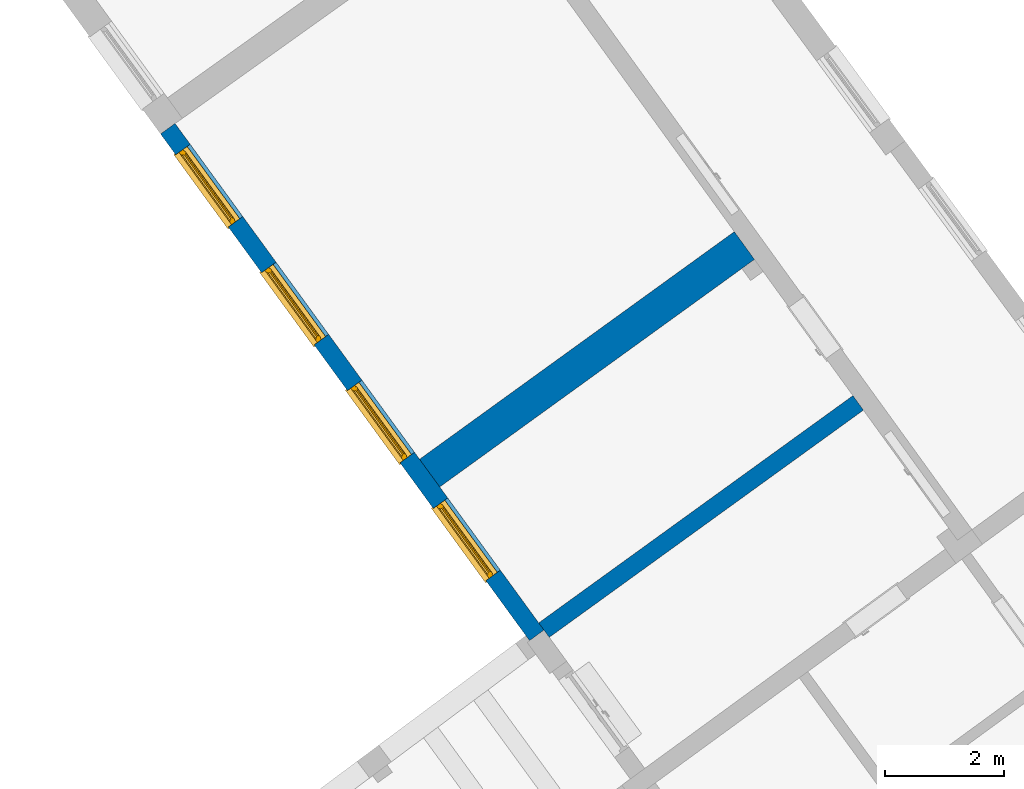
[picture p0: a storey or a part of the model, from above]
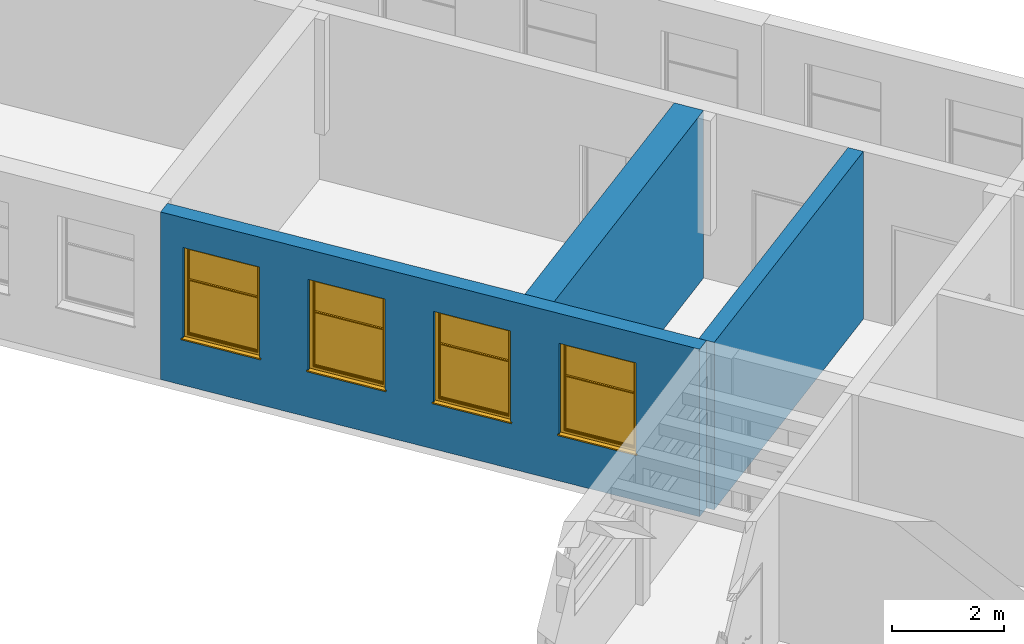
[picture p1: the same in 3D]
Properties of the parts of a building model (IFC2X3), part 1 of 13

# File
Description: ViewDefinition [CoordinationView_V2.0], RevitIdentifiers [VersionGUID: 7a34f898-4692-4373-837c-c47529479d31, NumberOfSaves: 8], CoordinateReference [CoordinateBase: Shared Coordinates]
File name: Project Number
Time: 2026-03-11T15:52:37+02:00
Written by: ODA SDAI 22.12
Made in: 23.1.10.4 - Exporter 23.2.2.0 - Alternate UI 23.2.2.0

# IfcProject, Project Number
LongName: Project Name; Phase: Project Status

# IfcSite, Default
RefLatitude: 42, 54, 1, 679999; RefLongitude: 25, 17, 46, 199999; RefElevation: 0 mm
Pset_ProductRequirements - Category: Project Information

# IfcBuilding
Pset_BuildingCommon - NumberOfStoreys: 11
Pset_ProductRequirements - Category: Project Information

# IfcBuildingStorey: Level:1/4" Head (3)
Elevation: 0 mm
Pset_ProductRequirements - Category: Levels
Name | LongName = Pset_AirSideSystemInformation, Name = Pset_ProductRequirements, Name
PLAN | PLAN
3D | 3D
-1. Story | -1. Story

# IfcBuildingStorey: Level:Circle Head - Project Datum (11)
Pset_ProductRequirements - Category: Levels
Name | LongName = Pset_AirSideSystemInformation, Name = Pset_ProductRequirements, Name | Elevation (mm)
0.UG -3.60 | 0.UG -3.60 | -3600
6.EG KH -1.15 | 6.EG KH -1.15 | -1150
1.EG +0.00 | 1.EG +0.00 | -4.33147e-12
7.1OG KH +2.65 | 7.1OG KH +2.65 | 2650
2.1OG +5.30 | 2.1OG +5.30 | 5300
8.2OG KH +6.45 | 8.2OG KH +6.45 | 6450
9.3OG KH +10.25 | 9.3OG KH +10.25 | 10250
3.2OG +10.60 | 3.2OG +10.60 | 10600
10.DG KH +14.25 | 10.DG KH +14.25 | 14250
4.3OG +15.90 | 4.3OG +15.90 | 15900
5.DG +21.50 | 5.DG +21.50 | 21500

# IfcBeam: Beam-124 291688:Beam-124 291688 (64)
In: PLAN
Type - Pset_BeamCommon - IsExternal: no; LoadBearing: yes
Type - Pset_ProductRequirements - Category: Structural Framing
Material: Paint-02.3; Group: Model Group:River:478153
Pset_BeamCommon - Reference: Beam-124 291688
Pset_QuantityTakeOff - Reference: Beam-124 291688; sets with these values: 2

# IfcBeam: Beam-124 342651:Beam-124 342651 (144)
In: PLAN
Type - Pset_BeamCommon - IsExternal: no; LoadBearing: yes
Type - Pset_ProductRequirements - Category: Structural Framing
Material: Wd Siding Dark color 01; Group: Model Group:River:478153
Pset_BeamCommon - Reference: Beam-124 342651
Pset_QuantityTakeOff - Reference: Beam-124 342651; sets with these values: 2

# IfcBeam: Beam-124 342768:Beam-124 342768 (10)
In: PLAN
Type - Pset_BeamCommon - IsExternal: no; LoadBearing: yes
Type - Pset_ProductRequirements - Category: Structural Framing
Material: Paint-02.1; Group: Model Group:River:478153
Pset_BeamCommon - Reference: Beam-124 342768
Pset_QuantityTakeOff - Reference: Beam-124 342768; sets with these values: 2

# IfcBeam: Beam-124 342968:Beam-124 342968 (4)
In: PLAN
Type - Pset_BeamCommon - IsExternal: no; LoadBearing: yes
Type - Pset_ProductRequirements - Category: Structural Framing
Material: Paint-02.3; Group: Model Group:River:478153
Pset_BeamCommon - Reference: Beam-124 342968
Pset_QuantityTakeOff - Reference: Beam-124 342968; sets with these values: 2

# IfcBeam: Beam-125 342678:Beam-125 342678 (6)
In: PLAN
Type - Pset_BeamCommon - IsExternal: no; LoadBearing: yes
Type - Pset_ProductRequirements - Category: Structural Framing
Material: Paint-02.2; Group: Model Group:River:478153
Pset_BeamCommon - Reference: Beam-125 342678
Pset_QuantityTakeOff - Reference: Beam-125 342678; sets with these values: 2

# IfcBeam: Beam-125 342737:Beam-125 342737 (6)
In: PLAN
Type - Pset_BeamCommon - IsExternal: no; LoadBearing: yes
Type - Pset_ProductRequirements - Category: Structural Framing
Material: Paint-02.2; Group: Model Group:River:478153
Pset_BeamCommon - Reference: Beam-125 342737
Pset_QuantityTakeOff - Reference: Beam-125 342737; sets with these values: 2

# IfcBeam: Beam-125 342828:Beam-125 342828 (2)
In: PLAN
Type - Pset_BeamCommon - IsExternal: no; LoadBearing: yes
Type - Pset_ProductRequirements - Category: Structural Framing
Material: Paint-02.2; Group: Model Group:River:478153
Pset_BeamCommon - Reference: Beam-125 342828
Pset_QuantityTakeOff - Reference: Beam-125 342828; sets with these values: 2

# IfcBeam: Beam-125 373068:Beam-125 373068 (2)
In: PLAN
Type - Pset_BeamCommon - IsExternal: no; LoadBearing: yes
Type - Pset_ProductRequirements - Category: Structural Framing
Material: Paint-02.2; Group: Model Group:River:478153
Pset_BeamCommon - Reference: Beam-125 373068
Pset_QuantityTakeOff - Reference: Beam-125 373068; sets with these values: 2

# IfcBeam: Beam-136 (4)
In: 6.EG KH -1.15
Type - Pset_BeamCommon - IsExternal: no; LoadBearing: yes
Type - Pset_ProductRequirements - Category: Structural Framing
Material: Paveta_bordur; Group: Model Group:River:478153
Pset_QuantityTakeOff - sets with these values: 2
Name | Pset_BeamCommon, Reference = Pset_QuantityTakeOff, Reference
Beam-136:Beam-136:298538 | Beam-136
Beam-136 237953:Beam-136 237953:298580 | Beam-136 237953
Beam-136 237969:Beam-136 237969:298587 | Beam-136 237969
Beam-136 266104:Beam-136 266104:299016 | Beam-136 266104

# IfcBeam: Beam-136 236833:Beam-136 236833, Beam-136
In: 1.EG +0.00
Type - Pset_BeamCommon - IsExternal: no; LoadBearing: yes
Type - Pset_ProductRequirements - Category: Structural Framing
Material: Paveta_bordur; Group: Model Group:River:478153
Pset_BeamCommon - Reference: Beam-136 236833
Pset_QuantityTakeOff - Reference: Beam-136 236833; sets with these values: 2

# IfcBeam: Beam-136 236875:Beam-136 236875, Beam-136
In: 1.EG +0.00
Type - Pset_BeamCommon - IsExternal: no; LoadBearing: yes
Type - Pset_ProductRequirements - Category: Structural Framing
Material: Paveta_bordur; Group: Model Group:River:478153
Pset_BeamCommon - Reference: Beam-136 236875
Pset_QuantityTakeOff - Reference: Beam-136 236875; sets with these values: 2

# IfcBeam: Beam-136 237941:Beam-136 237941, Beam-136
In: 6.EG KH -1.15
Type - Pset_BeamCommon - IsExternal: no; LoadBearing: yes
Type - Pset_ProductRequirements - Category: Structural Framing
Material: Paveta_bordur; Group: Model Group:River:478153
Pset_BeamCommon - Reference: Beam-136 237941
Pset_QuantityTakeOff - Reference: Beam-136 237941; sets with these values: 2

# IfcBeam: Beam-136 237952:Beam-136 237952, Beam-136
In: 6.EG KH -1.15
Type - Pset_BeamCommon - IsExternal: no; LoadBearing: yes
Type - Pset_ProductRequirements - Category: Structural Framing
Material: Paveta_bordur; Group: Model Group:River:478153
Pset_BeamCommon - Reference: Beam-136 237952
Pset_QuantityTakeOff - Reference: Beam-136 237952; sets with these values: 2

# IfcBeam: Beam-136 237970:Beam-136 237970, Beam-136
In: 6.EG KH -1.15
Type - Pset_BeamCommon - IsExternal: no; LoadBearing: yes
Type - Pset_ProductRequirements - Category: Structural Framing
Material: Paveta_bordur; Group: Model Group:River:478153
Pset_BeamCommon - Reference: Beam-136 237970
Pset_QuantityTakeOff - Reference: Beam-136 237970; sets with these values: 2

# IfcBeam: Beam-137 (3)
Type - Pset_BeamCommon - IsExternal: no; LoadBearing: yes
Type - Pset_ProductRequirements - Category: Structural Framing
Material: Paveta_bordur; Group: Model Group:River:478153
Pset_QuantityTakeOff - sets with these values: 2
Name | In | Pset_BeamCommon, Reference = Pset_QuantityTakeOff, Reference
Beam-137:Beam-137:298349 | 1.EG +0.00 | Beam-137
Beam-137 237484:Beam-137 237484:298510 | 6.EG KH -1.15 | Beam-137 237484
Beam-137 237932:Beam-137 237932:298573 | 6.EG KH -1.15 | Beam-137 237932

# IfcBeam: Beam-137 236767:Beam-137 236767, Beam-137
In: 1.EG +0.00
Type - Pset_BeamCommon - IsExternal: no; LoadBearing: yes
Type - Pset_ProductRequirements - Category: Structural Framing
Material: Paveta_bordur; Group: Model Group:River:478153
Pset_BeamCommon - Reference: Beam-137 236767
Pset_QuantityTakeOff - Reference: Beam-137 236767; sets with these values: 2

# IfcBeam: Beam-137 236820:Beam-137 236820 (6)
In: 3D
Type - Pset_BeamCommon - IsExternal: no; LoadBearing: yes
Type - Pset_ProductRequirements - Category: Structural Framing
Material: Paveta_bordur; Group: Model Group:River:478153
Pset_BeamCommon - Reference: Beam-137 236820
Pset_QuantityTakeOff - Reference: Beam-137 236820; sets with these values: 2
Name
Beam-148
2 x Beam-161
Beam-181
Beam-140
Beam-137

# IfcBeam: Beam-137 236851:Beam-137 236851, Beam-137
In: 1.EG +0.00
Type - Pset_BeamCommon - IsExternal: no; LoadBearing: yes
Type - Pset_ProductRequirements - Category: Structural Framing
Material: Paveta_bordur; Group: Model Group:River:478153
Pset_BeamCommon - Reference: Beam-137 236851
Pset_QuantityTakeOff - Reference: Beam-137 236851; sets with these values: 2

# IfcBeam: Beam-137 237951:Beam-137 237951, Beam-137
In: 6.EG KH -1.15
Type - Pset_BeamCommon - IsExternal: no; LoadBearing: yes
Type - Pset_ProductRequirements - Category: Structural Framing
Material: Paveta_bordur; Group: Model Group:River:478153
Pset_BeamCommon - Reference: Beam-137 237951
Pset_QuantityTakeOff - Reference: Beam-137 237951; sets with these values: 2

# IfcBeam: Beam-137 238188:Beam-137 238188, Beam-137
In: 6.EG KH -1.15
Type - Pset_BeamCommon - IsExternal: no; LoadBearing: yes
Type - Pset_ProductRequirements - Category: Structural Framing
Material: Paveta_bordur; Group: Model Group:River:478153
Pset_BeamCommon - Reference: Beam-137 238188
Pset_QuantityTakeOff - Reference: Beam-137 238188; sets with these values: 2

# IfcBeam: Beam-137 291495:Beam-137 291495, Beam-137
In: 1.EG +0.00
Type - Pset_BeamCommon - IsExternal: no; LoadBearing: yes
Type - Pset_ProductRequirements - Category: Structural Framing
Material: Paveta_bordur; Group: Model Group:River:478153
Pset_BeamCommon - Reference: Beam-137 291495
Pset_QuantityTakeOff - Reference: Beam-137 291495; sets with these values: 2

# IfcBeam: Beam-138, Beam-138:Beam-138:298650
In: 6.EG KH -1.15
Type - Pset_BeamCommon - IsExternal: no; LoadBearing: yes
Type - Pset_ProductRequirements - Category: Structural Framing
Material: Paveta_bordur; Group: Model Group:River:478153
Pset_BeamCommon - Reference: Beam-138
Pset_QuantityTakeOff - Reference: Beam-138; sets with these values: 2

# IfcBeam: Beam-138 236757:Beam-138 236757, Beam-138
In: 1.EG +0.00
Type - Pset_BeamCommon - IsExternal: no; LoadBearing: yes
Type - Pset_ProductRequirements - Category: Structural Framing
Material: Paveta_bordur; Group: Model Group:River:478153
Pset_BeamCommon - Reference: Beam-138 236757
Pset_QuantityTakeOff - Reference: Beam-138 236757; sets with these values: 2

# IfcBeam: Beam-138 236822:Beam-138 236822, Beam-138
In: 1.EG +0.00
Type - Pset_BeamCommon - IsExternal: no; LoadBearing: yes
Type - Pset_ProductRequirements - Category: Structural Framing
Material: Paveta_bordur; Group: Model Group:River:478153
Pset_BeamCommon - Reference: Beam-138 236822
Pset_QuantityTakeOff - Reference: Beam-138 236822; sets with these values: 2

# IfcBeam: Beam-138 237779:Beam-138 237779, Beam-138
In: 6.EG KH -1.15
Type - Pset_BeamCommon - IsExternal: no; LoadBearing: yes
Type - Pset_ProductRequirements - Category: Structural Framing
Material: Paveta_bordur; Group: Model Group:River:478153
Pset_BeamCommon - Reference: Beam-138 237779
Pset_QuantityTakeOff - Reference: Beam-138 237779; sets with these values: 2

# IfcBeam: Beam-139 (3)
Type - Pset_BeamCommon - IsExternal: no; LoadBearing: yes
Type - Pset_ProductRequirements - Category: Structural Framing
Material: Paveta_bordur; Group: Model Group:River:478153
Pset_QuantityTakeOff - sets with these values: 2
Name | In | Pset_BeamCommon, Reference = Pset_QuantityTakeOff, Reference
Beam-139:Beam-139:298356 | 1.EG +0.00 | Beam-139
Beam-139 237451:Beam-139 237451:298503 | 0.UG -3.60 | Beam-139 237451
Beam-139 237500:Beam-139 237500:298524 | 6.EG KH -1.15 | Beam-139 237500

# IfcBeam: Beam-139 228031:Beam-139 228031, Beam-139
In: 0.UG -3.60
Type - Pset_BeamCommon - IsExternal: no; LoadBearing: yes
Type - Pset_ProductRequirements - Category: Structural Framing
Material: Paveta_bordur; Group: Model Group:River:478153
Pset_BeamCommon - Reference: Beam-139 228031
Pset_QuantityTakeOff - Reference: Beam-139 228031; sets with these values: 2

# IfcBeam: Beam-139 236846:Beam-139 236846, Beam-139
In: 1.EG +0.00
Type - Pset_BeamCommon - IsExternal: no; LoadBearing: yes
Type - Pset_ProductRequirements - Category: Structural Framing
Material: Paveta_bordur; Group: Model Group:River:478153
Pset_BeamCommon - Reference: Beam-139 236846
Pset_QuantityTakeOff - Reference: Beam-139 236846; sets with these values: 2

# IfcBeam: Beam-139 236876:Beam-139 236876, Beam-139
In: 0.UG -3.60
Type - Pset_BeamCommon - IsExternal: no; LoadBearing: yes
Type - Pset_ProductRequirements - Category: Structural Framing
Material: Paint-01; Group: Model Group:River:478153
Pset_BeamCommon - Reference: Beam-139 236876
Pset_QuantityTakeOff - Reference: Beam-139 236876; sets with these values: 2

# IfcBeam: Beam-139 236877:Beam-139 236877, Beam-139
In: 0.UG -3.60
Type - Pset_BeamCommon - IsExternal: no; LoadBearing: yes
Type - Pset_ProductRequirements - Category: Structural Framing
Material: Paint-01; Group: Model Group:River:478153
Pset_BeamCommon - Reference: Beam-139 236877
Pset_QuantityTakeOff - Reference: Beam-139 236877; sets with these values: 2

# IfcBeam: Beam-139 237440:Beam-139 237440, Beam-139
In: 0.UG -3.60
Type - Pset_BeamCommon - IsExternal: no; LoadBearing: yes
Type - Pset_ProductRequirements - Category: Structural Framing
Material: Paint-01; Group: Model Group:River:478153
Pset_BeamCommon - Reference: Beam-139 237440
Pset_QuantityTakeOff - Reference: Beam-139 237440; sets with these values: 2

# IfcBeam: Beam-139 237447:Beam-139 237447, Beam-139
In: 0.UG -3.60
Type - Pset_BeamCommon - IsExternal: no; LoadBearing: yes
Type - Pset_ProductRequirements - Category: Structural Framing
Material: Paint-01; Group: Model Group:River:478153
Pset_BeamCommon - Reference: Beam-139 237447
Pset_QuantityTakeOff - Reference: Beam-139 237447; sets with these values: 2

# IfcBeam: Beam-139 237458:Beam-139 237458, Beam-139
In: 0.UG -3.60
Type - Pset_BeamCommon - IsExternal: no; LoadBearing: yes
Type - Pset_ProductRequirements - Category: Structural Framing
Material: Paint-01; Group: Model Group:River:478153
Pset_BeamCommon - Reference: Beam-139 237458
Pset_QuantityTakeOff - Reference: Beam-139 237458; sets with these values: 2

# IfcBeam: Beam-139 237459:Beam-139 237459, Beam-139
In: 6.EG KH -1.15
Type - Pset_BeamCommon - IsExternal: no; LoadBearing: yes
Type - Pset_ProductRequirements - Category: Structural Framing
Material: Paveta_bordur; Group: Model Group:River:478153
Pset_BeamCommon - Reference: Beam-139 237459
Pset_QuantityTakeOff - Reference: Beam-139 237459; sets with these values: 2

# IfcBeam: Beam-139 237462:Beam-139 237462, Beam-139
In: 0.UG -3.60
Type - Pset_BeamCommon - IsExternal: no; LoadBearing: yes
Type - Pset_ProductRequirements - Category: Structural Framing
Material: Paveta_bordur; Group: Model Group:River:478153
Pset_BeamCommon - Reference: Beam-139 237462
Pset_QuantityTakeOff - Reference: Beam-139 237462; sets with these values: 2

# IfcBeam: Beam-139 237467:Beam-139 237467, Beam-139
In: 0.UG -3.60
Type - Pset_BeamCommon - IsExternal: no; LoadBearing: yes
Type - Pset_ProductRequirements - Category: Structural Framing
Material: Paveta_bordur; Group: Model Group:River:478153
Pset_BeamCommon - Reference: Beam-139 237467
Pset_QuantityTakeOff - Reference: Beam-139 237467; sets with these values: 2

# IfcBeam: Beam-139 237471:Beam-139 237471, Beam-139
In: 0.UG -3.60
Type - Pset_BeamCommon - IsExternal: no; LoadBearing: yes
Type - Pset_ProductRequirements - Category: Structural Framing
Material: Paint-01; Group: Model Group:River:478153
Pset_BeamCommon - Reference: Beam-139 237471
Pset_QuantityTakeOff - Reference: Beam-139 237471; sets with these values: 2

# IfcBeam: Beam-139 237474:Beam-139 237474, Beam-139
In: 0.UG -3.60
Type - Pset_BeamCommon - IsExternal: no; LoadBearing: yes
Type - Pset_ProductRequirements - Category: Structural Framing
Material: Paint-01; Group: Model Group:River:478153
Pset_BeamCommon - Reference: Beam-139 237474
Pset_QuantityTakeOff - Reference: Beam-139 237474; sets with these values: 2

# IfcBeam: Beam-139 237483:Beam-139 237483, Beam-139
In: 6.EG KH -1.15
Type - Pset_BeamCommon - IsExternal: no; LoadBearing: yes
Type - Pset_ProductRequirements - Category: Structural Framing
Material: Paveta_bordur; Group: Model Group:River:478153
Pset_BeamCommon - Reference: Beam-139 237483
Pset_QuantityTakeOff - Reference: Beam-139 237483; sets with these values: 2

# IfcBeam: Beam-139 237501:Beam-139 237501, Beam-139
In: 0.UG -3.60
Type - Pset_BeamCommon - IsExternal: no; LoadBearing: yes
Type - Pset_ProductRequirements - Category: Structural Framing
Material: Paint-01; Group: Model Group:River:478153
Pset_BeamCommon - Reference: Beam-139 237501
Pset_QuantityTakeOff - Reference: Beam-139 237501; sets with these values: 2

# IfcBeam: Beam-139 237552:Beam-139 237552, Beam-139
In: 6.EG KH -1.15
Type - Pset_BeamCommon - IsExternal: no; LoadBearing: yes
Type - Pset_ProductRequirements - Category: Structural Framing
Material: Paveta_bordur; Group: Model Group:River:478153
Pset_BeamCommon - Reference: Beam-139 237552
Pset_QuantityTakeOff - Reference: Beam-139 237552; sets with these values: 2

# IfcBeam: Beam-139 237771:Beam-139 237771, Beam-139
In: 6.EG KH -1.15
Type - Pset_BeamCommon - IsExternal: no; LoadBearing: yes
Type - Pset_ProductRequirements - Category: Structural Framing
Material: Paveta_bordur; Group: Model Group:River:478153
Pset_BeamCommon - Reference: Beam-139 237771
Pset_QuantityTakeOff - Reference: Beam-139 237771; sets with these values: 2

# IfcBeam: Beam-139 237922:Beam-139 237922, Beam-139
In: 6.EG KH -1.15
Type - Pset_BeamCommon - IsExternal: no; LoadBearing: yes
Type - Pset_ProductRequirements - Category: Structural Framing
Material: Paveta_bordur; Group: Model Group:River:478153
Pset_BeamCommon - Reference: Beam-139 237922
Pset_QuantityTakeOff - Reference: Beam-139 237922; sets with these values: 2

# IfcBeam: Beam-139 238160:Beam-139 238160, Beam-139
In: 6.EG KH -1.15
Type - Pset_BeamCommon - IsExternal: no; LoadBearing: yes
Type - Pset_ProductRequirements - Category: Structural Framing
Material: Paveta_bordur; Group: Model Group:River:478153
Pset_BeamCommon - Reference: Beam-139 238160
Pset_QuantityTakeOff - Reference: Beam-139 238160; sets with these values: 2

# IfcBeam: Beam-139 238194:Beam-139 238194, Beam-139
In: 6.EG KH -1.15
Type - Pset_BeamCommon - IsExternal: no; LoadBearing: yes
Type - Pset_ProductRequirements - Category: Structural Framing
Material: Paveta_bordur; Group: Model Group:River:478153
Pset_BeamCommon - Reference: Beam-139 238194
Pset_QuantityTakeOff - Reference: Beam-139 238194; sets with these values: 2

# IfcBeam: Beam-139 238196:Beam-139 238196, Beam-139
In: 6.EG KH -1.15
Type - Pset_BeamCommon - IsExternal: no; LoadBearing: yes
Type - Pset_ProductRequirements - Category: Structural Framing
Material: Paveta_bordur; Group: Model Group:River:478153
Pset_BeamCommon - Reference: Beam-139 238196
Pset_QuantityTakeOff - Reference: Beam-139 238196; sets with these values: 2

# IfcBeam: Beam-139 262464:Beam-139 262464, Beam-139
In: 0.UG -3.60
Type - Pset_BeamCommon - IsExternal: no; LoadBearing: yes
Type - Pset_ProductRequirements - Category: Structural Framing
Material: Paint-01; Group: Model Group:River:478153
Pset_BeamCommon - Reference: Beam-139 262464
Pset_QuantityTakeOff - Reference: Beam-139 262464; sets with these values: 2

# IfcBeam: Beam-139 262485:Beam-139 262485, Beam-139
In: 0.UG -3.60
Type - Pset_BeamCommon - IsExternal: no; LoadBearing: yes
Type - Pset_ProductRequirements - Category: Structural Framing
Material: Paint-01; Group: Model Group:River:478153
Pset_BeamCommon - Reference: Beam-139 262485
Pset_QuantityTakeOff - Reference: Beam-139 262485; sets with these values: 2

# IfcBeam: Beam-139 83593:Beam-139 83593, Beam-139
In: 0.UG -3.60
Type - Pset_BeamCommon - IsExternal: no; LoadBearing: yes
Type - Pset_ProductRequirements - Category: Structural Framing
Material: Paveta_bordur; Group: Model Group:River:478153
Pset_BeamCommon - Reference: Beam-139 83593
Pset_QuantityTakeOff - Reference: Beam-139 83593; sets with these values: 2

# IfcBeam: Beam-140 (6)
Type - Pset_BeamCommon - IsExternal: no; LoadBearing: yes
Type - Pset_ProductRequirements - Category: Structural Framing
Material: Paveta_bordur; Group: Model Group:River:478153
Pset_QuantityTakeOff - sets with these values: 2
Name | In | Pset_BeamCommon, Reference = Pset_QuantityTakeOff, Reference
Beam-140:Beam-140:298377 | 1.EG +0.00 | Beam-140
Beam-140 237048:Beam-140 237048:298447 | 0.UG -3.60 | Beam-140 237048
Beam-140 237450:Beam-140 237450:298496 | 0.UG -3.60 | Beam-140 237450
Beam-140 237496:Beam-140 237496:298517 | 6.EG KH -1.15 | Beam-140 237496
Beam-140 237508:Beam-140 237508:298531 | 6.EG KH -1.15 | Beam-140 237508
Beam-140 238172:Beam-140 238172:298643 | 6.EG KH -1.15 | Beam-140 238172

# IfcBeam: Beam-140 182489:Beam-140 182489, Beam-140
In: 0.UG -3.60
Type - Pset_BeamCommon - IsExternal: no; LoadBearing: yes
Type - Pset_ProductRequirements - Category: Structural Framing
Material: Paint-01; Group: Model Group:River:478153
Pset_BeamCommon - Reference: Beam-140 182489
Pset_QuantityTakeOff - Reference: Beam-140 182489; sets with these values: 2

# IfcBeam: Beam-140 236747:Beam-140 236747 (6)
In: 3D
Type - Pset_BeamCommon - IsExternal: no; LoadBearing: yes
Type - Pset_ProductRequirements - Category: Structural Framing
Material: Paveta_bordur; Group: Model Group:River:478153
Pset_BeamCommon - Reference: Beam-140 236747
Pset_QuantityTakeOff - Reference: Beam-140 236747; sets with these values: 2
Name
Beam-146
Beam-176
Beam-164
Beam-163
Beam-143
Beam-140

# IfcBeam: Beam-140 237435:Beam-140 237435, Beam-140
In: 0.UG -3.60
Type - Pset_BeamCommon - IsExternal: no; LoadBearing: yes
Type - Pset_ProductRequirements - Category: Structural Framing
Material: Paveta_bordur; Group: Model Group:River:478153
Pset_BeamCommon - Reference: Beam-140 237435
Pset_QuantityTakeOff - Reference: Beam-140 237435; sets with these values: 2

# IfcBeam: Beam-140 237494:Beam-140 237494, Beam-140
In: 6.EG KH -1.15
Type - Pset_BeamCommon - IsExternal: no; LoadBearing: yes
Type - Pset_ProductRequirements - Category: Structural Framing
Material: Paveta_bordur; Group: Model Group:River:478153
Pset_BeamCommon - Reference: Beam-140 237494
Pset_QuantityTakeOff - Reference: Beam-140 237494; sets with these values: 2

# IfcBeam: Beam-140 237927:Beam-140 237927, Beam-140
In: 6.EG KH -1.15
Type - Pset_BeamCommon - IsExternal: no; LoadBearing: yes
Type - Pset_ProductRequirements - Category: Structural Framing
Material: Paveta_bordur; Group: Model Group:River:478153
Pset_BeamCommon - Reference: Beam-140 237927
Pset_QuantityTakeOff - Reference: Beam-140 237927; sets with these values: 2

# IfcBeam: Beam-141 (6)
Type - Pset_BeamCommon - IsExternal: no; LoadBearing: yes
Type - Pset_ProductRequirements - Category: Structural Framing
Material: Paveta_bordur; Group: Model Group:River:478153
Pset_QuantityTakeOff - sets with these values: 2
Name | In | Pset_BeamCommon, Reference = Pset_QuantityTakeOff, Reference
Beam-141:Beam-141:298363 | 1.EG +0.00 | Beam-141
Beam-141 236813:Beam-141 236813:298384 | 1.EG +0.00 | Beam-141 236813
Beam-141 237873:Beam-141 237873:298566 | 6.EG KH -1.15 | Beam-141 237873
Beam-141 238103:Beam-141 238103:298616 | 6.EG KH -1.15 | Beam-141 238103
Beam-141 238166:Beam-141 238166:298636 | 6.EG KH -1.15 | Beam-141 238166
Beam-141 256654:Beam-141 256654:298841 | 6.EG KH -1.15 | Beam-141 256654

# IfcBeam: Beam-141 211486:Beam-141 211486, Beam-141
In: 0.UG -3.60
Type - Pset_BeamCommon - IsExternal: no; LoadBearing: yes
Type - Pset_ProductRequirements - Category: Structural Framing
Material: Paint-01; Group: Model Group:River:478153
Pset_BeamCommon - Reference: Beam-141 211486
Pset_QuantityTakeOff - Reference: Beam-141 211486; sets with these values: 2

# IfcBeam: Beam-141 237854:Beam-141 237854, Beam-141
In: 6.EG KH -1.15
Type - Pset_BeamCommon - IsExternal: no; LoadBearing: yes
Type - Pset_ProductRequirements - Category: Structural Framing
Material: Paveta_bordur; Group: Model Group:River:478153
Pset_BeamCommon - Reference: Beam-141 237854
Pset_QuantityTakeOff - Reference: Beam-141 237854; sets with these values: 2

# IfcBeam: Beam-141 237901:Beam-141 237901, Beam-141
In: 6.EG KH -1.15
Type - Pset_BeamCommon - IsExternal: no; LoadBearing: yes
Type - Pset_ProductRequirements - Category: Structural Framing
Material: Paveta_bordur; Group: Model Group:River:478153
Pset_BeamCommon - Reference: Beam-141 237901
Pset_QuantityTakeOff - Reference: Beam-141 237901; sets with these values: 2

# IfcBeam: Beam-141 237912:Beam-141 237912, Beam-141
In: 6.EG KH -1.15
Type - Pset_BeamCommon - IsExternal: no; LoadBearing: yes
Type - Pset_ProductRequirements - Category: Structural Framing
Material: Paveta_bordur; Group: Model Group:River:478153
Pset_BeamCommon - Reference: Beam-141 237912
Pset_QuantityTakeOff - Reference: Beam-141 237912; sets with these values: 2

# IfcBeam: Beam-141 237933:Beam-141 237933, Beam-141
In: 6.EG KH -1.15
Type - Pset_BeamCommon - IsExternal: no; LoadBearing: yes
Type - Pset_ProductRequirements - Category: Structural Framing
Material: Paveta_bordur; Group: Model Group:River:478153
Pset_BeamCommon - Reference: Beam-141 237933
Pset_QuantityTakeOff - Reference: Beam-141 237933; sets with these values: 2

# IfcBeam: Beam-141 238098:Beam-141 238098, Beam-141
In: 6.EG KH -1.15
Type - Pset_BeamCommon - IsExternal: no; LoadBearing: yes
Type - Pset_ProductRequirements - Category: Structural Framing
Material: Paint-01; Group: Model Group:River:478153
Pset_BeamCommon - Reference: Beam-141 238098
Pset_QuantityTakeOff - Reference: Beam-141 238098; sets with these values: 2

# IfcBeam: Beam-141 238106:Beam-141 238106, Beam-141
In: 6.EG KH -1.15
Type - Pset_BeamCommon - IsExternal: no; LoadBearing: yes
Type - Pset_ProductRequirements - Category: Structural Framing
Material: Paint-01; Group: Model Group:River:478153
Pset_BeamCommon - Reference: Beam-141 238106
Pset_QuantityTakeOff - Reference: Beam-141 238106; sets with these values: 2

# IfcBeam: Beam-141 266031:Beam-141 266031, Beam-141
In: 6.EG KH -1.15
Type - Pset_BeamCommon - IsExternal: no; LoadBearing: yes
Type - Pset_ProductRequirements - Category: Structural Framing
Material: Paint-01; Group: Model Group:River:478153
Pset_BeamCommon - Reference: Beam-141 266031
Pset_QuantityTakeOff - Reference: Beam-141 266031; sets with these values: 2

# IfcBeam: Beam-141 266038:Beam-141 266038, Beam-141
In: 6.EG KH -1.15
Type - Pset_BeamCommon - IsExternal: no; LoadBearing: yes
Type - Pset_ProductRequirements - Category: Structural Framing
Material: Paint-01; Group: Model Group:River:478153
Pset_BeamCommon - Reference: Beam-141 266038
Pset_QuantityTakeOff - Reference: Beam-141 266038; sets with these values: 2

# IfcBeam: Beam-141 266069:Beam-141 266069, Beam-141
In: 0.UG -3.60
Type - Pset_BeamCommon - IsExternal: no; LoadBearing: yes
Type - Pset_ProductRequirements - Category: Structural Framing
Material: Paint-01; Group: Model Group:River:478153
Pset_BeamCommon - Reference: Beam-141 266069
Pset_QuantityTakeOff - Reference: Beam-141 266069; sets with these values: 2

# IfcBeam: Beam-141 266079:Beam-141 266079, Beam-141
In: 6.EG KH -1.15
Type - Pset_BeamCommon - IsExternal: no; LoadBearing: yes
Type - Pset_ProductRequirements - Category: Structural Framing
Material: Paveta_bordur; Group: Model Group:River:478153
Pset_BeamCommon - Reference: Beam-141 266079
Pset_QuantityTakeOff - Reference: Beam-141 266079; sets with these values: 2

# IfcBeam: Beam-141 266112:Beam-141 266112, Beam-141
In: 6.EG KH -1.15
Type - Pset_BeamCommon - IsExternal: no; LoadBearing: yes
Type - Pset_ProductRequirements - Category: Structural Framing
Material: Paint-01; Group: Model Group:River:478153
Pset_BeamCommon - Reference: Beam-141 266112
Pset_QuantityTakeOff - Reference: Beam-141 266112; sets with these values: 2

# IfcBeam: Beam-142 (3)
Type - Pset_BeamCommon - IsExternal: no; LoadBearing: yes
Type - Pset_ProductRequirements - Category: Structural Framing
Material: Paveta_bordur; Group: Model Group:River:478153
Pset_QuantityTakeOff - sets with these values: 2
Name | In | Pset_BeamCommon, Reference = Pset_QuantityTakeOff, Reference
Beam-142:Beam-142:297484 | 0.UG -3.60 | Beam-142
Beam-142 237364:Beam-142 237364:298482 | 0.UG -3.60 | Beam-142 237364
Beam-142 237788:Beam-142 237788:298545 | 6.EG KH -1.15 | Beam-142 237788

# IfcBeam: Beam-142 236743:Beam-142 236743, Beam-142
In: 1.EG +0.00
Type - Pset_BeamCommon - IsExternal: no; LoadBearing: yes
Type - Pset_ProductRequirements - Category: Structural Framing
Material: Paveta_bordur; Group: Model Group:River:478153
Pset_BeamCommon - Reference: Beam-142 236743
Pset_QuantityTakeOff - Reference: Beam-142 236743; sets with these values: 2

# IfcBeam: Beam-142 237426:Beam-142 237426, Beam-142
In: 0.UG -3.60
Type - Pset_BeamCommon - IsExternal: no; LoadBearing: yes
Type - Pset_ProductRequirements - Category: Structural Framing
Material: Paveta_bordur; Group: Model Group:River:478153
Pset_BeamCommon - Reference: Beam-142 237426
Pset_QuantityTakeOff - Reference: Beam-142 237426; sets with these values: 2

# IfcBeam: Beam-142 237446:Beam-142 237446, Beam-142
In: 0.UG -3.60
Type - Pset_BeamCommon - IsExternal: no; LoadBearing: yes
Type - Pset_ProductRequirements - Category: Structural Framing
Material: Paint-01; Group: Model Group:River:478153
Pset_BeamCommon - Reference: Beam-142 237446
Pset_QuantityTakeOff - Reference: Beam-142 237446; sets with these values: 2

# IfcBeam: Beam-142 237812:Beam-142 237812, Beam-142
In: 6.EG KH -1.15
Type - Pset_BeamCommon - IsExternal: no; LoadBearing: yes
Type - Pset_ProductRequirements - Category: Structural Framing
Material: Paveta_bordur; Group: Model Group:River:478153
Pset_BeamCommon - Reference: Beam-142 237812
Pset_QuantityTakeOff - Reference: Beam-142 237812; sets with these values: 2

# IfcBeam: Beam-142 237851:Beam-142 237851, Beam-142
In: 6.EG KH -1.15
Type - Pset_BeamCommon - IsExternal: no; LoadBearing: yes
Type - Pset_ProductRequirements - Category: Structural Framing
Material: Paveta_bordur; Group: Model Group:River:478153
Pset_BeamCommon - Reference: Beam-142 237851
Pset_QuantityTakeOff - Reference: Beam-142 237851; sets with these values: 2

# IfcBeam: Beam-142 237892:Beam-142 237892, Beam-142
In: 6.EG KH -1.15
Type - Pset_BeamCommon - IsExternal: no; LoadBearing: yes
Type - Pset_ProductRequirements - Category: Structural Framing
Material: Paveta_bordur; Group: Model Group:River:478153
Pset_BeamCommon - Reference: Beam-142 237892
Pset_QuantityTakeOff - Reference: Beam-142 237892; sets with these values: 2

# IfcBeam: Beam-142 238038:Beam-142 238038, Beam-142
In: 6.EG KH -1.15
Type - Pset_BeamCommon - IsExternal: no; LoadBearing: yes
Type - Pset_ProductRequirements - Category: Structural Framing
Material: Paint-01; Group: Model Group:River:478153
Pset_BeamCommon - Reference: Beam-142 238038
Pset_QuantityTakeOff - Reference: Beam-142 238038; sets with these values: 2

# IfcBeam: Beam-143 (5)
Type - Pset_BeamCommon - IsExternal: no; LoadBearing: yes
Type - Pset_ProductRequirements - Category: Structural Framing
Material: Paveta_bordur; Group: Model Group:River:478153
Pset_QuantityTakeOff - sets with these values: 2
Name | In | Pset_BeamCommon, Reference = Pset_QuantityTakeOff, Reference
Beam-143:Beam-143:298091 | 1.EG +0.00 | Beam-143
Beam-143 236867:Beam-143 236867:298391 | 1.EG +0.00 | Beam-143 236867
Beam-143 237867:Beam-143 237867:298552 | 6.EG KH -1.15 | Beam-143 237867
Beam-143 237871:Beam-143 237871:298559 | 6.EG KH -1.15 | Beam-143 237871
Beam-143 256643:Beam-143 256643:298812 | 6.EG KH -1.15 | Beam-143 256643

# IfcBeam: Beam-143 236732:Beam-143 236732, Beam-143
In: 1.EG +0.00
Type - Pset_BeamCommon - IsExternal: no; LoadBearing: yes
Type - Pset_ProductRequirements - Category: Structural Framing
Material: Paveta_bordur; Group: Model Group:River:478153
Pset_BeamCommon - Reference: Beam-143 236732
Pset_QuantityTakeOff - Reference: Beam-143 236732; sets with these values: 2

# IfcBeam: Beam-143 236752:Beam-143 236752, Beam-143
In: 1.EG +0.00
Type - Pset_BeamCommon - IsExternal: no; LoadBearing: yes
Type - Pset_ProductRequirements - Category: Structural Framing
Material: Paveta_bordur; Group: Model Group:River:478153
Pset_BeamCommon - Reference: Beam-143 236752
Pset_QuantityTakeOff - Reference: Beam-143 236752; sets with these values: 2

# IfcBeam: Beam-143 237778:Beam-143 237778, Beam-143
In: 6.EG KH -1.15
Type - Pset_BeamCommon - IsExternal: no; LoadBearing: yes
Type - Pset_ProductRequirements - Category: Structural Framing
Material: Paveta_bordur; Group: Model Group:River:478153
Pset_BeamCommon - Reference: Beam-143 237778
Pset_QuantityTakeOff - Reference: Beam-143 237778; sets with these values: 2

# IfcBeam: Beam-143 237790:Beam-143 237790, Beam-143
In: 6.EG KH -1.15
Type - Pset_BeamCommon - IsExternal: no; LoadBearing: yes
Type - Pset_ProductRequirements - Category: Structural Framing
Material: Paveta_bordur; Group: Model Group:River:478153
Pset_BeamCommon - Reference: Beam-143 237790
Pset_QuantityTakeOff - Reference: Beam-143 237790; sets with these values: 2

# IfcBeam: Beam-143 237866:Beam-143 237866, Beam-143
In: 6.EG KH -1.15
Type - Pset_BeamCommon - IsExternal: no; LoadBearing: yes
Type - Pset_ProductRequirements - Category: Structural Framing
Material: Paveta_bordur; Group: Model Group:River:478153
Pset_BeamCommon - Reference: Beam-143 237866
Pset_QuantityTakeOff - Reference: Beam-143 237866; sets with these values: 2

# IfcBeam: Beam-143 237887:Beam-143 237887, Beam-143
In: 6.EG KH -1.15
Type - Pset_BeamCommon - IsExternal: no; LoadBearing: yes
Type - Pset_ProductRequirements - Category: Structural Framing
Material: Paveta_bordur; Group: Model Group:River:478153
Pset_BeamCommon - Reference: Beam-143 237887
Pset_QuantityTakeOff - Reference: Beam-143 237887; sets with these values: 2

# IfcBeam: Beam-143 237907:Beam-143 237907, Beam-143
In: 6.EG KH -1.15
Type - Pset_BeamCommon - IsExternal: no; LoadBearing: yes
Type - Pset_ProductRequirements - Category: Structural Framing
Material: Paveta_bordur; Group: Model Group:River:478153
Pset_BeamCommon - Reference: Beam-143 237907
Pset_QuantityTakeOff - Reference: Beam-143 237907; sets with these values: 2

# IfcBeam: Beam-143 238161:Beam-143 238161, Beam-143
In: 6.EG KH -1.15
Type - Pset_BeamCommon - IsExternal: no; LoadBearing: yes
Type - Pset_ProductRequirements - Category: Structural Framing
Material: Paveta_bordur; Group: Model Group:River:478153
Pset_BeamCommon - Reference: Beam-143 238161
Pset_QuantityTakeOff - Reference: Beam-143 238161; sets with these values: 2

# IfcBeam: Beam-144, Beam-144:Beam-144:298342
In: 1.EG +0.00
Type - Pset_BeamCommon - IsExternal: no; LoadBearing: yes
Type - Pset_ProductRequirements - Category: Structural Framing
Material: Paveta_bordur; Group: Model Group:River:478153
Pset_BeamCommon - Reference: Beam-144
Pset_QuantityTakeOff - Reference: Beam-144; sets with these values: 2

# IfcBeam: Beam-144 237408:Beam-144 237408, Beam-144
In: 0.UG -3.60
Type - Pset_BeamCommon - IsExternal: no; LoadBearing: yes
Type - Pset_ProductRequirements - Category: Structural Framing
Material: Paveta_bordur; Group: Model Group:River:478153
Pset_BeamCommon - Reference: Beam-144 237408
Pset_QuantityTakeOff - Reference: Beam-144 237408; sets with these values: 2

# IfcBeam: Beam-144 237761:Beam-144 237761, Beam-144
In: 6.EG KH -1.15
Type - Pset_BeamCommon - IsExternal: no; LoadBearing: yes
Type - Pset_ProductRequirements - Category: Structural Framing
Material: Paveta_bordur; Group: Model Group:River:478153
Pset_BeamCommon - Reference: Beam-144 237761
Pset_QuantityTakeOff - Reference: Beam-144 237761; sets with these values: 2

# IfcBeam: Beam-144 237846:Beam-144 237846, Beam-144
In: 6.EG KH -1.15
Type - Pset_BeamCommon - IsExternal: no; LoadBearing: yes
Type - Pset_ProductRequirements - Category: Structural Framing
Material: Paveta_bordur; Group: Model Group:River:478153
Pset_BeamCommon - Reference: Beam-144 237846
Pset_QuantityTakeOff - Reference: Beam-144 237846; sets with these values: 2

# IfcBeam: Beam-144 237850:Beam-144 237850, Beam-144
In: 6.EG KH -1.15
Type - Pset_BeamCommon - IsExternal: no; LoadBearing: yes
Type - Pset_ProductRequirements - Category: Structural Framing
Material: Paveta_bordur; Group: Model Group:River:478153
Pset_BeamCommon - Reference: Beam-144 237850
Pset_QuantityTakeOff - Reference: Beam-144 237850; sets with these values: 2

# IfcBeam: Beam-144 237878:Beam-144 237878, Beam-144
In: 6.EG KH -1.15
Type - Pset_BeamCommon - IsExternal: no; LoadBearing: yes
Type - Pset_ProductRequirements - Category: Structural Framing
Material: Paveta_bordur; Group: Model Group:River:478153
Pset_BeamCommon - Reference: Beam-144 237878
Pset_QuantityTakeOff - Reference: Beam-144 237878; sets with these values: 2

# IfcBeam: Beam-145 236657:Beam-145 236657, Beam-145
In: 1.EG +0.00
Type - Pset_BeamCommon - IsExternal: no; LoadBearing: yes
Type - Pset_ProductRequirements - Category: Structural Framing
Material: Paint-01; Group: Model Group:River:478153
Pset_BeamCommon - Reference: Beam-145 236657
Pset_QuantityTakeOff - Reference: Beam-145 236657; sets with these values: 2

# IfcBeam: Beam-145 236670:Beam-145 236670, Beam-145
In: 6.EG KH -1.15
Type - Pset_BeamCommon - IsExternal: no; LoadBearing: yes
Type - Pset_ProductRequirements - Category: Structural Framing
Material: Paint-01; Group: Model Group:River:478153
Pset_BeamCommon - Reference: Beam-145 236670
Pset_QuantityTakeOff - Reference: Beam-145 236670; sets with these values: 2

# IfcBeam: Beam-145 236680:Beam-145 236680, Beam-145
In: 6.EG KH -1.15
Type - Pset_BeamCommon - IsExternal: no; LoadBearing: yes
Type - Pset_ProductRequirements - Category: Structural Framing
Material: Paveta_bordur; Group: Model Group:River:478153
Pset_BeamCommon - Reference: Beam-145 236680
Pset_QuantityTakeOff - Reference: Beam-145 236680; sets with these values: 2

# IfcBeam: Beam-145 236702:Beam-145 236702, Beam-145
In: 1.EG +0.00
Type - Pset_BeamCommon - IsExternal: no; LoadBearing: yes
Type - Pset_ProductRequirements - Category: Structural Framing
Material: Paveta_bordur; Group: Model Group:River:478153
Pset_BeamCommon - Reference: Beam-145 236702
Pset_QuantityTakeOff - Reference: Beam-145 236702; sets with these values: 2

# IfcBeam: Beam-145 236730:Beam-145 236730, Beam-145
In: 1.EG +0.00
Type - Pset_BeamCommon - IsExternal: no; LoadBearing: yes
Type - Pset_ProductRequirements - Category: Structural Framing
Material: Paveta_bordur; Group: Model Group:River:478153
Pset_BeamCommon - Reference: Beam-145 236730
Pset_QuantityTakeOff - Reference: Beam-145 236730; sets with these values: 2

# IfcBeam: Beam-145 236786:Beam-145 236786, Beam-145
In: 1.EG +0.00
Type - Pset_BeamCommon - IsExternal: no; LoadBearing: yes
Type - Pset_ProductRequirements - Category: Structural Framing
Material: Paint-01; Group: Model Group:River:478153
Pset_BeamCommon - Reference: Beam-145 236786
Pset_QuantityTakeOff - Reference: Beam-145 236786; sets with these values: 2

# IfcBeam: Beam-145 236797:Beam-145 236797, Beam-145
In: 6.EG KH -1.15
Type - Pset_BeamCommon - IsExternal: no; LoadBearing: yes
Type - Pset_ProductRequirements - Category: Structural Framing
Material: Paint-01; Group: Model Group:River:478153
Pset_BeamCommon - Reference: Beam-145 236797
Pset_QuantityTakeOff - Reference: Beam-145 236797; sets with these values: 2

# IfcBeam: Beam-145 236815:Beam-145 236815, Beam-145
In: 1.EG +0.00
Type - Pset_BeamCommon - IsExternal: no; LoadBearing: yes
Type - Pset_ProductRequirements - Category: Structural Framing
Material: Paint-01; Group: Model Group:River:478153
Pset_BeamCommon - Reference: Beam-145 236815
Pset_QuantityTakeOff - Reference: Beam-145 236815; sets with these values: 2

# IfcBeam: Beam-145 237387:Beam-145 237387, Beam-145
In: 0.UG -3.60
Type - Pset_BeamCommon - IsExternal: no; LoadBearing: yes
Type - Pset_ProductRequirements - Category: Structural Framing
Material: Paveta_bordur; Group: Model Group:River:478153
Pset_BeamCommon - Reference: Beam-145 237387
Pset_QuantityTakeOff - Reference: Beam-145 237387; sets with these values: 2

# IfcBeam: Beam-145 237754:Beam-145 237754, Beam-145
In: 6.EG KH -1.15
Type - Pset_BeamCommon - IsExternal: no; LoadBearing: yes
Type - Pset_ProductRequirements - Category: Structural Framing
Material: Paveta_bordur; Group: Model Group:River:478153
Pset_BeamCommon - Reference: Beam-145 237754
Pset_QuantityTakeOff - Reference: Beam-145 237754; sets with these values: 2

# IfcBeam: Beam-145 237897:Beam-145 237897, Beam-145
In: 6.EG KH -1.15
Type - Pset_BeamCommon - IsExternal: no; LoadBearing: yes
Type - Pset_ProductRequirements - Category: Structural Framing
Material: Paveta_bordur; Group: Model Group:River:478153
Pset_BeamCommon - Reference: Beam-145 237897
Pset_QuantityTakeOff - Reference: Beam-145 237897; sets with these values: 2

# IfcBeam: Beam-146 (2)
In: 0.UG -3.60
Type - Pset_BeamCommon - IsExternal: no; LoadBearing: yes
Type - Pset_ProductRequirements - Category: Structural Framing
Material: Paveta_bordur; Group: Model Group:River:478153
Pset_QuantityTakeOff - sets with these values: 2
Name | Pset_BeamCommon, Reference = Pset_QuantityTakeOff, Reference
Beam-146:Beam-146:297477 | Beam-146
Beam-146 208203:Beam-146 208203:297491 | Beam-146 208203

# IfcBeam: Beam-146 236684:Beam-146 236684, Beam-146
In: 6.EG KH -1.15
Type - Pset_BeamCommon - IsExternal: no; LoadBearing: yes
Type - Pset_ProductRequirements - Category: Structural Framing
Material: Paveta_bordur; Group: Model Group:River:478153
Pset_BeamCommon - Reference: Beam-146 236684
Pset_QuantityTakeOff - Reference: Beam-146 236684; sets with these values: 2

# IfcBeam: Beam-146 236712:Beam-146 236712, Beam-146
In: 1.EG +0.00
Type - Pset_BeamCommon - IsExternal: no; LoadBearing: yes
Type - Pset_ProductRequirements - Category: Structural Framing
Material: Paveta_bordur; Group: Model Group:River:478153
Pset_BeamCommon - Reference: Beam-146 236712
Pset_QuantityTakeOff - Reference: Beam-146 236712; sets with these values: 2

# IfcBeam: Beam-146 236717:Beam-146 236717, Beam-146
In: 1.EG +0.00
Type - Pset_BeamCommon - IsExternal: no; LoadBearing: yes
Type - Pset_ProductRequirements - Category: Structural Framing
Material: Paveta_bordur; Group: Model Group:River:478153
Pset_BeamCommon - Reference: Beam-146 236717
Pset_QuantityTakeOff - Reference: Beam-146 236717; sets with these values: 2

# IfcBeam: Beam-146 236784:Beam-146 236784, Beam-146
In: 1.EG +0.00
Type - Pset_BeamCommon - IsExternal: no; LoadBearing: yes
Type - Pset_ProductRequirements - Category: Structural Framing
Material: Paveta_bordur; Group: Model Group:River:478153
Pset_BeamCommon - Reference: Beam-146 236784
Pset_QuantityTakeOff - Reference: Beam-146 236784; sets with these values: 2

# IfcBeam: Beam-146 237397:Beam-146 237397, Beam-146
In: 0.UG -3.60
Type - Pset_BeamCommon - IsExternal: no; LoadBearing: yes
Type - Pset_ProductRequirements - Category: Structural Framing
Material: Paveta_bordur; Group: Model Group:River:478153
Pset_BeamCommon - Reference: Beam-146 237397
Pset_QuantityTakeOff - Reference: Beam-146 237397; sets with these values: 2

# IfcBeam: Beam-146 237398:Beam-146 237398, Beam-146
In: 0.UG -3.60
Type - Pset_BeamCommon - IsExternal: no; LoadBearing: yes
Type - Pset_ProductRequirements - Category: Structural Framing
Material: Paveta_bordur; Group: Model Group:River:478153
Pset_BeamCommon - Reference: Beam-146 237398
Pset_QuantityTakeOff - Reference: Beam-146 237398; sets with these values: 2

# IfcBeam: Beam-146 237399:Beam-146 237399, Beam-146
In: 0.UG -3.60
Type - Pset_BeamCommon - IsExternal: no; LoadBearing: yes
Type - Pset_ProductRequirements - Category: Structural Framing
Material: Paint-01; Group: Model Group:River:478153
Pset_BeamCommon - Reference: Beam-146 237399
Pset_QuantityTakeOff - Reference: Beam-146 237399; sets with these values: 2

# IfcBeam: Beam-146 237835:Beam-146 237835, Beam-146
In: 6.EG KH -1.15
Type - Pset_BeamCommon - IsExternal: no; LoadBearing: yes
Type - Pset_ProductRequirements - Category: Structural Framing
Material: Paveta_bordur; Group: Model Group:River:478153
Pset_BeamCommon - Reference: Beam-146 237835
Pset_QuantityTakeOff - Reference: Beam-146 237835; sets with these values: 2

# IfcBeam: Beam-147, Beam-147:Beam-147:298370
In: 1.EG +0.00
Type - Pset_BeamCommon - IsExternal: no; LoadBearing: yes
Type - Pset_ProductRequirements - Category: Structural Framing
Material: Paveta_bordur; Group: Model Group:River:478153
Pset_BeamCommon - Reference: Beam-147
Pset_QuantityTakeOff - Reference: Beam-147; sets with these values: 2

# IfcBeam: Beam-147 236671:Beam-147 236671, Beam-147
In: 6.EG KH -1.15
Type - Pset_BeamCommon - IsExternal: no; LoadBearing: yes
Type - Pset_ProductRequirements - Category: Structural Framing
Material: Paveta_bordur; Group: Model Group:River:478153
Pset_BeamCommon - Reference: Beam-147 236671
Pset_QuantityTakeOff - Reference: Beam-147 236671; sets with these values: 2

# IfcBeam: Beam-147 237382:Beam-147 237382, Beam-147
In: 0.UG -3.60
Type - Pset_BeamCommon - IsExternal: no; LoadBearing: yes
Type - Pset_ProductRequirements - Category: Structural Framing
Material: Paveta_bordur; Group: Model Group:River:478153
Pset_BeamCommon - Reference: Beam-147 237382
Pset_QuantityTakeOff - Reference: Beam-147 237382; sets with these values: 2

# IfcBeam: Beam-147 237577:Beam-147 237577, Beam-147
In: 6.EG KH -1.15
Type - Pset_BeamCommon - IsExternal: no; LoadBearing: yes
Type - Pset_ProductRequirements - Category: Structural Framing
Material: Paveta_bordur; Group: Model Group:River:478153
Pset_BeamCommon - Reference: Beam-147 237577
Pset_QuantityTakeOff - Reference: Beam-147 237577; sets with these values: 2

# IfcBeam: Beam-147 237719:Beam-147 237719, Beam-147
In: 6.EG KH -1.15
Type - Pset_BeamCommon - IsExternal: no; LoadBearing: yes
Type - Pset_ProductRequirements - Category: Structural Framing
Material: Paveta_bordur; Group: Model Group:River:478153
Pset_BeamCommon - Reference: Beam-147 237719
Pset_QuantityTakeOff - Reference: Beam-147 237719; sets with these values: 2

# IfcBeam: Beam-147 237817:Beam-147 237817, Beam-147
In: 6.EG KH -1.15
Type - Pset_BeamCommon - IsExternal: no; LoadBearing: yes
Type - Pset_ProductRequirements - Category: Structural Framing
Material: Paveta_bordur; Group: Model Group:River:478153
Pset_BeamCommon - Reference: Beam-147 237817
Pset_QuantityTakeOff - Reference: Beam-147 237817; sets with these values: 2

# IfcBeam: Beam-148 237353:Beam-148 237353, Beam-148
In: 0.UG -3.60
Type - Pset_BeamCommon - IsExternal: no; LoadBearing: yes
Type - Pset_ProductRequirements - Category: Structural Framing
Material: Paveta_bordur; Group: Model Group:River:478153
Pset_BeamCommon - Reference: Beam-148 237353
Pset_QuantityTakeOff - Reference: Beam-148 237353; sets with these values: 2

# IfcBeam: Beam-148 237381:Beam-148 237381, Beam-148
In: 0.UG -3.60
Type - Pset_BeamCommon - IsExternal: no; LoadBearing: yes
Type - Pset_ProductRequirements - Category: Structural Framing
Material: Paint-01; Group: Model Group:River:478153
Pset_BeamCommon - Reference: Beam-148 237381
Pset_QuantityTakeOff - Reference: Beam-148 237381; sets with these values: 2

# IfcBeam: Beam-148 237620:Beam-148 237620, Beam-148
In: 6.EG KH -1.15
Type - Pset_BeamCommon - IsExternal: no; LoadBearing: yes
Type - Pset_ProductRequirements - Category: Structural Framing
Material: Paveta_bordur; Group: Model Group:River:478153
Pset_BeamCommon - Reference: Beam-148 237620
Pset_QuantityTakeOff - Reference: Beam-148 237620; sets with these values: 2

# IfcBeam: Beam-148 238221:Beam-148 238221, Beam-148
In: 0.UG -3.60
Type - Pset_BeamCommon - IsExternal: no; LoadBearing: yes
Type - Pset_ProductRequirements - Category: Structural Framing
Material: Paveta_bordur; Group: Model Group:River:478153
Pset_BeamCommon - Reference: Beam-148 238221
Pset_QuantityTakeOff - Reference: Beam-148 238221; sets with these values: 2

# IfcBeam: Beam-149, Beam-149 237377:Beam-149 237377:298489
In: 0.UG -3.60
Type - Pset_BeamCommon - IsExternal: no; LoadBearing: yes
Type - Pset_ProductRequirements - Category: Structural Framing
Material: Paveta_bordur; Group: Model Group:River:478153
Pset_BeamCommon - Reference: Beam-149 237377
Pset_QuantityTakeOff - Reference: Beam-149 237377; sets with these values: 2

# IfcBeam: Beam-149 181490:Beam-149 181490, Beam-149
In: 0.UG -3.60
Type - Pset_BeamCommon - IsExternal: no; LoadBearing: yes
Type - Pset_ProductRequirements - Category: Structural Framing
Material: Paint-01; Group: Model Group:River:478153
Pset_BeamCommon - Reference: Beam-149 181490
Pset_QuantityTakeOff - Reference: Beam-149 181490; sets with these values: 2

# IfcBeam: Beam-149 205235:Beam-149 205235, Beam-149
In: 0.UG -3.60
Type - Pset_BeamCommon - IsExternal: no; LoadBearing: yes
Type - Pset_ProductRequirements - Category: Structural Framing
Material: Paint-01; Group: Model Group:River:478153
Pset_BeamCommon - Reference: Beam-149 205235
Pset_QuantityTakeOff - Reference: Beam-149 205235; sets with these values: 2

# IfcBeam: Beam-149 237316:Beam-149 237316, Beam-149
In: 0.UG -3.60
Type - Pset_BeamCommon - IsExternal: no; LoadBearing: yes
Type - Pset_ProductRequirements - Category: Structural Framing
Material: Paint-01; Group: Model Group:River:478153
Pset_BeamCommon - Reference: Beam-149 237316
Pset_QuantityTakeOff - Reference: Beam-149 237316; sets with these values: 2

# IfcBeam: Beam-149 237709:Beam-149 237709, Beam-149
In: 6.EG KH -1.15
Type - Pset_BeamCommon - IsExternal: no; LoadBearing: yes
Type - Pset_ProductRequirements - Category: Structural Framing
Material: Paveta_bordur; Group: Model Group:River:478153
Pset_BeamCommon - Reference: Beam-149 237709
Pset_QuantityTakeOff - Reference: Beam-149 237709; sets with these values: 2

# IfcBeam: Beam-149 289760:Beam-149 289760 (2)
In: 3D
Type - Pset_BeamCommon - IsExternal: no; LoadBearing: yes
Type - Pset_ProductRequirements - Category: Structural Framing
Material: Paint-01; Group: Model Group:River:478153
Pset_BeamCommon - Reference: Beam-149 289760
Pset_QuantityTakeOff - Reference: Beam-149 289760; sets with these values: 2

# IfcBeam: Beam-150 (2)
In: 0.UG -3.60
Type - Pset_BeamCommon - IsExternal: no; LoadBearing: yes
Type - Pset_ProductRequirements - Category: Structural Framing
Material: Paveta_bordur; Group: Model Group:River:478153
Pset_QuantityTakeOff - sets with these values: 2
Name | Pset_BeamCommon, Reference = Pset_QuantityTakeOff, Reference
Beam-150:Beam-150:297498 | Beam-150
Beam-150 237352:Beam-150 237352:298475 | Beam-150 237352

# IfcBeam: Beam-150 237374:Beam-150 237374, Beam-150
In: 0.UG -3.60
Type - Pset_BeamCommon - IsExternal: no; LoadBearing: yes
Type - Pset_ProductRequirements - Category: Structural Framing
Material: Paveta_bordur; Group: Model Group:River:478153
Pset_BeamCommon - Reference: Beam-150 237374
Pset_QuantityTakeOff - Reference: Beam-150 237374; sets with these values: 2

# IfcBeam: Beam-150 237704:Beam-150 237704, Beam-150
In: 6.EG KH -1.15
Type - Pset_BeamCommon - IsExternal: no; LoadBearing: yes
Type - Pset_ProductRequirements - Category: Structural Framing
Material: Paveta_bordur; Group: Model Group:River:478153
Pset_BeamCommon - Reference: Beam-150 237704
Pset_QuantityTakeOff - Reference: Beam-150 237704; sets with these values: 2

# IfcBeam: Beam-151 237307:Beam-151 237307, Beam-151
In: 0.UG -3.60
Type - Pset_BeamCommon - IsExternal: no; LoadBearing: yes
Type - Pset_ProductRequirements - Category: Structural Framing
Material: Paveta_bordur; Group: Model Group:River:478153
Pset_BeamCommon - Reference: Beam-151 237307
Pset_QuantityTakeOff - Reference: Beam-151 237307; sets with these values: 2

# IfcBeam: Beam-151 237315:Beam-151 237315, Beam-151
In: 0.UG -3.60
Type - Pset_BeamCommon - IsExternal: no; LoadBearing: yes
Type - Pset_ProductRequirements - Category: Structural Framing
Material: Paveta_bordur; Group: Model Group:River:478153
Pset_BeamCommon - Reference: Beam-151 237315
Pset_QuantityTakeOff - Reference: Beam-151 237315; sets with these values: 2

# IfcBeam: Beam-151 237698:Beam-151 237698, Beam-151
In: 6.EG KH -1.15
Type - Pset_BeamCommon - IsExternal: no; LoadBearing: yes
Type - Pset_ProductRequirements - Category: Structural Framing
Material: Paveta_bordur; Group: Model Group:River:478153
Pset_BeamCommon - Reference: Beam-151 237698
Pset_QuantityTakeOff - Reference: Beam-151 237698; sets with these values: 2

# IfcBeam: Beam-152, Beam-152:Beam-152:298468
In: 0.UG -3.60
Type - Pset_BeamCommon - IsExternal: no; LoadBearing: yes
Type - Pset_ProductRequirements - Category: Structural Framing
Material: Paveta_bordur; Group: Model Group:River:478153
Pset_BeamCommon - Reference: Beam-152
Pset_QuantityTakeOff - Reference: Beam-152; sets with these values: 2

# IfcBeam: Beam-152 237356:Beam-152 237356, Beam-152
In: 0.UG -3.60
Type - Pset_BeamCommon - IsExternal: no; LoadBearing: yes
Type - Pset_ProductRequirements - Category: Structural Framing
Material: Paveta_bordur; Group: Model Group:River:478153
Pset_BeamCommon - Reference: Beam-152 237356
Pset_QuantityTakeOff - Reference: Beam-152 237356; sets with these values: 2

# IfcBeam: Beam-152 237412:Beam-152 237412, Beam-152
In: 0.UG -3.60
Type - Pset_BeamCommon - IsExternal: no; LoadBearing: yes
Type - Pset_ProductRequirements - Category: Structural Framing
Material: Paveta_bordur; Group: Model Group:River:478153
Pset_BeamCommon - Reference: Beam-152 237412
Pset_QuantityTakeOff - Reference: Beam-152 237412; sets with these values: 2

# IfcBeam: Beam-152 237727:Beam-152 237727, Beam-152
In: 6.EG KH -1.15
Type - Pset_BeamCommon - IsExternal: no; LoadBearing: yes
Type - Pset_ProductRequirements - Category: Structural Framing
Material: Paveta_bordur; Group: Model Group:River:478153
Pset_BeamCommon - Reference: Beam-152 237727
Pset_QuantityTakeOff - Reference: Beam-152 237727; sets with these values: 2

# IfcBeam: Beam-153 237160:Beam-153 237160 (2)
In: 3D
Type - Pset_BeamCommon - IsExternal: no; LoadBearing: yes
Type - Pset_ProductRequirements - Category: Structural Framing
Material: Paveta_bordur; Group: Model Group:River:478153
Pset_BeamCommon - Reference: Beam-153 237160
Pset_QuantityTakeOff - Reference: Beam-153 237160; sets with these values: 2
Name
Beam-152
Beam-153

# IfcBeam: Beam-153 237306:Beam-153 237306, Beam-153
In: 0.UG -3.60
Type - Pset_BeamCommon - IsExternal: no; LoadBearing: yes
Type - Pset_ProductRequirements - Category: Structural Framing
Material: Paveta_bordur; Group: Model Group:River:478153
Pset_BeamCommon - Reference: Beam-153 237306
Pset_QuantityTakeOff - Reference: Beam-153 237306; sets with these values: 2

# IfcBeam: Beam-153 237699:Beam-153 237699, Beam-153
In: 6.EG KH -1.15
Type - Pset_BeamCommon - IsExternal: no; LoadBearing: yes
Type - Pset_ProductRequirements - Category: Structural Framing
Material: Paveta_bordur; Group: Model Group:River:478153
Pset_BeamCommon - Reference: Beam-153 237699
Pset_QuantityTakeOff - Reference: Beam-153 237699; sets with these values: 2

# IfcBeam: Beam-153 238112:Beam-153 238112, Beam-153
In: 0.UG -3.60
Type - Pset_BeamCommon - IsExternal: no; LoadBearing: yes
Type - Pset_ProductRequirements - Category: Structural Framing
Material: Paveta_bordur; Group: Model Group:River:478153
Pset_BeamCommon - Reference: Beam-153 238112
Pset_QuantityTakeOff - Reference: Beam-153 238112; sets with these values: 2

# IfcBeam: Beam-153 238199:Beam-153 238199, Beam-153
In: 0.UG -3.60
Type - Pset_BeamCommon - IsExternal: no; LoadBearing: yes
Type - Pset_ProductRequirements - Category: Structural Framing
Material: Paint-01; Group: Model Group:River:478153
Pset_BeamCommon - Reference: Beam-153 238199
Pset_QuantityTakeOff - Reference: Beam-153 238199; sets with these values: 2

# IfcBeam: Beam-155 237293:Beam-155 237293, Beam-155
In: 0.UG -3.60
Type - Pset_BeamCommon - IsExternal: no; LoadBearing: yes
Type - Pset_ProductRequirements - Category: Structural Framing
Material: Paveta_bordur; Group: Model Group:River:478153
Pset_BeamCommon - Reference: Beam-155 237293
Pset_QuantityTakeOff - Reference: Beam-155 237293; sets with these values: 2

# IfcBeam: Beam-155 237688:Beam-155 237688, Beam-155
In: 6.EG KH -1.15
Type - Pset_BeamCommon - IsExternal: no; LoadBearing: yes
Type - Pset_ProductRequirements - Category: Structural Framing
Material: Paveta_bordur; Group: Model Group:River:478153
Pset_BeamCommon - Reference: Beam-155 237688
Pset_QuantityTakeOff - Reference: Beam-155 237688; sets with these values: 2

# IfcBeam: Beam-156 237292:Beam-156 237292, Beam-156
In: 0.UG -3.60
Type - Pset_BeamCommon - IsExternal: no; LoadBearing: yes
Type - Pset_ProductRequirements - Category: Structural Framing
Material: Paveta_bordur; Group: Model Group:River:478153
Pset_BeamCommon - Reference: Beam-156 237292
Pset_QuantityTakeOff - Reference: Beam-156 237292; sets with these values: 2

# IfcBeam: Beam-156 237664:Beam-156 237664, Beam-156
In: 6.EG KH -1.15
Type - Pset_BeamCommon - IsExternal: no; LoadBearing: yes
Type - Pset_ProductRequirements - Category: Structural Framing
Material: Paveta_bordur; Group: Model Group:River:478153
Pset_BeamCommon - Reference: Beam-156 237664
Pset_QuantityTakeOff - Reference: Beam-156 237664; sets with these values: 2

# IfcBeam: Beam-157, Beam-157:Beam-157:288744
In: 0.UG -3.60
Type - Pset_BeamCommon - IsExternal: no; LoadBearing: yes
Type - Pset_ProductRequirements - Category: Structural Framing
Material: Paveta_bordur; Group: Model Group:River:478153
Pset_BeamCommon - Reference: Beam-157
Pset_QuantityTakeOff - Reference: Beam-157; sets with these values: 2

# IfcBeam: Beam-157 237033:Beam-157 237033, Beam-157
In: 0.UG -3.60
Type - Pset_BeamCommon - IsExternal: no; LoadBearing: yes
Type - Pset_ProductRequirements - Category: Structural Framing
Material: Paveta_bordur; Group: Model Group:River:478153
Pset_BeamCommon - Reference: Beam-157 237033
Pset_QuantityTakeOff - Reference: Beam-157 237033; sets with these values: 2

# IfcBeam: Beam-157 237118:Beam-157 237118, Beam-157
In: 0.UG -3.60
Type - Pset_BeamCommon - IsExternal: no; LoadBearing: yes
Type - Pset_ProductRequirements - Category: Structural Framing
Material: Paveta_bordur; Group: Model Group:River:478153
Pset_BeamCommon - Reference: Beam-157 237118
Pset_QuantityTakeOff - Reference: Beam-157 237118; sets with these values: 2

# IfcBeam: Beam-157 237278:Beam-157 237278, Beam-157
In: 0.UG -3.60
Type - Pset_BeamCommon - IsExternal: no; LoadBearing: yes
Type - Pset_ProductRequirements - Category: Structural Framing
Material: Paveta_bordur; Group: Model Group:River:478153
Pset_BeamCommon - Reference: Beam-157 237278
Pset_QuantityTakeOff - Reference: Beam-157 237278; sets with these values: 2

# IfcBeam: Beam-157 237669:Beam-157 237669, Beam-157
In: 6.EG KH -1.15
Type - Pset_BeamCommon - IsExternal: no; LoadBearing: yes
Type - Pset_ProductRequirements - Category: Structural Framing
Material: Paveta_bordur; Group: Model Group:River:478153
Pset_BeamCommon - Reference: Beam-157 237669
Pset_QuantityTakeOff - Reference: Beam-157 237669; sets with these values: 2

# IfcBeam: Beam-158, Beam-158:Beam-158:288751
In: 0.UG -3.60
Type - Pset_BeamCommon - IsExternal: no; LoadBearing: yes
Type - Pset_ProductRequirements - Category: Structural Framing
Material: Paveta_bordur; Group: Model Group:River:478153
Pset_BeamCommon - Reference: Beam-158
Pset_QuantityTakeOff - Reference: Beam-158; sets with these values: 2

# IfcBeam: Beam-158 237023:Beam-158 237023, Beam-158
In: 0.UG -3.60
Type - Pset_BeamCommon - IsExternal: no; LoadBearing: yes
Type - Pset_ProductRequirements - Category: Structural Framing
Material: Paveta_bordur; Group: Model Group:River:478153
Pset_BeamCommon - Reference: Beam-158 237023
Pset_QuantityTakeOff - Reference: Beam-158 237023; sets with these values: 2

# IfcBeam: Beam-158 237053:Beam-158 237053, Beam-158
In: 0.UG -3.60
Type - Pset_BeamCommon - IsExternal: no; LoadBearing: yes
Type - Pset_ProductRequirements - Category: Structural Framing
Material: Paveta_bordur; Group: Model Group:River:478153
Pset_BeamCommon - Reference: Beam-158 237053
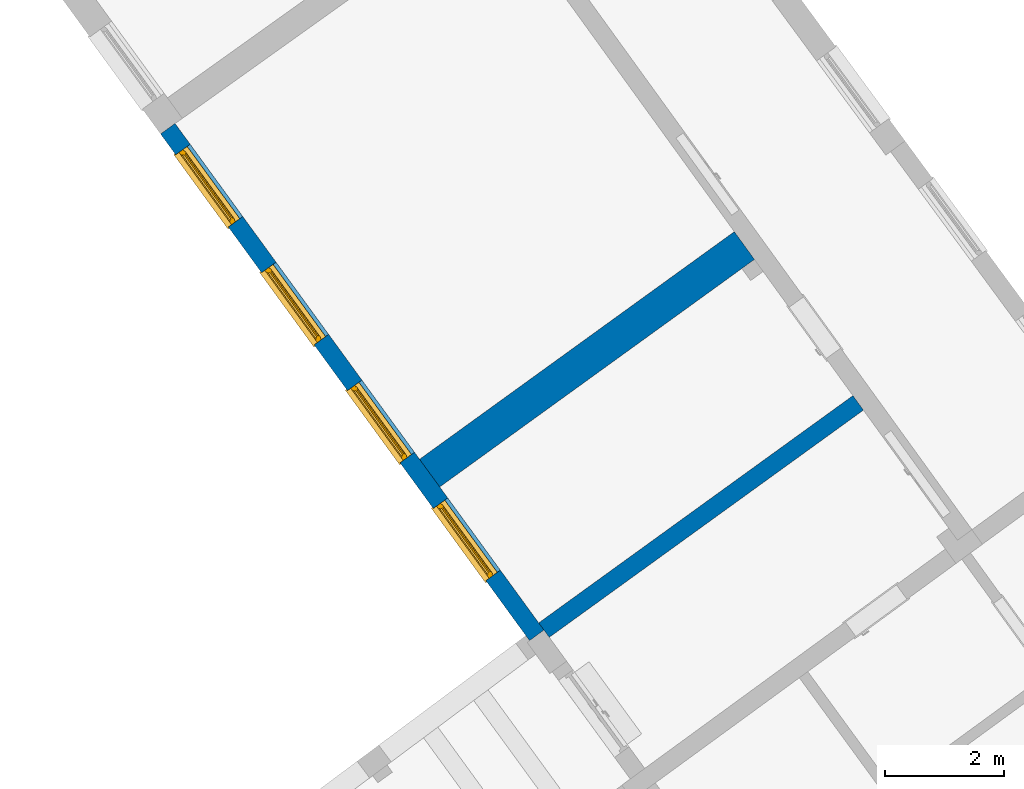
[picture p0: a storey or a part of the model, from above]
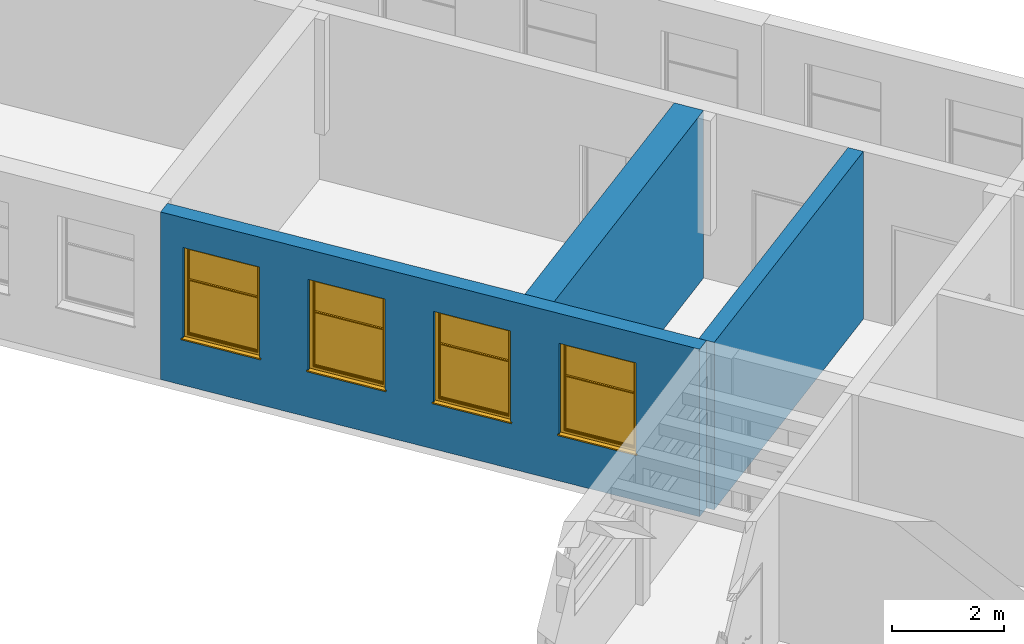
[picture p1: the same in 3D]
Properties of the parts of a building model (IFC2X3), part 2 of 13

# IfcBeam: Beam-158 237053:Beam-158 237053, Beam-158
Pset_QuantityTakeOff - Reference: Beam-158 237053; sets with these values: 2

# IfcBeam: Beam-158 237110:Beam-158 237110, Beam-158
In: 0.UG -3.60
Type - Pset_BeamCommon - IsExternal: no; LoadBearing: yes
Type - Pset_ProductRequirements - Category: Structural Framing
Material: Paveta_bordur; Group: Model Group:River:478153
Pset_BeamCommon - Reference: Beam-158 237110
Pset_QuantityTakeOff - Reference: Beam-158 237110; sets with these values: 2

# IfcBeam: Beam-158 237290:Beam-158 237290, Beam-158
In: 0.UG -3.60
Type - Pset_BeamCommon - IsExternal: no; LoadBearing: yes
Type - Pset_ProductRequirements - Category: Structural Framing
Material: Paveta_bordur; Group: Model Group:River:478153
Pset_BeamCommon - Reference: Beam-158 237290
Pset_QuantityTakeOff - Reference: Beam-158 237290; sets with these values: 2

# IfcBeam: Beam-158 237658:Beam-158 237658, Beam-158
In: 6.EG KH -1.15
Type - Pset_BeamCommon - IsExternal: no; LoadBearing: yes
Type - Pset_ProductRequirements - Category: Structural Framing
Material: Paveta_bordur; Group: Model Group:River:478153
Pset_BeamCommon - Reference: Beam-158 237658
Pset_QuantityTakeOff - Reference: Beam-158 237658; sets with these values: 2

# IfcBeam: Beam-159, Beam-159:Beam-159:298440
In: 0.UG -3.60
Type - Pset_BeamCommon - IsExternal: no; LoadBearing: yes
Type - Pset_ProductRequirements - Category: Structural Framing
Material: Paveta_bordur; Group: Model Group:River:478153
Pset_BeamCommon - Reference: Beam-159
Pset_QuantityTakeOff - Reference: Beam-159; sets with these values: 2

# IfcBeam: Beam-159 237022:Beam-159 237022, Beam-159
In: 0.UG -3.60
Type - Pset_BeamCommon - IsExternal: no; LoadBearing: yes
Type - Pset_ProductRequirements - Category: Structural Framing
Material: Paveta_bordur; Group: Model Group:River:478153
Pset_BeamCommon - Reference: Beam-159 237022
Pset_QuantityTakeOff - Reference: Beam-159 237022; sets with these values: 2

# IfcBeam: Beam-159 237105:Beam-159 237105, Beam-159
In: 0.UG -3.60
Type - Pset_BeamCommon - IsExternal: no; LoadBearing: yes
Type - Pset_ProductRequirements - Category: Structural Framing
Material: Paveta_bordur; Group: Model Group:River:478153
Pset_BeamCommon - Reference: Beam-159 237105
Pset_QuantityTakeOff - Reference: Beam-159 237105; sets with these values: 2

# IfcBeam: Beam-159 237277:Beam-159 237277, Beam-159
In: 0.UG -3.60
Type - Pset_BeamCommon - IsExternal: no; LoadBearing: yes
Type - Pset_ProductRequirements - Category: Structural Framing
Material: Paveta_bordur; Group: Model Group:River:478153
Pset_BeamCommon - Reference: Beam-159 237277
Pset_QuantityTakeOff - Reference: Beam-159 237277; sets with these values: 2

# IfcBeam: Beam-159 237659:Beam-159 237659, Beam-159
In: 6.EG KH -1.15
Type - Pset_BeamCommon - IsExternal: no; LoadBearing: yes
Type - Pset_ProductRequirements - Category: Structural Framing
Material: Paveta_bordur; Group: Model Group:River:478153
Pset_BeamCommon - Reference: Beam-159 237659
Pset_QuantityTakeOff - Reference: Beam-159 237659; sets with these values: 2

# IfcBeam: Beam-160, Beam-160:Beam-160:298454
In: 0.UG -3.60
Type - Pset_BeamCommon - IsExternal: no; LoadBearing: yes
Type - Pset_ProductRequirements - Category: Structural Framing
Material: Paveta_bordur; Group: Model Group:River:478153
Pset_BeamCommon - Reference: Beam-160
Pset_QuantityTakeOff - Reference: Beam-160; sets with these values: 2

# IfcBeam: Beam-160 237010:Beam-160 237010, Beam-160
In: 0.UG -3.60
Type - Pset_BeamCommon - IsExternal: no; LoadBearing: yes
Type - Pset_ProductRequirements - Category: Structural Framing
Material: Paveta_bordur; Group: Model Group:River:478153
Pset_BeamCommon - Reference: Beam-160 237010
Pset_QuantityTakeOff - Reference: Beam-160 237010; sets with these values: 2

# IfcBeam: Beam-160 237085:Beam-160 237085, Beam-160
In: 0.UG -3.60
Type - Pset_BeamCommon - IsExternal: no; LoadBearing: yes
Type - Pset_ProductRequirements - Category: Structural Framing
Material: Paveta_bordur; Group: Model Group:River:478153
Pset_BeamCommon - Reference: Beam-160 237085
Pset_QuantityTakeOff - Reference: Beam-160 237085; sets with these values: 2

# IfcBeam: Beam-160 237100:Beam-160 237100, Beam-160
In: 0.UG -3.60
Type - Pset_BeamCommon - IsExternal: no; LoadBearing: yes
Type - Pset_ProductRequirements - Category: Structural Framing
Material: Paveta_bordur; Group: Model Group:River:478153
Pset_BeamCommon - Reference: Beam-160 237100
Pset_QuantityTakeOff - Reference: Beam-160 237100; sets with these values: 2

# IfcBeam: Beam-160 237145:Beam-160 237145, Beam-160
In: 0.UG -3.60
Type - Pset_BeamCommon - IsExternal: no; LoadBearing: yes
Type - Pset_ProductRequirements - Category: Structural Framing
Material: Paveta_bordur; Group: Model Group:River:478153
Pset_BeamCommon - Reference: Beam-160 237145
Pset_QuantityTakeOff - Reference: Beam-160 237145; sets with these values: 2

# IfcBeam: Beam-160 237341:Beam-160 237341, Beam-160
In: 0.UG -3.60
Type - Pset_BeamCommon - IsExternal: no; LoadBearing: yes
Type - Pset_ProductRequirements - Category: Structural Framing
Material: Paveta_bordur; Group: Model Group:River:478153
Pset_BeamCommon - Reference: Beam-160 237341
Pset_QuantityTakeOff - Reference: Beam-160 237341; sets with these values: 2

# IfcBeam: Beam-160 237411:Beam-160 237411, Beam-160
In: 0.UG -3.60
Type - Pset_BeamCommon - IsExternal: no; LoadBearing: yes
Type - Pset_ProductRequirements - Category: Structural Framing
Material: Paveta_bordur; Group: Model Group:River:478153
Pset_BeamCommon - Reference: Beam-160 237411
Pset_QuantityTakeOff - Reference: Beam-160 237411; sets with these values: 2

# IfcBeam: Beam-160 237647:Beam-160 237647, Beam-160
In: 6.EG KH -1.15
Type - Pset_BeamCommon - IsExternal: no; LoadBearing: yes
Type - Pset_ProductRequirements - Category: Structural Framing
Material: Paveta_bordur; Group: Model Group:River:478153
Pset_BeamCommon - Reference: Beam-160 237647
Pset_QuantityTakeOff - Reference: Beam-160 237647; sets with these values: 2

# IfcBeam: Beam-160 240377:Beam-160 240377, Beam-160
In: 0.UG -3.60
Type - Pset_BeamCommon - IsExternal: no; LoadBearing: yes
Type - Pset_ProductRequirements - Category: Structural Framing
Material: Paveta_bordur; Group: Model Group:River:478153
Pset_BeamCommon - Reference: Beam-160 240377
Pset_QuantityTakeOff - Reference: Beam-160 240377; sets with these values: 2

# IfcBeam: Beam-161 (5)
In: 0.UG -3.60
Type - Pset_BeamCommon - IsExternal: no; LoadBearing: yes
Type - Pset_ProductRequirements - Category: Structural Framing
Material: Paveta_bordur; Group: Model Group:River:478153
Pset_QuantityTakeOff - sets with these values: 2
Name | Pset_BeamCommon, Reference = Pset_QuantityTakeOff, Reference
Beam-161:Beam-161:297505 | Beam-161
Beam-161 236930:Beam-161 236930:298405 | Beam-161 236930
Beam-161 236948:Beam-161 236948:298412 | Beam-161 236948
Beam-161 240349:Beam-161 240349:298665 | Beam-161 240349
Beam-161 240386:Beam-161 240386:298672 | Beam-161 240386

# IfcBeam: Beam-161 227987:Beam-161 227987, Beam-161
In: 0.UG -3.60
Type - Pset_BeamCommon - IsExternal: no; LoadBearing: yes
Type - Pset_ProductRequirements - Category: Structural Framing
Material: Paveta_bordur; Group: Model Group:River:478153
Pset_BeamCommon - Reference: Beam-161 227987
Pset_QuantityTakeOff - Reference: Beam-161 227987; sets with these values: 2

# IfcBeam: Beam-161 236893:Beam-161 236893, Beam-161
In: 0.UG -3.60
Type - Pset_BeamCommon - IsExternal: no; LoadBearing: yes
Type - Pset_ProductRequirements - Category: Structural Framing
Material: Paveta_bordur; Group: Model Group:River:478153
Pset_BeamCommon - Reference: Beam-161 236893
Pset_QuantityTakeOff - Reference: Beam-161 236893; sets with these values: 2

# IfcBeam: Beam-161 236897:Beam-161 236897, Beam-161
In: 0.UG -3.60
Type - Pset_BeamCommon - IsExternal: no; LoadBearing: yes
Type - Pset_ProductRequirements - Category: Structural Framing
Material: Paveta_bordur; Group: Model Group:River:478153
Pset_BeamCommon - Reference: Beam-161 236897
Pset_QuantityTakeOff - Reference: Beam-161 236897; sets with these values: 2

# IfcBeam: Beam-161 236898:Beam-161 236898, Beam-161
In: 0.UG -3.60
Type - Pset_BeamCommon - IsExternal: no; LoadBearing: yes
Type - Pset_ProductRequirements - Category: Structural Framing
Material: Paveta_bordur; Group: Model Group:River:478153
Pset_BeamCommon - Reference: Beam-161 236898
Pset_QuantityTakeOff - Reference: Beam-161 236898; sets with these values: 2

# IfcBeam: Beam-161 236908:Beam-161 236908, Beam-161
In: 0.UG -3.60
Type - Pset_BeamCommon - IsExternal: no; LoadBearing: yes
Type - Pset_ProductRequirements - Category: Structural Framing
Material: Paveta_bordur; Group: Model Group:River:478153
Pset_BeamCommon - Reference: Beam-161 236908
Pset_QuantityTakeOff - Reference: Beam-161 236908; sets with these values: 2

# IfcBeam: Beam-161 236914:Beam-161 236914, Beam-161
In: 0.UG -3.60
Type - Pset_BeamCommon - IsExternal: no; LoadBearing: yes
Type - Pset_ProductRequirements - Category: Structural Framing
Material: Paveta_bordur; Group: Model Group:River:478153
Pset_BeamCommon - Reference: Beam-161 236914
Pset_QuantityTakeOff - Reference: Beam-161 236914; sets with these values: 2

# IfcBeam: Beam-161 236943:Beam-161 236943, Beam-161
In: 0.UG -3.60
Type - Pset_BeamCommon - IsExternal: no; LoadBearing: yes
Type - Pset_ProductRequirements - Category: Structural Framing
Material: Paveta_bordur; Group: Model Group:River:478153
Pset_BeamCommon - Reference: Beam-161 236943
Pset_QuantityTakeOff - Reference: Beam-161 236943; sets with these values: 2

# IfcBeam: Beam-161 236953:Beam-161 236953, Beam-161
In: 0.UG -3.60
Type - Pset_BeamCommon - IsExternal: no; LoadBearing: yes
Type - Pset_ProductRequirements - Category: Structural Framing
Material: Paveta_bordur; Group: Model Group:River:478153
Pset_BeamCommon - Reference: Beam-161 236953
Pset_QuantityTakeOff - Reference: Beam-161 236953; sets with these values: 2

# IfcBeam: Beam-161 237080:Beam-161 237080, Beam-161
In: 0.UG -3.60
Type - Pset_BeamCommon - IsExternal: no; LoadBearing: yes
Type - Pset_ProductRequirements - Category: Structural Framing
Material: Paveta_bordur; Group: Model Group:River:478153
Pset_BeamCommon - Reference: Beam-161 237080
Pset_QuantityTakeOff - Reference: Beam-161 237080; sets with these values: 2

# IfcBeam: Beam-161 237090:Beam-161 237090, Beam-161
In: 0.UG -3.60
Type - Pset_BeamCommon - IsExternal: no; LoadBearing: yes
Type - Pset_ProductRequirements - Category: Structural Framing
Material: Paveta_bordur; Group: Model Group:River:478153
Pset_BeamCommon - Reference: Beam-161 237090
Pset_QuantityTakeOff - Reference: Beam-161 237090; sets with these values: 2

# IfcBeam: Beam-161 237126:Beam-161 237126, Beam-161
In: 0.UG -3.60
Type - Pset_BeamCommon - IsExternal: no; LoadBearing: yes
Type - Pset_ProductRequirements - Category: Structural Framing
Material: Paint-01; Group: Model Group:River:478153
Pset_BeamCommon - Reference: Beam-161 237126
Pset_QuantityTakeOff - Reference: Beam-161 237126; sets with these values: 2

# IfcBeam: Beam-161 237133:Beam-161 237133, Beam-161
In: 0.UG -3.60
Type - Pset_BeamCommon - IsExternal: no; LoadBearing: yes
Type - Pset_ProductRequirements - Category: Structural Framing
Material: Paint-01; Group: Model Group:River:478153
Pset_BeamCommon - Reference: Beam-161 237133
Pset_QuantityTakeOff - Reference: Beam-161 237133; sets with these values: 2

# IfcBeam: Beam-161 237425:Beam-161 237425, Beam-161
In: 0.UG -3.60
Type - Pset_BeamCommon - IsExternal: no; LoadBearing: yes
Type - Pset_ProductRequirements - Category: Structural Framing
Material: Paint-01; Group: Model Group:River:478153
Pset_BeamCommon - Reference: Beam-161 237425
Pset_QuantityTakeOff - Reference: Beam-161 237425; sets with these values: 2

# IfcBeam: Beam-161 240354:Beam-161 240354, Beam-161
In: 0.UG -3.60
Type - Pset_BeamCommon - IsExternal: no; LoadBearing: yes
Type - Pset_ProductRequirements - Category: Structural Framing
Material: Paveta_bordur; Group: Model Group:River:478153
Pset_BeamCommon - Reference: Beam-161 240354
Pset_QuantityTakeOff - Reference: Beam-161 240354; sets with these values: 2

# IfcBeam: Beam-161 240382:Beam-161 240382, Beam-161
In: 0.UG -3.60
Type - Pset_BeamCommon - IsExternal: no; LoadBearing: yes
Type - Pset_ProductRequirements - Category: Structural Framing
Material: Paveta_bordur; Group: Model Group:River:478153
Pset_BeamCommon - Reference: Beam-161 240382
Pset_QuantityTakeOff - Reference: Beam-161 240382; sets with these values: 2

# IfcBeam: Beam-162 195816:Beam-162 195816, Beam-162
In: 0.UG -3.60
Type - Pset_BeamCommon - IsExternal: no; LoadBearing: yes
Type - Pset_ProductRequirements - Category: Structural Framing
Material: Paveta_bordur; Group: Model Group:River:478153
Pset_BeamCommon - Reference: Beam-162 195816
Pset_QuantityTakeOff - Reference: Beam-162 195816; sets with these values: 2

# IfcBeam: Beam-162 210071:Beam-162 210071, Beam-162
In: 0.UG -3.60
Type - Pset_BeamCommon - IsExternal: no; LoadBearing: yes
Type - Pset_ProductRequirements - Category: Structural Framing
Material: Paveta_bordur; Group: Model Group:River:478153
Pset_BeamCommon - Reference: Beam-162 210071
Pset_QuantityTakeOff - Reference: Beam-162 210071; sets with these values: 2

# IfcBeam: Beam-162 236962:Beam-162 236962, Beam-162
In: 0.UG -3.60
Type - Pset_BeamCommon - IsExternal: no; LoadBearing: yes
Type - Pset_ProductRequirements - Category: Structural Framing
Material: Paveta_bordur; Group: Model Group:River:478153
Pset_BeamCommon - Reference: Beam-162 236962
Pset_QuantityTakeOff - Reference: Beam-162 236962; sets with these values: 2

# IfcBeam: Beam-162 237073:Beam-162 237073, Beam-162
In: 0.UG -3.60
Type - Pset_BeamCommon - IsExternal: no; LoadBearing: yes
Type - Pset_ProductRequirements - Category: Structural Framing
Material: Paveta_bordur; Group: Model Group:River:478153
Pset_BeamCommon - Reference: Beam-162 237073
Pset_QuantityTakeOff - Reference: Beam-162 237073; sets with these values: 2

# IfcBeam: Beam-162 237129:Beam-162 237129, Beam-162
In: 0.UG -3.60
Type - Pset_BeamCommon - IsExternal: no; LoadBearing: yes
Type - Pset_ProductRequirements - Category: Structural Framing
Material: Paint-01; Group: Model Group:River:478153
Pset_BeamCommon - Reference: Beam-162 237129
Pset_QuantityTakeOff - Reference: Beam-162 237129; sets with these values: 2

# IfcBeam: Beam-162 237132:Beam-162 237132, Beam-162
In: 0.UG -3.60
Type - Pset_BeamCommon - IsExternal: no; LoadBearing: yes
Type - Pset_ProductRequirements - Category: Structural Framing
Material: Paint-01; Group: Model Group:River:478153
Pset_BeamCommon - Reference: Beam-162 237132
Pset_QuantityTakeOff - Reference: Beam-162 237132; sets with these values: 2

# IfcBeam: Beam-162 237253:Beam-162 237253, Beam-162
In: 0.UG -3.60
Type - Pset_BeamCommon - IsExternal: no; LoadBearing: yes
Type - Pset_ProductRequirements - Category: Structural Framing
Material: Paveta_bordur; Group: Model Group:River:478153
Pset_BeamCommon - Reference: Beam-162 237253
Pset_QuantityTakeOff - Reference: Beam-162 237253; sets with these values: 2

# IfcBeam: Beam-162 237270:Beam-162 237270, Beam-162
In: 0.UG -3.60
Type - Pset_BeamCommon - IsExternal: no; LoadBearing: yes
Type - Pset_ProductRequirements - Category: Structural Framing
Material: Paveta_bordur; Group: Model Group:River:478153
Pset_BeamCommon - Reference: Beam-162 237270
Pset_QuantityTakeOff - Reference: Beam-162 237270; sets with these values: 2

# IfcBeam: Beam-163 (2)
In: 0.UG -3.60
Type - Pset_BeamCommon - IsExternal: no; LoadBearing: yes
Type - Pset_ProductRequirements - Category: Structural Framing
Material: Paveta_bordur; Group: Model Group:River:478153
Pset_QuantityTakeOff - sets with these values: 2
Name | Pset_BeamCommon, Reference = Pset_QuantityTakeOff, Reference
Beam-163:Beam-163:298040 | Beam-163
Beam-163 237331:Beam-163 237331:298461 | Beam-163 237331

# IfcBeam: Beam-163 237074:Beam-163 237074, Beam-163
In: 0.UG -3.60
Type - Pset_BeamCommon - IsExternal: no; LoadBearing: yes
Type - Pset_ProductRequirements - Category: Structural Framing
Material: Paveta_bordur; Group: Model Group:River:478153
Pset_BeamCommon - Reference: Beam-163 237074
Pset_QuantityTakeOff - Reference: Beam-163 237074; sets with these values: 2

# IfcBeam: Beam-163 237164:Beam-163 237164, Beam-163
In: 0.UG -3.60
Type - Pset_BeamCommon - IsExternal: no; LoadBearing: yes
Type - Pset_ProductRequirements - Category: Structural Framing
Material: Paint-01; Group: Model Group:River:478153
Pset_BeamCommon - Reference: Beam-163 237164
Pset_QuantityTakeOff - Reference: Beam-163 237164; sets with these values: 2

# IfcBeam: Beam-163 237266:Beam-163 237266, Beam-163
In: 0.UG -3.60
Type - Pset_BeamCommon - IsExternal: no; LoadBearing: yes
Type - Pset_ProductRequirements - Category: Structural Framing
Material: Paveta_bordur; Group: Model Group:River:478153
Pset_BeamCommon - Reference: Beam-163 237266
Pset_QuantityTakeOff - Reference: Beam-163 237266; sets with these values: 2

# IfcBeam: Beam-163 237327:Beam-163 237327, Beam-163
In: 0.UG -3.60
Type - Pset_BeamCommon - IsExternal: no; LoadBearing: yes
Type - Pset_ProductRequirements - Category: Structural Framing
Material: Paint-01; Group: Model Group:River:478153
Pset_BeamCommon - Reference: Beam-163 237327
Pset_QuantityTakeOff - Reference: Beam-163 237327; sets with these values: 2

# IfcBeam: Beam-163 238237:Beam-163 238237, Beam-163
In: 0.UG -3.60
Type - Pset_BeamCommon - IsExternal: no; LoadBearing: yes
Type - Pset_ProductRequirements - Category: Structural Framing
Material: Paveta_bordur; Group: Model Group:River:478153
Pset_BeamCommon - Reference: Beam-163 238237
Pset_QuantityTakeOff - Reference: Beam-163 238237; sets with these values: 2

# IfcBeam: Beam-164 (2)
In: 0.UG -3.60
Type - Pset_BeamCommon - IsExternal: no; LoadBearing: yes
Type - Pset_ProductRequirements - Category: Structural Framing
Material: Paveta_bordur; Group: Model Group:River:478153
Pset_QuantityTakeOff - sets with these values: 2
Name | Pset_BeamCommon, Reference = Pset_QuantityTakeOff, Reference
Beam-164:Beam-164:298398 | Beam-164
Beam-164 236958:Beam-164 236958:298419 | Beam-164 236958

# IfcBeam: Beam-164 236919:Beam-164 236919, Beam-164
In: 0.UG -3.60
Type - Pset_BeamCommon - IsExternal: no; LoadBearing: yes
Type - Pset_ProductRequirements - Category: Structural Framing
Material: Paveta_bordur; Group: Model Group:River:478153
Pset_BeamCommon - Reference: Beam-164 236919
Pset_QuantityTakeOff - Reference: Beam-164 236919; sets with these values: 2

# IfcBeam: Beam-164 237161:Beam-164 237161, Beam-164
In: 0.UG -3.60
Type - Pset_BeamCommon - IsExternal: no; LoadBearing: yes
Type - Pset_ProductRequirements - Category: Structural Framing
Material: Paint-01; Group: Model Group:River:478153
Pset_BeamCommon - Reference: Beam-164 237161
Pset_QuantityTakeOff - Reference: Beam-164 237161; sets with these values: 2

# IfcBeam: Beam-164 237636:Beam-164 237636, Beam-164
In: 6.EG KH -1.15
Type - Pset_BeamCommon - IsExternal: no; LoadBearing: yes
Type - Pset_ProductRequirements - Category: Structural Framing
Material: Paveta_bordur; Group: Model Group:River:478153
Pset_BeamCommon - Reference: Beam-164 237636
Pset_QuantityTakeOff - Reference: Beam-164 237636; sets with these values: 2

# IfcBeam: Beam-165 237065:Beam-165 237065, Beam-165
In: 0.UG -3.60
Type - Pset_BeamCommon - IsExternal: no; LoadBearing: yes
Type - Pset_ProductRequirements - Category: Structural Framing
Material: Paveta_bordur; Group: Model Group:River:478153
Pset_BeamCommon - Reference: Beam-165 237065
Pset_QuantityTakeOff - Reference: Beam-165 237065; sets with these values: 2

# IfcBeam: Beam-165 237264:Beam-165 237264, Beam-165
In: 0.UG -3.60
Type - Pset_BeamCommon - IsExternal: no; LoadBearing: yes
Type - Pset_ProductRequirements - Category: Structural Framing
Material: Paveta_bordur; Group: Model Group:River:478153
Pset_BeamCommon - Reference: Beam-165 237264
Pset_QuantityTakeOff - Reference: Beam-165 237264; sets with these values: 2

# IfcBeam: Beam-165 237349:Beam-165 237349, Beam-165
In: 0.UG -3.60
Type - Pset_BeamCommon - IsExternal: no; LoadBearing: yes
Type - Pset_ProductRequirements - Category: Structural Framing
Material: Paveta_bordur; Group: Model Group:River:478153
Pset_BeamCommon - Reference: Beam-165 237349
Pset_QuantityTakeOff - Reference: Beam-165 237349; sets with these values: 2

# IfcBeam: Beam-165 237631:Beam-165 237631, Beam-165
In: 6.EG KH -1.15
Type - Pset_BeamCommon - IsExternal: no; LoadBearing: yes
Type - Pset_ProductRequirements - Category: Structural Framing
Material: Paveta_bordur; Group: Model Group:River:478153
Pset_BeamCommon - Reference: Beam-165 237631
Pset_QuantityTakeOff - Reference: Beam-165 237631; sets with these values: 2

# IfcBeam: Beam-165 237974:Beam-165 237974, Beam-165
In: 0.UG -3.60
Type - Pset_BeamCommon - IsExternal: no; LoadBearing: yes
Type - Pset_ProductRequirements - Category: Structural Framing
Material: Paveta_bordur; Group: Model Group:River:478153
Pset_BeamCommon - Reference: Beam-165 237974
Pset_QuantityTakeOff - Reference: Beam-165 237974; sets with these values: 2

# IfcBeam: Beam-166 (3)
In: 6.EG KH -1.15
Type - Pset_BeamCommon - IsExternal: no; LoadBearing: yes
Type - Pset_ProductRequirements - Category: Structural Framing
Material: Paveta_bordur; Group: Model Group:River:478153
Pset_QuantityTakeOff - sets with these values: 2
Name | Pset_BeamCommon, Reference = Pset_QuantityTakeOff, Reference
Beam-166:Beam-166:299002 | Beam-166
Beam-166 262470:Beam-166 262470:299009 | Beam-166 262470
Beam-166 266109:Beam-166 266109:299023 | Beam-166 266109

# IfcBeam: Beam-166 235956:Beam-166 235956, Beam-166
In: 6.EG KH -1.15
Type - Pset_BeamCommon - IsExternal: no; LoadBearing: yes
Type - Pset_ProductRequirements - Category: Structural Framing
Material: Paint-01; Group: Model Group:River:478153
Pset_BeamCommon - Reference: Beam-166 235956
Pset_QuantityTakeOff - Reference: Beam-166 235956; sets with these values: 2

# IfcBeam: Beam-166 236872:Beam-166 236872, Beam-166
In: 6.EG KH -1.15
Type - Pset_BeamCommon - IsExternal: no; LoadBearing: yes
Type - Pset_ProductRequirements - Category: Structural Framing
Material: Paveta_bordur; Group: Model Group:River:478153
Pset_BeamCommon - Reference: Beam-166 236872
Pset_QuantityTakeOff - Reference: Beam-166 236872; sets with these values: 2

# IfcBeam: Beam-166 237260:Beam-166 237260, Beam-166
In: 0.UG -3.60
Type - Pset_BeamCommon - IsExternal: no; LoadBearing: yes
Type - Pset_ProductRequirements - Category: Structural Framing
Material: Paveta_bordur; Group: Model Group:River:478153
Pset_BeamCommon - Reference: Beam-166 237260
Pset_QuantityTakeOff - Reference: Beam-166 237260; sets with these values: 2

# IfcBeam: Beam-166 237564:Beam-166 237564, Beam-166
In: 6.EG KH -1.15
Type - Pset_BeamCommon - IsExternal: no; LoadBearing: yes
Type - Pset_ProductRequirements - Category: Structural Framing
Material: Paint-01; Group: Model Group:River:478153
Pset_BeamCommon - Reference: Beam-166 237564
Pset_QuantityTakeOff - Reference: Beam-166 237564; sets with these values: 2

# IfcBeam: Beam-166 237585:Beam-166 237585, Beam-166
In: 6.EG KH -1.15
Type - Pset_BeamCommon - IsExternal: no; LoadBearing: yes
Type - Pset_ProductRequirements - Category: Structural Framing
Material: Paint-01; Group: Model Group:River:478153
Pset_BeamCommon - Reference: Beam-166 237585
Pset_QuantityTakeOff - Reference: Beam-166 237585; sets with these values: 2

# IfcBeam: Beam-166 237587:Beam-166 237587, Beam-166
In: 6.EG KH -1.15
Type - Pset_BeamCommon - IsExternal: no; LoadBearing: yes
Type - Pset_ProductRequirements - Category: Structural Framing
Material: Paveta_bordur; Group: Model Group:River:478153
Pset_BeamCommon - Reference: Beam-166 237587
Pset_QuantityTakeOff - Reference: Beam-166 237587; sets with these values: 2

# IfcBeam: Beam-166 237602:Beam-166 237602, Beam-166
In: 6.EG KH -1.15
Type - Pset_BeamCommon - IsExternal: no; LoadBearing: yes
Type - Pset_ProductRequirements - Category: Structural Framing
Material: Paint-01; Group: Model Group:River:478153
Pset_BeamCommon - Reference: Beam-166 237602
Pset_QuantityTakeOff - Reference: Beam-166 237602; sets with these values: 2

# IfcBeam: Beam-166 237613:Beam-166 237613, Beam-166
In: 6.EG KH -1.15
Type - Pset_BeamCommon - IsExternal: no; LoadBearing: yes
Type - Pset_ProductRequirements - Category: Structural Framing
Material: Paveta_bordur; Group: Model Group:River:478153
Pset_BeamCommon - Reference: Beam-166 237613
Pset_QuantityTakeOff - Reference: Beam-166 237613; sets with these values: 2

# IfcBeam: Beam-166 237614:Beam-166 237614, Beam-166
In: 6.EG KH -1.15
Type - Pset_BeamCommon - IsExternal: no; LoadBearing: yes
Type - Pset_ProductRequirements - Category: Structural Framing
Material: Paveta_bordur; Group: Model Group:River:478153
Pset_BeamCommon - Reference: Beam-166 237614
Pset_QuantityTakeOff - Reference: Beam-166 237614; sets with these values: 2

# IfcBeam: Beam-166 237637:Beam-166 237637, Beam-166
In: 6.EG KH -1.15
Type - Pset_BeamCommon - IsExternal: no; LoadBearing: yes
Type - Pset_ProductRequirements - Category: Structural Framing
Material: Paveta_bordur; Group: Model Group:River:478153
Pset_BeamCommon - Reference: Beam-166 237637
Pset_QuantityTakeOff - Reference: Beam-166 237637; sets with these values: 2

# IfcBeam: Beam-166 237960:Beam-166 237960, Beam-166
In: 6.EG KH -1.15
Type - Pset_BeamCommon - IsExternal: no; LoadBearing: yes
Type - Pset_ProductRequirements - Category: Structural Framing
Material: Paint-01; Group: Model Group:River:478153
Pset_BeamCommon - Reference: Beam-166 237960
Pset_QuantityTakeOff - Reference: Beam-166 237960; sets with these values: 2

# IfcBeam: Beam-166 262416:Beam-166 262416, Beam-166
In: 6.EG KH -1.15
Type - Pset_BeamCommon - IsExternal: no; LoadBearing: yes
Type - Pset_ProductRequirements - Category: Structural Framing
Material: Paint-01; Group: Model Group:River:478153
Pset_BeamCommon - Reference: Beam-166 262416
Pset_QuantityTakeOff - Reference: Beam-166 262416; sets with these values: 2

# IfcBeam: Beam-166 262426:Beam-166 262426, Beam-166
In: 6.EG KH -1.15
Type - Pset_BeamCommon - IsExternal: no; LoadBearing: yes
Type - Pset_ProductRequirements - Category: Structural Framing
Material: Paint-01; Group: Model Group:River:478153
Pset_BeamCommon - Reference: Beam-166 262426
Pset_QuantityTakeOff - Reference: Beam-166 262426; sets with these values: 2

# IfcBeam: Beam-166 262444:Beam-166 262444, Beam-166
In: 6.EG KH -1.15
Type - Pset_BeamCommon - IsExternal: no; LoadBearing: yes
Type - Pset_ProductRequirements - Category: Structural Framing
Material: Paint-01; Group: Model Group:River:478153
Pset_BeamCommon - Reference: Beam-166 262444
Pset_QuantityTakeOff - Reference: Beam-166 262444; sets with these values: 2

# IfcBeam: Beam-166 262471:Beam-166 262471, Beam-166
In: 6.EG KH -1.15
Type - Pset_BeamCommon - IsExternal: no; LoadBearing: yes
Type - Pset_ProductRequirements - Category: Structural Framing
Material: Paint-01; Group: Model Group:River:478153
Pset_BeamCommon - Reference: Beam-166 262471
Pset_QuantityTakeOff - Reference: Beam-166 262471; sets with these values: 2

# IfcBeam: Beam-167 237265:Beam-167 237265, Beam-167
In: 0.UG -3.60
Type - Pset_BeamCommon - IsExternal: no; LoadBearing: yes
Type - Pset_ProductRequirements - Category: Structural Framing
Material: Paveta_bordur; Group: Model Group:River:478153
Pset_BeamCommon - Reference: Beam-167 237265
Pset_QuantityTakeOff - Reference: Beam-167 237265; sets with these values: 2

# IfcBeam: Beam-167 237598:Beam-167 237598, Beam-167
In: 6.EG KH -1.15
Type - Pset_BeamCommon - IsExternal: no; LoadBearing: yes
Type - Pset_ProductRequirements - Category: Structural Framing
Material: Paveta_bordur; Group: Model Group:River:478153
Pset_BeamCommon - Reference: Beam-167 237598
Pset_QuantityTakeOff - Reference: Beam-167 237598; sets with these values: 2

# IfcBeam: Beam-167 237657:Beam-167 237657, Beam-167
In: 6.EG KH -1.15
Type - Pset_BeamCommon - IsExternal: no; LoadBearing: yes
Type - Pset_ProductRequirements - Category: Structural Framing
Material: Paveta_bordur; Group: Model Group:River:478153
Pset_BeamCommon - Reference: Beam-167 237657
Pset_QuantityTakeOff - Reference: Beam-167 237657; sets with these values: 2

# IfcBeam: Beam-168 237608:Beam-168 237608, Beam-168
In: 6.EG KH -1.15
Type - Pset_BeamCommon - IsExternal: no; LoadBearing: yes
Type - Pset_ProductRequirements - Category: Structural Framing
Material: Paveta_bordur; Group: Model Group:River:478153
Pset_BeamCommon - Reference: Beam-168 237608
Pset_QuantityTakeOff - Reference: Beam-168 237608; sets with these values: 2

# IfcBeam: Beam-169 237536:Beam-169 237536, Beam-169
In: 6.EG KH -1.15
Type - Pset_BeamCommon - IsExternal: no; LoadBearing: yes
Type - Pset_ProductRequirements - Category: Structural Framing
Material: Paveta_bordur; Group: Model Group:River:478153
Pset_BeamCommon - Reference: Beam-169 237536
Pset_QuantityTakeOff - Reference: Beam-169 237536; sets with these values: 2

# IfcBeam: Beam-169 237546:Beam-169 237546, Beam-169
In: 6.EG KH -1.15
Type - Pset_BeamCommon - IsExternal: no; LoadBearing: yes
Type - Pset_ProductRequirements - Category: Structural Framing
Material: Paveta_bordur; Group: Model Group:River:478153
Pset_BeamCommon - Reference: Beam-169 237546
Pset_QuantityTakeOff - Reference: Beam-169 237546; sets with these values: 2

# IfcBeam: Beam-170, Beam-170:Beam-170:298426
In: 0.UG -3.60
Type - Pset_BeamCommon - IsExternal: no; LoadBearing: yes
Type - Pset_ProductRequirements - Category: Structural Framing
Material: Paveta_bordur; Group: Model Group:River:478153
Pset_BeamCommon - Reference: Beam-170
Pset_QuantityTakeOff - Reference: Beam-170; sets with these values: 2

# IfcBeam: Beam-170 236984:Beam-170 236984, Beam-170
In: 0.UG -3.60
Type - Pset_BeamCommon - IsExternal: no; LoadBearing: yes
Type - Pset_ProductRequirements - Category: Structural Framing
Material: Paveta_bordur; Group: Model Group:River:478153
Pset_BeamCommon - Reference: Beam-170 236984
Pset_QuantityTakeOff - Reference: Beam-170 236984; sets with these values: 2

# IfcBeam: Beam-170 237028:Beam-170 237028, Beam-170
In: 0.UG -3.60
Type - Pset_BeamCommon - IsExternal: no; LoadBearing: yes
Type - Pset_ProductRequirements - Category: Structural Framing
Material: Paveta_bordur; Group: Model Group:River:478153
Pset_BeamCommon - Reference: Beam-170 237028
Pset_QuantityTakeOff - Reference: Beam-170 237028; sets with these values: 2

# IfcBeam: Beam-170 237551:Beam-170 237551, Beam-170
In: 0.UG -3.60
Type - Pset_BeamCommon - IsExternal: no; LoadBearing: yes
Type - Pset_ProductRequirements - Category: Structural Framing
Material: Paveta_bordur; Group: Model Group:River:478153
Pset_BeamCommon - Reference: Beam-170 237551
Pset_QuantityTakeOff - Reference: Beam-170 237551; sets with these values: 2

# IfcBeam: Beam-171 237540:Beam-171 237540, Beam-171
In: 6.EG KH -1.15
Type - Pset_BeamCommon - IsExternal: no; LoadBearing: yes
Type - Pset_ProductRequirements - Category: Structural Framing
Material: Paveta_bordur; Group: Model Group:River:478153
Pset_BeamCommon - Reference: Beam-171 237540
Pset_QuantityTakeOff - Reference: Beam-171 237540; sets with these values: 2

# IfcBeam: Beam-171 237565:Beam-171 237565, Beam-171
In: 6.EG KH -1.15
Type - Pset_BeamCommon - IsExternal: no; LoadBearing: yes
Type - Pset_ProductRequirements - Category: Structural Framing
Material: Paveta_bordur; Group: Model Group:River:478153
Pset_BeamCommon - Reference: Beam-171 237565
Pset_QuantityTakeOff - Reference: Beam-171 237565; sets with these values: 2

# IfcBeam: Beam-171 237566:Beam-171 237566, Beam-171
In: 6.EG KH -1.15
Type - Pset_BeamCommon - IsExternal: no; LoadBearing: yes
Type - Pset_ProductRequirements - Category: Structural Framing
Material: Paveta_bordur; Group: Model Group:River:478153
Pset_BeamCommon - Reference: Beam-171 237566
Pset_QuantityTakeOff - Reference: Beam-171 237566; sets with these values: 2

# IfcBeam: Beam-172 237515:Beam-172 237515, Beam-172
In: 6.EG KH -1.15
Type - Pset_BeamCommon - IsExternal: no; LoadBearing: yes
Type - Pset_ProductRequirements - Category: Structural Framing
Material: Paint-01; Group: Model Group:River:478153
Pset_BeamCommon - Reference: Beam-172 237515
Pset_QuantityTakeOff - Reference: Beam-172 237515; sets with these values: 2

# IfcBeam: Beam-172 237525:Beam-172 237525, Beam-172
In: 6.EG KH -1.15
Type - Pset_BeamCommon - IsExternal: no; LoadBearing: yes
Type - Pset_ProductRequirements - Category: Structural Framing
Material: Paveta_bordur; Group: Model Group:River:478153
Pset_BeamCommon - Reference: Beam-172 237525
Pset_QuantityTakeOff - Reference: Beam-172 237525; sets with these values: 2

# IfcBeam: Beam-172 237541:Beam-172 237541, Beam-172
In: 6.EG KH -1.15
Type - Pset_BeamCommon - IsExternal: no; LoadBearing: yes
Type - Pset_ProductRequirements - Category: Structural Framing
Material: Paint-01; Group: Model Group:River:478153
Pset_BeamCommon - Reference: Beam-172 237541
Pset_QuantityTakeOff - Reference: Beam-172 237541; sets with these values: 2

# IfcBeam: Beam-173 236799:Beam-173 236799, Beam-173
In: 6.EG KH -1.15
Type - Pset_BeamCommon - IsExternal: no; LoadBearing: yes
Type - Pset_ProductRequirements - Category: Structural Framing
Material: Paveta_bordur; Group: Model Group:River:478153
Pset_BeamCommon - Reference: Beam-173 236799
Pset_QuantityTakeOff - Reference: Beam-173 236799; sets with these values: 2

# IfcBeam: Beam-173 237229:Beam-173 237229, Beam-173
In: 0.UG -3.60
Type - Pset_BeamCommon - IsExternal: no; LoadBearing: yes
Type - Pset_ProductRequirements - Category: Structural Framing
Material: Paveta_bordur; Group: Model Group:River:478153
Pset_BeamCommon - Reference: Beam-173 237229
Pset_QuantityTakeOff - Reference: Beam-173 237229; sets with these values: 2

# IfcBeam: Beam-173 237520:Beam-173 237520, Beam-173
In: 6.EG KH -1.15
Type - Pset_BeamCommon - IsExternal: no; LoadBearing: yes
Type - Pset_ProductRequirements - Category: Structural Framing
Material: Paveta_bordur; Group: Model Group:River:478153
Pset_BeamCommon - Reference: Beam-173 237520
Pset_QuantityTakeOff - Reference: Beam-173 237520; sets with these values: 2

# IfcBeam: Beam-175 236903:Beam-175 236903, Beam-175
In: 0.UG -3.60
Type - Pset_BeamCommon - IsExternal: no; LoadBearing: yes
Type - Pset_ProductRequirements - Category: Structural Framing
Material: Paveta_bordur; Group: Model Group:River:478153
Pset_BeamCommon - Reference: Beam-175 236903
Pset_QuantityTakeOff - Reference: Beam-175 236903; sets with these values: 2

# IfcBeam: Beam-175 237123:Beam-175 237123, Beam-175
In: 0.UG -3.60
Type - Pset_BeamCommon - IsExternal: no; LoadBearing: yes
Type - Pset_ProductRequirements - Category: Structural Framing
Material: Paveta_bordur; Group: Model Group:River:478153
Pset_BeamCommon - Reference: Beam-175 237123
Pset_QuantityTakeOff - Reference: Beam-175 237123; sets with these values: 2

# IfcBeam: Beam-176 (3)
In: 0.UG -3.60
Type - Pset_BeamCommon - IsExternal: no; LoadBearing: yes
Type - Pset_ProductRequirements - Category: Structural Framing
Material: Paveta_bordur; Group: Model Group:River:478153
Pset_QuantityTakeOff - sets with these values: 2
Name | Pset_BeamCommon, Reference = Pset_QuantityTakeOff, Reference
Beam-176:Beam-176:298126 | Beam-176
Beam-176 236697:Beam-176 236697:298335 | Beam-176 236697
Beam-176 236995:Beam-176 236995:298433 | Beam-176 236995

# IfcBeam: Beam-176 228032:Beam-176 228032, Beam-176
In: 0.UG -3.60
Type - Pset_BeamCommon - IsExternal: no; LoadBearing: yes
Type - Pset_ProductRequirements - Category: Structural Framing
Material: Paveta_bordur; Group: Model Group:River:478153
Pset_BeamCommon - Reference: Beam-176 228032
Pset_QuantityTakeOff - Reference: Beam-176 228032; sets with these values: 2

# IfcBeam: Beam-176 237005:Beam-176 237005, Beam-176
In: 0.UG -3.60
Type - Pset_BeamCommon - IsExternal: no; LoadBearing: yes
Type - Pset_ProductRequirements - Category: Structural Framing
Material: Paveta_bordur; Group: Model Group:River:478153
Pset_BeamCommon - Reference: Beam-176 237005
Pset_QuantityTakeOff - Reference: Beam-176 237005; sets with these values: 2

# IfcBeam: Beam-176 237222:Beam-176 237222, Beam-176
In: 0.UG -3.60
Type - Pset_BeamCommon - IsExternal: no; LoadBearing: yes
Type - Pset_ProductRequirements - Category: Structural Framing
Material: Paveta_bordur; Group: Model Group:River:478153
Pset_BeamCommon - Reference: Beam-176 237222
Pset_QuantityTakeOff - Reference: Beam-176 237222; sets with these values: 2

# IfcBeam: Beam-176 237245:Beam-176 237245, Beam-176
In: 0.UG -3.60
Type - Pset_BeamCommon - IsExternal: no; LoadBearing: yes
Type - Pset_ProductRequirements - Category: Structural Framing
Material: Paveta_bordur; Group: Model Group:River:478153
Pset_BeamCommon - Reference: Beam-176 237245
Pset_QuantityTakeOff - Reference: Beam-176 237245; sets with these values: 2

# IfcBeam: Beam-176 237248:Beam-176 237248, Beam-176
In: 0.UG -3.60
Type - Pset_BeamCommon - IsExternal: no; LoadBearing: yes
Type - Pset_ProductRequirements - Category: Structural Framing
Material: Paveta_bordur; Group: Model Group:River:478153
Pset_BeamCommon - Reference: Beam-176 237248
Pset_QuantityTakeOff - Reference: Beam-176 237248; sets with these values: 2

# IfcBeam: Beam-177 (2)
In: 0.UG -3.60
Type - Pset_BeamCommon - IsExternal: no; LoadBearing: yes
Type - Pset_ProductRequirements - Category: Structural Framing
Material: Paveta_bordur; Group: Model Group:River:478153
Pset_QuantityTakeOff - sets with these values: 2
Name | Pset_BeamCommon, Reference = Pset_QuantityTakeOff, Reference
Beam-177:Beam-177:297990 | Beam-177
Beam-177 220085:Beam-177 220085:297997 | Beam-177 220085

# IfcBeam: Beam-177 219159:Beam-177 219159, Beam-177
In: 0.UG -3.60
Type - Pset_BeamCommon - IsExternal: no; LoadBearing: yes
Type - Pset_ProductRequirements - Category: Structural Framing
Material: Paint-01; Group: Model Group:River:478153
Pset_BeamCommon - Reference: Beam-177 219159
Pset_QuantityTakeOff - Reference: Beam-177 219159; sets with these values: 2

# IfcBeam: Beam-177 220075:Beam-177 220075, Beam-177
In: 0.UG -3.60
Type - Pset_BeamCommon - IsExternal: no; LoadBearing: yes
Type - Pset_ProductRequirements - Category: Structural Framing
Material: Paveta_bordur; Group: Model Group:River:478153
Pset_BeamCommon - Reference: Beam-177 220075
Pset_QuantityTakeOff - Reference: Beam-177 220075; sets with these values: 2

# IfcBeam: Beam-177 228364:Beam-177 228364, Beam-177
In: 0.UG -3.60
Type - Pset_BeamCommon - IsExternal: no; LoadBearing: yes
Type - Pset_ProductRequirements - Category: Structural Framing
Material: Paveta_bordur; Group: Model Group:River:478153
Pset_BeamCommon - Reference: Beam-177 228364
Pset_QuantityTakeOff - Reference: Beam-177 228364; sets with these values: 2

# IfcBeam: Beam-177 237234:Beam-177 237234, Beam-177
In: 0.UG -3.60
Type - Pset_BeamCommon - IsExternal: no; LoadBearing: yes
Type - Pset_ProductRequirements - Category: Structural Framing
Material: Paveta_bordur; Group: Model Group:River:478153
Pset_BeamCommon - Reference: Beam-177 237234
Pset_QuantityTakeOff - Reference: Beam-177 237234; sets with these values: 2

# IfcBeam: Beam-178 (2)
In: 0.UG -3.60
Type - Pset_BeamCommon - IsExternal: no; LoadBearing: yes
Type - Pset_ProductRequirements - Category: Structural Framing
Material: Paveta_bordur; Group: Model Group:River:478153
Pset_QuantityTakeOff - sets with these values: 2
Name | Pset_BeamCommon, Reference = Pset_QuantityTakeOff, Reference
Beam-178:Beam-178:288737 | Beam-178
Beam-178 227982:Beam-178 227982:298062 | Beam-178 227982

# IfcBeam: Beam-178 219178:Beam-178 219178, Beam-178
In: 0.UG -3.60
Type - Pset_BeamCommon - IsExternal: no; LoadBearing: yes
Type - Pset_ProductRequirements - Category: Structural Framing
Material: Paveta_bordur; Group: Model Group:River:478153
Pset_BeamCommon - Reference: Beam-178 219178
Pset_QuantityTakeOff - Reference: Beam-178 219178; sets with these values: 2

# IfcBeam: Beam-178 237212:Beam-178 237212, Beam-178
In: 0.UG -3.60
Type - Pset_BeamCommon - IsExternal: no; LoadBearing: yes
Type - Pset_ProductRequirements - Category: Structural Framing
Material: Paveta_bordur; Group: Model Group:River:478153
Pset_BeamCommon - Reference: Beam-178 237212
Pset_QuantityTakeOff - Reference: Beam-178 237212; sets with these values: 2

# IfcBeam: Beam-179, Beam-179:Beam-179:288546
In: 0.UG -3.60
Type - Pset_BeamCommon - IsExternal: no; LoadBearing: yes
Type - Pset_ProductRequirements - Category: Structural Framing
Material: Paveta_bordur; Group: Model Group:River:478153
Pset_BeamCommon - Reference: Beam-179
Pset_QuantityTakeOff - Reference: Beam-179; sets with these values: 2

# IfcBeam: Beam-179 207791:Beam-179 207791, Beam-179
In: 0.UG -3.60
Type - Pset_BeamCommon - IsExternal: no; LoadBearing: yes
Type - Pset_ProductRequirements - Category: Structural Framing
Material: Paveta_bordur; Group: Model Group:River:478153
Pset_BeamCommon - Reference: Beam-179 207791
Pset_QuantityTakeOff - Reference: Beam-179 207791; sets with these values: 2

# IfcBeam: Beam-179 220069:Beam-179 220069, Beam-179
In: 0.UG -3.60
Type - Pset_BeamCommon - IsExternal: no; LoadBearing: yes
Type - Pset_ProductRequirements - Category: Structural Framing
Material: Paveta_bordur; Group: Model Group:River:478153
Pset_BeamCommon - Reference: Beam-179 220069
Pset_QuantityTakeOff - Reference: Beam-179 220069; sets with these values: 2

# IfcBeam: Beam-179 237208:Beam-179 237208, Beam-179
In: 0.UG -3.60
Type - Pset_BeamCommon - IsExternal: no; LoadBearing: yes
Type - Pset_ProductRequirements - Category: Structural Framing
Material: Paveta_bordur; Group: Model Group:River:478153
Pset_BeamCommon - Reference: Beam-179 237208
Pset_QuantityTakeOff - Reference: Beam-179 237208; sets with these values: 2

# IfcBeam: Beam-179 246836:Beam-179 246836, Beam-179
In: 0.UG -3.60
Type - Pset_BeamCommon - IsExternal: no; LoadBearing: yes
Type - Pset_ProductRequirements - Category: Structural Framing
Material: Paveta_bordur; Group: Model Group:River:478153
Pset_BeamCommon - Reference: Beam-179 246836
Pset_QuantityTakeOff - Reference: Beam-179 246836; sets with these values: 2

# IfcBeam: Beam-180 (2)
In: 0.UG -3.60
Type - Pset_BeamCommon - IsExternal: no; LoadBearing: yes
Type - Pset_ProductRequirements - Category: Structural Framing
Material: Paveta_bordur; Group: Model Group:River:478153
Pset_QuantityTakeOff - sets with these values: 2
Name | Pset_BeamCommon, Reference = Pset_QuantityTakeOff, Reference
Beam-180:Beam-180:297947 | Beam-180
Beam-180 228304:Beam-180 228304:298140 | Beam-180 228304

# IfcBeam: Beam-180 208270:Beam-180 208270, Beam-180
In: 0.UG -3.60
Type - Pset_BeamCommon - IsExternal: no; LoadBearing: yes
Type - Pset_ProductRequirements - Category: Structural Framing
Material: Paint-01; Group: Model Group:River:478153
Pset_BeamCommon - Reference: Beam-180 208270
Pset_QuantityTakeOff - Reference: Beam-180 208270; sets with these values: 2

# IfcBeam: Beam-180 246833:Beam-180 246833, Beam-180
In: 0.UG -3.60
Type - Pset_BeamCommon - IsExternal: no; LoadBearing: yes
Type - Pset_ProductRequirements - Category: Structural Framing
Material: Paint-01; Group: Model Group:River:478153
Pset_BeamCommon - Reference: Beam-180 246833
Pset_QuantityTakeOff - Reference: Beam-180 246833; sets with these values: 2

# IfcBeam: Beam-180 57452:Beam-180 57452, Beam-180
In: 6.EG KH -1.15
Type - Pset_BeamCommon - IsExternal: no; LoadBearing: yes
Type - Pset_ProductRequirements - Category: Structural Framing
Material: Paveta_bordur; Group: Model Group:River:478153
Pset_BeamCommon - Reference: Beam-180 57452
Pset_QuantityTakeOff - Reference: Beam-180 57452; sets with these values: 2

# IfcBeam: Beam-181 228290:Beam-181 228290 (3)
In: 3D
Type - Pset_BeamCommon - IsExternal: no; LoadBearing: yes
Type - Pset_ProductRequirements - Category: Structural Framing
Material: Paveta_bordur; Group: Model Group:River:478153
Pset_BeamCommon - Reference: Beam-181 228290
Pset_QuantityTakeOff - Reference: Beam-181 228290; sets with these values: 2
Name
Beam-141
Beam-148
Beam-181

# IfcBeam: Beam-181 236854:Beam-181 236854, Beam-181
In: 0.UG -3.60
Type - Pset_BeamCommon - IsExternal: no; LoadBearing: yes
Type - Pset_ProductRequirements - Category: Structural Framing
Material: Paveta_bordur; Group: Model Group:River:478153
Pset_BeamCommon - Reference: Beam-181 236854
Pset_QuantityTakeOff - Reference: Beam-181 236854; sets with these values: 2

# IfcBeam: Beam-181 237020:Beam-181 237020, Beam-181
In: 0.UG -3.60
Type - Pset_BeamCommon - IsExternal: no; LoadBearing: yes
Type - Pset_ProductRequirements - Category: Structural Framing
Material: Paveta_bordur; Group: Model Group:River:478153
Pset_BeamCommon - Reference: Beam-181 237020
Pset_QuantityTakeOff - Reference: Beam-181 237020; sets with these values: 2

# IfcBeam: Beam-182 237195:Beam-182 237195, Beam-182
In: 0.UG -3.60
Type - Pset_BeamCommon - IsExternal: no; LoadBearing: yes
Type - Pset_ProductRequirements - Category: Structural Framing
Material: Paveta_bordur; Group: Model Group:River:478153
Pset_BeamCommon - Reference: Beam-182 237195
Pset_QuantityTakeOff - Reference: Beam-182 237195; sets with these values: 2

# IfcBeam: Beam-183 237196:Beam-183 237196, Beam-183
In: 0.UG -3.60
Type - Pset_BeamCommon - IsExternal: no; LoadBearing: yes
Type - Pset_ProductRequirements - Category: Structural Framing
Material: Paint-01; Group: Model Group:River:478153
Pset_BeamCommon - Reference: Beam-183 237196
Pset_QuantityTakeOff - Reference: Beam-183 237196; sets with these values: 2

# IfcBeam: Beam-183 237202:Beam-183 237202, Beam-183
In: 0.UG -3.60
Type - Pset_BeamCommon - IsExternal: no; LoadBearing: yes
Type - Pset_ProductRequirements - Category: Structural Framing
Material: Paveta_bordur; Group: Model Group:River:478153
Pset_BeamCommon - Reference: Beam-183 237202
Pset_QuantityTakeOff - Reference: Beam-183 237202; sets with these values: 2

# IfcBeam: Beam-184 237184:Beam-184 237184, Beam-184
In: 0.UG -3.60
Type - Pset_BeamCommon - IsExternal: no; LoadBearing: yes
Type - Pset_ProductRequirements - Category: Structural Framing
Material: Paveta_bordur; Group: Model Group:River:478153
Pset_BeamCommon - Reference: Beam-184 237184
Pset_QuantityTakeOff - Reference: Beam-184 237184; sets with these values: 2

# IfcBeam: Beam-185 208224:Beam-185 208224, Beam-185
In: 0.UG -3.60
Type - Pset_BeamCommon - IsExternal: no; LoadBearing: yes
Type - Pset_ProductRequirements - Category: Structural Framing
Material: Paveta_bordur; Group: Model Group:River:478153
Pset_BeamCommon - Reference: Beam-185 208224
Pset_QuantityTakeOff - Reference: Beam-185 208224; sets with these values: 2

# IfcBeam: Beam-186 237177:Beam-186 237177, Beam-186
In: 0.UG -3.60
Type - Pset_BeamCommon - IsExternal: no; LoadBearing: yes
Type - Pset_ProductRequirements - Category: Structural Framing
Material: Paint-01; Group: Model Group:River:478153
Pset_BeamCommon - Reference: Beam-186 237177
Pset_QuantityTakeOff - Reference: Beam-186 237177; sets with these values: 2

# IfcBeam: Beam-187 237176:Beam-187 237176, Beam-187
In: 0.UG -3.60
Type - Pset_BeamCommon - IsExternal: no; LoadBearing: yes
Type - Pset_ProductRequirements - Category: Structural Framing
Material: Paveta_bordur; Group: Model Group:River:478153
Pset_BeamCommon - Reference: Beam-187 237176
Pset_QuantityTakeOff - Reference: Beam-187 237176; sets with these values: 2

# IfcBuildingElementProxy: Cotterman_Roof_ladder_with_walk-thru_17671:Cotterman_Roof_ladder_with_walk-thru_17671 (2)
Type - Material: <Unnamed>
Type - Pset_ProductRequirements - Category: Generic Models
Pset_BuildingElementProxyCommon - Reference: Cotterman_Roof_ladder_with_walk-thru_17671; sets with these values: 2
Group: Model Group:Building:629362
Name (Cotterman_Roof_ladder_with_walk-thru_17671:Cotterman_Roof_ladder_with_walk-thru_17671:...) | In
624168 | 4.3OG +15.90
624169 | 2.1OG +5.30

# IfcBuildingElementProxy: Eingang_West_1:Eingang_West_1 (2)
In: 1.EG +0.00
Type - Material: <Unnamed>
Type - Pset_ProductRequirements - Category: Generic Models
Pset_BuildingElementProxyCommon - Reference: Eingang_West_1; sets with these values: 2
Group: Model Group:Building:629362
Name (Eingang_West_1:Eingang_West_1:...)
624397
624398

# IfcBuildingElementProxy: Eingang_West_2:Eingang_West_2, Eingang_West_2:Eingang_West_2:624399
In: 1.EG +0.00
Type - Material: Default
Type - Pset_ProductRequirements - Category: Generic Models
Pset_BuildingElementProxyCommon - Reference: Eingang_West_2; sets with these values: 2
Group: Model Group:Building:629362

# IfcBuildingElementProxy: X_BRACE:X_BRACE (18)
Type - Material: Default
Type - Pset_ProductRequirements - Category: Generic Models
Pset_BuildingElementProxyCommon - Reference: X_BRACE; sets with these values: 2
Group: Model Group:Building:629362
Name (X_BRACE:X_BRACE:...) | In
623594 | 1.EG +0.00
623595 | 7.1OG KH +2.65
623596 | 2.1OG +5.30
623597 | 8.2OG KH +6.45
623598 | 9.3OG KH +10.25
623599 | 3.2OG +10.60
623600 | 10.DG KH +14.25
623601 | 4.3OG +15.90
623602 | 4.3OG +15.90
623603 | 1.EG +0.00
623604 | 7.1OG KH +2.65
623605 | 2.1OG +5.30
623606 | 8.2OG KH +6.45
623607 | 9.3OG KH +10.25
623608 | 3.2OG +10.60
623609 | 10.DG KH +14.25
623610 | 4.3OG +15.90
623611 | 4.3OG +15.90

# IfcColumn: Col-036 342654:Col-036 342654 (20)
In: PLAN
Type - PredefinedType: COLUMN; Material: Paint-02.1
Type - Pset_ColumnCommon - IsExternal: no
Type - Pset_ProductRequirements - Category: Columns
Pset_ColumnCommon - Reference: Col-036 342654
Pset_QuantityTakeOff - Reference: Col-036 342654; sets with these values: 2
Group: Model Group:River:478153

# IfcColumn: Col-042 216947:Col-042 216947 (9)
In: 3D
Type - PredefinedType: COLUMN; Material: _parapet_dark
Type - Pset_ColumnCommon - IsExternal: no
Type - Pset_ProductRequirements - Category: Columns
Pset_ColumnCommon - Reference: Col-042 216947
Pset_QuantityTakeOff - Reference: Col-042 216947; sets with these values: 2
Group: Model Group:River:478153

# IfcColumn: Col-045 246663:Col-045 246663, Col-045
In: 1.EG +0.00
Type - PredefinedType: COLUMN; Material: _parapet_dark
Type - Pset_ColumnCommon - IsExternal: no
Type - Pset_ProductRequirements - Category: Columns
Pset_ColumnCommon - Reference: Col-045 246663
Pset_QuantityTakeOff - Reference: Col-045 246663; sets with these values: 2
Group: Model Group:River:478153

# IfcColumn: Columns_Rectangular:130x80 (2)
Type - PredefinedType: COLUMN; Material: <Unnamed>, Analytical Wall Surface_CJC
Type - Pset_ColumnCommon - IsExternal: no
Type - Pset_ProductRequirements - Category: Columns
Material: Analytical Wall Surface_CJC; Group: Model Group:Building:629362
Pset_ColumnCommon - Reference: 130x80
Pset_QuantityTakeOff - Reference: 130x80; sets with these values: 2
Name (Columns_Rectangular:130x80:...) | In
619180 | 2.1OG +5.30
619877 | 3.2OG +10.60

# IfcColumn: Columns_Rectangular:130x80 (3)
Type - PredefinedType: COLUMN; Material: Analytical Wall Surface_CJC
Type - Pset_ColumnCommon - IsExternal: no
Type - Pset_ProductRequirements - Category: Columns
Pset_ColumnCommon - Reference: 130x80
Pset_QuantityTakeOff - Reference: 130x80; sets with these values: 2
Group: Model Group:Building:629362
Name (Columns_Rectangular:130x80:...) | In
618235 | 1.EG +0.00
618252 | 1.EG +0.00
620801 | 4.3OG +15.90

# IfcColumn: Columns_Rectangular:37.75x50, Columns_Rectangular:37.75x50:621834
In: 1.EG +0.00
Type - PredefinedType: COLUMN; Material: Analytical Wall Surface_CJC
Type - Pset_ColumnCommon - IsExternal: no
Type - Pset_ProductRequirements - Category: Columns
Pset_ColumnCommon - Reference: 37.75x50
Pset_QuantityTakeOff - Reference: 37.75x50; sets with these values: 2
Group: Model Group:Building:629362

# IfcColumn: Columns_Rectangular:37x40, Columns_Rectangular:37x40:621880
In: 6.EG KH -1.15
Type - PredefinedType: COLUMN; Material: Analytical Wall Surface_CJC
Type - Pset_ColumnCommon - IsExternal: no
Type - Pset_ProductRequirements - Category: Columns
Pset_ColumnCommon - Reference: 37x40
Pset_QuantityTakeOff - Reference: 37x40; sets with these values: 2
Group: Model Group:Building:629362

# IfcColumn: Columns_Rectangular:45x35 (13)
In: 4.3OG +15.90
Type - PredefinedType: COLUMN; Material: <Unnamed>, Analytical Wall Surface_CJC
Type - Pset_ColumnCommon - IsExternal: no
Type - Pset_ProductRequirements - Category: Columns
Material: Analytical Wall Surface_CJC; Group: Model Group:Building:629362
Pset_ColumnCommon - Reference: 45x35
Pset_QuantityTakeOff - Reference: 45x35; sets with these values: 2
Name (Columns_Rectangular:45x35:...)
620681
620698
620699
620700
620703
620718
620720
620721
620722
620723
620724
620729
621140

# IfcColumn: Columns_Rectangular:45x35 (11)
In: 4.3OG +15.90
Type - PredefinedType: COLUMN; Material: Analytical Wall Surface_CJC
Type - Pset_ColumnCommon - IsExternal: no
Type - Pset_ProductRequirements - Category: Columns
Pset_ColumnCommon - Reference: 45x35
Pset_QuantityTakeOff - Reference: 45x35; sets with these values: 2
Group: Model Group:Building:629362
Name (Columns_Rectangular:45x35:...)
620677
620678
620679
620680
620683
620684
620701
620702
620725
620726
620727

# IfcColumn: Columns_Rectangular:50x55 (4)
Type - PredefinedType: COLUMN; Material: <Unnamed>, Analytical Wall Surface_CJC
Type - Pset_ColumnCommon - IsExternal: no
Type - Pset_ProductRequirements - Category: Columns
Material: Analytical Wall Surface_CJC; Group: Model Group:Building:629362
Pset_ColumnCommon - Reference: 50x55
Pset_QuantityTakeOff - Reference: 50x55; sets with these values: 2
Name (Columns_Rectangular:50x55:...) | In
621704 | 1.EG +0.00
621870 | 7.1OG KH +2.65
622219 | 8.2OG KH +6.45
622314 | 9.3OG KH +10.25

# IfcColumn: Columns_Rectangular:55x55 (8)
Type - PredefinedType: COLUMN; Material: <Unnamed>, Analytical Wall Surface_CJC
Type - Pset_ColumnCommon - IsExternal: no
Type - Pset_ProductRequirements - Category: Columns
Material: Analytical Wall Surface_CJC; Group: Model Group:Building:629362
Pset_ColumnCommon - Reference: 55x55
Pset_QuantityTakeOff - Reference: 55x55; sets with these values: 2
Name (Columns_Rectangular:55x55:...) | In
621702 | 1.EG +0.00
621703 | 1.EG +0.00
621868 | 7.1OG KH +2.65
621869 | 7.1OG KH +2.65
622217 | 8.2OG KH +6.45
622218 | 8.2OG KH +6.45
622312 | 9.3OG KH +10.25
622313 | 9.3OG KH +10.25

# IfcColumn: Columns_Rectangular:65x35 (13)
In: 3.2OG +10.60
Type - PredefinedType: COLUMN; Material: <Unnamed>, Analytical Wall Surface_CJC
Type - Pset_ColumnCommon - IsExternal: no
Type - Pset_ProductRequirements - Category: Columns
Material: Analytical Wall Surface_CJC; Group: Model Group:Building:629362
Pset_ColumnCommon - Reference: 65x35
Pset_QuantityTakeOff - Reference: 65x35; sets with these values: 2
Name (Columns_Rectangular:65x35:...)
619741
619742
619745
619760
619761
619762
619763
619764
619765
619782
619783
619784
619785

# IfcColumn: Columns_Rectangular:65x35 (10)
In: 3.2OG +10.60
Type - PredefinedType: COLUMN; Material: Analytical Wall Surface_CJC
Type - Pset_ColumnCommon - IsExternal: no
Type - Pset_ProductRequirements - Category: Columns
Pset_ColumnCommon - Reference: 65x35
Pset_QuantityTakeOff - Reference: 65x35; sets with these values: 2
Group: Model Group:Building:629362
Name (Columns_Rectangular:65x35:...)
619739
619740
619743
619746
619780
619786
619787
619788
619789
619804

# IfcColumn: Columns_Rectangular:65x45, Columns_Rectangular:65x45:620728
In: 4.3OG +15.90
Type - PredefinedType: COLUMN; Material: <Unnamed>, Analytical Wall Surface_CJC
Type - Pset_ColumnCommon - IsExternal: no
Type - Pset_ProductRequirements - Category: Columns
Material: Analytical Wall Surface_CJC; Group: Model Group:Building:629362
Pset_ColumnCommon - Reference: 65x45
Pset_QuantityTakeOff - Reference: 65x45; sets with these values: 2

# IfcColumn: Columns_Rectangular:65x45, Columns_Rectangular:65x45:622528
In: 0.UG -3.60
Type - PredefinedType: COLUMN; Material: Analytical Wall Surface_CJC
Type - Pset_ColumnCommon - IsExternal: no
Type - Pset_ProductRequirements - Category: Columns
Pset_ColumnCommon - Reference: 65x45
Pset_QuantityTakeOff - Reference: 65x45; sets with these values: 2
Group: Model Group:Building:629362

# IfcColumn: Columns_Rectangular:65x65 (2)
Type - PredefinedType: COLUMN; Material: <Unnamed>, Analytical Wall Surface_CJC
Type - Pset_ColumnCommon - IsExternal: no
Type - Pset_ProductRequirements - Category: Columns
Material: Analytical Wall Surface_CJC; Group: Model Group:Building:629362
Pset_ColumnCommon - Reference: 65x65
Pset_QuantityTakeOff - Reference: 65x65; sets with these values: 2
Name (Columns_Rectangular:65x65:...) | In
619790 | 3.2OG +10.60
620719 | 4.3OG +15.90

# IfcColumn: Columns_Rectangular:65x65, Columns_Rectangular:65x65:619781
In: 3.2OG +10.60
Type - PredefinedType: COLUMN; Material: Analytical Wall Surface_CJC
Type - Pset_ColumnCommon - IsExternal: no
Type - Pset_ProductRequirements - Category: Columns
Pset_ColumnCommon - Reference: 65x65
Pset_QuantityTakeOff - Reference: 65x65; sets with these values: 2
Group: Model Group:Building:629362

# IfcColumn: Columns_Rectangular:67.5x30 (6)
Type - PredefinedType: COLUMN; Material: <Unnamed>
Type - Pset_ColumnCommon - IsExternal: no
Type - Pset_ProductRequirements - Category: Columns
Pset_ColumnCommon - Reference: 67.5x30
Pset_QuantityTakeOff - Reference: 67.5x30; sets with these values: 2
Group: Model Group:Building:629362
Name (Columns_Rectangular:67.5x30:...) | In
618168 | 1.EG +0.00
618169 | 1.EG +0.00
619129 | 2.1OG +5.30
619130 | 2.1OG +5.30
619826 | 3.2OG +10.60
619827 | 3.2OG +10.60

# IfcColumn: Columns_Rectangular:67.5x30 (4)
Type - PredefinedType: COLUMN; Material: <Unnamed>, Analytical Wall Surface_CJC
Type - Pset_ColumnCommon - IsExternal: no
Type - Pset_ProductRequirements - Category: Columns
Material: Analytical Wall Surface_CJC; Group: Model Group:Building:629362
Pset_ColumnCommon - Reference: 67.5x30
Pset_QuantityTakeOff - Reference: 67.5x30; sets with these values: 2
Name (Columns_Rectangular:67.5x30:...) | In
620750 | 4.3OG +15.90
620751 | 4.3OG +15.90
623075 | 0.UG -3.60
623076 | 0.UG -3.60

# IfcColumn: Columns_Rectangular:67.5x35 (4)
Type - PredefinedType: COLUMN; Material: <Unnamed>, Analytical Wall Surface_CJC
Type - Pset_ColumnCommon - IsExternal: no
Type - Pset_ProductRequirements - Category: Columns
Material: Analytical Wall Surface_CJC; Group: Model Group:Building:629362
Pset_ColumnCommon - Reference: 67.5x35
Pset_QuantityTakeOff - Reference: 67.5x35; sets with these values: 2
Name (Columns_Rectangular:67.5x35:...) | In
618170 | 1.EG +0.00
619131 | 2.1OG +5.30
619828 | 3.2OG +10.60
623077 | 0.UG -3.60

# IfcColumn: Columns_Rectangular:67.5x35 (6)
Type - PredefinedType: COLUMN; Material: Analytical Wall Surface_CJC
Type - Pset_ColumnCommon - IsExternal: no
Type - Pset_ProductRequirements - Category: Columns
Pset_ColumnCommon - Reference: 67.5x35
Pset_QuantityTakeOff - Reference: 67.5x35; sets with these values: 2
Group: Model Group:Building:629362
Name (Columns_Rectangular:67.5x35:...) | In
618167 | 1.EG +0.00
619128 | 2.1OG +5.30
619825 | 3.2OG +10.60
620749 | 4.3OG +15.90
620752 | 4.3OG +15.90
623074 | 0.UG -3.60

# IfcColumn: Columns_Rectangular:70x70, Columns_Rectangular:70x70:618245
In: 1.EG +0.00
Type - PredefinedType: COLUMN; Material: Analytical Wall Surface_CJC
Type - Pset_ColumnCommon - IsExternal: no
Type - Pset_ProductRequirements - Category: Columns
Pset_ColumnCommon - Reference: 70x70
Pset_QuantityTakeOff - Reference: 70x70; sets with these values: 2
Group: Model Group:Building:629362

# IfcColumn: Columns_Rectangular:75x35, Columns_Rectangular:75x35:620232
In: 3.2OG +10.60
Type - PredefinedType: COLUMN; Material: Analytical Wall Surface_CJC
Type - Pset_ColumnCommon - IsExternal: no
Type - Pset_ProductRequirements - Category: Columns
Pset_ColumnCommon - Reference: 75x35
Pset_QuantityTakeOff - Reference: 75x35; sets with these values: 2
Group: Model Group:Building:629362

# IfcColumn: Columns_Rectangular:80x40 (7)
In: 2.1OG +5.30
Type - PredefinedType: COLUMN; Material: <Unnamed>, Analytical Wall Surface_CJC
Type - Pset_ColumnCommon - IsExternal: no
Type - Pset_ProductRequirements - Category: Columns
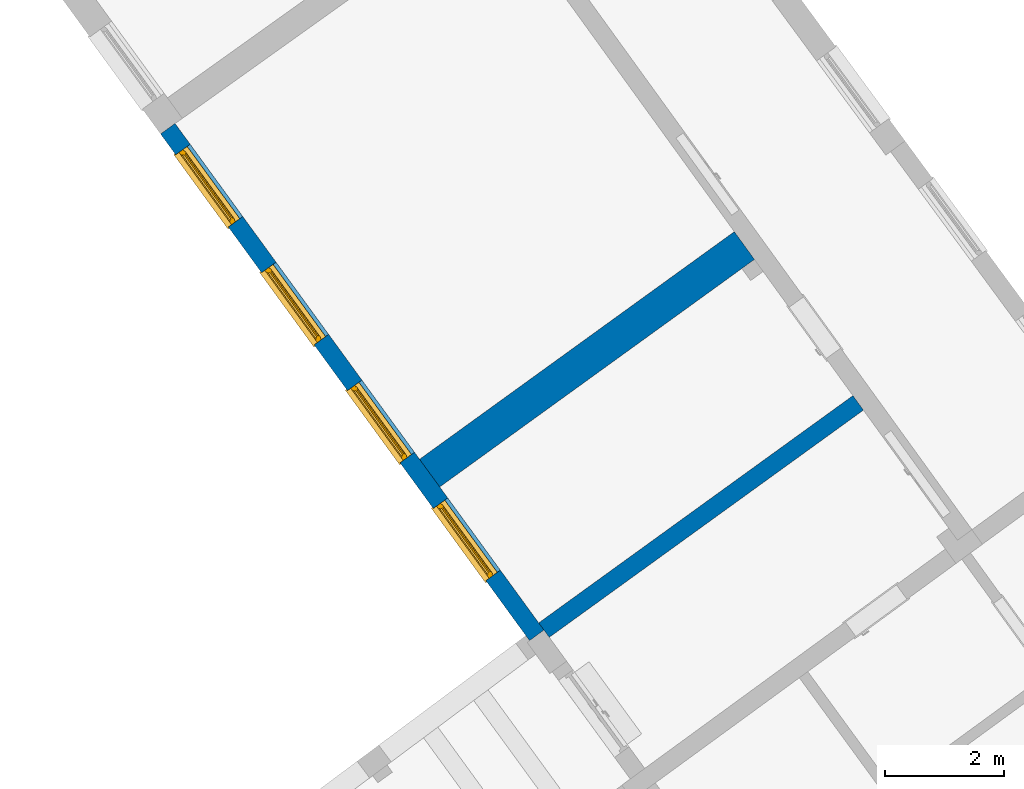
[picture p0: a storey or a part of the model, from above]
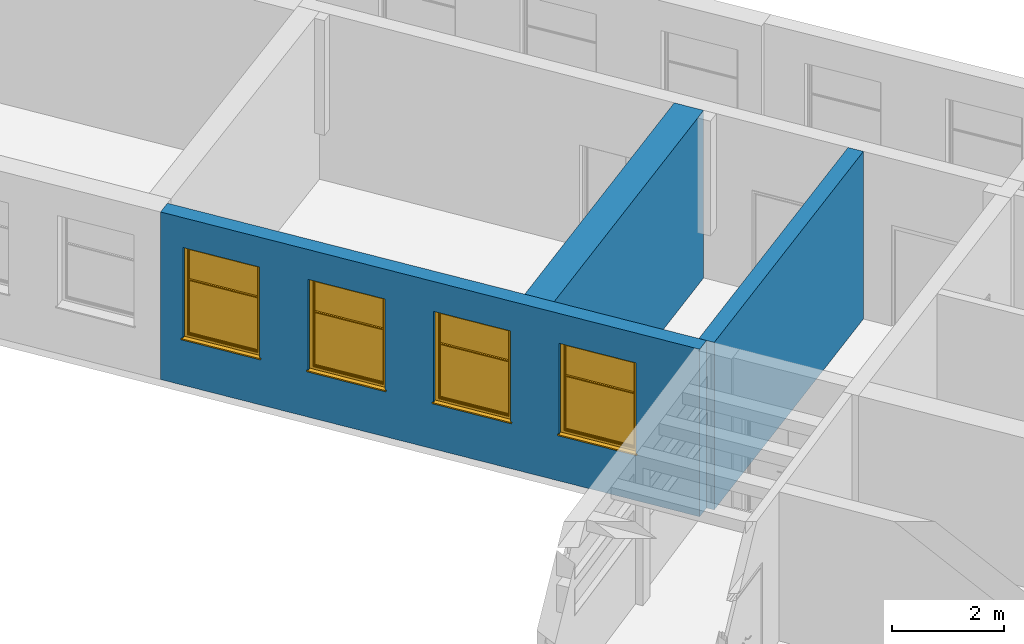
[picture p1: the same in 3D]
Properties of the parts of a building model (IFC2X3), part 3 of 13

# IfcColumn: Columns_Rectangular:80x40 (7)
Material: Analytical Wall Surface_CJC; Group: Model Group:Building:629362
Pset_ColumnCommon - Reference: 80x40
Pset_QuantityTakeOff - Reference: 80x40; sets with these values: 2
Name (Columns_Rectangular:80x40:...)
618859
618861
618862
618863
618864
618953
619087

# IfcColumn: Columns_Rectangular:80x40 (17)
In: 2.1OG +5.30
Type - PredefinedType: COLUMN; Material: Analytical Wall Surface_CJC
Type - Pset_ColumnCommon - IsExternal: no
Type - Pset_ProductRequirements - Category: Columns
Pset_ColumnCommon - Reference: 80x40
Pset_QuantityTakeOff - Reference: 80x40; sets with these values: 2
Group: Model Group:Building:629362
Name (Columns_Rectangular:80x40:...)
618799
618800
618801
618802
618803
618843
618844
618860
618951
618954
618955
618956
618957
618958
618959
618960
619595

# IfcColumn: Columns_Rectangular:80x70 (5)
Type - PredefinedType: COLUMN; Material: Analytical Wall Surface_CJC
Type - Pset_ColumnCommon - IsExternal: no
Type - Pset_ProductRequirements - Category: Columns
Pset_ColumnCommon - Reference: 80x70
Pset_QuantityTakeOff - Reference: 80x70; sets with these values: 2
Group: Model Group:Building:629362
Name (Columns_Rectangular:80x70:...) | In
618952 | 2.1OG +5.30
618961 | 2.1OG +5.30
619173 | 2.1OG +5.30
619870 | 3.2OG +10.60
620794 | 4.3OG +15.90

# IfcColumn: Columns_Rectangular:90x45, Columns_Rectangular:90x45:619604
In: 2.1OG +5.30
Type - PredefinedType: COLUMN; Material: Analytical Wall Surface_CJC
Type - Pset_ColumnCommon - IsExternal: no
Type - Pset_ProductRequirements - Category: Columns
Pset_ColumnCommon - Reference: 90x45
Pset_QuantityTakeOff - Reference: 90x45; sets with these values: 2
Group: Model Group:Building:629362

# IfcColumn: Columns_Rectangular:90x50 (4)
In: 1.EG +0.00
Type - PredefinedType: COLUMN; Material: <Unnamed>, Analytical Wall Surface_CJC
Type - Pset_ColumnCommon - IsExternal: no
Type - Pset_ProductRequirements - Category: Columns
Material: Analytical Wall Surface_CJC; Group: Model Group:Building:629362
Pset_ColumnCommon - Reference: 90x50
Pset_QuantityTakeOff - Reference: 90x50; sets with these values: 2
Name (Columns_Rectangular:90x50:...)
617838
617840
617841
617951

# IfcColumn: Columns_Rectangular:90x50 (19)
In: 1.EG +0.00
Type - PredefinedType: COLUMN; Material: Analytical Wall Surface_CJC
Type - Pset_ColumnCommon - IsExternal: no
Type - Pset_ProductRequirements - Category: Columns
Pset_ColumnCommon - Reference: 90x50
Pset_QuantityTakeOff - Reference: 90x50; sets with these values: 2
Group: Model Group:Building:629362
Name (Columns_Rectangular:90x50:...)
617742
617743
617744
617745
617746
617816
617817
617836
617837
617839
617947
617949
617950
617952
617953
617954
617955
617956
618090

# IfcColumn: Columns_Rectangular:90x65 (4)
In: 0.UG -3.60
Type - PredefinedType: COLUMN; Material: <Unnamed>, Analytical Wall Surface_CJC
Type - Pset_ColumnCommon - IsExternal: no
Type - Pset_ProductRequirements - Category: Columns
Material: Analytical Wall Surface_CJC; Group: Model Group:Building:629362
Pset_ColumnCommon - Reference: 90x65
Pset_QuantityTakeOff - Reference: 90x65; sets with these values: 2
Name (Columns_Rectangular:90x65:...)
622541
622542
622543
622561

# IfcColumn: Columns_Rectangular:90x65 (7)
In: 0.UG -3.60
Type - PredefinedType: COLUMN; Material: Analytical Wall Surface_CJC
Type - Pset_ColumnCommon - IsExternal: no
Type - Pset_ProductRequirements - Category: Columns
Pset_ColumnCommon - Reference: 90x65
Pset_QuantityTakeOff - Reference: 90x65; sets with these values: 2
Group: Model Group:Building:629362
Name (Columns_Rectangular:90x65:...)
622533
622534
622535
622536
622537
622538
622539

# IfcColumn: Columns_Rectangular:90x80 (3)
In: 1.EG +0.00
Type - PredefinedType: COLUMN; Material: Analytical Wall Surface_CJC
Type - Pset_ColumnCommon - IsExternal: no
Type - Pset_ProductRequirements - Category: Columns
Pset_ColumnCommon - Reference: 90x80
Pset_QuantityTakeOff - Reference: 90x80; sets with these values: 2
Group: Model Group:Building:629362
Name (Columns_Rectangular:90x80:...)
617948
617957
618236

# IfcColumn: Columns_Rectangular:95x65 (10)
In: 0.UG -3.60
Type - PredefinedType: COLUMN; Material: Analytical Wall Surface_CJC
Type - Pset_ColumnCommon - IsExternal: no
Type - Pset_ProductRequirements - Category: Columns
Pset_ColumnCommon - Reference: 95x65
Pset_QuantityTakeOff - Reference: 95x65; sets with these values: 2
Group: Model Group:Building:629362
Name (Columns_Rectangular:95x65:...)
622522
622523
622524
622525
622526
622527
622529
622530
622531
622532

# IfcCovering: Compound Ceiling:600x600mm_Grid (4)
In: 4.3OG +15.90
Type - PredefinedType: CEILING
Type - Pset_CoveringCommon - TotalThickness: 52 mm
Type - Pset_ElementShading - Roughness: 914.4 mm
Type - Pset_ProductRequirements - Category: Ceilings
Material: Default 36 mm, Ceiling Tile 600 x 600 16 mm; Group: Model Group:Building:629362
Pset_CoveringCommon - Reference: 600x600mm_Grid; Finish: Ceiling Tile 600 x 600;
Pset_QuantityTakeOff - Reference: 600x600mm_Grid
Name (Compound Ceiling:600x600mm_Grid:...)
625589
625616
625777
626034

# IfcCovering: Compound Ceiling:Plain, Compound Ceiling:Plain:627473
In: 2.1OG +5.30
Type - PredefinedType: CEILING
Type - Pset_CoveringCommon - TotalThickness: 57 mm
Type - Pset_ElementShading - Roughness: 914.4 mm
Type - Pset_ProductRequirements - Category: Ceilings
Material: Metal Stud Layer 45 mm, Gypsum Wall Board 12 mm; Group: Model Group:Building:629362
Pset_CoveringCommon - Reference: Plain; sets with these values: 2

# IfcCurtainWall: Curtain Wall:Curtain_Wall_CJC (2)
In: 1.EG +0.00
Type - Pset_CurtainWallCommon - IsExternal: yes
Type - Pset_ProductRequirements - Category: Walls
Pset_CurtainWallCommon - Reference: Curtain_Wall_CJC
Pset_QuantityTakeOff - Reference: Curtain_Wall_CJC
Group: Model Group:Building:629362
Name (Curtain Wall:Curtain_Wall_CJC:...)
618355
618425

# IfcCurtainWall: Curtain Wall:Curtain_Wall_CJC 2, Curtain Wall:Curtain_Wall_CJC 2:618390
In: 1.EG +0.00
Type - Pset_CurtainWallCommon - IsExternal: yes
Type - Pset_ProductRequirements - Category: Walls
Pset_CurtainWallCommon - Reference: Curtain_Wall_CJC 2
Pset_QuantityTakeOff - Reference: Curtain_Wall_CJC 2
Group: Model Group:Building:629362

# IfcCurtainWall: Curtain Wall:Curtain_Wall_CJC_ENTR1 (2)
In: 1.EG +0.00
Type - Pset_CurtainWallCommon - IsExternal: yes
Type - Pset_ProductRequirements - Category: Walls
Pset_CurtainWallCommon - Reference: Curtain_Wall_CJC_ENTR1
Pset_QuantityTakeOff - Reference: Curtain_Wall_CJC_ENTR1
Group: Model Group:Building:629362
Name (Curtain Wall:Curtain_Wall_CJC_ENTR1:...)
618663
618771

# IfcCurtainWall: Curtain Wall:Curtain_Wall_CJC_ENTR_KH, Curtain Wall:Curtain_Wall_CJC_ENTR_KH:622079
In: 6.EG KH -1.15
Type - Pset_CurtainWallCommon - IsExternal: yes
Type - Pset_ProductRequirements - Category: Walls
Pset_CurtainWallCommon - Reference: Curtain_Wall_CJC_ENTR_KH
Pset_QuantityTakeOff - Reference: Curtain_Wall_CJC_ENTR_KH
Group: Model Group:Building:629362

# IfcCurtainWall: Curtain Wall:Curtain_Wall_CJC_Int (12)
Type - Pset_CurtainWallCommon - IsExternal: no
Type - Pset_ProductRequirements - Category: Walls
Pset_CurtainWallCommon - Reference: Curtain_Wall_CJC_Int
Pset_QuantityTakeOff - Reference: Curtain_Wall_CJC_Int
Group: Model Group:Building:629362
Name (Curtain Wall:Curtain_Wall_CJC_Int:...) | In
624460 | 4.3OG +15.90
624486 | 4.3OG +15.90
624511 | 4.3OG +15.90
624537 | 4.3OG +15.90
624563 | 4.3OG +15.90
626517 | 2.1OG +5.30
626668 | 2.1OG +5.30
626689 | 2.1OG +5.30
626720 | 2.1OG +5.30
626751 | 2.1OG +5.30
627528 | 2.1OG +5.30
627658 | 2.1OG +5.30

# IfcCurtainWall: Curtain Wall:Curtain_Wall_CJC_Int2 (4)
In: 4.3OG +15.90
Type - Pset_CurtainWallCommon - IsExternal: no
Type - Pset_ProductRequirements - Category: Walls
Pset_CurtainWallCommon - Reference: Curtain_Wall_CJC_Int2
Pset_QuantityTakeOff - Reference: Curtain_Wall_CJC_Int2
Group: Model Group:Building:629362
Name (Curtain Wall:Curtain_Wall_CJC_Int2:...)
621555
621556
621557
625129

# IfcCurtainWall: Curtain Wall:Curtain_Wall_CJC_Int3 (2)
In: 4.3OG +15.90
Type - Pset_CurtainWallCommon - IsExternal: no
Type - Pset_ProductRequirements - Category: Walls
Pset_CurtainWallCommon - Reference: Curtain_Wall_CJC_Int3
Pset_QuantityTakeOff - Reference: Curtain_Wall_CJC_Int3
Group: Model Group:Building:629362
Name (Curtain Wall:Curtain_Wall_CJC_Int3:...)
625660
625707

# IfcCurtainWall: Curtain Wall:Curtain_Wall_CJC_Int4 (5)
In: 4.3OG +15.90
Type - Pset_CurtainWallCommon - IsExternal: no
Type - Pset_ProductRequirements - Category: Walls
Pset_CurtainWallCommon - Reference: Curtain_Wall_CJC_Int4
Pset_QuantityTakeOff - Reference: Curtain_Wall_CJC_Int4
Group: Model Group:Building:629362
Name (Curtain Wall:Curtain_Wall_CJC_Int4:...)
625881
625912
625943
625971
626002

# IfcCurtainWall: Curtain Wall:Curtain_Wall_CJC_Int5 (28)
Type - Pset_CurtainWallCommon - IsExternal: no
Type - Pset_ProductRequirements - Category: Walls
Pset_CurtainWallCommon - Reference: Curtain_Wall_CJC_Int5
Pset_QuantityTakeOff - Reference: Curtain_Wall_CJC_Int5
Group: Model Group:Building:629362
Name (Curtain Wall:Curtain_Wall_CJC_Int5:...) | In
617902 | 1.EG +0.00
617903 | 1.EG +0.00
617922 | 1.EG +0.00
618140 | 1.EG +0.00
618238 | 1.EG +0.00
626063 | 3.2OG +10.60
626084 | 3.2OG +10.60
626105 | 3.2OG +10.60
626208 | 3.2OG +10.60
626229 | 3.2OG +10.60
626250 | 3.2OG +10.60
626313 | 3.2OG +10.60
626338 | 3.2OG +10.60
626388 | 3.2OG +10.60
626414 | 3.2OG +10.60
626439 | 3.2OG +10.60
627861 | 2.1OG +5.30
627910 | 2.1OG +5.30
627957 | 2.1OG +5.30
628006 | 2.1OG +5.30
628041 | 2.1OG +5.30
628076 | 2.1OG +5.30
628365 | 1.EG +0.00
628568 | 1.EG +0.00
628569 | 1.EG +0.00
628713 | 1.EG +0.00
628740 | 1.EG +0.00
628755 | 1.EG +0.00

# IfcDoor: Doors_IntSgl:100x190, Doors_IntSgl:100x190:623334
In: 6.EG KH -1.15
Type - OperationType: SINGLE_SWING_RIGHT; ParameterTakesPrecedence: no; Sizeable: no; Material: Door - Handle, Door - Panel, Door - Architrave, Door - Frame/Mullion (1)
Type - Doors_IntSgl:100x190:623334:1 - PanelOperation: SWINGING
Type - Pset_DoorCommon - IsExternal: no
Type - Pset_ManufacturerTypeInformation - Manufacturer: Revit
Type - Pset_ProductRequirements - Category: Doors
OverallHeight: 1900 mm; OverallWidth: 1080 mm; Group: Model Group:Building:629362
Pset_DoorCommon - Reference: 100x190
Pset_QuantityTakeOff - Reference: 100x190

# IfcDoor: Doors_IntSgl:100x200 (3)
Type - OperationType: SINGLE_SWING_LEFT; ParameterTakesPrecedence: no; Sizeable: no; Material: Door - Handle, Door - Panel, Door - Architrave, Door - Frame/Mullion (1)
Type - Doors_IntSgl:100x200:619669:1 - PanelOperation: SWINGING
Type - Pset_DoorCommon - IsExternal: no
Type - Pset_ManufacturerTypeInformation - Manufacturer: Revit
Type - Pset_ProductRequirements - Category: Doors
OverallHeight: 2050 mm; OverallWidth: 1080 mm; Group: Model Group:Building:629362
Pset_DoorCommon - Reference: 100x200
Pset_QuantityTakeOff - Reference: 100x200
Name (Doors_IntSgl:100x200:...) | In
619669 | 2.1OG +5.30
620288 | 3.2OG +10.60
621194 | 4.3OG +15.90

# IfcDoor: Doors_IntSgl:100x200 (12)
Type - OperationType: SINGLE_SWING_RIGHT; ParameterTakesPrecedence: no; Sizeable: no; Material: Door - Handle, Door - Panel, Door - Architrave, Door - Frame/Mullion (1)
Type - Doors_IntSgl:100x200:619659:1 - PanelOperation: SWINGING
Type - Pset_DoorCommon - IsExternal: no
Type - Pset_ManufacturerTypeInformation - Manufacturer: Revit
Type - Pset_ProductRequirements - Category: Doors
OverallHeight: 2050 mm; OverallWidth: 1080 mm; Group: Model Group:Building:629362
Pset_DoorCommon - Reference: 100x200
Pset_QuantityTakeOff - Reference: 100x200
Name (Doors_IntSgl:100x200:...) | In
619659 | 2.1OG +5.30
619667 | 2.1OG +5.30
619668 | 2.1OG +5.30
620278 | 3.2OG +10.60
620286 | 3.2OG +10.60
620287 | 3.2OG +10.60
620660 | 2.1OG +5.30
620661 | 3.2OG +10.60
621184 | 4.3OG +15.90
621192 | 4.3OG +15.90
621193 | 4.3OG +15.90
621496 | 4.3OG +15.90

# IfcDoor: Doors_IntSgl:100x210 (44)
Type - OperationType: SINGLE_SWING_LEFT; ParameterTakesPrecedence: no; Sizeable: no; Material: Door - Handle, Door - Panel, Door - Architrave, Door - Frame/Mullion (1)
Type - Doors_IntSgl:100x210:618460:1 - PanelOperation: SWINGING
Type - Pset_DoorCommon - IsExternal: no
Type - Pset_ManufacturerTypeInformation - Manufacturer: Revit
Type - Pset_ProductRequirements - Category: Doors
OverallHeight: 2150 mm; OverallWidth: 1080 mm; Group: Model Group:Building:629362
Pset_DoorCommon - Reference: 100x210
Pset_QuantityTakeOff - Reference: 100x210
Name (Doors_IntSgl:100x210:...) | In
618460 | 1.EG +0.00
618518 | 1.EG +0.00
618519 | 1.EG +0.00
618548 | 1.EG +0.00
618556 | 1.EG +0.00
619584 | 2.1OG +5.30
619640 | 2.1OG +5.30
619662 | 2.1OG +5.30
619666 | 2.1OG +5.30
620217 | 3.2OG +10.60
620260 | 3.2OG +10.60
620281 | 3.2OG +10.60
620285 | 3.2OG +10.60
620873 | 4.3OG +15.90
621125 | 4.3OG +15.90
621127 | 4.3OG +15.90
621166 | 4.3OG +15.90
621187 | 4.3OG +15.90
621191 | 4.3OG +15.90
621599 | 4.3OG +15.90
621905 | 7.1OG KH +2.65
621908 | 7.1OG KH +2.65
622180 | 6.EG KH -1.15
622199 | 7.1OG KH +2.65
622239 | 8.2OG KH +6.45
622243 | 8.2OG KH +6.45
622246 | 8.2OG KH +6.45
622362 | 9.3OG KH +10.25
622364 | 9.3OG KH +10.25
622366 | 9.3OG KH +10.25
623095 | 0.UG -3.60
623096 | 0.UG -3.60
623098 | 0.UG -3.60
623100 | 0.UG -3.60
623104 | 0.UG -3.60
623111 | 0.UG -3.60
623114 | 0.UG -3.60
623115 | 0.UG -3.60
623118 | 0.UG -3.60
623120 | 0.UG -3.60
623123 | 0.UG -3.60
623124 | 0.UG -3.60
623179 | 0.UG -3.60
623180 | 0.UG -3.60

# IfcDoor: Doors_IntSgl:100x210, Doors_IntSgl:100x210:618558
In: 1.EG +0.00
Type - OperationType: SINGLE_SWING_LEFT; ParameterTakesPrecedence: no; Sizeable: no; Material: Door - Handle, Door - Panel, Door - Architrave, Door - Frame/Mullion (1)
Type - Doors_IntSgl:100x210:618558:1 - PanelOperation: SWINGING
Type - Pset_DoorCommon - IsExternal: no
Type - Pset_ManufacturerTypeInformation - Manufacturer: Revit
Type - Pset_ProductRequirements - Category: Doors
OverallHeight: 2150 mm; OverallWidth: 1080 mm; Group: Model Group:Building:629362
Pset_DoorCommon - Reference: 100x210
Pset_QuantityTakeOff - Reference: 100x210

# IfcDoor: Doors_IntSgl:100x210, Doors_IntSgl:100x210:621562
In: 4.3OG +15.90
Type - OperationType: SINGLE_SWING_LEFT; ParameterTakesPrecedence: no; Sizeable: no; Material: Door - Handle, Door - Panel, Door - Architrave, Door - Frame/Mullion (1)
Type - Doors_IntSgl:100x210:621562:1 - PanelOperation: SWINGING
Type - Pset_DoorCommon - IsExternal: no
Type - Pset_ManufacturerTypeInformation - Manufacturer: Revit
Type - Pset_ProductRequirements - Category: Doors
OverallHeight: 2150 mm; OverallWidth: 1080 mm; Group: Model Group:Building:629362
Pset_DoorCommon - Reference: 100x210
Pset_QuantityTakeOff - Reference: 100x210

# IfcDoor: Doors_IntSgl:100x210, Doors_IntSgl:100x210:621903
In: 7.1OG KH +2.65
Type - OperationType: SINGLE_SWING_LEFT; ParameterTakesPrecedence: no; Sizeable: no; Material: Door - Handle, Door - Panel, Door - Architrave, Door - Frame/Mullion (1)
Type - Doors_IntSgl:100x210:621903:1 - PanelOperation: SWINGING
Type - Pset_DoorCommon - IsExternal: no
Type - Pset_ManufacturerTypeInformation - Manufacturer: Revit
Type - Pset_ProductRequirements - Category: Doors
OverallHeight: 2150 mm; OverallWidth: 1080 mm; Group: Model Group:Building:629362
Pset_DoorCommon - Reference: 100x210
Pset_QuantityTakeOff - Reference: 100x210

# IfcDoor: Doors_IntSgl:100x210, Doors_IntSgl:100x210:621907
In: 7.1OG KH +2.65
Type - OperationType: SINGLE_SWING_LEFT; ParameterTakesPrecedence: no; Sizeable: no; Material: Door - Handle, Door - Panel, Door - Architrave, Door - Frame/Mullion (1)
Type - Doors_IntSgl:100x210:621907:1 - PanelOperation: SWINGING
Type - Pset_DoorCommon - IsExternal: no
Type - Pset_ManufacturerTypeInformation - Manufacturer: Revit
Type - Pset_ProductRequirements - Category: Doors
OverallHeight: 2150 mm; OverallWidth: 1080 mm; Group: Model Group:Building:629362
Pset_DoorCommon - Reference: 100x210
Pset_QuantityTakeOff - Reference: 100x210

# IfcDoor: Doors_IntSgl:100x210, Doors_IntSgl:100x210:621909
In: 7.1OG KH +2.65
Type - OperationType: SINGLE_SWING_LEFT; ParameterTakesPrecedence: no; Sizeable: no; Material: Door - Handle, Door - Panel, Door - Architrave, Door - Frame/Mullion (1)
Type - Doors_IntSgl:100x210:621909:1 - PanelOperation: SWINGING
Type - Pset_DoorCommon - IsExternal: no
Type - Pset_ManufacturerTypeInformation - Manufacturer: Revit
Type - Pset_ProductRequirements - Category: Doors
OverallHeight: 2150 mm; OverallWidth: 1080 mm; Group: Model Group:Building:629362
Pset_DoorCommon - Reference: 100x210
Pset_QuantityTakeOff - Reference: 100x210

# IfcDoor: Doors_IntSgl:100x210, Doors_IntSgl:100x210:622181
In: 6.EG KH -1.15
Type - OperationType: SINGLE_SWING_LEFT; ParameterTakesPrecedence: no; Sizeable: no; Material: Door - Handle, Door - Panel, Door - Architrave, Door - Frame/Mullion (1)
Type - Doors_IntSgl:100x210:622181:1 - PanelOperation: SWINGING
Type - Pset_DoorCommon - IsExternal: no
Type - Pset_ManufacturerTypeInformation - Manufacturer: Revit
Type - Pset_ProductRequirements - Category: Doors
OverallHeight: 2150 mm; OverallWidth: 1080 mm; Group: Model Group:Building:629362
Pset_DoorCommon - Reference: 100x210
Pset_QuantityTakeOff - Reference: 100x210

# IfcDoor: Doors_IntSgl:100x210, Doors_IntSgl:100x210:622240
In: 8.2OG KH +6.45
Type - OperationType: SINGLE_SWING_LEFT; ParameterTakesPrecedence: no; Sizeable: no; Material: Door - Handle, Door - Panel, Door - Architrave, Door - Frame/Mullion (1)
Type - Doors_IntSgl:100x210:622240:1 - PanelOperation: SWINGING
Type - Pset_DoorCommon - IsExternal: no
Type - Pset_ManufacturerTypeInformation - Manufacturer: Revit
Type - Pset_ProductRequirements - Category: Doors
OverallHeight: 2150 mm; OverallWidth: 1080 mm; Group: Model Group:Building:629362
Pset_DoorCommon - Reference: 100x210
Pset_QuantityTakeOff - Reference: 100x210

# IfcDoor: Doors_IntSgl:100x210 (2)
In: 0.UG -3.60
Type - OperationType: SINGLE_SWING_LEFT; ParameterTakesPrecedence: no; Sizeable: no; Material: Door - Handle, Door - Panel, Door - Architrave, Door - Frame/Mullion (1)
Type - Doors_IntSgl:100x210:623105:1 - PanelOperation: SWINGING
Type - Pset_DoorCommon - IsExternal: no
Type - Pset_ManufacturerTypeInformation - Manufacturer: Revit
Type - Pset_ProductRequirements - Category: Doors
OverallHeight: 2150 mm; OverallWidth: 1080 mm; Group: Model Group:Building:629362
Pset_DoorCommon - Reference: 100x210
Pset_QuantityTakeOff - Reference: 100x210
Name (Doors_IntSgl:100x210:...)
623105
623106

# IfcDoor: Doors_IntSgl:100x210, Doors_IntSgl:100x210:623204
In: 0.UG -3.60
Type - OperationType: SINGLE_SWING_LEFT; ParameterTakesPrecedence: no; Sizeable: no; Material: Door - Handle, Door - Panel, Door - Architrave, Door - Frame/Mullion (1)
Type - Doors_IntSgl:100x210:623204:1 - PanelOperation: SWINGING
Type - Pset_DoorCommon - IsExternal: no
Type - Pset_ManufacturerTypeInformation - Manufacturer: Revit
Type - Pset_ProductRequirements - Category: Doors
OverallHeight: 2150 mm; OverallWidth: 1080 mm; Group: Model Group:Building:629362
Pset_DoorCommon - Reference: 100x210
Pset_QuantityTakeOff - Reference: 100x210

# IfcDoor: Doors_IntSgl:100x210 (77)
Type - OperationType: SINGLE_SWING_RIGHT; ParameterTakesPrecedence: no; Sizeable: no; Material: Door - Handle, Door - Panel, Door - Architrave, Door - Frame/Mullion (1)
Type - Doors_IntSgl:100x210:618462:1 - PanelOperation: SWINGING
Type - Pset_DoorCommon - IsExternal: no
Type - Pset_ManufacturerTypeInformation - Manufacturer: Revit
Type - Pset_ProductRequirements - Category: Doors
OverallHeight: 2150 mm; OverallWidth: 1080 mm; Group: Model Group:Building:629362
Pset_DoorCommon - Reference: 100x210
Pset_QuantityTakeOff - Reference: 100x210
Name (Doors_IntSgl:100x210:...) | In
618462 | 1.EG +0.00
618520 | 1.EG +0.00
618521 | 1.EG +0.00
618522 | 1.EG +0.00
618523 | 1.EG +0.00
618524 | 1.EG +0.00
618549 | 1.EG +0.00
618555 | 1.EG +0.00
618557 | 1.EG +0.00
619253 | 2.1OG +5.30
619296 | 2.1OG +5.30
619297 | 2.1OG +5.30
619298 | 2.1OG +5.30
619299 | 2.1OG +5.30
619300 | 2.1OG +5.30
619301 | 2.1OG +5.30
619302 | 2.1OG +5.30
619586 | 2.1OG +5.30
619630 | 2.1OG +5.30
619631 | 2.1OG +5.30
619632 | 2.1OG +5.30
619636 | 2.1OG +5.30
619639 | 2.1OG +5.30
619641 | 2.1OG +5.30
619664 | 2.1OG +5.30
619665 | 2.1OG +5.30
619950 | 3.2OG +10.60
619993 | 3.2OG +10.60
619994 | 3.2OG +10.60
619995 | 3.2OG +10.60
619996 | 3.2OG +10.60
619997 | 3.2OG +10.60
619998 | 3.2OG +10.60
619999 | 3.2OG +10.60
620219 | 3.2OG +10.60
620257 | 3.2OG +10.60
620259 | 3.2OG +10.60
620261 | 3.2OG +10.60
620283 | 3.2OG +10.60
620284 | 3.2OG +10.60
620906 | 4.3OG +15.90
620907 | 4.3OG +15.90
620908 | 4.3OG +15.90
620909 | 4.3OG +15.90
620910 | 4.3OG +15.90
620911 | 4.3OG +15.90
620912 | 4.3OG +15.90
621163 | 4.3OG +15.90
621165 | 4.3OG +15.90
621167 | 4.3OG +15.90
621189 | 4.3OG +15.90
621190 | 4.3OG +15.90
621569 | 4.3OG +15.90
621904 | 7.1OG KH +2.65
621906 | 7.1OG KH +2.65
622182 | 6.EG KH -1.15
622241 | 8.2OG KH +6.45
622242 | 8.2OG KH +6.45
622244 | 8.2OG KH +6.45
622365 | 9.3OG KH +10.25
623093 | 0.UG -3.60
623094 | 0.UG -3.60
623097 | 0.UG -3.60
623099 | 0.UG -3.60
623102 | 0.UG -3.60
623103 | 0.UG -3.60
623112 | 0.UG -3.60
623113 | 0.UG -3.60
623116 | 0.UG -3.60
623117 | 0.UG -3.60
623119 | 0.UG -3.60
623125 | 0.UG -3.60
623126 | 0.UG -3.60
623166 | 0.UG -3.60
623177 | 0.UG -3.60
623178 | 0.UG -3.60
623207 | 0.UG -3.60

# IfcDoor: Doors_IntSgl:100x210 (5)
Type - OperationType: SINGLE_SWING_RIGHT; ParameterTakesPrecedence: no; Sizeable: no; Material: Door - Handle, Door - Panel, Door - Architrave, Door - Frame/Mullion (1)
Type - Doors_IntSgl:100x210:618525:1 - PanelOperation: SWINGING
Type - Pset_DoorCommon - IsExternal: no
Type - Pset_ManufacturerTypeInformation - Manufacturer: Revit
Type - Pset_ProductRequirements - Category: Doors
OverallHeight: 2150 mm; OverallWidth: 1080 mm; Group: Model Group:Building:629362
Pset_DoorCommon - Reference: 100x210
Pset_QuantityTakeOff - Reference: 100x210
Name (Doors_IntSgl:100x210:...) | In
618525 | 1.EG +0.00
619303 | 2.1OG +5.30
620000 | 3.2OG +10.60
620913 | 4.3OG +15.90
621563 | 4.3OG +15.90

# IfcDoor: Doors_IntSgl:100x210 (2)
Type - OperationType: SINGLE_SWING_RIGHT; ParameterTakesPrecedence: no; Sizeable: no; Material: Door - Handle, Door - Panel, Door - Architrave, Door - Frame/Mullion (1)
Type - Doors_IntSgl:100x210:622245:1 - PanelOperation: SWINGING
Type - Pset_DoorCommon - IsExternal: no
Type - Pset_ManufacturerTypeInformation - Manufacturer: Revit
Type - Pset_ProductRequirements - Category: Doors
OverallHeight: 2150 mm; OverallWidth: 1080 mm; Group: Model Group:Building:629362
Pset_DoorCommon - Reference: 100x210
Pset_QuantityTakeOff - Reference: 100x210
Name (Doors_IntSgl:100x210:...) | In
622245 | 8.2OG KH +6.45
622363 | 9.3OG KH +10.25

# IfcDoor: Doors_IntSgl:100x210, Doors_IntSgl:100x210:623091
In: 0.UG -3.60
Type - OperationType: SINGLE_SWING_RIGHT; ParameterTakesPrecedence: no; Sizeable: no; Material: Door - Handle, Door - Panel, Door - Architrave, Door - Frame/Mullion (1)
Type - Doors_IntSgl:100x210:623091:1 - PanelOperation: SWINGING
Type - Pset_DoorCommon - IsExternal: no
Type - Pset_ManufacturerTypeInformation - Manufacturer: Revit
Type - Pset_ProductRequirements - Category: Doors
OverallHeight: 2150 mm; OverallWidth: 1080 mm; Group: Model Group:Building:629362
Pset_DoorCommon - Reference: 100x210
Pset_QuantityTakeOff - Reference: 100x210

# IfcDoor: Doors_IntSgl:100x210 (2)
In: 0.UG -3.60
Type - OperationType: SINGLE_SWING_RIGHT; ParameterTakesPrecedence: no; Sizeable: no; Material: Door - Handle, Door - Panel, Door - Architrave, Door - Frame/Mullion (1)
Type - Doors_IntSgl:100x210:623107:1 - PanelOperation: SWINGING
Type - Pset_DoorCommon - IsExternal: no
Type - Pset_ManufacturerTypeInformation - Manufacturer: Revit
Type - Pset_ProductRequirements - Category: Doors
OverallHeight: 2150 mm; OverallWidth: 1080 mm; Group: Model Group:Building:629362
Pset_DoorCommon - Reference: 100x210
Pset_QuantityTakeOff - Reference: 100x210
Name (Doors_IntSgl:100x210:...)
623107
623109

# IfcDoor: Doors_IntSgl:100x210, Doors_IntSgl:100x210:623165
In: 0.UG -3.60
Type - OperationType: SINGLE_SWING_RIGHT; ParameterTakesPrecedence: no; Sizeable: no; Material: Door - Handle, Door - Panel, Door - Architrave, Door - Frame/Mullion (1)
Type - Doors_IntSgl:100x210:623165:1 - PanelOperation: SWINGING
Type - Pset_DoorCommon - IsExternal: no
Type - Pset_ManufacturerTypeInformation - Manufacturer: Revit
Type - Pset_ProductRequirements - Category: Doors
OverallHeight: 2150 mm; OverallWidth: 1080 mm; Group: Model Group:Building:629362
Pset_DoorCommon - Reference: 100x210
Pset_QuantityTakeOff - Reference: 100x210

# IfcDoor: Doors_IntSgl:100x210, Doors_IntSgl:100x210:623170
In: 0.UG -3.60
Type - OperationType: SINGLE_SWING_RIGHT; ParameterTakesPrecedence: no; Sizeable: no; Material: Door - Handle, Door - Panel, Door - Architrave, Door - Frame/Mullion (1)
Type - Doors_IntSgl:100x210:623170:1 - PanelOperation: SWINGING
Type - Pset_DoorCommon - IsExternal: no
Type - Pset_ManufacturerTypeInformation - Manufacturer: Revit
Type - Pset_ProductRequirements - Category: Doors
OverallHeight: 2150 mm; OverallWidth: 1080 mm; Group: Model Group:Building:629362
Pset_DoorCommon - Reference: 100x210
Pset_QuantityTakeOff - Reference: 100x210

# IfcDoor: Doors_IntSgl:100x210, Doors_IntSgl:100x210:623181
In: 0.UG -3.60
Type - OperationType: SINGLE_SWING_RIGHT; ParameterTakesPrecedence: no; Sizeable: no; Material: Door - Handle, Door - Panel, Door - Architrave, Door - Frame/Mullion (1)
Type - Doors_IntSgl:100x210:623181:1 - PanelOperation: SWINGING
Type - Pset_DoorCommon - IsExternal: no
Type - Pset_ManufacturerTypeInformation - Manufacturer: Revit
Type - Pset_ProductRequirements - Category: Doors
OverallHeight: 2150 mm; OverallWidth: 1080 mm; Group: Model Group:Building:629362
Pset_DoorCommon - Reference: 100x210
Pset_QuantityTakeOff - Reference: 100x210

# IfcDoor: Doors_IntSgl:70x210, Doors_IntSgl:70x210:623101
In: 0.UG -3.60
Type - OperationType: SINGLE_SWING_LEFT; ParameterTakesPrecedence: no; Sizeable: no; Material: Door - Handle, Door - Panel, Door - Architrave, Door - Frame/Mullion (1)
Type - Doors_IntSgl:70x210:623101:1 - PanelOperation: SWINGING
Type - Pset_DoorCommon - IsExternal: no
Type - Pset_ManufacturerTypeInformation - Manufacturer: Revit
Type - Pset_ProductRequirements - Category: Doors
OverallHeight: 2150 mm; OverallWidth: 780 mm; Group: Model Group:Building:629362
Pset_DoorCommon - Reference: 70x210
Pset_QuantityTakeOff - Reference: 70x210

# IfcDoor: Doors_IntSgl:70x210 (2)
Type - OperationType: SINGLE_SWING_LEFT; ParameterTakesPrecedence: no; Sizeable: no; Material: Door - Handle, Door - Panel, Door - Architrave, Door - Frame/Mullion (1)
Type - Doors_IntSgl:70x210:625642:1 - PanelOperation: SWINGING
Type - Pset_DoorCommon - IsExternal: no
Type - Pset_ManufacturerTypeInformation - Manufacturer: Revit
Type - Pset_ProductRequirements - Category: Doors
OverallHeight: 2150 mm; OverallWidth: 780 mm; Group: Model Group:Building:629362
Pset_DoorCommon - Reference: 70x210
Pset_QuantityTakeOff - Reference: 70x210
Name (Doors_IntSgl:70x210:...) | In
625642 | 4.3OG +15.90
627822 | 3.2OG +10.60

# IfcDoor: Doors_IntSgl:70x210, Doors_IntSgl:70x210:622179
In: 6.EG KH -1.15
Type - OperationType: SINGLE_SWING_RIGHT; ParameterTakesPrecedence: no; Sizeable: no; Material: Door - Handle, Door - Panel, Door - Architrave, Door - Frame/Mullion (1)
Type - Doors_IntSgl:70x210:622179:1 - PanelOperation: SWINGING
Type - Pset_DoorCommon - IsExternal: no
Type - Pset_ManufacturerTypeInformation - Manufacturer: Revit
Type - Pset_ProductRequirements - Category: Doors
OverallHeight: 2150 mm; OverallWidth: 780 mm; Group: Model Group:Building:629362
Pset_DoorCommon - Reference: 70x210
Pset_QuantityTakeOff - Reference: 70x210

# IfcDoor: Doors_IntSgl:70x210 (4)
Type - OperationType: SINGLE_SWING_RIGHT; ParameterTakesPrecedence: no; Sizeable: no; Material: Door - Handle, Door - Panel, Door - Architrave, Door - Frame/Mullion (1)
Type - Doors_IntSgl:70x210:625641:1 - PanelOperation: SWINGING
Type - Pset_DoorCommon - IsExternal: no
Type - Pset_ManufacturerTypeInformation - Manufacturer: Revit
Type - Pset_ProductRequirements - Category: Doors
OverallHeight: 2150 mm; OverallWidth: 780 mm; Group: Model Group:Building:629362
Pset_DoorCommon - Reference: 70x210
Pset_QuantityTakeOff - Reference: 70x210
Name (Doors_IntSgl:70x210:...) | In
625641 | 4.3OG +15.90
627821 | 3.2OG +10.60
627842 | 2.1OG +5.30
627843 | 2.1OG +5.30

# IfcDoor: Doors_IntSgl:75x210 (2)
In: 0.UG -3.60
Type - OperationType: SINGLE_SWING_LEFT; ParameterTakesPrecedence: no; Sizeable: no; Material: Door - Handle, Door - Panel, Door - Architrave, Door - Frame/Mullion (1)
Type - Doors_IntSgl:75x210:623089:1 - PanelOperation: SWINGING
Type - Pset_DoorCommon - IsExternal: no
Type - Pset_ManufacturerTypeInformation - Manufacturer: Revit
Type - Pset_ProductRequirements - Category: Doors
OverallHeight: 2150 mm; OverallWidth: 830 mm; Group: Model Group:Building:629362
Pset_DoorCommon - Reference: 75x210
Pset_QuantityTakeOff - Reference: 75x210
Name (Doors_IntSgl:75x210:...)
623089
623092

# IfcDoor: Doors_IntSgl:75x210, Doors_IntSgl:75x210:623090
In: 0.UG -3.60
Type - OperationType: SINGLE_SWING_RIGHT; ParameterTakesPrecedence: no; Sizeable: no; Material: Door - Handle, Door - Panel, Door - Architrave, Door - Frame/Mullion (1)
Type - Doors_IntSgl:75x210:623090:1 - PanelOperation: SWINGING
Type - Pset_DoorCommon - IsExternal: no
Type - Pset_ManufacturerTypeInformation - Manufacturer: Revit
Type - Pset_ProductRequirements - Category: Doors
OverallHeight: 2150 mm; OverallWidth: 830 mm; Group: Model Group:Building:629362
Pset_DoorCommon - Reference: 75x210
Pset_QuantityTakeOff - Reference: 75x210

# IfcDoor: Doors_IntSgl:75x210, Doors_IntSgl:75x210:628113
In: 1.EG +0.00
Type - OperationType: SINGLE_SWING_RIGHT; ParameterTakesPrecedence: no; Sizeable: no; Material: Door - Handle, Door - Panel, Door - Architrave, Door - Frame/Mullion (1)
Type - Doors_IntSgl:75x210:628113:1 - PanelOperation: SWINGING
Type - Pset_DoorCommon - IsExternal: no
Type - Pset_ManufacturerTypeInformation - Manufacturer: Revit
Type - Pset_ProductRequirements - Category: Doors
OverallHeight: 2150 mm; OverallWidth: 830 mm; Group: Model Group:Building:629362
Pset_DoorCommon - Reference: 75x210
Pset_QuantityTakeOff - Reference: 75x210

# IfcDoor: Doors_IntSgl:80x210 (3)
Type - OperationType: SINGLE_SWING_LEFT; ParameterTakesPrecedence: no; Sizeable: no; Material: Door - Handle, Door - Panel, Door - Architrave, Door - Frame/Mullion (1)
Type - Doors_IntSgl:80x210:619320:1 - PanelOperation: SWINGING
Type - Pset_DoorCommon - IsExternal: no
Type - Pset_ManufacturerTypeInformation - Manufacturer: Revit
Type - Pset_ProductRequirements - Category: Doors
OverallHeight: 2150 mm; OverallWidth: 880 mm; Group: Model Group:Building:629362
Pset_DoorCommon - Reference: 80x210
Pset_QuantityTakeOff - Reference: 80x210
Name (Doors_IntSgl:80x210:...) | In
619320 | 2.1OG +5.30
623163 | 0.UG -3.60
623172 | 0.UG -3.60

# IfcDoor: Doors_IntSgl:80x210, Doors_IntSgl:80x210:623205
In: 0.UG -3.60
Type - OperationType: SINGLE_SWING_LEFT; ParameterTakesPrecedence: no; Sizeable: no; Material: Door - Handle, Door - Panel, Door - Architrave, Door - Frame/Mullion (1)
Type - Doors_IntSgl:80x210:623205:1 - PanelOperation: SWINGING
Type - Pset_DoorCommon - IsExternal: no
Type - Pset_ManufacturerTypeInformation - Manufacturer: Revit
Type - Pset_ProductRequirements - Category: Doors
OverallHeight: 2150 mm; OverallWidth: 880 mm; Group: Model Group:Building:629362
Pset_DoorCommon - Reference: 80x210
Pset_QuantityTakeOff - Reference: 80x210

# IfcDoor: Doors_IntSgl:80x210 (2)
In: 0.UG -3.60
Type - OperationType: SINGLE_SWING_RIGHT; ParameterTakesPrecedence: no; Sizeable: no; Material: Door - Handle, Door - Panel, Door - Architrave, Door - Frame/Mullion (1)
Type - Doors_IntSgl:80x210:623167:1 - PanelOperation: SWINGING
Type - Pset_DoorCommon - IsExternal: no
Type - Pset_ManufacturerTypeInformation - Manufacturer: Revit
Type - Pset_ProductRequirements - Category: Doors
OverallHeight: 2150 mm; OverallWidth: 880 mm; Group: Model Group:Building:629362
Pset_DoorCommon - Reference: 80x210
Pset_QuantityTakeOff - Reference: 80x210
Name (Doors_IntSgl:80x210:...)
623167
623171

# IfcDoor: Doors_IntSgl:90x180, Doors_IntSgl:90x180:622292
In: 8.2OG KH +6.45
Type - OperationType: SINGLE_SWING_RIGHT; ParameterTakesPrecedence: no; Sizeable: no; Material: Door - Handle, Door - Panel, Door - Architrave, Door - Frame/Mullion (1)
Type - Doors_IntSgl:90x180:622292:1 - PanelOperation: SWINGING
Type - Pset_DoorCommon - IsExternal: no
Type - Pset_ManufacturerTypeInformation - Manufacturer: Revit
Type - Pset_ProductRequirements - Category: Doors
OverallHeight: 1850 mm; OverallWidth: 980 mm; Group: Model Group:Building:629362
Pset_DoorCommon - Reference: 90x180
Pset_QuantityTakeOff - Reference: 90x180

# IfcDoor: Doors_IntSgl:90x210 (4)
Type - OperationType: SINGLE_SWING_LEFT; ParameterTakesPrecedence: no; Sizeable: no; Material: Door - Handle, Door - Panel, Door - Architrave, Door - Frame/Mullion (1)
Type - Doors_IntSgl:90x210:618546:1 - PanelOperation: SWINGING
Type - Pset_DoorCommon - IsExternal: no
Type - Pset_ManufacturerTypeInformation - Manufacturer: Revit
Type - Pset_ProductRequirements - Category: Doors
OverallHeight: 2150 mm; OverallWidth: 980 mm; Group: Model Group:Building:629362
Pset_DoorCommon - Reference: 90x210
Pset_QuantityTakeOff - Reference: 90x210
Name (Doors_IntSgl:90x210:...) | In
618546 | 1.EG +0.00
618552 | 1.EG +0.00
622367 | 9.3OG KH +10.25
627526 | 2.1OG +5.30

# IfcDoor: Doors_IntSgl:90x210, Doors_IntSgl:90x210:619626
In: 2.1OG +5.30
Type - OperationType: SINGLE_SWING_LEFT; ParameterTakesPrecedence: no; Sizeable: no; Material: Door - Handle, Door - Panel, Door - Architrave, Door - Frame/Mullion (1)
Type - Doors_IntSgl:90x210:619626:1 - PanelOperation: SWINGING
Type - Pset_DoorCommon - IsExternal: no
Type - Pset_ManufacturerTypeInformation - Manufacturer: Revit
Type - Pset_ProductRequirements - Category: Doors
OverallHeight: 2150 mm; OverallWidth: 980 mm; Group: Model Group:Building:629362
Pset_DoorCommon - Reference: 90x210
Pset_QuantityTakeOff - Reference: 90x210

# IfcDoor: Doors_IntSgl:90x210, Doors_IntSgl:90x210:622198
In: 7.1OG KH +2.65
Type - OperationType: SINGLE_SWING_LEFT; ParameterTakesPrecedence: no; Sizeable: no; Material: Door - Handle, Door - Panel, Door - Architrave, Door - Frame/Mullion (1)
Type - Doors_IntSgl:90x210:622198:1 - PanelOperation: SWINGING
Type - Pset_DoorCommon - IsExternal: no
Type - Pset_ManufacturerTypeInformation - Manufacturer: Revit
Type - Pset_ProductRequirements - Category: Doors
OverallHeight: 2150 mm; OverallWidth: 980 mm; Group: Model Group:Building:629362
Pset_DoorCommon - Reference: 90x210
Pset_QuantityTakeOff - Reference: 90x210

# IfcDoor: Doors_IntSgl:90x210 (2)
In: 0.UG -3.60
Type - OperationType: SINGLE_SWING_LEFT; ParameterTakesPrecedence: no; Sizeable: no; Material: Door - Handle, Door - Panel, Door - Architrave, Door - Frame/Mullion (1)
Type - Doors_IntSgl:90x210:623182:1 - PanelOperation: SWINGING
Type - Pset_DoorCommon - IsExternal: no
Type - Pset_ManufacturerTypeInformation - Manufacturer: Revit
Type - Pset_ProductRequirements - Category: Doors
OverallHeight: 2150 mm; OverallWidth: 980 mm; Group: Model Group:Building:629362
Pset_DoorCommon - Reference: 90x210
Pset_QuantityTakeOff - Reference: 90x210
Name (Doors_IntSgl:90x210:...)
623182
623183

# IfcDoor: Doors_IntSgl:90x210 (10)
Type - OperationType: SINGLE_SWING_RIGHT; ParameterTakesPrecedence: no; Sizeable: no; Material: Door - Handle, Door - Panel, Door - Architrave, Door - Frame/Mullion (1)
Type - Doors_IntSgl:90x210:618547:1 - PanelOperation: SWINGING
Type - Pset_DoorCommon - IsExternal: no
Type - Pset_ManufacturerTypeInformation - Manufacturer: Revit
Type - Pset_ProductRequirements - Category: Doors
OverallHeight: 2150 mm; OverallWidth: 980 mm; Group: Model Group:Building:629362
Pset_DoorCommon - Reference: 90x210
Pset_QuantityTakeOff - Reference: 90x210
Name (Doors_IntSgl:90x210:...) | In
618547 | 1.EG +0.00
618550 | 1.EG +0.00
618551 | 1.EG +0.00
618553 | 1.EG +0.00
618554 | 1.EG +0.00
618790 | 1.EG +0.00
619622 | 2.1OG +5.30
619637 | 2.1OG +5.30
623122 | 0.UG -3.60
623206 | 0.UG -3.60

# IfcDoor: Doors_IntSgl:90x210, Doors_IntSgl:90x210:622247
In: 8.2OG KH +6.45
Type - OperationType: SINGLE_SWING_RIGHT; ParameterTakesPrecedence: no; Sizeable: no; Material: Door - Handle, Door - Panel, Door - Architrave, Door - Frame/Mullion (1)
Type - Doors_IntSgl:90x210:622247:1 - PanelOperation: SWINGING
Type - Pset_DoorCommon - IsExternal: no
Type - Pset_ManufacturerTypeInformation - Manufacturer: Revit
Type - Pset_ProductRequirements - Category: Doors
OverallHeight: 2150 mm; OverallWidth: 980 mm; Group: Model Group:Building:629362
Pset_DoorCommon - Reference: 90x210
Pset_QuantityTakeOff - Reference: 90x210

# IfcDoor: Doors_IntSgl:90x210, Doors_IntSgl:90x210:627527
In: 2.1OG +5.30
Type - OperationType: SINGLE_SWING_RIGHT; ParameterTakesPrecedence: no; Sizeable: no; Material: Door - Handle, Door - Panel, Door - Architrave, Door - Frame/Mullion (1)
Type - Doors_IntSgl:90x210:627527:1 - PanelOperation: SWINGING
Type - Pset_DoorCommon - IsExternal: no
Type - Pset_ManufacturerTypeInformation - Manufacturer: Revit
Type - Pset_ProductRequirements - Category: Doors
OverallHeight: 2150 mm; OverallWidth: 980 mm; Group: Model Group:Building:629362
Pset_DoorCommon - Reference: 90x210
Pset_QuantityTakeOff - Reference: 90x210

# IfcDoor: M_Door-Curtain-Wall-Double-Storefront:M_Door-Curtain-Wall-Double-Storefront (7)
Type - ParameterTakesPrecedence: no; Sizeable: no; Material: Aluminum, Glass
Type - Pset_DoorCommon - IsExternal: yes; ThermalTransmittance: 4.11674 kg/K/s3
Type - Pset_ProductRequirements - Category: Doors
Pset_DoorCommon - Reference: M_Door-Curtain-Wall-Double-Storefront
Pset_QuantityTakeOff - Reference: M_Door-Curtain-Wall-Double-Storefront
Group: Model Group:Building:629362
Name (M_Door-Curtain-Wall-Double-Storefront:M_Door-Curtain-Wall-Double-Storefront:...) | In | OverallHeight (mm) | OverallWidth (mm)
618703 | 1.EG +0.00 | 2875 | 1550
618694 | 1.EG +0.00 | 2875 | 1550
618774 | 1.EG +0.00 | 1900 | 1546.12
622082 | 6.EG KH -1.15 | 2075 | 1550
622086 | 6.EG KH -1.15 | 2075 | 1550
626064 | 3.2OG +10.60 | 2000 | 1425
627917 | 2.1OG +5.30 | 2000 | 1425

# IfcDoor: M_Door-Curtain-Wall-Single-Glass:M_Door-Curtain-Wall-Single-Glass (10)
Type - ParameterTakesPrecedence: no; Sizeable: no; Material: Glass, Aluminum
Type - Pset_DoorCommon - IsExternal: yes
Type - Pset_ProductRequirements - Category: Doors
Pset_DoorCommon - Reference: M_Door-Curtain-Wall-Single-Glass
Pset_QuantityTakeOff - Reference: M_Door-Curtain-Wall-Single-Glass
Group: Model Group:Building:629362
Name (M_Door-Curtain-Wall-Single-Glass:M_Door-Curtain-Wall-Single-Glass:...) | In | OverallHeight (mm) | OverallWidth (mm)
628192 | 1.EG +0.00 | 2025 | 825
628426 | 1.EG +0.00 | 2025 | 825
625313 | 4.3OG +15.90 | 3125 | 1000
625130 | 4.3OG +15.90 | 3125 | 975
625142 | 4.3OG +15.90 | 3125 | 1000
625661 | 4.3OG +15.90 | 2925 | 950
626316 | 3.2OG +10.60 | 2175 | 1075
626442 | 3.2OG +10.60 | 2100 | 1233.33
628571 | 1.EG +0.00 | 2025 | 825
628741 | 1.EG +0.00 | 2325 | 900

# IfcDoor: M_Door-Exterior-Double:265x350, M_Door-Exterior-Double:265x350:618561
In: 1.EG +0.00
Type - ParameterTakesPrecedence: no; Sizeable: no; Material: Metal - Stainless Steel, Cherry, Metal - Painted - Grey
Type - M_Door-Exterior-Double:265x350:618561 - LiningOffset: 15 mm
Type - Pset_DoorCommon - IsExternal: yes
Type - Pset_ProductRequirements - Category: Doors
OverallHeight: 3600 mm; OverallWidth: 2750 mm; Classification: B2030200 Uniformat (Uniformat); Group: Model Group:Building:629362
Pset_DoorCommon - Reference: 265x350
Pset_QuantityTakeOff - Reference: 265x350

# IfcDoor: M_Door-Exterior-Double:280x250, M_Door-Exterior-Double:280x250:623320
In: 1.EG +0.00
Type - ParameterTakesPrecedence: no; Sizeable: no; Material: Metal - Stainless Steel, Cherry, Metal - Painted - Grey
Type - M_Door-Exterior-Double:280x250:623320 - LiningOffset: 15 mm
Type - Pset_DoorCommon - IsExternal: yes
Type - Pset_ProductRequirements - Category: Doors
OverallHeight: 2600 mm; OverallWidth: 2900 mm; Classification: B2030200 Uniformat (Uniformat); Group: Model Group:Building:629362
Pset_DoorCommon - Reference: 280x250
Pset_QuantityTakeOff - Reference: 280x250

# IfcDoor: M_Door-Exterior-Double:300x290, M_Door-Exterior-Double:300x290:623321
In: 1.EG +0.00
Type - ParameterTakesPrecedence: no; Sizeable: no; Material: Metal - Stainless Steel, Cherry, Metal - Painted - Grey
Type - M_Door-Exterior-Double:300x290:623321 - LiningOffset: 15 mm
Type - Pset_DoorCommon - IsExternal: yes
Type - Pset_ProductRequirements - Category: Doors
OverallHeight: 3000 mm; OverallWidth: 3100 mm; Classification: B2030200 Uniformat (Uniformat); Group: Model Group:Building:629362
Pset_DoorCommon - Reference: 300x290
Pset_QuantityTakeOff - Reference: 300x290

# IfcDoor: M_Door-Passage-Double-Flush:130x210 (3)
Type - ParameterTakesPrecedence: no; Sizeable: no; Material: Aluminum, Metal - Painted - Grey, Metal Door - Brindle
Type - Pset_DoorCommon - IsExternal: yes
Type - Pset_ProductRequirements - Category: Doors
OverallHeight: 2200 mm; OverallWidth: 1400 mm; Classification: B2030200 Uniformat (Uniformat); Group: Model Group:Building:629362
Pset_DoorCommon - Reference: 130x210
Pset_QuantityTakeOff - Reference: 130x210
Name (M_Door-Passage-Double-Flush:130x210:...) | In
618625 | 1.EG +0.00
623108 | 0.UG -3.60
623110 | 0.UG -3.60

# IfcDoor: M_Door-Passage-Double-Flush:150x210 (16)
Type - ParameterTakesPrecedence: no; Sizeable: no; Material: Aluminum, Metal - Painted - Grey, Metal Door - Brindle
Type - Pset_DoorCommon - IsExternal: yes
Type - Pset_ProductRequirements - Category: Doors
OverallHeight: 2200 mm; OverallWidth: 1600 mm; Classification: B2030200 Uniformat (Uniformat); Group: Model Group:Building:629362
Pset_DoorCommon - Reference: 150x210
Pset_QuantityTakeOff - Reference: 150x210
Name (M_Door-Passage-Double-Flush:150x210:...) | In
618461 | 1.EG +0.00
618607 | 1.EG +0.00
618622 | 1.EG +0.00
619342 | 2.1OG +5.30
619629 | 2.1OG +5.30
619663 | 2.1OG +5.30
620038 | 3.2OG +10.60
620282 | 3.2OG +10.60
620666 | 3.2OG +10.60
620668 | 3.2OG +10.60
621188 | 4.3OG +15.90
622132 | 6.EG KH -1.15
622133 | 6.EG KH -1.15
622135 | 6.EG KH -1.15
622136 | 6.EG KH -1.15
622197 | 6.EG KH -1.15

# IfcDoor: M_Door-Passage-Double-Flush:160x210 (50)
Type - ParameterTakesPrecedence: no; Sizeable: no; Material: Aluminum, Metal - Painted - Grey, Metal Door - Brindle
Type - Pset_DoorCommon - IsExternal: yes
Type - Pset_ProductRequirements - Category: Doors
OverallHeight: 2200 mm; OverallWidth: 1700 mm; Classification: B2030200 Uniformat (Uniformat); Group: Model Group:Building:629362
Pset_DoorCommon - Reference: 160x210
Pset_QuantityTakeOff - Reference: 160x210
Name (M_Door-Passage-Double-Flush:160x210:...) | In
618600 | 1.EG +0.00
618601 | 1.EG +0.00
618602 | 1.EG +0.00
618603 | 1.EG +0.00
618604 | 1.EG +0.00
618605 | 1.EG +0.00
618606 | 1.EG +0.00
618608 | 1.EG +0.00
618609 | 1.EG +0.00
618610 | 1.EG +0.00
618611 | 1.EG +0.00
618612 | 1.EG +0.00
618613 | 1.EG +0.00
618614 | 1.EG +0.00
618615 | 1.EG +0.00
618616 | 1.EG +0.00
618617 | 1.EG +0.00
618618 | 1.EG +0.00
618619 | 1.EG +0.00
618620 | 1.EG +0.00
618621 | 1.EG +0.00
618624 | 1.EG +0.00
619340 | 2.1OG +5.30
619341 | 2.1OG +5.30
619344 | 2.1OG +5.30
619638 | 2.1OG +5.30
620036 | 3.2OG +10.60
620037 | 3.2OG +10.60
620040 | 3.2OG +10.60
620258 | 3.2OG +10.60
620949 | 4.3OG +15.90
620950 | 4.3OG +15.90
620952 | 4.3OG +15.90
621164 | 4.3OG +15.90
621995 | 7.1OG KH +2.65
622129 | 6.EG KH -1.15
622130 | 6.EG KH -1.15
622131 | 6.EG KH -1.15
622134 | 6.EG KH -1.15
622200 | 7.1OG KH +2.65
622248 | 8.2OG KH +6.45
622368 | 9.3OG KH +10.25
623164 | 0.UG -3.60
623168 | 0.UG -3.60
623169 | 0.UG -3.60
623173 | 0.UG -3.60
623174 | 0.UG -3.60
623175 | 0.UG -3.60
623176 | 0.UG -3.60
623769 | 0.UG -3.60

# IfcDoor: M_Door-Passage-Double-Flush:180x210, M_Door-Passage-Double-Flush:180x210:623162
In: 0.UG -3.60
Type - ParameterTakesPrecedence: no; Sizeable: no; Material: Aluminum, Metal - Painted - Grey, Metal Door - Brindle
Type - Pset_DoorCommon - IsExternal: yes
Type - Pset_ProductRequirements - Category: Doors
OverallHeight: 2200 mm; OverallWidth: 1900 mm; Classification: B2030200 Uniformat (Uniformat); Group: Model Group:Building:629362
Pset_DoorCommon - Reference: 180x210
Pset_QuantityTakeOff - Reference: 180x210

# IfcDoor: M_Door-Passage-Double-Flush:210x210, M_Door-Passage-Double-Flush:210x210:625586
In: 4.3OG +15.90
Type - ParameterTakesPrecedence: no; Sizeable: no; Material: Aluminum, Metal - Painted - Grey, Metal Door - Brindle
Type - Pset_DoorCommon - IsExternal: yes
Type - Pset_ProductRequirements - Category: Doors
OverallHeight: 2200 mm; OverallWidth: 2100 mm; Classification: B2030200 Uniformat (Uniformat); Group: Model Group:Building:629362
Pset_DoorCommon - Reference: 210x210
Pset_QuantityTakeOff - Reference: 210x210

# IfcDoor: M_Door-Passage-Double-Flush:220x210 (2)
In: 4.3OG +15.90
Type - ParameterTakesPrecedence: no; Sizeable: no; Material: Aluminum, Metal - Painted - Grey, Metal Door - Brindle
Type - Pset_DoorCommon - IsExternal: yes
Type - Pset_ProductRequirements - Category: Doors
OverallHeight: 2200 mm; OverallWidth: 2300 mm; Classification: B2030200 Uniformat (Uniformat); Group: Model Group:Building:629362
Pset_DoorCommon - Reference: 220x210
Pset_QuantityTakeOff - Reference: 220x210
Name (M_Door-Passage-Double-Flush:220x210:...)
621567
621568

# IfcMember: Rectangular Mullion:5x5 (2701)
Type - PredefinedType: MULLION; Material: Aluminium
Type - Pset_MemberCommon - IsExternal: no
Type - Pset_ProductRequirements - Category: Curtain Wall Mullions
Pset_MemberCommon - Reference: 5x5
Pset_QuantityTakeOff - Reference: 5x5
Group: Model Group:Building:629362
Name (Rectangular Mullion:5x5:...) | In | Span (mm)
628307 | 1.EG +0.00 | 2000
628308 | 1.EG +0.00 | 850
628329 | 1.EG +0.00 | 646.096
628330 | 1.EG +0.00 | 646.096
628331 | 1.EG +0.00 | 646.096
628332 | 1.EG +0.00 | 646.096
628333 | 1.EG +0.00 | 646.096
628334 | 1.EG +0.00 | 646.096
628335 | 1.EG +0.00 | 850
628336 | 1.EG +0.00 | 850
628337 | 1.EG +0.00 | 2000
628338 | 1.EG +0.00 | 850
628339 | 1.EG +0.00 | 646.096
628340 | 1.EG +0.00 | 646.096
628341 | 1.EG +0.00 | 646.096
628342 | 1.EG +0.00 | 646.096
628343 | 1.EG +0.00 | 646.096
628344 | 1.EG +0.00 | 646.096
628345 | 1.EG +0.00 | 646.096
628346 | 1.EG +0.00 | 646.096
628347 | 1.EG +0.00 | 646.096
628348 | 1.EG +0.00 | 646.096
628349 | 1.EG +0.00 | 646.096
628350 | 1.EG +0.00 | 646.096
628351 | 1.EG +0.00 | 646.096
628352 | 1.EG +0.00 | 646.096
628353 | 1.EG +0.00 | 2000
628354 | 1.EG +0.00 | 2000
628355 | 1.EG +0.00 | 2000
628356 | 1.EG +0.00 | 2000
628357 | 1.EG +0.00 | 850
628358 | 1.EG +0.00 | 850
628359 | 1.EG +0.00 | 850
628360 | 1.EG +0.00 | 850
628361 | 1.EG +0.00 | 850
628362 | 1.EG +0.00 | 850
628363 | 1.EG +0.00 | 850
628364 | 1.EG +0.00 | 850
628411 | 1.EG +0.00 | 646.096
628412 | 1.EG +0.00 | 646.096
628413 | 1.EG +0.00 | 646.096
628414 | 1.EG +0.00 | 646.096
628415 | 1.EG +0.00 | 646.096
628416 | 1.EG +0.00 | 646.096
628417 | 1.EG +0.00 | 646.096
628418 | 1.EG +0.00 | 646.096
628419 | 1.EG +0.00 | 2000
628420 | 1.EG +0.00 | 2000
628421 | 1.EG +0.00 | 850
628422 | 1.EG +0.00 | 850
628423 | 1.EG +0.00 | 850
628424 | 1.EG +0.00 | 850
628150 | 1.EG +0.00 | 696.43
628151 | 1.EG +0.00 | 746.43
628152 | 1.EG +0.00 | 1000
628153 | 1.EG +0.00 | 700
628218 | 1.EG +0.00 | 746.43
628219 | 1.EG +0.00 | 746.43
628220 | 1.EG +0.00 | 746.43
628221 | 1.EG +0.00 | 746.43
628222 | 1.EG +0.00 | 746.43
628223 | 1.EG +0.00 | 746.43
628224 | 1.EG +0.00 | 746.43
628225 | 1.EG +0.00 | 696.43
628226 | 1.EG +0.00 | 1100
628227 | 1.EG +0.00 | 1000
628228 | 1.EG +0.00 | 550
628229 | 1.EG +0.00 | 700
628230 | 1.EG +0.00 | 1000
628231 | 1.EG +0.00 | 1100
628232 | 1.EG +0.00 | 1000
628233 | 1.EG +0.00 | 550
628234 | 1.EG +0.00 | 746.43
628235 | 1.EG +0.00 | 746.43
628236 | 1.EG +0.00 | 746.43
628237 | 1.EG +0.00 | 746.43
628238 | 1.EG +0.00 | 696.43
628239 | 1.EG +0.00 | 746.43
628240 | 1.EG +0.00 | 746.43
628241 | 1.EG +0.00 | 746.43
628242 | 1.EG +0.00 | 746.43
628243 | 1.EG +0.00 | 696.43
628244 | 1.EG +0.00 | 1000
628245 | 1.EG +0.00 | 1000
628246 | 1.EG +0.00 | 1000
628247 | 1.EG +0.00 | 1000
628248 | 1.EG +0.00 | 1100
628249 | 1.EG +0.00 | 1100
628250 | 1.EG +0.00 | 1100
628251 | 1.EG +0.00 | 1100
628252 | 1.EG +0.00 | 1000
628253 | 1.EG +0.00 | 1000
628254 | 1.EG +0.00 | 1000
628255 | 1.EG +0.00 | 1000
628256 | 1.EG +0.00 | 550
628257 | 1.EG +0.00 | 550
628258 | 1.EG +0.00 | 550
628259 | 1.EG +0.00 | 550
628260 | 1.EG +0.00 | 700
628261 | 1.EG +0.00 | 700
628262 | 1.EG +0.00 | 700
628263 | 1.EG +0.00 | 700
628288 | 1.EG +0.00 | 746.43
628289 | 1.EG +0.00 | 746.43
628290 | 1.EG +0.00 | 746.43
628291 | 1.EG +0.00 | 746.43
628292 | 1.EG +0.00 | 746.43
628293 | 1.EG +0.00 | 746.43
628294 | 1.EG +0.00 | 746.43
628295 | 1.EG +0.00 | 746.43
628296 | 1.EG +0.00 | 1000
628297 | 1.EG +0.00 | 1000
628298 | 1.EG +0.00 | 1100
628299 | 1.EG +0.00 | 1100
628300 | 1.EG +0.00 | 1000
628301 | 1.EG +0.00 | 1000
628302 | 1.EG +0.00 | 550
628303 | 1.EG +0.00 | 550
628304 | 1.EG +0.00 | 700
628305 | 1.EG +0.00 | 700
628186 | 1.EG +0.00 | 701.034
628187 | 1.EG +0.00 | 1000
628188 | 1.EG +0.00 | 600
628201 | 1.EG +0.00 | 701.034
628202 | 1.EG +0.00 | 677.068
628203 | 1.EG +0.00 | 677.068
628204 | 1.EG +0.00 | 825
628205 | 1.EG +0.00 | 1100
628206 | 1.EG +0.00 | 1000
628207 | 1.EG +0.00 | 1000
628208 | 1.EG +0.00 | 1100
628209 | 1.EG +0.00 | 701.034
628210 | 1.EG +0.00 | 677.068
628211 | 1.EG +0.00 | 825
628212 | 1.EG +0.00 | 1000
628213 | 1.EG +0.00 | 1000
628214 | 1.EG +0.00 | 1100
628215 | 1.EG +0.00 | 1100
628216 | 1.EG +0.00 | 1000
628217 | 1.EG +0.00 | 1000
628264 | 1.EG +0.00 | 825
628269 | 1.EG +0.00 | 1000
628270 | 1.EG +0.00 | 600
628271 | 1.EG +0.00 | 600
628272 | 1.EG +0.00 | 600
628273 | 1.EG +0.00 | 701.034
628274 | 1.EG +0.00 | 677.068
628275 | 1.EG +0.00 | 825
628427 | 1.EG +0.00 | 728.634
628428 | 1.EG +0.00 | 753.634
628429 | 1.EG +0.00 | 1000
628430 | 1.EG +0.00 | 1125
628477 | 1.EG +0.00 | 728.634
628478 | 1.EG +0.00 | 728.634
628479 | 1.EG +0.00 | 728.634
628480 | 1.EG +0.00 | 728.634
628481 | 1.EG +0.00 | 753.634
628482 | 1.EG +0.00 | 753.634
628483 | 1.EG +0.00 | 753.634
628484 | 1.EG +0.00 | 753.634
628485 | 1.EG +0.00 | 1100
628486 | 1.EG +0.00 | 1125
628487 | 1.EG +0.00 | 1125
628488 | 1.EG +0.00 | 1000
628489 | 1.EG +0.00 | 1100
628490 | 1.EG +0.00 | 1125
628491 | 1.EG +0.00 | 753.634
628492 | 1.EG +0.00 | 753.634
628493 | 1.EG +0.00 | 753.634
628494 | 1.EG +0.00 | 753.634
628495 | 1.EG +0.00 | 753.634
628496 | 1.EG +0.00 | 728.634
628497 | 1.EG +0.00 | 728.634
628498 | 1.EG +0.00 | 728.634
628499 | 1.EG +0.00 | 728.634
628500 | 1.EG +0.00 | 728.634
628501 | 1.EG +0.00 | 728.634
628502 | 1.EG +0.00 | 728.634
628503 | 1.EG +0.00 | 728.634
628504 | 1.EG +0.00 | 728.634
628505 | 1.EG +0.00 | 728.634
628506 | 1.EG +0.00 | 1000
628507 | 1.EG +0.00 | 1000
628508 | 1.EG +0.00 | 1100
628509 | 1.EG +0.00 | 1100
628510 | 1.EG +0.00 | 1150
628511 | 1.EG +0.00 | 1125
628512 | 1.EG +0.00 | 1150
628513 | 1.EG +0.00 | 1125
628514 | 1.EG +0.00 | 1125
628515 | 1.EG +0.00 | 1125
628516 | 1.EG +0.00 | 1125
628517 | 1.EG +0.00 | 1125
628552 | 1.EG +0.00 | 728.634
628553 | 1.EG +0.00 | 728.634
628554 | 1.EG +0.00 | 753.634
628555 | 1.EG +0.00 | 728.634
628556 | 1.EG +0.00 | 753.634
628557 | 1.EG +0.00 | 728.634
628558 | 1.EG +0.00 | 728.634
628559 | 1.EG +0.00 | 728.634
628560 | 1.EG +0.00 | 728.634
628561 | 1.EG +0.00 | 728.634
628562 | 1.EG +0.00 | 1000
628563 | 1.EG +0.00 | 1100
628564 | 1.EG +0.00 | 1150
628565 | 1.EG +0.00 | 1125
628566 | 1.EG +0.00 | 1125
628567 | 1.EG +0.00 | 1125
628457 | 1.EG +0.00 | 701.034
628458 | 1.EG +0.00 | 825
628459 | 1.EG +0.00 | 1000
628460 | 1.EG +0.00 | 800
628518 | 1.EG +0.00 | 825
628519 | 1.EG +0.00 | 677.068
628520 | 1.EG +0.00 | 702.072
628521 | 1.EG +0.00 | 726.036
628522 | 1.EG +0.00 | 1100
628523 | 1.EG +0.00 | 800
628524 | 1.EG +0.00 | 800
628525 | 1.EG +0.00 | 1000
628526 | 1.EG +0.00 | 1100
628527 | 1.EG +0.00 | 800
628528 | 1.EG +0.00 | 702.072
628529 | 1.EG +0.00 | 726.036
628530 | 1.EG +0.00 | 825
628531 | 1.EG +0.00 | 677.068
628532 | 1.EG +0.00 | 701.034
628533 | 1.EG +0.00 | 825
628534 | 1.EG +0.00 | 677.068
628535 | 1.EG +0.00 | 701.034
628536 | 1.EG +0.00 | 1000
628537 | 1.EG +0.00 | 1100
628538 | 1.EG +0.00 | 800
628539 | 1.EG +0.00 | 825
628540 | 1.EG +0.00 | 800
628541 | 1.EG +0.00 | 800
618361 | 1.EG +0.00 | 712
618362 | 1.EG +0.00 | 712
618363 | 1.EG +0.00 | 712
618364 | 1.EG +0.00 | 1700
618365 | 1.EG +0.00 | 1700
618366 | 1.EG +0.00 | 1450
618367 | 1.EG +0.00 | 1700
618368 | 1.EG +0.00 | 1700
618369 | 1.EG +0.00 | 1700
618370 | 1.EG +0.00 | 712
618375 | 1.EG +0.00 | 712
618376 | 1.EG +0.00 | 712
618377 | 1.EG +0.00 | 712
618378 | 1.EG +0.00 | 712
618379 | 1.EG +0.00 | 1700
618380 | 1.EG +0.00 | 1700
618381 | 1.EG +0.00 | 1700
618385 | 1.EG +0.00 | 1700
618386 | 1.EG +0.00 | 1700
618387 | 1.EG +0.00 | 1700
618388 | 1.EG +0.00 | 712
618389 | 1.EG +0.00 | 712
624251 | 1.EG +0.00 | 1700
624252 | 1.EG +0.00 | 1700
624253 | 1.EG +0.00 | 1700
624254 | 1.EG +0.00 | 1700
624255 | 1.EG +0.00 | 1700
624256 | 1.EG +0.00 | 1700
624257 | 1.EG +0.00 | 1700
624258 | 1.EG +0.00 | 1700
624259 | 1.EG +0.00 | 1700
624260 | 1.EG +0.00 | 1700
624261 | 1.EG +0.00 | 1700
624262 | 1.EG +0.00 | 1700
624263 | 1.EG +0.00 | 1700
624264 | 1.EG +0.00 | 1700
624265 | 1.EG +0.00 | 1700
624266 | 1.EG +0.00 | 1700
624267 | 1.EG +0.00 | 1700
624268 | 1.EG +0.00 | 1450
624269 | 1.EG +0.00 | 1700
624270 | 1.EG +0.00 | 1700
624271 | 1.EG +0.00 | 1700
624272 | 1.EG +0.00 | 1700
624273 | 1.EG +0.00 | 1700
624274 | 1.EG +0.00 | 1700
624275 | 1.EG +0.00 | 1700
624276 | 1.EG +0.00 | 1700
624277 | 1.EG +0.00 | 1450
624278 | 1.EG +0.00 | 712
624279 | 1.EG +0.00 | 712
624280 | 1.EG +0.00 | 712
624281 | 1.EG +0.00 | 712
624282 | 1.EG +0.00 | 712
624283 | 1.EG +0.00 | 712
624284 | 1.EG +0.00 | 712
624285 | 1.EG +0.00 | 712
624286 | 1.EG +0.00 | 712
624287 | 1.EG +0.00 | 712
624288 | 1.EG +0.00 | 712
624289 | 1.EG +0.00 | 712
624290 | 1.EG +0.00 | 712
624291 | 1.EG +0.00 | 712
624292 | 1.EG +0.00 | 712
624293 | 1.EG +0.00 | 712
624294 | 1.EG +0.00 | 712
624295 | 1.EG +0.00 | 712
618396 | 1.EG +0.00 | 875.077
618397 | 1.EG +0.00 | 875.077
618398 | 1.EG +0.00 | 875.077
618399 | 1.EG +0.00 | 1700
618400 | 1.EG +0.00 | 1700
618401 | 1.EG +0.00 | 1450
618402 | 1.EG +0.00 | 1700
618403 | 1.EG +0.00 | 1700
618404 | 1.EG +0.00 | 1700
618405 | 1.EG +0.00 | 875.077
618410 | 1.EG +0.00 | 875.077
618411 | 1.EG +0.00 | 875.077
618412 | 1.EG +0.00 | 875.077
618413 | 1.EG +0.00 | 875.077
618414 | 1.EG +0.00 | 1700
618415 | 1.EG +0.00 | 1700
618416 | 1.EG +0.00 | 1700
618420 | 1.EG +0.00 | 1700
618421 | 1.EG +0.00 | 1700
618422 | 1.EG +0.00 | 1700
618423 | 1.EG +0.00 | 875.077
618424 | 1.EG +0.00 | 875.077
624296 | 1.EG +0.00 | 1700
624297 | 1.EG +0.00 | 1700
624298 | 1.EG +0.00 | 1700
624299 | 1.EG +0.00 | 1700
624300 | 1.EG +0.00 | 1700
624301 | 1.EG +0.00 | 1700
624302 | 1.EG +0.00 | 1700
624303 | 1.EG +0.00 | 1700
624304 | 1.EG +0.00 | 1700
624305 | 1.EG +0.00 | 1700
624306 | 1.EG +0.00 | 1700
624307 | 1.EG +0.00 | 1700
624308 | 1.EG +0.00 | 1700
624309 | 1.EG +0.00 | 1700
624310 | 1.EG +0.00 | 1700
624311 | 1.EG +0.00 | 1700
624312 | 1.EG +0.00 | 1700
624313 | 1.EG +0.00 | 1450
624314 | 1.EG +0.00 | 1700
624315 | 1.EG +0.00 | 1700
624316 | 1.EG +0.00 | 1700
624317 | 1.EG +0.00 | 1700
624318 | 1.EG +0.00 | 1700
624319 | 1.EG +0.00 | 1700
624320 | 1.EG +0.00 | 1700
624321 | 1.EG +0.00 | 1700
624322 | 1.EG +0.00 | 1450
624323 | 1.EG +0.00 | 875.077
624324 | 1.EG +0.00 | 875.077
624325 | 1.EG +0.00 | 875.077
624326 | 1.EG +0.00 | 875.077
624327 | 1.EG +0.00 | 875.077
624328 | 1.EG +0.00 | 875.077
624329 | 1.EG +0.00 | 875.077
624330 | 1.EG +0.00 | 875.077
624331 | 1.EG +0.00 | 875.077
624332 | 1.EG +0.00 | 875.077
624333 | 1.EG +0.00 | 875.077
624334 | 1.EG +0.00 | 875.077
624335 | 1.EG +0.00 | 875.077
624336 | 1.EG +0.00 | 875.077
624337 | 1.EG +0.00 | 875.077
624338 | 1.EG +0.00 | 875.077
624339 | 1.EG +0.00 | 875.077
624340 | 1.EG +0.00 | 875.077
618431 | 1.EG +0.00 | 713.127
618432 | 1.EG +0.00 | 713.127
618433 | 1.EG +0.00 | 713.127
618434 | 1.EG +0.00 | 1700
618435 | 1.EG +0.00 | 1700
618436 | 1.EG +0.00 | 1450
618437 | 1.EG +0.00 | 1700
618438 | 1.EG +0.00 | 1700
618439 | 1.EG +0.00 | 1700
618440 | 1.EG +0.00 | 713.127
618445 | 1.EG +0.00 | 713.127
618446 | 1.EG +0.00 | 713.127
618447 | 1.EG +0.00 | 713.127
618448 | 1.EG +0.00 | 713.127
618449 | 1.EG +0.00 | 1700
618450 | 1.EG +0.00 | 1700
618451 | 1.EG +0.00 | 1700
618455 | 1.EG +0.00 | 1700
618456 | 1.EG +0.00 | 1700
618457 | 1.EG +0.00 | 1700
618458 | 1.EG +0.00 | 713.127
618459 | 1.EG +0.00 | 713.127
624341 | 1.EG +0.00 | 1700
624342 | 1.EG +0.00 | 1700
624343 | 1.EG +0.00 | 1700
624344 | 1.EG +0.00 | 1700
624345 | 1.EG +0.00 | 1700
624346 | 1.EG +0.00 | 1700
624347 | 1.EG +0.00 | 1700
624348 | 1.EG +0.00 | 1700
624349 | 1.EG +0.00 | 1700
624350 | 1.EG +0.00 | 1700
624351 | 1.EG +0.00 | 1700
624352 | 1.EG +0.00 | 1700
624353 | 1.EG +0.00 | 1700
624354 | 1.EG +0.00 | 1700
624355 | 1.EG +0.00 | 1700
624356 | 1.EG +0.00 | 1700
624357 | 1.EG +0.00 | 1700
624358 | 1.EG +0.00 | 1450
624359 | 1.EG +0.00 | 1700
624360 | 1.EG +0.00 | 1700
624361 | 1.EG +0.00 | 1700
624362 | 1.EG +0.00 | 1700
624363 | 1.EG +0.00 | 1700
624364 | 1.EG +0.00 | 1700
624365 | 1.EG +0.00 | 1700
624366 | 1.EG +0.00 | 1700
624367 | 1.EG +0.00 | 1450
624368 | 1.EG +0.00 | 713.127
624369 | 1.EG +0.00 | 713.127
624370 | 1.EG +0.00 | 713.127
624371 | 1.EG +0.00 | 713.127
624372 | 1.EG +0.00 | 713.127
624373 | 1.EG +0.00 | 713.127
624374 | 1.EG +0.00 | 713.127
624375 | 1.EG +0.00 | 713.127
624376 | 1.EG +0.00 | 713.127
624377 | 1.EG +0.00 | 713.127
624378 | 1.EG +0.00 | 713.127
624379 | 1.EG +0.00 | 713.127
624380 | 1.EG +0.00 | 713.127
624381 | 1.EG +0.00 | 713.127
624382 | 1.EG +0.00 | 713.127
624383 | 1.EG +0.00 | 713.127
624384 | 1.EG +0.00 | 713.127
624385 | 1.EG +0.00 | 713.127
618676 | 1.EG +0.00 | 750
618677 | 1.EG +0.00 | 750
618678 | 1.EG +0.00 | 760
618679 | 1.EG +0.00 | 785
618680 | 1.EG +0.00 | 775
618681 | 1.EG +0.00 | 760
618682 | 1.EG +0.00 | 2950
618683 | 1.EG +0.00 | 1350
618684 | 1.EG +0.00 | 1350
618685 | 1.EG +0.00 | 2950
618686 | 1.EG +0.00 | 750
618687 | 1.EG +0.00 | 760
618688 | 1.EG +0.00 | 2950
618689 | 1.EG +0.00 | 1375
618690 | 1.EG +0.00 | 1350
618691 | 1.EG +0.00 | 1350
618692 | 1.EG +0.00 | 785
618705 | 1.EG +0.00 | 785
618706 | 1.EG +0.00 | 750
618707 | 1.EG +0.00 | 750
618708 | 1.EG +0.00 | 655
618709 | 1.EG +0.00 | 775
618710 | 1.EG +0.00 | 775
618711 | 1.EG +0.00 | 655
618712 | 1.EG +0.00 | 775
618713 | 1.EG +0.00 | 750
618714 | 1.EG +0.00 | 750
618715 | 1.EG +0.00 | 655
618716 | 1.EG +0.00 | 750
618717 | 1.EG +0.00 | 2950
618718 | 1.EG +0.00 | 2950
618719 | 1.EG +0.00 | 2950
618720 | 1.EG +0.00 | 1350
618721 | 1.EG +0.00 | 1350
618722 | 1.EG +0.00 | 1375
618723 | 1.EG +0.00 | 1350
618724 | 1.EG +0.00 | 2950
618779 | 1.EG +0.00 | 671.124
618780 | 1.EG +0.00 | 675
618781 | 1.EG +0.00 | 1546.12
618782 | 1.EG +0.00 | 675
618783 | 1.EG +0.00 | 1546.12
618784 | 1.EG +0.00 | 671.124
618785 | 1.EG +0.00 | 2000
618786 | 1.EG +0.00 | 2000
618787 | 1.EG +0.00 | 2000
618788 | 1.EG +0.00 | 2000
618789 | 1.EG +0.00 | 2000
625049 | 4.3OG +15.90 | 800
625050 | 4.3OG +15.90 | 1000
625051 | 4.3OG +15.90 | 1450
625080 | 4.3OG +15.90 | 800
625081 | 4.3OG +15.90 | 800
625082 | 4.3OG +15.90 | 800
625083 | 4.3OG +15.90 | 800
625084 | 4.3OG +15.90 | 800
625085 | 4.3OG +15.90 | 800
625086 | 4.3OG +15.90 | 800
625087 | 4.3OG +15.90 | 800
625088 | 4.3OG +15.90 | 800
625089 | 4.3OG +15.90 | 800
625090 | 4.3OG +15.90 | 800
625091 | 4.3OG +15.90 | 400.46
625092 | 4.3OG +15.90 | 1500
625093 | 4.3OG +15.90 | 1450
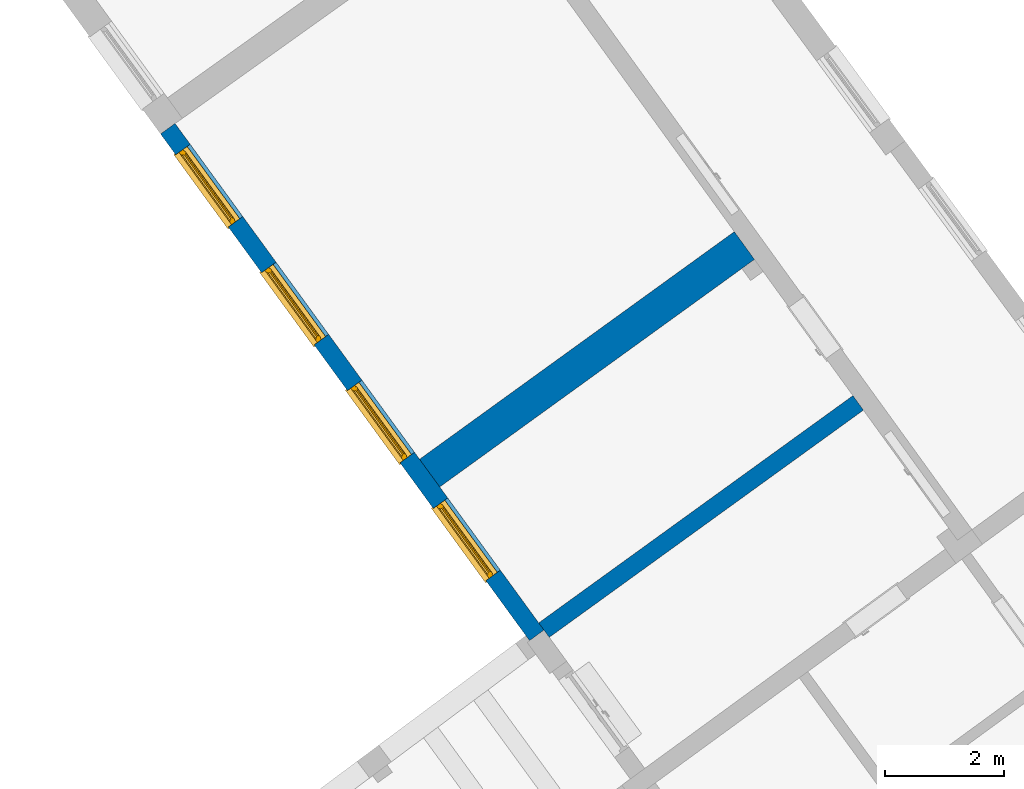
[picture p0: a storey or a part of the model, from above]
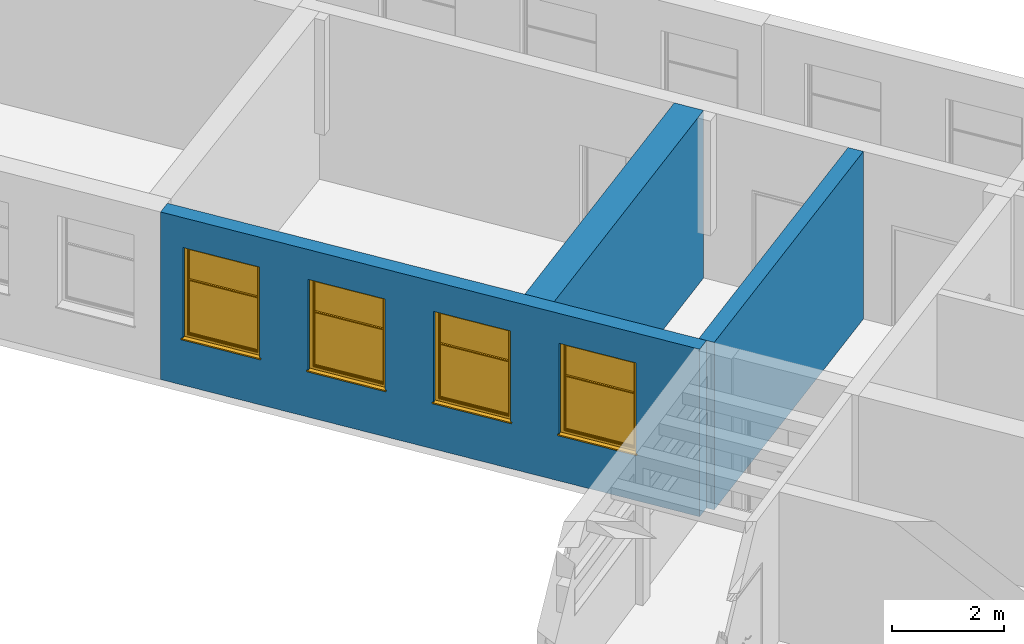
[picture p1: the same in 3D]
Properties of the parts of a building model (IFC2X3), part 4 of 13

# IfcMember: Rectangular Mullion:5x5 (2701)
Name (Rectangular Mullion:5x5:...) | In | Span (mm)
625094 | 4.3OG +15.90 | 700
625095 | 4.3OG +15.90 | 1500
625096 | 4.3OG +15.90 | 800
625097 | 4.3OG +15.90 | 800
625098 | 4.3OG +15.90 | 800
625099 | 4.3OG +15.90 | 800
625100 | 4.3OG +15.90 | 800
625101 | 4.3OG +15.90 | 800
625102 | 4.3OG +15.90 | 400.46
625103 | 4.3OG +15.90 | 800
625104 | 4.3OG +15.90 | 800
625105 | 4.3OG +15.90 | 800
625106 | 4.3OG +15.90 | 800
625107 | 4.3OG +15.90 | 800
625108 | 4.3OG +15.90 | 800
625109 | 4.3OG +15.90 | 400.46
625110 | 4.3OG +15.90 | 1000
625111 | 4.3OG +15.90 | 1000
625112 | 4.3OG +15.90 | 1000
625113 | 4.3OG +15.90 | 1000
625114 | 4.3OG +15.90 | 1000
625115 | 4.3OG +15.90 | 1000
625116 | 4.3OG +15.90 | 1500
625117 | 4.3OG +15.90 | 1500
625118 | 4.3OG +15.90 | 1500
625119 | 4.3OG +15.90 | 1500
625120 | 4.3OG +15.90 | 1500
625121 | 4.3OG +15.90 | 1500
625122 | 4.3OG +15.90 | 1450
625123 | 4.3OG +15.90 | 1450
625124 | 4.3OG +15.90 | 1450
625125 | 4.3OG +15.90 | 1450
625126 | 4.3OG +15.90 | 1450
625127 | 4.3OG +15.90 | 1450
625128 | 4.3OG +15.90 | 400.46
625289 | 4.3OG +15.90 | 700
625290 | 4.3OG +15.90 | 1000
625291 | 4.3OG +15.90 | 700
625292 | 4.3OG +15.90 | 700
625293 | 4.3OG +15.90 | 700
625294 | 4.3OG +15.90 | 700
625295 | 4.3OG +15.90 | 700
625296 | 4.3OG +15.90 | 700
625297 | 4.3OG +15.90 | 800
625298 | 4.3OG +15.90 | 800
625299 | 4.3OG +15.90 | 800
625300 | 4.3OG +15.90 | 800
625301 | 4.3OG +15.90 | 800
625302 | 4.3OG +15.90 | 800
625303 | 4.3OG +15.90 | 400.46
625306 | 4.3OG +15.90 | 175
625307 | 4.3OG +15.90 | 350.028
625308 | 4.3OG +15.90 | 1000
625309 | 4.3OG +15.90 | 850
625310 | 4.3OG +15.90 | 1300
625311 | 4.3OG +15.90 | 850
625396 | 4.3OG +15.90 | 1000
625397 | 4.3OG +15.90 | 800
625398 | 4.3OG +15.90 | 800
625399 | 4.3OG +15.90 | 800
625400 | 4.3OG +15.90 | 800
625401 | 4.3OG +15.90 | 800
625402 | 4.3OG +15.90 | 800
625403 | 4.3OG +15.90 | 800
625404 | 4.3OG +15.90 | 800
625405 | 4.3OG +15.90 | 675.717
625406 | 4.3OG +15.90 | 1500
625407 | 4.3OG +15.90 | 1300
625408 | 4.3OG +15.90 | 700
625409 | 4.3OG +15.90 | 1500
625410 | 4.3OG +15.90 | 175
625411 | 4.3OG +15.90 | 800
625412 | 4.3OG +15.90 | 800
625413 | 4.3OG +15.90 | 800
625414 | 4.3OG +15.90 | 800
625415 | 4.3OG +15.90 | 800
625416 | 4.3OG +15.90 | 800
625417 | 4.3OG +15.90 | 800
625418 | 4.3OG +15.90 | 800
625419 | 4.3OG +15.90 | 675.717
625420 | 4.3OG +15.90 | 175
625421 | 4.3OG +15.90 | 1000
625422 | 4.3OG +15.90 | 800
625423 | 4.3OG +15.90 | 800
625424 | 4.3OG +15.90 | 800
625425 | 4.3OG +15.90 | 800
625426 | 4.3OG +15.90 | 800
625427 | 4.3OG +15.90 | 800
625428 | 4.3OG +15.90 | 800
625429 | 4.3OG +15.90 | 800
625430 | 4.3OG +15.90 | 675.717
625431 | 4.3OG +15.90 | 1000
625432 | 4.3OG +15.90 | 1000
625433 | 4.3OG +15.90 | 1000
625434 | 4.3OG +15.90 | 1000
625435 | 4.3OG +15.90 | 1000
625436 | 4.3OG +15.90 | 1000
625437 | 4.3OG +15.90 | 1000
625438 | 4.3OG +15.90 | 1000
625439 | 4.3OG +15.90 | 1000
625440 | 4.3OG +15.90 | 1000
625441 | 4.3OG +15.90 | 1500
625442 | 4.3OG +15.90 | 1500
625443 | 4.3OG +15.90 | 1500
625444 | 4.3OG +15.90 | 1500
625445 | 4.3OG +15.90 | 1500
625446 | 4.3OG +15.90 | 1500
625447 | 4.3OG +15.90 | 1500
625448 | 4.3OG +15.90 | 1500
625449 | 4.3OG +15.90 | 1500
625450 | 4.3OG +15.90 | 1500
625451 | 4.3OG +15.90 | 1300
625452 | 4.3OG +15.90 | 1300
625453 | 4.3OG +15.90 | 1300
625454 | 4.3OG +15.90 | 1300
625455 | 4.3OG +15.90 | 1300
625456 | 4.3OG +15.90 | 1300
625457 | 4.3OG +15.90 | 1300
625458 | 4.3OG +15.90 | 1300
625459 | 4.3OG +15.90 | 1300
625534 | 4.3OG +15.90 | 700
625535 | 4.3OG +15.90 | 1000
625536 | 4.3OG +15.90 | 700
625537 | 4.3OG +15.90 | 700
625538 | 4.3OG +15.90 | 700
625539 | 4.3OG +15.90 | 700
625540 | 4.3OG +15.90 | 700
625541 | 4.3OG +15.90 | 700
625542 | 4.3OG +15.90 | 700
625543 | 4.3OG +15.90 | 700
625544 | 4.3OG +15.90 | 700
625545 | 4.3OG +15.90 | 700
625546 | 4.3OG +15.90 | 175
625547 | 4.3OG +15.90 | 800
625548 | 4.3OG +15.90 | 800
625549 | 4.3OG +15.90 | 800
625550 | 4.3OG +15.90 | 800
625551 | 4.3OG +15.90 | 800
625552 | 4.3OG +15.90 | 800
625553 | 4.3OG +15.90 | 800
625554 | 4.3OG +15.90 | 800
625555 | 4.3OG +15.90 | 675.717
625585 | 4.3OG +15.90 | 1300
629028 | 4.3OG +15.90 | 675.717
629029 | 4.3OG +15.90 | 50.4599
629030 | 4.3OG +15.90 | 175
629031 | 4.3OG +15.90 | 1000
629032 | 4.3OG +15.90 | 800
629033 | 4.3OG +15.90 | 800
629034 | 4.3OG +15.90 | 800
629035 | 4.3OG +15.90 | 800
629036 | 4.3OG +15.90 | 800
629037 | 4.3OG +15.90 | 299.512
629038 | 4.3OG +15.90 | 800
629039 | 4.3OG +15.90 | 800
625356 | 4.3OG +15.90 | 526.258
625357 | 4.3OG +15.90 | 800
625358 | 4.3OG +15.90 | 1000
625359 | 4.3OG +15.90 | 1300
625460 | 4.3OG +15.90 | 800
625461 | 4.3OG +15.90 | 800
625462 | 4.3OG +15.90 | 800
625463 | 4.3OG +15.90 | 800
625464 | 4.3OG +15.90 | 800
625465 | 4.3OG +15.90 | 800
625466 | 4.3OG +15.90 | 800
625467 | 4.3OG +15.90 | 800
625468 | 4.3OG +15.90 | 800
625469 | 4.3OG +15.90 | 800
625470 | 4.3OG +15.90 | 800
625471 | 4.3OG +15.90 | 800
625472 | 4.3OG +15.90 | 800
625473 | 4.3OG +15.90 | 800
625474 | 4.3OG +15.90 | 800
625475 | 4.3OG +15.90 | 526.258
625476 | 4.3OG +15.90 | 1500
625477 | 4.3OG +15.90 | 1300
625478 | 4.3OG +15.90 | 700
625479 | 4.3OG +15.90 | 1500
625480 | 4.3OG +15.90 | 800
625481 | 4.3OG +15.90 | 800
625482 | 4.3OG +15.90 | 800
625483 | 4.3OG +15.90 | 800
625484 | 4.3OG +15.90 | 800
625485 | 4.3OG +15.90 | 800
625486 | 4.3OG +15.90 | 800
625487 | 4.3OG +15.90 | 800
625488 | 4.3OG +15.90 | 526.258
625489 | 4.3OG +15.90 | 800
625490 | 4.3OG +15.90 | 800
625491 | 4.3OG +15.90 | 800
625492 | 4.3OG +15.90 | 800
625493 | 4.3OG +15.90 | 800
625494 | 4.3OG +15.90 | 800
625495 | 4.3OG +15.90 | 800
625496 | 4.3OG +15.90 | 800
625497 | 4.3OG +15.90 | 526.258
625498 | 4.3OG +15.90 | 1000
625499 | 4.3OG +15.90 | 1000
625500 | 4.3OG +15.90 | 1000
625501 | 4.3OG +15.90 | 1000
625502 | 4.3OG +15.90 | 1000
625503 | 4.3OG +15.90 | 1000
625504 | 4.3OG +15.90 | 1000
625505 | 4.3OG +15.90 | 1000
625506 | 4.3OG +15.90 | 1500
625507 | 4.3OG +15.90 | 1500
625508 | 4.3OG +15.90 | 1500
625509 | 4.3OG +15.90 | 1500
625510 | 4.3OG +15.90 | 1500
625511 | 4.3OG +15.90 | 1500
625512 | 4.3OG +15.90 | 1500
625513 | 4.3OG +15.90 | 1500
625514 | 4.3OG +15.90 | 1300
625515 | 4.3OG +15.90 | 1300
625516 | 4.3OG +15.90 | 1300
625517 | 4.3OG +15.90 | 1300
625518 | 4.3OG +15.90 | 1300
625519 | 4.3OG +15.90 | 1300
625520 | 4.3OG +15.90 | 1300
625521 | 4.3OG +15.90 | 1300
625566 | 4.3OG +15.90 | 700
625567 | 4.3OG +15.90 | 1000
625568 | 4.3OG +15.90 | 700
625569 | 4.3OG +15.90 | 700
625570 | 4.3OG +15.90 | 700
625571 | 4.3OG +15.90 | 700
625572 | 4.3OG +15.90 | 700
625573 | 4.3OG +15.90 | 700
625574 | 4.3OG +15.90 | 700
625575 | 4.3OG +15.90 | 700
625576 | 4.3OG +15.90 | 800
625577 | 4.3OG +15.90 | 800
625578 | 4.3OG +15.90 | 800
625579 | 4.3OG +15.90 | 800
625580 | 4.3OG +15.90 | 800
625581 | 4.3OG +15.90 | 800
625582 | 4.3OG +15.90 | 800
625583 | 4.3OG +15.90 | 800
625584 | 4.3OG +15.90 | 526.258
622089 | 6.EG KH -1.15 | 384.588
622090 | 6.EG KH -1.15 | 375
622091 | 6.EG KH -1.15 | 1550
622092 | 6.EG KH -1.15 | 350.028
622093 | 6.EG KH -1.15 | 750
622094 | 6.EG KH -1.15 | 375
622095 | 6.EG KH -1.15 | 1550
622096 | 6.EG KH -1.15 | 350
622097 | 6.EG KH -1.15 | 750
622098 | 6.EG KH -1.15 | 800
622099 | 6.EG KH -1.15 | 2150
622100 | 6.EG KH -1.15 | 950
622101 | 6.EG KH -1.15 | 2150
622102 | 6.EG KH -1.15 | 2150
622103 | 6.EG KH -1.15 | 2150
622110 | 6.EG KH -1.15 | 950
622111 | 6.EG KH -1.15 | 2150
622112 | 6.EG KH -1.15 | 950
622113 | 6.EG KH -1.15 | 950
622114 | 6.EG KH -1.15 | 950
622115 | 6.EG KH -1.15 | 375
622116 | 6.EG KH -1.15 | 1550
622117 | 6.EG KH -1.15 | 350
622118 | 6.EG KH -1.15 | 750
622119 | 6.EG KH -1.15 | 800
622124 | 6.EG KH -1.15 | 800
622125 | 6.EG KH -1.15 | 384.588
622126 | 6.EG KH -1.15 | 384.588
622127 | 6.EG KH -1.15 | 2150
622128 | 6.EG KH -1.15 | 950
624470 | 4.3OG +15.90 | 53.7897
624471 | 4.3OG +15.90 | 150
624472 | 4.3OG +15.90 | 200
624473 | 4.3OG +15.90 | 200
624474 | 4.3OG +15.90 | 200
624475 | 4.3OG +15.90 | 150
624476 | 4.3OG +15.90 | 200
624477 | 4.3OG +15.90 | 200
624478 | 4.3OG +15.90 | 200
624479 | 4.3OG +15.90 | 200
624480 | 4.3OG +15.90 | 1350
624481 | 4.3OG +15.90 | 1350
624482 | 4.3OG +15.90 | 1350
624483 | 4.3OG +15.90 | 1350
624484 | 4.3OG +15.90 | 1350
624485 | 4.3OG +15.90 | 1350
624765 | 4.3OG +15.90 | 200
624766 | 4.3OG +15.90 | 200
624767 | 4.3OG +15.90 | 200
624768 | 4.3OG +15.90 | 200
624769 | 4.3OG +15.90 | 200
624770 | 4.3OG +15.90 | 200
624771 | 4.3OG +15.90 | 200
624772 | 4.3OG +15.90 | 200
624773 | 4.3OG +15.90 | 200
624774 | 4.3OG +15.90 | 200
624775 | 4.3OG +15.90 | 200
624776 | 4.3OG +15.90 | 200
624777 | 4.3OG +15.90 | 200
624778 | 4.3OG +15.90 | 200
624779 | 4.3OG +15.90 | 200
624780 | 4.3OG +15.90 | 200
624781 | 4.3OG +15.90 | 200
624782 | 4.3OG +15.90 | 200
624783 | 4.3OG +15.90 | 200
624784 | 4.3OG +15.90 | 200
624785 | 4.3OG +15.90 | 200
624786 | 4.3OG +15.90 | 200
624787 | 4.3OG +15.90 | 200
624788 | 4.3OG +15.90 | 200
624789 | 4.3OG +15.90 | 200
624790 | 4.3OG +15.90 | 200
624791 | 4.3OG +15.90 | 200
624792 | 4.3OG +15.90 | 200
624793 | 4.3OG +15.90 | 200
624794 | 4.3OG +15.90 | 200
624795 | 4.3OG +15.90 | 200
624796 | 4.3OG +15.90 | 200
624797 | 4.3OG +15.90 | 200
624798 | 4.3OG +15.90 | 200
624799 | 4.3OG +15.90 | 200
624800 | 4.3OG +15.90 | 53.7897
624801 | 4.3OG +15.90 | 1350
624802 | 4.3OG +15.90 | 1350
624803 | 4.3OG +15.90 | 1350
624804 | 4.3OG +15.90 | 1350
624805 | 4.3OG +15.90 | 1350
624806 | 4.3OG +15.90 | 1350
624807 | 4.3OG +15.90 | 1350
624808 | 4.3OG +15.90 | 1350
624809 | 4.3OG +15.90 | 1350
624810 | 4.3OG +15.90 | 1350
624811 | 4.3OG +15.90 | 1350
624812 | 4.3OG +15.90 | 1350
624813 | 4.3OG +15.90 | 1350
624814 | 4.3OG +15.90 | 1350
624815 | 4.3OG +15.90 | 1350
624816 | 4.3OG +15.90 | 1350
624817 | 4.3OG +15.90 | 1350
624818 | 4.3OG +15.90 | 1350
624496 | 4.3OG +15.90 | 200
624497 | 4.3OG +15.90 | 200
624498 | 4.3OG +15.90 | 200
624499 | 4.3OG +15.90 | 200
624500 | 4.3OG +15.90 | 200
624501 | 4.3OG +15.90 | 200
624502 | 4.3OG +15.90 | 200
624503 | 4.3OG +15.90 | 200
624504 | 4.3OG +15.90 | 200
624505 | 4.3OG +15.90 | 1350
624506 | 4.3OG +15.90 | 1350
624507 | 4.3OG +15.90 | 1350
624508 | 4.3OG +15.90 | 1350
624509 | 4.3OG +15.90 | 1350
624510 | 4.3OG +15.90 | 1350
624819 | 4.3OG +15.90 | 200
624820 | 4.3OG +15.90 | 200
624821 | 4.3OG +15.90 | 200
624822 | 4.3OG +15.90 | 200
624823 | 4.3OG +15.90 | 200
624824 | 4.3OG +15.90 | 200
624825 | 4.3OG +15.90 | 200
624826 | 4.3OG +15.90 | 200
624827 | 4.3OG +15.90 | 200
624828 | 4.3OG +15.90 | 200
624829 | 4.3OG +15.90 | 200
624830 | 4.3OG +15.90 | 200
624831 | 4.3OG +15.90 | 200
624832 | 4.3OG +15.90 | 200
624833 | 4.3OG +15.90 | 200
624834 | 4.3OG +15.90 | 200
624835 | 4.3OG +15.90 | 200
624836 | 4.3OG +15.90 | 200
624837 | 4.3OG +15.90 | 200
624838 | 4.3OG +15.90 | 200
624839 | 4.3OG +15.90 | 200
624840 | 4.3OG +15.90 | 200
624841 | 4.3OG +15.90 | 200
624842 | 4.3OG +15.90 | 200
624843 | 4.3OG +15.90 | 200
624844 | 4.3OG +15.90 | 200
624845 | 4.3OG +15.90 | 200
624846 | 4.3OG +15.90 | 200
624847 | 4.3OG +15.90 | 200
624848 | 4.3OG +15.90 | 200
624849 | 4.3OG +15.90 | 200
624850 | 4.3OG +15.90 | 200
624851 | 4.3OG +15.90 | 200
624852 | 4.3OG +15.90 | 200
624853 | 4.3OG +15.90 | 200
624854 | 4.3OG +15.90 | 1350
624855 | 4.3OG +15.90 | 1350
624856 | 4.3OG +15.90 | 1350
624857 | 4.3OG +15.90 | 1350
624858 | 4.3OG +15.90 | 1350
624859 | 4.3OG +15.90 | 1350
624860 | 4.3OG +15.90 | 1350
624861 | 4.3OG +15.90 | 1350
624862 | 4.3OG +15.90 | 1350
624863 | 4.3OG +15.90 | 1350
624864 | 4.3OG +15.90 | 1350
624865 | 4.3OG +15.90 | 1350
624866 | 4.3OG +15.90 | 1350
624867 | 4.3OG +15.90 | 1350
624868 | 4.3OG +15.90 | 1350
624869 | 4.3OG +15.90 | 1350
624870 | 4.3OG +15.90 | 1350
624871 | 4.3OG +15.90 | 1350
624522 | 4.3OG +15.90 | 200
624523 | 4.3OG +15.90 | 200
624524 | 4.3OG +15.90 | 200
624525 | 4.3OG +15.90 | 200
624526 | 4.3OG +15.90 | 200
624527 | 4.3OG +15.90 | 200
624528 | 4.3OG +15.90 | 200
624529 | 4.3OG +15.90 | 200
624530 | 4.3OG +15.90 | 200
624531 | 4.3OG +15.90 | 1350
624532 | 4.3OG +15.90 | 1350
624533 | 4.3OG +15.90 | 1350
624534 | 4.3OG +15.90 | 1350
624535 | 4.3OG +15.90 | 1350
624536 | 4.3OG +15.90 | 1350
624872 | 4.3OG +15.90 | 200
624873 | 4.3OG +15.90 | 200
624874 | 4.3OG +15.90 | 200
624875 | 4.3OG +15.90 | 200
624876 | 4.3OG +15.90 | 200
624877 | 4.3OG +15.90 | 200
624878 | 4.3OG +15.90 | 200
624879 | 4.3OG +15.90 | 200
624880 | 4.3OG +15.90 | 200
624881 | 4.3OG +15.90 | 200
624882 | 4.3OG +15.90 | 200
624883 | 4.3OG +15.90 | 200
624884 | 4.3OG +15.90 | 200
624885 | 4.3OG +15.90 | 200
624886 | 4.3OG +15.90 | 200
624887 | 4.3OG +15.90 | 200
624888 | 4.3OG +15.90 | 200
624889 | 4.3OG +15.90 | 200
624890 | 4.3OG +15.90 | 200
624891 | 4.3OG +15.90 | 200
624892 | 4.3OG +15.90 | 200
624893 | 4.3OG +15.90 | 200
624894 | 4.3OG +15.90 | 200
624895 | 4.3OG +15.90 | 200
624896 | 4.3OG +15.90 | 200
624897 | 4.3OG +15.90 | 200
624898 | 4.3OG +15.90 | 200
624899 | 4.3OG +15.90 | 200
624900 | 4.3OG +15.90 | 200
624901 | 4.3OG +15.90 | 200
624902 | 4.3OG +15.90 | 200
624903 | 4.3OG +15.90 | 200
624904 | 4.3OG +15.90 | 200
624905 | 4.3OG +15.90 | 200
624906 | 4.3OG +15.90 | 200
624908 | 4.3OG +15.90 | 1350
624909 | 4.3OG +15.90 | 1350
624910 | 4.3OG +15.90 | 1350
624911 | 4.3OG +15.90 | 1350
624912 | 4.3OG +15.90 | 1350
624913 | 4.3OG +15.90 | 1350
624914 | 4.3OG +15.90 | 1350
624915 | 4.3OG +15.90 | 1350
624916 | 4.3OG +15.90 | 1350
624917 | 4.3OG +15.90 | 1350
624918 | 4.3OG +15.90 | 1350
624919 | 4.3OG +15.90 | 1350
624920 | 4.3OG +15.90 | 1350
624921 | 4.3OG +15.90 | 1350
624922 | 4.3OG +15.90 | 1350
624923 | 4.3OG +15.90 | 1350
624924 | 4.3OG +15.90 | 1350
624925 | 4.3OG +15.90 | 1350
624548 | 4.3OG +15.90 | 150
624549 | 4.3OG +15.90 | 200
624550 | 4.3OG +15.90 | 200
624551 | 4.3OG +15.90 | 200
624552 | 4.3OG +15.90 | 150
624553 | 4.3OG +15.90 | 200
624554 | 4.3OG +15.90 | 200
624555 | 4.3OG +15.90 | 200
624556 | 4.3OG +15.90 | 200
624557 | 4.3OG +15.90 | 1900
624558 | 4.3OG +15.90 | 1900
624559 | 4.3OG +15.90 | 1900
624560 | 4.3OG +15.90 | 1900
624561 | 4.3OG +15.90 | 1900
624562 | 4.3OG +15.90 | 1900
624926 | 4.3OG +15.90 | 200
624927 | 4.3OG +15.90 | 200
624928 | 4.3OG +15.90 | 200
624929 | 4.3OG +15.90 | 200
624930 | 4.3OG +15.90 | 200
624931 | 4.3OG +15.90 | 200
624932 | 4.3OG +15.90 | 200
624933 | 4.3OG +15.90 | 200
624934 | 4.3OG +15.90 | 200
624935 | 4.3OG +15.90 | 200
624936 | 4.3OG +15.90 | 200
624937 | 4.3OG +15.90 | 200
624938 | 4.3OG +15.90 | 200
624939 | 4.3OG +15.90 | 200
624940 | 4.3OG +15.90 | 200
624941 | 4.3OG +15.90 | 200
624942 | 4.3OG +15.90 | 200
624943 | 4.3OG +15.90 | 200
624944 | 4.3OG +15.90 | 200
624945 | 4.3OG +15.90 | 200
624946 | 4.3OG +15.90 | 200
624947 | 4.3OG +15.90 | 200
624948 | 4.3OG +15.90 | 200
624949 | 4.3OG +15.90 | 200
624950 | 4.3OG +15.90 | 200
624951 | 4.3OG +15.90 | 200
624952 | 4.3OG +15.90 | 200
624953 | 4.3OG +15.90 | 200
624954 | 4.3OG +15.90 | 200
624955 | 4.3OG +15.90 | 200
624956 | 4.3OG +15.90 | 200
624957 | 4.3OG +15.90 | 200
624958 | 4.3OG +15.90 | 200
624959 | 4.3OG +15.90 | 200
624960 | 4.3OG +15.90 | 200
624962 | 4.3OG +15.90 | 1900
624963 | 4.3OG +15.90 | 1900
624964 | 4.3OG +15.90 | 1900
624965 | 4.3OG +15.90 | 1900
624966 | 4.3OG +15.90 | 1900
624967 | 4.3OG +15.90 | 1900
624968 | 4.3OG +15.90 | 1900
624969 | 4.3OG +15.90 | 1900
624970 | 4.3OG +15.90 | 1900
624971 | 4.3OG +15.90 | 1900
624972 | 4.3OG +15.90 | 1900
624973 | 4.3OG +15.90 | 1900
624974 | 4.3OG +15.90 | 1900
624975 | 4.3OG +15.90 | 1900
624976 | 4.3OG +15.90 | 1900
624977 | 4.3OG +15.90 | 1900
624978 | 4.3OG +15.90 | 1900
624979 | 4.3OG +15.90 | 1900
624573 | 4.3OG +15.90 | 14.5158
624574 | 4.3OG +15.90 | 150
624575 | 4.3OG +15.90 | 200
624576 | 4.3OG +15.90 | 200
624577 | 4.3OG +15.90 | 200
624578 | 4.3OG +15.90 | 150
624579 | 4.3OG +15.90 | 200
624580 | 4.3OG +15.90 | 200
624581 | 4.3OG +15.90 | 200
624582 | 4.3OG +15.90 | 200
624583 | 4.3OG +15.90 | 1900
624584 | 4.3OG +15.90 | 1900
624585 | 4.3OG +15.90 | 1900
624586 | 4.3OG +15.90 | 1900
624587 | 4.3OG +15.90 | 1900
624588 | 4.3OG +15.90 | 1900
624980 | 4.3OG +15.90 | 200
624981 | 4.3OG +15.90 | 200
624982 | 4.3OG +15.90 | 200
624983 | 4.3OG +15.90 | 200
624984 | 4.3OG +15.90 | 200
624985 | 4.3OG +15.90 | 200
624986 | 4.3OG +15.90 | 200
624987 | 4.3OG +15.90 | 200
624988 | 4.3OG +15.90 | 200
624989 | 4.3OG +15.90 | 200
624990 | 4.3OG +15.90 | 200
624991 | 4.3OG +15.90 | 200
624992 | 4.3OG +15.90 | 200
624993 | 4.3OG +15.90 | 200
624994 | 4.3OG +15.90 | 200
624995 | 4.3OG +15.90 | 200
624996 | 4.3OG +15.90 | 200
624997 | 4.3OG +15.90 | 200
624998 | 4.3OG +15.90 | 200
624999 | 4.3OG +15.90 | 200
625000 | 4.3OG +15.90 | 200
625001 | 4.3OG +15.90 | 200
625002 | 4.3OG +15.90 | 200
625003 | 4.3OG +15.90 | 200
625004 | 4.3OG +15.90 | 200
625005 | 4.3OG +15.90 | 200
625006 | 4.3OG +15.90 | 200
625007 | 4.3OG +15.90 | 200
625008 | 4.3OG +15.90 | 200
625009 | 4.3OG +15.90 | 200
625010 | 4.3OG +15.90 | 200
625011 | 4.3OG +15.90 | 14.5158
625012 | 4.3OG +15.90 | 1900
625013 | 4.3OG +15.90 | 1900
625014 | 4.3OG +15.90 | 1900
625015 | 4.3OG +15.90 | 1900
625016 | 4.3OG +15.90 | 1900
625017 | 4.3OG +15.90 | 1900
625018 | 4.3OG +15.90 | 1900
625019 | 4.3OG +15.90 | 1900
625020 | 4.3OG +15.90 | 1900
625021 | 4.3OG +15.90 | 1900
625022 | 4.3OG +15.90 | 1900
625023 | 4.3OG +15.90 | 1900
625024 | 4.3OG +15.90 | 1900
625025 | 4.3OG +15.90 | 1900
625026 | 4.3OG +15.90 | 1900
625027 | 4.3OG +15.90 | 1900
625163 | 4.3OG +15.90 | 975
625164 | 4.3OG +15.90 | 800
625165 | 4.3OG +15.90 | 800
625166 | 4.3OG +15.90 | 575
625167 | 4.3OG +15.90 | 800
625168 | 4.3OG +15.90 | 800
625169 | 4.3OG +15.90 | 1000
625170 | 4.3OG +15.90 | 800
625171 | 4.3OG +15.90 | 800
625172 | 4.3OG +15.90 | 800
625173 | 4.3OG +15.90 | 975
625174 | 4.3OG +15.90 | 800
625175 | 4.3OG +15.90 | 800
625176 | 4.3OG +15.90 | 575
625177 | 4.3OG +15.90 | 800
625178 | 4.3OG +15.90 | 800
625179 | 4.3OG +15.90 | 1000
625180 | 4.3OG +15.90 | 800
625181 | 4.3OG +15.90 | 800
625182 | 4.3OG +15.90 | 800
625183 | 4.3OG +15.90 | 1000
625184 | 4.3OG +15.90 | 1500
625185 | 4.3OG +15.90 | 1450
625186 | 4.3OG +15.90 | 700
625187 | 4.3OG +15.90 | 800
625188 | 4.3OG +15.90 | 800
625189 | 4.3OG +15.90 | 575
625190 | 4.3OG +15.90 | 800
625191 | 4.3OG +15.90 | 800
625192 | 4.3OG +15.90 | 800
625193 | 4.3OG +15.90 | 800
625194 | 4.3OG +15.90 | 800
625195 | 4.3OG +15.90 | 1000
625196 | 4.3OG +15.90 | 1000
625197 | 4.3OG +15.90 | 1000
625198 | 4.3OG +15.90 | 1000
625199 | 4.3OG +15.90 | 1000
625200 | 4.3OG +15.90 | 1000
625201 | 4.3OG +15.90 | 1000
625202 | 4.3OG +15.90 | 1000
625203 | 4.3OG +15.90 | 1000
625204 | 4.3OG +15.90 | 1000
625205 | 4.3OG +15.90 | 1500
625206 | 4.3OG +15.90 | 1500
625207 | 4.3OG +15.90 | 1500
625208 | 4.3OG +15.90 | 1500
625209 | 4.3OG +15.90 | 1500
625210 | 4.3OG +15.90 | 1500
625211 | 4.3OG +15.90 | 1500
625212 | 4.3OG +15.90 | 1500
625213 | 4.3OG +15.90 | 1500
625214 | 4.3OG +15.90 | 1500
625227 | 4.3OG +15.90 | 1450
625228 | 4.3OG +15.90 | 1500
625229 | 4.3OG +15.90 | 1450
625230 | 4.3OG +15.90 | 1450
625231 | 4.3OG +15.90 | 1450
625232 | 4.3OG +15.90 | 1450
625233 | 4.3OG +15.90 | 1450
625234 | 4.3OG +15.90 | 1450
625235 | 4.3OG +15.90 | 1450
625236 | 4.3OG +15.90 | 1450
625237 | 4.3OG +15.90 | 1450
625238 | 4.3OG +15.90 | 1450
625239 | 4.3OG +15.90 | 975
625240 | 4.3OG +15.90 | 800
625241 | 4.3OG +15.90 | 800
625242 | 4.3OG +15.90 | 575
625243 | 4.3OG +15.90 | 800
625244 | 4.3OG +15.90 | 800
625245 | 4.3OG +15.90 | 1000
625246 | 4.3OG +15.90 | 800
625247 | 4.3OG +15.90 | 800
625248 | 4.3OG +15.90 | 800
625261 | 4.3OG +15.90 | 700
625262 | 4.3OG +15.90 | 1000
625263 | 4.3OG +15.90 | 700
625264 | 4.3OG +15.90 | 700
625265 | 4.3OG +15.90 | 700
625266 | 4.3OG +15.90 | 700
625267 | 4.3OG +15.90 | 700
625268 | 4.3OG +15.90 | 700
625269 | 4.3OG +15.90 | 700
625270 | 4.3OG +15.90 | 700
625271 | 4.3OG +15.90 | 700
625272 | 4.3OG +15.90 | 700
625273 | 4.3OG +15.90 | 800
625274 | 4.3OG +15.90 | 800
625275 | 4.3OG +15.90 | 575
625276 | 4.3OG +15.90 | 800
625277 | 4.3OG +15.90 | 800
625278 | 4.3OG +15.90 | 800
625279 | 4.3OG +15.90 | 800
625280 | 4.3OG +15.90 | 800
625679 | 4.3OG +15.90 | 450.275
625680 | 4.3OG +15.90 | 950
625681 | 4.3OG +15.90 | 950
625682 | 4.3OG +15.90 | 950
625683 | 4.3OG +15.90 | 950
625684 | 4.3OG +15.90 | 950
625685 | 4.3OG +15.90 | 950
625686 | 4.3OG +15.90 | 950
625687 | 4.3OG +15.90 | 950
625688 | 4.3OG +15.90 | 950
625689 | 4.3OG +15.90 | 950
625690 | 4.3OG +15.90 | 450.275
625691 | 4.3OG +15.90 | 1000
625692 | 4.3OG +15.90 | 1000
625693 | 4.3OG +15.90 | 150
625694 | 4.3OG +15.90 | 1000
625695 | 4.3OG +15.90 | 950
625696 | 4.3OG +15.90 | 450.275
625697 | 4.3OG +15.90 | 1000
625698 | 4.3OG +15.90 | 1000
625699 | 4.3OG +15.90 | 1000
625700 | 4.3OG +15.90 | 1000
625701 | 4.3OG +15.90 | 1000
625702 | 4.3OG +15.90 | 1000
625703 | 4.3OG +15.90 | 1000
625704 | 4.3OG +15.90 | 1000
625705 | 4.3OG +15.90 | 1000
625706 | 4.3OG +15.90 | 1000
625765 | 4.3OG +15.90 | 1000
625766 | 4.3OG +15.90 | 1000
625767 | 4.3OG +15.90 | 1000
625768 | 4.3OG +15.90 | 1000
625769 | 4.3OG +15.90 | 1000
625770 | 4.3OG +15.90 | 1000
625771 | 4.3OG +15.90 | 1000
625772 | 4.3OG +15.90 | 950
625773 | 4.3OG +15.90 | 450.275
625822 | 4.3OG +15.90 | 1000
625823 | 4.3OG +15.90 | 1000
625824 | 4.3OG +15.90 | 1000
625825 | 4.3OG +15.90 | 1000
625826 | 4.3OG +15.90 | 1000
625827 | 4.3OG +15.90 | 150
625828 | 4.3OG +15.90 | 1000
625829 | 4.3OG +15.90 | 1000
625830 | 4.3OG +15.90 | 150
625831 | 4.3OG +15.90 | 1000
625832 | 4.3OG +15.90 | 1000
625833 | 4.3OG +15.90 | 150
625834 | 4.3OG +15.90 | 1000
625835 | 4.3OG +15.90 | 1000
625836 | 4.3OG +15.90 | 150
625837 | 4.3OG +15.90 | 1000
625838 | 4.3OG +15.90 | 1000
625839 | 4.3OG +15.90 | 150
625840 | 4.3OG +15.90 | 1000
625841 | 4.3OG +15.90 | 1000
625842 | 4.3OG +15.90 | 150
625843 | 4.3OG +15.90 | 950
625844 | 4.3OG +15.90 | 950
625845 | 4.3OG +15.90 | 950
625846 | 4.3OG +15.90 | 950
625847 | 4.3OG +15.90 | 950
625848 | 4.3OG +15.90 | 450.275
625726 | 4.3OG +15.90 | 396.862
625727 | 4.3OG +15.90 | 950
625728 | 4.3OG +15.90 | 950
625729 | 4.3OG +15.90 | 950
625730 | 4.3OG +15.90 | 950
625731 | 4.3OG +15.90 | 950
625732 | 4.3OG +15.90 | 950
625733 | 4.3OG +15.90 | 950
625734 | 4.3OG +15.90 | 950
625735 | 4.3OG +15.90 | 950
625736 | 4.3OG +15.90 | 950
625737 | 4.3OG +15.90 | 396.862
625738 | 4.3OG +15.90 | 1000
625739 | 4.3OG +15.90 | 1000
625740 | 4.3OG +15.90 | 700
625741 | 4.3OG +15.90 | 1000
625742 | 4.3OG +15.90 | 950
625743 | 4.3OG +15.90 | 950
625744 | 4.3OG +15.90 | 950
625745 | 4.3OG +15.90 | 950
625746 | 4.3OG +15.90 | 950
625747 | 4.3OG +15.90 | 396.862
625748 | 4.3OG +15.90 | 1000
625749 | 4.3OG +15.90 | 1000
625750 | 4.3OG +15.90 | 1000
625751 | 4.3OG +15.90 | 1000
625752 | 4.3OG +15.90 | 1000
625753 | 4.3OG +15.90 | 1000
625754 | 4.3OG +15.90 | 1000
625755 | 4.3OG +15.90 | 1000
625756 | 4.3OG +15.90 | 1000
625757 | 4.3OG +15.90 | 1000
625849 | 4.3OG +15.90 | 1000
625850 | 4.3OG +15.90 | 700
625851 | 4.3OG +15.90 | 1000
625852 | 4.3OG +15.90 | 1000
625853 | 4.3OG +15.90 | 1000
625854 | 4.3OG +15.90 | 700
625855 | 4.3OG +15.90 | 1000
625856 | 4.3OG +15.90 | 700
625857 | 4.3OG +15.90 | 1000
625858 | 4.3OG +15.90 | 700
625859 | 4.3OG +15.90 | 1000
625860 | 4.3OG +15.90 | 700
625861 | 4.3OG +15.90 | 1000
625862 | 4.3OG +15.90 | 700
625863 | 4.3OG +15.90 | 950
625864 | 4.3OG +15.90 | 950
625865 | 4.3OG +15.90 | 950
625866 | 4.3OG +15.90 | 950
625867 | 4.3OG +15.90 | 950
625868 | 4.3OG +15.90 | 396.862
625869 | 4.3OG +15.90 | 950
625870 | 4.3OG +15.90 | 950
625871 | 4.3OG +15.90 | 950
625872 | 4.3OG +15.90 | 950
625873 | 4.3OG +15.90 | 950
625874 | 4.3OG +15.90 | 396.862
625901 | 4.3OG +15.90 | 800
625902 | 4.3OG +15.90 | 800
625903 | 4.3OG +15.90 | 800
625904 | 4.3OG +15.90 | 800
625905 | 4.3OG +15.90 | 800
625906 | 4.3OG +15.90 | 800
625907 | 4.3OG +15.90 | 800
625908 | 4.3OG +15.90 | 800
625909 | 4.3OG +15.90 | 800
625910 | 4.3OG +15.90 | 800
625911 | 4.3OG +15.90 | 800
625932 | 4.3OG +15.90 | 800
625933 | 4.3OG +15.90 | 800
625934 | 4.3OG +15.90 | 800
625935 | 4.3OG +15.90 | 800
625936 | 4.3OG +15.90 | 800
625937 | 4.3OG +15.90 | 800
625938 | 4.3OG +15.90 | 800
625939 | 4.3OG +15.90 | 800
625940 | 4.3OG +15.90 | 800
625941 | 4.3OG +15.90 | 800
625942 | 4.3OG +15.90 | 800
625961 | 4.3OG +15.90 | 800
625962 | 4.3OG +15.90 | 800
625963 | 4.3OG +15.90 | 800
625964 | 4.3OG +15.90 | 800
625965 | 4.3OG +15.90 | 800
625966 | 4.3OG +15.90 | 800
625967 | 4.3OG +15.90 | 800
625968 | 4.3OG +15.90 | 800
625969 | 4.3OG +15.90 | 800
625970 | 4.3OG +15.90 | 800
625991 | 4.3OG +15.90 | 800
625992 | 4.3OG +15.90 | 800
625993 | 4.3OG +15.90 | 800
625994 | 4.3OG +15.90 | 800
625995 | 4.3OG +15.90 | 800
625996 | 4.3OG +15.90 | 800
625997 | 4.3OG +15.90 | 800
625998 | 4.3OG +15.90 | 800
625999 | 4.3OG +15.90 | 800
626000 | 4.3OG +15.90 | 800
626001 | 4.3OG +15.90 | 800
626020 | 4.3OG +15.90 | 800
626021 | 4.3OG +15.90 | 800
626022 | 4.3OG +15.90 | 800
626023 | 4.3OG +15.90 | 800
626024 | 4.3OG +15.90 | 800
626025 | 4.3OG +15.90 | 800
626026 | 4.3OG +15.90 | 800
626027 | 4.3OG +15.90 | 800
626028 | 4.3OG +15.90 | 800
626029 | 4.3OG +15.90 | 800
626071 | 3.2OG +10.60 | 1249.22
626072 | 3.2OG +10.60 | 1425
626073 | 3.2OG +10.60 | 1073.43
626074 | 3.2OG +10.60 | 1249.22
626075 | 3.2OG +10.60 | 1425
626076 | 3.2OG +10.60 | 1073.43
626077 | 3.2OG +10.60 | 1249.22
626078 | 3.2OG +10.60 | 1249.22
626079 | 3.2OG +10.60 | 700
626080 | 3.2OG +10.60 | 700
626081 | 3.2OG +10.60 | 700
626082 | 3.2OG +10.60 | 700
626083 | 3.2OG +10.60 | 700
626156 | 3.2OG +10.60 | 700
626157 | 3.2OG +10.60 | 700
626158 | 3.2OG +10.60 | 700
626159 | 3.2OG +10.60 | 700
626160 | 3.2OG +10.60 | 700
626161 | 3.2OG +10.60 | 700
626162 | 3.2OG +10.60 | 700
626163 | 3.2OG +10.60 | 700
626164 | 3.2OG +10.60 | 700
626165 | 3.2OG +10.60 | 700
626166 | 3.2OG +10.60 | 1073.43
626167 | 3.2OG +10.60 | 1249.22
626168 | 3.2OG +10.60 | 1249.22
626169 | 3.2OG +10.60 | 1073.43
626170 | 3.2OG +10.60 | 1249.22
626171 | 3.2OG +10.60 | 1249.22
626092 | 3.2OG +10.60 | 1275.37
626093 | 3.2OG +10.60 | 1275.37
626094 | 3.2OG +10.60 | 1275.37
626095 | 3.2OG +10.60 | 1275.37
626096 | 3.2OG +10.60 | 1275.37
626097 | 3.2OG +10.60 | 1275.37
626098 | 3.2OG +10.60 | 1275.37
626099 | 3.2OG +10.60 | 1275.37
626100 | 3.2OG +10.60 | 700
626101 | 3.2OG +10.60 | 700
626102 | 3.2OG +10.60 | 700
626103 | 3.2OG +10.60 | 700
626104 | 3.2OG +10.60 | 700
626172 | 3.2OG +10.60 | 700
626173 | 3.2OG +10.60 | 700
626174 | 3.2OG +10.60 | 700
626175 | 3.2OG +10.60 | 700
626176 | 3.2OG +10.60 | 700
626177 | 3.2OG +10.60 | 700
626178 | 3.2OG +10.60 | 700
626179 | 3.2OG +10.60 | 700
626180 | 3.2OG +10.60 | 700
626181 | 3.2OG +10.60 | 700
626182 | 3.2OG +10.60 | 1275.37
626183 | 3.2OG +10.60 | 1275.37
626184 | 3.2OG +10.60 | 1275.37
626185 | 3.2OG +10.60 | 1275.37
626186 | 3.2OG +10.60 | 1275.37
626187 | 3.2OG +10.60 | 1275.37
626188 | 3.2OG +10.60 | 1275.37
626189 | 3.2OG +10.60 | 1275.37
626113 | 3.2OG +10.60 | 1250.79
626114 | 3.2OG +10.60 | 1250.79
626115 | 3.2OG +10.60 | 1250.79
626116 | 3.2OG +10.60 | 1250.79
626117 | 3.2OG +10.60 | 1250.79
626118 | 3.2OG +10.60 | 1250.79
626119 | 3.2OG +10.60 | 1250.79
626120 | 3.2OG +10.60 | 1250.79
626121 | 3.2OG +10.60 | 700
626122 | 3.2OG +10.60 | 700
626123 | 3.2OG +10.60 | 700
626124 | 3.2OG +10.60 | 700
626125 | 3.2OG +10.60 | 700
626190 | 3.2OG +10.60 | 700
626191 | 3.2OG +10.60 | 700
626192 | 3.2OG +10.60 | 700
626193 | 3.2OG +10.60 | 700
626194 | 3.2OG +10.60 | 700
626195 | 3.2OG +10.60 | 700
626196 | 3.2OG +10.60 | 700
626197 | 3.2OG +10.60 | 700
626198 | 3.2OG +10.60 | 700
626199 | 3.2OG +10.60 | 700
626200 | 3.2OG +10.60 | 1250.79
626201 | 3.2OG +10.60 | 1250.79
626202 | 3.2OG +10.60 | 1250.79
626203 | 3.2OG +10.60 | 1250.79
626204 | 3.2OG +10.60 | 1250.79
626205 | 3.2OG +10.60 | 1250.79
626206 | 3.2OG +10.60 | 1250.79
626207 | 3.2OG +10.60 | 1250.79
626216 | 3.2OG +10.60 | 1249.22
626217 | 3.2OG +10.60 | 1249.22
626218 | 3.2OG +10.60 | 1249.22
626219 | 3.2OG +10.60 | 1249.22
626220 | 3.2OG +10.60 | 1249.22
626221 | 3.2OG +10.60 | 1249.22
626222 | 3.2OG +10.60 | 1249.22
626223 | 3.2OG +10.60 | 1249.22
626224 | 3.2OG +10.60 | 800
626225 | 3.2OG +10.60 | 800
626226 | 3.2OG +10.60 | 800
626227 | 3.2OG +10.60 | 800
626228 | 3.2OG +10.60 | 800
626286 | 3.2OG +10.60 | 800
626287 | 3.2OG +10.60 | 800
626288 | 3.2OG +10.60 | 800
626289 | 3.2OG +10.60 | 800
626290 | 3.2OG +10.60 | 800
626291 | 3.2OG +10.60 | 1249.22
626292 | 3.2OG +10.60 | 1249.22
626293 | 3.2OG +10.60 | 1249.22
626294 | 3.2OG +10.60 | 1249.22
626237 | 3.2OG +10.60 | 1275.37
626238 | 3.2OG +10.60 | 1275.37
626239 | 3.2OG +10.60 | 1275.37
626240 | 3.2OG +10.60 | 1275.37
626241 | 3.2OG +10.60 | 1275.37
626242 | 3.2OG +10.60 | 1275.37
626243 | 3.2OG +10.60 | 1275.37
626244 | 3.2OG +10.60 | 1275.37
626245 | 3.2OG +10.60 | 800
626246 | 3.2OG +10.60 | 800
626247 | 3.2OG +10.60 | 800
626248 | 3.2OG +10.60 | 800
626249 | 3.2OG +10.60 | 800
626295 | 3.2OG +10.60 | 800
626296 | 3.2OG +10.60 | 800
626297 | 3.2OG +10.60 | 800
626298 | 3.2OG +10.60 | 800
626299 | 3.2OG +10.60 | 800
626300 | 3.2OG +10.60 | 1275.37
626301 | 3.2OG +10.60 | 1275.37
626302 | 3.2OG +10.60 | 1275.37
626303 | 3.2OG +10.60 | 1275.37
626258 | 3.2OG +10.60 | 1250.79
626259 | 3.2OG +10.60 | 1250.79
626260 | 3.2OG +10.60 | 1250.79
626261 | 3.2OG +10.60 | 1250.79
626262 | 3.2OG +10.60 | 1250.79
626263 | 3.2OG +10.60 | 1250.79
626264 | 3.2OG +10.60 | 1250.79
626265 | 3.2OG +10.60 | 1250.79
626266 | 3.2OG +10.60 | 800
626267 | 3.2OG +10.60 | 800
626268 | 3.2OG +10.60 | 800
626269 | 3.2OG +10.60 | 800
626270 | 3.2OG +10.60 | 800
626304 | 3.2OG +10.60 | 800
626305 | 3.2OG +10.60 | 800
626306 | 3.2OG +10.60 | 800
626307 | 3.2OG +10.60 | 800
626308 | 3.2OG +10.60 | 800
626309 | 3.2OG +10.60 | 1250.79
626310 | 3.2OG +10.60 | 1250.79
626311 | 3.2OG +10.60 | 1250.79
626312 | 3.2OG +10.60 | 1250.79
626323 | 3.2OG +10.60 | 1075
626324 | 3.2OG +10.60 | 1075
626325 | 3.2OG +10.60 | 1075
626326 | 3.2OG +10.60 | 1075
626327 | 3.2OG +10.60 | 1450
626328 | 3.2OG +10.60 | 800
626329 | 3.2OG +10.60 | 650
626330 | 3.2OG +10.60 | 500
626331 | 3.2OG +10.60 | 1450
626332 | 3.2OG +10.60 | 800
626333 | 3.2OG +10.60 | 1075
626334 | 3.2OG +10.60 | 1075
626335 | 3.2OG +10.60 | 1450
626336 | 3.2OG +10.60 | 800
626337 | 3.2OG +10.60 | 650
626368 | 3.2OG +10.60 | 950
626369 | 3.2OG +10.60 | 650
626370 | 3.2OG +10.60 | 950
626371 | 3.2OG +10.60 | 1075
626375 | 3.2OG +10.60 | 950
626376 | 3.2OG +10.60 | 500
626377 | 3.2OG +10.60 | 500
626378 | 3.2OG +10.60 | 1075
626379 | 3.2OG +10.60 | 1075
626348 | 3.2OG +10.60 | 887.5
626349 | 3.2OG +10.60 | 937.5
626350 | 3.2OG +10.60 | 937.5
626351 | 3.2OG +10.60 | 887.5
626352 | 3.2OG +10.60 | 1450
626353 | 3.2OG +10.60 | 1450
626354 | 3.2OG +10.60 | 950
626355 | 3.2OG +10.60 | 500
626356 | 3.2OG +10.60 | 1450
626357 | 3.2OG +10.60 | 1450
626358 | 3.2OG +10.60 | 937.5
626359 | 3.2OG +10.60 | 887.5
626360 | 3.2OG +10.60 | 937.5
626361 | 3.2OG +10.60 | 887.5
626362 | 3.2OG +10.60 | 1450
626363 | 3.2OG +10.60 | 1450
626364 | 3.2OG +10.60 | 950
626383 | 3.2OG +10.60 | 500
626384 | 3.2OG +10.60 | 950
626385 | 3.2OG +10.60 | 500
626386 | 3.2OG +10.60 | 937.5
626387 | 3.2OG +10.60 | 887.5
626398 | 3.2OG +10.60 | 1300
626399 | 3.2OG +10.60 | 1300
626400 | 3.2OG +10.60 | 1300
626401 | 3.2OG +10.60 | 1300
626402 | 3.2OG +10.60 | 1300
626403 | 3.2OG +10.60 | 1300
626404 | 3.2OG +10.60 | 1175
626405 | 3.2OG +10.60 | 2175
626406 | 3.2OG +10.60 | 2175
626407 | 3.2OG +10.60 | 500
626408 | 3.2OG +10.60 | 1300
626409 | 3.2OG +10.60 | 1300
626410 | 3.2OG +10.60 | 1175
626411 | 3.2OG +10.60 | 1175
626412 | 3.2OG +10.60 | 2175
626413 | 3.2OG +10.60 | 2175
626479 | 3.2OG +10.60 | 500
626480 | 3.2OG +10.60 | 1175
626481 | 3.2OG +10.60 | 500
626482 | 3.2OG +10.60 | 500
626483 | 3.2OG +10.60 | 1300
626484 | 3.2OG +10.60 | 1300
626489 | 3.2OG +10.60 | 500
626490 | 3.2OG +10.60 | 500
626491 | 3.2OG +10.60 | 500
626492 | 3.2OG +10.60 | 500
626493 | 3.2OG +10.60 | 1300
626424 | 3.2OG +10.60 | 1233.33
626425 | 3.2OG +10.60 | 1233.33
626426 | 3.2OG +10.60 | 1233.33
626427 | 3.2OG +10.60 | 1233.33
626428 | 3.2OG +10.60 | 1233.33
626429 | 3.2OG +10.60 | 1233.33
626430 | 3.2OG +10.60 | 1182.6
626431 | 3.2OG +10.60 | 2175
626432 | 3.2OG +10.60 | 2175
626433 | 3.2OG +10.60 | 500
626434 | 3.2OG +10.60 | 1233.33
626435 | 3.2OG +10.60 | 1182.6
626436 | 3.2OG +10.60 | 1182.6
626437 | 3.2OG +10.60 | 2175
626438 | 3.2OG +10.60 | 2175
626498 | 3.2OG +10.60 | 500
626499 | 3.2OG +10.60 | 492.404
626500 | 3.2OG +10.60 | 500
626501 | 3.2OG +10.60 | 500
626502 | 3.2OG +10.60 | 1233.33
626503 | 3.2OG +10.60 | 1233.33
626508 | 3.2OG +10.60 | 492.404
626509 | 3.2OG +10.60 | 492.404
626510 | 3.2OG +10.60 | 492.404
626511 | 3.2OG +10.60 | 1182.6
626512 | 3.2OG +10.60 | 1233.33
626449 | 3.2OG +10.60 | 1233.33
626450 | 3.2OG +10.60 | 1233.33
626451 | 3.2OG +10.60 | 1233.33
626452 | 3.2OG +10.60 | 1233.33
626453 | 3.2OG +10.60 | 1233.33
626454 | 3.2OG +10.60 | 1233.33
626455 | 3.2OG +10.60 | 1175
626456 | 3.2OG +10.60 | 2175
626457 | 3.2OG +10.60 | 2175
626458 | 3.2OG +10.60 | 1000
626459 | 3.2OG +10.60 | 1233.33
626460 | 3.2OG +10.60 | 1233.33
626461 | 3.2OG +10.60 | 1175
626462 | 3.2OG +10.60 | 1175
626463 | 3.2OG +10.60 | 2175
626464 | 3.2OG +10.60 | 2175
626469 | 3.2OG +10.60 | 1000
626470 | 3.2OG +10.60 | 1175
626471 | 3.2OG +10.60 | 1000
626472 | 3.2OG +10.60 | 1000
626473 | 3.2OG +10.60 | 1233.33
626474 | 3.2OG +10.60 | 1233.33
626577 | 2.1OG +5.30 | 150
626578 | 2.1OG +5.30 | 200
626579 | 2.1OG +5.30 | 200
626580 | 2.1OG +5.30 | 200
626581 | 2.1OG +5.30 | 200
626582 | 2.1OG +5.30 | 200
626583 | 2.1OG +5.30 | 200
626584 | 2.1OG +5.30 | 200
626585 | 2.1OG +5.30 | 200
626586 | 2.1OG +5.30 | 200
626587 | 2.1OG +5.30 | 200
626588 | 2.1OG +5.30 | 200
626589 | 2.1OG +5.30 | 200
626590 | 2.1OG +5.30 | 200
626591 | 2.1OG +5.30 | 200
626592 | 2.1OG +5.30 | 200
626593 | 2.1OG +5.30 | 200
626594 | 2.1OG +5.30 | 200
626595 | 2.1OG +5.30 | 200
626596 | 2.1OG +5.30 | 200
626597 | 2.1OG +5.30 | 200
626598 | 2.1OG +5.30 | 200
626599 | 2.1OG +5.30 | 200
626600 | 2.1OG +5.30 | 200
626601 | 2.1OG +5.30 | 200
626602 | 2.1OG +5.30 | 200
626603 | 2.1OG +5.30 | 200
626604 | 2.1OG +5.30 | 200
626605 | 2.1OG +5.30 | 200
626606 | 2.1OG +5.30 | 150
626607 | 2.1OG +5.30 | 200
626608 | 2.1OG +5.30 | 200
626609 | 2.1OG +5.30 | 200
626610 | 2.1OG +5.30 | 200
626611 | 2.1OG +5.30 | 200
626612 | 2.1OG +5.30 | 200
626613 | 2.1OG +5.30 | 200
626614 | 2.1OG +5.30 | 200
626615 | 2.1OG +5.30 | 200
626616 | 2.1OG +5.30 | 200
626617 | 2.1OG +5.30 | 200
626618 | 2.1OG +5.30 | 200
626619 | 2.1OG +5.30 | 200
626620 | 2.1OG +5.30 | 200
626621 | 2.1OG +5.30 | 200
626622 | 2.1OG +5.30 | 200
626623 | 2.1OG +5.30 | 200
626624 | 2.1OG +5.30 | 200
626625 | 2.1OG +5.30 | 200
626626 | 2.1OG +5.30 | 200
626627 | 2.1OG +5.30 | 200
626628 | 2.1OG +5.30 | 200
626629 | 2.1OG +5.30 | 200
626630 | 2.1OG +5.30 | 200
626631 | 2.1OG +5.30 | 200
626632 | 2.1OG +5.30 | 200
626633 | 2.1OG +5.30 | 200
626634 | 2.1OG +5.30 | 200
626635 | 2.1OG +5.30 | 200
626636 | 2.1OG +5.30 | 1900
626637 | 2.1OG +5.30 | 1900
626638 | 2.1OG +5.30 | 1900
626639 | 2.1OG +5.30 | 1900
626640 | 2.1OG +5.30 | 1900
626641 | 2.1OG +5.30 | 1900
626642 | 2.1OG +5.30 | 1900
626643 | 2.1OG +5.30 | 1900
626644 | 2.1OG +5.30 | 1900
626645 | 2.1OG +5.30 | 1900
626646 | 2.1OG +5.30 | 1900
626647 | 2.1OG +5.30 | 1900
626648 | 2.1OG +5.30 | 1900
626649 | 2.1OG +5.30 | 1900
626650 | 2.1OG +5.30 | 1900
626651 | 2.1OG +5.30 | 1900
626652 | 2.1OG +5.30 | 1900
626653 | 2.1OG +5.30 | 1900
626654 | 2.1OG +5.30 | 1900
626655 | 2.1OG +5.30 | 1900
626656 | 2.1OG +5.30 | 1900
626657 | 2.1OG +5.30 | 1900
626658 | 2.1OG +5.30 | 1900
626659 | 2.1OG +5.30 | 1900
626660 | 2.1OG +5.30 | 1900
626661 | 2.1OG +5.30 | 1900
626662 | 2.1OG +5.30 | 1900
626663 | 2.1OG +5.30 | 1900
626664 | 2.1OG +5.30 | 1900
626665 | 2.1OG +5.30 | 1900
626666 | 2.1OG +5.30 | 1900
626786 | 2.1OG +5.30 | 200
626787 | 2.1OG +5.30 | 200
626788 | 2.1OG +5.30 | 200
626789 | 2.1OG +5.30 | 200
626790 | 2.1OG +5.30 | 200
626791 | 2.1OG +5.30 | 200
626792 | 2.1OG +5.30 | 200
626793 | 2.1OG +5.30 | 200
626794 | 2.1OG +5.30 | 200
626795 | 2.1OG +5.30 | 200
626796 | 2.1OG +5.30 | 200
626797 | 2.1OG +5.30 | 200
626798 | 2.1OG +5.30 | 1900
626799 | 2.1OG +5.30 | 1900
626800 | 2.1OG +5.30 | 1900
626801 | 2.1OG +5.30 | 1900
626802 | 2.1OG +5.30 | 1900
626803 | 2.1OG +5.30 | 1900
627070 | 2.1OG +5.30 | 200
627071 | 2.1OG +5.30 | 200
627072 | 2.1OG +5.30 | 200
627073 | 2.1OG +5.30 | 200
627074 | 2.1OG +5.30 | 200
627075 | 2.1OG +5.30 | 200
627076 | 2.1OG +5.30 | 200
627077 | 2.1OG +5.30 | 200
627078 | 2.1OG +5.30 | 200
627079 | 2.1OG +5.30 | 200
627080 | 2.1OG +5.30 | 200
627081 | 2.1OG +5.30 | 200
627082 | 2.1OG +5.30 | 200
627083 | 2.1OG +5.30 | 200
627084 | 2.1OG +5.30 | 200
627085 | 2.1OG +5.30 | 200
627086 | 2.1OG +5.30 | 200
627087 | 2.1OG +5.30 | 200
627088 | 2.1OG +5.30 | 200
627089 | 2.1OG +5.30 | 200
627090 | 2.1OG +5.30 | 200
627091 | 2.1OG +5.30 | 200
627092 | 2.1OG +5.30 | 200
627093 | 2.1OG +5.30 | 200
627094 | 2.1OG +5.30 | 200
627095 | 2.1OG +5.30 | 200
627096 | 2.1OG +5.30 | 200
627097 | 2.1OG +5.30 | 200
627098 | 2.1OG +5.30 | 200
627099 | 2.1OG +5.30 | 200
627100 | 2.1OG +5.30 | 200
627101 | 2.1OG +5.30 | 200
627102 | 2.1OG +5.30 | 200
627103 | 2.1OG +5.30 | 200
627104 | 2.1OG +5.30 | 200
627105 | 2.1OG +5.30 | 200
627106 | 2.1OG +5.30 | 200
627107 | 2.1OG +5.30 | 200
627108 | 2.1OG +5.30 | 200
627109 | 2.1OG +5.30 | 200
627110 | 2.1OG +5.30 | 200
627111 | 2.1OG +5.30 | 200
627112 | 2.1OG +5.30 | 200
627113 | 2.1OG +5.30 | 200
627114 | 2.1OG +5.30 | 200
627115 | 2.1OG +5.30 | 200
627116 | 2.1OG +5.30 | 200
627117 | 2.1OG +5.30 | 200
627118 | 2.1OG +5.30 | 200
627119 | 2.1OG +5.30 | 200
627120 | 2.1OG +5.30 | 200
627121 | 2.1OG +5.30 | 200
627122 | 2.1OG +5.30 | 200
627123 | 2.1OG +5.30 | 200
627124 | 2.1OG +5.30 | 200
627125 | 2.1OG +5.30 | 200
627126 | 2.1OG +5.30 | 200
627127 | 2.1OG +5.30 | 200
627128 | 2.1OG +5.30 | 200
627129 | 2.1OG +5.30 | 200
627130 | 2.1OG +5.30 | 200
627131 | 2.1OG +5.30 | 200
627132 | 2.1OG +5.30 | 200
627133 | 2.1OG +5.30 | 200
627134 | 2.1OG +5.30 | 200
627135 | 2.1OG +5.30 | 200
627136 | 2.1OG +5.30 | 200
627137 | 2.1OG +5.30 | 200
627138 | 2.1OG +5.30 | 200
627139 | 2.1OG +5.30 | 200
627140 | 2.1OG +5.30 | 200
627141 | 2.1OG +5.30 | 200
627142 | 2.1OG +5.30 | 200
627143 | 2.1OG +5.30 | 200
627144 | 2.1OG +5.30 | 200
627145 | 2.1OG +5.30 | 200
627146 | 2.1OG +5.30 | 200
627147 | 2.1OG +5.30 | 200
627148 | 2.1OG +5.30 | 200
627149 | 2.1OG +5.30 | 200
627150 | 2.1OG +5.30 | 200
627151 | 2.1OG +5.30 | 200
627152 | 2.1OG +5.30 | 200
627153 | 2.1OG +5.30 | 200
627154 | 2.1OG +5.30 | 200
627155 | 2.1OG +5.30 | 200
627156 | 2.1OG +5.30 | 200
627157 | 2.1OG +5.30 | 200
627158 | 2.1OG +5.30 | 200
627159 | 2.1OG +5.30 | 200
627160 | 2.1OG +5.30 | 200
627161 | 2.1OG +5.30 | 200
627162 | 2.1OG +5.30 | 200
627163 | 2.1OG +5.30 | 200
627164 | 2.1OG +5.30 | 200
627165 | 2.1OG +5.30 | 200
627166 | 2.1OG +5.30 | 200
627167 | 2.1OG +5.30 | 200
627168 | 2.1OG +5.30 | 200
627169 | 2.1OG +5.30 | 200
627170 | 2.1OG +5.30 | 200
627171 | 2.1OG +5.30 | 200
627172 | 2.1OG +5.30 | 200
627173 | 2.1OG +5.30 | 200
627174 | 2.1OG +5.30 | 200
627175 | 2.1OG +5.30 | 200
627176 | 2.1OG +5.30 | 200
627177 | 2.1OG +5.30 | 200
627178 | 2.1OG +5.30 | 200
627179 | 2.1OG +5.30 | 200
627180 | 2.1OG +5.30 | 200
627181 | 2.1OG +5.30 | 200
627182 | 2.1OG +5.30 | 200
627183 | 2.1OG +5.30 | 200
627184 | 2.1OG +5.30 | 200
627185 | 2.1OG +5.30 | 200
627186 | 2.1OG +5.30 | 200
627187 | 2.1OG +5.30 | 200
627188 | 2.1OG +5.30 | 200
627189 | 2.1OG +5.30 | 200
627190 | 2.1OG +5.30 | 200
627191 | 2.1OG +5.30 | 200
627192 | 2.1OG +5.30 | 200
627193 | 2.1OG +5.30 | 200
627194 | 2.1OG +5.30 | 200
627195 | 2.1OG +5.30 | 200
627196 | 2.1OG +5.30 | 200
627197 | 2.1OG +5.30 | 200
627198 | 2.1OG +5.30 | 200
627199 | 2.1OG +5.30 | 200
627200 | 2.1OG +5.30 | 200
627201 | 2.1OG +5.30 | 200
627202 | 2.1OG +5.30 | 200
627203 | 2.1OG +5.30 | 200
627204 | 2.1OG +5.30 | 200
627205 | 2.1OG +5.30 | 200
627206 | 2.1OG +5.30 | 200
627207 | 2.1OG +5.30 | 200
627208 | 2.1OG +5.30 | 200
627209 | 2.1OG +5.30 | 200
627210 | 2.1OG +5.30 | 200
627211 | 2.1OG +5.30 | 200
627212 | 2.1OG +5.30 | 200
627213 | 2.1OG +5.30 | 200
627214 | 2.1OG +5.30 | 200
627215 | 2.1OG +5.30 | 200
627216 | 2.1OG +5.30 | 200
627217 | 2.1OG +5.30 | 200
627218 | 2.1OG +5.30 | 200
627219 | 2.1OG +5.30 | 200
627220 | 2.1OG +5.30 | 200
627221 | 2.1OG +5.30 | 200
627222 | 2.1OG +5.30 | 200
627223 | 2.1OG +5.30 | 200
627224 | 2.1OG +5.30 | 200
627225 | 2.1OG +5.30 | 200
627226 | 2.1OG +5.30 | 200
627227 | 2.1OG +5.30 | 200
627228 | 2.1OG +5.30 | 200
627229 | 2.1OG +5.30 | 200
627230 | 2.1OG +5.30 | 200
627231 | 2.1OG +5.30 | 200
627232 | 2.1OG +5.30 | 200
627233 | 2.1OG +5.30 | 200
627234 | 2.1OG +5.30 | 200
627235 | 2.1OG +5.30 | 200
627236 | 2.1OG +5.30 | 200
627237 | 2.1OG +5.30 | 200
627238 | 2.1OG +5.30 | 1900
627239 | 2.1OG +5.30 | 1900
627240 | 2.1OG +5.30 | 1900
627241 | 2.1OG +5.30 | 1900
627242 | 2.1OG +5.30 | 1900
627243 | 2.1OG +5.30 | 1900
627244 | 2.1OG +5.30 | 1900
627245 | 2.1OG +5.30 | 1900
627246 | 2.1OG +5.30 | 1900
627247 | 2.1OG +5.30 | 1900
627248 | 2.1OG +5.30 | 1900
627249 | 2.1OG +5.30 | 1900
627250 | 2.1OG +5.30 | 1900
627251 | 2.1OG +5.30 | 1900
627252 | 2.1OG +5.30 | 1900
627253 | 2.1OG +5.30 | 1900
627254 | 2.1OG +5.30 | 1900
627255 | 2.1OG +5.30 | 1900
627256 | 2.1OG +5.30 | 1900
627257 | 2.1OG +5.30 | 1900
627258 | 2.1OG +5.30 | 1900
627259 | 2.1OG +5.30 | 1900
627260 | 2.1OG +5.30 | 1900
627261 | 2.1OG +5.30 | 1900
627262 | 2.1OG +5.30 | 1900
627263 | 2.1OG +5.30 | 1900
627264 | 2.1OG +5.30 | 1900
627265 | 2.1OG +5.30 | 1900
627266 | 2.1OG +5.30 | 1900
627267 | 2.1OG +5.30 | 1900
627268 | 2.1OG +5.30 | 1900
627269 | 2.1OG +5.30 | 1900
627270 | 2.1OG +5.30 | 1900
627271 | 2.1OG +5.30 | 1900
627272 | 2.1OG +5.30 | 1900
627273 | 2.1OG +5.30 | 1900
627274 | 2.1OG +5.30 | 1900
627275 | 2.1OG +5.30 | 1900
627276 | 2.1OG +5.30 | 1900
627277 | 2.1OG +5.30 | 1900
627278 | 2.1OG +5.30 | 1900
627279 | 2.1OG +5.30 | 1900
627280 | 2.1OG +5.30 | 1900
627281 | 2.1OG +5.30 | 1900
627282 | 2.1OG +5.30 | 1900
627283 | 2.1OG +5.30 | 1900
627284 | 2.1OG +5.30 | 1900
627285 | 2.1OG +5.30 | 1900
627286 | 2.1OG +5.30 | 1900
627287 | 2.1OG +5.30 | 1900
627288 | 2.1OG +5.30 | 1900
627289 | 2.1OG +5.30 | 1900
627290 | 2.1OG +5.30 | 1900
627291 | 2.1OG +5.30 | 1900
627292 | 2.1OG +5.30 | 1900
627293 | 2.1OG +5.30 | 1900
627294 | 2.1OG +5.30 | 1900
627295 | 2.1OG +5.30 | 1900
627296 | 2.1OG +5.30 | 1900
627297 | 2.1OG +5.30 | 1900
627298 | 2.1OG +5.30 | 1900
627299 | 2.1OG +5.30 | 1900
627300 | 2.1OG +5.30 | 1900
627301 | 2.1OG +5.30 | 1900
627302 | 2.1OG +5.30 | 1900
627303 | 2.1OG +5.30 | 1900
627304 | 2.1OG +5.30 | 1900
627305 | 2.1OG +5.30 | 1900
627306 | 2.1OG +5.30 | 1900
627307 | 2.1OG +5.30 | 1900
627308 | 2.1OG +5.30 | 1900
627309 | 2.1OG +5.30 | 1900
627310 | 2.1OG +5.30 | 1900
627311 | 2.1OG +5.30 | 1900
627312 | 2.1OG +5.30 | 1900
627313 | 2.1OG +5.30 | 1900
627314 | 2.1OG +5.30 | 1900
627315 | 2.1OG +5.30 | 1900
627316 | 2.1OG +5.30 | 1900
627317 | 2.1OG +5.30 | 1900
627318 | 2.1OG +5.30 | 1900
627319 | 2.1OG +5.30 | 1900
627320 | 2.1OG +5.30 | 1900
627321 | 2.1OG +5.30 | 1900
628825 | 2.1OG +5.30 | 200
628827 | 2.1OG +5.30 | 1900
626670 | 2.1OG +5.30 | 52.9531
626671 | 2.1OG +5.30 | 200
626672 | 2.1OG +5.30 | 1900
626673 | 2.1OG +5.30 | 1900
626680 | 2.1OG +5.30 | 200
626681 | 2.1OG +5.30 | 200
626682 | 2.1OG +5.30 | 200
626683 | 2.1OG +5.30 | 200
626684 | 2.1OG +5.30 | 200
626685 | 2.1OG +5.30 | 200
626686 | 2.1OG +5.30 | 1900
626687 | 2.1OG +5.30 | 1900
626688 | 2.1OG +5.30 | 1900
627322 | 2.1OG +5.30 | 200
627323 | 2.1OG +5.30 | 200
627324 | 2.1OG +5.30 | 200
627325 | 2.1OG +5.30 | 200
627326 | 2.1OG +5.30 | 200
627327 | 2.1OG +5.30 | 200
627328 | 2.1OG +5.30 | 200
627329 | 2.1OG +5.30 | 200
627330 | 2.1OG +5.30 | 200
627331 | 2.1OG +5.30 | 200
627332 | 2.1OG +5.30 | 200
627333 | 2.1OG +5.30 | 200
627334 | 2.1OG +5.30 | 200
627335 | 2.1OG +5.30 | 200
627336 | 2.1OG +5.30 | 200
627337 | 2.1OG +5.30 | 200
627338 | 2.1OG +5.30 | 200
627339 | 2.1OG +5.30 | 200
627340 | 2.1OG +5.30 | 200
627341 | 2.1OG +5.30 | 52.9531
627342 | 2.1OG +5.30 | 1900
627343 | 2.1OG +5.30 | 1900
627344 | 2.1OG +5.30 | 1900
627345 | 2.1OG +5.30 | 1900
627346 | 2.1OG +5.30 | 1900
627347 | 2.1OG +5.30 | 1900
627348 | 2.1OG +5.30 | 1900
627349 | 2.1OG +5.30 | 1900
627350 | 2.1OG +5.30 | 1900
627351 | 2.1OG +5.30 | 1900
626702 | 2.1OG +5.30 | 200
626703 | 2.1OG +5.30 | 200
626704 | 2.1OG +5.30 | 200
626705 | 2.1OG +5.30 | 200
626706 | 2.1OG +5.30 | 200
626707 | 2.1OG +5.30 | 200
626708 | 2.1OG +5.30 | 200
626709 | 2.1OG +5.30 | 200
626710 | 2.1OG +5.30 | 200
626711 | 2.1OG +5.30 | 200
626712 | 2.1OG +5.30 | 200
626713 | 2.1OG +5.30 | 1900
626714 | 2.1OG +5.30 | 1900
626715 | 2.1OG +5.30 | 1900
626716 | 2.1OG +5.30 | 1900
626717 | 2.1OG +5.30 | 1900
626718 | 2.1OG +5.30 | 1900
626719 | 2.1OG +5.30 | 1900
627352 | 2.1OG +5.30 | 200
627353 | 2.1OG +5.30 | 200
627354 | 2.1OG +5.30 | 200
627355 | 2.1OG +5.30 | 200
627356 | 2.1OG +5.30 | 200
627357 | 2.1OG +5.30 | 200
627358 | 2.1OG +5.30 | 200
627359 | 2.1OG +5.30 | 200
627360 | 2.1OG +5.30 | 200
627361 | 2.1OG +5.30 | 200
627362 | 2.1OG +5.30 | 200
627363 | 2.1OG +5.30 | 200
627364 | 2.1OG +5.30 | 200
627365 | 2.1OG +5.30 | 200
627366 | 2.1OG +5.30 | 200
627367 | 2.1OG +5.30 | 200
627368 | 2.1OG +5.30 | 200
627369 | 2.1OG +5.30 | 200
627370 | 2.1OG +5.30 | 200
627371 | 2.1OG +5.30 | 200
627372 | 2.1OG +5.30 | 200
627373 | 2.1OG +5.30 | 200
627374 | 2.1OG +5.30 | 200
627375 | 2.1OG +5.30 | 200
627376 | 2.1OG +5.30 | 200
627377 | 2.1OG +5.30 | 200
627378 | 2.1OG +5.30 | 200
627379 | 2.1OG +5.30 | 200
627380 | 2.1OG +5.30 | 200
627382 | 2.1OG +5.30 | 1900
627383 | 2.1OG +5.30 | 1900
627384 | 2.1OG +5.30 | 1900
627385 | 2.1OG +5.30 | 1900
627386 | 2.1OG +5.30 | 1900
627387 | 2.1OG +5.30 | 1900
627388 | 2.1OG +5.30 | 1900
627389 | 2.1OG +5.30 | 1900
627390 | 2.1OG +5.30 | 1900
627391 | 2.1OG +5.30 | 1900
627392 | 2.1OG +5.30 | 1900
627393 | 2.1OG +5.30 | 1900
627394 | 2.1OG +5.30 | 1900
627395 | 2.1OG +5.30 | 1900
627396 | 2.1OG +5.30 | 1900
626733 | 2.1OG +5.30 | 200
626734 | 2.1OG +5.30 | 200
626735 | 2.1OG +5.30 | 200
626736 | 2.1OG +5.30 | 200
626737 | 2.1OG +5.30 | 200
626738 | 2.1OG +5.30 | 200
626739 | 2.1OG +5.30 | 200
626740 | 2.1OG +5.30 | 200
626741 | 2.1OG +5.30 | 200
626742 | 2.1OG +5.30 | 200
626743 | 2.1OG +5.30 | 200
626744 | 2.1OG +5.30 | 1900
626745 | 2.1OG +5.30 | 1900
626746 | 2.1OG +5.30 | 1900
626747 | 2.1OG +5.30 | 1900
626748 | 2.1OG +5.30 | 1900
626749 | 2.1OG +5.30 | 1900
626750 | 2.1OG +5.30 | 1900
627397 | 2.1OG +5.30 | 200
627398 | 2.1OG +5.30 | 200
627399 | 2.1OG +5.30 | 200
627400 | 2.1OG +5.30 | 200
627401 | 2.1OG +5.30 | 200
627402 | 2.1OG +5.30 | 200
627403 | 2.1OG +5.30 | 200
627404 | 2.1OG +5.30 | 200
627405 | 2.1OG +5.30 | 200
627406 | 2.1OG +5.30 | 200
627407 | 2.1OG +5.30 | 200
627408 | 2.1OG +5.30 | 200
627409 | 2.1OG +5.30 | 200
627410 | 2.1OG +5.30 | 200
627411 | 2.1OG +5.30 | 200
627412 | 2.1OG +5.30 | 200
627413 | 2.1OG +5.30 | 200
627414 | 2.1OG +5.30 | 200
627415 | 2.1OG +5.30 | 200
627416 | 2.1OG +5.30 | 200
627417 | 2.1OG +5.30 | 200
627418 | 2.1OG +5.30 | 200
627419 | 2.1OG +5.30 | 200
627420 | 2.1OG +5.30 | 200
627421 | 2.1OG +5.30 | 200
627422 | 2.1OG +5.30 | 200
627423 | 2.1OG +5.30 | 200
627424 | 2.1OG +5.30 | 200
627425 | 2.1OG +5.30 | 200
627427 | 2.1OG +5.30 | 1900
627428 | 2.1OG +5.30 | 1900
627429 | 2.1OG +5.30 | 1900
627430 | 2.1OG +5.30 | 1900
627431 | 2.1OG +5.30 | 1900
627432 | 2.1OG +5.30 | 1900
627433 | 2.1OG +5.30 | 1900
627434 | 2.1OG +5.30 | 1900
627435 | 2.1OG +5.30 | 1900
627436 | 2.1OG +5.30 | 1900
627437 | 2.1OG +5.30 | 1900
627438 | 2.1OG +5.30 | 1900
627439 | 2.1OG +5.30 | 1900
627440 | 2.1OG +5.30 | 1900
627441 | 2.1OG +5.30 | 1900
626759 | 2.1OG +5.30 | 152.882
626760 | 2.1OG +5.30 | 200
626761 | 2.1OG +5.30 | 200
626762 | 2.1OG +5.30 | 200
626763 | 2.1OG +5.30 | 200
626764 | 2.1OG +5.30 | 200
626765 | 2.1OG +5.30 | 200
626766 | 2.1OG +5.30 | 200
626767 | 2.1OG +5.30 | 1900
626768 | 2.1OG +5.30 | 1900
626769 | 2.1OG +5.30 | 1900
626770 | 2.1OG +5.30 | 1900
626771 | 2.1OG +5.30 | 1900
627442 | 2.1OG +5.30 | 200
627443 | 2.1OG +5.30 | 200
627444 | 2.1OG +5.30 | 200
627445 | 2.1OG +5.30 | 200
627446 | 2.1OG +5.30 | 200
627447 | 2.1OG +5.30 | 200
627448 | 2.1OG +5.30 | 200
627449 | 2.1OG +5.30 | 200
627450 | 2.1OG +5.30 | 200
627451 | 2.1OG +5.30 | 200
627452 | 2.1OG +5.30 | 200
627453 | 2.1OG +5.30 | 200
627454 | 2.1OG +5.30 | 200
627455 | 2.1OG +5.30 | 200
627456 | 2.1OG +5.30 | 200
627457 | 2.1OG +5.30 | 200
627458 | 2.1OG +5.30 | 200
627459 | 2.1OG +5.30 | 152.882
627460 | 2.1OG +5.30 | 1900
627461 | 2.1OG +5.30 | 1900
627462 | 2.1OG +5.30 | 1900
627463 | 2.1OG +5.30 | 1900
627464 | 2.1OG +5.30 | 1900
627465 | 2.1OG +5.30 | 1900
627466 | 2.1OG +5.30 | 1900
627467 | 2.1OG +5.30 | 1900
627468 | 2.1OG +5.30 | 1900
627571 | 2.1OG +5.30 | 200
627572 | 2.1OG +5.30 | 200
627573 | 2.1OG +5.30 | 200
627574 | 2.1OG +5.30 | 200
627575 | 2.1OG +5.30 | 200
627576 | 2.1OG +5.30 | 200
627577 | 2.1OG +5.30 | 200
627578 | 2.1OG +5.30 | 200
627579 | 2.1OG +5.30 | 200
627580 | 2.1OG +5.30 | 200
627581 | 2.1OG +5.30 | 200
627582 | 2.1OG +5.30 | 200
627583 | 2.1OG +5.30 | 200
627584 | 2.1OG +5.30 | 200
627585 | 2.1OG +5.30 | 200
627586 | 2.1OG +5.30 | 200
627587 | 2.1OG +5.30 | 200
627588 | 2.1OG +5.30 | 200
627589 | 2.1OG +5.30 | 200
627590 | 2.1OG +5.30 | 200
627591 | 2.1OG +5.30 | 200
627592 | 2.1OG +5.30 | 200
627593 | 2.1OG +5.30 | 76.8066
627594 | 2.1OG +5.30 | 1900
627595 | 2.1OG +5.30 | 1900
627596 | 2.1OG +5.30 | 1900
627597 | 2.1OG +5.30 | 1900
627598 | 2.1OG +5.30 | 1408
627599 | 2.1OG +5.30 | 1408
627600 | 2.1OG +5.30 | 1408
627601 | 2.1OG +5.30 | 1408
627602 | 2.1OG +5.30 | 1900
627603 | 2.1OG +5.30 | 1900
627604 | 2.1OG +5.30 | 1900
627605 | 2.1OG +5.30 | 1900
627606 | 2.1OG +5.30 | 1900
627607 | 2.1OG +5.30 | 1900
627608 | 2.1OG +5.30 | 1900
627609 | 2.1OG +5.30 | 1900
627610 | 2.1OG +5.30 | 1900
627611 | 2.1OG +5.30 | 1900
627612 | 2.1OG +5.30 | 1900
627613 | 2.1OG +5.30 | 1900
627614 | 2.1OG +5.30 | 1900
627615 | 2.1OG +5.30 | 1900
627634 | 2.1OG +5.30 | 73.1934
627635 | 2.1OG +5.30 | 59.1934
627636 | 2.1OG +5.30 | 200
627637 | 2.1OG +5.30 | 200
627638 | 2.1OG +5.30 | 200
627639 | 2.1OG +5.30 | 90.8066
627640 | 2.1OG +5.30 | 200
627641 | 2.1OG +5.30 | 200
627642 | 2.1OG +5.30 | 200
627643 | 2.1OG +5.30 | 200
627644 | 2.1OG +5.30 | 200
627645 | 2.1OG +5.30 | 200
627646 | 2.1OG +5.30 | 200
627647 | 2.1OG +5.30 | 200
627648 | 2.1OG +5.30 | 200
627649 | 2.1OG +5.30 | 200
627650 | 2.1OG +5.30 | 200
627651 | 2.1OG +5.30 | 200
627652 | 2.1OG +5.30 | 200
627654 | 2.1OG +5.30 | 542
627655 | 2.1OG +5.30 | 542
627704 | 2.1OG +5.30 | 80
627705 | 2.1OG +5.30 | 200
627706 | 2.1OG +5.30 | 200
627707 | 2.1OG +5.30 | 200
627708 | 2.1OG +5.30 | 200
627709 | 2.1OG +5.30 | 200
627710 | 2.1OG +5.30 | 200
627711 | 2.1OG +5.30 | 200
627712 | 2.1OG +5.30 | 200
627713 | 2.1OG +5.30 | 200
627714 | 2.1OG +5.30 | 200
627715 | 2.1OG +5.30 | 200
627716 | 2.1OG +5.30 | 200
627717 | 2.1OG +5.30 | 200
627718 | 2.1OG +5.30 | 200
627719 | 2.1OG +5.30 | 200
627720 | 2.1OG +5.30 | 200
627721 | 2.1OG +5.30 | 200
627722 | 2.1OG +5.30 | 200
627723 | 2.1OG +5.30 | 200
627724 | 2.1OG +5.30 | 200
627725 | 2.1OG +5.30 | 200
627726 | 2.1OG +5.30 | 200
627727 | 2.1OG +5.30 | 200
627728 | 2.1OG +5.30 | 200
627729 | 2.1OG +5.30 | 200
627730 | 2.1OG +5.30 | 200
627731 | 2.1OG +5.30 | 200
627732 | 2.1OG +5.30 | 200
627733 | 2.1OG +5.30 | 200
627734 | 2.1OG +5.30 | 200
627735 | 2.1OG +5.30 | 200
627736 | 2.1OG +5.30 | 200
627737 | 2.1OG +5.30 | 200
627738 | 2.1OG +5.30 | 200
627739 | 2.1OG +5.30 | 200
627740 | 2.1OG +5.30 | 200
627741 | 2.1OG +5.30 | 200
627742 | 2.1OG +5.30 | 200
627743 | 2.1OG +5.30 | 200
627744 | 2.1OG +5.30 | 200
627745 | 2.1OG +5.30 | 200
627746 | 2.1OG +5.30 | 200
627747 | 2.1OG +5.30 | 200
627748 | 2.1OG +5.30 | 200
627749 | 2.1OG +5.30 | 80
627750 | 2.1OG +5.30 | 1800
627751 | 2.1OG +5.30 | 1800
627752 | 2.1OG +5.30 | 1800
627753 | 2.1OG +5.30 | 1800
627754 | 2.1OG +5.30 | 1800
627755 | 2.1OG +5.30 | 1800
627756 | 2.1OG +5.30 | 1800
627757 | 2.1OG +5.30 | 1800
627758 | 2.1OG +5.30 | 1800
627759 | 2.1OG +5.30 | 1800
627760 | 2.1OG +5.30 | 1800
627761 | 2.1OG +5.30 | 1800
627762 | 2.1OG +5.30 | 1800
627763 | 2.1OG +5.30 | 1800
627764 | 2.1OG +5.30 | 1800
627765 | 2.1OG +5.30 | 1800
627766 | 2.1OG +5.30 | 1800
627767 | 2.1OG +5.30 | 1800
627768 | 2.1OG +5.30 | 1800
627769 | 2.1OG +5.30 | 1800
627770 | 2.1OG +5.30 | 1800
627771 | 2.1OG +5.30 | 1800
627772 | 2.1OG +5.30 | 1800
627773 | 2.1OG +5.30 | 1800
627879 | 2.1OG +5.30 | 1208.12
627880 | 2.1OG +5.30 | 1208.12
627881 | 2.1OG +5.30 | 1208.12
627882 | 2.1OG +5.30 | 1208.12
627883 | 2.1OG +5.30 | 1208.12
627884 | 2.1OG +5.30 | 1208.12
627885 | 2.1OG +5.30 | 1208.12
627886 | 2.1OG +5.30 | 1208.12
627887 | 2.1OG +5.30 | 700
627888 | 2.1OG +5.30 | 700
627889 | 2.1OG +5.30 | 700
627890 | 2.1OG +5.30 | 700
627891 | 2.1OG +5.30 | 700
627892 | 2.1OG +5.30 | 700
627893 | 2.1OG +5.30 | 1208.12
627894 | 2.1OG +5.30 | 1208.12
627895 | 2.1OG +5.30 | 1208.12
627896 | 2.1OG +5.30 | 1208.12
627897 | 2.1OG +5.30 | 1208.12
627898 | 2.1OG +5.30 | 1208.12
627899 | 2.1OG +5.30 | 1208.12
627900 | 2.1OG +5.30 | 1208.12
627901 | 2.1OG +5.30 | 700
627902 | 2.1OG +5.30 | 700
627903 | 2.1OG +5.30 | 700
627904 | 2.1OG +5.30 | 700
627905 | 2.1OG +5.30 | 700
627906 | 2.1OG +5.30 | 700
627907 | 2.1OG +5.30 | 700
627908 | 2.1OG +5.30 | 700
627909 | 2.1OG +5.30 | 700
627928 | 2.1OG +5.30 | 1425
627929 | 2.1OG +5.30 | 1237.87
627930 | 2.1OG +5.30 | 1237.87
627931 | 2.1OG +5.30 | 1050.74
627932 | 2.1OG +5.30 | 1237.87
627933 | 2.1OG +5.30 | 1237.87
627934 | 2.1OG +5.30 | 1050.74
627935 | 2.1OG +5.30 | 1425
627936 | 2.1OG +5.30 | 700
627937 | 2.1OG +5.30 | 700
627938 | 2.1OG +5.30 | 700
627939 | 2.1OG +5.30 | 700
627940 | 2.1OG +5.30 | 700
627941 | 2.1OG +5.30 | 700
627942 | 2.1OG +5.30 | 1237.87
627943 | 2.1OG +5.30 | 1237.87
627944 | 2.1OG +5.30 | 1050.74
627945 | 2.1OG +5.30 | 1237.87
627946 | 2.1OG +5.30 | 1237.87
627947 | 2.1OG +5.30 | 1050.74
627948 | 2.1OG +5.30 | 700
627949 | 2.1OG +5.30 | 700
627950 | 2.1OG +5.30 | 700
627951 | 2.1OG +5.30 | 700
627952 | 2.1OG +5.30 | 700
627953 | 2.1OG +5.30 | 700
627954 | 2.1OG +5.30 | 700
627955 | 2.1OG +5.30 | 700
627956 | 2.1OG +5.30 | 700
627975 | 2.1OG +5.30 | 1207.05
627976 | 2.1OG +5.30 | 1207.05
627977 | 2.1OG +5.30 | 1207.05
627978 | 2.1OG +5.30 | 1207.05
627979 | 2.1OG +5.30 | 1207.05
627980 | 2.1OG +5.30 | 1207.05
627981 | 2.1OG +5.30 | 1207.05
627982 | 2.1OG +5.30 | 1207.05
627983 | 2.1OG +5.30 | 700
627984 | 2.1OG +5.30 | 700
627985 | 2.1OG +5.30 | 700
627986 | 2.1OG +5.30 | 700
627987 | 2.1OG +5.30 | 700
627988 | 2.1OG +5.30 | 700
627989 | 2.1OG +5.30 | 1207.05
627990 | 2.1OG +5.30 | 1207.05
627991 | 2.1OG +5.30 | 1207.05
627992 | 2.1OG +5.30 | 1207.05
627993 | 2.1OG +5.30 | 1207.05
627994 | 2.1OG +5.30 | 1207.05
627995 | 2.1OG +5.30 | 1207.05
627996 | 2.1OG +5.30 | 1207.05
627997 | 2.1OG +5.30 | 700
627998 | 2.1OG +5.30 | 700
627999 | 2.1OG +5.30 | 700
628000 | 2.1OG +5.30 | 700
628001 | 2.1OG +5.30 | 700
628002 | 2.1OG +5.30 | 700
628003 | 2.1OG +5.30 | 700
628004 | 2.1OG +5.30 | 700
628005 | 2.1OG +5.30 | 700
628019 | 2.1OG +5.30 | 1208.12
628020 | 2.1OG +5.30 | 1208.12
628021 | 2.1OG +5.30 | 1208.12
628022 | 2.1OG +5.30 | 1208.12
628023 | 2.1OG +5.30 | 1208.12
628024 | 2.1OG +5.30 | 1208.12
628025 | 2.1OG +5.30 | 1208.12
628026 | 2.1OG +5.30 | 1208.12
628027 | 2.1OG +5.30 | 800
628028 | 2.1OG +5.30 | 800
628029 | 2.1OG +5.30 | 800
628030 | 2.1OG +5.30 | 800
628031 | 2.1OG +5.30 | 1208.12
628032 | 2.1OG +5.30 | 1208.12
628033 | 2.1OG +5.30 | 1208.12
628034 | 2.1OG +5.30 | 1208.12
628035 | 2.1OG +5.30 | 800
628036 | 2.1OG +5.30 | 800
628037 | 2.1OG +5.30 | 800
628038 | 2.1OG +5.30 | 800
628039 | 2.1OG +5.30 | 800
628040 | 2.1OG +5.30 | 800
628054 | 2.1OG +5.30 | 1237.87
628055 | 2.1OG +5.30 | 1237.87
628056 | 2.1OG +5.30 | 1237.87
628057 | 2.1OG +5.30 | 1237.87
628058 | 2.1OG +5.30 | 1237.87
628059 | 2.1OG +5.30 | 1237.87
628060 | 2.1OG +5.30 | 1237.87
628061 | 2.1OG +5.30 | 1237.87
628062 | 2.1OG +5.30 | 800
628063 | 2.1OG +5.30 | 800
628064 | 2.1OG +5.30 | 800
628065 | 2.1OG +5.30 | 800
628066 | 2.1OG +5.30 | 1237.87
628067 | 2.1OG +5.30 | 1237.87
628068 | 2.1OG +5.30 | 1237.87
628069 | 2.1OG +5.30 | 1237.87
628070 | 2.1OG +5.30 | 800
628071 | 2.1OG +5.30 | 800
628072 | 2.1OG +5.30 | 800
628073 | 2.1OG +5.30 | 800
628074 | 2.1OG +5.30 | 800
628075 | 2.1OG +5.30 | 800
628089 | 2.1OG +5.30 | 1207.05
628090 | 2.1OG +5.30 | 1207.05
628091 | 2.1OG +5.30 | 1207.05
628092 | 2.1OG +5.30 | 1207.05
628093 | 2.1OG +5.30 | 1207.05
628094 | 2.1OG +5.30 | 1207.05
628095 | 2.1OG +5.30 | 1207.05
628096 | 2.1OG +5.30 | 1207.05
628097 | 2.1OG +5.30 | 800
628098 | 2.1OG +5.30 | 800
628099 | 2.1OG +5.30 | 800
628100 | 2.1OG +5.30 | 800
628101 | 2.1OG +5.30 | 1207.05
628102 | 2.1OG +5.30 | 1207.05
628103 | 2.1OG +5.30 | 1207.05
628104 | 2.1OG +5.30 | 1207.05
628105 | 2.1OG +5.30 | 800
628106 | 2.1OG +5.30 | 800
628107 | 2.1OG +5.30 | 800
628108 | 2.1OG +5.30 | 800
628109 | 2.1OG +5.30 | 800
628110 | 2.1OG +5.30 | 800
628379 | 1.EG +0.00 | 700.714
628380 | 1.EG +0.00 | 750.714
628381 | 1.EG +0.00 | 750.714
628382 | 1.EG +0.00 | 750.714
628383 | 1.EG +0.00 | 750.714
628384 | 1.EG +0.00 | 700.714
628385 | 1.EG +0.00 | 2000
628386 | 1.EG +0.00 | 850
628387 | 1.EG +0.00 | 850
628388 | 1.EG +0.00 | 850
628389 | 1.EG +0.00 | 2000
628390 | 1.EG +0.00 | 850
628391 | 1.EG +0.00 | 750.714
628392 | 1.EG +0.00 | 750.714
628393 | 1.EG +0.00 | 700.714
628394 | 1.EG +0.00 | 750.714
628395 | 1.EG +0.00 | 750.714
628396 | 1.EG +0.00 | 700.714
628397 | 1.EG +0.00 | 2000
628398 | 1.EG +0.00 | 2000
628399 | 1.EG +0.00 | 850
628400 | 1.EG +0.00 | 850
628401 | 1.EG +0.00 | 850
628402 | 1.EG +0.00 | 850
628572 | 1.EG +0.00 | 728.634
628573 | 1.EG +0.00 | 753.634
628574 | 1.EG +0.00 | 1000
628575 | 1.EG +0.00 | 1125
628622 | 1.EG +0.00 | 728.634
628623 | 1.EG +0.00 | 728.634
628624 | 1.EG +0.00 | 728.634
628625 | 1.EG +0.00 | 728.634
628626 | 1.EG +0.00 | 753.634
628627 | 1.EG +0.00 | 753.634
628628 | 1.EG +0.00 | 753.634
628629 | 1.EG +0.00 | 753.634
628630 | 1.EG +0.00 | 1100
628631 | 1.EG +0.00 | 1125
628632 | 1.EG +0.00 | 1125
628633 | 1.EG +0.00 | 1000
628634 | 1.EG +0.00 | 1100
628635 | 1.EG +0.00 | 1125
628636 | 1.EG +0.00 | 753.634
628637 | 1.EG +0.00 | 753.634
628638 | 1.EG +0.00 | 753.634
628639 | 1.EG +0.00 | 753.634
628640 | 1.EG +0.00 | 753.634
628641 | 1.EG +0.00 | 728.634
628642 | 1.EG +0.00 | 728.634
628643 | 1.EG +0.00 | 728.634
628644 | 1.EG +0.00 | 728.634
628645 | 1.EG +0.00 | 728.634
628646 | 1.EG +0.00 | 728.634
628647 | 1.EG +0.00 | 728.634
628648 | 1.EG +0.00 | 728.634
628649 | 1.EG +0.00 | 728.634
628650 | 1.EG +0.00 | 728.634
628651 | 1.EG +0.00 | 1000
628652 | 1.EG +0.00 | 1000
628653 | 1.EG +0.00 | 1100
628654 | 1.EG +0.00 | 1100
628655 | 1.EG +0.00 | 1150
628656 | 1.EG +0.00 | 1125
628657 | 1.EG +0.00 | 1150
628658 | 1.EG +0.00 | 1125
628659 | 1.EG +0.00 | 1125
628660 | 1.EG +0.00 | 1125
628661 | 1.EG +0.00 | 1125
628662 | 1.EG +0.00 | 1125
628697 | 1.EG +0.00 | 728.634
628698 | 1.EG +0.00 | 728.634
628699 | 1.EG +0.00 | 753.634
628700 | 1.EG +0.00 | 728.634
628701 | 1.EG +0.00 | 753.634
628702 | 1.EG +0.00 | 728.634
628703 | 1.EG +0.00 | 728.634
628704 | 1.EG +0.00 | 728.634
628705 | 1.EG +0.00 | 728.634
628706 | 1.EG +0.00 | 728.634
628707 | 1.EG +0.00 | 1000
628708 | 1.EG +0.00 | 1100
628709 | 1.EG +0.00 | 1150
628710 | 1.EG +0.00 | 1125
628711 | 1.EG +0.00 | 1125
628712 | 1.EG +0.00 | 1125
628602 | 1.EG +0.00 | 701.034
628603 | 1.EG +0.00 | 825
628604 | 1.EG +0.00 | 1000
628605 | 1.EG +0.00 | 800
628663 | 1.EG +0.00 | 825
628664 | 1.EG +0.00 | 677.068
628665 | 1.EG +0.00 | 702.072
628666 | 1.EG +0.00 | 726.036
628667 | 1.EG +0.00 | 1100
628668 | 1.EG +0.00 | 800
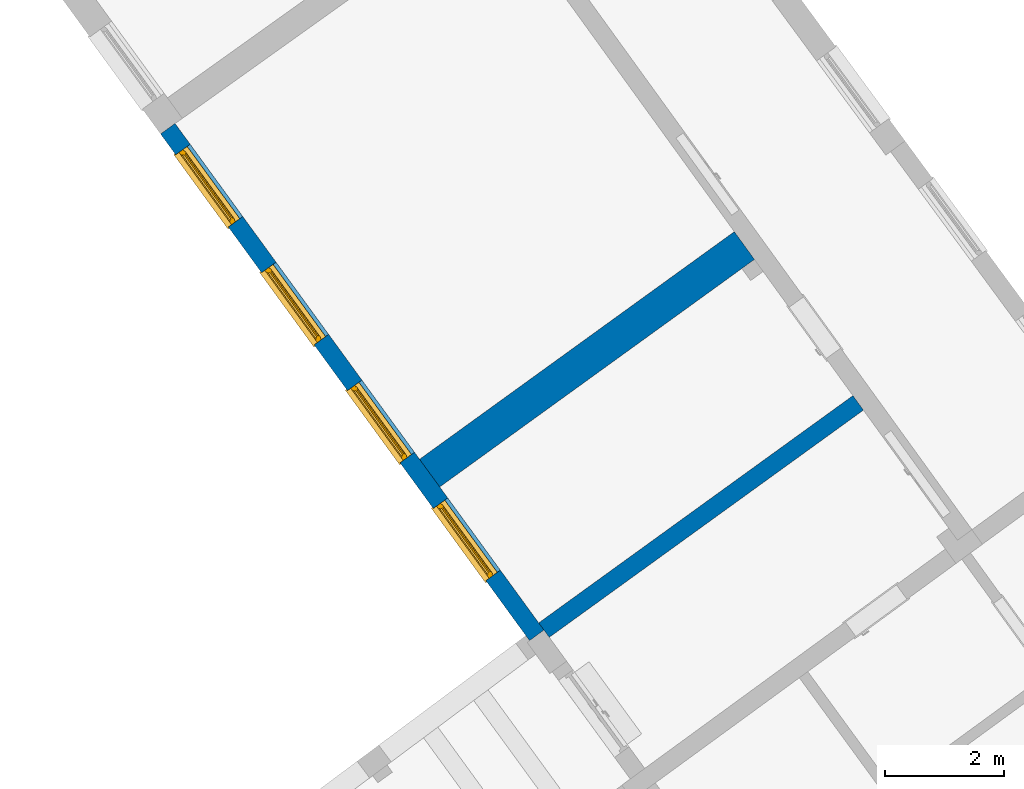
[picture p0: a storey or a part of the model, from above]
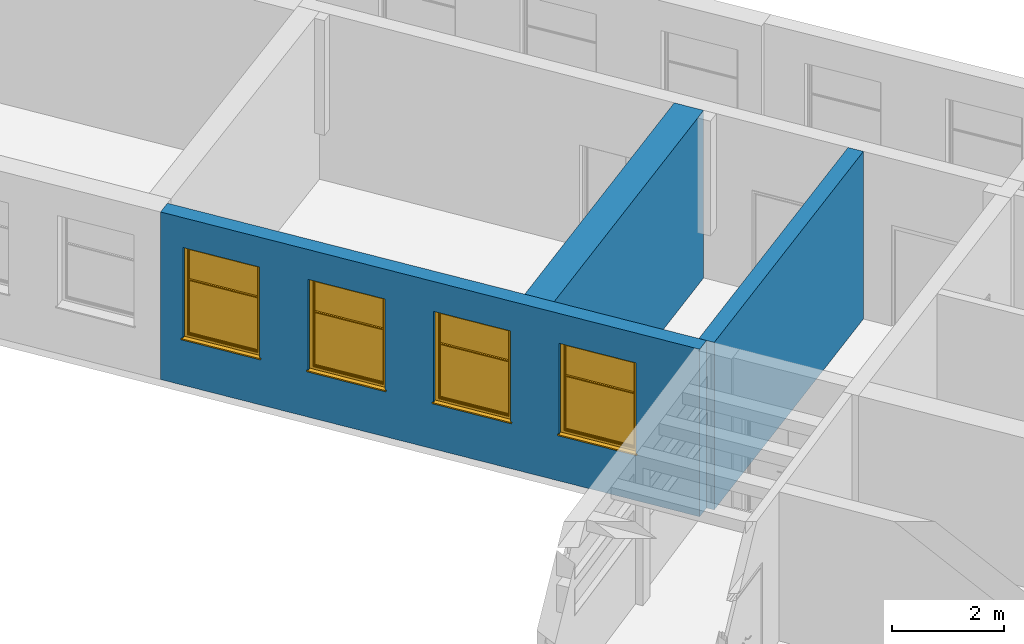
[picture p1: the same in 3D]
Properties of the parts of a building model (IFC2X3), part 5 of 13

# IfcMember: Rectangular Mullion:5x5 (2701)
Name (Rectangular Mullion:5x5:...) | In | Span (mm)
628669 | 1.EG +0.00 | 800
628670 | 1.EG +0.00 | 1000
628671 | 1.EG +0.00 | 1100
628672 | 1.EG +0.00 | 800
628673 | 1.EG +0.00 | 702.072
628674 | 1.EG +0.00 | 726.036
628675 | 1.EG +0.00 | 825
628676 | 1.EG +0.00 | 677.068
628677 | 1.EG +0.00 | 701.034
628678 | 1.EG +0.00 | 825
628679 | 1.EG +0.00 | 677.068
628680 | 1.EG +0.00 | 701.034
628681 | 1.EG +0.00 | 1000
628682 | 1.EG +0.00 | 1100
628683 | 1.EG +0.00 | 800
628684 | 1.EG +0.00 | 825
628685 | 1.EG +0.00 | 800
628686 | 1.EG +0.00 | 800
628723 | 1.EG +0.00 | 766.667
628724 | 1.EG +0.00 | 766.667
628725 | 1.EG +0.00 | 766.667
628726 | 1.EG +0.00 | 766.667
628727 | 1.EG +0.00 | 766.667
628728 | 1.EG +0.00 | 766.667
628729 | 1.EG +0.00 | 1500
628730 | 1.EG +0.00 | 900
628731 | 1.EG +0.00 | 1150
628732 | 1.EG +0.00 | 1500
628733 | 1.EG +0.00 | 766.667
628734 | 1.EG +0.00 | 766.667
628735 | 1.EG +0.00 | 766.667
628736 | 1.EG +0.00 | 1500
628737 | 1.EG +0.00 | 1500
628738 | 1.EG +0.00 | 900
628739 | 1.EG +0.00 | 900
628802 | 1.EG +0.00 | 1150
628803 | 1.EG +0.00 | 900
628804 | 1.EG +0.00 | 1150
628805 | 1.EG +0.00 | 1150
628806 | 1.EG +0.00 | 766.667
628807 | 1.EG +0.00 | 766.667
628808 | 1.EG +0.00 | 766.667
628747 | 1.EG +0.00 | 425
628748 | 1.EG +0.00 | 425
628749 | 1.EG +0.00 | 450
628750 | 1.EG +0.00 | 450
628751 | 1.EG +0.00 | 1500
628752 | 1.EG +0.00 | 900
628753 | 1.EG +0.00 | 1150
628754 | 1.EG +0.00 | 1500
628809 | 1.EG +0.00 | 1150
628810 | 1.EG +0.00 | 900
628811 | 1.EG +0.00 | 1175
628812 | 1.EG +0.00 | 425
628813 | 1.EG +0.00 | 425
628768 | 1.EG +0.00 | 688.246
628769 | 1.EG +0.00 | 738.246
628770 | 1.EG +0.00 | 738.246
628771 | 1.EG +0.00 | 738.246
628772 | 1.EG +0.00 | 738.246
628773 | 1.EG +0.00 | 738.246
628774 | 1.EG +0.00 | 738.246
628775 | 1.EG +0.00 | 688.246
628776 | 1.EG +0.00 | 1500
628777 | 1.EG +0.00 | 900
628778 | 1.EG +0.00 | 1150
628779 | 1.EG +0.00 | 1500
628780 | 1.EG +0.00 | 738.246
628781 | 1.EG +0.00 | 738.246
628782 | 1.EG +0.00 | 738.246
628783 | 1.EG +0.00 | 688.246
628784 | 1.EG +0.00 | 1500
628785 | 1.EG +0.00 | 1500
628786 | 1.EG +0.00 | 1500
628787 | 1.EG +0.00 | 900
628788 | 1.EG +0.00 | 900
628789 | 1.EG +0.00 | 900
628814 | 1.EG +0.00 | 1150
628815 | 1.EG +0.00 | 900
628816 | 1.EG +0.00 | 1150
628817 | 1.EG +0.00 | 1150
628818 | 1.EG +0.00 | 1150
628819 | 1.EG +0.00 | 738.246
628820 | 1.EG +0.00 | 738.246
628821 | 1.EG +0.00 | 738.246
628822 | 1.EG +0.00 | 688.246

# IfcMember: Stringer:Stringer-Paint-15mm_Width (4)
In: 1.EG +0.00
Type - PredefinedType: STRINGER
Material: Steel, Paint Finish, Dark Gray, Matte; Group: Model Group:Building:629362
Pset_MemberCommon - IsExternal: no; Reference: Stringer-Paint-15mm_Width; Slope: 90 deg
Pset_ProductRequirements - Category: Stairs: Supports
Pset_QuantityTakeOff - Reference: Stringer-Paint-15mm_Width
Name (Assembled Stair:Stair:...)
629207 Stringer 1
629207 Stringer 2
629355 Stringer 1
629355 Stringer 2

# IfcOpeningElement: Opening (908)
Name | In
Basic Wall:Wand_Aussen_35:630546 | 1.EG +0.00 | Pset_OpeningElementCommon - Reference: Wand_Aussen_35; sets with these values: 2; Pset_ProductRequirements - Category: Lines: <Sketch>; Group: Model Group:Building:629362
9 x Basic Wall:Wand_Innen_35:630553 | 1.EG +0.00 | Pset_OpeningElementCommon - Reference: Wand_Innen_35; sets with these values: 2; Pset_ProductRequirements - Category: Lines: <Sketch>; Group: Model Group:Building:629362
Columns_Rectangular:90x50:617836:1 | 1.EG +0.00 | Pset_OpeningElementCommon - Reference: 90x50; sets with these values: 2; Pset_ProductRequirements - Category: Columns; Group: Model Group:Building:629362
Columns_Rectangular:90x80:617948:1 | 1.EG +0.00 | Pset_OpeningElementCommon - Reference: 90x80; sets with these values: 2; Pset_ProductRequirements - Category: Columns; Group: Model Group:Building:629362
Floor:Boden_CJC:618466:2 | 1.EG +0.00 | Pset_OpeningElementCommon - Reference: Boden_CJC; sets with these values: 2; Pset_ProductRequirements - Category: Floors; Group: Model Group:Building:629362
Floor:Boden_CJC:618466:3 | 1.EG +0.00 | Pset_OpeningElementCommon - Reference: Boden_CJC; sets with these values: 2; Pset_ProductRequirements - Category: Floors; Group: Model Group:Building:629362
Floor:Boden_CJC:618466:4 | 1.EG +0.00 | Pset_OpeningElementCommon - Reference: Boden_CJC; sets with these values: 2; Pset_ProductRequirements - Category: Floors; Group: Model Group:Building:629362
Basic Wall:Wand_Innen_30:618725:1 | 1.EG +0.00 | Pset_OpeningElementCommon - Reference: Wand_Innen_30; sets with these values: 2; Pset_ProductRequirements - Category: Walls; Group: Model Group:Building:629362
Basic Wall:Wand_Innen_30:618726:1 | 1.EG +0.00 | Pset_OpeningElementCommon - Reference: Wand_Innen_30; sets with these values: 2; Pset_ProductRequirements - Category: Walls; Group: Model Group:Building:629362
8 x Basic Wall:Wand_Innen_35:630553 | 2.1OG +5.30 | Pset_OpeningElementCommon - Reference: Wand_Innen_35; sets with these values: 2; Pset_ProductRequirements - Category: Lines: <Sketch>; Group: Model Group:Building:629362
Floor:Boden_CJC:619257:2 | 2.1OG +5.30 | Pset_OpeningElementCommon - Reference: Boden_CJC; sets with these values: 2; Pset_ProductRequirements - Category: Floors; Group: Model Group:Building:629362
Basic Wall:Wand_Innen_30:619343 | 2.1OG +5.30 | Pset_OpeningElementCommon - Reference: Fenster_Aussen_NORD1_CJC; sets with these values: 2; Pset_ProductRequirements - Category: Windows; Group: Model Group:Building:629362
Basic Wall:Wand_Innen_30:619511:1 | 2.1OG +5.30 | Pset_OpeningElementCommon - Reference: Wand_Innen_30; sets with these values: 2; Pset_ProductRequirements - Category: Walls; Group: Model Group:Building:629362
Basic Wall:Wand_Aussen_35:619520 | 2.1OG +5.30 | Pset_OpeningElementCommon - Reference: 90x250; sets with these values: 2; Pset_ProductRequirements - Category: Windows; Group: Model Group:Building:629362
Basic Wall:Wand_Innen_30:619528 | 2.1OG +5.30 | Pset_OpeningElementCommon - Reference: 0610 x 1220mm; sets with these values: 2; Pset_ProductRequirements - Category: Windows; Group: Model Group:Building:629362
Basic Wall:Wand_Innen_32.5:619530 | 2.1OG +5.30 | Pset_OpeningElementCommon - Reference: 150x210; sets with these values: 2; Pset_ProductRequirements - Category: Doors; Group: Model Group:Building:629362
Basic Wall:Wand_Innen_30:619593:1 | 2.1OG +5.30 | Pset_OpeningElementCommon - Reference: Wand_Innen_30; sets with these values: 2; Pset_ProductRequirements - Category: Walls; Group: Model Group:Building:629362
Basic Wall:Wand_Innen_30:619601:1 | 2.1OG +5.30 | Pset_OpeningElementCommon - Reference: Wand_Innen_30; sets with these values: 2; Pset_ProductRequirements - Category: Walls; Group: Model Group:Building:629362
Basic Wall:Wand_Innen_30:619602:1 | 2.1OG +5.30 | Pset_OpeningElementCommon - Reference: Wand_Innen_30; sets with these values: 2; Pset_ProductRequirements - Category: Walls; Group: Model Group:Building:629362
Basic Wall:Wand_Innen_30:619603:1 | 2.1OG +5.30 | Pset_OpeningElementCommon - Reference: Wand_Innen_30; sets with these values: 2; Pset_ProductRequirements - Category: Walls; Group: Model Group:Building:629362
Basic Wall:Wand_Innen_55:619624 | 2.1OG +5.30 | Pset_OpeningElementCommon - Reference: 80x210; sets with these values: 2; Pset_ProductRequirements - Category: Doors; Group: Model Group:Building:629362
8 x Basic Wall:Wand_Innen_35:630553 | 3.2OG +10.60 | Pset_OpeningElementCommon - Reference: Wand_Innen_35; sets with these values: 2; Pset_ProductRequirements - Category: Lines: <Sketch>; Group: Model Group:Building:629362
Floor:Boden_CJC:619954:2 | 3.2OG +10.60 | Pset_OpeningElementCommon - Reference: Boden_CJC; sets with these values: 2; Pset_ProductRequirements - Category: Floors; Group: Model Group:Building:629362
Basic Wall:Wand_Aussen_35:620168 | 3.2OG +10.60 | Pset_OpeningElementCommon - Reference: 90x250; sets with these values: 2; Pset_ProductRequirements - Category: Windows; Group: Model Group:Building:629362
Basic Wall:Wand_Innen_30:620176 | 3.2OG +10.60 | Pset_OpeningElementCommon - Reference: 0610 x 1220mm; sets with these values: 2; Pset_ProductRequirements - Category: Windows; Group: Model Group:Building:629362
Basic Wall:Wand_Innen_32.5:620178 | 3.2OG +10.60 | Pset_OpeningElementCommon - Reference: 150x210; sets with these values: 2; Pset_ProductRequirements - Category: Doors; Group: Model Group:Building:629362
Basic Wall:Wand_Innen_30:620224:1 | 3.2OG +10.60 | Pset_OpeningElementCommon - Reference: Wand_Innen_30; sets with these values: 2; Pset_ProductRequirements - Category: Walls; Group: Model Group:Building:629362
Basic Wall:Wand_Innen_30:620229:1 | 3.2OG +10.60 | Pset_OpeningElementCommon - Reference: Wand_Innen_30; sets with these values: 2; Pset_ProductRequirements - Category: Walls; Group: Model Group:Building:629362
Basic Wall:Wand_Innen_30:620230:1 | 3.2OG +10.60 | Pset_OpeningElementCommon - Reference: Wand_Innen_30; sets with these values: 2; Pset_ProductRequirements - Category: Walls; Group: Model Group:Building:629362
Basic Wall:Wand_Innen_30:620231:1 | 3.2OG +10.60 | Pset_OpeningElementCommon - Reference: Wand_Innen_30; sets with these values: 2; Pset_ProductRequirements - Category: Walls; Group: Model Group:Building:629362
Basic Wall:Wand_Aussen_35:630546 | 4.3OG +15.90 | Pset_OpeningElementCommon - Reference: Wand_Aussen_35; sets with these values: 2; Pset_ProductRequirements - Category: Lines: <Sketch>; Group: Model Group:Building:629362
10 x Basic Wall:Wand_Innen_35:630553 | 4.3OG +15.90 | Pset_OpeningElementCommon - Reference: Wand_Innen_35; sets with these values: 2; Pset_ProductRequirements - Category: Lines: <Sketch>; Group: Model Group:Building:629362
Floor:Boden_CJC:620877:2 | 4.3OG +15.90 | Pset_OpeningElementCommon - Reference: Boden_CJC; sets with these values: 2; Pset_ProductRequirements - Category: Floors; Group: Model Group:Building:629362
Basic Wall:Wand_Aussen_35:621078 | 4.3OG +15.90 | Pset_OpeningElementCommon - Reference: 90x250; sets with these values: 2; Pset_ProductRequirements - Category: Windows; Group: Model Group:Building:629362
Basic Wall:Wand_Innen_30:621086 | 4.3OG +15.90 | Pset_OpeningElementCommon - Reference: 0610 x 1220mm; sets with these values: 2; Pset_ProductRequirements - Category: Windows; Group: Model Group:Building:629362
Basic Wall:Wand_Innen_35:621088 | 4.3OG +15.90 | Pset_OpeningElementCommon - Reference: 150x210; sets with these values: 2; Pset_ProductRequirements - Category: Doors; Group: Model Group:Building:629362
Basic Wall:Wand_Innen_30:621132:1 | 4.3OG +15.90 | Pset_OpeningElementCommon - Reference: Wand_Innen_30; sets with these values: 2; Pset_ProductRequirements - Category: Walls; Group: Model Group:Building:629362
Basic Wall:Wand_Innen_30:621137:1 | 4.3OG +15.90 | Pset_OpeningElementCommon - Reference: Wand_Innen_30; sets with these values: 2; Pset_ProductRequirements - Category: Walls; Group: Model Group:Building:629362
Basic Wall:Wand_Innen_30:621138:1 | 4.3OG +15.90 | Pset_OpeningElementCommon - Reference: Wand_Innen_30; sets with these values: 2; Pset_ProductRequirements - Category: Walls; Group: Model Group:Building:629362
Basic Wall:Wand_Innen_30:621139:1 | 4.3OG +15.90 | Pset_OpeningElementCommon - Reference: Wand_Innen_30; sets with these values: 2; Pset_ProductRequirements - Category: Walls; Group: Model Group:Building:629362
Basic Wall:Wand_Innen_15:621564 | 4.3OG +15.90 | Pset_OpeningElementCommon - Reference: 210x210; sets with these values: 2; Pset_ProductRequirements - Category: Doors; Group: Model Group:Building:629362
Basic Roof:Dach_CJC_CAP:621651:1 | 5.DG +21.50 | Pset_OpeningElementCommon - Reference: Dach_CJC_CAP; sets with these values: 2; Pset_ProductRequirements - Category: Roofs; Group: Model Group:Building:629362
Basic Roof:Dach_CJC_CAP:621651:2 | 5.DG +21.50 | Pset_OpeningElementCommon - Reference: Dach_CJC_CAP; sets with these values: 2; Pset_ProductRequirements - Category: Roofs; Group: Model Group:Building:629362
Basic Roof:Dach_CJC_CAP:621651:3 | 5.DG +21.50 | Pset_OpeningElementCommon - Reference: Dach_CJC_CAP; sets with these values: 2; Pset_ProductRequirements - Category: Roofs; Group: Model Group:Building:629362
Basic Wall:Wand_Innen_42.5:621681 | 1.EG +0.00 | Pset_OpeningElementCommon - Reference: 200x150; sets with these values: 2; Pset_ProductRequirements - Category: Windows; Group: Model Group:Building:629362
Basic Wall:Wand_Innen_30:621688:1 | 1.EG +0.00 | Pset_OpeningElementCommon - Reference: Wand_Innen_30; sets with these values: 2; Pset_ProductRequirements - Category: Walls; Group: Model Group:Building:629362
Basic Wall:Wand_Innen_30:621894:1 | 7.1OG KH +2.65 | Pset_OpeningElementCommon - Reference: Wand_Innen_30; sets with these values: 2; Pset_ProductRequirements - Category: Walls; Group: Model Group:Building:629362
Basic Wall:Wand_Innen_30:621895:1 | 7.1OG KH +2.65 | Pset_OpeningElementCommon - Reference: Wand_Innen_30; sets with these values: 2; Pset_ProductRequirements - Category: Walls; Group: Model Group:Building:629362
Basic Wall:Wand_Innen_35:621898:1 | 7.1OG KH +2.65 | Pset_OpeningElementCommon - Reference: Wand_Innen_35; sets with these values: 2; Pset_ProductRequirements - Category: Walls; Group: Model Group:Building:629362
Basic Wall:Wand_Innen_35:621899:1 | 7.1OG KH +2.65 | Pset_OpeningElementCommon - Reference: Wand_Innen_35; sets with these values: 2; Pset_ProductRequirements - Category: Walls; Group: Model Group:Building:629362
Basic Wall:Wand_Innen_42.5:622224 | 8.2OG KH +6.45 | Pset_OpeningElementCommon - Reference: 160x210; sets with these values: 2; Pset_ProductRequirements - Category: Doors; Group: Model Group:Building:629362
Basic Roof:Dach_CJC_CAP:622416:1 | 10.DG KH +14.25 | Pset_OpeningElementCommon - Reference: Dach_CJC_CAP; sets with these values: 2; Pset_ProductRequirements - Category: Roofs; Group: Model Group:Building:629362
Basic Wall:Wand_Aussen_35:622475 | 0.UG -3.60 | Pset_OpeningElementCommon - Reference: 508x270; sets with these values: 2; Pset_ProductRequirements - Category: Windows; Group: Model Group:Building:629362
Basic Wall:Wand_Innen_35:622991:1 | 0.UG -3.60 | Pset_OpeningElementCommon - Reference: Wand_Innen_35; sets with these values: 2; Pset_ProductRequirements - Category: Walls; Group: Model Group:Building:629362
Basic Wall:Wand_Innen_35:623013:1 | 0.UG -3.60 | Pset_OpeningElementCommon - Reference: Wand_Innen_35; sets with these values: 2; Pset_ProductRequirements - Category: Walls; Group: Model Group:Building:629362
Basic Wall:Wand_Innen_30:623039:1 | 0.UG -3.60 | Pset_OpeningElementCommon - Reference: Wand_Innen_30; sets with these values: 2; Pset_ProductRequirements - Category: Walls; Group: Model Group:Building:629362
Basic Wall:Wand_Innen_30:623039:2 | 0.UG -3.60 | Pset_OpeningElementCommon - Reference: Wand_Innen_30; sets with these values: 2; Pset_ProductRequirements - Category: Walls; Group: Model Group:Building:629362
Basic Wall:Wand_Innen_30:623039:3 | 0.UG -3.60 | Pset_OpeningElementCommon - Reference: Wand_Innen_30; sets with these values: 2; Pset_ProductRequirements - Category: Walls; Group: Model Group:Building:629362
Basic Wall:Wand_Innen_30:623039:4 | 0.UG -3.60 | Pset_OpeningElementCommon - Reference: Wand_Innen_30; sets with these values: 2; Pset_ProductRequirements - Category: Walls; Group: Model Group:Building:629362
Basic Wall:Wand_Innen_30:623039:5 | 0.UG -3.60 | Pset_OpeningElementCommon - Reference: Wand_Innen_30; sets with these values: 2; Pset_ProductRequirements - Category: Walls; Group: Model Group:Building:629362
Basic Wall:Wand_Innen_30:623039:6 | 0.UG -3.60 | Pset_OpeningElementCommon - Reference: Wand_Innen_30; sets with these values: 2; Pset_ProductRequirements - Category: Walls; Group: Model Group:Building:629362
Basic Wall:Wand_Innen_35:623042:1 | 0.UG -3.60 | Pset_OpeningElementCommon - Reference: Wand_Innen_35; sets with these values: 2; Pset_ProductRequirements - Category: Walls; Group: Model Group:Building:629362
Basic Wall:Wand_Innen_30:623044:1 | 0.UG -3.60 | Pset_OpeningElementCommon - Reference: Wand_Innen_30; sets with these values: 2; Pset_ProductRequirements - Category: Walls; Group: Model Group:Building:629362
Basic Wall:Wand_Innen_45:623243 | 0.UG -3.60 | Pset_OpeningElementCommon - Reference: 508x270; sets with these values: 2; Pset_ProductRequirements - Category: Windows; Group: Model Group:Building:629362
Basic Roof:Dach_CJC_CAP:624114:1 | 5.DG +21.50 | Pset_OpeningElementCommon - Reference: Dach_CJC_CAP; sets with these values: 2; Pset_ProductRequirements - Category: Roofs; Group: Model Group:Building:629362
Basic Roof:Dach_CJC_CAP:624136:1 | 5.DG +21.50 | Pset_OpeningElementCommon - Reference: Dach_CJC_CAP; sets with these values: 2; Pset_ProductRequirements - Category: Roofs; Group: Model Group:Building:629362
Basic Roof:Dach_CJC_CAP:624136:2 | 5.DG +21.50 | Pset_OpeningElementCommon - Reference: Dach_CJC_CAP; sets with these values: 2; Pset_ProductRequirements - Category: Roofs; Group: Model Group:Building:629362
Tuer_Aussen_NORD_EG_CJC:Tuer_Aussen_NORD_EG_CJC:623742:1 | 1.EG +0.00
Fenster_Aussen_CJC:Fenster_Aussen_CJC_265x350:618463:1 | 1.EG +0.00
Doors_IntSgl:100x210:618558:1 | 1.EG +0.00
M_Door-Exterior-Double:265x350:618561:1 | 1.EG +0.00
Fenster_Aussen_CJC:Fenster_Aussen_CJC_265x350:618304:1 | 1.EG +0.00
Fenster_Aussen_CJC:Fenster_Aussen_CJC_265x350:618303:1 | 1.EG +0.00
Fenster_Aussen_CJC_TOPONLY:Fenster_Aussen_CJC_TOPONLY:618562:1 | 1.EG +0.00
Fenster_Aussen_CJC:Fenster_Aussen_CJC_265x350:618290:1 | 1.EG +0.00
Fenster_Aussen_CJC:Fenster_Aussen_CJC_265x350:618291:1 | 1.EG +0.00
Fenster_Aussen_CJC:Fenster_Aussen_CJC_265x350:618292:1 | 1.EG +0.00
Fenster_Aussen_CJC:Fenster_Aussen_CJC_265x350:618293:1 | 1.EG +0.00
Fenster_Aussen_CJC:Fenster_Aussen_CJC_265x350:618294:1 | 1.EG +0.00
Fenster_Aussen_CJC:Fenster_Aussen_CJC_265x350:618295:1 | 1.EG +0.00
Fenster_Aussen_CJC:Fenster_Aussen_CJC_265x350:618296:1 | 1.EG +0.00
Fenster_Aussen_CJC:Fenster_Aussen_CJC_265x350:618297:1 | 1.EG +0.00
Fenster_Aussen_CJC:Fenster_Aussen_CJC_265x350:618298:1 | 1.EG +0.00
Fenster_Aussen_CJC:Fenster_Aussen_CJC_265x350:618299:1 | 1.EG +0.00
Fenster_Aussen_CJC:Fenster_Aussen_CJC_265x350:618300:1 | 1.EG +0.00
Fenster_Aussen_CJC:Fenster_Aussen_CJC_265x350:618301:1 | 1.EG +0.00
Fenster_Aussen_CJC:Fenster_Aussen_CJC_265x350:618302:1 | 1.EG +0.00
Fenster_Aussen_CJC:Fenster_Aussen_CJC_265x350:618305:1 | 1.EG +0.00
Fenster_Aussen_CJC:Fenster_Aussen_CJC_265x350:618335:1 | 1.EG +0.00
Fenster_Aussen_CJC:Fenster_Aussen_CJC_265x350:618336:1 | 1.EG +0.00
Fenster_Aussen_CJC:Fenster_Aussen_CJC_265x350:618337:1 | 1.EG +0.00
Fenster_Aussen_CJC:Fenster_Aussen_CJC_265x350:618338:1 | 1.EG +0.00
Fenster_Aussen_CJC:Fenster_Aussen_CJC_265x350:618339:1 | 1.EG +0.00
Fenster_Aussen_CJC:Fenster_Aussen_CJC_265x350:618340:1 | 1.EG +0.00
Fenster_Aussen_CJC:Fenster_Aussen_CJC_265x350:618341:1 | 1.EG +0.00
Fenster_Aussen_CJC:Fenster_Aussen_CJC_265x350:618342:1 | 1.EG +0.00
Fenster_Aussen_CJC:Fenster_Aussen_CJC_265x350:618343:1 | 1.EG +0.00
Fenster_Aussen_CJC:Fenster_Aussen_CJC_265x350:618344:1 | 1.EG +0.00
Fenster_Aussen_CJC:Fenster_Aussen_CJC_265x350:618345:1 | 1.EG +0.00
Fenster_Aussen_CJC:Fenster_Aussen_CJC_265x350:618346:1 | 1.EG +0.00
Fenster_Aussen_CJC:Fenster_Aussen_CJC_265x350:618347:1 | 1.EG +0.00
Fenster_Aussen_CJC:Fenster_Aussen_CJC_265x350:618348:1 | 1.EG +0.00
Fenster_Aussen_CJC:Fenster_Aussen_CJC_265x350:618349:1 | 1.EG +0.00
Fenster_Aussen_CJC:Fenster_Aussen_CJC_265x350:618350:1 | 1.EG +0.00
Doors_IntSgl:100x210:618549:1 | 1.EG +0.00
Doors_IntSgl:90x210:618552:1 | 1.EG +0.00
Doors_IntSgl:90x210:618551:1 | 1.EG +0.00
M_Door-Passage-Double-Flush:160x210:618611:1 | 1.EG +0.00
Doors_IntSgl:100x210:618525:1 | 1.EG +0.00
M_Door-Passage-Double-Flush:160x210:618621:1 | 1.EG +0.00
M_Door-Passage-Double-Flush:150x210:618607:1 | 1.EG +0.00
M_Door-Passage-Double-Flush:160x210:618601:1 | 1.EG +0.00
M_Door-Passage-Double-Flush:160x210:618608:1 | 1.EG +0.00
Doors_IntSgl:100x210:618518:1 | 1.EG +0.00
Doors_IntSgl:100x210:618519:1 | 1.EG +0.00
Doors_IntSgl:100x210:618520:1 | 1.EG +0.00
M_Door-Passage-Double-Flush:160x210:618609:1 | 1.EG +0.00
M_Door-Passage-Double-Flush:160x210:618610:1 | 1.EG +0.00
Doors_IntSgl:100x210:618555:1 | 1.EG +0.00
Fenster_Aussen_CJC:Fenster_Aussen_CJC_265x350:618306:1 | 1.EG +0.00
Fenster_Aussen_CJC:Fenster_Aussen_CJC_265x350:618307:1 | 1.EG +0.00
Fenster_Aussen_CJC:Fenster_Aussen_CJC_265x350:618308:1 | 1.EG +0.00
Fenster_Aussen_CJC:Fenster_Aussen_CJC_265x350:618309:1 | 1.EG +0.00
Fenster_Aussen_CJC:Fenster_Aussen_CJC_265x350:618310:1 | 1.EG +0.00
Fenster_Aussen_CJC:Fenster_Aussen_CJC_265x350:618311:1 | 1.EG +0.00
Fenster_Aussen_CJC:Fenster_Aussen_CJC_265x350:618312:1 | 1.EG +0.00
Fenster_Aussen_CJC:Fenster_Aussen_CJC_265x350:618313:1 | 1.EG +0.00
Fenster_Aussen_CJC:Fenster_Aussen_CJC_265x350:618314:1 | 1.EG +0.00
Fenster_Aussen_CJC:Fenster_Aussen_CJC_265x350:618315:1 | 1.EG +0.00
Fenster_Aussen_CJC:Fenster_Aussen_CJC_265x350:618316:1 | 1.EG +0.00
Fenster_Aussen_CJC:Fenster_Aussen_CJC_265x350:618317:1 | 1.EG +0.00
Fenster_Aussen_CJC:Fenster_Aussen_CJC_265x350:618318:1 | 1.EG +0.00
Fenster_Aussen_CJC:Fenster_Aussen_CJC_265x350:618319:1 | 1.EG +0.00
Fenster_Aussen_CJC:Fenster_Aussen_CJC_265x350:618320:1 | 1.EG +0.00
Fenster_Aussen_CJC:Fenster_Aussen_CJC_265x350:618321:1 | 1.EG +0.00
Fenster_Aussen_CJC:Fenster_Aussen_CJC_265x350:618322:1 | 1.EG +0.00
Fenster_Aussen_CJC:Fenster_Aussen_CJC_265x350:618323:1 | 1.EG +0.00
Fenster_Aussen_CJC:Fenster_Aussen_CJC_265x350:618324:1 | 1.EG +0.00
Fenster_Aussen_CJC:Fenster_Aussen_CJC_265x350:618325:1 | 1.EG +0.00
Fenster_Aussen_CJC:Fenster_Aussen_CJC_265x350:618326:1 | 1.EG +0.00
Fenster_Aussen_CJC:Fenster_Aussen_CJC_265x350:618327:1 | 1.EG +0.00
Fenster_Aussen_CJC:Fenster_Aussen_CJC_265x350:618328:1 | 1.EG +0.00
Fenster_Aussen_CJC:Fenster_Aussen_CJC_265x350:618329:1 | 1.EG +0.00
Fenster_Aussen_CJC:Fenster_Aussen_CJC_265x350:618330:1 | 1.EG +0.00
Fenster_Aussen_CJC:Fenster_Aussen_CJC_265x350:618331:1 | 1.EG +0.00
Fenster_Aussen_CJC:Fenster_Aussen_CJC_265x350:618332:1 | 1.EG +0.00
Fenster_Aussen_CJC:Fenster_Aussen_CJC_265x350:618333:1 | 1.EG +0.00
Fenster_Aussen_CJC:Fenster_Aussen_CJC_265x350:618334:1 | 1.EG +0.00
Doors_IntSgl:100x210:618460:1 | 1.EG +0.00
M_Door-Passage-Double-Flush:150x210:618461:1 | 1.EG +0.00
Doors_IntSgl:100x210:618462:1 | 1.EG +0.00
Doors_IntSgl:100x210:618521:1 | 1.EG +0.00
Doors_IntSgl:100x210:618522:1 | 1.EG +0.00
Doors_IntSgl:100x210:618523:1 | 1.EG +0.00
Doors_IntSgl:100x210:618524:1 | 1.EG +0.00
Doors_IntSgl:90x210:618546:1 | 1.EG +0.00
Doors_IntSgl:90x210:618547:1 | 1.EG +0.00
Doors_IntSgl:100x210:618548:1 | 1.EG +0.00
Doors_IntSgl:90x210:618550:1 | 1.EG +0.00
Doors_IntSgl:90x210:618553:1 | 1.EG +0.00
Doors_IntSgl:90x210:618554:1 | 1.EG +0.00
Doors_IntSgl:100x210:618556:1 | 1.EG +0.00
Doors_IntSgl:100x210:618557:1 | 1.EG +0.00
M_Door-Passage-Double-Flush:160x210:618600:1 | 1.EG +0.00
M_Door-Passage-Double-Flush:160x210:618602:1 | 1.EG +0.00
M_Door-Passage-Double-Flush:160x210:618603:1 | 1.EG +0.00
M_Door-Passage-Double-Flush:160x210:618604:1 | 1.EG +0.00
M_Door-Passage-Double-Flush:160x210:618605:1 | 1.EG +0.00
M_Door-Passage-Double-Flush:160x210:618606:1 | 1.EG +0.00
M_Door-Passage-Double-Flush:160x210:618612:1 | 1.EG +0.00
M_Door-Passage-Double-Flush:160x210:618613:1 | 1.EG +0.00
M_Door-Passage-Double-Flush:160x210:618614:1 | 1.EG +0.00
M_Door-Passage-Double-Flush:160x210:618615:1 | 1.EG +0.00
M_Door-Passage-Double-Flush:160x210:618616:1 | 1.EG +0.00
M_Door-Passage-Double-Flush:160x210:618617:1 | 1.EG +0.00
M_Door-Passage-Double-Flush:160x210:618618:1 | 1.EG +0.00
M_Door-Passage-Double-Flush:160x210:618619:1 | 1.EG +0.00
M_Door-Passage-Double-Flush:160x210:618620:1 | 1.EG +0.00
M_Door-Passage-Double-Flush:150x210:618622:1 | 1.EG +0.00
M_Door-Passage-Double-Flush:160x210:618624:1 | 1.EG +0.00
M_Door-Passage-Double-Flush:130x210:618625:1 | 1.EG +0.00
Fenster_Aussen_NORD1_CJC:Fenster_Aussen_NORD1_CJC:618650:1 | 1.EG +0.00
Doors_IntSgl:90x210:618790:1 | 1.EG +0.00
Fenster_Aussen_CJC:Fenster_Aussen_CJC_265x350:619254:1 | 2.1OG +5.30
Fenster_Aussen_CJC:Fenster_Aussen_CJC_265x350:619519:1 | 2.1OG +5.30
Fenster_Tuer_Fass_CJC:Fenster_Tuer_Fass_CJC:623733:1 | 2.1OG +5.30
Fenster_Aussen_CJC:Fenster_Aussen_CJC_265x350:619203:1 | 2.1OG +5.30
Fenster_Aussen_CJC:Fenster_Aussen_CJC_265x350:619202:1 | 2.1OG +5.30
Fenster_Aussen_CJC:Fenster_Aussen_CJC_265x350:619189:1 | 2.1OG +5.30
Fenster_Aussen_CJC:Fenster_Aussen_CJC_265x350:619190:1 | 2.1OG +5.30
Fenster_Aussen_CJC:Fenster_Aussen_CJC_265x350:619191:1 | 2.1OG +5.30
Fenster_Aussen_CJC:Fenster_Aussen_CJC_265x350:619192:1 | 2.1OG +5.30
Fenster_Aussen_CJC:Fenster_Aussen_CJC_265x350:619193:1 | 2.1OG +5.30
Fenster_Aussen_CJC:Fenster_Aussen_CJC_265x350:619194:1 | 2.1OG +5.30
Fenster_Aussen_CJC:Fenster_Aussen_CJC_265x350:619195:1 | 2.1OG +5.30
Fenster_Aussen_CJC:Fenster_Aussen_CJC_265x350:619196:1 | 2.1OG +5.30
Fenster_Aussen_CJC:Fenster_Aussen_CJC_265x350:619197:1 | 2.1OG +5.30
Fenster_Aussen_CJC:Fenster_Aussen_CJC_265x350:619198:1 | 2.1OG +5.30
Fenster_Aussen_CJC:Fenster_Aussen_CJC_265x350:619199:1 | 2.1OG +5.30
Fenster_Aussen_CJC:Fenster_Aussen_CJC_265x350:619200:1 | 2.1OG +5.30
Fenster_Aussen_CJC:Fenster_Aussen_CJC_265x350:619201:1 | 2.1OG +5.30
Fenster_Aussen_CJC:Fenster_Aussen_CJC_265x350:619204:1 | 2.1OG +5.30
Fenster_Aussen_CJC:Fenster_Aussen_CJC_265x350:619532:1 | 2.1OG +5.30
Fenster_Aussen_CJC:Fenster_Aussen_CJC_265x350:619234:1 | 2.1OG +5.30
Fenster_Aussen_CJC:Fenster_Aussen_CJC_265x350:619235:1 | 2.1OG +5.30
Fenster_Aussen_CJC:Fenster_Aussen_CJC_265x350:619236:1 | 2.1OG +5.30
Fenster_Aussen_CJC:Fenster_Aussen_CJC_265x350:619237:1 | 2.1OG +5.30
Fenster_Aussen_CJC:Fenster_Aussen_CJC_265x350:619238:1 | 2.1OG +5.30
Fenster_Aussen_CJC:Fenster_Aussen_CJC_265x350:619239:1 | 2.1OG +5.30
Fenster_Aussen_CJC:Fenster_Aussen_CJC_265x350:619240:1 | 2.1OG +5.30
Fenster_Aussen_CJC:Fenster_Aussen_CJC_265x350:619241:1 | 2.1OG +5.30
Fenster_Aussen_CJC:Fenster_Aussen_CJC_265x350:619242:1 | 2.1OG +5.30
Fenster_Aussen_CJC:Fenster_Aussen_CJC_265x350:619243:1 | 2.1OG +5.30
Fenster_Aussen_CJC:Fenster_Aussen_CJC_265x350:619244:1 | 2.1OG +5.30
Fenster_Aussen_CJC:Fenster_Aussen_CJC_265x350:619245:1 | 2.1OG +5.30
Fenster_Aussen_CJC:Fenster_Aussen_CJC_265x350:619246:1 | 2.1OG +5.30
Fenster_Aussen_CJC:Fenster_Aussen_CJC_265x350:619247:1 | 2.1OG +5.30
Fenster_Aussen_CJC:Fenster_Aussen_CJC_265x350:619248:1 | 2.1OG +5.30
Fenster_Aussen_CJC:Fenster_Aussen_CJC_265x350:619249:1 | 2.1OG +5.30
M_Window-Louvers:140x310:619616:1 | 2.1OG +5.30
Fenster_Aussen_CJC:Fenster_Aussen_CJC_265x350:619613:1 | 2.1OG +5.30
Fenster_Aussen_CJC:Fenster_Aussen_CJC_265x350:619615:1 | 2.1OG +5.30
Doors_IntSgl:100x210:619665:1 | 2.1OG +5.30
M_Door-Passage-Double-Flush:150x210:619663:1 | 2.1OG +5.30
M_Door-Passage-Double-Flush:160x210:619341:1 | 2.1OG +5.30
Doors_IntSgl:100x210:619303:1 | 2.1OG +5.30
Doors_IntSgl:100x210:619639:1 | 2.1OG +5.30
Doors_IntSgl:100x210:619640:1 | 2.1OG +5.30
Fenster_Aussen_CJC:Fenster_Aussen_CJC_265x350:619205:1 | 2.1OG +5.30
Fenster_Aussen_CJC:Fenster_Aussen_CJC_265x350:619206:1 | 2.1OG +5.30
Fenster_Aussen_CJC:Fenster_Aussen_CJC_265x350:619207:1 | 2.1OG +5.30
Fenster_Aussen_CJC:Fenster_Aussen_CJC_265x350:619208:1 | 2.1OG +5.30
Fenster_Aussen_CJC:Fenster_Aussen_CJC_265x350:619209:1 | 2.1OG +5.30
Fenster_Aussen_CJC:Fenster_Aussen_CJC_265x350:619210:1 | 2.1OG +5.30
Fenster_Aussen_CJC:Fenster_Aussen_CJC_265x350:619211:1 | 2.1OG +5.30
Fenster_Aussen_CJC:Fenster_Aussen_CJC_265x350:619212:1 | 2.1OG +5.30
Fenster_Aussen_CJC:Fenster_Aussen_CJC_265x350:619213:1 | 2.1OG +5.30
Fenster_Aussen_CJC:Fenster_Aussen_CJC_265x350:619214:1 | 2.1OG +5.30
Fenster_Aussen_CJC:Fenster_Aussen_CJC_265x350:619215:1 | 2.1OG +5.30
Fenster_Aussen_CJC:Fenster_Aussen_CJC_265x350:619216:1 | 2.1OG +5.30
Fenster_Aussen_CJC:Fenster_Aussen_CJC_265x350:619217:1 | 2.1OG +5.30
Fenster_Aussen_CJC:Fenster_Aussen_CJC_265x350:619218:1 | 2.1OG +5.30
Fenster_Aussen_CJC:Fenster_Aussen_CJC_265x350:619699:1 | 2.1OG +5.30
Fenster_Aussen_CJC:Fenster_Aussen_CJC_265x350:619700:1 | 2.1OG +5.30
Fenster_Aussen_CJC:Fenster_Aussen_CJC_265x350:623875:1 | 2.1OG +5.30
Fenster_Aussen_CJC:Fenster_Aussen_CJC_265x350:623876:1 | 2.1OG +5.30
M_Door-Passage-Double-Flush:160x210:619340:1 | 2.1OG +5.30
Doors_IntSgl:100x210:619296:1 | 2.1OG +5.30
Doors_IntSgl:100x210:619297:1 | 2.1OG +5.30
Doors_IntSgl:100x210:619298:1 | 2.1OG +5.30
Doors_IntSgl:100x210:619584:1 | 2.1OG +5.30
Fenster_Corridor200x100x350_CJC:Fenster_Corridor200x100x350_CJC:627815:1 | 2.1OG +5.30
Fenster_Corridor200x100x350_CJC:Fenster_Corridor200x100x350_CJC:627816:1 | 2.1OG +5.30
Fenster_Corridor200x100x350_CJC:Fenster_Corridor200x100x350_CJC:627817:1 | 2.1OG +5.30
Fenster_Corridor200x100x350_CJC:Fenster_Corridor200x100x350_CJC:627818:1 | 2.1OG +5.30
Fenster_Aussen_CJC:Fenster_Aussen_CJC_265x350:619219:1 | 2.1OG +5.30
Fenster_Aussen_CJC:Fenster_Aussen_CJC_265x350:619220:1 | 2.1OG +5.30
Fenster_Aussen_CJC:Fenster_Aussen_CJC_265x350:619221:1 | 2.1OG +5.30
Fenster_Aussen_CJC:Fenster_Aussen_CJC_265x350:619222:1 | 2.1OG +5.30
Fenster_Aussen_CJC:Fenster_Aussen_CJC_265x350:619223:1 | 2.1OG +5.30
Fenster_Aussen_CJC:Fenster_Aussen_CJC_265x350:619224:1 | 2.1OG +5.30
Fenster_Aussen_CJC:Fenster_Aussen_CJC_265x350:619225:1 | 2.1OG +5.30
Fenster_Aussen_CJC:Fenster_Aussen_CJC_265x350:619226:1 | 2.1OG +5.30
Fenster_Aussen_CJC:Fenster_Aussen_CJC_265x350:619227:1 | 2.1OG +5.30
Fenster_Aussen_CJC:Fenster_Aussen_CJC_265x350:619228:1 | 2.1OG +5.30
Fenster_Aussen_CJC:Fenster_Aussen_CJC_265x350:619229:1 | 2.1OG +5.30
Fenster_Aussen_CJC:Fenster_Aussen_CJC_265x350:619230:1 | 2.1OG +5.30
Fenster_Aussen_CJC:Fenster_Aussen_CJC_265x350:619231:1 | 2.1OG +5.30
Fenster_Aussen_CJC:Fenster_Aussen_CJC_265x350:619232:1 | 2.1OG +5.30
Fenster_Aussen_CJC:Fenster_Aussen_CJC_265x350:619233:1 | 2.1OG +5.30
M_Window-Louvers:140x250:619621:1 | 2.1OG +5.30
Doors_IntSgl:100x210:619253:1 | 2.1OG +5.30
Doors_IntSgl:100x210:619299:1 | 2.1OG +5.30
Doors_IntSgl:100x210:619300:1 | 2.1OG +5.30
Doors_IntSgl:100x210:619301:1 | 2.1OG +5.30
Doors_IntSgl:100x210:619302:1 | 2.1OG +5.30
Doors_IntSgl:80x210:619320:1 | 2.1OG +5.30
M_Door-Passage-Double-Flush:150x210:619342:1 | 2.1OG +5.30
Doors_IntSgl:100x210:619636:1 | 2.1OG +5.30
Doors_IntSgl:90x210:619637:1 | 2.1OG +5.30
M_Door-Passage-Double-Flush:160x210:619344:1 | 2.1OG +5.30
Fenster_Aussen_NORD1_CJC:Fenster_Aussen_NORD1_CJC:619360:1 | 2.1OG +5.30
Fenster_Aussen_NORD2_CJC:Fenster_Aussen_NORD2_CJC:619368:1 | 2.1OG +5.30
Doors_IntSgl:90x210:619622:1 | 2.1OG +5.30
Fenster_Aussen_CJC:Fenster_Aussen_CJC_265x350:619701:1 | 2.1OG +5.30
M_Window-Louvers:90x250:619675:1 | 2.1OG +5.30
Doors_IntSgl:100x210:619666:1 | 2.1OG +5.30
M_Instance-Window-Fixed:0610 x 1220mm:619670:1 | 2.1OG +5.30
Doors_IntSgl:100x200:619669:1 | 2.1OG +5.30
M_Instance-Window-Fixed:0610 x 1220mm:619671:1 | 2.1OG +5.30
Doors_IntSgl:100x200:619668:1 | 2.1OG +5.30
M_Instance-Window-Fixed:0610 x 1220mm:619672:1 | 2.1OG +5.30
Doors_IntSgl:100x210:619662:1 | 2.1OG +5.30
Doors_IntSgl:100x210:619664:1 | 2.1OG +5.30
Doors_IntSgl:100x210:619586:1 | 2.1OG +5.30
Doors_IntSgl:100x210:619641:1 | 2.1OG +5.30
Doors_IntSgl:100x200:619659:1 | 2.1OG +5.30
M_Instance-Window-Fixed:0610 x 1220mm:619660:1 | 2.1OG +5.30
Doors_IntSgl:90x210:619626:1 | 2.1OG +5.30
M_Door-Passage-Double-Flush:150x210:619629:1 | 2.1OG +5.30
Doors_IntSgl:100x210:619630:1 | 2.1OG +5.30
Doors_IntSgl:100x210:619631:1 | 2.1OG +5.30
Doors_IntSgl:100x210:619632:1 | 2.1OG +5.30
M_Door-Passage-Double-Flush:160x210:619638:1 | 2.1OG +5.30
Doors_IntSgl:100x200:619667:1 | 2.1OG +5.30
Fenster_Aussen_CJC:Fenster_Aussen_CJC_265x350:619951:1 | 3.2OG +10.60
Fenster_Aussen_CJC:Fenster_Aussen_CJC_265x350:620167:1 | 3.2OG +10.60
Fenster_Tuer_Fass_CJC:Fenster_Tuer_Fass_CJC:623734:1 | 3.2OG +10.60
Fenster_Aussen_CJC:Fenster_Aussen_CJC_265x350:619900:1 | 3.2OG +10.60
Fenster_Aussen_CJC:Fenster_Aussen_CJC_265x350:619899:1 | 3.2OG +10.60
Fenster_Aussen_CJC:Fenster_Aussen_CJC_265x350:619886:1 | 3.2OG +10.60
Fenster_Aussen_CJC:Fenster_Aussen_CJC_265x350:619887:1 | 3.2OG +10.60
Fenster_Aussen_CJC:Fenster_Aussen_CJC_265x350:619888:1 | 3.2OG +10.60
Fenster_Aussen_CJC:Fenster_Aussen_CJC_265x350:619889:1 | 3.2OG +10.60
Fenster_Aussen_CJC:Fenster_Aussen_CJC_265x350:619890:1 | 3.2OG +10.60
Fenster_Aussen_CJC:Fenster_Aussen_CJC_265x350:619891:1 | 3.2OG +10.60
Fenster_Aussen_CJC:Fenster_Aussen_CJC_265x350:619892:1 | 3.2OG +10.60
Fenster_Aussen_CJC:Fenster_Aussen_CJC_265x350:619893:1 | 3.2OG +10.60
Fenster_Aussen_CJC:Fenster_Aussen_CJC_265x350:619894:1 | 3.2OG +10.60
Fenster_Aussen_CJC:Fenster_Aussen_CJC_265x350:619895:1 | 3.2OG +10.60
Fenster_Aussen_CJC:Fenster_Aussen_CJC_265x350:619896:1 | 3.2OG +10.60
Fenster_Aussen_CJC:Fenster_Aussen_CJC_265x350:619897:1 | 3.2OG +10.60
Fenster_Aussen_CJC:Fenster_Aussen_CJC_265x350:619898:1 | 3.2OG +10.60
Fenster_Aussen_CJC:Fenster_Aussen_CJC_265x350:619901:1 | 3.2OG +10.60
Fenster_Aussen_CJC:Fenster_Aussen_CJC_265x350:620180:1 | 3.2OG +10.60
Fenster_Aussen_CJC:Fenster_Aussen_CJC_265x350:619931:1 | 3.2OG +10.60
Fenster_Aussen_CJC:Fenster_Aussen_CJC_265x350:619932:1 | 3.2OG +10.60
Fenster_Aussen_CJC:Fenster_Aussen_CJC_265x350:619933:1 | 3.2OG +10.60
Fenster_Aussen_CJC:Fenster_Aussen_CJC_265x350:619934:1 | 3.2OG +10.60
Fenster_Aussen_CJC:Fenster_Aussen_CJC_265x350:619935:1 | 3.2OG +10.60
Fenster_Aussen_CJC:Fenster_Aussen_CJC_265x350:619936:1 | 3.2OG +10.60
Fenster_Aussen_CJC:Fenster_Aussen_CJC_265x350:619937:1 | 3.2OG +10.60
Fenster_Aussen_CJC:Fenster_Aussen_CJC_265x350:619938:1 | 3.2OG +10.60
Fenster_Aussen_CJC:Fenster_Aussen_CJC_265x350:619939:1 | 3.2OG +10.60
Fenster_Aussen_CJC:Fenster_Aussen_CJC_265x350:619940:1 | 3.2OG +10.60
Fenster_Aussen_CJC:Fenster_Aussen_CJC_265x350:619941:1 | 3.2OG +10.60
Fenster_Aussen_CJC:Fenster_Aussen_CJC_265x350:619942:1 | 3.2OG +10.60
Fenster_Aussen_CJC:Fenster_Aussen_CJC_265x350:619943:1 | 3.2OG +10.60
Fenster_Aussen_CJC:Fenster_Aussen_CJC_265x350:619944:1 | 3.2OG +10.60
Fenster_Aussen_CJC:Fenster_Aussen_CJC_265x350:619945:1 | 3.2OG +10.60
Fenster_Aussen_CJC:Fenster_Aussen_CJC_265x350:619946:1 | 3.2OG +10.60
M_Window-Louvers:140x310:620244:1 | 3.2OG +10.60
Fenster_Aussen_CJC:Fenster_Aussen_CJC_265x350:620241:1 | 3.2OG +10.60
Fenster_Aussen_CJC:Fenster_Aussen_CJC_265x350:620243:1 | 3.2OG +10.60
Doors_IntSgl:100x210:620284:1 | 3.2OG +10.60
M_Door-Passage-Double-Flush:150x210:620282:1 | 3.2OG +10.60
M_Door-Passage-Double-Flush:160x210:620037:1 | 3.2OG +10.60
Doors_IntSgl:100x210:620000:1 | 3.2OG +10.60
Doors_IntSgl:100x210:620259:1 | 3.2OG +10.60
Doors_IntSgl:100x210:620260:1 | 3.2OG +10.60
Fenster_Aussen_CJC:Fenster_Aussen_CJC_265x350:619902:1 | 3.2OG +10.60
Fenster_Aussen_CJC:Fenster_Aussen_CJC_265x350:619903:1 | 3.2OG +10.60
Fenster_Aussen_CJC:Fenster_Aussen_CJC_265x350:619904:1 | 3.2OG +10.60
Fenster_Aussen_CJC:Fenster_Aussen_CJC_265x350:619905:1 | 3.2OG +10.60
Fenster_Aussen_CJC:Fenster_Aussen_CJC_265x350:619906:1 | 3.2OG +10.60
Fenster_Aussen_CJC:Fenster_Aussen_CJC_265x350:619907:1 | 3.2OG +10.60
Fenster_Aussen_CJC:Fenster_Aussen_CJC_265x350:619908:1 | 3.2OG +10.60
Fenster_Aussen_CJC:Fenster_Aussen_CJC_265x350:619909:1 | 3.2OG +10.60
Fenster_Aussen_CJC:Fenster_Aussen_CJC_265x350:619910:1 | 3.2OG +10.60
Fenster_Aussen_CJC:Fenster_Aussen_CJC_265x350:619911:1 | 3.2OG +10.60
Fenster_Aussen_CJC:Fenster_Aussen_CJC_265x350:619912:1 | 3.2OG +10.60
Fenster_Aussen_CJC:Fenster_Aussen_CJC_265x350:619913:1 | 3.2OG +10.60
Fenster_Aussen_CJC:Fenster_Aussen_CJC_265x350:619914:1 | 3.2OG +10.60
Fenster_Aussen_CJC:Fenster_Aussen_CJC_265x350:619915:1 | 3.2OG +10.60
Fenster_Aussen_CJC:Fenster_Aussen_CJC_265x350:620299:1 | 3.2OG +10.60
Fenster_Aussen_CJC:Fenster_Aussen_CJC_265x350:620300:1 | 3.2OG +10.60
Fenster_Aussen_CJC:Fenster_Aussen_CJC_265x350:623873:1 | 3.2OG +10.60
Fenster_Aussen_CJC:Fenster_Aussen_CJC_265x350:623874:1 | 3.2OG +10.60
M_Door-Passage-Double-Flush:160x210:620036:1 | 3.2OG +10.60
Doors_IntSgl:100x210:619993:1 | 3.2OG +10.60
Doors_IntSgl:100x210:619994:1 | 3.2OG +10.60
Doors_IntSgl:100x210:619995:1 | 3.2OG +10.60
Doors_IntSgl:100x210:620217:1 | 3.2OG +10.60
Fenster_Corridor200x100x350_CJC:Fenster_Corridor200x100x350_CJC:626055:1 | 3.2OG +10.60
Fenster_Corridor200x100x350_CJC:Fenster_Corridor200x100x350_CJC:626056:1 | 3.2OG +10.60
Fenster_Corridor200x100x350_CJC:Fenster_Corridor200x100x350_CJC:626057:1 | 3.2OG +10.60
Fenster_Corridor200x100x350_CJC:Fenster_Corridor200x100x350_CJC:626058:1 | 3.2OG +10.60
Fenster_Aussen_CJC:Fenster_Aussen_CJC_265x350:619916:1 | 3.2OG +10.60
Fenster_Aussen_CJC:Fenster_Aussen_CJC_265x350:619917:1 | 3.2OG +10.60
Fenster_Aussen_CJC:Fenster_Aussen_CJC_265x350:619918:1 | 3.2OG +10.60
Fenster_Aussen_CJC:Fenster_Aussen_CJC_265x350:619919:1 | 3.2OG +10.60
Fenster_Aussen_CJC:Fenster_Aussen_CJC_265x350:619920:1 | 3.2OG +10.60
Fenster_Aussen_CJC:Fenster_Aussen_CJC_265x350:619921:1 | 3.2OG +10.60
Fenster_Aussen_CJC:Fenster_Aussen_CJC_265x350:619922:1 | 3.2OG +10.60
Fenster_Aussen_CJC:Fenster_Aussen_CJC_265x350:619923:1 | 3.2OG +10.60
Fenster_Aussen_CJC:Fenster_Aussen_CJC_265x350:619924:1 | 3.2OG +10.60
Fenster_Aussen_CJC:Fenster_Aussen_CJC_265x350:619925:1 | 3.2OG +10.60
Fenster_Aussen_CJC:Fenster_Aussen_CJC_265x350:619926:1 | 3.2OG +10.60
Fenster_Aussen_CJC:Fenster_Aussen_CJC_265x350:619927:1 | 3.2OG +10.60
Fenster_Aussen_CJC:Fenster_Aussen_CJC_265x350:619928:1 | 3.2OG +10.60
Fenster_Aussen_CJC:Fenster_Aussen_CJC_265x350:619929:1 | 3.2OG +10.60
Fenster_Aussen_CJC:Fenster_Aussen_CJC_265x350:619930:1 | 3.2OG +10.60
M_Window-Louvers:140x250:620249:1 | 3.2OG +10.60
Doors_IntSgl:100x210:619950:1 | 3.2OG +10.60
Doors_IntSgl:100x210:619996:1 | 3.2OG +10.60
Doors_IntSgl:100x210:619997:1 | 3.2OG +10.60
Doors_IntSgl:100x210:619998:1 | 3.2OG +10.60
Doors_IntSgl:100x210:619999:1 | 3.2OG +10.60
M_Door-Passage-Double-Flush:150x210:620038:1 | 3.2OG +10.60
M_Door-Passage-Double-Flush:160x210:620040:1 | 3.2OG +10.60
Fenster_Aussen_NORD1_CJC:Fenster_Aussen_NORD1_CJC:620056:1 | 3.2OG +10.60
Fenster_Aussen_NORD2_CJC:Fenster_Aussen_NORD2_CJC:620057:1 | 3.2OG +10.60
Fenster_Aussen_CJC:Fenster_Aussen_CJC_265x350:620301:1 | 3.2OG +10.60
M_Window-Louvers:90x250:620294:1 | 3.2OG +10.60
Doors_IntSgl:100x210:620285:1 | 3.2OG +10.60
M_Instance-Window-Fixed:0610 x 1220mm:620289:1 | 3.2OG +10.60
Doors_IntSgl:100x200:620288:1 | 3.2OG +10.60
M_Instance-Window-Fixed:0610 x 1220mm:620290:1 | 3.2OG +10.60
Doors_IntSgl:100x200:620287:1 | 3.2OG +10.60
M_Instance-Window-Fixed:0610 x 1220mm:620291:1 | 3.2OG +10.60
Doors_IntSgl:100x210:620281:1 | 3.2OG +10.60
Doors_IntSgl:100x210:620283:1 | 3.2OG +10.60
Doors_IntSgl:100x210:620219:1 | 3.2OG +10.60
Doors_IntSgl:100x210:620261:1 | 3.2OG +10.60
Doors_IntSgl:100x200:620278:1 | 3.2OG +10.60
M_Instance-Window-Fixed:0610 x 1220mm:620279:1 | 3.2OG +10.60
M_Door-Passage-Double-Flush:160x210:620258:1 | 3.2OG +10.60
Doors_IntSgl:100x210:620257:1 | 3.2OG +10.60
Doors_IntSgl:100x200:620286:1 | 3.2OG +10.60
M_Door-Passage-Double-Flush:150x210:620666:1 | 3.2OG +10.60
Doors_IntSgl:100x200:620660:1 | 2.1OG +5.30
Doors_IntSgl:100x200:620661:1 | 3.2OG +10.60
M_Instance-Window-Fixed:0610 x 1220mm:620665:1 | 3.2OG +10.60
M_Door-Passage-Double-Flush:150x210:620668:1 | 3.2OG +10.60
Fenster_Aussen_CJC:Fenster_Aussen_CJC_265x350:620874:1 | 4.3OG +15.90
Fenster_Aussen_CJC:Fenster_Aussen_CJC_265x350:621077:1 | 4.3OG +15.90
Fenster_Tuer_Fass_CJC:Fenster_Tuer_Fass_CJC:623735:1 | 4.3OG +15.90
Fenster_Aussen_CJC:Fenster_Aussen_CJC_265x350:620823:1 | 4.3OG +15.90
Fenster_Aussen_CJC:Fenster_Aussen_CJC_265x350:620822:1 | 4.3OG +15.90
Fenster_Aussen_CJC:Fenster_Aussen_CJC_265x350:620809:1 | 4.3OG +15.90
Fenster_Aussen_CJC:Fenster_Aussen_CJC_265x350:620810:1 | 4.3OG +15.90
Fenster_Aussen_CJC:Fenster_Aussen_CJC_265x350:620811:1 | 4.3OG +15.90
Fenster_Aussen_CJC:Fenster_Aussen_CJC_265x350:620812:1 | 4.3OG +15.90
Fenster_Aussen_CJC:Fenster_Aussen_CJC_265x350:620813:1 | 4.3OG +15.90
Fenster_Aussen_CJC:Fenster_Aussen_CJC_265x350:620814:1 | 4.3OG +15.90
Fenster_Aussen_CJC:Fenster_Aussen_CJC_265x350:620815:1 | 4.3OG +15.90
Fenster_Aussen_CJC:Fenster_Aussen_CJC_265x350:620816:1 | 4.3OG +15.90
Fenster_Aussen_CJC:Fenster_Aussen_CJC_265x350:620817:1 | 4.3OG +15.90
Fenster_Aussen_CJC:Fenster_Aussen_CJC_265x350:620818:1 | 4.3OG +15.90
Fenster_Aussen_CJC:Fenster_Aussen_CJC_265x350:620819:1 | 4.3OG +15.90
Fenster_Aussen_CJC:Fenster_Aussen_CJC_265x350:620820:1 | 4.3OG +15.90
Fenster_Aussen_CJC:Fenster_Aussen_CJC_265x350:620821:1 | 4.3OG +15.90
Fenster_Aussen_CJC:Fenster_Aussen_CJC_265x350:620824:1 | 4.3OG +15.90
Fenster_Aussen_CJC:Fenster_Aussen_CJC_265x350:621089:1 | 4.3OG +15.90
Fenster_Aussen_CJC:Fenster_Aussen_CJC_265x350:620854:1 | 4.3OG +15.90
Fenster_Aussen_CJC:Fenster_Aussen_CJC_265x350:620855:1 | 4.3OG +15.90
Fenster_Aussen_CJC:Fenster_Aussen_CJC_265x350:620856:1 | 4.3OG +15.90
Fenster_Aussen_CJC:Fenster_Aussen_CJC_265x350:620857:1 | 4.3OG +15.90
Fenster_Aussen_CJC:Fenster_Aussen_CJC_265x350:620858:1 | 4.3OG +15.90
Fenster_Aussen_CJC:Fenster_Aussen_CJC_265x350:620859:1 | 4.3OG +15.90
Fenster_Aussen_CJC:Fenster_Aussen_CJC_265x350:620860:1 | 4.3OG +15.90
Fenster_Aussen_CJC:Fenster_Aussen_CJC_265x350:620861:1 | 4.3OG +15.90
Fenster_Aussen_CJC:Fenster_Aussen_CJC_265x350:620862:1 | 4.3OG +15.90
Fenster_Aussen_CJC:Fenster_Aussen_CJC_265x350:620863:1 | 4.3OG +15.90
Fenster_Aussen_CJC:Fenster_Aussen_CJC_265x350:620864:1 | 4.3OG +15.90
Fenster_Aussen_CJC:Fenster_Aussen_CJC_265x350:620865:1 | 4.3OG +15.90
Fenster_Aussen_CJC:Fenster_Aussen_CJC_265x350:620866:1 | 4.3OG +15.90
Fenster_Aussen_CJC:Fenster_Aussen_CJC_265x350:620867:1 | 4.3OG +15.90
Fenster_Aussen_CJC:Fenster_Aussen_CJC_265x350:620868:1 | 4.3OG +15.90
Fenster_Aussen_CJC:Fenster_Aussen_CJC_265x350:620869:1 | 4.3OG +15.90
M_Window-Louvers:140x310:621152:1 | 4.3OG +15.90
Fenster_Aussen_CJC:Fenster_Aussen_CJC_265x350:621149:1 | 4.3OG +15.90
Fenster_Aussen_CJC:Fenster_Aussen_CJC_265x350:621151:1 | 4.3OG +15.90
Doors_IntSgl:100x210:621190:1 | 4.3OG +15.90
M_Door-Passage-Double-Flush:160x210:620950:1 | 4.3OG +15.90
Doors_IntSgl:100x210:621569:1 | 4.3OG +15.90
Doors_IntSgl:100x210:620913:1 | 4.3OG +15.90
Doors_IntSgl:100x210:621165:1 | 4.3OG +15.90
Doors_IntSgl:100x210:621166:1 | 4.3OG +15.90
Fenster_Aussen_NORD2_CJC:Fenster_Aussen_NORD2_CJC:620969:1 | 4.3OG +15.90
Fenster_Aussen_NORD1_CJC:Fenster_Aussen_NORD1_CJC:620968:1 | 4.3OG +15.90
Fenster_Aussen_CJC:Fenster_Aussen_CJC_265x350:620825:1 | 4.3OG +15.90
Fenster_Aussen_CJC:Fenster_Aussen_CJC_265x350:620826:1 | 4.3OG +15.90
Fenster_Aussen_CJC:Fenster_Aussen_CJC_265x350:620827:1 | 4.3OG +15.90
Fenster_Aussen_CJC:Fenster_Aussen_CJC_265x350:620828:1 | 4.3OG +15.90
Fenster_Aussen_CJC:Fenster_Aussen_CJC_265x350:620829:1 | 4.3OG +15.90
Fenster_Aussen_CJC:Fenster_Aussen_CJC_265x350:620830:1 | 4.3OG +15.90
Fenster_Aussen_CJC:Fenster_Aussen_CJC_265x350:620831:1 | 4.3OG +15.90
Fenster_Aussen_CJC:Fenster_Aussen_CJC_265x350:620832:1 | 4.3OG +15.90
Fenster_Aussen_CJC:Fenster_Aussen_CJC_265x350:620833:1 | 4.3OG +15.90
Fenster_Aussen_CJC:Fenster_Aussen_CJC_265x350:620834:1 | 4.3OG +15.90
Fenster_Aussen_CJC:Fenster_Aussen_CJC_265x350:620835:1 | 4.3OG +15.90
Fenster_Aussen_CJC:Fenster_Aussen_CJC_265x350:620836:1 | 4.3OG +15.90
Fenster_Aussen_CJC:Fenster_Aussen_CJC_265x350:620837:1 | 4.3OG +15.90
Fenster_Aussen_CJC:Fenster_Aussen_CJC_265x350:620838:1 | 4.3OG +15.90
Fenster_Aussen_CJC:Fenster_Aussen_CJC_265x350:621205:1 | 4.3OG +15.90
Fenster_Aussen_CJC:Fenster_Aussen_CJC_265x350:621206:1 | 4.3OG +15.90
Fenster_Aussen_CJC:Fenster_Aussen_CJC_265x350:623871:1 | 4.3OG +15.90
Fenster_Aussen_CJC:Fenster_Aussen_CJC_265x350:623872:1 | 4.3OG +15.90
Doors_IntSgl:100x210:620906:1 | 4.3OG +15.90
Doors_IntSgl:100x210:620907:1 | 4.3OG +15.90
Doors_IntSgl:100x210:620908:1 | 4.3OG +15.90
Doors_IntSgl:100x210:621125:1 | 4.3OG +15.90
Fenster_Corridor200x100x350_CJC:Fenster_Corridor200x100x350_CJC:625610:1 | 4.3OG +15.90
Fenster_Corridor200x100x350_CJC:Fenster_Corridor200x100x350_CJC:625611:1 | 4.3OG +15.90
Fenster_Corridor200x100x350_CJC:Fenster_Corridor200x100x350_CJC:625612:1 | 4.3OG +15.90
Fenster_Corridor200x100x350_CJC:Fenster_Corridor200x100x350_CJC:625613:1 | 4.3OG +15.90
Fenster_Aussen_CJC:Fenster_Aussen_CJC_265x350:620839:1 | 4.3OG +15.90
Fenster_Aussen_CJC:Fenster_Aussen_CJC_265x350:620840:1 | 4.3OG +15.90
Fenster_Aussen_CJC:Fenster_Aussen_CJC_265x350:620841:1 | 4.3OG +15.90
Fenster_Aussen_CJC:Fenster_Aussen_CJC_265x350:620842:1 | 4.3OG +15.90
Fenster_Aussen_CJC:Fenster_Aussen_CJC_265x350:620843:1 | 4.3OG +15.90
Fenster_Aussen_CJC:Fenster_Aussen_CJC_265x350:620844:1 | 4.3OG +15.90
Fenster_Aussen_CJC:Fenster_Aussen_CJC_265x350:620845:1 | 4.3OG +15.90
Fenster_Aussen_CJC:Fenster_Aussen_CJC_265x350:620846:1 | 4.3OG +15.90
Fenster_Aussen_CJC:Fenster_Aussen_CJC_265x350:620847:1 | 4.3OG +15.90
Fenster_Aussen_CJC:Fenster_Aussen_CJC_265x350:620848:1 | 4.3OG +15.90
Fenster_Aussen_CJC:Fenster_Aussen_CJC_265x350:620849:1 | 4.3OG +15.90
Fenster_Aussen_CJC:Fenster_Aussen_CJC_265x350:620850:1 | 4.3OG +15.90
Fenster_Aussen_CJC:Fenster_Aussen_CJC_265x350:620851:1 | 4.3OG +15.90
Fenster_Aussen_CJC:Fenster_Aussen_CJC_265x350:620852:1 | 4.3OG +15.90
Fenster_Aussen_CJC:Fenster_Aussen_CJC_265x350:620853:1 | 4.3OG +15.90
M_Window-Louvers:140x250:621157:1 | 4.3OG +15.90
Doors_IntSgl:100x210:620873:1 | 4.3OG +15.90
Doors_IntSgl:100x210:620909:1 | 4.3OG +15.90
Doors_IntSgl:100x210:620910:1 | 4.3OG +15.90
Doors_IntSgl:100x210:620911:1 | 4.3OG +15.90
Doors_IntSgl:100x210:620912:1 | 4.3OG +15.90
M_Door-Passage-Double-Flush:160x210:620949:1 | 4.3OG +15.90
M_Door-Passage-Double-Flush:160x210:620952:1 | 4.3OG +15.90
Fenster_Aussen_CJC:Fenster_Aussen_CJC_265x350:621207:1 | 4.3OG +15.90
M_Window-Louvers:90x250:621200:1 | 4.3OG +15.90
Doors_IntSgl:100x210:621191:1 | 4.3OG +15.90
M_Instance-Window-Fixed:0610 x 1220mm:621195:1 | 4.3OG +15.90
Doors_IntSgl:100x200:621194:1 | 4.3OG +15.90
M_Instance-Window-Fixed:0610 x 1220mm:621196:1 | 4.3OG +15.90
Doors_IntSgl:100x200:621193:1 | 4.3OG +15.90
M_Instance-Window-Fixed:0610 x 1220mm:621197:1 | 4.3OG +15.90
Doors_IntSgl:100x210:621187:1 | 4.3OG +15.90
Doors_IntSgl:100x210:621189:1 | 4.3OG +15.90
Doors_IntSgl:100x210:621127:1 | 4.3OG +15.90
Doors_IntSgl:100x210:621167:1 | 4.3OG +15.90
Doors_IntSgl:100x200:621184:1 | 4.3OG +15.90
M_Instance-Window-Fixed:0610 x 1220mm:621185:1 | 4.3OG +15.90
M_Door-Passage-Double-Flush:160x210:621164:1 | 4.3OG +15.90
Doors_IntSgl:100x210:621163:1 | 4.3OG +15.90
M_Door-Passage-Double-Flush:150x210:621188:1 | 4.3OG +15.90
Doors_IntSgl:100x200:621192:1 | 4.3OG +15.90
Doors_IntSgl:100x200:621496:1 | 4.3OG +15.90
M_Instance-Window-Fixed:0610 x 1220mm:621500:1 | 4.3OG +15.90
M_Door-Passage-Double-Flush:220x210:621567:1 | 4.3OG +15.90
M_Door-Passage-Double-Flush:220x210:621568:1 | 4.3OG +15.90
Doors_IntSgl:100x210:621562:1 | 4.3OG +15.90
Doors_IntSgl:100x210:621563:1 | 4.3OG +15.90
Doors_IntSgl:100x210:621599:1 | 4.3OG +15.90
Windows_Sgl_Horz_Bars:200x150:622075:1 | 1.EG +0.00
Windows_Sgl_Horz_Bars:200x150:622076:1 | 1.EG +0.00
Windows_Sgl_Horz_Bars:200x150:622070:1 | 1.EG +0.00
Windows_Sgl_Horz_Bars:200x150:622071:1 | 1.EG +0.00
Windows_Sgl_Horz_Bars:200x150:622072:1 | 1.EG +0.00
Windows_Sgl_Horz_Bars:200x150:622073:1 | 1.EG +0.00
Windows_Sgl_Horz_Bars:200x150:622074:1 | 1.EG +0.00
Fenster_Aussen_KH_CJC:Fenster_Aussen_KH_CJC:623631:1 | 1.EG +0.00
Fenster_Aussen_KH_CJC:Fenster_Aussen_KH_CJC:623629:1 | 1.EG +0.00
Fenster_Aussen_KH_CJC:Fenster_Aussen_KH_CJC:623630:1 | 1.EG +0.00
Windows_Sgl_Horz_Bars:200x150:622066:1 | 1.EG +0.00
Windows_Sgl_Horz_Bars:200x150:622067:1 | 1.EG +0.00
Windows_Sgl_Horz_Bars:200x150:622068:1 | 1.EG +0.00
Windows_Sgl_Horz_Bars:200x150:622069:1 | 1.EG +0.00
Windows_Sgl_Horz_Bars:200x150:622062:1 | 1.EG +0.00
Windows_Sgl_Horz_Bars:200x150:622063:1 | 1.EG +0.00
Windows_Sgl_Horz_Bars:200x150:622064:1 | 1.EG +0.00
Windows_Sgl_Horz_Bars:200x150:622065:1 | 1.EG +0.00
M_Door-Passage-Double-Flush:160x210:622129:1 | 1.EG +0.00
M_Door-Passage-Double-Flush:160x210:622130:1 | 1.EG +0.00
M_Door-Passage-Double-Flush:150x210:622132:1 | 1.EG +0.00
M_Door-Passage-Double-Flush:150x210:622133:1 | 1.EG +0.00
M_Door-Passage-Double-Flush:160x210:622134:1 | 1.EG +0.00
Doors_IntSgl:100x210:622182:1 | 1.EG +0.00
Doors_IntSgl:100x210:622181:1 | 1.EG +0.00
Doors_IntSgl:70x210:622179:1 | 1.EG +0.00
M_Door-Passage-Double-Flush:150x210:622136:1 | 1.EG +0.00
Windows_Sgl_Plain:100x100:622177:1 | 1.EG +0.00
Windows_Sgl_Plain:120x140:622178:1 | 1.EG +0.00
Doors_IntSgl:100x210:621903:1 | 7.1OG KH +2.65
Windows_Sgl_Horz_Bars:200x150:622002:1 | 7.1OG KH +2.65
Windows_Sgl_Horz_Bars:200x150:622003:1 | 7.1OG KH +2.65
Windows_Sgl_Horz_Bars:200x150:621996:1 | 7.1OG KH +2.65
Windows_Sgl_Horz_Bars:200x150:621997:1 | 7.1OG KH +2.65
Windows_Sgl_Horz_Bars:200x150:621998:1 | 7.1OG KH +2.65
Windows_Sgl_Horz_Bars:200x150:621999:1 | 7.1OG KH +2.65
Windows_Sgl_Horz_Bars:200x150:622000:1 | 7.1OG KH +2.65
Windows_Sgl_Horz_Bars:200x150:622001:1 | 7.1OG KH +2.65
Windows_Sgl_Horz_Bars:200x150:622008:1 | 7.1OG KH +2.65
Windows_Sgl_Horz_Bars:200x150:622009:1 | 7.1OG KH +2.65
Windows_Sgl_Horz_Bars:200x150:622010:1 | 7.1OG KH +2.65
Windows_Sgl_Horz_Bars:200x150:622011:1 | 7.1OG KH +2.65
Windows_Sgl_Horz_Bars:200x150:622012:1 | 7.1OG KH +2.65
Windows_Sgl_Horz_Bars:200x150:622013:1 | 7.1OG KH +2.65
Windows_Sgl_Horz_Bars:200x150:622006:1 | 7.1OG KH +2.65
Windows_Sgl_Horz_Bars:200x150:622004:1 | 7.1OG KH +2.65
Windows_Sgl_Horz_Bars:200x150:622005:1 | 7.1OG KH +2.65
Windows_Sgl_Horz_Bars:200x150:622007:1 | 7.1OG KH +2.65
Windows_Sgl_Horz_Bars:200x150:622014:1 | 7.1OG KH +2.65
Windows_Sgl_Horz_Bars:200x150:622015:1 | 7.1OG KH +2.65
Windows_Sgl_Horz_Bars:200x150:622016:1 | 7.1OG KH +2.65
Windows_Sgl_Horz_Bars:200x150:622017:1 | 7.1OG KH +2.65
Doors_IntSgl:100x210:621907:1 | 7.1OG KH +2.65
M_Door-Passage-Double-Flush:160x210:622200:1 | 7.1OG KH +2.65
Doors_IntSgl:100x210:621904:1 | 7.1OG KH +2.65
Doors_IntSgl:100x210:621905:1 | 7.1OG KH +2.65
Doors_IntSgl:100x210:621906:1 | 7.1OG KH +2.65
M_Door-Passage-Double-Flush:160x210:621995:1 | 7.1OG KH +2.65
Doors_IntSgl:90x210:622198:1 | 7.1OG KH +2.65
Doors_IntSgl:100x210:622199:1 | 7.1OG KH +2.65
Doors_IntSgl:100x210:621908:1 | 7.1OG KH +2.65
Doors_IntSgl:100x210:621909:1 | 7.1OG KH +2.65
Windows_Sgl_Horz_Bars:200x150:622018:1 | 7.1OG KH +2.65
Windows_Sgl_Horz_Bars:200x150:622019:1 | 7.1OG KH +2.65
Windows_Sgl_Horz_Bars:200x150:622020:1 | 7.1OG KH +2.65
Windows_Sgl_Horz_Bars:200x150:622021:1 | 7.1OG KH +2.65
Windows_Sgl_Horz_Bars:200x150:622022:1 | 7.1OG KH +2.65
Windows_Sgl_Horz_Bars:200x150:622023:1 | 7.1OG KH +2.65
Windows_Sgl_Horz_Bars:200x150:622024:1 | 7.1OG KH +2.65
Fenster_Aussen_CJC:Fenster_Aussen_CJC_265x350:622025:1 | 1.EG +0.00
Windows_Sgl_Horz_Bars:200x150:622077:1 | 1.EG +0.00
Windows_Sgl_Horz_Bars:200x150:622078:1 | 1.EG +0.00
M_Door-Passage-Double-Flush:160x210:622131:1 | 1.EG +0.00
M_Door-Passage-Double-Flush:150x210:622135:1 | 1.EG +0.00
Doors_IntSgl:100x210:622180:1 | 1.EG +0.00
M_Door-Passage-Double-Flush:150x210:622197:1 | 1.EG +0.00
Windows_Sgl_Horz_Bars:200x150:622293:1 | 8.2OG KH +6.45
Windows_Sgl_Horz_Bars:200x150:622294:1 | 8.2OG KH +6.45
Windows_Sgl_Horz_Bars:200x150:622295:1 | 8.2OG KH +6.45
Windows_Sgl_Horz_Bars:200x150:622274:1 | 8.2OG KH +6.45
Windows_Sgl_Horz_Bars:200x150:622285:1 | 8.2OG KH +6.45
Doors_IntSgl:90x180:622292:1 | 8.2OG KH +6.45
Windows_Sgl_Horz_Bars:200x150:622286:1 | 8.2OG KH +6.45
Windows_Sgl_Horz_Bars:200x150:622287:1 | 8.2OG KH +6.45
Windows_Sgl_Horz_Bars:200x150:622288:1 | 8.2OG KH +6.45
Windows_Sgl_Horz_Bars:200x150:622289:1 | 8.2OG KH +6.45
Windows_Sgl_Horz_Bars:200x150:622290:1 | 8.2OG KH +6.45
Windows_Sgl_Horz_Bars:200x150:622291:1 | 8.2OG KH +6.45
Windows_Sgl_Horz_Bars:200x150:622279:1 | 8.2OG KH +6.45
Windows_Sgl_Horz_Bars:200x150:622280:1 | 8.2OG KH +6.45
Windows_Sgl_Horz_Bars:200x150:622281:1 | 8.2OG KH +6.45
Windows_Sgl_Horz_Bars:200x150:622282:1 | 8.2OG KH +6.45
Windows_Sgl_Horz_Bars:200x150:622283:1 | 8.2OG KH +6.45
Windows_Sgl_Horz_Bars:200x150:622284:1 | 8.2OG KH +6.45
Windows_Sgl_Horz_Bars:200x150:622275:1 | 8.2OG KH +6.45
Windows_Sgl_Horz_Bars:200x150:622276:1 | 8.2OG KH +6.45
Windows_Sgl_Horz_Bars:200x150:622277:1 | 8.2OG KH +6.45
Windows_Sgl_Horz_Bars:200x150:622278:1 | 8.2OG KH +6.45
M_Window-Louvers:60x60:622296:1 | 8.2OG KH +6.45
Doors_IntSgl:90x210:622247:1 | 8.2OG KH +6.45
Doors_IntSgl:100x210:622245:1 | 8.2OG KH +6.45
Doors_IntSgl:100x210:622241:1 | 8.2OG KH +6.45
Doors_IntSgl:100x210:622242:1 | 8.2OG KH +6.45
Doors_IntSgl:100x210:622244:1 | 8.2OG KH +6.45
Doors_IntSgl:100x210:622246:1 | 8.2OG KH +6.45
Doors_IntSgl:100x210:622240:1 | 8.2OG KH +6.45
Doors_IntSgl:100x210:622239:1 | 8.2OG KH +6.45
Doors_IntSgl:100x210:622243:1 | 8.2OG KH +6.45
M_Door-Passage-Double-Flush:160x210:622248:1 | 8.2OG KH +6.45
Windows_Sgl_Horz_Bars:200x150:622341:1 | 9.3OG KH +10.25
Windows_Sgl_Horz_Bars:200x150:622342:1 | 9.3OG KH +10.25
Windows_Sgl_Horz_Bars:200x150:622343:1 | 9.3OG KH +10.25
Windows_Sgl_Horz_Bars:200x150:622344:1 | 9.3OG KH +10.25
Windows_Sgl_Horz_Bars:200x150:622345:1 | 9.3OG KH +10.25
Windows_Sgl_Horz_Bars:200x150:622346:1 | 9.3OG KH +10.25
Windows_Sgl_Horz_Bars:200x150:622347:1 | 9.3OG KH +10.25
Windows_Sgl_Horz_Bars:200x150:622348:1 | 9.3OG KH +10.25
Windows_Sgl_Horz_Bars:200x150:622349:1 | 9.3OG KH +10.25
Windows_Sgl_Horz_Bars:200x150:622350:1 | 9.3OG KH +10.25
Windows_Sgl_Horz_Bars:200x150:622351:1 | 9.3OG KH +10.25
Windows_Sgl_Horz_Bars:200x150:622356:1 | 9.3OG KH +10.25
Windows_Sgl_Horz_Bars:200x150:622357:1 | 9.3OG KH +10.25
Windows_Sgl_Horz_Bars:200x150:622358:1 | 9.3OG KH +10.25
Windows_Sgl_Horz_Bars:200x150:622359:1 | 9.3OG KH +10.25
Windows_Sgl_Horz_Bars:200x150:622360:1 | 9.3OG KH +10.25
Windows_Sgl_Horz_Bars:200x150:622361:1 | 9.3OG KH +10.25
Windows_Sgl_Horz_Bars:200x150:622352:1 | 9.3OG KH +10.25
Windows_Sgl_Horz_Bars:200x150:622353:1 | 9.3OG KH +10.25
Windows_Sgl_Horz_Bars:200x150:622354:1 | 9.3OG KH +10.25
Windows_Sgl_Horz_Bars:200x150:622355:1 | 9.3OG KH +10.25
Doors_IntSgl:100x210:622363:1 | 9.3OG KH +10.25
Doors_IntSgl:100x210:622364:1 | 9.3OG KH +10.25
Doors_IntSgl:100x210:622365:1 | 9.3OG KH +10.25
Doors_IntSgl:100x210:622362:1 | 9.3OG KH +10.25
M_Door-Passage-Double-Flush:160x210:622368:1 | 9.3OG KH +10.25
M_Instance-Window-Fixed:508x270 2:622386:1 | 9.3OG KH +10.25
Doors_IntSgl:90x210:622367:1 | 9.3OG KH +10.25
Doors_IntSgl:100x210:622366:1 | 9.3OG KH +10.25
Windows_Dbl_Plain:200x140:623315:1 | 0.UG -3.60
Windows_Dbl_Plain:200x140:623302:1 | 0.UG -3.60
Windows_Dbl_Plain:200x140:623303:1 | 0.UG -3.60
Windows_Dbl_Plain:200x140:623304:1 | 0.UG -3.60
Windows_Dbl_Plain:200x140:623305:1 | 0.UG -3.60
Windows_Dbl_Plain:200x140:623306:1 | 0.UG -3.60
Windows_Dbl_Plain:200x140:623307:1 | 0.UG -3.60
Windows_Dbl_Plain:200x140:623308:1 | 0.UG -3.60
Windows_Dbl_Plain:200x140:623309:1 | 0.UG -3.60
Windows_Dbl_Plain:200x140:623310:1 | 0.UG -3.60
Windows_Dbl_Plain:200x140:623311:1 | 0.UG -3.60
Windows_Dbl_Plain:200x140:623312:1 | 0.UG -3.60
Windows_Dbl_Plain:200x140:623313:1 | 0.UG -3.60
Windows_Dbl_Plain:200x140:623314:1 | 0.UG -3.60
Windows_Sgl_Plain:90x140:623316:1 | 0.UG -3.60
Windows_Sgl_Plain:90x140:623317:1 | 0.UG -3.60
Windows_Sgl_Plain:90x140:623318:1 | 0.UG -3.60
Windows_Sgl_Plain:90x140:623319:1 | 0.UG -3.60
Windows_Sgl_Plain:90x45:623740:1 | 0.UG -3.60
Windows_Sgl_Plain:90x45:623736:1 | 0.UG -3.60
Windows_Sgl_Plain:90x45:623737:1 | 0.UG -3.60
Windows_Sgl_Plain:90x45:623738:1 | 0.UG -3.60
Windows_Sgl_Plain:90x45:623739:1 | 0.UG -3.60
Windows_Sgl_Plain:90x45:623741:1 | 0.UG -3.60
Doors_IntSgl:100x210:623109:1 | 0.UG -3.60
Doors_IntSgl:100x210:623105:1 | 0.UG -3.60
Doors_IntSgl:100x210:623106:1 | 0.UG -3.60
M_Door-Passage-Double-Flush:130x210:623108:1 | 0.UG -3.60
Doors_IntSgl:100x210:623107:1 | 0.UG -3.60
M_Door-Passage-Double-Flush:130x210:623110:1 | 0.UG -3.60
Doors_IntSgl:100x210:623104:1 | 0.UG -3.60
Doors_IntSgl:100x210:623095:1 | 0.UG -3.60
Doors_IntSgl:100x210:623096:1 | 0.UG -3.60
Doors_IntSgl:100x210:623097:1 | 0.UG -3.60
Doors_IntSgl:100x210:623111:1 | 0.UG -3.60
Doors_IntSgl:100x210:623112:1 | 0.UG -3.60
Doors_IntSgl:100x210:623100:1 | 0.UG -3.60
Doors_IntSgl:100x210:623102:1 | 0.UG -3.60
Doors_IntSgl:100x210:623103:1 | 0.UG -3.60
M_Instance-Window-Fixed:508x270:623252:1 | 0.UG -3.60
Doors_IntSgl:70x210:623101:1 | 0.UG -3.60
Doors_IntSgl:100x210:623093:1 | 0.UG -3.60
Doors_IntSgl:100x210:623094:1 | 0.UG -3.60
Doors_IntSgl:75x210:623089:1 | 0.UG -3.60
Doors_IntSgl:75x210:623090:1 | 0.UG -3.60
Doors_IntSgl:100x210:623091:1 | 0.UG -3.60
Doors_IntSgl:75x210:623092:1 | 0.UG -3.60
Doors_IntSgl:100x210:623115:1 | 0.UG -3.60
Doors_IntSgl:80x210:623163:1 | 0.UG -3.60
M_Door-Passage-Double-Flush:160x210:623168:1 | 0.UG -3.60
Doors_IntSgl:100x210:623119:1 | 0.UG -3.60
Doors_IntSgl:100x210:623120:1 | 0.UG -3.60
Doors_IntSgl:100x210:623123:1 | 0.UG -3.60
M_Instance-Window-Fixed:508x270:623245:1 | 0.UG -3.60
M_Instance-Window-Fixed:508x270:623248:1 | 0.UG -3.60
Doors_IntSgl:100x210:623177:1 | 0.UG -3.60
Doors_IntSgl:100x210:623178:1 | 0.UG -3.60
Doors_IntSgl:100x210:623179:1 | 0.UG -3.60
Doors_IntSgl:100x210:623180:1 | 0.UG -3.60
Doors_IntSgl:90x210:623206:1 | 0.UG -3.60
M_Door-Passage-Double-Flush:160x210:623176:1 | 0.UG -3.60
Doors_IntSgl:80x210:623171:1 | 0.UG -3.60
M_Door-Passage-Double-Flush:160x210:623169:1 | 0.UG -3.60
Doors_IntSgl:80x210:623172:1 | 0.UG -3.60
Doors_IntSgl:100x210:623166:1 | 0.UG -3.60
Doors_IntSgl:80x210:623167:1 | 0.UG -3.60
Doors_IntSgl:100x210:623116:1 | 0.UG -3.60
Doors_IntSgl:100x210:623118:1 | 0.UG -3.60
M_Door-Passage-Double-Flush:160x210:623769:1 | 0.UG -3.60
M_Instance-Window-Fixed:508x270:623250:1 | 0.UG -3.60
M_Instance-Window-Fixed:508x270:623249:1 | 0.UG -3.60
M_Door-Passage-Double-Flush:180x210:623162:1 | 0.UG -3.60
M_Door-Passage-Double-Flush:160x210:623164:1 | 0.UG -3.60
Doors_IntSgl:100x210:623165:1 | 0.UG -3.60
Doors_IntSgl:100x210:623098:1 | 0.UG -3.60
Doors_IntSgl:100x210:623099:1 | 0.UG -3.60
M_Door-Passage-Double-Flush:160x210:623173:1 | 0.UG -3.60
M_Door-Passage-Double-Flush:160x210:623174:1 | 0.UG -3.60
M_Door-Passage-Double-Flush:160x210:623175:1 | 0.UG -3.60
Windows_Dbl_Plain:200x140:623286:1 | 0.UG -3.60
Windows_Dbl_Plain:200x140:623287:1 | 0.UG -3.60
Windows_Dbl_Plain:200x140:623288:1 | 0.UG -3.60
Windows_Dbl_Plain:200x140:623289:1 | 0.UG -3.60
Windows_Dbl_Plain:200x140:623290:1 | 0.UG -3.60
Windows_Dbl_Plain:200x140:623291:1 | 0.UG -3.60
Windows_Dbl_Plain:200x140:623292:1 | 0.UG -3.60
Windows_Dbl_Plain:200x140:623293:1 | 0.UG -3.60
Windows_Dbl_Plain:200x140:623294:1 | 0.UG -3.60
Windows_Dbl_Plain:200x140:623295:1 | 0.UG -3.60
Windows_Dbl_Plain:200x140:623296:1 | 0.UG -3.60
Windows_Dbl_Plain:200x140:623297:1 | 0.UG -3.60
Windows_Dbl_Plain:200x140:623298:1 | 0.UG -3.60
Windows_Dbl_Plain:200x140:623299:1 | 0.UG -3.60
Doors_IntSgl:100x210:623113:1 | 0.UG -3.60
Doors_IntSgl:100x210:623114:1 | 0.UG -3.60
Doors_IntSgl:90x210:623182:1 | 0.UG -3.60
Doors_IntSgl:100x210:623117:1 | 0.UG -3.60
Doors_IntSgl:90x210:623122:1 | 0.UG -3.60
M_Instance-Window-Fixed:508x270:623251:1 | 0.UG -3.60
Doors_IntSgl:100x210:623124:1 | 0.UG -3.60
Doors_IntSgl:100x210:623125:1 | 0.UG -3.60
Doors_IntSgl:100x210:623126:1 | 0.UG -3.60
Windows_Sgl_Plain:90x140:623284:1 | 0.UG -3.60
Windows_Dbl_Plain:200x140:623255:1 | 0.UG -3.60
Windows_Dbl_Plain:200x140:623256:1 | 0.UG -3.60
Windows_Dbl_Plain:200x140:623257:1 | 0.UG -3.60
Windows_Dbl_Plain:200x140:623258:1 | 0.UG -3.60
Windows_Dbl_Plain:200x140:623259:1 | 0.UG -3.60
Windows_Dbl_Plain:200x140:623260:1 | 0.UG -3.60
Windows_Dbl_Plain:200x140:623261:1 | 0.UG -3.60
Windows_Dbl_Plain:200x140:623262:1 | 0.UG -3.60
Windows_Dbl_Plain:200x140:623263:1 | 0.UG -3.60
Windows_Dbl_Plain:200x140:623264:1 | 0.UG -3.60
Windows_Dbl_Plain:200x140:623265:1 | 0.UG -3.60
Windows_Dbl_Plain:200x140:623266:1 | 0.UG -3.60
Windows_Dbl_Plain:200x140:623267:1 | 0.UG -3.60
Windows_Sgl_Plain:90x140:623285:1 | 0.UG -3.60
Doors_IntSgl:100x210:623170:1 | 0.UG -3.60
Doors_IntSgl:100x210:623181:1 | 0.UG -3.60
Doors_IntSgl:90x210:623183:1 | 0.UG -3.60
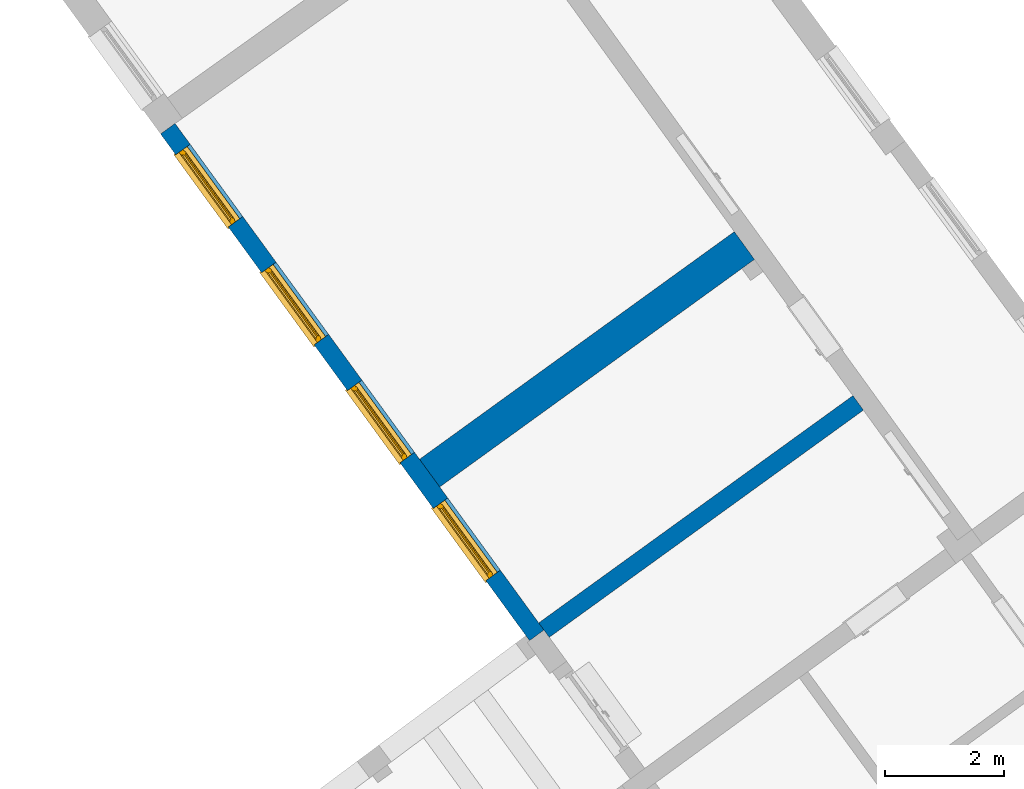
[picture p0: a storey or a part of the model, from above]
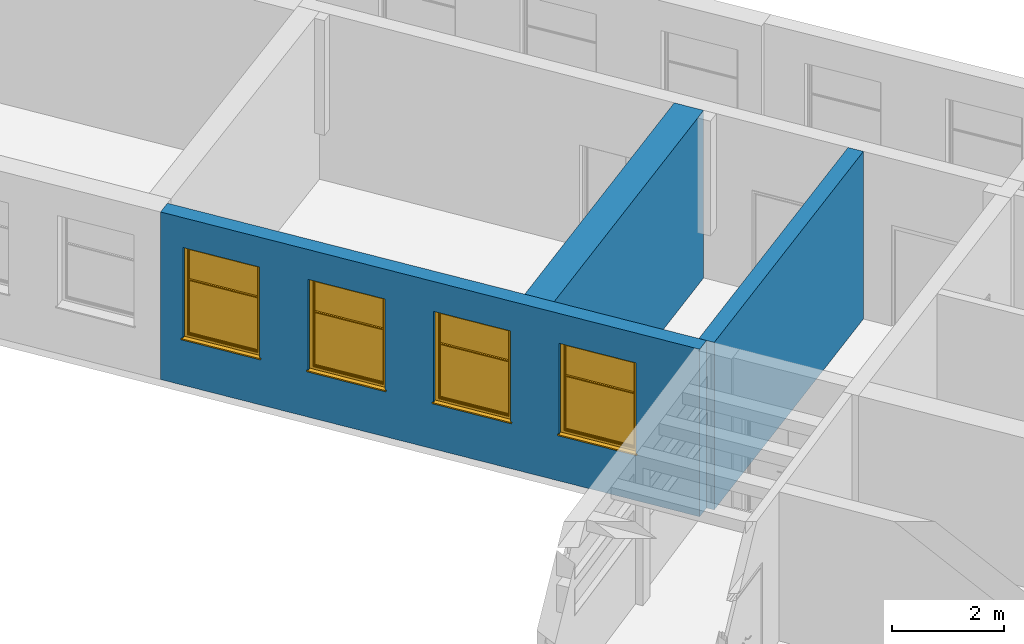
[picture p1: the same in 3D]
Properties of the parts of a building model (IFC2X3), part 6 of 13

# IfcOpeningElement: Opening (908)
Name | In
Doors_IntSgl:100x210:623204:1 | 0.UG -3.60
Doors_IntSgl:80x210:623205:1 | 0.UG -3.60
Doors_IntSgl:100x210:623207:1 | 0.UG -3.60
M_Instance-Window-Fixed:508x270:623246:1 | 0.UG -3.60
M_Instance-Window-Fixed:508x270:623247:1 | 0.UG -3.60
Windows_Dbl_Plain:200x140:623253:1 | 0.UG -3.60
Windows_Dbl_Plain:200x140:623254:1 | 0.UG -3.60
Windows_Dbl_Plain:200x140:623268:1 | 0.UG -3.60
Windows_Dbl_Plain:200x140:623269:1 | 0.UG -3.60
Windows_Dbl_Plain:200x140:623270:1 | 0.UG -3.60
Windows_Dbl_Plain:200x140:623271:1 | 0.UG -3.60
Windows_Dbl_Plain:200x140:623272:1 | 0.UG -3.60
Windows_Dbl_Plain:200x140:623273:1 | 0.UG -3.60
Windows_Dbl_Plain:200x140:623274:1 | 0.UG -3.60
Windows_Dbl_Plain:200x140:623275:1 | 0.UG -3.60
Windows_Dbl_Plain:200x140:623276:1 | 0.UG -3.60
Windows_Dbl_Plain:200x140:623277:1 | 0.UG -3.60
Windows_Dbl_Plain:200x140:623278:1 | 0.UG -3.60
Windows_Dbl_Plain:200x140:623279:1 | 0.UG -3.60
Windows_Dbl_Plain:200x140:623280:1 | 0.UG -3.60
Windows_Dbl_Plain:200x140:623281:1 | 0.UG -3.60
Windows_Dbl_Plain:200x140:623282:1 | 0.UG -3.60
Windows_Dbl_Plain:200x140:623283:1 | 0.UG -3.60
Windows_Dbl_Plain:200x140:623300:1 | 0.UG -3.60
Windows_Dbl_Plain:200x140:623301:1 | 0.UG -3.60
M_Door-Exterior-Double:280x250:623320:1 | 1.EG +0.00
M_Door-Exterior-Double:300x290:623321:1 | 1.EG +0.00
WINDOW_Glass_Block:WINDOW_Glass_Block_14x3:623322:1 | 1.EG +0.00
WINDOW_Glass_Block:WINDOW_Glass_Block_14x3:623323:1 | 1.EG +0.00
WINDOW_Glass_Block:WINDOW_Glass_Block_10x3:623324:1 | 1.EG +0.00
WINDOW_Glass_Block:WINDOW_Glass_Block_14x3:623325:1 | 1.EG +0.00
WINDOW_Glass_Block:WINDOW_Glass_Block_14x3:623326:1 | 1.EG +0.00
WINDOW_Glass_Block:WINDOW_Glass_Block_10x3:623327:1 | 1.EG +0.00
WINDOW_Glass_Block:WINDOW_Glass_Block_14x3:623328:1 | 1.EG +0.00
WINDOW_Glass_Block:WINDOW_Glass_Block_14x3:623329:1 | 1.EG +0.00
WINDOW_Glass_Block:WINDOW_Glass_Block_15x3:623330:1 | 1.EG +0.00
WINDOW_Glass_Block:WINDOW_Glass_Block_14x3:623331:1 | 1.EG +0.00
WINDOW_Glass_Block:WINDOW_Glass_Block_14x3:623332:1 | 1.EG +0.00
WINDOW_Glass_Block:WINDOW_Glass_Block_15x3:623333:1 | 1.EG +0.00
Doors_IntSgl:100x190:623334:1 | 1.EG +0.00
M_Window-Louvers:90x250:623591:1 | 1.EG +0.00
Windows_Sgl_Plain:150x80:623895:1 | 0.UG -3.60
Windows_Sgl_Plain:150x80:623896:1 | 0.UG -3.60
Windows_Sgl_Plain:150x80:623894:1 | 0.UG -3.60
M_Instance-Window-Fixed:508x270 2:623893:1 | 0.UG -3.60
M_Door-Passage-Double-Flush:210x210:625586:1 | 4.3OG +15.90
Doors_IntSgl:70x210:625641:1 | 4.3OG +15.90
Doors_IntSgl:70x210:625642:1 | 4.3OG +15.90
Doors_IntSgl:90x210:627526:1 | 2.1OG +5.30
Doors_IntSgl:90x210:627527:1 | 2.1OG +5.30
Doors_IntSgl:70x210:627821:1 | 3.2OG +10.60
Doors_IntSgl:70x210:627822:1 | 3.2OG +10.60
Doors_IntSgl:70x210:627842:1 | 2.1OG +5.30
Doors_IntSgl:70x210:627843:1 | 2.1OG +5.30
Doors_IntSgl:75x210:628113:1 | 1.EG +0.00
Fenster_Corridor450x80x335_CJC:Fenster_Corridor450x80x335_CJC:628137:1 | 1.EG +0.00
Fenster_Corridor450x80x335_CJC:Fenster_Corridor450x80x335_CJC:628138:1 | 1.EG +0.00
Fenster_Corridor450x80x335_CJC:Fenster_Corridor450x80x335_CJC:628139:1 | 1.EG +0.00
Fenster_Corridor265x80x260_CJC:Fenster_Corridor265x80x260_CJC:628140:1 | 1.EG +0.00
Fenster_Corridor265x80x260_CJC:Fenster_Corridor265x80x260_CJC:628141:1 | 1.EG +0.00
Fenster_Corridor265x80x260_CJC:Fenster_Corridor265x80x260_CJC:628142:1 | 1.EG +0.00
Fenster_Corridor265x80x260_CJC:Fenster_Corridor265x80x260_CJC:628143:1 | 1.EG +0.00
Fenster_Corridor265x80x260_CJC:Fenster_Corridor265x80x260_CJC:628144:1 | 1.EG +0.00
Fenster_Corridor265x80x260_CJC:Fenster_Corridor265x80x260_CJC:628145:1 | 1.EG +0.00
Fenster_Corridor265x80x260_CJC:Fenster_Corridor265x80x260_CJC:628146:1 | 1.EG +0.00
Fenster_Corridor265x80x260_CJC:Fenster_Corridor265x80x260_CJC:628147:1 | 1.EG +0.00
Fenster_Aussen_KH_CJC:Fenster_Aussen_KH_CJC:629210:1 | 7.1OG KH +2.65
Fenster_Aussen_KH_CJC:Fenster_Aussen_KH_CJC:629211:1 | 7.1OG KH +2.65
Fenster_Aussen_KH_CJC:Fenster_Aussen_KH_CJC:629212:1 | 7.1OG KH +2.65
Fenster_Aussen_KH_CJC:Fenster_Aussen_KH_CJC:629213:1 | 8.2OG KH +6.45
Fenster_Aussen_KH_CJC:Fenster_Aussen_KH_CJC:629214:1 | 8.2OG KH +6.45
Fenster_Aussen_KH_CJC:Fenster_Aussen_KH_CJC:629215:1 | 8.2OG KH +6.45
Fenster_Aussen_KH_CJC:Fenster_Aussen_KH_CJC:629216:1 | 9.3OG KH +10.25
Fenster_Aussen_KH_CJC:Fenster_Aussen_KH_CJC:629217:1 | 9.3OG KH +10.25

# IfcPlate: System Panel:Glazed_CJC (744)
Type - PredefinedType: CURTAIN_PANEL; Material: Glass
Type - Pset_PlateCommon - IsExternal: no
Type - Pset_ProductRequirements - Category: Curtain Panels
Pset_PlateCommon - Reference: Glazed_CJC
Pset_QuantityTakeOff - Reference: Glazed_CJC
Group: Model Group:Building:629362
Name (System Panel:Glazed_CJC:...) | In
628318 | 1.EG +0.00
628409 | 1.EG +0.00
628405 | 1.EG +0.00
628319 | 1.EG +0.00
628320 | 1.EG +0.00
628321 | 1.EG +0.00
628322 | 1.EG +0.00
628324 | 1.EG +0.00
628410 | 1.EG +0.00
628406 | 1.EG +0.00
628325 | 1.EG +0.00
628326 | 1.EG +0.00
628327 | 1.EG +0.00
628328 | 1.EG +0.00
628169 | 1.EG +0.00
628285 | 1.EG +0.00
628279 | 1.EG +0.00
628170 | 1.EG +0.00
628171 | 1.EG +0.00
628172 | 1.EG +0.00
628173 | 1.EG +0.00
628198 | 1.EG +0.00
628199 | 1.EG +0.00
628200 | 1.EG +0.00
628266 | 1.EG +0.00
628267 | 1.EG +0.00
628268 | 1.EG +0.00
628446 | 1.EG +0.00
628447 | 1.EG +0.00
628448 | 1.EG +0.00
628449 | 1.EG +0.00
628450 | 1.EG +0.00
628545 | 1.EG +0.00
628550 | 1.EG +0.00
628452 | 1.EG +0.00
628453 | 1.EG +0.00
628454 | 1.EG +0.00
628455 | 1.EG +0.00
628456 | 1.EG +0.00
628546 | 1.EG +0.00
628551 | 1.EG +0.00
628470 | 1.EG +0.00
628471 | 1.EG +0.00
628472 | 1.EG +0.00
628474 | 1.EG +0.00
628475 | 1.EG +0.00
628476 | 1.EG +0.00
618356 | 1.EG +0.00
618372 | 1.EG +0.00
618358 | 1.EG +0.00
618373 | 1.EG +0.00
618360 | 1.EG +0.00
618374 | 1.EG +0.00
618383 | 1.EG +0.00
618384 | 1.EG +0.00
624171 | 1.EG +0.00
624172 | 1.EG +0.00
624174 | 1.EG +0.00
624175 | 1.EG +0.00
624177 | 1.EG +0.00
624178 | 1.EG +0.00
624180 | 1.EG +0.00
624181 | 1.EG +0.00
624183 | 1.EG +0.00
624184 | 1.EG +0.00
624186 | 1.EG +0.00
624187 | 1.EG +0.00
624189 | 1.EG +0.00
624190 | 1.EG +0.00
624192 | 1.EG +0.00
624193 | 1.EG +0.00
624195 | 1.EG +0.00
624196 | 1.EG +0.00
618391 | 1.EG +0.00
618407 | 1.EG +0.00
618393 | 1.EG +0.00
618408 | 1.EG +0.00
618395 | 1.EG +0.00
618409 | 1.EG +0.00
618418 | 1.EG +0.00
618419 | 1.EG +0.00
624198 | 1.EG +0.00
624199 | 1.EG +0.00
624201 | 1.EG +0.00
624202 | 1.EG +0.00
624204 | 1.EG +0.00
624205 | 1.EG +0.00
624207 | 1.EG +0.00
624208 | 1.EG +0.00
624210 | 1.EG +0.00
624211 | 1.EG +0.00
624213 | 1.EG +0.00
624214 | 1.EG +0.00
624216 | 1.EG +0.00
624217 | 1.EG +0.00
624219 | 1.EG +0.00
624220 | 1.EG +0.00
624222 | 1.EG +0.00
624223 | 1.EG +0.00
618426 | 1.EG +0.00
618442 | 1.EG +0.00
618428 | 1.EG +0.00
618443 | 1.EG +0.00
618430 | 1.EG +0.00
618444 | 1.EG +0.00
618453 | 1.EG +0.00
618454 | 1.EG +0.00
624225 | 1.EG +0.00
624226 | 1.EG +0.00
624228 | 1.EG +0.00
624229 | 1.EG +0.00
624231 | 1.EG +0.00
624232 | 1.EG +0.00
624234 | 1.EG +0.00
624235 | 1.EG +0.00
624237 | 1.EG +0.00
624238 | 1.EG +0.00
624240 | 1.EG +0.00
624241 | 1.EG +0.00
624243 | 1.EG +0.00
624244 | 1.EG +0.00
624246 | 1.EG +0.00
624247 | 1.EG +0.00
624249 | 1.EG +0.00
624250 | 1.EG +0.00
618664 | 1.EG +0.00
618697 | 1.EG +0.00
618668 | 1.EG +0.00
618672 | 1.EG +0.00
618704 | 1.EG +0.00
618701 | 1.EG +0.00
618698 | 1.EG +0.00
618695 | 1.EG +0.00
618673 | 1.EG +0.00
618674 | 1.EG +0.00
618772 | 1.EG +0.00
618776 | 1.EG +0.00
625282 | 4.3OG +15.90
625283 | 4.3OG +15.90
625284 | 4.3OG +15.90
625285 | 4.3OG +15.90
625286 | 4.3OG +15.90
625287 | 4.3OG +15.90
625288 | 4.3OG +15.90
625065 | 4.3OG +15.90
625066 | 4.3OG +15.90
625067 | 4.3OG +15.90
625068 | 4.3OG +15.90
625069 | 4.3OG +15.90
625070 | 4.3OG +15.90
625071 | 4.3OG +15.90
625073 | 4.3OG +15.90
625074 | 4.3OG +15.90
625075 | 4.3OG +15.90
625076 | 4.3OG +15.90
625077 | 4.3OG +15.90
625078 | 4.3OG +15.90
625079 | 4.3OG +15.90
625523 | 4.3OG +15.90
625525 | 4.3OG +15.90
625526 | 4.3OG +15.90
625527 | 4.3OG +15.90
625528 | 4.3OG +15.90
625529 | 4.3OG +15.90
625530 | 4.3OG +15.90
625531 | 4.3OG +15.90
625532 | 4.3OG +15.90
625533 | 4.3OG +15.90
625333 | 4.3OG +15.90
625335 | 4.3OG +15.90
625336 | 4.3OG +15.90
625337 | 4.3OG +15.90
625338 | 4.3OG +15.90
625339 | 4.3OG +15.90
625340 | 4.3OG +15.90
625341 | 4.3OG +15.90
625342 | 4.3OG +15.90
625343 | 4.3OG +15.90
625557 | 4.3OG +15.90
625558 | 4.3OG +15.90
625559 | 4.3OG +15.90
625560 | 4.3OG +15.90
625561 | 4.3OG +15.90
625562 | 4.3OG +15.90
625563 | 4.3OG +15.90
625564 | 4.3OG +15.90
625565 | 4.3OG +15.90
625377 | 4.3OG +15.90
625378 | 4.3OG +15.90
625379 | 4.3OG +15.90
625380 | 4.3OG +15.90
625381 | 4.3OG +15.90
625382 | 4.3OG +15.90
625383 | 4.3OG +15.90
625384 | 4.3OG +15.90
625385 | 4.3OG +15.90
622080 | 6.EG KH -1.15
622084 | 6.EG KH -1.15
622122 | 6.EG KH -1.15
622105 | 6.EG KH -1.15
622106 | 6.EG KH -1.15
622107 | 6.EG KH -1.15
622108 | 6.EG KH -1.15
622123 | 6.EG KH -1.15
624461 | 4.3OG +15.90
624463 | 4.3OG +15.90
624465 | 4.3OG +15.90
624467 | 4.3OG +15.90
624469 | 4.3OG +15.90
624590 | 4.3OG +15.90
624592 | 4.3OG +15.90
624594 | 4.3OG +15.90
624596 | 4.3OG +15.90
624598 | 4.3OG +15.90
624600 | 4.3OG +15.90
624602 | 4.3OG +15.90
624604 | 4.3OG +15.90
624606 | 4.3OG +15.90
624608 | 4.3OG +15.90
624610 | 4.3OG +15.90
624612 | 4.3OG +15.90
624614 | 4.3OG +15.90
624616 | 4.3OG +15.90
624618 | 4.3OG +15.90
624620 | 4.3OG +15.90
624622 | 4.3OG +15.90
624624 | 4.3OG +15.90
624487 | 4.3OG +15.90
624489 | 4.3OG +15.90
624491 | 4.3OG +15.90
624493 | 4.3OG +15.90
624495 | 4.3OG +15.90
624626 | 4.3OG +15.90
624628 | 4.3OG +15.90
624630 | 4.3OG +15.90
624632 | 4.3OG +15.90
624634 | 4.3OG +15.90
624636 | 4.3OG +15.90
624638 | 4.3OG +15.90
624640 | 4.3OG +15.90
624642 | 4.3OG +15.90
624644 | 4.3OG +15.90
624646 | 4.3OG +15.90
624648 | 4.3OG +15.90
624650 | 4.3OG +15.90
624652 | 4.3OG +15.90
624654 | 4.3OG +15.90
624656 | 4.3OG +15.90
624658 | 4.3OG +15.90
624512 | 4.3OG +15.90
624514 | 4.3OG +15.90
624516 | 4.3OG +15.90
624518 | 4.3OG +15.90
624520 | 4.3OG +15.90
624662 | 4.3OG +15.90
624664 | 4.3OG +15.90
624666 | 4.3OG +15.90
624668 | 4.3OG +15.90
624670 | 4.3OG +15.90
624672 | 4.3OG +15.90
624674 | 4.3OG +15.90
624676 | 4.3OG +15.90
624678 | 4.3OG +15.90
624680 | 4.3OG +15.90
624682 | 4.3OG +15.90
624684 | 4.3OG +15.90
624686 | 4.3OG +15.90
624688 | 4.3OG +15.90
624690 | 4.3OG +15.90
624692 | 4.3OG +15.90
624694 | 4.3OG +15.90
624538 | 4.3OG +15.90
624540 | 4.3OG +15.90
624542 | 4.3OG +15.90
624544 | 4.3OG +15.90
624546 | 4.3OG +15.90
624698 | 4.3OG +15.90
624700 | 4.3OG +15.90
624702 | 4.3OG +15.90
624704 | 4.3OG +15.90
624706 | 4.3OG +15.90
624708 | 4.3OG +15.90
624710 | 4.3OG +15.90
624712 | 4.3OG +15.90
624714 | 4.3OG +15.90
624716 | 4.3OG +15.90
624718 | 4.3OG +15.90
624720 | 4.3OG +15.90
624722 | 4.3OG +15.90
624724 | 4.3OG +15.90
624726 | 4.3OG +15.90
624728 | 4.3OG +15.90
624730 | 4.3OG +15.90
624564 | 4.3OG +15.90
624566 | 4.3OG +15.90
624568 | 4.3OG +15.90
624570 | 4.3OG +15.90
624572 | 4.3OG +15.90
624734 | 4.3OG +15.90
624736 | 4.3OG +15.90
624738 | 4.3OG +15.90
624740 | 4.3OG +15.90
624742 | 4.3OG +15.90
624744 | 4.3OG +15.90
624746 | 4.3OG +15.90
624748 | 4.3OG +15.90
624750 | 4.3OG +15.90
624752 | 4.3OG +15.90
624754 | 4.3OG +15.90
624756 | 4.3OG +15.90
624758 | 4.3OG +15.90
624760 | 4.3OG +15.90
624762 | 4.3OG +15.90
624764 | 4.3OG +15.90
625251 | 4.3OG +15.90
625252 | 4.3OG +15.90
625253 | 4.3OG +15.90
625254 | 4.3OG +15.90
625255 | 4.3OG +15.90
625257 | 4.3OG +15.90
625258 | 4.3OG +15.90
625259 | 4.3OG +15.90
625153 | 4.3OG +15.90
625154 | 4.3OG +15.90
625155 | 4.3OG +15.90
625156 | 4.3OG +15.90
625157 | 4.3OG +15.90
625159 | 4.3OG +15.90
625160 | 4.3OG +15.90
625161 | 4.3OG +15.90
625216 | 4.3OG +15.90
625217 | 4.3OG +15.90
625218 | 4.3OG +15.90
625219 | 4.3OG +15.90
625220 | 4.3OG +15.90
625221 | 4.3OG +15.90
625222 | 4.3OG +15.90
625223 | 4.3OG +15.90
625224 | 4.3OG +15.90
625225 | 4.3OG +15.90
625677 | 4.3OG +15.90
625678 | 4.3OG +15.90
625763 | 4.3OG +15.90
625764 | 4.3OG +15.90
625720 | 4.3OG +15.90
625721 | 4.3OG +15.90
625722 | 4.3OG +15.90
625723 | 4.3OG +15.90
625724 | 4.3OG +15.90
625725 | 4.3OG +15.90
625809 | 4.3OG +15.90
625810 | 4.3OG +15.90
625811 | 4.3OG +15.90
625812 | 4.3OG +15.90
625813 | 4.3OG +15.90
625814 | 4.3OG +15.90
626128 | 3.2OG +10.60
626129 | 3.2OG +10.60
626130 | 3.2OG +10.60
626133 | 3.2OG +10.60
626134 | 3.2OG +10.60
626135 | 3.2OG +10.60
626137 | 3.2OG +10.60
626138 | 3.2OG +10.60
626139 | 3.2OG +10.60
626140 | 3.2OG +10.60
626142 | 3.2OG +10.60
626143 | 3.2OG +10.60
626144 | 3.2OG +10.60
626145 | 3.2OG +10.60
626147 | 3.2OG +10.60
626148 | 3.2OG +10.60
626149 | 3.2OG +10.60
626150 | 3.2OG +10.60
626152 | 3.2OG +10.60
626153 | 3.2OG +10.60
626154 | 3.2OG +10.60
626155 | 3.2OG +10.60
626209 | 3.2OG +10.60
626211 | 3.2OG +10.60
626213 | 3.2OG +10.60
626215 | 3.2OG +10.60
626272 | 3.2OG +10.60
626273 | 3.2OG +10.60
626274 | 3.2OG +10.60
626275 | 3.2OG +10.60
626230 | 3.2OG +10.60
626232 | 3.2OG +10.60
626234 | 3.2OG +10.60
626236 | 3.2OG +10.60
626277 | 3.2OG +10.60
626278 | 3.2OG +10.60
626279 | 3.2OG +10.60
626280 | 3.2OG +10.60
626251 | 3.2OG +10.60
626253 | 3.2OG +10.60
626255 | 3.2OG +10.60
626257 | 3.2OG +10.60
626282 | 3.2OG +10.60
626283 | 3.2OG +10.60
626284 | 3.2OG +10.60
626285 | 3.2OG +10.60
626314 | 3.2OG +10.60
626318 | 3.2OG +10.60
626322 | 3.2OG +10.60
626366 | 3.2OG +10.60
626341 | 3.2OG +10.60
626343 | 3.2OG +10.60
626344 | 3.2OG +10.60
626346 | 3.2OG +10.60
626347 | 3.2OG +10.60
626389 | 3.2OG +10.60
626477 | 3.2OG +10.60
626486 | 3.2OG +10.60
626396 | 3.2OG +10.60
626397 | 3.2OG +10.60
626417 | 3.2OG +10.60
626419 | 3.2OG +10.60
626505 | 3.2OG +10.60
626496 | 3.2OG +10.60
626497 | 3.2OG +10.60
626421 | 3.2OG +10.60
626466 | 3.2OG +10.60
626468 | 3.2OG +10.60
626446 | 3.2OG +10.60
626447 | 3.2OG +10.60
626518 | 2.1OG +5.30
626520 | 2.1OG +5.30
626522 | 2.1OG +5.30
626524 | 2.1OG +5.30
626526 | 2.1OG +5.30
626528 | 2.1OG +5.30
626530 | 2.1OG +5.30
626532 | 2.1OG +5.30
626534 | 2.1OG +5.30
626536 | 2.1OG +5.30
626538 | 2.1OG +5.30
626540 | 2.1OG +5.30
626542 | 2.1OG +5.30
626544 | 2.1OG +5.30
626546 | 2.1OG +5.30
626548 | 2.1OG +5.30
626550 | 2.1OG +5.30
626552 | 2.1OG +5.30
626554 | 2.1OG +5.30
626556 | 2.1OG +5.30
626558 | 2.1OG +5.30
626560 | 2.1OG +5.30
626562 | 2.1OG +5.30
626564 | 2.1OG +5.30
626566 | 2.1OG +5.30
626568 | 2.1OG +5.30
626570 | 2.1OG +5.30
626572 | 2.1OG +5.30
626574 | 2.1OG +5.30
626576 | 2.1OG +5.30
626775 | 2.1OG +5.30
626777 | 2.1OG +5.30
626779 | 2.1OG +5.30
626781 | 2.1OG +5.30
626783 | 2.1OG +5.30
626785 | 2.1OG +5.30
626805 | 2.1OG +5.30
626807 | 2.1OG +5.30
626809 | 2.1OG +5.30
626811 | 2.1OG +5.30
626813 | 2.1OG +5.30
626815 | 2.1OG +5.30
626817 | 2.1OG +5.30
626819 | 2.1OG +5.30
626821 | 2.1OG +5.30
626823 | 2.1OG +5.30
626825 | 2.1OG +5.30
626827 | 2.1OG +5.30
626829 | 2.1OG +5.30
626831 | 2.1OG +5.30
626833 | 2.1OG +5.30
626835 | 2.1OG +5.30
626837 | 2.1OG +5.30
626839 | 2.1OG +5.30
626841 | 2.1OG +5.30
626843 | 2.1OG +5.30
626845 | 2.1OG +5.30
626847 | 2.1OG +5.30
626849 | 2.1OG +5.30
626851 | 2.1OG +5.30
626853 | 2.1OG +5.30
626855 | 2.1OG +5.30
626857 | 2.1OG +5.30
626859 | 2.1OG +5.30
626861 | 2.1OG +5.30
626863 | 2.1OG +5.30
626865 | 2.1OG +5.30
626867 | 2.1OG +5.30
626869 | 2.1OG +5.30
626871 | 2.1OG +5.30
626873 | 2.1OG +5.30
626875 | 2.1OG +5.30
626877 | 2.1OG +5.30
626879 | 2.1OG +5.30
626881 | 2.1OG +5.30
626883 | 2.1OG +5.30
626885 | 2.1OG +5.30
626887 | 2.1OG +5.30
626889 | 2.1OG +5.30
626891 | 2.1OG +5.30
626893 | 2.1OG +5.30
626895 | 2.1OG +5.30
626897 | 2.1OG +5.30
626899 | 2.1OG +5.30
626901 | 2.1OG +5.30
626903 | 2.1OG +5.30
626905 | 2.1OG +5.30
626907 | 2.1OG +5.30
626909 | 2.1OG +5.30
626911 | 2.1OG +5.30
626913 | 2.1OG +5.30
626915 | 2.1OG +5.30
626917 | 2.1OG +5.30
626919 | 2.1OG +5.30
626921 | 2.1OG +5.30
626923 | 2.1OG +5.30
626925 | 2.1OG +5.30
626927 | 2.1OG +5.30
626929 | 2.1OG +5.30
626931 | 2.1OG +5.30
626933 | 2.1OG +5.30
626935 | 2.1OG +5.30
626937 | 2.1OG +5.30
626939 | 2.1OG +5.30
626941 | 2.1OG +5.30
626943 | 2.1OG +5.30
626945 | 2.1OG +5.30
626947 | 2.1OG +5.30
626949 | 2.1OG +5.30
626951 | 2.1OG +5.30
626953 | 2.1OG +5.30
626955 | 2.1OG +5.30
626957 | 2.1OG +5.30
626959 | 2.1OG +5.30
626961 | 2.1OG +5.30
626963 | 2.1OG +5.30
626965 | 2.1OG +5.30
626967 | 2.1OG +5.30
626969 | 2.1OG +5.30
626971 | 2.1OG +5.30
626669 | 2.1OG +5.30
626675 | 2.1OG +5.30
626677 | 2.1OG +5.30
626679 | 2.1OG +5.30
626973 | 2.1OG +5.30
626975 | 2.1OG +5.30
626977 | 2.1OG +5.30
626979 | 2.1OG +5.30
626981 | 2.1OG +5.30
626983 | 2.1OG +5.30
626985 | 2.1OG +5.30
626987 | 2.1OG +5.30
626989 | 2.1OG +5.30
626991 | 2.1OG +5.30
626690 | 2.1OG +5.30
626692 | 2.1OG +5.30
626694 | 2.1OG +5.30
626696 | 2.1OG +5.30
626698 | 2.1OG +5.30
626700 | 2.1OG +5.30
626993 | 2.1OG +5.30
626995 | 2.1OG +5.30
626997 | 2.1OG +5.30
626999 | 2.1OG +5.30
627001 | 2.1OG +5.30
627003 | 2.1OG +5.30
627005 | 2.1OG +5.30
627007 | 2.1OG +5.30
627009 | 2.1OG +5.30
627011 | 2.1OG +5.30
627013 | 2.1OG +5.30
627015 | 2.1OG +5.30
627017 | 2.1OG +5.30
627019 | 2.1OG +5.30
626721 | 2.1OG +5.30
626723 | 2.1OG +5.30
626725 | 2.1OG +5.30
626727 | 2.1OG +5.30
626729 | 2.1OG +5.30
626731 | 2.1OG +5.30
627023 | 2.1OG +5.30
627025 | 2.1OG +5.30
627027 | 2.1OG +5.30
627029 | 2.1OG +5.30
627031 | 2.1OG +5.30
627033 | 2.1OG +5.30
627035 | 2.1OG +5.30
627037 | 2.1OG +5.30
627039 | 2.1OG +5.30
627041 | 2.1OG +5.30
627043 | 2.1OG +5.30
627045 | 2.1OG +5.30
627047 | 2.1OG +5.30
627049 | 2.1OG +5.30
626752 | 2.1OG +5.30
626754 | 2.1OG +5.30
626756 | 2.1OG +5.30
626758 | 2.1OG +5.30
627053 | 2.1OG +5.30
627055 | 2.1OG +5.30
627057 | 2.1OG +5.30
627059 | 2.1OG +5.30
627061 | 2.1OG +5.30
627063 | 2.1OG +5.30
627065 | 2.1OG +5.30
627067 | 2.1OG +5.30
627069 | 2.1OG +5.30
627529 | 2.1OG +5.30
627531 | 2.1OG +5.30
627533 | 2.1OG +5.30
627535 | 2.1OG +5.30
627537 | 2.1OG +5.30
627539 | 2.1OG +5.30
627541 | 2.1OG +5.30
627543 | 2.1OG +5.30
627545 | 2.1OG +5.30
627547 | 2.1OG +5.30
627549 | 2.1OG +5.30
627551 | 2.1OG +5.30
627553 | 2.1OG +5.30
627555 | 2.1OG +5.30
627557 | 2.1OG +5.30
627559 | 2.1OG +5.30
627561 | 2.1OG +5.30
627563 | 2.1OG +5.30
627565 | 2.1OG +5.30
627567 | 2.1OG +5.30
627659 | 2.1OG +5.30
627661 | 2.1OG +5.30
627663 | 2.1OG +5.30
627665 | 2.1OG +5.30
627667 | 2.1OG +5.30
627669 | 2.1OG +5.30
627671 | 2.1OG +5.30
627673 | 2.1OG +5.30
627675 | 2.1OG +5.30
627677 | 2.1OG +5.30
627679 | 2.1OG +5.30
627681 | 2.1OG +5.30
627683 | 2.1OG +5.30
627685 | 2.1OG +5.30
627687 | 2.1OG +5.30
627689 | 2.1OG +5.30
627691 | 2.1OG +5.30
627693 | 2.1OG +5.30
627695 | 2.1OG +5.30
627697 | 2.1OG +5.30
627699 | 2.1OG +5.30
627701 | 2.1OG +5.30
627703 | 2.1OG +5.30
627870 | 2.1OG +5.30
627871 | 2.1OG +5.30
627872 | 2.1OG +5.30
627873 | 2.1OG +5.30
627875 | 2.1OG +5.30
627876 | 2.1OG +5.30
627877 | 2.1OG +5.30
627878 | 2.1OG +5.30
627919 | 2.1OG +5.30
627920 | 2.1OG +5.30
627921 | 2.1OG +5.30
627924 | 2.1OG +5.30
627925 | 2.1OG +5.30
627926 | 2.1OG +5.30
627966 | 2.1OG +5.30
627967 | 2.1OG +5.30
627968 | 2.1OG +5.30
627969 | 2.1OG +5.30
627971 | 2.1OG +5.30
627972 | 2.1OG +5.30
627973 | 2.1OG +5.30
627974 | 2.1OG +5.30
628007 | 2.1OG +5.30
628009 | 2.1OG +5.30
628011 | 2.1OG +5.30
628013 | 2.1OG +5.30
628015 | 2.1OG +5.30
628016 | 2.1OG +5.30
628017 | 2.1OG +5.30
628018 | 2.1OG +5.30
628042 | 2.1OG +5.30
628044 | 2.1OG +5.30
628046 | 2.1OG +5.30
628048 | 2.1OG +5.30
628050 | 2.1OG +5.30
628051 | 2.1OG +5.30
628052 | 2.1OG +5.30
628053 | 2.1OG +5.30
628077 | 2.1OG +5.30
628079 | 2.1OG +5.30
628081 | 2.1OG +5.30
628083 | 2.1OG +5.30
628085 | 2.1OG +5.30
628086 | 2.1OG +5.30
628087 | 2.1OG +5.30
628088 | 2.1OG +5.30
628372 | 1.EG +0.00
628373 | 1.EG +0.00
628374 | 1.EG +0.00
628376 | 1.EG +0.00
628377 | 1.EG +0.00
628378 | 1.EG +0.00
628591 | 1.EG +0.00
628592 | 1.EG +0.00
628593 | 1.EG +0.00
628594 | 1.EG +0.00
628595 | 1.EG +0.00
628690 | 1.EG +0.00
628695 | 1.EG +0.00
628597 | 1.EG +0.00
628598 | 1.EG +0.00
628599 | 1.EG +0.00
628600 | 1.EG +0.00
628601 | 1.EG +0.00
628691 | 1.EG +0.00
628696 | 1.EG +0.00
628615 | 1.EG +0.00
628616 | 1.EG +0.00
628617 | 1.EG +0.00
628619 | 1.EG +0.00
628620 | 1.EG +0.00
628621 | 1.EG +0.00
628720 | 1.EG +0.00
628721 | 1.EG +0.00
628722 | 1.EG +0.00
628791 | 1.EG +0.00
628792 | 1.EG +0.00
628793 | 1.EG +0.00
628795 | 1.EG +0.00
628796 | 1.EG +0.00
628764 | 1.EG +0.00
628765 | 1.EG +0.00
628766 | 1.EG +0.00
628767 | 1.EG +0.00
628798 | 1.EG +0.00
628799 | 1.EG +0.00
628800 | 1.EG +0.00
628801 | 1.EG +0.00

# IfcPlate: System Panel:Solid (163)
Type - PredefinedType: CURTAIN_PANEL; Material: Default
Type - Pset_PlateCommon - IsExternal: no; ThermalTransmittance: 3.7021 kg/K/s3
Type - Pset_ProductRequirements - Category: Curtain Panels
Pset_PlateCommon - Reference: Solid
Pset_QuantityTakeOff - Reference: Solid
Group: Model Group:Building:629362
Name (System Panel:Solid:...) | In
628306 | 1.EG +0.00
628408 | 1.EG +0.00
628404 | 1.EG +0.00
628310 | 1.EG +0.00
628312 | 1.EG +0.00
628314 | 1.EG +0.00
628316 | 1.EG +0.00
628148 | 1.EG +0.00
628283 | 1.EG +0.00
628277 | 1.EG +0.00
628155 | 1.EG +0.00
628157 | 1.EG +0.00
628159 | 1.EG +0.00
628161 | 1.EG +0.00
628175 | 1.EG +0.00
628286 | 1.EG +0.00
628280 | 1.EG +0.00
628176 | 1.EG +0.00
628177 | 1.EG +0.00
628178 | 1.EG +0.00
628179 | 1.EG +0.00
628149 | 1.EG +0.00
628190 | 1.EG +0.00
628425 | 1.EG +0.00
628434 | 1.EG +0.00
628438 | 1.EG +0.00
628548 | 1.EG +0.00
628440 | 1.EG +0.00
628442 | 1.EG +0.00
628444 | 1.EG +0.00
628549 | 1.EG +0.00
628462 | 1.EG +0.00
628467 | 1.EG +0.00
625048 | 4.3OG +15.90
625053 | 4.3OG +15.90
625055 | 4.3OG +15.90
625057 | 4.3OG +15.90
625059 | 4.3OG +15.90
625061 | 4.3OG +15.90
625063 | 4.3OG +15.90
625304 | 4.3OG +15.90
625315 | 4.3OG +15.90
625317 | 4.3OG +15.90
625319 | 4.3OG +15.90
625321 | 4.3OG +15.90
625323 | 4.3OG +15.90
625325 | 4.3OG +15.90
625327 | 4.3OG +15.90
625329 | 4.3OG +15.90
625331 | 4.3OG +15.90
625345 | 4.3OG +15.90
625346 | 4.3OG +15.90
625347 | 4.3OG +15.90
625348 | 4.3OG +15.90
625349 | 4.3OG +15.90
625350 | 4.3OG +15.90
625351 | 4.3OG +15.90
625352 | 4.3OG +15.90
625353 | 4.3OG +15.90
625354 | 4.3OG +15.90
625355 | 4.3OG +15.90
625305 | 4.3OG +15.90
625361 | 4.3OG +15.90
625363 | 4.3OG +15.90
625365 | 4.3OG +15.90
625367 | 4.3OG +15.90
625369 | 4.3OG +15.90
625371 | 4.3OG +15.90
625373 | 4.3OG +15.90
625375 | 4.3OG +15.90
625387 | 4.3OG +15.90
625388 | 4.3OG +15.90
625389 | 4.3OG +15.90
625390 | 4.3OG +15.90
625391 | 4.3OG +15.90
625392 | 4.3OG +15.90
625393 | 4.3OG +15.90
625394 | 4.3OG +15.90
625395 | 4.3OG +15.90
625132 | 4.3OG +15.90
625134 | 4.3OG +15.90
625136 | 4.3OG +15.90
625138 | 4.3OG +15.90
625140 | 4.3OG +15.90
625144 | 4.3OG +15.90
625146 | 4.3OG +15.90
625148 | 4.3OG +15.90
625663 | 4.3OG +15.90
625665 | 4.3OG +15.90
625667 | 4.3OG +15.90
625669 | 4.3OG +15.90
625671 | 4.3OG +15.90
625788 | 4.3OG +15.90
625789 | 4.3OG +15.90
625790 | 4.3OG +15.90
625791 | 4.3OG +15.90
625792 | 4.3OG +15.90
625793 | 4.3OG +15.90
625708 | 4.3OG +15.90
625710 | 4.3OG +15.90
625712 | 4.3OG +15.90
625714 | 4.3OG +15.90
625716 | 4.3OG +15.90
625718 | 4.3OG +15.90
625816 | 4.3OG +15.90
625817 | 4.3OG +15.90
625818 | 4.3OG +15.90
625819 | 4.3OG +15.90
625820 | 4.3OG +15.90
625821 | 4.3OG +15.90
626066 | 3.2OG +10.60
626068 | 3.2OG +10.60
626070 | 3.2OG +10.60
626085 | 3.2OG +10.60
626087 | 3.2OG +10.60
626089 | 3.2OG +10.60
626091 | 3.2OG +10.60
626106 | 3.2OG +10.60
626108 | 3.2OG +10.60
626110 | 3.2OG +10.60
626112 | 3.2OG +10.60
626373 | 3.2OG +10.60
626374 | 3.2OG +10.60
626339 | 3.2OG +10.60
626381 | 3.2OG +10.60
626382 | 3.2OG +10.60
626391 | 3.2OG +10.60
626393 | 3.2OG +10.60
626478 | 3.2OG +10.60
626415 | 3.2OG +10.60
626440 | 3.2OG +10.60
626444 | 3.2OG +10.60
627862 | 2.1OG +5.30
627864 | 2.1OG +5.30
627866 | 2.1OG +5.30
627868 | 2.1OG +5.30
627911 | 2.1OG +5.30
627913 | 2.1OG +5.30
627915 | 2.1OG +5.30
627958 | 2.1OG +5.30
627960 | 2.1OG +5.30
627962 | 2.1OG +5.30
627964 | 2.1OG +5.30
628366 | 1.EG +0.00
628368 | 1.EG +0.00
628370 | 1.EG +0.00
628570 | 1.EG +0.00
628579 | 1.EG +0.00
628583 | 1.EG +0.00
628693 | 1.EG +0.00
628585 | 1.EG +0.00
628587 | 1.EG +0.00
628589 | 1.EG +0.00
628694 | 1.EG +0.00
628607 | 1.EG +0.00
628612 | 1.EG +0.00
628714 | 1.EG +0.00
628716 | 1.EG +0.00
628718 | 1.EG +0.00
628756 | 1.EG +0.00
628758 | 1.EG +0.00
628760 | 1.EG +0.00
628762 | 1.EG +0.00

# IfcPlate: System Panel:Solid_Empty (48)
In: 4.3OG +15.90
Type - PredefinedType: CURTAIN_PANEL; Material: Default_EMPTY
Type - Pset_PlateCommon - IsExternal: no
Type - Pset_ProductRequirements - Category: Curtain Panels
Pset_PlateCommon - Reference: Solid_Empty
Pset_QuantityTakeOff - Reference: Solid_Empty
Group: Model Group:Building:629362
Name (System Panel:Solid_Empty:...)
625882
625884
625886
625888
625890
625892
625894
625896
625898
625900
625913
625915
625917
625919
625921
625923
625925
625927
625929
625931
625944
625946
625948
625950
625952
625954
625956
625958
625960
625972
625974
625976
625978
625980
625982
625984
625986
625988
625990
626003
626005
626007
626009
626011
626013
626015
626017
626019

# IfcRailing: Railing:1100mm (4)
Material: <Unnamed>; Group: Model Group:Building:629362
Pset_ProductRequirements - Category: Railings
Pset_QuantityTakeOff - Reference: 1100mm
Pset_RailingCommon - IsExternal: no; Reference: 1100mm; Height: 1100 mm
Name (Railing:1100mm:...) | In
623359 | 6.EG KH -1.15
623406 | 7.1OG KH +2.65
623449 | 8.2OG KH +6.45
623971 | 0.UG -3.60

# IfcRailing: Railing:600mm (5)
In: 1.EG +0.00
Material: <Unnamed>; Group: Model Group:Building:629362
Pset_ProductRequirements - Category: Railings
Pset_QuantityTakeOff - Reference: 600mm
Pset_RailingCommon - IsExternal: no; Reference: 600mm; Height: 600 mm
Name (Railing:600mm:...)
623634
623658
623682
623706
629335

# IfcRamp: Ramp:Rampe_CJC, Ramp:Rampe_CJC:623753
In: 6.EG KH -1.15
Material: Analytical Wall Surface_CJC; Group: Model Group:Building:629362
Pset_ProductRequirements - Category: Ramps
Pset_QuantityTakeOff - Reference: Rampe_CJC
Pset_RampCommon - IsExternal: yes; Reference: Rampe_CJC

# IfcRamp: Ramp:Standard, Ramp:Standard:623150
In: 0.UG -3.60
Pset_ProductRequirements - Category: Ramps
Pset_QuantityTakeOff - Reference: Standard
Pset_RampCommon - IsExternal: no; Reference: Standard
Group: Model Group:Building:629362

# IfcRampFlight: Ramp:Standard, Ramp:Standard:623150:1
In: 0.UG -3.60
Material: Analytical Wall Surface_CJC; Group: Model Group:Building:629362
Pset_ProductRequirements - Category: Ramps
Pset_QuantityTakeOff - Reference: Standard; sets with these values: 2

# IfcRoof: Basic Roof:Dach_CJC, Basic Roof:Dach_CJC:621602
In: 5.DG +21.50
Material: Rigid insulation 300 mm, Analytical Wall Surface_CJC 150 mm; Group: Model Group:Building:629362
Pset_ProductRequirements - Category: Roofs
Pset_QuantityTakeOff - Reference: Dach_CJC
Pset_RoofCommon - IsExternal: yes; Reference: Dach_CJC; ProjectedArea: 2085.05 m2; TotalArea: 2085.05 m2

# IfcRoof: Basic Roof:Dach_CJC_CAP (4)
Material: Analytical Wall Surface_CJC 50 mm; Group: Model Group:Building:629362
Pset_ProductRequirements - Category: Roofs
Pset_QuantityTakeOff - Reference: Dach_CJC_CAP
Pset_RoofCommon - IsExternal: yes; Reference: Dach_CJC_CAP
Name (Basic Roof:Dach_CJC_CAP:...) | In | ProjectedArea (m2) | TotalArea (m2)
621651 | 5.DG +21.50 | 1603.74 | 144.143
622416 | 10.DG KH +14.25 | 403.322 | 42.2648
624114 | 5.DG +21.50 | 0.902669 | 0.742657
624136 | 5.DG +21.50 | 2.21018 | 1.97016

# IfcRoof: Basic Roof:Dach_CJC_KH, Basic Roof:Dach_CJC_KH:622389
In: 10.DG KH +14.25
Material: Rigid insulation 300 mm, Analytical Wall Surface_CJC 200 mm; Group: Model Group:Building:629362
Pset_ProductRequirements - Category: Roofs
Pset_QuantityTakeOff - Reference: Dach_CJC_KH
Pset_RoofCommon - IsExternal: yes; Reference: Dach_CJC_KH; ProjectedArea: 362.987 m2; TotalArea: 362.987 m2

# IfcRoof: Basic Roof:Dach_CJC_KH_2, Basic Roof:Dach_CJC_KH_2:623846
In: 8.2OG KH +6.45
Material: Rigid insulation 200 mm, Analytical Wall Surface_CJC 150 mm; Group: Model Group:Building:629362
Pset_ProductRequirements - Category: Roofs
Pset_QuantityTakeOff - Reference: Dach_CJC_KH_2
Pset_RoofCommon - IsExternal: yes; Reference: Dach_CJC_KH_2; ProjectedArea: 120.991 m2; TotalArea: 120.991 m2

# IfcRoof: Basic Roof:Dach_CJC_Staircase, Basic Roof:Dach_CJC_Staircase:621595
In: 5.DG +21.50
Material: Analytical Wall Surface_CJC 400 mm; Group: Model Group:Building:629362
Pset_ProductRequirements - Category: Roofs
Pset_QuantityTakeOff - Reference: Dach_CJC_Staircase
Pset_RoofCommon - IsExternal: yes; Reference: Dach_CJC_Staircase; ProjectedArea: 40.1659 m2; TotalArea: 40.1659 m2

# IfcRoof: Basic Roof:Dach_CJC_Staircase 2, Basic Roof:Dach_CJC_Staircase 2:621638
In: 5.DG +21.50
Material: Analytical Wall Surface_CJC 200 mm; Group: Model Group:Building:629362
Pset_ProductRequirements - Category: Roofs
Pset_QuantityTakeOff - Reference: Dach_CJC_Staircase 2
Pset_RoofCommon - IsExternal: yes; Reference: Dach_CJC_Staircase 2; ProjectedArea: 10.0242 m2; TotalArea: 10.0242 m2

# IfcSlab: Basic Roof:Dach_CJC, Basic Roof:Dach_CJC:621602
In: 5.DG +21.50
Type - PredefinedType: ROOF
Type - Pset_ElementShading - Roughness: 914.4 mm
Type - Pset_ProductRequirements - Category: Roofs
Type - Pset_SlabCommon - IsExternal: yes; ThermalTransmittance: 0.116667 kg/K/s3
Material: Rigid insulation 300 mm, Analytical Wall Surface_CJC 150 mm; Group: Model Group:Building:629362
Pset_QuantityTakeOff - Reference: Dach_CJC; sets with these values: 2
Pset_SlabCommon - PitchAngle: 0 deg; Reference: Dach_CJC

# IfcSlab: Basic Roof:Dach_CJC_CAP (4)
Type - PredefinedType: ROOF
Type - Pset_ElementShading - Roughness: 914.4 mm
Type - Pset_ProductRequirements - Category: Roofs
Type - Pset_SlabCommon - IsExternal: yes
Pset_QuantityTakeOff - Reference: Dach_CJC_CAP; sets with these values: 2
Pset_SlabCommon - PitchAngle: 0 deg; Reference: Dach_CJC_CAP
Group: Model Group:Building:629362
Name (Basic Roof:Dach_CJC_CAP:...) | In
621651:1 | 5.DG +21.50
622416:1 | 10.DG KH +14.25
624114:1 | 5.DG +21.50
624136:1 | 5.DG +21.50

# IfcSlab: Basic Roof:Dach_CJC_KH, Basic Roof:Dach_CJC_KH:622389
In: 10.DG KH +14.25
Type - PredefinedType: ROOF
Type - Pset_ElementShading - Roughness: 914.4 mm
Type - Pset_ProductRequirements - Category: Roofs
Type - Pset_SlabCommon - IsExternal: yes; ThermalTransmittance: 0.116667 kg/K/s3
Material: Rigid insulation 300 mm, Analytical Wall Surface_CJC 200 mm; Group: Model Group:Building:629362
Pset_QuantityTakeOff - Reference: Dach_CJC_KH; sets with these values: 2
Pset_SlabCommon - PitchAngle: 0 deg; Reference: Dach_CJC_KH

# IfcSlab: Basic Roof:Dach_CJC_KH_2, Basic Roof:Dach_CJC_KH_2:623846
In: 8.2OG KH +6.45
Type - PredefinedType: ROOF
Type - Pset_ElementShading - Roughness: 914.4 mm
Type - Pset_ProductRequirements - Category: Roofs
Type - Pset_SlabCommon - IsExternal: yes; ThermalTransmittance: 0.175 kg/K/s3
Material: Rigid insulation 200 mm, Analytical Wall Surface_CJC 150 mm; Group: Model Group:Building:629362
Pset_QuantityTakeOff - Reference: Dach_CJC_KH_2; sets with these values: 2
Pset_SlabCommon - PitchAngle: 0 deg; Reference: Dach_CJC_KH_2

# IfcSlab: Basic Roof:Dach_CJC_Staircase, Basic Roof:Dach_CJC_Staircase:621595
In: 5.DG +21.50
Type - PredefinedType: ROOF
Type - Pset_ElementShading - Roughness: 914.4 mm
Type - Pset_ProductRequirements - Category: Roofs
Type - Pset_SlabCommon - IsExternal: yes
Material: Analytical Wall Surface_CJC 400 mm; Group: Model Group:Building:629362
Pset_QuantityTakeOff - Reference: Dach_CJC_Staircase; sets with these values: 2
Pset_SlabCommon - PitchAngle: 0 deg; Reference: Dach_CJC_Staircase

# IfcSlab: Basic Roof:Dach_CJC_Staircase 2, Basic Roof:Dach_CJC_Staircase 2:621638
In: 5.DG +21.50
Type - PredefinedType: ROOF
Type - Pset_ElementShading - Roughness: 914.4 mm
Type - Pset_ProductRequirements - Category: Roofs
Type - Pset_SlabCommon - IsExternal: yes
Material: Analytical Wall Surface_CJC 200 mm; Group: Model Group:Building:629362
Pset_QuantityTakeOff - Reference: Dach_CJC_Staircase 2; sets with these values: 2
Pset_SlabCommon - PitchAngle: 0 deg; Reference: Dach_CJC_Staircase 2

# IfcSlab: Floor:Boden_CJC (35)
Type - PredefinedType: FLOOR; Material: Analytical Floor Surface_CJC 150 mm
Type - Pset_ElementShading - Roughness: 914.4 mm
Type - Pset_ProductRequirements - Category: Floors
Type - Pset_SlabCommon - IsExternal: no
Pset_QuantityTakeOff - Reference: Boden_CJC; sets with these values: 2
Pset_SlabCommon - LoadBearing: no; PitchAngle: 0 deg; Reference: Boden_CJC
Group: Model Group:Building:629362
Name (Floor:Boden_CJC:...) | In
618226 | 1.EG +0.00
618466 | 1.EG +0.00
618499 | 2.1OG +5.30
618499:2 | 2.1OG +5.30
619164 | 2.1OG +5.30
619257 | 2.1OG +5.30
619288 | 2.1OG +5.30
619288:2 | 2.1OG +5.30
619547 | 2.1OG +5.30
619607 | 2.1OG +5.30
619861 | 3.2OG +10.60
619954 | 3.2OG +10.60
619985 | 3.2OG +10.60
619985:2 | 3.2OG +10.60
620192 | 3.2OG +10.60
620235 | 3.2OG +10.60
620785 | 4.3OG +15.90
620877 | 4.3OG +15.90
621101 | 4.3OG +15.90
621143 | 4.3OG +15.90
621545 | 4.3OG +15.90
621545:2 | 4.3OG +15.90
621580 | 4.3OG +15.90
621707 | 1.EG +0.00
621721 | 1.EG +0.00
621753 | 1.EG +0.00
622203 | 8.2OG KH +6.45
622298 | 9.3OG KH +10.25
622450 | 7.1OG KH +2.65
623016 | 0.UG -3.60
624024 | 0.UG -3.60
624024:2 | 0.UG -3.60
624024:3 | 0.UG -3.60
624388 | 1.EG +0.00
628116 | 1.EG +0.00

# IfcSlab: Floor:Boden_CJC 2, Floor:Boden_CJC 2:618654
In: 1.EG +0.00
Type - PredefinedType: FLOOR; Material: Analytical Floor Surface_CJC 200 mm
Type - Pset_ElementShading - Roughness: 914.4 mm
Type - Pset_ProductRequirements - Category: Floors
Type - Pset_SlabCommon - IsExternal: no
Pset_QuantityTakeOff - Reference: Boden_CJC 2; sets with these values: 2
Pset_SlabCommon - LoadBearing: no; PitchAngle: 0 deg; Reference: Boden_CJC 2
Group: Model Group:Building:629362

# IfcSlab: Floor:Boden_Rampe_CJC (7)
Type - PredefinedType: FLOOR; Material: Analytical Floor Surface_CJC 100 mm
Type - Pset_ElementShading - Roughness: 914.4 mm
Type - Pset_ProductRequirements - Category: Floors
Type - Pset_SlabCommon - IsExternal: no
Pset_QuantityTakeOff - Reference: Boden_Rampe_CJC; sets with these values: 2
Pset_SlabCommon - LoadBearing: no; PitchAngle: 0 deg; Reference: Boden_Rampe_CJC
Group: Model Group:Building:629362
Name (Floor:Boden_Rampe_CJC:...) | In
623745 | 1.EG +0.00
623814 | 0.UG -3.60
623814:2 | 0.UG -3.60
623814:3 | 0.UG -3.60
623814:4 | 0.UG -3.60
623814:5 | 0.UG -3.60
624004 | 0.UG -3.60

# IfcSlab: Floor:Boden_UG_CJC (2)
In: 0.UG -3.60
Type - PredefinedType: FLOOR; Material: Analytical Floor Surface_CJC 400 mm
Type - Pset_ElementShading - Roughness: 914.4 mm
Type - Pset_ProductRequirements - Category: Floors
Type - Pset_SlabCommon - IsExternal: no
Pset_QuantityTakeOff - Reference: Boden_UG_CJC; sets with these values: 2
Pset_SlabCommon - LoadBearing: no; PitchAngle: 0 deg; Reference: Boden_UG_CJC
Group: Model Group:Building:629362
Name (Floor:Boden_UG_CJC:...)
623772
623805

# IfcSlab: Floor:Slab-118, Floor:Slab-118:348961
In: 3D
Type - PredefinedType: FLOOR; Material: Paint-01 14000 mm
Type - Pset_ElementShading - Roughness: 304.8 mm
Type - Pset_ProductRequirements - Category: Floors
Type - Pset_SlabCommon - IsExternal: no
Pset_QuantityTakeOff - Reference: Slab-118; sets with these values: 2
Pset_SlabCommon - LoadBearing: no; PitchAngle: 0 deg; Reference: Slab-118
Group: Model Group:River:478153

# IfcSlab: Floor:Slab-161, Floor:Slab-161:350743
In: 3D
Type - PredefinedType: FLOOR; Material: Paint-01 13500 mm
Type - Pset_ElementShading - Roughness: 304.8 mm
Type - Pset_ProductRequirements - Category: Floors
Type - Pset_SlabCommon - IsExternal: no
Pset_QuantityTakeOff - Reference: Slab-161; sets with these values: 2
Pset_SlabCommon - LoadBearing: no; PitchAngle: 0 deg; Reference: Slab-161
Group: Model Group:River:478153

# IfcSlab: Floor:Slab-161:1010 (7)
In: 3D
Type - PredefinedType: FLOOR; Material: Paint-01 24000 mm
Type - Pset_ElementShading - Roughness: 304.8 mm
Type - Pset_ProductRequirements - Category: Floors
Type - Pset_SlabCommon - IsExternal: no
Pset_QuantityTakeOff - Reference: Slab-161:1010; sets with these values: 2
Pset_SlabCommon - LoadBearing: no; PitchAngle: 0 deg; Reference: Slab-161:1010
Group: Model Group:River:478153
Name (Floor:Slab-161:1010:...)
347365
347495
347597
347620
347884
349581
351355

# IfcSlab: Floor:Slab-161:1018 (12)
In: 3D
Type - PredefinedType: FLOOR; Material: Paint-01 30000 mm
Type - Pset_ElementShading - Roughness: 304.8 mm
Type - Pset_ProductRequirements - Category: Floors
Type - Pset_SlabCommon - IsExternal: no
Pset_QuantityTakeOff - Reference: Slab-161:1018; sets with these values: 2
Pset_SlabCommon - LoadBearing: no; PitchAngle: 0 deg; Reference: Slab-161:1018
Group: Model Group:River:478153
Name (Floor:Slab-161:1018:...)
347511
347650
350692
350848
350857
350865
350874
350883
350892
351309
351404
352250

# IfcSlab: Floor:Slab-161:1027, Floor:Slab-161:1027:347679
In: 3D
Type - PredefinedType: FLOOR; Material: Paint-01 45000 mm
Type - Pset_ElementShading - Roughness: 304.8 mm
Type - Pset_ProductRequirements - Category: Floors
Type - Pset_SlabCommon - IsExternal: no
Pset_QuantityTakeOff - Reference: Slab-161:1027; sets with these values: 2
Pset_SlabCommon - LoadBearing: no; PitchAngle: 0 deg; Reference: Slab-161:1027
Group: Model Group:River:478153

# IfcSlab: Floor:Slab-161:1039 (6)
In: 3D
Type - PredefinedType: FLOOR; Material: Paint-01 2000 mm
Type - Pset_ElementShading - Roughness: 304.8 mm
Type - Pset_ProductRequirements - Category: Floors
Type - Pset_SlabCommon - IsExternal: no
Pset_QuantityTakeOff - Reference: Slab-161:1039; sets with these values: 2
Pset_SlabCommon - LoadBearing: no; PitchAngle: 0 deg; Reference: Slab-161:1039
Group: Model Group:River:478153
Name (Floor:Slab-161:1039:...)
348048
348797
348856
349735
351147
352604

# IfcSlab: Floor:Slab-161:1054 (2)
In: 3D
Type - PredefinedType: FLOOR; Material: Paint-01 11000 mm
Type - Pset_ElementShading - Roughness: 304.8 mm
Type - Pset_ProductRequirements - Category: Floors
Type - Pset_SlabCommon - IsExternal: no
Pset_QuantityTakeOff - Reference: Slab-161:1054; sets with these values: 2
Pset_SlabCommon - LoadBearing: no; PitchAngle: 0 deg; Reference: Slab-161:1054
Group: Model Group:River:478153
Name (Floor:Slab-161:1054:...)
348322
350735

# IfcSlab: Floor:Slab-161:1066 (4)
In: 3D
Type - PredefinedType: FLOOR; Material: Paint-01 900 mm
Type - Pset_ElementShading - Roughness: 304.8 mm
Type - Pset_ProductRequirements - Category: Floors
Type - Pset_SlabCommon - IsExternal: no
Pset_QuantityTakeOff - Reference: Slab-161:1066; sets with these values: 2
Pset_SlabCommon - LoadBearing: no; PitchAngle: 0 deg; Reference: Slab-161:1066
Group: Model Group:River:478153
Name (Floor:Slab-161:1066:...)
348767
348966
349488
353038

# IfcSlab: Floor:Slab-161:1067 (5)
In: 3D
Type - PredefinedType: FLOOR; Material: Paint-01 3000 mm
Type - Pset_ElementShading - Roughness: 304.8 mm
Type - Pset_ProductRequirements - Category: Floors
Type - Pset_SlabCommon - IsExternal: no
Pset_QuantityTakeOff - Reference: Slab-161:1067; sets with these values: 2
Pset_SlabCommon - LoadBearing: no; PitchAngle: 0 deg; Reference: Slab-161:1067
Group: Model Group:River:478153
Name (Floor:Slab-161:1067:...)
348808
348973
348978
350499
353360

# IfcSlab: Floor:Slab-161:1069 (3)
In: 3D
Type - PredefinedType: FLOOR; Material: Paint-01 1700 mm
Type - Pset_ElementShading - Roughness: 304.8 mm
Type - Pset_ProductRequirements - Category: Floors
Type - Pset_SlabCommon - IsExternal: no
Pset_QuantityTakeOff - Reference: Slab-161:1069; sets with these values: 2
Pset_SlabCommon - LoadBearing: no; PitchAngle: 0 deg; Reference: Slab-161:1069
Group: Model Group:River:478153
Name (Floor:Slab-161:1069:...)
348831
348878
348983

# IfcSlab: Floor:Slab-161:1090 (2)
In: 3D
Type - PredefinedType: FLOOR; Material: Paint-01 9000 mm
Type - Pset_ElementShading - Roughness: 304.8 mm
Type - Pset_ProductRequirements - Category: Floors
Type - Pset_SlabCommon - IsExternal: no
Pset_QuantityTakeOff - Reference: Slab-161:1090; sets with these values: 2
Pset_SlabCommon - LoadBearing: no; PitchAngle: 0 deg; Reference: Slab-161:1090
Group: Model Group:River:478153
Name (Floor:Slab-161:1090:...)
349790
350236

# IfcSlab: Floor:Slab-162 (21)
In: 3D
Type - PredefinedType: FLOOR; Material: Paint-01 2500 mm
Type - Pset_ElementShading - Roughness: 304.8 mm
Type - Pset_ProductRequirements - Category: Floors
Type - Pset_SlabCommon - IsExternal: no
Pset_QuantityTakeOff - Reference: Slab-162; sets with these values: 2
Pset_SlabCommon - LoadBearing: no; PitchAngle: 0 deg; Reference: Slab-162
Group: Model Group:River:478153
Name (Floor:Slab-162:...)
347636
348173
348180
348728
348774
349601
349646
349670
349694
349701
349717
349906
349914
349973
349983
349991
350002
350058
351094
351510
353052

# IfcSlab: Floor:Slab-162:1024 (36)
In: 3D
Type - PredefinedType: FLOOR; Material: Paint-01 6000 mm
Type - Pset_ElementShading - Roughness: 304.8 mm
Type - Pset_ProductRequirements - Category: Floors
Type - Pset_SlabCommon - IsExternal: no
Pset_QuantityTakeOff - Reference: Slab-162:1024; sets with these values: 2
Pset_SlabCommon - LoadBearing: no; PitchAngle: 0 deg; Reference: Slab-162:1024
Group: Model Group:River:478153
Name (Floor:Slab-162:1024:...)
347590
351683
351702
351714
351723
351730
351739
351752
351763
351770
351778
351787
351794
351805
351814
351821
351829
351840
351854
351863
351871
351878
351885
351896
351941
351959
351970
351977
351986
352012
352022
352132
352139
352158
352234
353353

# IfcSlab: Floor:Slab-163 (5)
In: 3D
Type - PredefinedType: FLOOR; Material: Paint-01 7000 mm
Type - Pset_ElementShading - Roughness: 304.8 mm
Type - Pset_ProductRequirements - Category: Floors
Type - Pset_SlabCommon - IsExternal: no
Pset_QuantityTakeOff - Reference: Slab-163; sets with these values: 2
Pset_SlabCommon - LoadBearing: no; PitchAngle: 0 deg; Reference: Slab-163
Group: Model Group:River:478153
Name (Floor:Slab-163:...)
349594
349776
350288
350380
351116

# IfcSlab: Floor:Slab-163:1007 (3)
In: 3D
Type - PredefinedType: FLOOR; Material: Paint-01 42500 mm
Type - Pset_ElementShading - Roughness: 304.8 mm
Type - Pset_ProductRequirements - Category: Floors
Type - Pset_SlabCommon - IsExternal: no
Pset_QuantityTakeOff - Reference: Slab-163:1007; sets with these values: 2
Pset_SlabCommon - LoadBearing: no; PitchAngle: 0 deg; Reference: Slab-163:1007
Group: Model Group:River:478153
Name (Floor:Slab-163:1007:...)
347309
347322
347335

# IfcSlab: Floor:Slab-163:1071 (2)
In: 3D
Type - PredefinedType: FLOOR; Material: Paint-01 1500 mm
Type - Pset_ElementShading - Roughness: 304.8 mm
Type - Pset_ProductRequirements - Category: Floors
Type - Pset_SlabCommon - IsExternal: no
Pset_QuantityTakeOff - Reference: Slab-163:1071; sets with these values: 2
Pset_SlabCommon - LoadBearing: no; PitchAngle: 0 deg; Reference: Slab-163:1071
Group: Model Group:River:478153
Name (Floor:Slab-163:1071:...)
348849
351669

# IfcSlab: Floor:Slab-164 (3)
In: 3D
Type - PredefinedType: FLOOR; Material: Paint-01 16000 mm
Type - Pset_ElementShading - Roughness: 304.8 mm
Type - Pset_ProductRequirements - Category: Floors
Type - Pset_SlabCommon - IsExternal: no
Pset_QuantityTakeOff - Reference: Slab-164; sets with these values: 2
Pset_SlabCommon - LoadBearing: no; PitchAngle: 0 deg; Reference: Slab-164
Group: Model Group:River:478153
Name (Floor:Slab-164:...)
350568
350705
350712

# IfcSlab: Floor:Slab-164:1009 (19)
In: 3D
Type - PredefinedType: FLOOR; Material: Paint-01 600 mm
Type - Pset_ElementShading - Roughness: 304.8 mm
Type - Pset_ProductRequirements - Category: Floors
Type - Pset_SlabCommon - IsExternal: no
Pset_QuantityTakeOff - Reference: Slab-164:1009; sets with these values: 2
Pset_SlabCommon - LoadBearing: no; PitchAngle: 0 deg; Reference: Slab-164:1009
Group: Model Group:River:478153
Name (Floor:Slab-164:1009:...)
347358
348041
349384
349442
349474
350166
351215
351583
352656
352667
352678
352689
352707
352823
353017
353166
353177
353188
353392

# IfcSlab: Floor:Slab-164:1082 (6)
In: 3D
Type - PredefinedType: FLOOR; Material: Paint-01 1050 mm
Type - Pset_ElementShading - Roughness: 304.8 mm
Type - Pset_ProductRequirements - Category: Floors
Type - Pset_SlabCommon - IsExternal: no
Pset_QuantityTakeOff - Reference: Slab-164:1082; sets with these values: 2
Pset_SlabCommon - LoadBearing: no; PitchAngle: 0 deg; Reference: Slab-164:1082
Group: Model Group:River:478153
Name (Floor:Slab-164:1082:...)
349407
349495
351517
351612
352635
353045

# IfcSlab: Floor:Slab-164:1083 (2)
In: 3D
Type - PredefinedType: FLOOR; Material: Paint-01 1350 mm
Type - Pset_ElementShading - Roughness: 304.8 mm
Type - Pset_ProductRequirements - Category: Floors
Type - Pset_SlabCommon - IsExternal: no
Pset_QuantityTakeOff - Reference: Slab-164:1083; sets with these values: 2
Pset_SlabCommon - LoadBearing: no; PitchAngle: 0 deg; Reference: Slab-164:1083
Group: Model Group:River:478153
Name (Floor:Slab-164:1083:...)
349428
349509

# IfcSlab: Floor:Slab-164:1084 (4)
In: 3D
Type - PredefinedType: FLOOR; Material: Paint-01 750 mm
Type - Pset_ElementShading - Roughness: 304.8 mm
Type - Pset_ProductRequirements - Category: Floors
Type - Pset_SlabCommon - IsExternal: no
Pset_QuantityTakeOff - Reference: Slab-164:1084; sets with these values: 2
Pset_SlabCommon - LoadBearing: no; PitchAngle: 0 deg; Reference: Slab-164:1084
Group: Model Group:River:478153
Name (Floor:Slab-164:1084:...)
349435
349481
351175
353003

# IfcSlab: Floor:Slab-166 (14)
In: 3D
Type - PredefinedType: FLOOR; Material: Paint-01 20000 mm
Type - Pset_ElementShading - Roughness: 304.8 mm
Type - Pset_ProductRequirements - Category: Floors
Type - Pset_SlabCommon - IsExternal: no
Pset_QuantityTakeOff - Reference: Slab-166; sets with these values: 2
Pset_SlabCommon - LoadBearing: no; PitchAngle: 0 deg; Reference: Slab-166
Group: Model Group:River:478153
Name (Floor:Slab-166:...)
347295
350932
351952
352165
352180
352192
352214
352225
352243
352265
352274
352281
352288
352316

# IfcSlab: Floor:Slab-167 (4)
In: 3D
Type - PredefinedType: FLOOR; Material: Paint-01 7500 mm
Type - Pset_ElementShading - Roughness: 304.8 mm
Type - Pset_ProductRequirements - Category: Floors
Type - Pset_SlabCommon - IsExternal: no
Pset_QuantityTakeOff - Reference: Slab-167; sets with these values: 2
Pset_SlabCommon - LoadBearing: no; PitchAngle: 0 deg; Reference: Slab-167
Group: Model Group:River:478153
Name (Floor:Slab-167:...)
348701
349809
350782
350818

# IfcSlab: Floor:Slab-167:1001 (13)
In: 3D
Type - PredefinedType: FLOOR; Material: Paint-01 4500 mm
Type - Pset_ElementShading - Roughness: 304.8 mm
Type - Pset_ProductRequirements - Category: Floors
Type - Pset_SlabCommon - IsExternal: no
Pset_QuantityTakeOff - Reference: Slab-167:1001; sets with these values: 2
Pset_SlabCommon - LoadBearing: no; PitchAngle: 0 deg; Reference: Slab-167:1001
Group: Model Group:River:478153
Name (Floor:Slab-167:1001:...)
347272
348062
348266
348949
348990
349769
350173
350555
350759
351626
351644
351662
353127

# IfcSlab: Floor:Slab-167:1002, Floor:Slab-167:1002:347279
In: 3D
Type - PredefinedType: FLOOR; Material: Paint-01 10500 mm
Type - Pset_ElementShading - Roughness: 304.8 mm
Type - Pset_ProductRequirements - Category: Floors
Type - Pset_SlabCommon - IsExternal: no
Pset_QuantityTakeOff - Reference: Slab-167:1002; sets with these values: 2
Pset_SlabCommon - LoadBearing: no; PitchAngle: 0 deg; Reference: Slab-167:1002
Group: Model Group:River:478153

# IfcSlab: Floor:Slab-168 (4)
In: 3D
Type - PredefinedType: FLOOR; Material: Paint-01 8000 mm
Type - Pset_ElementShading - Roughness: 304.8 mm
Type - Pset_ProductRequirements - Category: Floors
Type - Pset_SlabCommon - IsExternal: no
Pset_QuantityTakeOff - Reference: Slab-168; sets with these values: 2
Pset_SlabCommon - LoadBearing: no; PitchAngle: 0 deg; Reference: Slab-168
Group: Model Group:River:478153
Name (Floor:Slab-168:...)
350799
352406
352434
352488

# IfcSlab: Floor:Slab-169 (7)
In: 3D
Type - PredefinedType: FLOOR; Material: Paint-01 350 mm
Type - Pset_ElementShading - Roughness: 304.8 mm
Type - Pset_ProductRequirements - Category: Floors
Type - Pset_SlabCommon - IsExternal: no
Pset_QuantityTakeOff - Reference: Slab-169; sets with these values: 2
Pset_SlabCommon - Reference: Slab-169; LoadBearing: no; PitchAngle: 0 deg
Group: Model Group:River:478153
Name (Floor:Slab-169:...)
351168
352561
353206
353213
353220
353227
353234

# IfcSlab: Floor:Slab-169:1021, Floor:Slab-169:1021:347528
In: 3D
Type - PredefinedType: FLOOR; Material: Paint-01 10450 mm
Type - Pset_ElementShading - Roughness: 304.8 mm
Type - Pset_ProductRequirements - Category: Floors
Type - Pset_SlabCommon - IsExternal: no
Pset_QuantityTakeOff - Reference: Slab-169:1021; sets with these values: 2
Pset_SlabCommon - LoadBearing: no; PitchAngle: 0 deg; Reference: Slab-169:1021
Group: Model Group:River:478153

# IfcSlab: Floor:Slab-169:1023 (8)
In: 3D
Type - PredefinedType: FLOOR; Material: Paint-01 500 mm
Type - Pset_ElementShading - Roughness: 304.8 mm
Type - Pset_ProductRequirements - Category: Floors
Type - Pset_SlabCommon - IsExternal: no
Pset_QuantityTakeOff - Reference: Slab-169:1023; sets with these values: 2
Pset_SlabCommon - LoadBearing: no; PitchAngle: 0 deg; Reference: Slab-169:1023
Group: Model Group:River:478153
Name (Floor:Slab-169:1023:...)
347551
348887
349617
350121
351388
351538
352308
352599

# IfcSlab: Floor:Slab-169:1026 (12)
In: 3D
Type - PredefinedType: FLOOR; Material: Paint-01 5450 mm
Type - Pset_ElementShading - Roughness: 304.8 mm
Type - Pset_ProductRequirements - Category: Floors
Type - Pset_SlabCommon - IsExternal: no
Pset_QuantityTakeOff - Reference: Slab-169:1026; sets with these values: 2
Pset_SlabCommon - LoadBearing: no; PitchAngle: 0 deg; Reference: Slab-169:1026
Group: Model Group:River:478153
Name (Floor:Slab-169:1026:...)
347664
347841
347851
348162
348192
348287
349212
349248
349709
350158
351139
351270

# IfcSlab: Floor:Slab-169:1030 (10)
In: 3D
Type - PredefinedType: FLOOR; Material: Paint-01 1000 mm
Type - Pset_ElementShading - Roughness: 304.8 mm
Type - Pset_ProductRequirements - Category: Floors
Type - Pset_SlabCommon - IsExternal: no
Pset_QuantityTakeOff - Reference: Slab-169:1030; sets with these values: 2
Pset_SlabCommon - LoadBearing: no; PitchAngle: 0 deg; Reference: Slab-169:1030
Group: Model Group:River:478153
Name (Floor:Slab-169:1030:...)
347814
348739
349760
350272
351081
351154
351324
351633
353283
353332

# IfcSlab: Floor:Slab-169:1033 (5)
In: 3D
Type - PredefinedType: FLOOR; Material: Paint-01 5500 mm
Type - Pset_ElementShading - Roughness: 304.8 mm
Type - Pset_ProductRequirements - Category: Floors
Type - Pset_SlabCommon - IsExternal: no
Pset_QuantityTakeOff - Reference: Slab-169:1033; sets with these values: 2
Pset_SlabCommon - LoadBearing: no; PitchAngle: 0 deg; Reference: Slab-169:1033
Group: Model Group:River:478153
Name (Floor:Slab-169:1033:...)
347917
348865
348940
349797
350140

# IfcSlab: Floor:Slab-169:1041 (8)
In: 3D
Type - PredefinedType: FLOOR; Material: Paint-01 4900 mm
Type - Pset_ElementShading - Roughness: 304.8 mm
Type - Pset_ProductRequirements - Category: Floors
Type - Pset_SlabCommon - IsExternal: no
Pset_QuantityTakeOff - Reference: Slab-169:1041; sets with these values: 2
Pset_SlabCommon - LoadBearing: no; PitchAngle: 0 deg; Reference: Slab-169:1041
Group: Model Group:River:478153
Name (Floor:Slab-169:1041:...)
348070
348111
348118
348125
349133
349309
349316
350243

# IfcSlab: Floor:Slab-169:1043 (3)
In: 3D
Type - PredefinedType: FLOOR; Material: Paint-01 2400 mm
Type - Pset_ElementShading - Roughness: 304.8 mm
Type - Pset_ProductRequirements - Category: Floors
Type - Pset_SlabCommon - IsExternal: no
Pset_QuantityTakeOff - Reference: Slab-169:1043; sets with these values: 2
Pset_SlabCommon - LoadBearing: no; PitchAngle: 0 deg; Reference: Slab-169:1043
Group: Model Group:River:478153
Name (Floor:Slab-169:1043:...)
348094
348139
350016

# IfcSlab: Floor:Slab-169:1044 (3)
In: 3D
Type - PredefinedType: FLOOR; Material: Paint-01 700 mm
Type - Pset_ElementShading - Roughness: 304.8 mm
Type - Pset_ProductRequirements - Category: Floors
Type - Pset_SlabCommon - IsExternal: no
Pset_QuantityTakeOff - Reference: Slab-169:1044; sets with these values: 2
Pset_SlabCommon - LoadBearing: no; PitchAngle: 0 deg; Reference: Slab-169:1044
Group: Model Group:River:478153
Name (Floor:Slab-169:1044:...)
348132
348790
352590

# IfcSlab: Floor:Slab-169:1045 (4)
In: 3D
Type - PredefinedType: FLOOR; Material: Paint-01 4850 mm
Type - Pset_ElementShading - Roughness: 304.8 mm
Type - Pset_ProductRequirements - Category: Floors
Type - Pset_SlabCommon - IsExternal: no
Pset_QuantityTakeOff - Reference: Slab-169:1045; sets with these values: 2
Pset_SlabCommon - LoadBearing: no; PitchAngle: 0 deg; Reference: Slab-169:1045
Group: Model Group:River:478153
Name (Floor:Slab-169:1045:...)
348447
350584
350629
351132

# IfcSlab: Floor:Slab-169:1046 (2)
In: 3D
Type - PredefinedType: FLOOR; Material: Paint-01 2350 mm
Type - Pset_ElementShading - Roughness: 304.8 mm
Type - Pset_ProductRequirements - Category: Floors
Type - Pset_SlabCommon - IsExternal: no
Pset_QuantityTakeOff - Reference: Slab-169:1046; sets with these values: 2
Pset_SlabCommon - LoadBearing: no; PitchAngle: 0 deg; Reference: Slab-169:1046
Group: Model Group:River:478153
Name (Floor:Slab-169:1046:...)
348146
351461

# IfcSlab: Floor:Slab-169:1057 (9)
In: 3D
Type - PredefinedType: FLOOR; Material: Paint-01 5550 mm
Type - Pset_ElementShading - Roughness: 304.8 mm
Type - Pset_ProductRequirements - Category: Floors
Type - Pset_SlabCommon - IsExternal: no
Pset_QuantityTakeOff - Reference: Slab-169:1057; sets with these values: 2
Pset_SlabCommon - LoadBearing: no; PitchAngle: 0 deg; Reference: Slab-169:1057
Group: Model Group:River:478153
Name (Floor:Slab-169:1057:...)
348365
349117
349140
349150
349158
349166
349178
349187
349201

# IfcSlab: Floor:Slab-169:1059 (5)
Type - PredefinedType: FLOOR; Material: Paint-01 9900 mm
Type - Pset_ElementShading - Roughness: 304.8 mm
Type - Pset_ProductRequirements - Category: Floors
Type - Pset_SlabCommon - IsExternal: no
Pset_QuantityTakeOff - Reference: Slab-169:1059; sets with these values: 2
Pset_SlabCommon - LoadBearing: no; PitchAngle: 0 deg; Reference: Slab-169:1059
Group: Model Group:River:478153
Name (Floor:Slab-169:1059:...) | In
348397 | 3D
351605 | 3D
353760 | PLAN
354558 | PLAN
354565 | PLAN

# IfcSlab: Floor:Slab-169:1060, Floor:Slab-169:1060:348429
In: 3D
Type - PredefinedType: FLOOR; Material: Paint-01 5560 mm
Type - Pset_ElementShading - Roughness: 304.8 mm
Type - Pset_ProductRequirements - Category: Floors
Type - Pset_SlabCommon - IsExternal: no
Pset_QuantityTakeOff - Reference: Slab-169:1060; sets with these values: 2
Pset_SlabCommon - LoadBearing: no; PitchAngle: 0 deg; Reference: Slab-169:1060
Group: Model Group:River:478153

# IfcSlab: Floor:Slab-169:1062, Floor:Slab-169:1062:348592
In: 3D
Type - PredefinedType: FLOOR; Material: Paint-01 850 mm
Type - Pset_ElementShading - Roughness: 304.8 mm
Type - Pset_ProductRequirements - Category: Floors
Type - Pset_SlabCommon - IsExternal: no
Pset_QuantityTakeOff - Reference: Slab-169:1062; sets with these values: 2
Pset_SlabCommon - LoadBearing: no; PitchAngle: 0 deg; Reference: Slab-169:1062
Group: Model Group:River:478153

# IfcSlab: Floor:Slab-169:1063, Floor:Slab-169:1063:348616
In: 3D
Type - PredefinedType: FLOOR; Material: Paint-01 1850 mm
Type - Pset_ElementShading - Roughness: 304.8 mm
Type - Pset_ProductRequirements - Category: Floors
Type - Pset_SlabCommon - IsExternal: no
Pset_QuantityTakeOff - Reference: Slab-169:1063; sets with these values: 2
Pset_SlabCommon - LoadBearing: no; PitchAngle: 0 deg; Reference: Slab-169:1063
Group: Model Group:River:478153

# IfcSlab: Floor:Slab-169:1065 (2)
In: 3D
Type - PredefinedType: FLOOR; Material: Paint-01 5400 mm
Type - Pset_ElementShading - Roughness: 304.8 mm
Type - Pset_ProductRequirements - Category: Floors
Type - Pset_SlabCommon - IsExternal: no
Pset_QuantityTakeOff - Reference: Slab-169:1065; sets with these values: 2
Pset_SlabCommon - LoadBearing: no; PitchAngle: 0 deg; Reference: Slab-169:1065
Group: Model Group:River:478153
Name (Floor:Slab-169:1065:...)
348708
352554

# IfcSlab: Floor:Slab-169:1070, Floor:Slab-169:1070:348838
In: 3D
Type - PredefinedType: FLOOR; Material: Paint-01 1100 mm
Type - Pset_ElementShading - Roughness: 304.8 mm
Type - Pset_ProductRequirements - Category: Floors
Type - Pset_SlabCommon - IsExternal: no
Pset_QuantityTakeOff - Reference: Slab-169:1070; sets with these values: 2
Pset_SlabCommon - LoadBearing: no; PitchAngle: 0 deg; Reference: Slab-169:1070
Group: Model Group:River:478153

# IfcSlab: Floor:Slab-169:1074 (2)
In: 3D
Type - PredefinedType: FLOOR; Material: Paint-01 270 mm
Type - Pset_ElementShading - Roughness: 304.8 mm
Type - Pset_ProductRequirements - Category: Floors
Type - Pset_SlabCommon - IsExternal: no
Pset_QuantityTakeOff - Reference: Slab-169:1074; sets with these values: 2
Pset_SlabCommon - LoadBearing: no; PitchAngle: 0 deg; Reference: Slab-169:1074
Group: Model Group:River:478153
Name (Floor:Slab-169:1074:...)
349059
349101

# IfcSlab: Floor:Slab-169:1076, Floor:Slab-169:1076:349073
In: 3D
Type - PredefinedType: FLOOR; Material: Paint-01 650 mm
Type - Pset_ElementShading - Roughness: 304.8 mm
Type - Pset_ProductRequirements - Category: Floors
Type - Pset_SlabCommon - IsExternal: no
Pset_QuantityTakeOff - Reference: Slab-169:1076; sets with these values: 2
Pset_SlabCommon - LoadBearing: no; PitchAngle: 0 deg; Reference: Slab-169:1076
Group: Model Group:River:478153

# IfcSlab: Floor:Slab-169:1077, Floor:Slab-169:1077:349087
In: 3D
Type - PredefinedType: FLOOR; Material: Paint-01 950 mm
Type - Pset_ElementShading - Roughness: 304.8 mm
Type - Pset_ProductRequirements - Category: Floors
Type - Pset_SlabCommon - IsExternal: no
Pset_QuantityTakeOff - Reference: Slab-169:1077; sets with these values: 2
Pset_SlabCommon - LoadBearing: no; PitchAngle: 0 deg; Reference: Slab-169:1077
Group: Model Group:River:478153

# IfcSlab: Floor:Slab-169:1078 (6)
In: 3D
Type - PredefinedType: FLOOR; Material: Paint-01 800 mm
Type - Pset_ElementShading - Roughness: 304.8 mm
Type - Pset_ProductRequirements - Category: Floors
Type - Pset_SlabCommon - IsExternal: no
Pset_QuantityTakeOff - Reference: Slab-169:1078; sets with these values: 2
Pset_SlabCommon - LoadBearing: no; PitchAngle: 0 deg; Reference: Slab-169:1078
Group: Model Group:River:478153
Name (Floor:Slab-169:1078:...)
349094
351545
351553
351560
351568
351576

# IfcSlab: Floor:Slab-169:1100, Floor:Slab-169:1100:351045
In: 3D
Type - PredefinedType: FLOOR; Material: Paint-01 4300 mm
Type - Pset_ElementShading - Roughness: 304.8 mm
Type - Pset_ProductRequirements - Category: Floors
Type - Pset_SlabCommon - IsExternal: no
Pset_QuantityTakeOff - Reference: Slab-169:1100; sets with these values: 2
Pset_SlabCommon - LoadBearing: no; PitchAngle: 0 deg; Reference: Slab-169:1100
Group: Model Group:River:478153

# IfcSlab: Floor:Slab-170 (2)
In: 3D
Type - PredefinedType: FLOOR; Material: Paint-01 440 mm
Type - Pset_ElementShading - Roughness: 304.8 mm
Type - Pset_ProductRequirements - Category: Floors
Type - Pset_SlabCommon - IsExternal: no
Pset_QuantityTakeOff - Reference: Slab-170; sets with these values: 2
Pset_SlabCommon - LoadBearing: no; PitchAngle: 0 deg; Reference: Slab-170
Group: Model Group:River:478153
Name (Floor:Slab-170:...)
349066
349080

# IfcSlab: Floor:Slab-170:1048 (3)
In: 3D
Type - PredefinedType: FLOOR; Material: Paint-01 7350 mm
Type - Pset_ElementShading - Roughness: 304.8 mm
Type - Pset_ProductRequirements - Category: Floors
Type - Pset_SlabCommon - IsExternal: no
Pset_QuantityTakeOff - Reference: Slab-170:1048; sets with these values: 2
Pset_SlabCommon - LoadBearing: no; PitchAngle: 0 deg; Reference: Slab-170:1048
Group: Model Group:River:478153
Name (Floor:Slab-170:1048:...)
348199
353139
353146

# IfcSlab: Floor:Slab-171, Floor:Slab-171:353346
In: 3D
Type - PredefinedType: FLOOR; Material: Paint-01 6150 mm
Type - Pset_ElementShading - Roughness: 304.8 mm
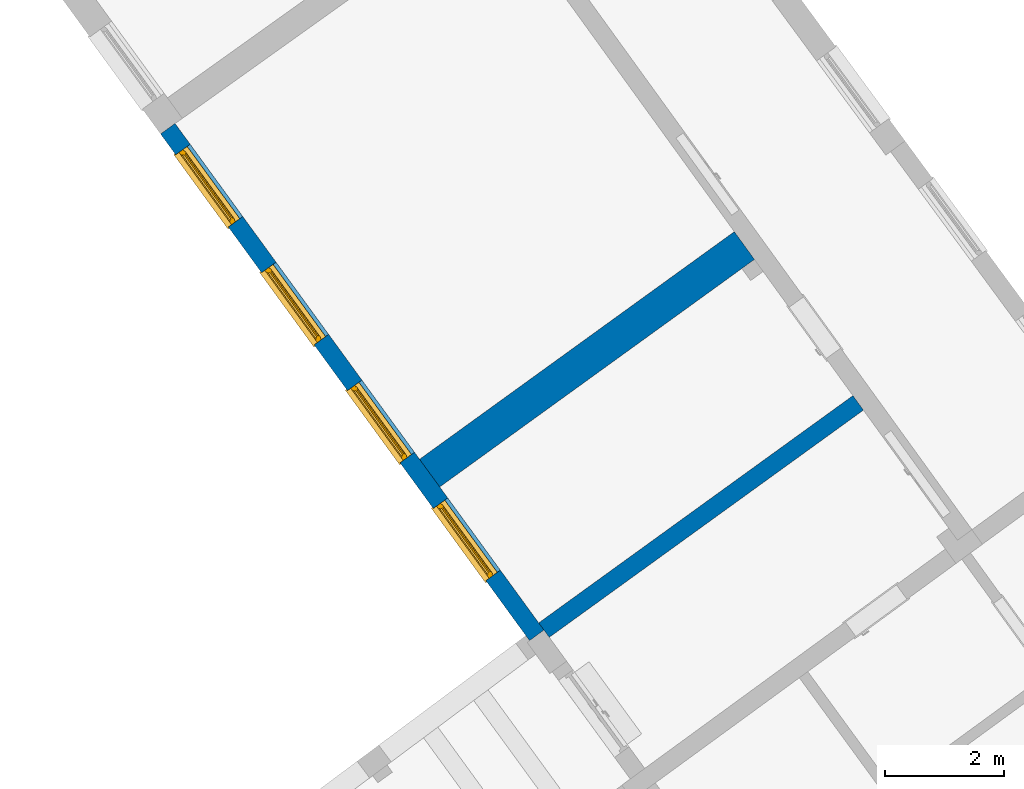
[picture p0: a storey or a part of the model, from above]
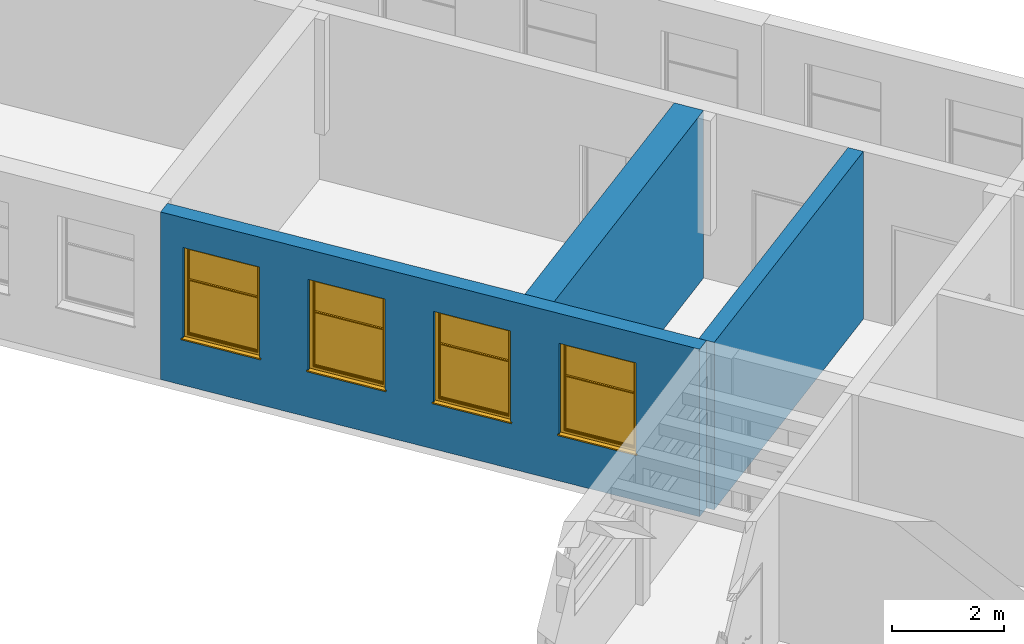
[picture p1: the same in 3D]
Properties of the parts of a building model (IFC2X3), part 7 of 13

# IfcSlab: Floor:Slab-171, Floor:Slab-171:353346
Type - Pset_ProductRequirements - Category: Floors
Type - Pset_SlabCommon - IsExternal: no
Pset_QuantityTakeOff - Reference: Slab-171; sets with these values: 2
Pset_SlabCommon - LoadBearing: no; PitchAngle: 0 deg; Reference: Slab-171
Group: Model Group:River:478153

# IfcSlab: Floor:Slab-171:1014 (4)
In: 3D
Type - PredefinedType: FLOOR; Material: Paint-01 1600 mm
Type - Pset_ElementShading - Roughness: 304.8 mm
Type - Pset_ProductRequirements - Category: Floors
Type - Pset_SlabCommon - IsExternal: no
Pset_QuantityTakeOff - Reference: Slab-171:1014; sets with these values: 2
Pset_SlabCommon - LoadBearing: no; PitchAngle: 0 deg; Reference: Slab-171:1014
Group: Model Group:River:478153
Name (Floor:Slab-171:1014:...)
347417
351447
352981
352989

# IfcSlab: Floor:Slab-171:1108 (2)
In: 3D
Type - PredefinedType: FLOOR; Material: Paint-01 300 mm
Type - Pset_ElementShading - Roughness: 304.8 mm
Type - Pset_ProductRequirements - Category: Floors
Type - Pset_SlabCommon - IsExternal: no
Pset_QuantityTakeOff - Reference: Slab-171:1108; sets with these values: 2
Pset_SlabCommon - LoadBearing: no; PitchAngle: 0 deg; Reference: Slab-171:1108
Group: Model Group:River:478153
Name (Floor:Slab-171:1108:...)
351279
353024

# IfcSlab: Floor:Slab-171:1366 (2)
In: 3D
Type - PredefinedType: FLOOR; Material: Paint-01 5900 mm
Type - Pset_ElementShading - Roughness: 304.8 mm
Type - Pset_ProductRequirements - Category: Floors
Type - Pset_SlabCommon - IsExternal: no
Pset_QuantityTakeOff - Reference: Slab-171:1366; sets with these values: 2
Pset_SlabCommon - LoadBearing: no; PitchAngle: 0 deg; Reference: Slab-171:1366
Group: Model Group:River:478153
Name (Floor:Slab-171:1366:...)
353276
353325

# IfcSlab: Floor:Slab-172 (9)
In: 3D
Type - PredefinedType: FLOOR; Material: Paint-01 5600 mm
Type - Pset_ElementShading - Roughness: 304.8 mm
Type - Pset_ProductRequirements - Category: Floors
Type - Pset_SlabCommon - IsExternal: no
Pset_QuantityTakeOff - Reference: Slab-172; sets with these values: 2
Pset_SlabCommon - Reference: Slab-172; LoadBearing: no; PitchAngle: 0 deg
Group: Model Group:River:478153
Name (Floor:Slab-172:...)
348351
348358
349624
349631
349639
349724
349742
349753
353112

# IfcSlab: Floor:Slab-172:1038 (21)
In: 3D
Type - PredefinedType: FLOOR; Material: Paint-01 15000 mm
Type - Pset_ElementShading - Roughness: 304.8 mm
Type - Pset_ProductRequirements - Category: Floors
Type - Pset_SlabCommon - IsExternal: no
Pset_QuantityTakeOff - Reference: Slab-172:1038; sets with these values: 2
Pset_SlabCommon - LoadBearing: no; PitchAngle: 0 deg; Reference: Slab-172:1038
Group: Model Group:River:478153
Name (Floor:Slab-172:1038:...)
348001
348011
348077
350900
350920
350960
350994
351005
351013
351370
351380
351424
352323
352330
352337
352353
352360
352392
352477
352535
352547

# IfcSlab: Floor:Slab-173 (3)
In: 3D
Type - PredefinedType: FLOOR; Material: Paint-01 2550 mm
Type - Pset_ElementShading - Roughness: 304.8 mm
Type - Pset_ProductRequirements - Category: Floors
Type - Pset_SlabCommon - IsExternal: no
Pset_QuantityTakeOff - Reference: Slab-173; sets with these values: 2
Pset_SlabCommon - LoadBearing: no; PitchAngle: 0 deg; Reference: Slab-173
Group: Model Group:River:478153
Name (Floor:Slab-173:...)
348210
348245
349783

# IfcSlab: Floor:Slab-174, Floor:Slab-174:348085
In: 3D
Type - PredefinedType: FLOOR; Material: Paint-01 18000 mm
Type - Pset_ElementShading - Roughness: 304.8 mm
Type - Pset_ProductRequirements - Category: Floors
Type - Pset_SlabCommon - IsExternal: no
Pset_QuantityTakeOff - Reference: Slab-174; sets with these values: 2
Pset_SlabCommon - LoadBearing: no; PitchAngle: 0 deg; Reference: Slab-174
Group: Model Group:River:478153

# IfcSlab: Floor:Slab-175, Floor:Slab-175:353290
In: 3D
Type - PredefinedType: FLOOR; Material: Paint-01 7600 mm
Type - Pset_ElementShading - Roughness: 304.8 mm
Type - Pset_ProductRequirements - Category: Floors
Type - Pset_SlabCommon - IsExternal: no
Pset_QuantityTakeOff - Reference: Slab-175; sets with these values: 2
Pset_SlabCommon - LoadBearing: no; PitchAngle: 0 deg; Reference: Slab-175
Group: Model Group:River:478153

# IfcSlab: Floor:Slab-175:1051, Floor:Slab-175:1051:348252
In: 3D
Type - PredefinedType: FLOOR; Material: Paint-01 7400 mm
Type - Pset_ElementShading - Roughness: 304.8 mm
Type - Pset_ProductRequirements - Category: Floors
Type - Pset_SlabCommon - IsExternal: no
Pset_QuantityTakeOff - Reference: Slab-175:1051; sets with these values: 2
Pset_SlabCommon - LoadBearing: no; PitchAngle: 0 deg; Reference: Slab-175:1051
Group: Model Group:River:478153

# IfcSlab: Floor:Slab-175:1120, Floor:Slab-175:1120:351619
In: 3D
Type - PredefinedType: FLOOR; Material: Paint-01 3600 mm
Type - Pset_ElementShading - Roughness: 304.8 mm
Type - Pset_ProductRequirements - Category: Floors
Type - Pset_SlabCommon - IsExternal: no
Pset_QuantityTakeOff - Reference: Slab-175:1120; sets with these values: 2
Pset_SlabCommon - LoadBearing: no; PitchAngle: 0 deg; Reference: Slab-175:1120
Group: Model Group:River:478153

# IfcSlab: Floor:Slab-175:1346 (4)
In: 3D
Type - PredefinedType: FLOOR; Material: Paint-01 1150 mm
Type - Pset_ElementShading - Roughness: 304.8 mm
Type - Pset_ProductRequirements - Category: Floors
Type - Pset_SlabCommon - IsExternal: no
Pset_QuantityTakeOff - Reference: Slab-175:1346; sets with these values: 2
Pset_SlabCommon - LoadBearing: no; PitchAngle: 0 deg; Reference: Slab-175:1346
Group: Model Group:River:478153
Name (Floor:Slab-175:1346:...)
352642
352649
353269
353339

# IfcSlab: Floor:Slab-175:1353, Floor:Slab-175:1353:353105
In: 3D
Type - PredefinedType: FLOOR; Material: Paint-01 3750 mm
Type - Pset_ElementShading - Roughness: 304.8 mm
Type - Pset_ProductRequirements - Category: Floors
Type - Pset_SlabCommon - IsExternal: no
Pset_QuantityTakeOff - Reference: Slab-175:1353; sets with these values: 2
Pset_SlabCommon - LoadBearing: no; PitchAngle: 0 deg; Reference: Slab-175:1353
Group: Model Group:River:478153

# IfcSlab: Floor:Slab-175:1365, Floor:Slab-175:1365:353199
In: 3D
Type - PredefinedType: FLOOR; Material: Paint-01 2250 mm
Type - Pset_ElementShading - Roughness: 304.8 mm
Type - Pset_ProductRequirements - Category: Floors
Type - Pset_SlabCommon - IsExternal: no
Pset_QuantityTakeOff - Reference: Slab-175:1365; sets with these values: 2
Pset_SlabCommon - LoadBearing: no; PitchAngle: 0 deg; Reference: Slab-175:1365
Group: Model Group:River:478153

# IfcSlab: Floor:Slab-176, Floor:Slab-176:353066
In: 3D
Type - PredefinedType: FLOOR; Material: Paint-01 3800 mm
Type - Pset_ElementShading - Roughness: 304.8 mm
Type - Pset_ProductRequirements - Category: Floors
Type - Pset_SlabCommon - IsExternal: no
Pset_QuantityTakeOff - Reference: Slab-176; sets with these values: 2
Pset_SlabCommon - LoadBearing: no; PitchAngle: 0 deg; Reference: Slab-176
Group: Model Group:River:478153

# IfcSlab: Floor:Slab-176:1005 (25)
In: 3D
Type - PredefinedType: FLOOR; Material: Paint-01 150 mm
Type - Pset_ElementShading - Roughness: 304.8 mm
Type - Pset_ProductRequirements - Category: Floors
Type - Pset_SlabCommon - IsExternal: no
Pset_QuantityTakeOff - Reference: Slab-176:1005; sets with these values: 2
Pset_SlabCommon - LoadBearing: no; PitchAngle: 0 deg; Reference: Slab-176:1005
Group: Model Group:River:478153
Name (Floor:Slab-176:1005:...)
347302
347439
347446
347453
347474
347488
347537
347544
347629
347643
348055
349360
349400
349414
350009
351302
351417
351433
351496
351503
352568
353031
353073
353080
353120

# IfcSlab: Floor:Slab-176:1012, Floor:Slab-176:1012:347392
In: 3D
Type - PredefinedType: FLOOR; Material: Paint-01 1400 mm
Type - Pset_ElementShading - Roughness: 304.8 mm
Type - Pset_ProductRequirements - Category: Floors
Type - Pset_SlabCommon - IsExternal: no
Pset_QuantityTakeOff - Reference: Slab-176:1012; sets with these values: 2
Pset_SlabCommon - LoadBearing: no; PitchAngle: 0 deg; Reference: Slab-176:1012
Group: Model Group:River:478153

# IfcSlab: Floor:Slab-176:1013 (10)
In: 3D
Type - PredefinedType: FLOOR; Material: Paint-01 50 mm
Type - Pset_ElementShading - Roughness: 304.8 mm
Type - Pset_ProductRequirements - Category: Floors
Type - Pset_SlabCommon - IsExternal: no
Pset_QuantityTakeOff - Reference: Slab-176:1013; sets with these values: 2
Pset_SlabCommon - LoadBearing: no; PitchAngle: 0 deg; Reference: Slab-176:1013
Group: Model Group:River:478153
Name (Floor:Slab-176:1013:...)
347399
347460
347467
347902
347912
348023
348723
350665
350676
352967

# IfcSlab: Floor:Slab-176:1017 (2)
In: 3D
Type - PredefinedType: FLOOR; Material: Surf-Poured Concrete 950 mm
Type - Pset_ElementShading - Roughness: 304.8 mm
Type - Pset_ProductRequirements - Category: Floors
Type - Pset_SlabCommon - IsExternal: no
Pset_QuantityTakeOff - Reference: Slab-176:1017; sets with these values: 2
Pset_SlabCommon - LoadBearing: no; PitchAngle: 0 deg; Reference: Slab-176:1017
Group: Model Group:River:478153
Name (Floor:Slab-176:1017:...)
347481
351531

# IfcSlab: Floor:Slab-176:1031 (8)
In: 3D
Type - PredefinedType: FLOOR; Material: Paint-01 1200 mm
Type - Pset_ElementShading - Roughness: 304.8 mm
Type - Pset_ProductRequirements - Category: Floors
Type - Pset_SlabCommon - IsExternal: no
Pset_QuantityTakeOff - Reference: Slab-176:1031; sets with these values: 2
Pset_SlabCommon - LoadBearing: no; PitchAngle: 0 deg; Reference: Slab-176:1031
Group: Model Group:River:478153
Name (Floor:Slab-176:1031:...)
347870
349421
349502
350548
351363
351397
351695
353010

# IfcSlab: Floor:Slab-176:1052, Floor:Slab-176:1052:348259
In: 3D
Type - PredefinedType: FLOOR; Material: Paint-01 2600 mm
Type - Pset_ElementShading - Roughness: 304.8 mm
Type - Pset_ProductRequirements - Category: Floors
Type - Pset_SlabCommon - IsExternal: no
Pset_QuantityTakeOff - Reference: Slab-176:1052; sets with these values: 2
Pset_SlabCommon - LoadBearing: no; PitchAngle: 0 deg; Reference: Slab-176:1052
Group: Model Group:River:478153

# IfcSlab: Floor:Slab-176:1058, Floor:Slab-176:1058:348382
In: 3D
Type - PredefinedType: FLOOR; Material: Paint-01 9500 mm
Type - Pset_ElementShading - Roughness: 304.8 mm
Type - Pset_ProductRequirements - Category: Floors
Type - Pset_SlabCommon - IsExternal: no
Pset_QuantityTakeOff - Reference: Slab-176:1058; sets with these values: 2
Pset_SlabCommon - LoadBearing: no; PitchAngle: 0 deg; Reference: Slab-176:1058
Group: Model Group:River:478153

# IfcSlab: Floor:Slab-176:1061, Floor:Slab-176:1061:348438
In: 3D
Type - PredefinedType: FLOOR; Material: Paint-01 5200 mm
Type - Pset_ElementShading - Roughness: 304.8 mm
Type - Pset_ProductRequirements - Category: Floors
Type - Pset_SlabCommon - IsExternal: no
Pset_QuantityTakeOff - Reference: Slab-176:1061; sets with these values: 2
Pset_SlabCommon - LoadBearing: no; PitchAngle: 0 deg; Reference: Slab-176:1061
Group: Model Group:River:478153

# IfcSlab: Floor:Slab-176:1091, Floor:Slab-176:1091:349848
In: 3D
Type - PredefinedType: FLOOR; Material: Paint-01 200 mm
Type - Pset_ElementShading - Roughness: 304.8 mm
Type - Pset_ProductRequirements - Category: Floors
Type - Pset_SlabCommon - IsExternal: no
Pset_QuantityTakeOff - Reference: Slab-176:1091; sets with these values: 2
Pset_SlabCommon - LoadBearing: no; PitchAngle: 0 deg; Reference: Slab-176:1091
Group: Model Group:River:478153

# IfcSlab: Floor:Slab-176:1112 (4)
In: 3D
Type - PredefinedType: FLOOR; Material: Paint-01 160 mm
Type - Pset_ElementShading - Roughness: 304.8 mm
Type - Pset_ProductRequirements - Category: Floors
Type - Pset_SlabCommon - IsExternal: no
Pset_QuantityTakeOff - Reference: Slab-176:1112; sets with these values: 2
Pset_SlabCommon - LoadBearing: no; PitchAngle: 0 deg; Reference: Slab-176:1112
Group: Model Group:River:478153
Name (Floor:Slab-176:1112:...)
351440
351489
352960
352974

# IfcSlab: Floor:Slab-176:1117 (2)
In: 3D
Type - PredefinedType: FLOOR; Material: Paint-01 30 mm
Type - Pset_ElementShading - Roughness: 304.8 mm
Type - Pset_ProductRequirements - Category: Floors
Type - Pset_SlabCommon - IsExternal: no
Pset_QuantityTakeOff - Reference: Slab-176:1117; sets with these values: 2
Pset_SlabCommon - LoadBearing: no; PitchAngle: 0 deg; Reference: Slab-176:1117
Group: Model Group:River:478153
Name (Floor:Slab-176:1117:...)
351524
351676

# IfcSlab: Floor:Slab-176:1339, Floor:Slab-176:1339:352618
In: 3D
Type - PredefinedType: FLOOR; Material: Paint-01 8500 mm
Type - Pset_ElementShading - Roughness: 304.8 mm
Type - Pset_ProductRequirements - Category: Floors
Type - Pset_SlabCommon - IsExternal: no
Pset_QuantityTakeOff - Reference: Slab-176:1339; sets with these values: 2
Pset_SlabCommon - LoadBearing: no; PitchAngle: 0 deg; Reference: Slab-176:1339
Group: Model Group:River:478153

# IfcSlab: Floor:Slab-176:1350, Floor:Slab-176:1350:352996
In: 3D
Type - PredefinedType: FLOOR; Material: Paint-01 4100 mm
Type - Pset_ElementShading - Roughness: 304.8 mm
Type - Pset_ProductRequirements - Category: Floors
Type - Pset_SlabCommon - IsExternal: no
Pset_QuantityTakeOff - Reference: Slab-176:1350; sets with these values: 2
Pset_SlabCommon - LoadBearing: no; PitchAngle: 0 deg; Reference: Slab-176:1350
Group: Model Group:River:478153

# IfcSlab: Floor:Slab-176:1351, Floor:Slab-176:1351:353059
In: 3D
Type - PredefinedType: FLOOR; Material: Paint-01 450 mm
Type - Pset_ElementShading - Roughness: 304.8 mm
Type - Pset_ProductRequirements - Category: Floors
Type - Pset_SlabCommon - IsExternal: no
Pset_QuantityTakeOff - Reference: Slab-176:1351; sets with these values: 2
Pset_SlabCommon - LoadBearing: no; PitchAngle: 0 deg; Reference: Slab-176:1351
Group: Model Group:River:478153

# IfcSlab: Floor:Slab-177, Floor:Slab-177:351475
In: 3D
Type - PredefinedType: FLOOR; Material: Paint-01 2200 mm
Type - Pset_ElementShading - Roughness: 304.8 mm
Type - Pset_ProductRequirements - Category: Floors
Type - Pset_SlabCommon - IsExternal: no
Pset_QuantityTakeOff - Reference: Slab-177; sets with these values: 2
Pset_SlabCommon - LoadBearing: no; PitchAngle: 0 deg; Reference: Slab-177
Group: Model Group:River:478153

# IfcSlab: Floor:Slab-177:1047 (42)
In: 3D
Type - PredefinedType: FLOOR; Material: Paint-01 100 mm
Type - Pset_ElementShading - Roughness: 304.8 mm
Type - Pset_ProductRequirements - Category: Floors
Type - Pset_SlabCommon - IsExternal: no
Pset_QuantityTakeOff - Reference: Slab-177:1047; sets with these values: 2
Pset_SlabCommon - LoadBearing: no; PitchAngle: 0 deg; Reference: Slab-177:1047
Group: Model Group:River:478153
Name (Floor:Slab-177:1047:...)
348187
348611
348660
348685
352700
352718
352725
352732
352739
352746
352753
352760
352767
352774
352781
352788
352795
352802
352809
352816
352834
352841
352848
352855
352862
352869
352876
352883
352890
352897
352904
352911
352918
352925
352932
352939
352946
352953
353297
353304
353311
353318

# IfcSlab: Floor:Slab-177:1050 (11)
In: 3D
Type - PredefinedType: FLOOR; Material: Paint-01 3450 mm
Type - Pset_ElementShading - Roughness: 304.8 mm
Type - Pset_ProductRequirements - Category: Floors
Type - Pset_SlabCommon - IsExternal: no
Pset_QuantityTakeOff - Reference: Slab-177:1050; sets with these values: 2
Pset_SlabCommon - LoadBearing: no; PitchAngle: 0 deg; Reference: Slab-177:1050
Group: Model Group:River:478153
Name (Floor:Slab-177:1050:...)
348217
348904
350264
350333
350362
350393
350402
350450
350467
351056
351316

# IfcSlab: Floor:Slab-178, Floor:Slab-178:351482
In: 3D
Type - PredefinedType: FLOOR; Material: Paint-01 2050 mm
Type - Pset_ElementShading - Roughness: 304.8 mm
Type - Pset_ProductRequirements - Category: Floors
Type - Pset_SlabCommon - IsExternal: no
Pset_QuantityTakeOff - Reference: Slab-178; sets with these values: 2
Pset_SlabCommon - LoadBearing: no; PitchAngle: 0 deg; Reference: Slab-178
Group: Model Group:River:478153

# IfcSlab: Floor:Slab-178:1068 (4)
In: 3D
Type - PredefinedType: FLOOR; Material: Paint-01 3950 mm
Type - Pset_ElementShading - Roughness: 304.8 mm
Type - Pset_ProductRequirements - Category: Floors
Type - Pset_SlabCommon - IsExternal: no
Pset_QuantityTakeOff - Reference: Slab-178:1068; sets with these values: 2
Pset_SlabCommon - LoadBearing: no; PitchAngle: 0 deg; Reference: Slab-178:1068
Group: Model Group:River:478153
Name (Floor:Slab-178:1068:...)
348815
349376
350316
352575

# IfcSlab: Floor:Slab-179, Floor:Slab-179:351454
In: 3D
Type - PredefinedType: FLOOR; Material: Paint-01 1900 mm
Type - Pset_ElementShading - Roughness: 304.8 mm
Type - Pset_ProductRequirements - Category: Floors
Type - Pset_SlabCommon - IsExternal: no
Pset_QuantityTakeOff - Reference: Slab-179; sets with these values: 2
Pset_SlabCommon - LoadBearing: no; PitchAngle: 0 deg; Reference: Slab-179
Group: Model Group:River:478153

# IfcSlab: Floor:Slab-179:1000 (17048)
Type - PredefinedType: FLOOR; Material: Paint-01 20 mm
Type - Pset_ElementShading - Roughness: 304.8 mm
Type - Pset_ProductRequirements - Category: Floors
Type - Pset_SlabCommon - IsExternal: no
Pset_QuantityTakeOff - Reference: Slab-179:1000; sets with these values: 2
Pset_SlabCommon - Reference: Slab-179:1000; LoadBearing: no; PitchAngle: 0 deg
Group: Model Group:River:478153
Name (Floor:Slab-179:1000:...) | In
347258 | -1. Story
347265 | -1. Story
353371 | PLAN
353378 | PLAN
353385 | PLAN
353403 | PLAN
353410 | PLAN
353417 | PLAN
353424 | PLAN
353431 | PLAN
353438 | PLAN
353445 | PLAN
353452 | PLAN
353459 | PLAN
353466 | PLAN
353473 | PLAN
353480 | PLAN
353487 | PLAN
353494 | PLAN
353501 | PLAN
353508 | PLAN
353515 | PLAN
353522 | PLAN
353529 | PLAN
353536 | PLAN
353543 | PLAN
353550 | PLAN
353557 | PLAN
353564 | PLAN
353571 | PLAN
353578 | PLAN
353585 | PLAN
353592 | PLAN
353599 | PLAN
353606 | PLAN
353613 | PLAN
353620 | PLAN
353627 | PLAN
353634 | PLAN
353641 | PLAN
353648 | PLAN
353655 | PLAN
353662 | PLAN
353669 | PLAN
353676 | PLAN
353683 | PLAN
353690 | PLAN
353697 | PLAN
353704 | PLAN
353711 | PLAN
353718 | PLAN
353725 | PLAN
353732 | PLAN
353739 | PLAN
353746 | PLAN
353753 | PLAN
353767 | PLAN
353774 | PLAN
353781 | PLAN
353788 | PLAN
353795 | PLAN
353802 | PLAN
353809 | PLAN
353816 | PLAN
353823 | PLAN
353830 | PLAN
353837 | PLAN
353844 | PLAN
353851 | PLAN
353858 | PLAN
353865 | PLAN
353872 | PLAN
353879 | PLAN
353886 | PLAN
353893 | PLAN
353900 | PLAN
353907 | PLAN
353914 | PLAN
353921 | PLAN
353928 | PLAN
353935 | PLAN
353942 | PLAN
353949 | PLAN
353956 | PLAN
353963 | PLAN
353970 | PLAN
353977 | PLAN
353984 | PLAN
353991 | PLAN
353998 | PLAN
354005 | PLAN
354012 | PLAN
354019 | PLAN
354026 | PLAN
354033 | PLAN
354040 | PLAN
354047 | PLAN
354054 | PLAN
354061 | PLAN
354068 | PLAN
354075 | PLAN
354082 | PLAN
354089 | PLAN
354096 | PLAN
354103 | PLAN
354110 | PLAN
354117 | PLAN
354124 | PLAN
354131 | PLAN
354138 | PLAN
354145 | PLAN
354152 | PLAN
354159 | PLAN
354166 | PLAN
354173 | PLAN
354180 | PLAN
354187 | PLAN
354194 | PLAN
354201 | PLAN
354208 | PLAN
354215 | PLAN
354222 | PLAN
354229 | PLAN
354236 | PLAN
354243 | PLAN
354250 | PLAN
354257 | PLAN
354264 | PLAN
354271 | PLAN
354278 | PLAN
354285 | PLAN
354292 | PLAN
354299 | PLAN
354306 | PLAN
354313 | PLAN
354320 | PLAN
354327 | PLAN
354334 | PLAN
354341 | PLAN
354348 | PLAN
354355 | PLAN
354362 | PLAN
354369 | PLAN
354376 | PLAN
354383 | PLAN
354390 | PLAN
354397 | PLAN
354404 | PLAN
354411 | PLAN
354418 | PLAN
354425 | PLAN
354432 | PLAN
354439 | PLAN
354446 | PLAN
354453 | PLAN
354460 | PLAN
354467 | PLAN
354474 | PLAN
354481 | PLAN
354488 | PLAN
354495 | PLAN
354502 | PLAN
354509 | PLAN
354516 | PLAN
354523 | PLAN
354530 | PLAN
354537 | PLAN
354544 | PLAN
354551 | PLAN
354572 | PLAN
354579 | PLAN
354586 | PLAN
354593 | PLAN
354600 | PLAN
354607 | PLAN
354614 | PLAN
354621 | PLAN
354628 | PLAN
354635 | PLAN
354642 | PLAN
354649 | PLAN
354656 | PLAN
354663 | PLAN
354670 | PLAN
354677 | PLAN
354684 | PLAN
354691 | PLAN
354698 | PLAN
354705 | PLAN
354712 | PLAN
354719 | PLAN
354726 | PLAN
354733 | PLAN
354740 | PLAN
354747 | PLAN
354754 | PLAN
354761 | PLAN
354768 | PLAN
354775 | PLAN
354782 | PLAN
354789 | PLAN
354796 | PLAN
354803 | PLAN
354810 | PLAN
354817 | PLAN
354824 | PLAN
354831 | PLAN
354838 | PLAN
354845 | PLAN
354852 | PLAN
354859 | PLAN
354866 | PLAN
354873 | PLAN
354880 | PLAN
354887 | PLAN
354894 | PLAN
354901 | PLAN
354908 | PLAN
354915 | PLAN
354922 | PLAN
354929 | PLAN
354936 | PLAN
354943 | PLAN
354950 | PLAN
354957 | PLAN
354964 | PLAN
354971 | PLAN
354978 | PLAN
354985 | PLAN
354992 | PLAN
354999 | PLAN
355006 | PLAN
355013 | PLAN
355020 | PLAN
355027 | PLAN
355034 | PLAN
355041 | PLAN
355048 | PLAN
355055 | PLAN
355062 | PLAN
355069 | PLAN
355076 | PLAN
355083 | PLAN
355090 | PLAN
355097 | PLAN
355104 | PLAN
355111 | PLAN
355118 | PLAN
355125 | PLAN
355132 | PLAN
355139 | PLAN
355146 | PLAN
355153 | PLAN
355160 | PLAN
355167 | PLAN
355174 | PLAN
355181 | PLAN
355188 | PLAN
355195 | PLAN
355202 | PLAN
355209 | PLAN
355216 | PLAN
355223 | PLAN
355230 | PLAN
355237 | PLAN
355244 | PLAN
355251 | PLAN
355258 | PLAN
355265 | PLAN
355272 | PLAN
355279 | PLAN
355286 | PLAN
355293 | PLAN
355300 | PLAN
355307 | PLAN
355314 | PLAN
355321 | PLAN
355328 | PLAN
355335 | PLAN
355342 | PLAN
355349 | PLAN
355356 | PLAN
355363 | PLAN
355370 | PLAN
355377 | PLAN
355384 | PLAN
355391 | PLAN
355398 | PLAN
355405 | PLAN
355412 | PLAN
355419 | PLAN
355426 | PLAN
355433 | PLAN
355440 | PLAN
355447 | PLAN
355454 | PLAN
355461 | PLAN
355468 | PLAN
355475 | PLAN
355482 | PLAN
355489 | PLAN
355496 | PLAN
355503 | PLAN
355510 | PLAN
355517 | PLAN
355524 | PLAN
355531 | PLAN
355538 | PLAN
355545 | PLAN
355552 | PLAN
355559 | PLAN
355566 | PLAN
355573 | PLAN
355580 | PLAN
355587 | PLAN
355594 | PLAN
355601 | PLAN
355608 | PLAN
355615 | PLAN
355622 | PLAN
355629 | PLAN
355636 | PLAN
355643 | PLAN
355650 | PLAN
355657 | PLAN
355664 | PLAN
355671 | PLAN
355678 | PLAN
355685 | PLAN
355692 | PLAN
355699 | PLAN
355706 | PLAN
355713 | PLAN
355720 | PLAN
355727 | PLAN
355734 | PLAN
355741 | PLAN
355748 | PLAN
355755 | PLAN
355762 | PLAN
355769 | PLAN
355776 | PLAN
355783 | PLAN
355790 | PLAN
355797 | PLAN
355804 | PLAN
355811 | PLAN
355818 | PLAN
355825 | PLAN
355832 | PLAN
355839 | PLAN
355846 | PLAN
355853 | PLAN
355860 | PLAN
355867 | PLAN
355874 | PLAN
355881 | PLAN
355888 | PLAN
355895 | PLAN
355902 | PLAN
355909 | PLAN
355916 | PLAN
355923 | PLAN
355930 | PLAN
355937 | PLAN
355944 | PLAN
355951 | PLAN
355958 | PLAN
355965 | PLAN
355972 | PLAN
355979 | PLAN
355986 | PLAN
355993 | PLAN
356000 | PLAN
356007 | PLAN
356014 | PLAN
356021 | PLAN
356028 | PLAN
356035 | PLAN
356042 | PLAN
356049 | PLAN
356056 | PLAN
356063 | PLAN
356070 | PLAN
356077 | PLAN
356084 | PLAN
356091 | PLAN
356098 | PLAN
356105 | PLAN
356112 | PLAN
356119 | PLAN
356126 | PLAN
356133 | PLAN
356140 | PLAN
356147 | PLAN
356154 | PLAN
356161 | PLAN
356168 | PLAN
356175 | PLAN
356182 | PLAN
356189 | PLAN
356196 | PLAN
356203 | PLAN
356210 | PLAN
356217 | PLAN
356224 | PLAN
356231 | PLAN
356238 | PLAN
356245 | PLAN
356252 | PLAN
356259 | PLAN
356266 | PLAN
356273 | PLAN
356280 | PLAN
356287 | PLAN
356294 | PLAN
356301 | PLAN
356308 | PLAN
356315 | PLAN
356322 | PLAN
356329 | PLAN
356336 | PLAN
356343 | PLAN
356350 | PLAN
356357 | PLAN
356364 | PLAN
356371 | PLAN
356378 | PLAN
356385 | PLAN
356392 | PLAN
356399 | PLAN
356406 | PLAN
356413 | PLAN
356420 | PLAN
356427 | PLAN
356434 | PLAN
356441 | PLAN
356448 | PLAN
356455 | PLAN
356462 | PLAN
356469 | PLAN
356476 | PLAN
356483 | PLAN
356490 | PLAN
356497 | PLAN
356504 | PLAN
356511 | PLAN
356518 | PLAN
356525 | PLAN
356532 | PLAN
356539 | PLAN
356546 | PLAN
356553 | PLAN
356560 | PLAN
356567 | PLAN
356574 | PLAN
356581 | PLAN
356588 | PLAN
356595 | PLAN
356602 | PLAN
356609 | PLAN
356616 | PLAN
356623 | PLAN
356630 | PLAN
356637 | PLAN
356644 | PLAN
356651 | PLAN
356658 | PLAN
356665 | PLAN
356672 | PLAN
356679 | PLAN
356686 | PLAN
356693 | PLAN
356700 | PLAN
356707 | PLAN
356714 | PLAN
356721 | PLAN
356728 | PLAN
356735 | PLAN
356742 | PLAN
356749 | PLAN
356756 | PLAN
356763 | PLAN
356770 | PLAN
356777 | PLAN
356784 | PLAN
356791 | PLAN
356798 | PLAN
356805 | PLAN
356812 | PLAN
356819 | PLAN
356826 | PLAN
356833 | PLAN
356840 | PLAN
356847 | PLAN
356854 | PLAN
356861 | PLAN
356868 | PLAN
356875 | PLAN
356882 | PLAN
356889 | PLAN
356896 | PLAN
356903 | PLAN
356910 | PLAN
356917 | PLAN
356924 | PLAN
356931 | PLAN
356938 | PLAN
356945 | PLAN
356952 | PLAN
356959 | PLAN
356966 | PLAN
356973 | PLAN
356980 | PLAN
356987 | PLAN
356994 | PLAN
357001 | PLAN
357008 | PLAN
357015 | PLAN
357022 | PLAN
357029 | PLAN
357036 | PLAN
357043 | PLAN
357050 | PLAN
357057 | PLAN
357064 | PLAN
357071 | PLAN
357078 | PLAN
357085 | PLAN
357092 | PLAN
357099 | PLAN
357106 | PLAN
357113 | PLAN
357120 | PLAN
357127 | PLAN
357134 | PLAN
357141 | PLAN
357148 | PLAN
357155 | PLAN
357162 | PLAN
357169 | PLAN
357176 | PLAN
357183 | PLAN
357190 | PLAN
357197 | PLAN
357204 | PLAN
357211 | PLAN
357218 | PLAN
357225 | PLAN
357232 | PLAN
357239 | PLAN
357246 | PLAN
357253 | PLAN
357260 | PLAN
357267 | PLAN
357274 | PLAN
357281 | PLAN
357288 | PLAN
357295 | PLAN
357302 | PLAN
357309 | PLAN
357316 | PLAN
357323 | PLAN
357330 | PLAN
357337 | PLAN
357344 | PLAN
357351 | PLAN
357358 | PLAN
357365 | PLAN
357372 | PLAN
357379 | PLAN
357386 | PLAN
357393 | PLAN
357400 | PLAN
357407 | PLAN
357414 | PLAN
357421 | PLAN
357428 | PLAN
357435 | PLAN
357442 | PLAN
357449 | PLAN
357456 | PLAN
357463 | PLAN
357470 | PLAN
357477 | PLAN
357484 | PLAN
357491 | PLAN
357498 | PLAN
357505 | PLAN
357512 | PLAN
357519 | PLAN
357526 | PLAN
357533 | PLAN
357540 | PLAN
357547 | PLAN
357554 | PLAN
357561 | PLAN
357568 | PLAN
357575 | PLAN
357582 | PLAN
357589 | PLAN
357596 | PLAN
357603 | PLAN
357610 | PLAN
357617 | PLAN
357624 | PLAN
357631 | PLAN
357638 | PLAN
357645 | PLAN
357652 | PLAN
357659 | PLAN
357666 | PLAN
357673 | PLAN
357680 | PLAN
357687 | PLAN
357694 | PLAN
357701 | PLAN
357708 | PLAN
357715 | PLAN
357722 | PLAN
357729 | PLAN
357736 | PLAN
357743 | PLAN
357750 | PLAN
357757 | PLAN
357764 | PLAN
357771 | PLAN
357778 | PLAN
357785 | PLAN
357792 | PLAN
357799 | PLAN
357806 | PLAN
357813 | PLAN
357820 | PLAN
357827 | PLAN
357834 | PLAN
357841 | PLAN
357848 | PLAN
357855 | PLAN
357862 | PLAN
357869 | PLAN
357876 | PLAN
357883 | PLAN
357890 | PLAN
357897 | PLAN
357904 | PLAN
357911 | PLAN
357918 | PLAN
357925 | PLAN
357932 | PLAN
357939 | PLAN
357946 | PLAN
357953 | PLAN
357960 | PLAN
357967 | PLAN
357974 | PLAN
357981 | PLAN
357988 | PLAN
357995 | PLAN
358002 | PLAN
358009 | PLAN
358016 | PLAN
358023 | PLAN
358030 | PLAN
358037 | PLAN
358044 | PLAN
358051 | PLAN
358058 | PLAN
358065 | PLAN
358072 | PLAN
358079 | PLAN
358086 | PLAN
358093 | PLAN
358100 | PLAN
358107 | PLAN
358114 | PLAN
358121 | PLAN
358128 | PLAN
358135 | PLAN
358142 | PLAN
358149 | PLAN
358156 | PLAN
358163 | PLAN
358170 | PLAN
358177 | PLAN
358184 | PLAN
358191 | PLAN
358198 | PLAN
358205 | PLAN
358212 | PLAN
358219 | PLAN
358226 | PLAN
358233 | PLAN
358240 | PLAN
358247 | PLAN
358254 | PLAN
358261 | PLAN
358268 | PLAN
358275 | PLAN
358282 | PLAN
358289 | PLAN
358296 | PLAN
358303 | PLAN
358310 | PLAN
358317 | PLAN
358324 | PLAN
358331 | PLAN
358338 | PLAN
358345 | PLAN
358352 | PLAN
358359 | PLAN
358366 | PLAN
358373 | PLAN
358380 | PLAN
358387 | PLAN
358394 | PLAN
358401 | PLAN
358408 | PLAN
358415 | PLAN
358422 | PLAN
358429 | PLAN
358436 | PLAN
358443 | PLAN
358450 | PLAN
358457 | PLAN
358464 | PLAN
358471 | PLAN
358478 | PLAN
358485 | PLAN
358492 | PLAN
358499 | PLAN
358506 | PLAN
358513 | PLAN
358520 | PLAN
358527 | PLAN
358534 | PLAN
358541 | PLAN
358548 | PLAN
358555 | PLAN
358562 | PLAN
358569 | PLAN
358576 | PLAN
358583 | PLAN
358590 | PLAN
358597 | PLAN
358604 | PLAN
358611 | PLAN
358618 | PLAN
358625 | PLAN
358632 | PLAN
358639 | PLAN
358646 | PLAN
358653 | PLAN
358660 | PLAN
358667 | PLAN
358674 | PLAN
358681 | PLAN
358688 | PLAN
358695 | PLAN
358702 | PLAN
358709 | PLAN
358716 | PLAN
358723 | PLAN
358730 | PLAN
358737 | PLAN
358744 | PLAN
358751 | PLAN
358758 | PLAN
358765 | PLAN
358772 | PLAN
358779 | PLAN
358786 | PLAN
358793 | PLAN
358800 | PLAN
358807 | PLAN
358814 | PLAN
358821 | PLAN
358828 | PLAN
358835 | PLAN
358842 | PLAN
358849 | PLAN
358856 | PLAN
358863 | PLAN
358870 | PLAN
358877 | PLAN
358884 | PLAN
358891 | PLAN
358898 | PLAN
358905 | PLAN
358912 | PLAN
358919 | PLAN
358926 | PLAN
358933 | PLAN
358940 | PLAN
358947 | PLAN
358954 | PLAN
358961 | PLAN
358968 | PLAN
358975 | PLAN
358982 | PLAN
358989 | PLAN
358996 | PLAN
359003 | PLAN
359010 | PLAN
359017 | PLAN
359024 | PLAN
359031 | PLAN
359038 | PLAN
359045 | PLAN
359052 | PLAN
359059 | PLAN
359066 | PLAN
359073 | PLAN
359080 | PLAN
359087 | PLAN
359094 | PLAN
359101 | PLAN
359108 | PLAN
359115 | PLAN
359122 | PLAN
359129 | PLAN
359136 | PLAN
359143 | PLAN
359150 | PLAN
359157 | PLAN
359164 | PLAN
359171 | PLAN
359178 | PLAN
359185 | PLAN
359192 | PLAN
359199 | PLAN
359206 | PLAN
359213 | PLAN
359220 | PLAN
359227 | PLAN
359234 | PLAN
359241 | PLAN
359248 | PLAN
359255 | PLAN
359262 | PLAN
359269 | PLAN
359276 | PLAN
359283 | PLAN
359290 | PLAN
359297 | PLAN
359304 | PLAN
359311 | PLAN
359318 | PLAN
359325 | PLAN
359332 | PLAN
359339 | PLAN
359346 | PLAN
359353 | PLAN
359360 | PLAN
359367 | PLAN
359374 | PLAN
359381 | PLAN
359388 | PLAN
359395 | PLAN
359402 | PLAN
359409 | PLAN
359416 | PLAN
359423 | PLAN
359430 | PLAN
359437 | PLAN
359444 | PLAN
359451 | PLAN
359458 | PLAN
359465 | PLAN
359472 | PLAN
359479 | PLAN
359486 | PLAN
359493 | PLAN
359500 | PLAN
359507 | PLAN
359514 | PLAN
359521 | PLAN
359528 | PLAN
359535 | PLAN
359542 | PLAN
359549 | PLAN
359556 | PLAN
359563 | PLAN
359570 | PLAN
359577 | PLAN
359584 | PLAN
359591 | PLAN
359598 | PLAN
359605 | PLAN
359612 | PLAN
359619 | PLAN
359626 | PLAN
359633 | PLAN
359640 | PLAN
359647 | PLAN
359654 | PLAN
359661 | PLAN
359668 | PLAN
359675 | PLAN
359682 | PLAN
359689 | PLAN
359696 | PLAN
359703 | PLAN
359710 | PLAN
359717 | PLAN
359724 | PLAN
359731 | PLAN
359738 | PLAN
359745 | PLAN
359752 | PLAN
359759 | PLAN
359766 | PLAN
359773 | PLAN
359780 | PLAN
359787 | PLAN
359794 | PLAN
359801 | PLAN
359808 | PLAN
359815 | PLAN
359822 | PLAN
359829 | PLAN
359836 | PLAN
359843 | PLAN
359850 | PLAN
359857 | PLAN
359864 | PLAN
359871 | PLAN
359878 | PLAN
359885 | PLAN
359892 | PLAN
359899 | PLAN
359906 | PLAN
359913 | PLAN
359920 | PLAN
359927 | PLAN
359934 | PLAN
359941 | PLAN
359948 | PLAN
359955 | PLAN
359962 | PLAN
359969 | PLAN
359976 | PLAN
359983 | PLAN
359990 | PLAN
359997 | PLAN
360004 | PLAN
360011 | PLAN
360018 | PLAN
360025 | PLAN
360032 | PLAN
360039 | PLAN
360046 | PLAN
360053 | PLAN
360060 | PLAN
360067 | PLAN
360074 | PLAN
360081 | PLAN
360088 | PLAN
360095 | PLAN
360102 | PLAN
360109 | PLAN
360116 | PLAN
360123 | PLAN
360130 | PLAN
360137 | PLAN
360144 | PLAN
360151 | PLAN
360158 | PLAN
360165 | PLAN
360172 | PLAN
360179 | PLAN
360186 | PLAN
360193 | PLAN
360200 | PLAN
360207 | PLAN
360214 | PLAN
360221 | PLAN
360228 | PLAN
360235 | PLAN
360242 | PLAN
360249 | PLAN
360256 | PLAN
360263 | PLAN
360270 | PLAN
360277 | PLAN
360284 | PLAN
360291 | PLAN
360298 | PLAN
360305 | PLAN
360312 | PLAN
360319 | PLAN
360326 | PLAN
360333 | PLAN
360340 | PLAN
360347 | PLAN
360354 | PLAN
360361 | PLAN
360368 | PLAN
360375 | PLAN
360382 | PLAN
360389 | PLAN
360396 | PLAN
360403 | PLAN
360410 | PLAN
360417 | PLAN
360424 | PLAN
360431 | PLAN
360438 | PLAN
360445 | PLAN
360452 | PLAN
360459 | PLAN
360466 | PLAN
360473 | PLAN
360480 | PLAN
360487 | PLAN
360494 | PLAN
360501 | PLAN
360508 | PLAN
360515 | PLAN
360522 | PLAN
360529 | PLAN
360536 | PLAN
360543 | PLAN
360550 | PLAN
360557 | PLAN
360564 | PLAN
360571 | PLAN
360578 | PLAN
360585 | PLAN
360592 | PLAN
360599 | PLAN
360606 | PLAN
360613 | PLAN
360620 | PLAN
360627 | PLAN
360634 | PLAN
360641 | PLAN
360648 | PLAN
360655 | PLAN
360662 | PLAN
360669 | PLAN
360676 | PLAN
360683 | PLAN
360690 | PLAN
360697 | PLAN
360704 | PLAN
360711 | PLAN
360718 | PLAN
360725 | PLAN
360732 | PLAN
360739 | PLAN
360746 | PLAN
360753 | PLAN
360760 | PLAN
360767 | PLAN
360774 | PLAN
360781 | PLAN
360788 | PLAN
360795 | PLAN
360802 | PLAN
360809 | PLAN
360816 | PLAN
360823 | PLAN
360830 | PLAN
360837 | PLAN
360844 | PLAN
360851 | PLAN
360858 | PLAN
360865 | PLAN
360872 | PLAN
360879 | PLAN
360886 | PLAN
360893 | PLAN
360900 | PLAN
360907 | PLAN
360914 | PLAN
360921 | PLAN
360928 | PLAN
360935 | PLAN
360942 | PLAN
360949 | PLAN
360956 | PLAN
360963 | PLAN
360970 | PLAN
360977 | PLAN
360984 | PLAN
360991 | PLAN
360998 | PLAN
361005 | PLAN
361012 | PLAN
361019 | PLAN
361026 | PLAN
361033 | PLAN
361040 | PLAN
361047 | PLAN
361054 | PLAN
361061 | PLAN
361068 | PLAN
361075 | PLAN
361082 | PLAN
361089 | PLAN
361096 | PLAN
361103 | PLAN
361110 | PLAN
361117 | PLAN
361124 | PLAN
361131 | PLAN
361138 | PLAN
361145 | PLAN
361152 | PLAN
361159 | PLAN
361166 | PLAN
361173 | PLAN
361180 | PLAN
361187 | PLAN
361194 | PLAN
361201 | PLAN
361208 | PLAN
361215 | PLAN
361222 | PLAN
361229 | PLAN
361236 | PLAN
361243 | PLAN
361250 | PLAN
361257 | PLAN
361264 | PLAN
361271 | PLAN
361278 | PLAN
361285 | PLAN
361292 | PLAN
361299 | PLAN
361306 | PLAN
361313 | PLAN
361320 | PLAN
361327 | PLAN
361334 | PLAN
361341 | PLAN
361348 | PLAN
361355 | PLAN
361362 | PLAN
361369 | PLAN
361376 | PLAN
361383 | PLAN
361390 | PLAN
361397 | PLAN
361404 | PLAN
361411 | PLAN
361418 | PLAN
361425 | PLAN
361432 | PLAN
361439 | PLAN
361446 | PLAN
361453 | PLAN
361460 | PLAN
361467 | PLAN
361474 | PLAN
361481 | PLAN
361488 | PLAN
361495 | PLAN
361502 | PLAN
361509 | PLAN
361516 | PLAN
361523 | PLAN
361530 | PLAN
361537 | PLAN
361544 | PLAN
361551 | PLAN
361558 | PLAN
361565 | PLAN
361572 | PLAN
361579 | PLAN
361586 | PLAN
361593 | PLAN
361600 | PLAN
361607 | PLAN
361614 | PLAN
361621 | PLAN
361628 | PLAN
361635 | PLAN
361642 | PLAN
361649 | PLAN
361656 | PLAN
361663 | PLAN
361670 | PLAN
361677 | PLAN
361684 | PLAN
361691 | PLAN
361698 | PLAN
361705 | PLAN
361712 | PLAN
361719 | PLAN
361726 | PLAN
361733 | PLAN
361740 | PLAN
361747 | PLAN
361754 | PLAN
361761 | PLAN
361768 | PLAN
361775 | PLAN
361782 | PLAN
361789 | PLAN
361796 | PLAN
361803 | PLAN
361810 | PLAN
361817 | PLAN
361824 | PLAN
361831 | PLAN
361838 | PLAN
361845 | PLAN
361852 | PLAN
361859 | PLAN
361866 | PLAN
361873 | PLAN
361880 | PLAN
361887 | PLAN
361894 | PLAN
361901 | PLAN
361908 | PLAN
361915 | PLAN
361922 | PLAN
361929 | PLAN
361936 | PLAN
361943 | PLAN
361950 | PLAN
361957 | PLAN
361964 | PLAN
361971 | PLAN
361978 | PLAN
361985 | PLAN
361992 | PLAN
361999 | PLAN
362006 | PLAN
362013 | PLAN
362020 | PLAN
362027 | PLAN
362034 | PLAN
362041 | PLAN
362048 | PLAN
362055 | PLAN
362062 | PLAN
362069 | PLAN
362076 | PLAN
362083 | PLAN
362090 | PLAN
362097 | PLAN
362104 | PLAN
362111 | PLAN
362118 | PLAN
362125 | PLAN
362132 | PLAN
362139 | PLAN
362146 | PLAN
362153 | PLAN
362160 | PLAN
362167 | PLAN
362174 | PLAN
362181 | PLAN
362188 | PLAN
362195 | PLAN
362202 | PLAN
362209 | PLAN
362216 | PLAN
362223 | PLAN
362230 | PLAN
362237 | PLAN
362244 | PLAN
362251 | PLAN
362258 | PLAN
362265 | PLAN
362272 | PLAN
362279 | PLAN
362286 | PLAN
362293 | PLAN
362300 | PLAN
362307 | PLAN
362314 | PLAN
362321 | PLAN
362328 | PLAN
362335 | PLAN
362342 | PLAN
362349 | PLAN
362356 | PLAN
362363 | PLAN
362370 | PLAN
362377 | PLAN
362384 | PLAN
362391 | PLAN
362398 | PLAN
362405 | PLAN
362412 | PLAN
362419 | PLAN
362426 | PLAN
362433 | PLAN
362440 | PLAN
362447 | PLAN
362454 | PLAN
362461 | PLAN
362468 | PLAN
362475 | PLAN
362482 | PLAN
362489 | PLAN
362496 | PLAN
362503 | PLAN
362510 | PLAN
362517 | PLAN
362524 | PLAN
362531 | PLAN
362538 | PLAN
362545 | PLAN
362552 | PLAN
362559 | PLAN
362566 | PLAN
362573 | PLAN
362580 | PLAN
362587 | PLAN
362594 | PLAN
362601 | PLAN
362608 | PLAN
362615 | PLAN
362622 | PLAN
362629 | PLAN
362636 | PLAN
362643 | PLAN
362650 | PLAN
362657 | PLAN
362664 | PLAN
362671 | PLAN
362678 | PLAN
362685 | PLAN
362692 | PLAN
362699 | PLAN
362706 | PLAN
362713 | PLAN
362720 | PLAN
362727 | PLAN
362734 | PLAN
362741 | PLAN
362748 | PLAN
362755 | PLAN
362762 | PLAN
362769 | PLAN
362776 | PLAN
362783 | PLAN
362790 | PLAN
362797 | PLAN
362804 | PLAN
362811 | PLAN
362818 | PLAN
362825 | PLAN
362832 | PLAN
362839 | PLAN
362846 | PLAN
362853 | PLAN
362860 | PLAN
362867 | PLAN
362874 | PLAN
362881 | PLAN
362888 | PLAN
362895 | PLAN
362902 | PLAN
362909 | PLAN
362916 | PLAN
362923 | PLAN
362930 | PLAN
362937 | PLAN
362944 | PLAN
362951 | PLAN
362958 | PLAN
362965 | PLAN
362972 | PLAN
362979 | PLAN
362986 | PLAN
362993 | PLAN
363000 | PLAN
363007 | PLAN
363014 | PLAN
363021 | PLAN
363028 | PLAN
363035 | PLAN
363042 | PLAN
363049 | PLAN
363056 | PLAN
363063 | PLAN
363070 | PLAN
363077 | PLAN
363084 | PLAN
363091 | PLAN
363098 | PLAN
363105 | PLAN
363112 | PLAN
363119 | PLAN
363126 | PLAN
363133 | PLAN
363140 | PLAN
363147 | PLAN
363154 | PLAN
363161 | PLAN
363168 | PLAN
363175 | PLAN
363182 | PLAN
363189 | PLAN
363196 | PLAN
363203 | PLAN
363210 | PLAN
363217 | PLAN
363224 | PLAN
363231 | PLAN
363238 | PLAN
363245 | PLAN
363252 | PLAN
363259 | PLAN
363266 | PLAN
363273 | PLAN
363280 | PLAN
363287 | PLAN
363294 | PLAN
363301 | PLAN
363308 | PLAN
363315 | PLAN
363322 | PLAN
363329 | PLAN
363336 | PLAN
363343 | PLAN
363350 | PLAN
363357 | PLAN
363364 | PLAN
363371 | PLAN
363378 | PLAN
363385 | PLAN
363392 | PLAN
363399 | PLAN
363406 | PLAN
363413 | PLAN
363420 | PLAN
363427 | PLAN
363434 | PLAN
363441 | PLAN
363448 | PLAN
363455 | PLAN
363462 | PLAN
363469 | PLAN
363476 | PLAN
363483 | PLAN
363490 | PLAN
363497 | PLAN
363504 | PLAN
363511 | PLAN
363518 | PLAN
363525 | PLAN
363532 | PLAN
363539 | PLAN
363546 | PLAN
363553 | PLAN
363560 | PLAN
363567 | PLAN
363574 | PLAN
363581 | PLAN
363588 | PLAN
363595 | PLAN
363602 | PLAN
363609 | PLAN
363616 | PLAN
363623 | PLAN
363630 | PLAN
363637 | PLAN
363644 | PLAN
363651 | PLAN
363658 | PLAN
363665 | PLAN
363672 | PLAN
363679 | PLAN
363686 | PLAN
363693 | PLAN
363700 | PLAN
363707 | PLAN
363714 | PLAN
363721 | PLAN
363728 | PLAN
363735 | PLAN
363742 | PLAN
363749 | PLAN
363756 | PLAN
363763 | PLAN
363770 | PLAN
363777 | PLAN
363784 | PLAN
363791 | PLAN
363798 | PLAN
363805 | PLAN
363812 | PLAN
363819 | PLAN
363826 | PLAN
363833 | PLAN
363840 | PLAN
363847 | PLAN
363854 | PLAN
363861 | PLAN
363868 | PLAN
363875 | PLAN
363882 | PLAN
363889 | PLAN
363896 | PLAN
363903 | PLAN
363910 | PLAN
363917 | PLAN
363924 | PLAN
363931 | PLAN
363938 | PLAN
363945 | PLAN
363952 | PLAN
363959 | PLAN
363966 | PLAN
363973 | PLAN
363980 | PLAN
363987 | PLAN
363994 | PLAN
364001 | PLAN
364008 | PLAN
364015 | PLAN
364022 | PLAN
364029 | PLAN
364036 | PLAN
364043 | PLAN
364050 | PLAN
364057 | PLAN
364064 | PLAN
364071 | PLAN
364078 | PLAN
364085 | PLAN
364092 | PLAN
364099 | PLAN
364106 | PLAN
364113 | PLAN
364120 | PLAN
364127 | PLAN
364134 | PLAN
364141 | PLAN
364148 | PLAN
364155 | PLAN
364162 | PLAN
364169 | PLAN
364176 | PLAN
364183 | PLAN
364190 | PLAN
364197 | PLAN
364204 | PLAN
364211 | PLAN
364218 | PLAN
364225 | PLAN
364232 | PLAN
364239 | PLAN
364246 | PLAN
364253 | PLAN
364260 | PLAN
364267 | PLAN
364274 | PLAN
364281 | PLAN
364288 | PLAN
364295 | PLAN
364302 | PLAN
364309 | PLAN
364316 | PLAN
364323 | PLAN
364330 | PLAN
364337 | PLAN
364344 | PLAN
364351 | PLAN
364358 | PLAN
364365 | PLAN
364372 | PLAN
364379 | PLAN
364386 | PLAN
364393 | PLAN
364400 | PLAN
364407 | PLAN
364414 | PLAN
364421 | PLAN
364428 | PLAN
364435 | PLAN
364442 | PLAN
364449 | PLAN
364456 | PLAN
364463 | PLAN
364470 | PLAN
364477 | PLAN
364484 | PLAN
364491 | PLAN
364498 | PLAN
364505 | PLAN
364512 | PLAN
364519 | PLAN
364526 | PLAN
364533 | PLAN
364540 | PLAN
364547 | PLAN
364554 | PLAN
364561 | PLAN
364568 | PLAN
364575 | PLAN
364582 | PLAN
364589 | PLAN
364596 | PLAN
364603 | PLAN
364610 | PLAN
364617 | PLAN
364624 | PLAN
364631 | PLAN
364638 | PLAN
364645 | PLAN
364652 | PLAN
364659 | PLAN
364666 | PLAN
364673 | PLAN
364680 | PLAN
364687 | PLAN
364694 | PLAN
364701 | PLAN
364708 | PLAN
364715 | PLAN
364722 | PLAN
364729 | PLAN
364736 | PLAN
364743 | PLAN
364750 | PLAN
364757 | PLAN
364764 | PLAN
364771 | PLAN
364778 | PLAN
364785 | PLAN
364792 | PLAN
364799 | PLAN
364806 | PLAN
364813 | PLAN
364820 | PLAN
364827 | PLAN
364834 | PLAN
364841 | PLAN
364848 | PLAN
364855 | PLAN
364862 | PLAN
364869 | PLAN
364876 | PLAN
364883 | PLAN
364890 | PLAN
364897 | PLAN
364904 | PLAN
364911 | PLAN
364918 | PLAN
364925 | PLAN
364932 | PLAN
364939 | PLAN
364946 | PLAN
364953 | PLAN
364960 | PLAN
364967 | PLAN
364974 | PLAN
364981 | PLAN
364988 | PLAN
364995 | PLAN
365002 | PLAN
365009 | PLAN
365016 | PLAN
365023 | PLAN
365030 | PLAN
365037 | PLAN
365044 | PLAN
365051 | PLAN
365058 | PLAN
365065 | PLAN
365072 | PLAN
365079 | PLAN
365086 | PLAN
365093 | PLAN
365100 | PLAN
365107 | PLAN
365114 | PLAN
365121 | PLAN
365128 | PLAN
365135 | PLAN
365142 | PLAN
365149 | PLAN
365156 | PLAN
365163 | PLAN
365170 | PLAN
365177 | PLAN
365184 | PLAN
365191 | PLAN
365198 | PLAN
365205 | PLAN
365212 | PLAN
365219 | PLAN
365226 | PLAN
365233 | PLAN
365240 | PLAN
365247 | PLAN
365254 | PLAN
365261 | PLAN
365268 | PLAN
365275 | PLAN
365282 | PLAN
365289 | PLAN
365296 | PLAN
365303 | PLAN
365310 | PLAN
365317 | PLAN
365324 | PLAN
365331 | PLAN
365338 | PLAN
365345 | PLAN
365352 | PLAN
365359 | PLAN
365366 | PLAN
365373 | PLAN
365380 | PLAN
365387 | PLAN
365394 | PLAN
365401 | PLAN
365408 | PLAN
365415 | PLAN
365422 | PLAN
365429 | PLAN
365436 | PLAN
365443 | PLAN
365450 | PLAN
365457 | PLAN
365464 | PLAN
365471 | PLAN
365478 | PLAN
365485 | PLAN
365492 | PLAN
365499 | PLAN
365506 | PLAN
365513 | PLAN
365520 | PLAN
365527 | PLAN
365534 | PLAN
365541 | PLAN
365548 | PLAN
365555 | PLAN
365562 | PLAN
365569 | PLAN
365576 | PLAN
365583 | PLAN
365590 | PLAN
365597 | PLAN
365604 | PLAN
365611 | PLAN
365618 | PLAN
365625 | PLAN
365632 | PLAN
365639 | PLAN
365646 | PLAN
365653 | PLAN
365660 | PLAN
365667 | PLAN
365674 | PLAN
365681 | PLAN
365688 | PLAN
365695 | PLAN
365702 | PLAN
365709 | PLAN
365716 | PLAN
365723 | PLAN
365730 | PLAN
365737 | PLAN
365744 | PLAN
365751 | PLAN
365758 | PLAN
365765 | PLAN
365772 | PLAN
365779 | PLAN
365786 | PLAN
365793 | PLAN
365800 | PLAN
365807 | PLAN
365814 | PLAN
365821 | PLAN
365828 | PLAN
365835 | PLAN
365842 | PLAN
365849 | PLAN
365856 | PLAN
365863 | PLAN
365870 | PLAN
365877 | PLAN
365884 | PLAN
365891 | PLAN
365898 | PLAN
365905 | PLAN
365912 | PLAN
365919 | PLAN
365926 | PLAN
365933 | PLAN
365940 | PLAN
365947 | PLAN
365954 | PLAN
365961 | PLAN
365968 | PLAN
365975 | PLAN
365982 | PLAN
365989 | PLAN
365996 | PLAN
366003 | PLAN
366010 | PLAN
366017 | PLAN
366024 | PLAN
366031 | PLAN
366038 | PLAN
366045 | PLAN
366052 | PLAN
366059 | PLAN
366066 | PLAN
366073 | PLAN
366080 | PLAN
366087 | PLAN
366094 | PLAN
366101 | PLAN
366108 | PLAN
366115 | PLAN
366122 | PLAN
366129 | PLAN
366136 | PLAN
366143 | PLAN
366150 | PLAN
366157 | PLAN
366164 | PLAN
366171 | PLAN
366178 | PLAN
366185 | PLAN
366192 | PLAN
366199 | PLAN
366206 | PLAN
366213 | PLAN
366220 | PLAN
366227 | PLAN
366234 | PLAN
366241 | PLAN
366248 | PLAN
366255 | PLAN
366262 | PLAN
366269 | PLAN
366276 | PLAN
366283 | PLAN
366290 | PLAN
366297 | PLAN
366304 | PLAN
366311 | PLAN
366318 | PLAN
366325 | PLAN
366332 | PLAN
366339 | PLAN
366346 | PLAN
366353 | PLAN
366360 | PLAN
366367 | PLAN
366374 | PLAN
366381 | PLAN
366388 | PLAN
366395 | PLAN
366402 | PLAN
366409 | PLAN
366416 | PLAN
366423 | PLAN
366430 | PLAN
366437 | PLAN
366444 | PLAN
366451 | PLAN
366458 | PLAN
366465 | PLAN
366472 | PLAN
366479 | PLAN
366486 | PLAN
366493 | PLAN
366500 | PLAN
366507 | PLAN
366514 | PLAN
366521 | PLAN
366528 | PLAN
366535 | PLAN
366542 | PLAN
366549 | PLAN
366556 | PLAN
366563 | PLAN
366570 | PLAN
366577 | PLAN
366584 | PLAN
366591 | PLAN
366598 | PLAN
366605 | PLAN
366612 | PLAN
366619 | PLAN
366626 | PLAN
366633 | PLAN
366640 | PLAN
366647 | PLAN
366654 | PLAN
366661 | PLAN
366668 | PLAN
366675 | PLAN
366682 | PLAN
366689 | PLAN
366696 | PLAN
366703 | PLAN
366710 | PLAN
366717 | PLAN
366724 | PLAN
366731 | PLAN
366738 | PLAN
366745 | PLAN
366752 | PLAN
366759 | PLAN
366766 | PLAN
366773 | PLAN
366780 | PLAN
366787 | PLAN
366794 | PLAN
366801 | PLAN
366808 | PLAN
366815 | PLAN
366822 | PLAN
366829 | PLAN
366836 | PLAN
366843 | PLAN
366850 | PLAN
366857 | PLAN
366864 | PLAN
366871 | PLAN
366878 | PLAN
366885 | PLAN
366892 | PLAN
366899 | PLAN
366906 | PLAN
366913 | PLAN
366920 | PLAN
366927 | PLAN
366934 | PLAN
366941 | PLAN
366948 | PLAN
366955 | PLAN
366962 | PLAN
366969 | PLAN
366976 | PLAN
366983 | PLAN
366990 | PLAN
366997 | PLAN
367004 | PLAN
367011 | PLAN
367018 | PLAN
367025 | PLAN
367032 | PLAN
367039 | PLAN
367046 | PLAN
367053 | PLAN
367060 | PLAN
367067 | PLAN
367074 | PLAN
367081 | PLAN
367088 | PLAN
367095 | PLAN
367102 | PLAN
367109 | PLAN
367116 | PLAN
367123 | PLAN
367130 | PLAN
367137 | PLAN
367144 | PLAN
367151 | PLAN
367158 | PLAN
367165 | PLAN
367172 | PLAN
367179 | PLAN
367186 | PLAN
367193 | PLAN
367200 | PLAN
367207 | PLAN
367214 | PLAN
367221 | PLAN
367228 | PLAN
367235 | PLAN
367242 | PLAN
367249 | PLAN
367256 | PLAN
367263 | PLAN
367270 | PLAN
367277 | PLAN
367284 | PLAN
367291 | PLAN
367298 | PLAN
367305 | PLAN
367312 | PLAN
367319 | PLAN
367326 | PLAN
367333 | PLAN
367340 | PLAN
367347 | PLAN
367354 | PLAN
367361 | PLAN
367368 | PLAN
367375 | PLAN
367382 | PLAN
367389 | PLAN
367396 | PLAN
367403 | PLAN
367410 | PLAN
367417 | PLAN
367424 | PLAN
367431 | PLAN
367438 | PLAN
367445 | PLAN
367452 | PLAN
367459 | PLAN
367466 | PLAN
367473 | PLAN
367480 | PLAN
367487 | PLAN
367494 | PLAN
367501 | PLAN
367508 | PLAN
367515 | PLAN
367522 | PLAN
367529 | PLAN
367536 | PLAN
367543 | PLAN
367550 | PLAN
367557 | PLAN
367564 | PLAN
367571 | PLAN
367578 | PLAN
367585 | PLAN
367592 | PLAN
367599 | PLAN
367606 | PLAN
367613 | PLAN
367620 | PLAN
367627 | PLAN
367634 | PLAN
367641 | PLAN
367648 | PLAN
367655 | PLAN
367662 | PLAN
367669 | PLAN
367676 | PLAN
367683 | PLAN
367690 | PLAN
367697 | PLAN
367704 | PLAN
367711 | PLAN
367718 | PLAN
367725 | PLAN
367732 | PLAN
367739 | PLAN
367746 | PLAN
367753 | PLAN
367760 | PLAN
367767 | PLAN
367774 | PLAN
367781 | PLAN
367788 | PLAN
367795 | PLAN
367802 | PLAN
367809 | PLAN
367816 | PLAN
367823 | PLAN
367830 | PLAN
367837 | PLAN
367844 | PLAN
367851 | PLAN
367858 | PLAN
367865 | PLAN
367872 | PLAN
367879 | PLAN
367886 | PLAN
367893 | PLAN
367900 | PLAN
367907 | PLAN
367914 | PLAN
367921 | PLAN
367928 | PLAN
367935 | PLAN
367942 | PLAN
367949 | PLAN
367956 | PLAN
367963 | PLAN
367970 | PLAN
367977 | PLAN
367984 | PLAN
367991 | PLAN
367998 | PLAN
368005 | PLAN
368012 | PLAN
368019 | PLAN
368026 | PLAN
368033 | PLAN
368040 | PLAN
368047 | PLAN
368054 | PLAN
368061 | PLAN
368068 | PLAN
368075 | PLAN
368082 | PLAN
368089 | PLAN
368096 | PLAN
368103 | PLAN
368110 | PLAN
368117 | PLAN
368124 | PLAN
368131 | PLAN
368138 | PLAN
368145 | PLAN
368152 | PLAN
368159 | PLAN
368166 | PLAN
368173 | PLAN
368180 | PLAN
368187 | PLAN
368194 | PLAN
368201 | PLAN
368208 | PLAN
368215 | PLAN
368222 | PLAN
368229 | PLAN
368236 | PLAN
368243 | PLAN
368250 | PLAN
368257 | PLAN
368264 | PLAN
368271 | PLAN
368278 | PLAN
368285 | PLAN
368292 | PLAN
368299 | PLAN
368306 | PLAN
368313 | PLAN
368320 | PLAN
368327 | PLAN
368334 | PLAN
368341 | PLAN
368348 | PLAN
368355 | PLAN
368362 | PLAN
368369 | PLAN
368376 | PLAN
368383 | PLAN
368390 | PLAN
368397 | PLAN
368404 | PLAN
368411 | PLAN
368418 | PLAN
368425 | PLAN
368432 | PLAN
368439 | PLAN
368446 | PLAN
368453 | PLAN
368460 | PLAN
368467 | PLAN
368474 | PLAN
368481 | PLAN
368488 | PLAN
368495 | PLAN
368502 | PLAN
368509 | PLAN
368516 | PLAN
368523 | PLAN
368530 | PLAN
368537 | PLAN
368544 | PLAN
368551 | PLAN
368558 | PLAN
368565 | PLAN
368572 | PLAN
368579 | PLAN
368586 | PLAN
368593 | PLAN
368600 | PLAN
368607 | PLAN
368614 | PLAN
368621 | PLAN
368628 | PLAN
368635 | PLAN
368642 | PLAN
368649 | PLAN
368656 | PLAN
368663 | PLAN
368670 | PLAN
368677 | PLAN
368684 | PLAN
368691 | PLAN
368698 | PLAN
368705 | PLAN
368712 | PLAN
368719 | PLAN
368726 | PLAN
368733 | PLAN
368740 | PLAN
368747 | PLAN
368754 | PLAN
368761 | PLAN
368768 | PLAN
368775 | PLAN
368782 | PLAN
368789 | PLAN
368796 | PLAN
368803 | PLAN
368810 | PLAN
368817 | PLAN
368824 | PLAN
368831 | PLAN
368838 | PLAN
368845 | PLAN
368852 | PLAN
368859 | PLAN
368866 | PLAN
368873 | PLAN
368880 | PLAN
368887 | PLAN
368894 | PLAN
368901 | PLAN
368908 | PLAN
368915 | PLAN
368922 | PLAN
368929 | PLAN
368936 | PLAN
368943 | PLAN
368950 | PLAN
368957 | PLAN
368964 | PLAN
368971 | PLAN
368978 | PLAN
368985 | PLAN
368992 | PLAN
368999 | PLAN
369006 | PLAN
369013 | PLAN
369020 | PLAN
369027 | PLAN
369034 | PLAN
369041 | PLAN
369048 | PLAN
369055 | PLAN
369062 | PLAN
369069 | PLAN
369076 | PLAN
369083 | PLAN
369090 | PLAN
369097 | PLAN
369104 | PLAN
369111 | PLAN
369118 | PLAN
369125 | PLAN
369132 | PLAN
369139 | PLAN
369146 | PLAN
369153 | PLAN
369160 | PLAN
369167 | PLAN
369174 | PLAN
369181 | PLAN
369188 | PLAN
369195 | PLAN
369202 | PLAN
369209 | PLAN
369216 | PLAN
369223 | PLAN
369230 | PLAN
369237 | PLAN
369244 | PLAN
369251 | PLAN
369258 | PLAN
369265 | PLAN
369272 | PLAN
369279 | PLAN
369286 | PLAN
369293 | PLAN
369300 | PLAN
369307 | PLAN
369314 | PLAN
369321 | PLAN
369328 | PLAN
369335 | PLAN
369342 | PLAN
369349 | PLAN
369356 | PLAN
369363 | PLAN
369370 | PLAN
369377 | PLAN
369384 | PLAN
369391 | PLAN
369398 | PLAN
369405 | PLAN
369412 | PLAN
369419 | PLAN
369426 | PLAN
369433 | PLAN
369440 | PLAN
369447 | PLAN
369454 | PLAN
369461 | PLAN
369468 | PLAN
369475 | PLAN
369482 | PLAN
369489 | PLAN
369496 | PLAN
369503 | PLAN
369510 | PLAN
369517 | PLAN
369524 | PLAN
369531 | PLAN
369538 | PLAN
369545 | PLAN
369552 | PLAN
369559 | PLAN
369566 | PLAN
369573 | PLAN
369580 | PLAN
369587 | PLAN
369594 | PLAN
369601 | PLAN
369608 | PLAN
369615 | PLAN
369622 | PLAN
369629 | PLAN
369636 | PLAN
369643 | PLAN
369650 | PLAN
369657 | PLAN
369664 | PLAN
369671 | PLAN
369678 | PLAN
369685 | PLAN
369692 | PLAN
369699 | PLAN
369706 | PLAN
369713 | PLAN
369720 | PLAN
369727 | PLAN
369734 | PLAN
369741 | PLAN
369748 | PLAN
369755 | PLAN
369762 | PLAN
369769 | PLAN
369776 | PLAN
369783 | PLAN
369790 | PLAN
369797 | PLAN
369804 | PLAN
369811 | PLAN
369818 | PLAN
369825 | PLAN
369832 | PLAN
369839 | PLAN
369846 | PLAN
369853 | PLAN
369860 | PLAN
369867 | PLAN
369874 | PLAN
369881 | PLAN
369888 | PLAN
369895 | PLAN
369902 | PLAN
369909 | PLAN
369916 | PLAN
369923 | PLAN
369930 | PLAN
369937 | PLAN
369944 | PLAN
369951 | PLAN
369958 | PLAN
369965 | PLAN
369972 | PLAN
369979 | PLAN
369986 | PLAN
369993 | PLAN
370000 | PLAN
370007 | PLAN
370014 | PLAN
370021 | PLAN
370028 | PLAN
370035 | PLAN
370042 | PLAN
370049 | PLAN
370056 | PLAN
370063 | PLAN
370070 | PLAN
370077 | PLAN
370084 | PLAN
370091 | PLAN
370098 | PLAN
370105 | PLAN
370112 | PLAN
370119 | PLAN
370126 | PLAN
370133 | PLAN
370140 | PLAN
370147 | PLAN
370154 | PLAN
370161 | PLAN
370168 | PLAN
370175 | PLAN
370182 | PLAN
370189 | PLAN
370196 | PLAN
370203 | PLAN
370210 | PLAN
370217 | PLAN
370224 | PLAN
370231 | PLAN
370238 | PLAN
370245 | PLAN
370252 | PLAN
370259 | PLAN
370266 | PLAN
370273 | PLAN
370280 | PLAN
370287 | PLAN
370294 | PLAN
370301 | PLAN
370308 | PLAN
370315 | PLAN
370322 | PLAN
370329 | PLAN
370336 | PLAN
370343 | PLAN
370350 | PLAN
370357 | PLAN
370364 | PLAN
370371 | PLAN
370378 | PLAN
370385 | PLAN
370392 | PLAN
370399 | PLAN
370406 | PLAN
370413 | PLAN
370420 | PLAN
370427 | PLAN
370434 | PLAN
370441 | PLAN
370448 | PLAN
370455 | PLAN
370462 | PLAN
370469 | PLAN
370476 | PLAN
370483 | PLAN
370490 | PLAN
370497 | PLAN
370504 | PLAN
370511 | PLAN
370518 | PLAN
370525 | PLAN
370532 | PLAN
370539 | PLAN
370546 | PLAN
370553 | PLAN
370560 | PLAN
370567 | PLAN
370574 | PLAN
370581 | PLAN
370588 | PLAN
370595 | PLAN
370602 | PLAN
370609 | PLAN
370616 | PLAN
370623 | PLAN
370630 | PLAN
370637 | PLAN
370644 | PLAN
370651 | PLAN
370658 | PLAN
370665 | PLAN
370672 | PLAN
370679 | PLAN
370686 | PLAN
370693 | PLAN
370700 | PLAN
370707 | PLAN
370714 | PLAN
370721 | PLAN
370728 | PLAN
370735 | PLAN
370742 | PLAN
370749 | PLAN
370756 | PLAN
370763 | PLAN
370770 | PLAN
370777 | PLAN
370784 | PLAN
370791 | PLAN
370798 | PLAN
370805 | PLAN
370812 | PLAN
370819 | PLAN
370826 | PLAN
370833 | PLAN
370840 | PLAN
370847 | PLAN
370854 | PLAN
370861 | PLAN
370868 | PLAN
370875 | PLAN
370882 | PLAN
370889 | PLAN
370896 | PLAN
370903 | PLAN
370910 | PLAN
370917 | PLAN
370924 | PLAN
370931 | PLAN
370938 | PLAN
370945 | PLAN
370952 | PLAN
370959 | PLAN
370966 | PLAN
370973 | PLAN
370980 | PLAN
370987 | PLAN
370994 | PLAN
371001 | PLAN
371008 | PLAN
371015 | PLAN
371022 | PLAN
371029 | PLAN
371036 | PLAN
371043 | PLAN
371050 | PLAN
371057 | PLAN
371064 | PLAN
371071 | PLAN
371078 | PLAN
371085 | PLAN
371092 | PLAN
371099 | PLAN
371106 | PLAN
371113 | PLAN
371120 | PLAN
371127 | PLAN
371134 | PLAN
371141 | PLAN
371148 | PLAN
371155 | PLAN
371162 | PLAN
371169 | PLAN
371176 | PLAN
371183 | PLAN
371190 | PLAN
371199 | PLAN
371206 | PLAN
371213 | PLAN
371220 | PLAN
371227 | PLAN
371234 | PLAN
371241 | PLAN
371248 | PLAN
371255 | PLAN
371262 | PLAN
371269 | PLAN
371276 | PLAN
371283 | PLAN
371290 | PLAN
371297 | PLAN
371304 | PLAN
371311 | PLAN
371318 | PLAN
371325 | PLAN
371332 | PLAN
371339 | PLAN
371346 | PLAN
371353 | PLAN
371360 | PLAN
371367 | PLAN
371374 | PLAN
371381 | PLAN
371388 | PLAN
371395 | PLAN
371402 | PLAN
371409 | PLAN
371416 | PLAN
371423 | PLAN
371430 | PLAN
371437 | PLAN
371444 | PLAN
371451 | PLAN
371458 | PLAN
371465 | PLAN
371472 | PLAN
371479 | PLAN
371486 | PLAN
371493 | PLAN
371500 | PLAN
371507 | PLAN
371514 | PLAN
371521 | PLAN
371528 | PLAN
371535 | PLAN
371542 | PLAN
371549 | PLAN
371556 | PLAN
371563 | PLAN
371570 | PLAN
371577 | PLAN
371584 | PLAN
371591 | PLAN
371598 | PLAN
371605 | PLAN
371612 | PLAN
371619 | PLAN
371626 | PLAN
371633 | PLAN
371640 | PLAN
371647 | PLAN
371654 | PLAN
371661 | PLAN
371668 | PLAN
371675 | PLAN
371682 | PLAN
371689 | PLAN
371696 | PLAN
371703 | PLAN
371710 | PLAN
371717 | PLAN
371724 | PLAN
371731 | PLAN
371738 | PLAN
371745 | PLAN
371752 | PLAN
371759 | PLAN
371766 | PLAN
371773 | PLAN
371780 | PLAN
371787 | PLAN
371794 | PLAN
371801 | PLAN
371808 | PLAN
371815 | PLAN
371822 | PLAN
371829 | PLAN
371836 | PLAN
371843 | PLAN
371850 | PLAN
371857 | PLAN
371864 | PLAN
371871 | PLAN
371878 | PLAN
371885 | PLAN
371892 | PLAN
371899 | PLAN
371906 | PLAN
371913 | PLAN
371920 | PLAN
371927 | PLAN
371934 | PLAN
371941 | PLAN
371948 | PLAN
371955 | PLAN
371962 | PLAN
371969 | PLAN
371976 | PLAN
371983 | PLAN
371990 | PLAN
371997 | PLAN
372004 | PLAN
372011 | PLAN
372018 | PLAN
372025 | PLAN
372032 | PLAN
372039 | PLAN
372046 | PLAN
372053 | PLAN
372060 | PLAN
372067 | PLAN
372074 | PLAN
372081 | PLAN
372088 | PLAN
372095 | PLAN
372102 | PLAN
372109 | PLAN
372116 | PLAN
372123 | PLAN
372130 | PLAN
372137 | PLAN
372144 | PLAN
372151 | PLAN
372158 | PLAN
372165 | PLAN
372172 | PLAN
372179 | PLAN
372186 | PLAN
372193 | PLAN
372200 | PLAN
372207 | PLAN
372214 | PLAN
372221 | PLAN
372228 | PLAN
372235 | PLAN
372242 | PLAN
372249 | PLAN
372256 | PLAN
372263 | PLAN
372270 | PLAN
372277 | PLAN
372284 | PLAN
372291 | PLAN
372298 | PLAN
372305 | PLAN
372312 | PLAN
372319 | PLAN
372326 | PLAN
372333 | PLAN
372340 | PLAN
372347 | PLAN
372354 | PLAN
372361 | PLAN
372368 | PLAN
372375 | PLAN
372382 | PLAN
372389 | PLAN
372396 | PLAN
372403 | PLAN
372410 | PLAN
372417 | PLAN
372424 | PLAN
372431 | PLAN
372438 | PLAN
372445 | PLAN
372452 | PLAN
372459 | PLAN
372466 | PLAN
372473 | PLAN
372480 | PLAN
372487 | PLAN
372494 | PLAN
372501 | PLAN
372508 | PLAN
372515 | PLAN
372522 | PLAN
372529 | PLAN
372536 | PLAN
372543 | PLAN
372550 | PLAN
372557 | PLAN
372564 | PLAN
372571 | PLAN
372578 | PLAN
372585 | PLAN
372592 | PLAN
372599 | PLAN
372606 | PLAN
372613 | PLAN
372620 | PLAN
372627 | PLAN
372634 | PLAN
372641 | PLAN
372648 | PLAN
372655 | PLAN
372662 | PLAN
372669 | PLAN
372676 | PLAN
372683 | PLAN
372690 | PLAN
372697 | PLAN
372704 | PLAN
372711 | PLAN
372718 | PLAN
372725 | PLAN
372732 | PLAN
372739 | PLAN
372746 | PLAN
372753 | PLAN
372760 | PLAN
372767 | PLAN
372774 | PLAN
372781 | PLAN
372788 | PLAN
372795 | PLAN
372802 | PLAN
372809 | PLAN
372816 | PLAN
372823 | PLAN
372830 | PLAN
372837 | PLAN
372844 | PLAN
372851 | PLAN
372858 | PLAN
372865 | PLAN
372872 | PLAN
372879 | PLAN
372886 | PLAN
372893 | PLAN
372900 | PLAN
372907 | PLAN
372914 | PLAN
372921 | PLAN
372928 | PLAN
372935 | PLAN
372942 | PLAN
372949 | PLAN
372956 | PLAN
372963 | PLAN
372970 | PLAN
372977 | PLAN
372984 | PLAN
372991 | PLAN
372998 | PLAN
373005 | PLAN
373012 | PLAN
373019 | PLAN
373026 | PLAN
373033 | PLAN
373040 | PLAN
373047 | PLAN
373054 | PLAN
373061 | PLAN
373068 | PLAN
373075 | PLAN
373082 | PLAN
373089 | PLAN
373096 | PLAN
373103 | PLAN
373110 | PLAN
373117 | PLAN
373124 | PLAN
373131 | PLAN
373138 | PLAN
373145 | PLAN
373152 | PLAN
373159 | PLAN
373166 | PLAN
373173 | PLAN
373180 | PLAN
373187 | PLAN
373194 | PLAN
373201 | PLAN
373208 | PLAN
373215 | PLAN
373222 | PLAN
373229 | PLAN
373236 | PLAN
373243 | PLAN
373250 | PLAN
373257 | PLAN
373264 | PLAN
373271 | PLAN
373278 | PLAN
373285 | PLAN
373292 | PLAN
373299 | PLAN
373306 | PLAN
373313 | PLAN
373320 | PLAN
373327 | PLAN
373334 | PLAN
373341 | PLAN
373348 | PLAN
373355 | PLAN
373362 | PLAN
373369 | PLAN
373376 | PLAN
373383 | PLAN
373390 | PLAN
373397 | PLAN
373404 | PLAN
373411 | PLAN
373418 | PLAN
373425 | PLAN
373432 | PLAN
373439 | PLAN
373446 | PLAN
373453 | PLAN
373460 | PLAN
373467 | PLAN
373474 | PLAN
373481 | PLAN
373488 | PLAN
373495 | PLAN
373502 | PLAN
373509 | PLAN
373516 | PLAN
373523 | PLAN
373530 | PLAN
373537 | PLAN
373544 | PLAN
373551 | PLAN
373558 | PLAN
373565 | PLAN
373572 | PLAN
373579 | PLAN
373586 | PLAN
373593 | PLAN
373600 | PLAN
373607 | PLAN
373614 | PLAN
373621 | PLAN
373630 | PLAN
373637 | PLAN
373644 | PLAN
373651 | PLAN
373658 | PLAN
373665 | PLAN
373672 | PLAN
373679 | PLAN
373686 | PLAN
373693 | PLAN
373700 | PLAN
373707 | PLAN
373714 | PLAN
373721 | PLAN
373728 | PLAN
373735 | PLAN
373742 | PLAN
373749 | PLAN
373756 | PLAN
373763 | PLAN
373770 | PLAN
373777 | PLAN
373784 | PLAN
373791 | PLAN
373798 | PLAN
373805 | PLAN
373812 | PLAN
373819 | PLAN
373826 | PLAN
373833 | PLAN
373840 | PLAN
373847 | PLAN
373854 | PLAN
373861 | PLAN
373868 | PLAN
373875 | PLAN
373882 | PLAN
373889 | PLAN
373896 | PLAN
373903 | PLAN
373910 | PLAN
373917 | PLAN
373924 | PLAN
373931 | PLAN
373938 | PLAN
373945 | PLAN
373952 | PLAN
373959 | PLAN
373966 | PLAN
373973 | PLAN
373980 | PLAN
373987 | PLAN
373994 | PLAN
374001 | PLAN
374008 | PLAN
374015 | PLAN
374022 | PLAN
374029 | PLAN
374036 | PLAN
374043 | PLAN
374050 | PLAN
374057 | PLAN
374064 | PLAN
374071 | PLAN
374078 | PLAN
374085 | PLAN
374092 | PLAN
374099 | PLAN
374106 | PLAN
374113 | PLAN
374120 | PLAN
374127 | PLAN
374134 | PLAN
374141 | PLAN
374148 | PLAN
374155 | PLAN
374162 | PLAN
374169 | PLAN
374176 | PLAN
374183 | PLAN
374190 | PLAN
374197 | PLAN
374204 | PLAN
374211 | PLAN
374218 | PLAN
374225 | PLAN
374232 | PLAN
374239 | PLAN
374246 | PLAN
374253 | PLAN
374260 | PLAN
374267 | PLAN
374274 | PLAN
374281 | PLAN
374288 | PLAN
374295 | PLAN
374302 | PLAN
374309 | PLAN
374316 | PLAN
374323 | PLAN
374330 | PLAN
374337 | PLAN
374344 | PLAN
374351 | PLAN
374358 | PLAN
374365 | PLAN
374372 | PLAN
374379 | PLAN
374386 | PLAN
374393 | PLAN
374400 | PLAN
374407 | PLAN
374414 | PLAN
374421 | PLAN
374428 | PLAN
374435 | PLAN
374442 | PLAN
374449 | PLAN
374456 | PLAN
374463 | PLAN
374470 | PLAN
374477 | PLAN
374484 | PLAN
374491 | PLAN
374498 | PLAN
374505 | PLAN
374512 | PLAN
374519 | PLAN
374526 | PLAN
374533 | PLAN
374540 | PLAN
374547 | PLAN
374554 | PLAN
374561 | PLAN
374568 | PLAN
374575 | PLAN
374582 | PLAN
374589 | PLAN
374596 | PLAN
374603 | PLAN
374610 | PLAN
374617 | PLAN
374624 | PLAN
374631 | PLAN
374638 | PLAN
374645 | PLAN
374652 | PLAN
374659 | PLAN
374666 | PLAN
374673 | PLAN
374680 | PLAN
374687 | PLAN
374694 | PLAN
374701 | PLAN
374708 | PLAN
374715 | PLAN
374722 | PLAN
374729 | PLAN
374736 | PLAN
374743 | PLAN
374750 | PLAN
374757 | PLAN
374764 | PLAN
374771 | PLAN
374778 | PLAN
374785 | PLAN
374792 | PLAN
374799 | PLAN
374806 | PLAN
374813 | PLAN
374820 | PLAN
374827 | PLAN
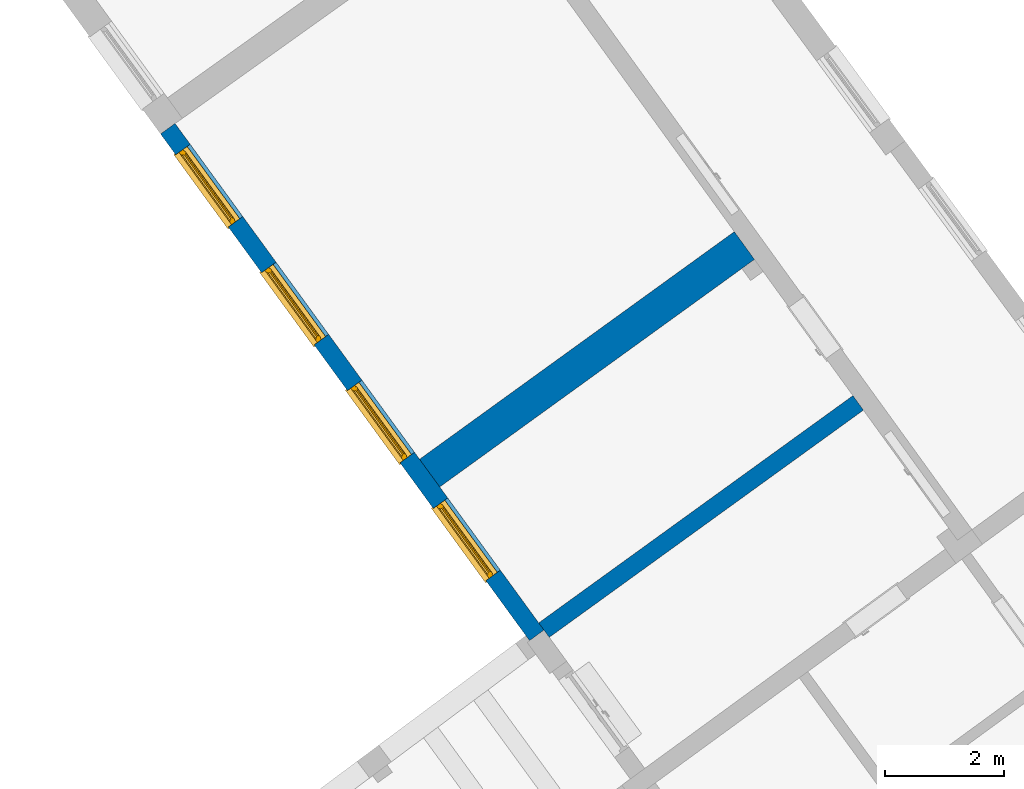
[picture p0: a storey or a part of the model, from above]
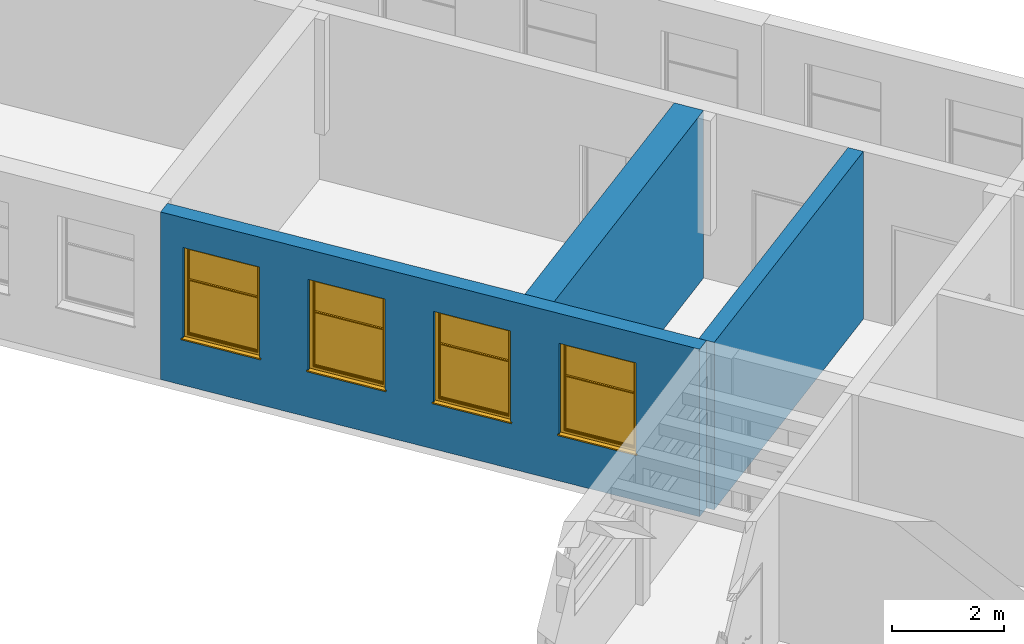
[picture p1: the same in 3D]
Properties of the parts of a building model (IFC2X3), part 8 of 13

# IfcSlab: Floor:Slab-179:1000 (17048)
Name (Floor:Slab-179:1000:...) | In
374834 | PLAN
374841 | PLAN
374848 | PLAN
374855 | PLAN
374862 | PLAN
374869 | PLAN
374876 | PLAN
374883 | PLAN
374890 | PLAN
374897 | PLAN
374904 | PLAN
374911 | PLAN
374918 | PLAN
374925 | PLAN
374932 | PLAN
374939 | PLAN
374946 | PLAN
374953 | PLAN
374960 | PLAN
374967 | PLAN
374974 | PLAN
374981 | PLAN
374988 | PLAN
374995 | PLAN
375002 | PLAN
375009 | PLAN
375016 | PLAN
375023 | PLAN
375030 | PLAN
375037 | PLAN
375044 | PLAN
375051 | PLAN
375058 | PLAN
375065 | PLAN
375072 | PLAN
375079 | PLAN
375086 | PLAN
375093 | PLAN
375100 | PLAN
375107 | PLAN
375114 | PLAN
375121 | PLAN
375128 | PLAN
375135 | PLAN
375142 | PLAN
375149 | PLAN
375156 | PLAN
375163 | PLAN
375170 | PLAN
375177 | PLAN
375184 | PLAN
375191 | PLAN
375198 | PLAN
375205 | PLAN
375212 | PLAN
375219 | PLAN
375226 | PLAN
375233 | PLAN
375240 | PLAN
375247 | PLAN
375254 | PLAN
375261 | PLAN
375268 | PLAN
375275 | PLAN
375282 | PLAN
375289 | PLAN
375296 | PLAN
375303 | PLAN
375310 | PLAN
375317 | PLAN
375324 | PLAN
375331 | PLAN
375338 | PLAN
375345 | PLAN
375352 | PLAN
375359 | PLAN
375366 | PLAN
375373 | PLAN
375380 | PLAN
375387 | PLAN
375394 | PLAN
375401 | PLAN
375408 | PLAN
375415 | PLAN
375422 | PLAN
375429 | PLAN
375436 | PLAN
375443 | PLAN
375450 | PLAN
375457 | PLAN
375464 | PLAN
375471 | PLAN
375478 | PLAN
375485 | PLAN
375492 | PLAN
375499 | PLAN
375506 | PLAN
375513 | PLAN
375520 | PLAN
375527 | PLAN
375534 | PLAN
375541 | PLAN
375548 | PLAN
375555 | PLAN
375562 | PLAN
375569 | PLAN
375576 | PLAN
375583 | PLAN
375590 | PLAN
375597 | PLAN
375604 | PLAN
375611 | PLAN
375618 | PLAN
375625 | PLAN
375632 | PLAN
375639 | PLAN
375646 | PLAN
375653 | PLAN
375660 | PLAN
375667 | PLAN
375674 | PLAN
375681 | PLAN
375688 | PLAN
375695 | PLAN
375702 | PLAN
375709 | PLAN
375716 | PLAN
375723 | PLAN
375730 | PLAN
375737 | PLAN
375744 | PLAN
375751 | PLAN
375758 | PLAN
375765 | PLAN
375772 | PLAN
375779 | PLAN
375786 | PLAN
375793 | PLAN
375800 | PLAN
375807 | PLAN
375814 | PLAN
375821 | PLAN
375828 | PLAN
375835 | PLAN
375842 | PLAN
375849 | PLAN
375856 | PLAN
375863 | PLAN
375870 | PLAN
375877 | PLAN
375884 | PLAN
375891 | PLAN
375898 | PLAN
375905 | PLAN
375912 | PLAN
375919 | PLAN
375926 | PLAN
375933 | PLAN
375940 | PLAN
375947 | PLAN
375954 | PLAN
375961 | PLAN
375968 | PLAN
375975 | PLAN
375982 | PLAN
375989 | PLAN
375996 | PLAN
376003 | PLAN
376010 | PLAN
376017 | PLAN
376024 | PLAN
376031 | PLAN
376038 | PLAN
376045 | PLAN
376052 | PLAN
376059 | PLAN
376066 | PLAN
376073 | PLAN
376080 | PLAN
376087 | PLAN
376094 | PLAN
376101 | PLAN
376108 | PLAN
376115 | PLAN
376122 | PLAN
376129 | PLAN
376136 | PLAN
376143 | PLAN
376150 | PLAN
376157 | PLAN
376164 | PLAN
376171 | PLAN
376178 | PLAN
376185 | PLAN
376192 | PLAN
376199 | PLAN
376206 | PLAN
376213 | PLAN
376220 | PLAN
376227 | PLAN
376234 | PLAN
376241 | PLAN
376248 | PLAN
376255 | PLAN
376262 | PLAN
376269 | PLAN
376276 | PLAN
376283 | PLAN
376290 | PLAN
376297 | PLAN
376304 | PLAN
376311 | PLAN
376318 | PLAN
376325 | PLAN
376332 | PLAN
376339 | PLAN
376346 | PLAN
376353 | PLAN
376361 | PLAN
376368 | PLAN
376375 | PLAN
376382 | PLAN
376389 | PLAN
376396 | PLAN
376403 | PLAN
376410 | PLAN
376417 | PLAN
376424 | PLAN
376431 | PLAN
376438 | PLAN
376445 | PLAN
376452 | PLAN
376459 | PLAN
376466 | PLAN
376473 | PLAN
376480 | PLAN
376487 | PLAN
376494 | PLAN
376501 | PLAN
376508 | PLAN
376515 | PLAN
376522 | PLAN
376529 | PLAN
376536 | PLAN
376543 | PLAN
376550 | PLAN
376557 | PLAN
376564 | PLAN
376571 | PLAN
376578 | PLAN
376585 | PLAN
376592 | PLAN
376599 | PLAN
376606 | PLAN
376613 | PLAN
376620 | PLAN
376627 | PLAN
376634 | PLAN
376641 | PLAN
376648 | PLAN
376655 | PLAN
376662 | PLAN
376669 | PLAN
376676 | PLAN
376683 | PLAN
376690 | PLAN
376697 | PLAN
376704 | PLAN
376711 | PLAN
376718 | PLAN
376725 | PLAN
376732 | PLAN
376739 | PLAN
376746 | PLAN
376753 | PLAN
376760 | PLAN
376767 | PLAN
376774 | PLAN
376781 | PLAN
376788 | PLAN
376795 | PLAN
376802 | PLAN
376809 | PLAN
376816 | PLAN
376823 | PLAN
376830 | PLAN
376837 | PLAN
376844 | PLAN
376851 | PLAN
376858 | PLAN
376865 | PLAN
376872 | PLAN
376879 | PLAN
376886 | PLAN
376893 | PLAN
376900 | PLAN
376907 | PLAN
376914 | PLAN
376921 | PLAN
376928 | PLAN
376935 | PLAN
376942 | PLAN
376949 | PLAN
376956 | PLAN
376963 | PLAN
376970 | PLAN
376977 | PLAN
376984 | PLAN
376991 | PLAN
376998 | PLAN
377005 | PLAN
377012 | PLAN
377019 | PLAN
377026 | PLAN
377033 | PLAN
377040 | PLAN
377047 | PLAN
377054 | PLAN
377061 | PLAN
377068 | PLAN
377075 | PLAN
377082 | PLAN
377089 | PLAN
377096 | PLAN
377103 | PLAN
377110 | PLAN
377117 | PLAN
377124 | PLAN
377131 | PLAN
377138 | PLAN
377145 | PLAN
377152 | PLAN
377159 | PLAN
377166 | PLAN
377173 | PLAN
377180 | PLAN
377187 | PLAN
377194 | PLAN
377201 | PLAN
377208 | PLAN
377215 | PLAN
377222 | PLAN
377229 | PLAN
377236 | PLAN
377243 | PLAN
377250 | PLAN
377257 | PLAN
377264 | PLAN
377271 | PLAN
377278 | PLAN
377285 | PLAN
377292 | PLAN
377299 | PLAN
377306 | PLAN
377313 | PLAN
377320 | PLAN
377327 | PLAN
377334 | PLAN
377341 | PLAN
377348 | PLAN
377355 | PLAN
377362 | PLAN
377369 | PLAN
377376 | PLAN
377383 | PLAN
377390 | PLAN
377397 | PLAN
377404 | PLAN
377411 | PLAN
377418 | PLAN
377425 | PLAN
377432 | PLAN
377439 | PLAN
377446 | PLAN
377453 | PLAN
377460 | PLAN
377467 | PLAN
377475 | PLAN
377482 | PLAN
377489 | PLAN
377496 | PLAN
377503 | PLAN
377510 | PLAN
377520 | PLAN
377527 | PLAN
377534 | PLAN
377541 | PLAN
377548 | PLAN
377555 | PLAN
377562 | PLAN
377569 | PLAN
377576 | PLAN
377583 | PLAN
377590 | PLAN
377597 | PLAN
377604 | PLAN
377611 | PLAN
377618 | PLAN
377625 | PLAN
377632 | PLAN
377639 | PLAN
377646 | PLAN
377653 | PLAN
377660 | PLAN
377667 | PLAN
377674 | PLAN
377681 | PLAN
377688 | PLAN
377695 | PLAN
377702 | PLAN
377709 | PLAN
377716 | PLAN
377723 | PLAN
377730 | PLAN
377737 | PLAN
377744 | PLAN
377751 | PLAN
377758 | PLAN
377765 | PLAN
377772 | PLAN
377779 | PLAN
377786 | PLAN
377793 | PLAN
377800 | PLAN
377807 | PLAN
377814 | PLAN
377821 | PLAN
377828 | PLAN
377835 | PLAN
377842 | PLAN
377849 | PLAN
377856 | PLAN
377863 | PLAN
377870 | PLAN
377877 | PLAN
377884 | PLAN
377891 | PLAN
377898 | PLAN
377905 | PLAN
377912 | PLAN
377919 | PLAN
377926 | PLAN
377933 | PLAN
377940 | PLAN
377947 | PLAN
377954 | PLAN
377961 | PLAN
377968 | PLAN
377975 | PLAN
377982 | PLAN
377989 | PLAN
377996 | PLAN
378003 | PLAN
378010 | PLAN
378017 | PLAN
378024 | PLAN
378031 | PLAN
378038 | PLAN
378045 | PLAN
378052 | PLAN
378059 | PLAN
378066 | PLAN
378073 | PLAN
378080 | PLAN
378087 | PLAN
378094 | PLAN
378101 | PLAN
378108 | PLAN
378115 | PLAN
378122 | PLAN
378129 | PLAN
378136 | PLAN
378143 | PLAN
378150 | PLAN
378157 | PLAN
378164 | PLAN
378171 | PLAN
378178 | PLAN
378185 | PLAN
378192 | PLAN
378199 | PLAN
378206 | PLAN
378213 | PLAN
378220 | PLAN
378227 | PLAN
378234 | PLAN
378241 | PLAN
378248 | PLAN
378255 | PLAN
378262 | PLAN
378269 | PLAN
378276 | PLAN
378283 | PLAN
378290 | PLAN
378297 | PLAN
378304 | PLAN
378311 | PLAN
378318 | PLAN
378325 | PLAN
378332 | PLAN
378339 | PLAN
378346 | PLAN
378353 | PLAN
378360 | PLAN
378367 | PLAN
378374 | PLAN
378381 | PLAN
378388 | PLAN
378395 | PLAN
378402 | PLAN
378409 | PLAN
378416 | PLAN
378423 | PLAN
378430 | PLAN
378437 | PLAN
378444 | PLAN
378451 | PLAN
378458 | PLAN
378465 | PLAN
378472 | PLAN
378479 | PLAN
378486 | PLAN
378493 | PLAN
378500 | PLAN
378507 | PLAN
378514 | PLAN
378521 | PLAN
378528 | PLAN
378535 | PLAN
378542 | PLAN
378549 | PLAN
378556 | PLAN
378563 | PLAN
378570 | PLAN
378577 | PLAN
378584 | PLAN
378591 | PLAN
378598 | PLAN
378605 | PLAN
378612 | PLAN
378619 | PLAN
378626 | PLAN
378633 | PLAN
378640 | PLAN
378647 | PLAN
378654 | PLAN
378661 | PLAN
378668 | PLAN
378675 | PLAN
378682 | PLAN
378689 | PLAN
378696 | PLAN
378703 | PLAN
378710 | PLAN
378717 | PLAN
378724 | PLAN
378731 | PLAN
378738 | PLAN
378745 | PLAN
378752 | PLAN
378759 | PLAN
378766 | PLAN
378773 | PLAN
378780 | PLAN
378787 | PLAN
378794 | PLAN
378801 | PLAN
378808 | PLAN
378815 | PLAN
378822 | PLAN
378829 | PLAN
378836 | PLAN
378843 | PLAN
378850 | PLAN
378857 | PLAN
378864 | PLAN
378871 | PLAN
378878 | PLAN
378885 | PLAN
378892 | PLAN
378899 | PLAN
378906 | PLAN
378913 | PLAN
378920 | PLAN
378927 | PLAN
378934 | PLAN
378941 | PLAN
378948 | PLAN
378955 | PLAN
378962 | PLAN
378969 | PLAN
378976 | PLAN
378983 | PLAN
378990 | PLAN
378997 | PLAN
379004 | PLAN
379011 | PLAN
379018 | PLAN
379025 | PLAN
379032 | PLAN
379039 | PLAN
379046 | PLAN
379053 | PLAN
379060 | PLAN
379067 | PLAN
379074 | PLAN
379081 | PLAN
379088 | PLAN
379095 | PLAN
379102 | PLAN
379109 | PLAN
379116 | PLAN
379123 | PLAN
379130 | PLAN
379137 | PLAN
379144 | PLAN
379151 | PLAN
379158 | PLAN
379165 | PLAN
379172 | PLAN
379179 | PLAN
379186 | PLAN
379193 | PLAN
379200 | PLAN
379207 | PLAN
379214 | PLAN
379221 | PLAN
379228 | PLAN
379235 | PLAN
379242 | PLAN
379249 | PLAN
379256 | PLAN
379263 | PLAN
379270 | PLAN
379277 | PLAN
379284 | PLAN
379291 | PLAN
379298 | PLAN
379305 | PLAN
379312 | PLAN
379319 | PLAN
379326 | PLAN
379333 | PLAN
379340 | PLAN
379347 | PLAN
379354 | PLAN
379361 | PLAN
379368 | PLAN
379375 | PLAN
379382 | PLAN
379389 | PLAN
379396 | PLAN
379403 | PLAN
379410 | PLAN
379417 | PLAN
379424 | PLAN
379431 | PLAN
379438 | PLAN
379445 | PLAN
379452 | PLAN
379459 | PLAN
379466 | PLAN
379473 | PLAN
379480 | PLAN
379487 | PLAN
379494 | PLAN
379501 | PLAN
379508 | PLAN
379515 | PLAN
379522 | PLAN
379529 | PLAN
379536 | PLAN
379543 | PLAN
379550 | PLAN
379557 | PLAN
379564 | PLAN
379571 | PLAN
379578 | PLAN
379585 | PLAN
379592 | PLAN
379599 | PLAN
379606 | PLAN
379613 | PLAN
379620 | PLAN
379627 | PLAN
379634 | PLAN
379641 | PLAN
379648 | PLAN
379655 | PLAN
379662 | PLAN
379669 | PLAN
379676 | PLAN
379684 | PLAN
379691 | PLAN
379698 | PLAN
379705 | PLAN
379713 | PLAN
379720 | PLAN
379727 | PLAN
379734 | PLAN
379741 | PLAN
379748 | PLAN
379755 | PLAN
379762 | PLAN
379769 | PLAN
379776 | PLAN
379783 | PLAN
379790 | PLAN
379797 | PLAN
379804 | PLAN
379811 | PLAN
379818 | PLAN
379826 | PLAN
379833 | PLAN
379840 | PLAN
379847 | PLAN
379854 | PLAN
379861 | PLAN
379868 | PLAN
379875 | PLAN
379882 | PLAN
379889 | PLAN
379896 | PLAN
379903 | PLAN
379910 | PLAN
379917 | PLAN
379924 | PLAN
379931 | PLAN
379938 | PLAN
379945 | PLAN
379952 | PLAN
379959 | PLAN
379966 | PLAN
379973 | PLAN
379980 | PLAN
379987 | PLAN
379994 | PLAN
380001 | PLAN
380008 | PLAN
380015 | PLAN
380022 | PLAN
380029 | PLAN
380036 | PLAN
380043 | PLAN
380050 | PLAN
380057 | PLAN
380064 | PLAN
380071 | PLAN
380078 | PLAN
380085 | PLAN
380092 | PLAN
380099 | PLAN
380106 | PLAN
380113 | PLAN
380120 | PLAN
380127 | PLAN
380134 | PLAN
380141 | PLAN
380148 | PLAN
380155 | PLAN
380162 | PLAN
380169 | PLAN
380176 | PLAN
380183 | PLAN
380190 | PLAN
380197 | PLAN
380204 | PLAN
380211 | PLAN
380218 | PLAN
380225 | PLAN
380232 | PLAN
380239 | PLAN
380246 | PLAN
380253 | PLAN
380260 | PLAN
380267 | PLAN
380274 | PLAN
380281 | PLAN
380288 | PLAN
380295 | PLAN
380302 | PLAN
380309 | PLAN
380316 | PLAN
380323 | PLAN
380330 | PLAN
380337 | PLAN
380344 | PLAN
380351 | PLAN
380358 | PLAN
380365 | PLAN
380372 | PLAN
380379 | PLAN
380386 | PLAN
380393 | PLAN
380400 | PLAN
380407 | PLAN
380414 | PLAN
380421 | PLAN
380428 | PLAN
380435 | PLAN
380442 | PLAN
380449 | PLAN
380456 | PLAN
380463 | PLAN
380470 | PLAN
380477 | PLAN
380484 | PLAN
380491 | PLAN
380498 | PLAN
380505 | PLAN
380512 | PLAN
380519 | PLAN
380526 | PLAN
380533 | PLAN
380540 | PLAN
380547 | PLAN
380554 | PLAN
380561 | PLAN
380568 | PLAN
380575 | PLAN
380582 | PLAN
380589 | PLAN
380596 | PLAN
380603 | PLAN
380610 | PLAN
380617 | PLAN
380624 | PLAN
380631 | PLAN
380638 | PLAN
380645 | PLAN
380652 | PLAN
380659 | PLAN
380666 | PLAN
380673 | PLAN
380680 | PLAN
380687 | PLAN
380694 | PLAN
380701 | PLAN
380708 | PLAN
380715 | PLAN
380722 | PLAN
380729 | PLAN
380736 | PLAN
380743 | PLAN
380750 | PLAN
380757 | PLAN
380764 | PLAN
380771 | PLAN
380778 | PLAN
380785 | PLAN
380792 | PLAN
380799 | PLAN
380806 | PLAN
380813 | PLAN
380820 | PLAN
380827 | PLAN
380834 | PLAN
380841 | PLAN
380848 | PLAN
380855 | PLAN
380862 | PLAN
380869 | PLAN
380876 | PLAN
380883 | PLAN
380890 | PLAN
380897 | PLAN
380904 | PLAN
380911 | PLAN
380918 | PLAN
380925 | PLAN
380932 | PLAN
380939 | PLAN
380946 | PLAN
380953 | PLAN
380960 | PLAN
380967 | PLAN
380974 | PLAN
380981 | PLAN
380988 | PLAN
380995 | PLAN
381002 | PLAN
381009 | PLAN
381016 | PLAN
381023 | PLAN
381030 | PLAN
381037 | PLAN
381044 | PLAN
381051 | PLAN
381058 | PLAN
381065 | PLAN
381072 | PLAN
381080 | PLAN
381088 | PLAN
381095 | PLAN
381102 | PLAN
381109 | PLAN
381116 | PLAN
381123 | PLAN
381130 | PLAN
381137 | PLAN
381144 | PLAN
381151 | PLAN
381158 | PLAN
381165 | PLAN
381172 | PLAN
381179 | PLAN
381186 | PLAN
381193 | PLAN
381200 | PLAN
381207 | PLAN
381214 | PLAN
381221 | PLAN
381228 | PLAN
381235 | PLAN
381242 | PLAN
381249 | PLAN
381256 | PLAN
381263 | PLAN
381270 | PLAN
381277 | PLAN
381284 | PLAN
381291 | PLAN
381298 | PLAN
381305 | PLAN
381312 | PLAN
381319 | PLAN
381326 | PLAN
381333 | PLAN
381340 | PLAN
381347 | PLAN
381354 | PLAN
381361 | PLAN
381368 | PLAN
381375 | PLAN
381382 | PLAN
381389 | PLAN
381396 | PLAN
381403 | PLAN
381410 | PLAN
381417 | PLAN
381424 | PLAN
381431 | PLAN
381438 | PLAN
381445 | PLAN
381452 | PLAN
381459 | PLAN
381466 | PLAN
381473 | PLAN
381480 | PLAN
381487 | PLAN
381494 | PLAN
381501 | PLAN
381508 | PLAN
381515 | PLAN
381522 | PLAN
381529 | PLAN
381536 | PLAN
381543 | PLAN
381550 | PLAN
381557 | PLAN
381564 | PLAN
381571 | PLAN
381578 | PLAN
381585 | PLAN
381592 | PLAN
381599 | PLAN
381606 | PLAN
381613 | PLAN
381620 | PLAN
381627 | PLAN
381634 | PLAN
381641 | PLAN
381648 | PLAN
381655 | PLAN
381662 | PLAN
381669 | PLAN
381676 | PLAN
381683 | PLAN
381690 | PLAN
381697 | PLAN
381704 | PLAN
381711 | PLAN
381718 | PLAN
381725 | PLAN
381732 | PLAN
381739 | PLAN
381746 | PLAN
381753 | PLAN
381760 | PLAN
381767 | PLAN
381774 | PLAN
381781 | PLAN
381788 | PLAN
381795 | PLAN
381802 | PLAN
381809 | PLAN
381816 | PLAN
381823 | PLAN
381830 | PLAN
381837 | PLAN
381844 | PLAN
381851 | PLAN
381858 | PLAN
381865 | PLAN
381872 | PLAN
381879 | PLAN
381886 | PLAN
381893 | PLAN
381900 | PLAN
381907 | PLAN
381914 | PLAN
381921 | PLAN
381928 | PLAN
381935 | PLAN
381942 | PLAN
381949 | PLAN
381956 | PLAN
381963 | PLAN
381970 | PLAN
381977 | PLAN
381984 | PLAN
381991 | PLAN
381998 | PLAN
382005 | PLAN
382012 | PLAN
382019 | PLAN
382026 | PLAN
382033 | PLAN
382040 | PLAN
382047 | PLAN
382054 | PLAN
382061 | PLAN
382068 | PLAN
382075 | PLAN
382082 | PLAN
382089 | PLAN
382096 | PLAN
382103 | PLAN
382110 | PLAN
382117 | PLAN
382124 | PLAN
382131 | PLAN
382138 | PLAN
382145 | PLAN
382152 | PLAN
382159 | PLAN
382166 | PLAN
382173 | PLAN
382180 | PLAN
382187 | PLAN
382194 | PLAN
382201 | PLAN
382208 | PLAN
382215 | PLAN
382222 | PLAN
382229 | PLAN
382236 | PLAN
382243 | PLAN
382250 | PLAN
382257 | PLAN
382264 | PLAN
382271 | PLAN
382278 | PLAN
382285 | PLAN
382292 | PLAN
382299 | PLAN
382306 | PLAN
382313 | PLAN
382320 | PLAN
382327 | PLAN
382334 | PLAN
382341 | PLAN
382348 | PLAN
382355 | PLAN
382362 | PLAN
382369 | PLAN
382376 | PLAN
382383 | PLAN
382390 | PLAN
382397 | PLAN
382404 | PLAN
382411 | PLAN
382418 | PLAN
382425 | PLAN
382432 | PLAN
382439 | PLAN
382446 | PLAN
382453 | PLAN
382460 | PLAN
382467 | PLAN
382474 | PLAN
382481 | PLAN
382488 | PLAN
382495 | PLAN
382502 | PLAN
382509 | PLAN
382516 | PLAN
382523 | PLAN
382530 | PLAN
382537 | PLAN
382544 | PLAN
382551 | PLAN
382558 | PLAN
382565 | PLAN
382572 | PLAN
382579 | PLAN
382586 | PLAN
382593 | PLAN
382600 | PLAN
382607 | PLAN
382614 | PLAN
382621 | PLAN
382628 | PLAN
382635 | PLAN
382642 | PLAN
382649 | PLAN
382656 | PLAN
382663 | PLAN
382670 | PLAN
382677 | PLAN
382684 | PLAN
382691 | PLAN
382698 | PLAN
382705 | PLAN
382712 | PLAN
382719 | PLAN
382726 | PLAN
382733 | PLAN
382740 | PLAN
382747 | PLAN
382754 | PLAN
382761 | PLAN
382768 | PLAN
382775 | PLAN
382782 | PLAN
382789 | PLAN
382796 | PLAN
382803 | PLAN
382810 | PLAN
382817 | PLAN
382824 | PLAN
382831 | PLAN
382838 | PLAN
382845 | PLAN
382852 | PLAN
382859 | PLAN
382866 | PLAN
382873 | PLAN
382880 | PLAN
382887 | PLAN
382894 | PLAN
382901 | PLAN
382908 | PLAN
382915 | PLAN
382922 | PLAN
382929 | PLAN
382936 | PLAN
382943 | PLAN
382950 | PLAN
382957 | PLAN
382964 | PLAN
382971 | PLAN
382978 | PLAN
382985 | PLAN
382992 | PLAN
382999 | PLAN
383006 | PLAN
383013 | PLAN
383020 | PLAN
383027 | PLAN
383034 | PLAN
383041 | PLAN
383048 | PLAN
383055 | PLAN
383062 | PLAN
383069 | PLAN
383076 | PLAN
383083 | PLAN
383090 | PLAN
383097 | PLAN
383104 | PLAN
383111 | PLAN
383118 | PLAN
383125 | PLAN
383132 | PLAN
383139 | PLAN
383146 | PLAN
383153 | PLAN
383160 | PLAN
383167 | PLAN
383174 | PLAN
383181 | PLAN
383188 | PLAN
383195 | PLAN
383202 | PLAN
383209 | PLAN
383216 | PLAN
383223 | PLAN
383230 | PLAN
383237 | PLAN
383244 | PLAN
383251 | PLAN
383258 | PLAN
383265 | PLAN
383272 | PLAN
383279 | PLAN
383286 | PLAN
383293 | PLAN
383300 | PLAN
383307 | PLAN
383314 | PLAN
383321 | PLAN
383328 | PLAN
383335 | PLAN
383342 | PLAN
383349 | PLAN
383356 | PLAN
383363 | PLAN
383370 | PLAN
383377 | PLAN
383384 | PLAN
383391 | PLAN
383398 | PLAN
383405 | PLAN
383412 | PLAN
383419 | PLAN
383426 | PLAN
383433 | PLAN
383440 | PLAN
383447 | PLAN
383454 | PLAN
383461 | PLAN
383468 | PLAN
383475 | PLAN
383482 | PLAN
383489 | PLAN
383496 | PLAN
383503 | PLAN
383510 | PLAN
383517 | PLAN
383524 | PLAN
383531 | PLAN
383538 | PLAN
383545 | PLAN
383552 | PLAN
383559 | PLAN
383566 | PLAN
383573 | PLAN
383580 | PLAN
383587 | PLAN
383594 | PLAN
383601 | PLAN
383608 | PLAN
383615 | PLAN
383622 | PLAN
383629 | PLAN
383636 | PLAN
383643 | PLAN
383650 | PLAN
383657 | PLAN
383664 | PLAN
383671 | PLAN
383678 | PLAN
383685 | PLAN
383692 | PLAN
383699 | PLAN
383706 | PLAN
383713 | PLAN
383720 | PLAN
383727 | PLAN
383734 | PLAN
383741 | PLAN
383748 | PLAN
383755 | PLAN
383762 | PLAN
383769 | PLAN
383776 | PLAN
383783 | PLAN
383790 | PLAN
383797 | PLAN
383804 | PLAN
383811 | PLAN
383818 | PLAN
383825 | PLAN
383832 | PLAN
383839 | PLAN
383846 | PLAN
383853 | PLAN
383860 | PLAN
383867 | PLAN
383874 | PLAN
383881 | PLAN
383888 | PLAN
383895 | PLAN
383902 | PLAN
383909 | PLAN
383916 | PLAN
383923 | PLAN
383930 | PLAN
383937 | PLAN
383944 | PLAN
383951 | PLAN
383958 | PLAN
383965 | PLAN
383972 | PLAN
383979 | PLAN
383986 | PLAN
383993 | PLAN
384000 | PLAN
384007 | PLAN
384014 | PLAN
384021 | PLAN
384028 | PLAN
384035 | PLAN
384042 | PLAN
384049 | PLAN
384056 | PLAN
384063 | PLAN
384070 | PLAN
384077 | PLAN
384084 | PLAN
384091 | PLAN
384098 | PLAN
384105 | PLAN
384112 | PLAN
384119 | PLAN
384126 | PLAN
384133 | PLAN
384140 | PLAN
384147 | PLAN
384154 | PLAN
384161 | PLAN
384168 | PLAN
384175 | PLAN
384182 | PLAN
384189 | PLAN
384196 | PLAN
384203 | PLAN
384210 | PLAN
384217 | PLAN
384224 | PLAN
384231 | PLAN
384238 | PLAN
384245 | PLAN
384252 | PLAN
384259 | PLAN
384266 | PLAN
384273 | PLAN
384280 | PLAN
384287 | PLAN
384294 | PLAN
384301 | PLAN
384308 | PLAN
384315 | PLAN
384322 | PLAN
384329 | PLAN
384336 | PLAN
384343 | PLAN
384350 | PLAN
384357 | PLAN
384364 | PLAN
384371 | PLAN
384378 | PLAN
384385 | PLAN
384392 | PLAN
384399 | PLAN
384406 | PLAN
384413 | PLAN
384420 | PLAN
384427 | PLAN
384434 | PLAN
384441 | PLAN
384448 | PLAN
384455 | PLAN
384462 | PLAN
384469 | PLAN
384476 | PLAN
384483 | PLAN
384490 | PLAN
384497 | PLAN
384504 | PLAN
384511 | PLAN
384518 | PLAN
384525 | PLAN
384532 | PLAN
384539 | PLAN
384546 | PLAN
384553 | PLAN
384560 | PLAN
384567 | PLAN
384574 | PLAN
384581 | PLAN
384588 | PLAN
384595 | PLAN
384602 | PLAN
384609 | PLAN
384616 | PLAN
384623 | PLAN
384630 | PLAN
384637 | PLAN
384644 | PLAN
384651 | PLAN
384658 | PLAN
384665 | PLAN
384672 | PLAN
384679 | PLAN
384686 | PLAN
384693 | PLAN
384700 | PLAN
384707 | PLAN
384714 | PLAN
384721 | PLAN
384728 | PLAN
384735 | PLAN
384742 | PLAN
384749 | PLAN
384756 | PLAN
384763 | PLAN
384770 | PLAN
384777 | PLAN
384784 | PLAN
384791 | PLAN
384798 | PLAN
384805 | PLAN
384812 | PLAN
384819 | PLAN
384826 | PLAN
384833 | PLAN
384840 | PLAN
384847 | PLAN
384854 | PLAN
384861 | PLAN
384868 | PLAN
384875 | PLAN
384882 | PLAN
384889 | PLAN
384896 | PLAN
384903 | PLAN
384910 | PLAN
384917 | PLAN
384924 | PLAN
384931 | PLAN
384938 | PLAN
384945 | PLAN
384952 | PLAN
384959 | PLAN
384966 | PLAN
384973 | PLAN
384980 | PLAN
384987 | PLAN
384994 | PLAN
385001 | PLAN
385008 | PLAN
385015 | PLAN
385022 | PLAN
385029 | PLAN
385036 | PLAN
385043 | PLAN
385050 | PLAN
385057 | PLAN
385064 | PLAN
385071 | PLAN
385078 | PLAN
385085 | PLAN
385092 | PLAN
385099 | PLAN
385106 | PLAN
385113 | PLAN
385120 | PLAN
385127 | PLAN
385134 | PLAN
385141 | PLAN
385148 | PLAN
385155 | PLAN
385162 | PLAN
385169 | PLAN
385176 | PLAN
385183 | PLAN
385190 | PLAN
385197 | PLAN
385204 | PLAN
385211 | PLAN
385218 | PLAN
385225 | PLAN
385232 | PLAN
385239 | PLAN
385246 | PLAN
385253 | PLAN
385260 | PLAN
385267 | PLAN
385274 | PLAN
385281 | PLAN
385288 | PLAN
385295 | PLAN
385302 | PLAN
385309 | PLAN
385316 | PLAN
385323 | PLAN
385330 | PLAN
385337 | PLAN
385344 | PLAN
385351 | PLAN
385358 | PLAN
385365 | PLAN
385372 | PLAN
385379 | PLAN
385386 | PLAN
385393 | PLAN
385400 | PLAN
385407 | PLAN
385414 | PLAN
385421 | PLAN
385428 | PLAN
385435 | PLAN
385442 | PLAN
385449 | PLAN
385456 | PLAN
385463 | PLAN
385470 | PLAN
385477 | PLAN
385484 | PLAN
385491 | PLAN
385498 | PLAN
385505 | PLAN
385512 | PLAN
385519 | PLAN
385526 | PLAN
385533 | PLAN
385540 | PLAN
385547 | PLAN
385554 | PLAN
385561 | PLAN
385568 | PLAN
385575 | PLAN
385582 | PLAN
385589 | PLAN
385596 | PLAN
385603 | PLAN
385610 | PLAN
385617 | PLAN
385624 | PLAN
385631 | PLAN
385638 | PLAN
385645 | PLAN
385652 | PLAN
385659 | PLAN
385666 | PLAN
385673 | PLAN
385680 | PLAN
385687 | PLAN
385694 | PLAN
385701 | PLAN
385708 | PLAN
385715 | PLAN
385722 | PLAN
385729 | PLAN
385736 | PLAN
385743 | PLAN
385750 | PLAN
385757 | PLAN
385764 | PLAN
385771 | PLAN
385778 | PLAN
385785 | PLAN
385792 | PLAN
385799 | PLAN
385806 | PLAN
385813 | PLAN
385820 | PLAN
385827 | PLAN
385834 | PLAN
385841 | PLAN
385848 | PLAN
385855 | PLAN
385862 | PLAN
385869 | PLAN
385876 | PLAN
385883 | PLAN
385890 | PLAN
385897 | PLAN
385904 | PLAN
385911 | PLAN
385918 | PLAN
385925 | PLAN
385932 | PLAN
385939 | PLAN
385946 | PLAN
385953 | PLAN
385960 | PLAN
385967 | PLAN
385974 | PLAN
385981 | PLAN
385988 | PLAN
385995 | PLAN
386002 | PLAN
386009 | PLAN
386016 | PLAN
386023 | PLAN
386030 | PLAN
386037 | PLAN
386044 | PLAN
386051 | PLAN
386058 | PLAN
386065 | PLAN
386072 | PLAN
386079 | PLAN
386086 | PLAN
386093 | PLAN
386100 | PLAN
386107 | PLAN
386114 | PLAN
386121 | PLAN
386128 | PLAN
386135 | PLAN
386142 | PLAN
386149 | PLAN
386156 | PLAN
386163 | PLAN
386170 | PLAN
386177 | PLAN
386184 | PLAN
386191 | PLAN
386198 | PLAN
386205 | PLAN
386212 | PLAN
386219 | PLAN
386226 | PLAN
386233 | PLAN
386240 | PLAN
386247 | PLAN
386254 | PLAN
386261 | PLAN
386268 | PLAN
386275 | PLAN
386282 | PLAN
386289 | PLAN
386296 | PLAN
386303 | PLAN
386310 | PLAN
386317 | PLAN
386324 | PLAN
386331 | PLAN
386338 | PLAN
386345 | PLAN
386352 | PLAN
386359 | PLAN
386366 | PLAN
386373 | PLAN
386380 | PLAN
386387 | PLAN
386394 | PLAN
386401 | PLAN
386408 | PLAN
386415 | PLAN
386422 | PLAN
386429 | PLAN
386436 | PLAN
386443 | PLAN
386450 | PLAN
386457 | PLAN
386464 | PLAN
386471 | PLAN
386478 | PLAN
386485 | PLAN
386492 | PLAN
386499 | PLAN
386506 | PLAN
386513 | PLAN
386520 | PLAN
386527 | PLAN
386534 | PLAN
386541 | PLAN
386548 | PLAN
386555 | PLAN
386562 | PLAN
386569 | PLAN
386576 | PLAN
386583 | PLAN
386590 | PLAN
386597 | PLAN
386604 | PLAN
386611 | PLAN
386618 | PLAN
386625 | PLAN
386632 | PLAN
386639 | PLAN
386646 | PLAN
386653 | PLAN
386660 | PLAN
386667 | PLAN
386674 | PLAN
386681 | PLAN
386688 | PLAN
386695 | PLAN
386702 | PLAN
386709 | PLAN
386716 | PLAN
386723 | PLAN
386730 | PLAN
386737 | PLAN
386744 | PLAN
386751 | PLAN
386758 | PLAN
386765 | PLAN
386772 | PLAN
386779 | PLAN
386786 | PLAN
386793 | PLAN
386800 | PLAN
386807 | PLAN
386814 | PLAN
386821 | PLAN
386828 | PLAN
386835 | PLAN
386842 | PLAN
386849 | PLAN
386856 | PLAN
386863 | PLAN
386870 | PLAN
386877 | PLAN
386884 | PLAN
386891 | PLAN
386898 | PLAN
386905 | PLAN
386912 | PLAN
386919 | PLAN
386926 | PLAN
386933 | PLAN
386940 | PLAN
386947 | PLAN
386954 | PLAN
386961 | PLAN
386968 | PLAN
386975 | PLAN
386982 | PLAN
386989 | PLAN
386996 | PLAN
387003 | PLAN
387010 | PLAN
387017 | PLAN
387024 | PLAN
387031 | PLAN
387038 | PLAN
387045 | PLAN
387052 | PLAN
387059 | PLAN
387066 | PLAN
387073 | PLAN
387080 | PLAN
387087 | PLAN
387094 | PLAN
387101 | PLAN
387108 | PLAN
387115 | PLAN
387122 | PLAN
387129 | PLAN
387136 | PLAN
387143 | PLAN
387150 | PLAN
387157 | PLAN
387164 | PLAN
387171 | PLAN
387178 | PLAN
387185 | PLAN
387192 | PLAN
387199 | PLAN
387206 | PLAN
387213 | PLAN
387220 | PLAN
387227 | PLAN
387234 | PLAN
387241 | PLAN
387248 | PLAN
387255 | PLAN
387262 | PLAN
387269 | PLAN
387276 | PLAN
387283 | PLAN
387290 | PLAN
387297 | PLAN
387304 | PLAN
387311 | PLAN
387318 | PLAN
387325 | PLAN
387332 | PLAN
387339 | PLAN
387346 | PLAN
387353 | PLAN
387360 | PLAN
387367 | PLAN
387374 | PLAN
387381 | PLAN
387388 | PLAN
387395 | PLAN
387402 | PLAN
387409 | PLAN
387416 | PLAN
387423 | PLAN
387430 | PLAN
387437 | PLAN
387444 | PLAN
387451 | PLAN
387458 | PLAN
387465 | PLAN
387472 | PLAN
387479 | PLAN
387486 | PLAN
387493 | PLAN
387500 | PLAN
387507 | PLAN
387514 | PLAN
387521 | PLAN
387528 | PLAN
387535 | PLAN
387542 | PLAN
387549 | PLAN
387556 | PLAN
387563 | PLAN
387570 | PLAN
387577 | PLAN
387584 | PLAN
387591 | PLAN
387598 | PLAN
387605 | PLAN
387612 | PLAN
387619 | PLAN
387626 | PLAN
387633 | PLAN
387640 | PLAN
387647 | PLAN
387654 | PLAN
387661 | PLAN
387668 | PLAN
387675 | PLAN
387682 | PLAN
387689 | PLAN
387696 | PLAN
387703 | PLAN
387710 | PLAN
387717 | PLAN
387724 | PLAN
387731 | PLAN
387738 | PLAN
387745 | PLAN
387752 | PLAN
387759 | PLAN
387766 | PLAN
387773 | PLAN
387780 | PLAN
387787 | PLAN
387794 | PLAN
387801 | PLAN
387808 | PLAN
387815 | PLAN
387822 | PLAN
387829 | PLAN
387836 | PLAN
387843 | PLAN
387850 | PLAN
387857 | PLAN
387864 | PLAN
387871 | PLAN
387878 | PLAN
387885 | PLAN
387892 | PLAN
387899 | PLAN
387906 | PLAN
387913 | PLAN
387920 | PLAN
387927 | PLAN
387934 | PLAN
387941 | PLAN
387948 | PLAN
387955 | PLAN
387962 | PLAN
387969 | PLAN
387976 | PLAN
387983 | PLAN
387990 | PLAN
387997 | PLAN
388004 | PLAN
388011 | PLAN
388018 | PLAN
388025 | PLAN
388032 | PLAN
388039 | PLAN
388046 | PLAN
388053 | PLAN
388060 | PLAN
388067 | PLAN
388074 | PLAN
388081 | PLAN
388088 | PLAN
388095 | PLAN
388102 | PLAN
388109 | PLAN
388116 | PLAN
388123 | PLAN
388130 | PLAN
388137 | PLAN
388144 | PLAN
388151 | PLAN
388158 | PLAN
388165 | PLAN
388172 | PLAN
388179 | PLAN
388186 | PLAN
388193 | PLAN
388200 | PLAN
388207 | PLAN
388214 | PLAN
388221 | PLAN
388228 | PLAN
388235 | PLAN
388242 | PLAN
388249 | PLAN
388256 | PLAN
388263 | PLAN
388270 | PLAN
388277 | PLAN
388284 | PLAN
388291 | PLAN
388298 | PLAN
388305 | PLAN
388312 | PLAN
388319 | PLAN
388326 | PLAN
388333 | PLAN
388340 | PLAN
388347 | PLAN
388354 | PLAN
388361 | PLAN
388368 | PLAN
388375 | PLAN
388382 | PLAN
388389 | PLAN
388396 | PLAN
388403 | PLAN
388410 | PLAN
388417 | PLAN
388424 | PLAN
388431 | PLAN
388438 | PLAN
388445 | PLAN
388452 | PLAN
388459 | PLAN
388466 | PLAN
388473 | PLAN
388480 | PLAN
388487 | PLAN
388494 | PLAN
388501 | PLAN
388508 | PLAN
388515 | PLAN
388522 | PLAN
388529 | PLAN
388536 | PLAN
388543 | PLAN
388550 | PLAN
388557 | PLAN
388564 | PLAN
388571 | PLAN
388578 | PLAN
388585 | PLAN
388592 | PLAN
388599 | PLAN
388606 | PLAN
388613 | PLAN
388620 | PLAN
388627 | PLAN
388634 | PLAN
388641 | PLAN
388648 | PLAN
388655 | PLAN
388662 | PLAN
388669 | PLAN
388676 | PLAN
388683 | PLAN
388690 | PLAN
388697 | PLAN
388704 | PLAN
388711 | PLAN
388718 | PLAN
388725 | PLAN
388732 | PLAN
388739 | PLAN
388746 | PLAN
388753 | PLAN
388760 | PLAN
388767 | PLAN
388774 | PLAN
388781 | PLAN
388788 | PLAN
388795 | PLAN
388802 | PLAN
388809 | PLAN
388816 | PLAN
388823 | PLAN
388830 | PLAN
388837 | PLAN
388844 | PLAN
388851 | PLAN
388858 | PLAN
388865 | PLAN
388872 | PLAN
388879 | PLAN
388886 | PLAN
388893 | PLAN
388900 | PLAN
388907 | PLAN
388914 | PLAN
388921 | PLAN
388928 | PLAN
388935 | PLAN
388942 | PLAN
388949 | PLAN
388956 | PLAN
388963 | PLAN
388970 | PLAN
388977 | PLAN
388984 | PLAN
388991 | PLAN
388998 | PLAN
389005 | PLAN
389012 | PLAN
389019 | PLAN
389026 | PLAN
389033 | PLAN
389040 | PLAN
389047 | PLAN
389054 | PLAN
389061 | PLAN
389068 | PLAN
389075 | PLAN
389082 | PLAN
389089 | PLAN
389096 | PLAN
389103 | PLAN
389110 | PLAN
389117 | PLAN
389124 | PLAN
389131 | PLAN
389138 | PLAN
389145 | PLAN
389152 | PLAN
389159 | PLAN
389166 | PLAN
389173 | PLAN
389180 | PLAN
389187 | PLAN
389194 | PLAN
389201 | PLAN
389208 | PLAN
389215 | PLAN
389222 | PLAN
389229 | PLAN
389236 | PLAN
389243 | PLAN
389250 | PLAN
389257 | PLAN
389264 | PLAN
389271 | PLAN
389278 | PLAN
389285 | PLAN
389292 | PLAN
389299 | PLAN
389306 | PLAN
389313 | PLAN
389320 | PLAN
389327 | PLAN
389334 | PLAN
389341 | PLAN
389348 | PLAN
389355 | PLAN
389362 | PLAN
389369 | PLAN
389376 | PLAN
389383 | PLAN
389390 | PLAN
389397 | PLAN
389404 | PLAN
389411 | PLAN
389418 | PLAN
389425 | PLAN
389432 | PLAN
389439 | PLAN
389446 | PLAN
389453 | PLAN
389460 | PLAN
389467 | PLAN
389474 | PLAN
389481 | PLAN
389488 | PLAN
389495 | PLAN
389502 | PLAN
389509 | PLAN
389516 | PLAN
389523 | PLAN
389530 | PLAN
389537 | PLAN
389544 | PLAN
389551 | PLAN
389558 | PLAN
389565 | PLAN
389572 | PLAN
389579 | PLAN
389586 | PLAN
389593 | PLAN
389600 | PLAN
389607 | PLAN
389614 | PLAN
389621 | PLAN
389628 | PLAN
389635 | PLAN
389642 | PLAN
389649 | PLAN
389656 | PLAN
389663 | PLAN
389670 | PLAN
389677 | PLAN
389684 | PLAN
389691 | PLAN
389698 | PLAN
389705 | PLAN
389712 | PLAN
389719 | PLAN
389726 | PLAN
389733 | PLAN
389740 | PLAN
389747 | PLAN
389754 | PLAN
389761 | PLAN
389768 | PLAN
389775 | PLAN
389782 | PLAN
389789 | PLAN
389796 | PLAN
389803 | PLAN
389810 | PLAN
389817 | PLAN
389824 | PLAN
389831 | PLAN
389838 | PLAN
389845 | PLAN
389852 | PLAN
389859 | PLAN
389866 | PLAN
389873 | PLAN
389880 | PLAN
389887 | PLAN
389894 | PLAN
389901 | PLAN
389908 | PLAN
389915 | PLAN
389922 | PLAN
389929 | PLAN
389936 | PLAN
389943 | PLAN
389950 | PLAN
389957 | PLAN
389964 | PLAN
389971 | PLAN
389978 | PLAN
389985 | PLAN
389992 | PLAN
389999 | PLAN
390006 | PLAN
390013 | PLAN
390020 | PLAN
390027 | PLAN
390034 | PLAN
390041 | PLAN
390048 | PLAN
390055 | PLAN
390062 | PLAN
390069 | PLAN
390076 | PLAN
390083 | PLAN
390090 | PLAN
390097 | PLAN
390104 | PLAN
390111 | PLAN
390118 | PLAN
390125 | PLAN
390132 | PLAN
390139 | PLAN
390146 | PLAN
390153 | PLAN
390160 | PLAN
390167 | PLAN
390174 | PLAN
390181 | PLAN
390188 | PLAN
390195 | PLAN
390202 | PLAN
390209 | PLAN
390216 | PLAN
390223 | PLAN
390230 | PLAN
390237 | PLAN
390244 | PLAN
390251 | PLAN
390258 | PLAN
390265 | PLAN
390272 | PLAN
390279 | PLAN
390286 | PLAN
390293 | PLAN
390300 | PLAN
390307 | PLAN
390314 | PLAN
390321 | PLAN
390328 | PLAN
390335 | PLAN
390342 | PLAN
390349 | PLAN
390356 | PLAN
390363 | PLAN
390370 | PLAN
390377 | PLAN
390384 | PLAN
390391 | PLAN
390398 | PLAN
390405 | PLAN
390412 | PLAN
390419 | PLAN
390426 | PLAN
390433 | PLAN
390440 | PLAN
390447 | PLAN
390454 | PLAN
390461 | PLAN
390468 | PLAN
390475 | PLAN
390482 | PLAN
390489 | PLAN
390496 | PLAN
390503 | PLAN
390510 | PLAN
390517 | PLAN
390524 | PLAN
390531 | PLAN
390538 | PLAN
390545 | PLAN
390552 | PLAN
390559 | PLAN
390566 | PLAN
390573 | PLAN
390580 | PLAN
390587 | PLAN
390594 | PLAN
390601 | PLAN
390608 | PLAN
390615 | PLAN
390622 | PLAN
390629 | PLAN
390636 | PLAN
390643 | PLAN
390650 | PLAN
390657 | PLAN
390664 | PLAN
390671 | PLAN
390678 | PLAN
390685 | PLAN
390692 | PLAN
390699 | PLAN
390706 | PLAN
390713 | PLAN
390720 | PLAN
390727 | PLAN
390734 | PLAN
390741 | PLAN
390748 | PLAN
390755 | PLAN
390762 | PLAN
390769 | PLAN
390776 | PLAN
390783 | PLAN
390790 | PLAN
390797 | PLAN
390804 | PLAN
390811 | PLAN
390818 | PLAN
390825 | PLAN
390832 | PLAN
390839 | PLAN
390846 | PLAN
390853 | PLAN
390860 | PLAN
390867 | PLAN
390874 | PLAN
390881 | PLAN
390888 | PLAN
390895 | PLAN
390902 | PLAN
390909 | PLAN
390916 | PLAN
390923 | PLAN
390930 | PLAN
390937 | PLAN
390944 | PLAN
390951 | PLAN
390958 | PLAN
390965 | PLAN
390972 | PLAN
390979 | PLAN
390986 | PLAN
390993 | PLAN
391000 | PLAN
391007 | PLAN
391014 | PLAN
391021 | PLAN
391028 | PLAN
391035 | PLAN
391042 | PLAN
391049 | PLAN
391056 | PLAN
391063 | PLAN
391070 | PLAN
391077 | PLAN
391084 | PLAN
391091 | PLAN
391098 | PLAN
391105 | PLAN
391112 | PLAN
391119 | PLAN
391126 | PLAN
391133 | PLAN
391140 | PLAN
391147 | PLAN
391154 | PLAN
391161 | PLAN
391168 | PLAN
391175 | PLAN
391182 | PLAN
391189 | PLAN
391196 | PLAN
391203 | PLAN
391210 | PLAN
391217 | PLAN
391224 | PLAN
391231 | PLAN
391238 | PLAN
391245 | PLAN
391252 | PLAN
391259 | PLAN
391266 | PLAN
391273 | PLAN
391280 | PLAN
391287 | PLAN
391294 | PLAN
391301 | PLAN
391308 | PLAN
391315 | PLAN
391322 | PLAN
391329 | PLAN
391336 | PLAN
391343 | PLAN
391350 | PLAN
391357 | PLAN
391364 | PLAN
391371 | PLAN
391378 | PLAN
391385 | PLAN
391392 | PLAN
391399 | PLAN
391406 | PLAN
391413 | PLAN
391420 | PLAN
391427 | PLAN
391434 | PLAN
391441 | PLAN
391448 | PLAN
391455 | PLAN
391462 | PLAN
391469 | PLAN
391476 | PLAN
391483 | PLAN
391490 | PLAN
391497 | PLAN
391504 | PLAN
391511 | PLAN
391518 | PLAN
391525 | PLAN
391532 | PLAN
391539 | PLAN
391546 | PLAN
391553 | PLAN
391560 | PLAN
391567 | PLAN
391574 | PLAN
391581 | PLAN
391588 | PLAN
391595 | PLAN
391602 | PLAN
391609 | PLAN
391616 | PLAN
391623 | PLAN
391630 | PLAN
391637 | PLAN
391644 | PLAN
391651 | PLAN
391658 | PLAN
391665 | PLAN
391672 | PLAN
391679 | PLAN
391686 | PLAN
391693 | PLAN
391700 | PLAN
391707 | PLAN
391714 | PLAN
391721 | PLAN
391728 | PLAN
391735 | PLAN
391742 | PLAN
391749 | PLAN
391756 | PLAN
391763 | PLAN
391770 | PLAN
391777 | PLAN
391784 | PLAN
391791 | PLAN
391798 | PLAN
391805 | PLAN
391812 | PLAN
391819 | PLAN
391826 | PLAN
391833 | PLAN
391840 | PLAN
391847 | PLAN
391854 | PLAN
391861 | PLAN
391868 | PLAN
391875 | PLAN
391882 | PLAN
391889 | PLAN
391896 | PLAN
391903 | PLAN
391910 | PLAN
391917 | PLAN
391924 | PLAN
391931 | PLAN
391938 | PLAN
391945 | PLAN
391952 | PLAN
391959 | PLAN
391966 | PLAN
391973 | PLAN
391980 | PLAN
391987 | PLAN
391994 | PLAN
392001 | PLAN
392008 | PLAN
392015 | PLAN
392022 | PLAN
392029 | PLAN
392036 | PLAN
392043 | PLAN
392050 | PLAN
392057 | PLAN
392064 | PLAN
392071 | PLAN
392078 | PLAN
392085 | PLAN
392092 | PLAN
392099 | PLAN
392106 | PLAN
392113 | PLAN
392120 | PLAN
392127 | PLAN
392134 | PLAN
392141 | PLAN
392148 | PLAN
392155 | PLAN
392162 | PLAN
392169 | PLAN
392176 | PLAN
392183 | PLAN
392190 | PLAN
392197 | PLAN
392204 | PLAN
392211 | PLAN
392218 | PLAN
392225 | PLAN
392232 | PLAN
392239 | PLAN
392246 | PLAN
392253 | PLAN
392260 | PLAN
392267 | PLAN
392274 | PLAN
392281 | PLAN
392288 | PLAN
392295 | PLAN
392302 | PLAN
392309 | PLAN
392316 | PLAN
392323 | PLAN
392330 | PLAN
392337 | PLAN
392344 | PLAN
392351 | PLAN
392358 | PLAN
392365 | PLAN
392372 | PLAN
392379 | PLAN
392386 | PLAN
392393 | PLAN
392400 | PLAN
392407 | PLAN
392414 | PLAN
392421 | PLAN
392428 | PLAN
392435 | PLAN
392442 | PLAN
392449 | PLAN
392456 | PLAN
392463 | PLAN
392470 | PLAN
392477 | PLAN
392484 | PLAN
392491 | PLAN
392498 | PLAN
392505 | PLAN
392512 | PLAN
392519 | PLAN
392526 | PLAN
392533 | PLAN
392540 | PLAN
392547 | PLAN
392554 | PLAN
392561 | PLAN
392568 | PLAN
392575 | PLAN
392582 | PLAN
392589 | PLAN
392596 | PLAN
392603 | PLAN
392610 | PLAN
392617 | PLAN
392624 | PLAN
392631 | PLAN
392638 | PLAN
392645 | PLAN
392652 | PLAN
392659 | PLAN
392666 | PLAN
392673 | PLAN
392680 | PLAN
392687 | PLAN
392694 | PLAN
392701 | PLAN
392708 | PLAN
392715 | PLAN
392722 | PLAN
392729 | PLAN
392736 | PLAN
392743 | PLAN
392750 | PLAN
392757 | PLAN
392764 | PLAN
392771 | PLAN
392778 | PLAN
392785 | PLAN
392792 | PLAN
392799 | PLAN
392806 | PLAN
392813 | PLAN
392820 | PLAN
392827 | PLAN
392834 | PLAN
392841 | PLAN
392848 | PLAN
392855 | PLAN
392862 | PLAN
392869 | PLAN
392876 | PLAN
392883 | PLAN
392890 | PLAN
392897 | PLAN
392904 | PLAN
392911 | PLAN
392918 | PLAN
392925 | PLAN
392932 | PLAN
392939 | PLAN
392946 | PLAN
392953 | PLAN
392960 | PLAN
392967 | PLAN
392974 | PLAN
392981 | PLAN
392988 | PLAN
392995 | PLAN
393002 | PLAN
393009 | PLAN
393016 | PLAN
393023 | PLAN
393030 | PLAN
393037 | PLAN
393044 | PLAN
393051 | PLAN
393058 | PLAN
393065 | PLAN
393072 | PLAN
393079 | PLAN
393086 | PLAN
393093 | PLAN
393100 | PLAN
393107 | PLAN
393114 | PLAN
393121 | PLAN
393128 | PLAN
393135 | PLAN
393142 | PLAN
393149 | PLAN
393156 | PLAN
393163 | PLAN
393170 | PLAN
393177 | PLAN
393184 | PLAN
393191 | PLAN
393198 | PLAN
393205 | PLAN
393212 | PLAN
393219 | PLAN
393226 | PLAN
393233 | PLAN
393240 | PLAN
393247 | PLAN
393254 | PLAN
393261 | PLAN
393268 | PLAN
393275 | PLAN
393282 | PLAN
393289 | PLAN
393296 | PLAN
393303 | PLAN
393310 | PLAN
393317 | PLAN
393324 | PLAN
393331 | PLAN
393338 | PLAN
393345 | PLAN
393352 | PLAN
393359 | PLAN
393366 | PLAN
393373 | PLAN
393380 | PLAN
393387 | PLAN
393394 | PLAN
393401 | PLAN
393408 | PLAN
393415 | PLAN
393422 | PLAN
393429 | PLAN
393436 | PLAN
393443 | PLAN
393450 | PLAN
393457 | PLAN
393464 | PLAN
393471 | PLAN
393478 | PLAN
393485 | PLAN
393492 | PLAN
393499 | PLAN
393506 | PLAN
393513 | PLAN
393520 | PLAN
393527 | PLAN
393534 | PLAN
393541 | PLAN
393548 | PLAN
393555 | PLAN
393562 | PLAN
393569 | PLAN
393576 | PLAN
393583 | PLAN
393590 | PLAN
393597 | PLAN
393604 | PLAN
393611 | PLAN
393618 | PLAN
393625 | PLAN
393632 | PLAN
393639 | PLAN
393646 | PLAN
393653 | PLAN
393660 | PLAN
393667 | PLAN
393674 | PLAN
393681 | PLAN
393688 | PLAN
393695 | PLAN
393702 | PLAN
393709 | PLAN
393716 | PLAN
393723 | PLAN
393730 | PLAN
393737 | PLAN
393744 | PLAN
393751 | PLAN
393758 | PLAN
393765 | PLAN
393772 | PLAN
393779 | PLAN
393786 | PLAN
393793 | PLAN
393800 | PLAN
393807 | PLAN
393814 | PLAN
393821 | PLAN
393828 | PLAN
393835 | PLAN
393842 | PLAN
393849 | PLAN
393856 | PLAN
393863 | PLAN
393870 | PLAN
393877 | PLAN
393884 | PLAN
393891 | PLAN
393898 | PLAN
393905 | PLAN
393912 | PLAN
393919 | PLAN
393926 | PLAN
393933 | PLAN
393940 | PLAN
393947 | PLAN
393954 | PLAN
393961 | PLAN
393968 | PLAN
393975 | PLAN
393982 | PLAN
393989 | PLAN
393996 | PLAN
394003 | PLAN
394010 | PLAN
394017 | PLAN
394024 | PLAN
394031 | PLAN
394038 | PLAN
394045 | PLAN
394052 | PLAN
394059 | PLAN
394066 | PLAN
394073 | PLAN
394080 | PLAN
394087 | PLAN
394094 | PLAN
394101 | PLAN
394108 | PLAN
394115 | PLAN
394122 | PLAN
394129 | PLAN
394136 | PLAN
394143 | PLAN
394150 | PLAN
394157 | PLAN
394164 | PLAN
394171 | PLAN
394178 | PLAN
394185 | PLAN
394192 | PLAN
394199 | PLAN
394206 | PLAN
394213 | PLAN
394220 | PLAN
394227 | PLAN
394234 | PLAN
394241 | PLAN
394248 | PLAN
394255 | PLAN
394262 | PLAN
394269 | PLAN
394276 | PLAN
394283 | PLAN
394290 | PLAN
394297 | PLAN
394304 | PLAN
394311 | PLAN
394318 | PLAN
394325 | PLAN
394332 | PLAN
394339 | PLAN
394346 | PLAN
394353 | PLAN
394360 | PLAN
394367 | PLAN
394374 | PLAN
394381 | PLAN
394388 | PLAN
394395 | PLAN
394402 | PLAN
394409 | PLAN
394416 | PLAN
394423 | PLAN
394430 | PLAN
394437 | PLAN
394444 | PLAN
394451 | PLAN
394458 | PLAN
394465 | PLAN
394472 | PLAN
394479 | PLAN
394486 | PLAN
394493 | PLAN
394500 | PLAN
394507 | PLAN
394514 | PLAN
394521 | PLAN
394528 | PLAN
394535 | PLAN
394542 | PLAN
394549 | PLAN
394556 | PLAN
394563 | PLAN
394570 | PLAN
394577 | PLAN
394584 | PLAN
394591 | PLAN
394598 | PLAN
394605 | PLAN
394612 | PLAN
394619 | PLAN
394626 | PLAN
394633 | PLAN
394640 | PLAN
394647 | PLAN
394654 | PLAN
394661 | PLAN
394668 | PLAN
394675 | PLAN
394682 | PLAN
394689 | PLAN
394696 | PLAN
394703 | PLAN
394710 | PLAN
394717 | PLAN
394724 | PLAN
394731 | PLAN
394738 | PLAN
394745 | PLAN
394752 | PLAN
394759 | PLAN
394766 | PLAN
394773 | PLAN
394780 | PLAN
394787 | PLAN
394794 | PLAN
394801 | PLAN
394808 | PLAN
394815 | PLAN
394822 | PLAN
394829 | PLAN
394836 | PLAN
394843 | PLAN
394850 | PLAN
394857 | PLAN
394864 | PLAN
394871 | PLAN
394878 | PLAN
394885 | PLAN
394892 | PLAN
394899 | PLAN
394906 | PLAN
394913 | PLAN
394920 | PLAN
394927 | PLAN
394934 | PLAN
394941 | PLAN
394948 | PLAN
394955 | PLAN
394962 | PLAN
394969 | PLAN
394976 | PLAN
394983 | PLAN
394990 | PLAN
394997 | PLAN
395004 | PLAN
395011 | PLAN
395018 | PLAN
395025 | PLAN
395032 | PLAN
395039 | PLAN
395046 | PLAN
395053 | PLAN
395060 | PLAN
395067 | PLAN
395074 | PLAN
395081 | PLAN
395088 | PLAN
395095 | PLAN
395102 | PLAN
395109 | PLAN
395116 | PLAN
395123 | PLAN
395130 | PLAN
395137 | PLAN
395144 | PLAN
395151 | PLAN
395158 | PLAN
395165 | PLAN
395172 | PLAN
395179 | PLAN
395186 | PLAN
395193 | PLAN
395200 | PLAN
395207 | PLAN
395214 | PLAN
395221 | PLAN
395228 | PLAN
395235 | PLAN
395242 | PLAN
395249 | PLAN
395256 | PLAN
395263 | PLAN
395270 | PLAN
395277 | PLAN
395284 | PLAN
395291 | PLAN
395298 | PLAN
395305 | PLAN
395312 | PLAN
395319 | PLAN
395326 | PLAN
395333 | PLAN
395340 | PLAN
395347 | PLAN
395354 | PLAN
395361 | PLAN
395368 | PLAN
395375 | PLAN
395382 | PLAN
395389 | PLAN
395396 | PLAN
395403 | PLAN
395410 | PLAN
395417 | PLAN
395424 | PLAN
395431 | PLAN
395438 | PLAN
395445 | PLAN
395452 | PLAN
395459 | PLAN
395466 | PLAN
395473 | PLAN
395480 | PLAN
395487 | PLAN
395494 | PLAN
395501 | PLAN
395508 | PLAN
395515 | PLAN
395522 | PLAN
395529 | PLAN
395536 | PLAN
395543 | PLAN
395550 | PLAN
395557 | PLAN
395564 | PLAN
395571 | PLAN
395578 | PLAN
395585 | PLAN
395592 | PLAN
395599 | PLAN
395606 | PLAN
395613 | PLAN
395620 | PLAN
395627 | PLAN
395634 | PLAN
395641 | PLAN
395648 | PLAN
395655 | PLAN
395662 | PLAN
395669 | PLAN
395676 | PLAN
395683 | PLAN
395690 | PLAN
395697 | PLAN
395704 | PLAN
395711 | PLAN
395718 | PLAN
395725 | PLAN
395732 | PLAN
395739 | PLAN
395746 | PLAN
395753 | PLAN
395760 | PLAN
395767 | PLAN
395774 | PLAN
395781 | PLAN
395788 | PLAN
395795 | PLAN
395802 | PLAN
395809 | PLAN
395816 | PLAN
395823 | PLAN
395830 | PLAN
395837 | PLAN
395844 | PLAN
395851 | PLAN
395858 | PLAN
395865 | PLAN
395872 | PLAN
395879 | PLAN
395886 | PLAN
395893 | PLAN
395900 | PLAN
395907 | PLAN
395914 | PLAN
395921 | PLAN
395928 | PLAN
395935 | PLAN
395942 | PLAN
395949 | PLAN
395956 | PLAN
395963 | PLAN
395970 | PLAN
395977 | PLAN
395984 | PLAN
395991 | PLAN
395998 | PLAN
396005 | PLAN
396012 | PLAN
396019 | PLAN
396026 | PLAN
396033 | PLAN
396040 | PLAN
396047 | PLAN
396054 | PLAN
396061 | PLAN
396068 | PLAN
396075 | PLAN
396082 | PLAN
396089 | PLAN
396096 | PLAN
396103 | PLAN
396110 | PLAN
396117 | PLAN
396124 | PLAN
396131 | PLAN
396138 | PLAN
396145 | PLAN
396152 | PLAN
396159 | PLAN
396166 | PLAN
396173 | PLAN
396180 | PLAN
396187 | PLAN
396194 | PLAN
396201 | PLAN
396208 | PLAN
396215 | PLAN
396222 | PLAN
396229 | PLAN
396236 | PLAN
396243 | PLAN
396250 | PLAN
396257 | PLAN
396264 | PLAN
396271 | PLAN
396278 | PLAN
396285 | PLAN
396292 | PLAN
396299 | PLAN
396306 | PLAN
396313 | PLAN
396320 | PLAN
396327 | PLAN
396334 | PLAN
396341 | PLAN
396348 | PLAN
396355 | PLAN
396362 | PLAN
396369 | PLAN
396376 | PLAN
396383 | PLAN
396390 | PLAN
396397 | PLAN
396404 | PLAN
396411 | PLAN
396418 | PLAN
396425 | PLAN
396432 | PLAN
396439 | PLAN
396446 | PLAN
396453 | PLAN
396460 | PLAN
396467 | PLAN
396474 | PLAN
396481 | PLAN
396488 | PLAN
396495 | PLAN
396502 | PLAN
396509 | PLAN
396516 | PLAN
396523 | PLAN
396530 | PLAN
396537 | PLAN
396544 | PLAN
396551 | PLAN
396558 | PLAN
396565 | PLAN
396572 | PLAN
396579 | PLAN
396586 | PLAN
396593 | PLAN
396600 | PLAN
396607 | PLAN
396614 | PLAN
396621 | PLAN
396628 | PLAN
396635 | PLAN
396642 | PLAN
396649 | PLAN
396656 | PLAN
396663 | PLAN
396670 | PLAN
396677 | PLAN
396684 | PLAN
396691 | PLAN
396698 | PLAN
396705 | PLAN
396712 | PLAN
396719 | PLAN
396726 | PLAN
396733 | PLAN
396740 | PLAN
396747 | PLAN
396754 | PLAN
396761 | PLAN
396768 | PLAN
396775 | PLAN
396782 | PLAN
396789 | PLAN
396796 | PLAN
396803 | PLAN
396810 | PLAN
396817 | PLAN
396824 | PLAN
396831 | PLAN
396838 | PLAN
396845 | PLAN
396852 | PLAN
396859 | PLAN
396866 | PLAN
396873 | PLAN
396880 | PLAN
396887 | PLAN
396894 | PLAN
396901 | PLAN
396908 | PLAN
396915 | PLAN
396922 | PLAN
396929 | PLAN
396936 | PLAN
396943 | PLAN
396950 | PLAN
396957 | PLAN
396964 | PLAN
396971 | PLAN
396978 | PLAN
396985 | PLAN
396992 | PLAN
396999 | PLAN
397006 | PLAN
397013 | PLAN
397020 | PLAN
397027 | PLAN
397034 | PLAN
397041 | PLAN
397048 | PLAN
397055 | PLAN
397062 | PLAN
397069 | PLAN
397076 | PLAN
397083 | PLAN
397090 | PLAN
397097 | PLAN
397104 | PLAN
397111 | PLAN
397118 | PLAN
397125 | PLAN
397132 | PLAN
397139 | PLAN
397146 | PLAN
397153 | PLAN
397160 | PLAN
397167 | PLAN
397174 | PLAN
397181 | PLAN
397188 | PLAN
397195 | PLAN
397202 | PLAN
397209 | PLAN
397216 | PLAN
397223 | PLAN
397230 | PLAN
397237 | PLAN
397244 | PLAN
397251 | PLAN
397258 | PLAN
397265 | PLAN
397272 | PLAN
397279 | PLAN
397286 | PLAN
397293 | PLAN
397300 | PLAN
397307 | PLAN
397314 | PLAN
397321 | PLAN
397328 | PLAN
397335 | PLAN
397342 | PLAN
397349 | PLAN
397356 | PLAN
397363 | PLAN
397370 | PLAN
397377 | PLAN
397384 | PLAN
397391 | PLAN
397398 | PLAN
397405 | PLAN
397412 | PLAN
397419 | PLAN
397426 | PLAN
397433 | PLAN
397440 | PLAN
397447 | PLAN
397454 | PLAN
397461 | PLAN
397468 | PLAN
397475 | PLAN
397482 | PLAN
397489 | PLAN
397496 | PLAN
397503 | PLAN
397510 | PLAN
397517 | PLAN
397524 | PLAN
397531 | PLAN
397538 | PLAN
397545 | PLAN
397552 | PLAN
397559 | PLAN
397566 | PLAN
397573 | PLAN
397580 | PLAN
397587 | PLAN
397594 | PLAN
397601 | PLAN
397608 | PLAN
397615 | PLAN
397622 | PLAN
397629 | PLAN
397636 | PLAN
397643 | PLAN
397650 | PLAN
397657 | PLAN
397664 | PLAN
397671 | PLAN
397678 | PLAN
397685 | PLAN
397692 | PLAN
397699 | PLAN
397706 | PLAN
397713 | PLAN
397720 | PLAN
397727 | PLAN
397734 | PLAN
397741 | PLAN
397748 | PLAN
397755 | PLAN
397762 | PLAN
397769 | PLAN
397776 | PLAN
397783 | PLAN
397790 | PLAN
397797 | PLAN
397804 | PLAN
397811 | PLAN
397818 | PLAN
397825 | PLAN
397832 | PLAN
397839 | PLAN
397846 | PLAN
397853 | PLAN
397860 | PLAN
397867 | PLAN
397874 | PLAN
397881 | PLAN
397888 | PLAN
397895 | PLAN
397902 | PLAN
397909 | PLAN
397916 | PLAN
397923 | PLAN
397930 | PLAN
397937 | PLAN
397944 | PLAN
397951 | PLAN
397958 | PLAN
397965 | PLAN
397972 | PLAN
397979 | PLAN
397986 | PLAN
397993 | PLAN
398000 | PLAN
398007 | PLAN
398014 | PLAN
398021 | PLAN
398028 | PLAN
398035 | PLAN
398042 | PLAN
398049 | PLAN
398056 | PLAN
398063 | PLAN
398070 | PLAN
398077 | PLAN
398084 | PLAN
398091 | PLAN
398098 | PLAN
398105 | PLAN
398112 | PLAN
398119 | PLAN
398126 | PLAN
398133 | PLAN
398140 | PLAN
398147 | PLAN
398154 | PLAN
398161 | PLAN
398168 | PLAN
398175 | PLAN
398182 | PLAN
398189 | PLAN
398196 | PLAN
398203 | PLAN
398210 | PLAN
398217 | PLAN
398224 | PLAN
398231 | PLAN
398238 | PLAN
398245 | PLAN
398252 | PLAN
398259 | PLAN
398266 | PLAN
398273 | PLAN
398280 | PLAN
398287 | PLAN
398294 | PLAN
398301 | PLAN
398308 | PLAN
398315 | PLAN
398322 | PLAN
398329 | PLAN
398336 | PLAN
398343 | PLAN
398350 | PLAN
398357 | PLAN
398364 | PLAN
398371 | PLAN
398378 | PLAN
398385 | PLAN
398392 | PLAN
398399 | PLAN
398406 | PLAN
398413 | PLAN
398420 | PLAN
398427 | PLAN
398434 | PLAN
398441 | PLAN
398448 | PLAN
398455 | PLAN
398462 | PLAN
398469 | PLAN
398476 | PLAN
398483 | PLAN
398490 | PLAN
398497 | PLAN
398504 | PLAN
398511 | PLAN
398518 | PLAN
398525 | PLAN
398532 | PLAN
398539 | PLAN
398546 | PLAN
398553 | PLAN
398560 | PLAN
398567 | PLAN
398574 | PLAN
398581 | PLAN
398588 | PLAN
398595 | PLAN
398602 | PLAN
398609 | PLAN
398616 | PLAN
398623 | PLAN
398630 | PLAN
398637 | PLAN
398644 | PLAN
398651 | PLAN
398658 | PLAN
398665 | PLAN
398672 | PLAN
398679 | PLAN
398686 | PLAN
398693 | PLAN
398700 | PLAN
398707 | PLAN
398714 | PLAN
398721 | PLAN
398728 | PLAN
398735 | PLAN
398742 | PLAN
398749 | PLAN
398756 | PLAN
398763 | PLAN
398770 | PLAN
398777 | PLAN
398784 | PLAN
398791 | PLAN
398798 | PLAN
398805 | PLAN
398812 | PLAN
398819 | PLAN
398826 | PLAN
398833 | PLAN
398840 | PLAN
398847 | PLAN
398854 | PLAN
398861 | PLAN
398868 | PLAN
398875 | PLAN
398882 | PLAN
398889 | PLAN
398896 | PLAN
398903 | PLAN
398910 | PLAN
398917 | PLAN
398924 | PLAN
398931 | PLAN
398938 | PLAN
398945 | PLAN
398952 | PLAN
398959 | PLAN
398966 | PLAN
398973 | PLAN
398980 | PLAN
398987 | PLAN
398994 | PLAN
399001 | PLAN
399008 | PLAN
399015 | PLAN
399022 | PLAN
399029 | PLAN
399036 | PLAN
399043 | PLAN
399050 | PLAN
399057 | PLAN
399064 | PLAN
399071 | PLAN
399078 | PLAN
399085 | PLAN
399092 | PLAN
399099 | PLAN
399106 | PLAN
399113 | PLAN
399120 | PLAN
399127 | PLAN
399134 | PLAN
399141 | PLAN
399148 | PLAN
399155 | PLAN
399162 | PLAN
399169 | PLAN
399176 | PLAN
399183 | PLAN
399190 | PLAN
399197 | PLAN
399204 | PLAN
399211 | PLAN
399218 | PLAN
399225 | PLAN
399232 | PLAN
399239 | PLAN
399246 | PLAN
399253 | PLAN
399260 | PLAN
399267 | PLAN
399274 | PLAN
399281 | PLAN
399288 | PLAN
399295 | PLAN
399302 | PLAN
399309 | PLAN
399316 | PLAN
399323 | PLAN
399330 | PLAN
399337 | PLAN
399344 | PLAN
399351 | PLAN
399358 | PLAN
399365 | PLAN
399372 | PLAN
399379 | PLAN
399386 | PLAN
399393 | PLAN
399400 | PLAN
399407 | PLAN
399414 | PLAN
399421 | PLAN
399428 | PLAN
399435 | PLAN
399442 | PLAN
399449 | PLAN
399456 | PLAN
399463 | PLAN
399470 | PLAN
399477 | PLAN
399484 | PLAN
399491 | PLAN
399498 | PLAN
399505 | PLAN
399512 | PLAN
399519 | PLAN
399526 | PLAN
399533 | PLAN
399540 | PLAN
399547 | PLAN
399554 | PLAN
399561 | PLAN
399568 | PLAN
399575 | PLAN
399582 | PLAN
399589 | PLAN
399596 | PLAN
399603 | PLAN
399610 | PLAN
399617 | PLAN
399624 | PLAN
399631 | PLAN
399638 | PLAN
399645 | PLAN
399652 | PLAN
399659 | PLAN
399666 | PLAN
399673 | PLAN
399680 | PLAN
399687 | PLAN
399694 | PLAN
399701 | PLAN
399708 | PLAN
399715 | PLAN
399722 | PLAN
399729 | PLAN
399736 | PLAN
399743 | PLAN
399750 | PLAN
399757 | PLAN
399764 | PLAN
399771 | PLAN
399778 | PLAN
399785 | PLAN
399792 | PLAN
399799 | PLAN
399806 | PLAN
399813 | PLAN
399820 | PLAN
399827 | PLAN
399834 | PLAN
399841 | PLAN
399848 | PLAN
399855 | PLAN
399862 | PLAN
399869 | PLAN
399876 | PLAN
399883 | PLAN
399890 | PLAN
399897 | PLAN
399904 | PLAN
399911 | PLAN
399918 | PLAN
399925 | PLAN
399932 | PLAN
399939 | PLAN
399946 | PLAN
399953 | PLAN
399960 | PLAN
399967 | PLAN
399974 | PLAN
399981 | PLAN
399988 | PLAN
399995 | PLAN
400002 | PLAN
400009 | PLAN
400016 | PLAN
400023 | PLAN
400030 | PLAN
400037 | PLAN
400044 | PLAN
400051 | PLAN
400058 | PLAN
400065 | PLAN
400072 | PLAN
400079 | PLAN
400086 | PLAN
400093 | PLAN
400100 | PLAN
400107 | PLAN
400114 | PLAN
400121 | PLAN
400128 | PLAN
400135 | PLAN
400142 | PLAN
400149 | PLAN
400156 | PLAN
400163 | PLAN
400170 | PLAN
400177 | PLAN
400184 | PLAN
400191 | PLAN
400198 | PLAN
400205 | PLAN
400212 | PLAN
400219 | PLAN
400226 | PLAN
400233 | PLAN
400240 | PLAN
400247 | PLAN
400254 | PLAN
400261 | PLAN
400268 | PLAN
400275 | PLAN
400282 | PLAN
400289 | PLAN
400296 | PLAN
400303 | PLAN
400310 | PLAN
400317 | PLAN
400324 | PLAN
400331 | PLAN
400338 | PLAN
400345 | PLAN
400352 | PLAN
400359 | PLAN
400366 | PLAN
400373 | PLAN
400380 | PLAN
400387 | PLAN
400394 | PLAN
400401 | PLAN
400408 | PLAN
400415 | PLAN
400422 | PLAN
400429 | PLAN
400436 | PLAN
400443 | PLAN
400450 | PLAN
400457 | PLAN
400464 | PLAN
400471 | PLAN
400478 | PLAN
400485 | PLAN
400492 | PLAN
400499 | PLAN
400506 | PLAN
400513 | PLAN
400520 | PLAN
400527 | PLAN
400534 | PLAN
400541 | PLAN
400548 | PLAN
400555 | PLAN
400562 | PLAN
400569 | PLAN
400576 | PLAN
400583 | PLAN
400590 | PLAN
400597 | PLAN
400604 | PLAN
400611 | PLAN
400618 | PLAN
400625 | PLAN
400632 | PLAN
400639 | PLAN
400646 | PLAN
400653 | PLAN
400660 | PLAN
400667 | PLAN
400674 | PLAN
400681 | PLAN
400688 | PLAN
400695 | PLAN
400702 | PLAN
400709 | PLAN
400716 | PLAN
400723 | PLAN
400730 | PLAN
400737 | PLAN
400744 | PLAN
400751 | PLAN
400758 | PLAN
400765 | PLAN
400772 | PLAN
400779 | PLAN
400786 | PLAN
400793 | PLAN
400800 | PLAN
400807 | PLAN
400814 | PLAN
400821 | PLAN
400828 | PLAN
400835 | PLAN
400842 | PLAN
400849 | PLAN
400856 | PLAN
400863 | PLAN
400870 | PLAN
400877 | PLAN
400884 | PLAN
400891 | PLAN
400898 | PLAN
400905 | PLAN
400912 | PLAN
400919 | PLAN
400926 | PLAN
400933 | PLAN
400940 | PLAN
400947 | PLAN
400954 | PLAN
400961 | PLAN
400968 | PLAN
400975 | PLAN
400982 | PLAN
400989 | PLAN
400996 | PLAN
401003 | PLAN
401010 | PLAN
401017 | PLAN
401024 | PLAN
401031 | PLAN
401038 | PLAN
401045 | PLAN
401052 | PLAN
401059 | PLAN
401066 | PLAN
401073 | PLAN
401080 | PLAN
401087 | PLAN
401094 | PLAN
401101 | PLAN
401108 | PLAN
401115 | PLAN
401122 | PLAN
401129 | PLAN
401136 | PLAN
401143 | PLAN
401150 | PLAN
401157 | PLAN
401164 | PLAN
401171 | PLAN
401178 | PLAN
401185 | PLAN
401192 | PLAN
401199 | PLAN
401206 | PLAN
401213 | PLAN
401220 | PLAN
401227 | PLAN
401234 | PLAN
401241 | PLAN
401248 | PLAN
401255 | PLAN
401262 | PLAN
401269 | PLAN
401276 | PLAN
401283 | PLAN
401290 | PLAN
401297 | PLAN
401304 | PLAN
401311 | PLAN
401318 | PLAN
401325 | PLAN
401332 | PLAN
401339 | PLAN
401346 | PLAN
401353 | PLAN
401360 | PLAN
401367 | PLAN
401374 | PLAN
401381 | PLAN
401388 | PLAN
401395 | PLAN
401402 | PLAN
401409 | PLAN
401416 | PLAN
401423 | PLAN
401430 | PLAN
401437 | PLAN
401444 | PLAN
401451 | PLAN
401458 | PLAN
401465 | PLAN
401472 | PLAN
401479 | PLAN
401486 | PLAN
401493 | PLAN
401500 | PLAN
401507 | PLAN
401514 | PLAN
401521 | PLAN
401528 | PLAN
401535 | PLAN
401542 | PLAN
401549 | PLAN
401556 | PLAN
401563 | PLAN
401570 | PLAN
401577 | PLAN
401584 | PLAN
401591 | PLAN
401598 | PLAN
401605 | PLAN
401612 | PLAN
401619 | PLAN
401626 | PLAN
401633 | PLAN
401640 | PLAN
401647 | PLAN
401654 | PLAN
401661 | PLAN
401668 | PLAN
401675 | PLAN
401682 | PLAN
401689 | PLAN
401696 | PLAN
401703 | PLAN
401710 | PLAN
401717 | PLAN
401724 | PLAN
401731 | PLAN
401738 | PLAN
401745 | PLAN
401752 | PLAN
401759 | PLAN
401766 | PLAN
401773 | PLAN
401780 | PLAN
401787 | PLAN
401794 | PLAN
401801 | PLAN
401808 | PLAN
401815 | PLAN
401822 | PLAN
401829 | PLAN
401836 | PLAN
401843 | PLAN
401850 | PLAN
401857 | PLAN
401864 | PLAN
401871 | PLAN
401878 | PLAN
401885 | PLAN
401892 | PLAN
401899 | PLAN
401906 | PLAN
401913 | PLAN
401920 | PLAN
401927 | PLAN
401934 | PLAN
401941 | PLAN
401948 | PLAN
401955 | PLAN
401962 | PLAN
401969 | PLAN
401976 | PLAN
401983 | PLAN
401990 | PLAN
401997 | PLAN
402004 | PLAN
402011 | PLAN
402018 | PLAN
402025 | PLAN
402032 | PLAN
402039 | PLAN
402046 | PLAN
402053 | PLAN
402060 | PLAN
402067 | PLAN
402074 | PLAN
402081 | PLAN
402088 | PLAN
402095 | PLAN
402102 | PLAN
402109 | PLAN
402116 | PLAN
402123 | PLAN
402130 | PLAN
402137 | PLAN
402144 | PLAN
402151 | PLAN
402158 | PLAN
402165 | PLAN
402172 | PLAN
402179 | PLAN
402186 | PLAN
402193 | PLAN
402200 | PLAN
402207 | PLAN
402214 | PLAN
402221 | PLAN
402228 | PLAN
402235 | PLAN
402242 | PLAN
402249 | PLAN
402256 | PLAN
402263 | PLAN
402270 | PLAN
402277 | PLAN
402284 | PLAN
402291 | PLAN
402298 | PLAN
402305 | PLAN
402312 | PLAN
402319 | PLAN
402326 | PLAN
402333 | PLAN
402340 | PLAN
402347 | PLAN
402354 | PLAN
402361 | PLAN
402368 | PLAN
402375 | PLAN
402382 | PLAN
402389 | PLAN
402396 | PLAN
402403 | PLAN
402410 | PLAN
402417 | PLAN
402424 | PLAN
402431 | PLAN
402438 | PLAN
402445 | PLAN
402452 | PLAN
402459 | PLAN
402466 | PLAN
402473 | PLAN
402480 | PLAN
402487 | PLAN
402494 | PLAN
402501 | PLAN
402508 | PLAN
402515 | PLAN
402522 | PLAN
402529 | PLAN
402536 | PLAN
402543 | PLAN
402550 | PLAN
402557 | PLAN
402564 | PLAN
402571 | PLAN
402578 | PLAN
402585 | PLAN
402592 | PLAN
402599 | PLAN
402606 | PLAN
402613 | PLAN
402620 | PLAN
402627 | PLAN
402634 | PLAN
402641 | PLAN
402648 | PLAN
402655 | PLAN
402662 | PLAN
402669 | PLAN
402676 | PLAN
402683 | PLAN
402690 | PLAN
402697 | PLAN
402704 | PLAN
402711 | PLAN
402718 | PLAN
402725 | PLAN
402732 | PLAN
402739 | PLAN
402746 | PLAN
402753 | PLAN
402760 | PLAN
402767 | PLAN
402774 | PLAN
402781 | PLAN
402788 | PLAN
402795 | PLAN
402802 | PLAN
402809 | PLAN
402816 | PLAN
402823 | PLAN
402830 | PLAN
402837 | PLAN
402844 | PLAN
402851 | PLAN
402858 | PLAN
402865 | PLAN
402872 | PLAN
402879 | PLAN
402886 | PLAN
402893 | PLAN
402900 | PLAN
402907 | PLAN
402914 | PLAN
402921 | PLAN
402928 | PLAN
402935 | PLAN
402942 | PLAN
402949 | PLAN
402956 | PLAN
402963 | PLAN
402970 | PLAN
402977 | PLAN
402984 | PLAN
402991 | PLAN
402998 | PLAN
403005 | PLAN
403012 | PLAN
403019 | PLAN
403026 | PLAN
403033 | PLAN
403040 | PLAN
403047 | PLAN
403054 | PLAN
403061 | PLAN
403068 | PLAN
403075 | PLAN
403082 | PLAN
403089 | PLAN
403096 | PLAN
403103 | PLAN
403110 | PLAN
403117 | PLAN
403124 | PLAN
403131 | PLAN
403138 | PLAN
403145 | PLAN
403152 | PLAN
403159 | PLAN
403166 | PLAN
403173 | PLAN
403180 | PLAN
403187 | PLAN
403194 | PLAN
403201 | PLAN
403208 | PLAN
403215 | PLAN
403222 | PLAN
403229 | PLAN
403236 | PLAN
403243 | PLAN
403250 | PLAN
403257 | PLAN
403264 | PLAN
403271 | PLAN
403278 | PLAN
403285 | PLAN
403292 | PLAN
403299 | PLAN
403306 | PLAN
403313 | PLAN
403320 | PLAN
403327 | PLAN
403334 | PLAN
403341 | PLAN
403348 | PLAN
403355 | PLAN
403362 | PLAN
403369 | PLAN
403376 | PLAN
403383 | PLAN
403390 | PLAN
403397 | PLAN
403404 | PLAN
403411 | PLAN
403418 | PLAN
403425 | PLAN
403432 | PLAN
403439 | PLAN
403446 | PLAN
403453 | PLAN
403460 | PLAN
403467 | PLAN
403474 | PLAN
403481 | PLAN
403488 | PLAN
403495 | PLAN
403502 | PLAN
403509 | PLAN
403516 | PLAN
403523 | PLAN
403530 | PLAN
403537 | PLAN
403544 | PLAN
403551 | PLAN
403558 | PLAN
403565 | PLAN
403572 | PLAN
403579 | PLAN
403586 | PLAN
403593 | PLAN
403600 | PLAN
403607 | PLAN
403614 | PLAN
403621 | PLAN
403628 | PLAN
403635 | PLAN
403642 | PLAN
403649 | PLAN
403656 | PLAN
403663 | PLAN
403670 | PLAN
403677 | PLAN
403684 | PLAN
403691 | PLAN
403698 | PLAN
403705 | PLAN
403712 | PLAN
403719 | PLAN
403726 | PLAN
403733 | PLAN
403740 | PLAN
403747 | PLAN
403754 | PLAN
403761 | PLAN
403768 | PLAN
403775 | PLAN
403782 | PLAN
403789 | PLAN
403796 | PLAN
403803 | PLAN
403810 | PLAN
403817 | PLAN
403824 | PLAN
403831 | PLAN
403838 | PLAN
403845 | PLAN
403852 | PLAN
403859 | PLAN
403866 | PLAN
403873 | PLAN
403880 | PLAN
403887 | PLAN
403894 | PLAN
403901 | PLAN
403908 | PLAN
403915 | PLAN
403922 | PLAN
403929 | PLAN
403936 | PLAN
403943 | PLAN
403950 | PLAN
403957 | PLAN
403964 | PLAN
403971 | PLAN
403978 | PLAN
403985 | PLAN
403992 | PLAN
403999 | PLAN
404006 | PLAN
404013 | PLAN
404020 | PLAN
404027 | PLAN
404034 | PLAN
404041 | PLAN
404048 | PLAN
404055 | PLAN
404062 | PLAN
404069 | PLAN
404076 | PLAN
404083 | PLAN
404090 | PLAN
404097 | PLAN
404104 | PLAN
404111 | PLAN
404118 | PLAN
404125 | PLAN
404132 | PLAN
404139 | PLAN
404146 | PLAN
404153 | PLAN
404160 | PLAN
404167 | PLAN
404174 | PLAN
404181 | PLAN
404188 | PLAN
404195 | PLAN
404202 | PLAN
404209 | PLAN
404216 | PLAN
404223 | PLAN
404230 | PLAN
404237 | PLAN
404244 | PLAN
404251 | PLAN
404258 | PLAN
404265 | PLAN
404272 | PLAN
404279 | PLAN
404286 | PLAN
404293 | PLAN
404300 | PLAN
404307 | PLAN
404314 | PLAN
404321 | PLAN
404328 | PLAN
404335 | PLAN
404342 | PLAN
404349 | PLAN
404356 | PLAN
404363 | PLAN
404370 | PLAN
404377 | PLAN
404384 | PLAN
404391 | PLAN
404398 | PLAN
404405 | PLAN
404412 | PLAN
404419 | PLAN
404426 | PLAN
404433 | PLAN
404440 | PLAN
404447 | PLAN
404454 | PLAN
404461 | PLAN
404468 | PLAN
404475 | PLAN
404482 | PLAN
404489 | PLAN
404496 | PLAN
404503 | PLAN
404510 | PLAN
404517 | PLAN
404524 | PLAN
404531 | PLAN
404538 | PLAN
404545 | PLAN
404552 | PLAN
404559 | PLAN
404566 | PLAN
404573 | PLAN
404580 | PLAN
404587 | PLAN
404594 | PLAN
404601 | PLAN
404608 | PLAN
404615 | PLAN
404622 | PLAN
404629 | PLAN
404636 | PLAN
404643 | PLAN
404650 | PLAN
404657 | PLAN
404664 | PLAN
404671 | PLAN
404678 | PLAN
404685 | PLAN
404692 | PLAN
404699 | PLAN
404706 | PLAN
404713 | PLAN
404720 | PLAN
404727 | PLAN
404734 | PLAN
404741 | PLAN
404748 | PLAN
404755 | PLAN
404762 | PLAN
404769 | PLAN
404776 | PLAN
404783 | PLAN
404790 | PLAN
404797 | PLAN
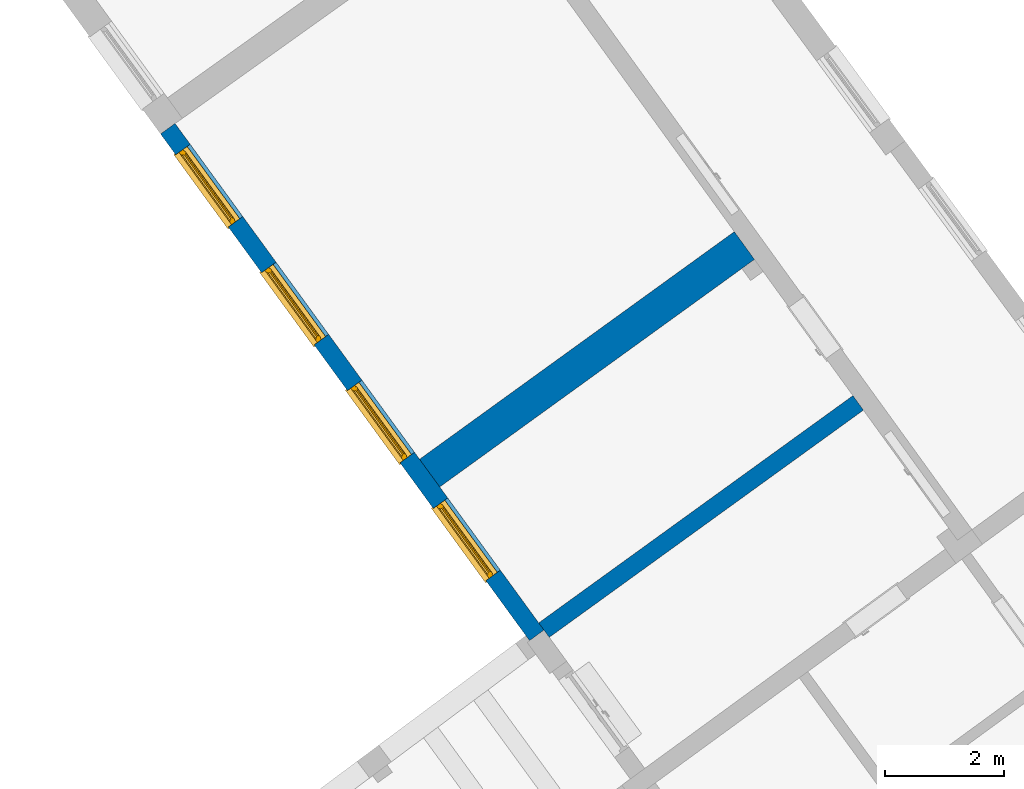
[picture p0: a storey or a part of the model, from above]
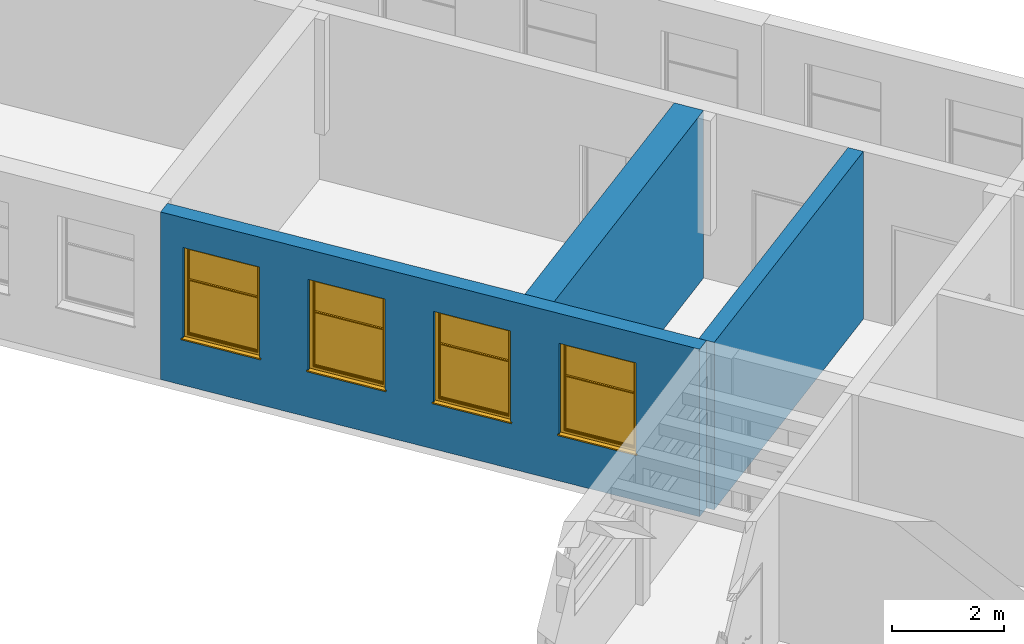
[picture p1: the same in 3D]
Properties of the parts of a building model (IFC2X3), part 9 of 13

# IfcSlab: Floor:Slab-179:1000 (17048)
Name (Floor:Slab-179:1000:...) | In
404804 | PLAN
404811 | PLAN
404818 | PLAN
404825 | PLAN
404832 | PLAN
404839 | PLAN
404846 | PLAN
404853 | PLAN
404860 | PLAN
404867 | PLAN
404874 | PLAN
404881 | PLAN
404888 | PLAN
404895 | PLAN
404902 | PLAN
404909 | PLAN
404916 | PLAN
404923 | PLAN
404930 | PLAN
404937 | PLAN
404944 | PLAN
404951 | PLAN
404958 | PLAN
404965 | PLAN
404972 | PLAN
404979 | PLAN
404986 | PLAN
404993 | PLAN
405000 | PLAN
405007 | PLAN
405014 | PLAN
405021 | PLAN
405028 | PLAN
405035 | PLAN
405042 | PLAN
405049 | PLAN
405056 | PLAN
405063 | PLAN
405070 | PLAN
405077 | PLAN
405084 | PLAN
405091 | PLAN
405098 | PLAN
405105 | PLAN
405112 | PLAN
405119 | PLAN
405126 | PLAN
405133 | PLAN
405140 | PLAN
405147 | PLAN
405154 | PLAN
405161 | PLAN
405168 | PLAN
405175 | PLAN
405182 | PLAN
405189 | PLAN
405196 | PLAN
405203 | PLAN
405210 | PLAN
405217 | PLAN
405224 | PLAN
405231 | PLAN
405238 | PLAN
405245 | PLAN
405252 | PLAN
405259 | PLAN
405266 | PLAN
405273 | PLAN
405280 | PLAN
405287 | PLAN
405294 | PLAN
405301 | PLAN
405308 | PLAN
405315 | PLAN
405322 | PLAN
405329 | PLAN
405336 | PLAN
405343 | PLAN
405350 | PLAN
405357 | PLAN
405364 | PLAN
405371 | PLAN
405378 | PLAN
405385 | PLAN
405392 | PLAN
405399 | PLAN
405406 | PLAN
405413 | PLAN
405420 | PLAN
405427 | PLAN
405434 | PLAN
405441 | PLAN
405448 | PLAN
405455 | PLAN
405462 | PLAN
405469 | PLAN
405476 | PLAN
405483 | PLAN
405490 | PLAN
405497 | PLAN
405504 | PLAN
405511 | PLAN
405518 | PLAN
405525 | PLAN
405532 | PLAN
405539 | PLAN
405546 | PLAN
405553 | PLAN
405560 | PLAN
405567 | PLAN
405574 | PLAN
405581 | PLAN
405588 | PLAN
405595 | PLAN
405602 | PLAN
405609 | PLAN
405616 | PLAN
405623 | PLAN
405630 | PLAN
405637 | PLAN
405644 | PLAN
405651 | PLAN
405658 | PLAN
405665 | PLAN
405672 | PLAN
405679 | PLAN
405686 | PLAN
405693 | PLAN
405700 | PLAN
405707 | PLAN
405714 | PLAN
405721 | PLAN
405728 | PLAN
405735 | PLAN
405742 | PLAN
405749 | PLAN
405756 | PLAN
405763 | PLAN
405770 | PLAN
405777 | PLAN
405784 | PLAN
405791 | PLAN
405798 | PLAN
405805 | PLAN
405812 | PLAN
405819 | PLAN
405826 | PLAN
405833 | PLAN
405840 | PLAN
405847 | PLAN
405854 | PLAN
405861 | PLAN
405868 | PLAN
405875 | PLAN
405882 | PLAN
405889 | PLAN
405896 | PLAN
405903 | PLAN
405910 | PLAN
405917 | PLAN
405924 | PLAN
405931 | PLAN
405938 | PLAN
405945 | PLAN
405952 | PLAN
405959 | PLAN
405966 | PLAN
405973 | PLAN
405980 | PLAN
405987 | PLAN
405994 | PLAN
406001 | PLAN
406008 | PLAN
406015 | PLAN
406022 | PLAN
406029 | PLAN
406036 | PLAN
406043 | PLAN
406050 | PLAN
406057 | PLAN
406064 | PLAN
406071 | PLAN
406078 | PLAN
406085 | PLAN
406092 | PLAN
406099 | PLAN
406106 | PLAN
406113 | PLAN
406120 | PLAN
406127 | PLAN
406134 | PLAN
406141 | PLAN
406148 | PLAN
406155 | PLAN
406162 | PLAN
406169 | PLAN
406176 | PLAN
406183 | PLAN
406190 | PLAN
406197 | PLAN
406204 | PLAN
406211 | PLAN
406218 | PLAN
406225 | PLAN
406232 | PLAN
406239 | PLAN
406246 | PLAN
406253 | PLAN
406260 | PLAN
406267 | PLAN
406274 | PLAN
406281 | PLAN
406288 | PLAN
406295 | PLAN
406302 | PLAN
406309 | PLAN
406316 | PLAN
406323 | PLAN
406330 | PLAN
406337 | PLAN
406344 | PLAN
406351 | PLAN
406358 | PLAN
406365 | PLAN
406372 | PLAN
406379 | PLAN
406386 | PLAN
406393 | PLAN
406400 | PLAN
406407 | PLAN
406414 | PLAN
406421 | PLAN
406428 | PLAN
406435 | PLAN
406442 | PLAN
406449 | PLAN
406456 | PLAN
406463 | PLAN
406470 | PLAN
406477 | PLAN
406484 | PLAN
406491 | PLAN
406498 | PLAN
406505 | PLAN
406512 | PLAN
406519 | PLAN
406526 | PLAN
406533 | PLAN
406540 | PLAN
406547 | PLAN
406554 | PLAN
406561 | PLAN
406568 | PLAN
406575 | PLAN
406582 | PLAN
406589 | PLAN
406596 | PLAN
406603 | PLAN
406610 | PLAN
406617 | PLAN
406624 | PLAN
406631 | PLAN
406638 | PLAN
406645 | PLAN
406652 | PLAN
406659 | PLAN
406666 | PLAN
406673 | PLAN
406680 | PLAN
406687 | PLAN
406694 | PLAN
406701 | PLAN
406708 | PLAN
406715 | PLAN
406722 | PLAN
406729 | PLAN
406736 | PLAN
406743 | PLAN
406750 | PLAN
406757 | PLAN
406764 | PLAN
406771 | PLAN
406778 | PLAN
406785 | PLAN
406792 | PLAN
406799 | PLAN
406806 | PLAN
406813 | PLAN
406820 | PLAN
406827 | PLAN
406834 | PLAN
406841 | PLAN
406848 | PLAN
406855 | PLAN
406862 | PLAN
406869 | PLAN
406876 | PLAN
406883 | PLAN
406890 | PLAN
406897 | PLAN
406904 | PLAN
406911 | PLAN
406918 | PLAN
406925 | PLAN
406932 | PLAN
406939 | PLAN
406946 | PLAN
406953 | PLAN
406960 | PLAN
406967 | PLAN
406974 | PLAN
406981 | PLAN
406988 | PLAN
406995 | PLAN
407002 | PLAN
407009 | PLAN
407016 | PLAN
407023 | PLAN
407030 | PLAN
407037 | PLAN
407044 | PLAN
407051 | PLAN
407058 | PLAN
407065 | PLAN
407072 | PLAN
407079 | PLAN
407086 | PLAN
407093 | PLAN
407100 | PLAN
407107 | PLAN
407114 | PLAN
407121 | PLAN
407128 | PLAN
407135 | PLAN
407142 | PLAN
407149 | PLAN
407156 | PLAN
407163 | PLAN
407170 | PLAN
407177 | PLAN
407184 | PLAN
407191 | PLAN
407198 | PLAN
407205 | PLAN
407212 | PLAN
407219 | PLAN
407226 | PLAN
407233 | PLAN
407240 | PLAN
407247 | PLAN
407254 | PLAN
407261 | PLAN
407268 | PLAN
407275 | PLAN
407282 | PLAN
407289 | PLAN
407296 | PLAN
407303 | PLAN
407310 | PLAN
407317 | PLAN
407324 | PLAN
407331 | PLAN
407338 | PLAN
407345 | PLAN
407352 | PLAN
407359 | PLAN
407366 | PLAN
407373 | PLAN
407380 | PLAN
407387 | PLAN
407394 | PLAN
407401 | PLAN
407408 | PLAN
407415 | PLAN
407422 | PLAN
407429 | PLAN
407436 | PLAN
407443 | PLAN
407450 | PLAN
407457 | PLAN
407464 | PLAN
407471 | PLAN
407478 | PLAN
407485 | PLAN
407492 | PLAN
407499 | PLAN
407506 | PLAN
407513 | PLAN
407520 | PLAN
407527 | PLAN
407534 | PLAN
407541 | PLAN
407548 | PLAN
407555 | PLAN
407562 | PLAN
407569 | PLAN
407576 | PLAN
407583 | PLAN
407590 | PLAN
407597 | PLAN
407604 | PLAN
407611 | PLAN
407618 | PLAN
407625 | PLAN
407632 | PLAN
407639 | PLAN
407646 | PLAN
407653 | PLAN
407660 | PLAN
407667 | PLAN
407674 | PLAN
407681 | PLAN
407688 | PLAN
407695 | PLAN
407702 | PLAN
407709 | PLAN
407716 | PLAN
407723 | PLAN
407730 | PLAN
407737 | PLAN
407744 | PLAN
407751 | PLAN
407758 | PLAN
407765 | PLAN
407772 | PLAN
407779 | PLAN
407786 | PLAN
407793 | PLAN
407800 | PLAN
407807 | PLAN
407814 | PLAN
407821 | PLAN
407828 | PLAN
407835 | PLAN
407842 | PLAN
407849 | PLAN
407856 | PLAN
407863 | PLAN
407870 | PLAN
407877 | PLAN
407884 | PLAN
407891 | PLAN
407898 | PLAN
407905 | PLAN
407912 | PLAN
407919 | PLAN
407926 | PLAN
407933 | PLAN
407940 | PLAN
407947 | PLAN
407954 | PLAN
407961 | PLAN
407968 | PLAN
407975 | PLAN
407982 | PLAN
407989 | PLAN
407996 | PLAN
408003 | PLAN
408010 | PLAN
408017 | PLAN
408024 | PLAN
408031 | PLAN
408038 | PLAN
408045 | PLAN
408052 | PLAN
408059 | PLAN
408066 | PLAN
408073 | PLAN
408080 | PLAN
408087 | PLAN
408094 | PLAN
408101 | PLAN
408108 | PLAN
408115 | PLAN
408122 | PLAN
408129 | PLAN
408136 | PLAN
408143 | PLAN
408150 | PLAN
408157 | PLAN
408164 | PLAN
408171 | PLAN
408178 | PLAN
408185 | PLAN
408192 | PLAN
408199 | PLAN
408206 | PLAN
408213 | PLAN
408220 | PLAN
408227 | PLAN
408234 | PLAN
408241 | PLAN
408248 | PLAN
408255 | PLAN
408262 | PLAN
408269 | PLAN
408276 | PLAN
408283 | PLAN
408290 | PLAN
408297 | PLAN
408304 | PLAN
408311 | PLAN
408318 | PLAN
408325 | PLAN
408332 | PLAN
408339 | PLAN
408346 | PLAN
408353 | PLAN
408360 | PLAN
408367 | PLAN
408374 | PLAN
408381 | PLAN
408388 | PLAN
408395 | PLAN
408402 | PLAN
408409 | PLAN
408416 | PLAN
408423 | PLAN
408430 | PLAN
408437 | PLAN
408444 | PLAN
408451 | PLAN
408458 | PLAN
408465 | PLAN
408472 | PLAN
408479 | PLAN
408486 | PLAN
408493 | PLAN
408500 | PLAN
408507 | PLAN
408514 | PLAN
408521 | PLAN
408528 | PLAN
408535 | PLAN
408542 | PLAN
408549 | PLAN
408556 | PLAN
408563 | PLAN
408570 | PLAN
408577 | PLAN
408584 | PLAN
408591 | PLAN
408598 | PLAN
408605 | PLAN
408612 | PLAN
408619 | PLAN
408626 | PLAN
408633 | PLAN
408640 | PLAN
408647 | PLAN
408654 | PLAN
408661 | PLAN
408668 | PLAN
408675 | PLAN
408682 | PLAN
408689 | PLAN
408696 | PLAN
408703 | PLAN
408710 | PLAN
408717 | PLAN
408724 | PLAN
408731 | PLAN
408738 | PLAN
408745 | PLAN
408752 | PLAN
408759 | PLAN
408766 | PLAN
408773 | PLAN
408780 | PLAN
408787 | PLAN
408794 | PLAN
408801 | PLAN
408808 | PLAN
408815 | PLAN
408822 | PLAN
408829 | PLAN
408836 | PLAN
408843 | PLAN
408850 | PLAN
408857 | PLAN
408864 | PLAN
408871 | PLAN
408878 | PLAN
408885 | PLAN
408892 | PLAN
408899 | PLAN
408906 | PLAN
408913 | PLAN
408920 | PLAN
408927 | PLAN
408934 | PLAN
408941 | PLAN
408948 | PLAN
408955 | PLAN
408962 | PLAN
408969 | PLAN
408976 | PLAN
408983 | PLAN
408990 | PLAN
408997 | PLAN
409004 | PLAN
409011 | PLAN
409018 | PLAN
409025 | PLAN
409032 | PLAN
409039 | PLAN
409046 | PLAN
409053 | PLAN
409060 | PLAN
409067 | PLAN
409074 | PLAN
409081 | PLAN
409088 | PLAN
409095 | PLAN
409102 | PLAN
409109 | PLAN
409116 | PLAN
409123 | PLAN
409130 | PLAN
409137 | PLAN
409144 | PLAN
409151 | PLAN
409158 | PLAN
409165 | PLAN
409172 | PLAN
409179 | PLAN
409186 | PLAN
409193 | PLAN
409200 | PLAN
409207 | PLAN
409214 | PLAN
409221 | PLAN
409228 | PLAN
409235 | PLAN
409242 | PLAN
409249 | PLAN
409256 | PLAN
409263 | PLAN
409270 | PLAN
409277 | PLAN
409284 | PLAN
409291 | PLAN
409298 | PLAN
409305 | PLAN
409312 | PLAN
409319 | PLAN
409326 | PLAN
409333 | PLAN
409340 | PLAN
409347 | PLAN
409354 | PLAN
409361 | PLAN
409368 | PLAN
409375 | PLAN
409382 | PLAN
409389 | PLAN
409396 | PLAN
409403 | PLAN
409410 | PLAN
409417 | PLAN
409424 | PLAN
409431 | PLAN
409438 | PLAN
409445 | PLAN
409452 | PLAN
409459 | PLAN
409466 | PLAN
409473 | PLAN
409480 | PLAN
409487 | PLAN
409494 | PLAN
409501 | PLAN
409508 | PLAN
409515 | PLAN
409522 | PLAN
409529 | PLAN
409536 | PLAN
409543 | PLAN
409550 | PLAN
409557 | PLAN
409564 | PLAN
409571 | PLAN
409578 | PLAN
409585 | PLAN
409592 | PLAN
409599 | PLAN
409606 | PLAN
409613 | PLAN
409620 | PLAN
409627 | PLAN
409634 | PLAN
409641 | PLAN
409648 | PLAN
409655 | PLAN
409662 | PLAN
409669 | PLAN
409676 | PLAN
409683 | PLAN
409690 | PLAN
409697 | PLAN
409704 | PLAN
409711 | PLAN
409718 | PLAN
409725 | PLAN
409732 | PLAN
409739 | PLAN
409746 | PLAN
409753 | PLAN
409760 | PLAN
409767 | PLAN
409774 | PLAN
409781 | PLAN
409788 | PLAN
409795 | PLAN
409802 | PLAN
409809 | PLAN
409816 | PLAN
409823 | PLAN
409830 | PLAN
409837 | PLAN
409844 | PLAN
409851 | PLAN
409858 | PLAN
409865 | PLAN
409872 | PLAN
409879 | PLAN
409886 | PLAN
409893 | PLAN
409900 | PLAN
409907 | PLAN
409914 | PLAN
409921 | PLAN
409928 | PLAN
409935 | PLAN
409942 | PLAN
409949 | PLAN
409956 | PLAN
409963 | PLAN
409970 | PLAN
409977 | PLAN
409984 | PLAN
409991 | PLAN
409998 | PLAN
410005 | PLAN
410012 | PLAN
410019 | PLAN
410026 | PLAN
410033 | PLAN
410040 | PLAN
410047 | PLAN
410054 | PLAN
410061 | PLAN
410068 | PLAN
410075 | PLAN
410082 | PLAN
410089 | PLAN
410096 | PLAN
410103 | PLAN
410110 | PLAN
410117 | PLAN
410124 | PLAN
410131 | PLAN
410138 | PLAN
410145 | PLAN
410152 | PLAN
410159 | PLAN
410166 | PLAN
410173 | PLAN
410180 | PLAN
410187 | PLAN
410194 | PLAN
410201 | PLAN
410208 | PLAN
410215 | PLAN
410222 | PLAN
410229 | PLAN
410236 | PLAN
410243 | PLAN
410250 | PLAN
410257 | PLAN
410264 | PLAN
410271 | PLAN
410278 | PLAN
410285 | PLAN
410292 | PLAN
410299 | PLAN
410306 | PLAN
410313 | PLAN
410320 | PLAN
410327 | PLAN
410334 | PLAN
410341 | PLAN
410348 | PLAN
410355 | PLAN
410362 | PLAN
410369 | PLAN
410376 | PLAN
410383 | PLAN
410390 | PLAN
410397 | PLAN
410404 | PLAN
410411 | PLAN
410418 | PLAN
410425 | PLAN
410432 | PLAN
410439 | PLAN
410446 | PLAN
410453 | PLAN
410460 | PLAN
410467 | PLAN
410474 | PLAN
410481 | PLAN
410488 | PLAN
410495 | PLAN
410502 | PLAN
410509 | PLAN
410516 | PLAN
410523 | PLAN
410530 | PLAN
410537 | PLAN
410544 | PLAN
410551 | PLAN
410558 | PLAN
410565 | PLAN
410572 | PLAN
410579 | PLAN
410586 | PLAN
410593 | PLAN
410600 | PLAN
410607 | PLAN
410614 | PLAN
410621 | PLAN
410628 | PLAN
410635 | PLAN
410642 | PLAN
410649 | PLAN
410656 | PLAN
410663 | PLAN
410670 | PLAN
410677 | PLAN
410684 | PLAN
410691 | PLAN
410698 | PLAN
410705 | PLAN
410712 | PLAN
410719 | PLAN
410726 | PLAN
410733 | PLAN
410740 | PLAN
410747 | PLAN
410754 | PLAN
410761 | PLAN
410768 | PLAN
410775 | PLAN
410782 | PLAN
410789 | PLAN
410796 | PLAN
410803 | PLAN
410810 | PLAN
410817 | PLAN
410824 | PLAN
410831 | PLAN
410838 | PLAN
410845 | PLAN
410852 | PLAN
410859 | PLAN
410866 | PLAN
410873 | PLAN
410880 | PLAN
410887 | PLAN
410894 | PLAN
410901 | PLAN
410908 | PLAN
410915 | PLAN
410922 | PLAN
410929 | PLAN
410936 | PLAN
410943 | PLAN
410950 | PLAN
410957 | PLAN
410964 | PLAN
410971 | PLAN
410978 | PLAN
410985 | PLAN
410992 | PLAN
410999 | PLAN
411006 | PLAN
411013 | PLAN
411020 | PLAN
411027 | PLAN
411034 | PLAN
411041 | PLAN
411048 | PLAN
411055 | PLAN
411062 | PLAN
411069 | PLAN
411076 | PLAN
411083 | PLAN
411090 | PLAN
411097 | PLAN
411104 | PLAN
411111 | PLAN
411118 | PLAN
411125 | PLAN
411132 | PLAN
411139 | PLAN
411146 | PLAN
411153 | PLAN
411160 | PLAN
411167 | PLAN
411174 | PLAN
411181 | PLAN
411188 | PLAN
411195 | PLAN
411202 | PLAN
411209 | PLAN
411216 | PLAN
411223 | PLAN
411230 | PLAN
411237 | PLAN
411244 | PLAN
411251 | PLAN
411258 | PLAN
411265 | PLAN
411272 | PLAN
411279 | PLAN
411286 | PLAN
411293 | PLAN
411300 | PLAN
411307 | PLAN
411314 | PLAN
411321 | PLAN
411328 | PLAN
411335 | PLAN
411342 | PLAN
411349 | PLAN
411356 | PLAN
411363 | PLAN
411370 | PLAN
411377 | PLAN
411384 | PLAN
411391 | PLAN
411398 | PLAN
411405 | PLAN
411412 | PLAN
411419 | PLAN
411426 | PLAN
411433 | PLAN
411440 | PLAN
411447 | PLAN
411454 | PLAN
411461 | PLAN
411468 | PLAN
411475 | PLAN
411482 | PLAN
411489 | PLAN
411496 | PLAN
411503 | PLAN
411510 | PLAN
411517 | PLAN
411524 | PLAN
411531 | PLAN
411538 | PLAN
411545 | PLAN
411552 | PLAN
411559 | PLAN
411566 | PLAN
411573 | PLAN
411580 | PLAN
411587 | PLAN
411594 | PLAN
411601 | PLAN
411608 | PLAN
411615 | PLAN
411622 | PLAN
411629 | PLAN
411636 | PLAN
411643 | PLAN
411650 | PLAN
411657 | PLAN
411664 | PLAN
411671 | PLAN
411678 | PLAN
411685 | PLAN
411692 | PLAN
411699 | PLAN
411706 | PLAN
411713 | PLAN
411720 | PLAN
411727 | PLAN
411734 | PLAN
411741 | PLAN
411748 | PLAN
411755 | PLAN
411762 | PLAN
411769 | PLAN
411776 | PLAN
411783 | PLAN
411790 | PLAN
411797 | PLAN
411804 | PLAN
411811 | PLAN
411818 | PLAN
411825 | PLAN
411832 | PLAN
411839 | PLAN
411846 | PLAN
411853 | PLAN
411860 | PLAN
411867 | PLAN
411874 | PLAN
411881 | PLAN
411888 | PLAN
411895 | PLAN
411902 | PLAN
411909 | PLAN
411916 | PLAN
411923 | PLAN
411930 | PLAN
411937 | PLAN
411944 | PLAN
411951 | PLAN
411958 | PLAN
411965 | PLAN
411972 | PLAN
411979 | PLAN
411986 | PLAN
411993 | PLAN
412000 | PLAN
412007 | PLAN
412014 | PLAN
412021 | PLAN
412028 | PLAN
412035 | PLAN
412042 | PLAN
412049 | PLAN
412056 | PLAN
412063 | PLAN
412070 | PLAN
412077 | PLAN
412084 | PLAN
412091 | PLAN
412098 | PLAN
412105 | PLAN
412112 | PLAN
412119 | PLAN
412126 | PLAN
412133 | PLAN
412140 | PLAN
412147 | PLAN
412154 | PLAN
412161 | PLAN
412168 | PLAN
412175 | PLAN
412182 | PLAN
412189 | PLAN
412196 | PLAN
412203 | PLAN
412210 | PLAN
412217 | PLAN
412224 | PLAN
412231 | PLAN
412238 | PLAN
412245 | PLAN
412252 | PLAN
412259 | PLAN
412266 | PLAN
412273 | PLAN
412280 | PLAN
412287 | PLAN
412294 | PLAN
412301 | PLAN
412308 | PLAN
412315 | PLAN
412322 | PLAN
412329 | PLAN
412336 | PLAN
412343 | PLAN
412350 | PLAN
412357 | PLAN
412364 | PLAN
412371 | PLAN
412378 | PLAN
412385 | PLAN
412392 | PLAN
412399 | PLAN
412406 | PLAN
412413 | PLAN
412420 | PLAN
412427 | PLAN
412434 | PLAN
412441 | PLAN
412448 | PLAN
412455 | PLAN
412462 | PLAN
412469 | PLAN
412476 | PLAN
412483 | PLAN
412490 | PLAN
412497 | PLAN
412504 | PLAN
412511 | PLAN
412518 | PLAN
412525 | PLAN
412532 | PLAN
412539 | PLAN
412546 | PLAN
412553 | PLAN
412560 | PLAN
412567 | PLAN
412574 | PLAN
412581 | PLAN
412588 | PLAN
412595 | PLAN
412602 | PLAN
412609 | PLAN
412616 | PLAN
412623 | PLAN
412630 | PLAN
412637 | PLAN
412644 | PLAN
412651 | PLAN
412658 | PLAN
412665 | PLAN
412672 | PLAN
412679 | PLAN
412686 | PLAN
412693 | PLAN
412700 | PLAN
412707 | PLAN
412714 | PLAN
412721 | PLAN
412728 | PLAN
412735 | PLAN
412742 | PLAN
412749 | PLAN
412756 | PLAN
412763 | PLAN
412770 | PLAN
412777 | PLAN
412784 | PLAN
412791 | PLAN
412798 | PLAN
412805 | PLAN
412812 | PLAN
412819 | PLAN
412826 | PLAN
412833 | PLAN
412840 | PLAN
412847 | PLAN
412854 | PLAN
412861 | PLAN
412868 | PLAN
412875 | PLAN
412882 | PLAN
412889 | PLAN
412896 | PLAN
412903 | PLAN
412910 | PLAN
412917 | PLAN
412924 | PLAN
412931 | PLAN
412938 | PLAN
412945 | PLAN
412952 | PLAN
412959 | PLAN
412966 | PLAN
412973 | PLAN
412980 | PLAN
412987 | PLAN
412994 | PLAN
413001 | PLAN
413008 | PLAN
413015 | PLAN
413022 | PLAN
413029 | PLAN
413036 | PLAN
413043 | PLAN
413050 | PLAN
413057 | PLAN
413064 | PLAN
413071 | PLAN
413078 | PLAN
413085 | PLAN
413092 | PLAN
413099 | PLAN
413106 | PLAN
413113 | PLAN
413120 | PLAN
413127 | PLAN
413134 | PLAN
413141 | PLAN
413148 | PLAN
413155 | PLAN
413162 | PLAN
413169 | PLAN
413176 | PLAN
413183 | PLAN
413190 | PLAN
413197 | PLAN
413204 | PLAN
413211 | PLAN
413218 | PLAN
413225 | PLAN
413232 | PLAN
413239 | PLAN
413246 | PLAN
413253 | PLAN
413260 | PLAN
413267 | PLAN
413274 | PLAN
413281 | PLAN
413288 | PLAN
413295 | PLAN
413302 | PLAN
413309 | PLAN
413316 | PLAN
413323 | PLAN
413330 | PLAN
413337 | PLAN
413344 | PLAN
413351 | PLAN
413358 | PLAN
413365 | PLAN
413372 | PLAN
413379 | PLAN
413386 | PLAN
413393 | PLAN
413400 | PLAN
413407 | PLAN
413414 | PLAN
413421 | PLAN
413428 | PLAN
413435 | PLAN
413442 | PLAN
413449 | PLAN
413456 | PLAN
413463 | PLAN
413470 | PLAN
413477 | PLAN
413484 | PLAN
413491 | PLAN
413498 | PLAN
413505 | PLAN
413512 | PLAN
413519 | PLAN
413526 | PLAN
413533 | PLAN
413540 | PLAN
413547 | PLAN
413554 | PLAN
413561 | PLAN
413568 | PLAN
413575 | PLAN
413582 | PLAN
413589 | PLAN
413596 | PLAN
413603 | PLAN
413610 | PLAN
413617 | PLAN
413624 | PLAN
413631 | PLAN
413638 | PLAN
413645 | PLAN
413652 | PLAN
413659 | PLAN
413666 | PLAN
413673 | PLAN
413680 | PLAN
413687 | PLAN
413694 | PLAN
413701 | PLAN
413708 | PLAN
413715 | PLAN
413722 | PLAN
413729 | PLAN
413736 | PLAN
413743 | PLAN
413750 | PLAN
413757 | PLAN
413764 | PLAN
413771 | PLAN
413778 | PLAN
413785 | PLAN
413792 | PLAN
413799 | PLAN
413806 | PLAN
413813 | PLAN
413820 | PLAN
413827 | PLAN
413834 | PLAN
413841 | PLAN
413848 | PLAN
413855 | PLAN
413862 | PLAN
413869 | PLAN
413876 | PLAN
413883 | PLAN
413890 | PLAN
413897 | PLAN
413904 | PLAN
413911 | PLAN
413918 | PLAN
413925 | PLAN
413932 | PLAN
413939 | PLAN
413946 | PLAN
413953 | PLAN
413960 | PLAN
413967 | PLAN
413974 | PLAN
413981 | PLAN
413988 | PLAN
413995 | PLAN
414002 | PLAN
414009 | PLAN
414016 | PLAN
414023 | PLAN
414030 | PLAN
414037 | PLAN
414044 | PLAN
414051 | PLAN
414058 | PLAN
414065 | PLAN
414072 | PLAN
414079 | PLAN
414086 | PLAN
414093 | PLAN
414100 | PLAN
414107 | PLAN
414114 | PLAN
414121 | PLAN
414128 | PLAN
414135 | PLAN
414142 | PLAN
414149 | PLAN
414156 | PLAN
414163 | PLAN
414170 | PLAN
414177 | PLAN
414184 | PLAN
414191 | PLAN
414198 | PLAN
414205 | PLAN
414212 | PLAN
414219 | PLAN
414226 | PLAN
414233 | PLAN
414240 | PLAN
414247 | PLAN
414254 | PLAN
414261 | PLAN
414268 | PLAN
414275 | PLAN
414282 | PLAN
414289 | PLAN
414296 | PLAN
414303 | PLAN
414310 | PLAN
414317 | PLAN
414324 | PLAN
414331 | PLAN
414338 | PLAN
414345 | PLAN
414352 | PLAN
414359 | PLAN
414366 | PLAN
414373 | PLAN
414380 | PLAN
414387 | PLAN
414394 | PLAN
414401 | PLAN
414408 | PLAN
414415 | PLAN
414422 | PLAN
414429 | PLAN
414436 | PLAN
414443 | PLAN
414450 | PLAN
414457 | PLAN
414464 | PLAN
414471 | PLAN
414478 | PLAN
414485 | PLAN
414492 | PLAN
414499 | PLAN
414506 | PLAN
414513 | PLAN
414520 | PLAN
414527 | PLAN
414534 | PLAN
414541 | PLAN
414548 | PLAN
414555 | PLAN
414562 | PLAN
414569 | PLAN
414576 | PLAN
414583 | PLAN
414590 | PLAN
414597 | PLAN
414604 | PLAN
414611 | PLAN
414618 | PLAN
414625 | PLAN
414632 | PLAN
414639 | PLAN
414646 | PLAN
414653 | PLAN
414660 | PLAN
414667 | PLAN
414674 | PLAN
414681 | PLAN
414688 | PLAN
414695 | PLAN
414702 | PLAN
414709 | PLAN
414716 | PLAN
414723 | PLAN
414730 | PLAN
414737 | PLAN
414744 | PLAN
414751 | PLAN
414758 | PLAN
414765 | PLAN
414772 | PLAN
414779 | PLAN
414786 | PLAN
414793 | PLAN
414800 | PLAN
414807 | PLAN
414814 | PLAN
414821 | PLAN
414828 | PLAN
414835 | PLAN
414842 | PLAN
414849 | PLAN
414856 | PLAN
414863 | PLAN
414870 | PLAN
414877 | PLAN
414884 | PLAN
414891 | PLAN
414898 | PLAN
414905 | PLAN
414912 | PLAN
414919 | PLAN
414926 | PLAN
414933 | PLAN
414940 | PLAN
414947 | PLAN
414954 | PLAN
414961 | PLAN
414968 | PLAN
414975 | PLAN
414982 | PLAN
414989 | PLAN
414996 | PLAN
415003 | PLAN
415010 | PLAN
415017 | PLAN
415024 | PLAN
415031 | PLAN
415038 | PLAN
415045 | PLAN
415052 | PLAN
415059 | PLAN
415066 | PLAN
415073 | PLAN
415080 | PLAN
415087 | PLAN
415094 | PLAN
415101 | PLAN
415108 | PLAN
415115 | PLAN
415122 | PLAN
415129 | PLAN
415136 | PLAN
415143 | PLAN
415150 | PLAN
415157 | PLAN
415164 | PLAN
415171 | PLAN
415178 | PLAN
415185 | PLAN
415192 | PLAN
415199 | PLAN
415206 | PLAN
415213 | PLAN
415220 | PLAN
415227 | PLAN
415234 | PLAN
415241 | PLAN
415248 | PLAN
415255 | PLAN
415262 | PLAN
415269 | PLAN
415276 | PLAN
415283 | PLAN
415290 | PLAN
415297 | PLAN
415304 | PLAN
415311 | PLAN
415318 | PLAN
415325 | PLAN
415332 | PLAN
415339 | PLAN
415346 | PLAN
415353 | PLAN
415360 | PLAN
415367 | PLAN
415374 | PLAN
415381 | PLAN
415388 | PLAN
415395 | PLAN
415402 | PLAN
415409 | PLAN
415416 | PLAN
415423 | PLAN
415430 | PLAN
415437 | PLAN
415444 | PLAN
415451 | PLAN
415458 | PLAN
415465 | PLAN
415472 | PLAN
415479 | PLAN
415486 | PLAN
415493 | PLAN
415500 | PLAN
415507 | PLAN
415514 | PLAN
415521 | PLAN
415528 | PLAN
415535 | PLAN
415542 | PLAN
415549 | PLAN
415556 | PLAN
415563 | PLAN
415570 | PLAN
415577 | PLAN
415584 | PLAN
415591 | PLAN
415598 | PLAN
415605 | PLAN
415612 | PLAN
415619 | PLAN
415626 | PLAN
415633 | PLAN
415640 | PLAN
415647 | PLAN
415654 | PLAN
415661 | PLAN
415668 | PLAN
415675 | PLAN
415682 | PLAN
415689 | PLAN
415696 | PLAN
415703 | PLAN
415710 | PLAN
415717 | PLAN
415724 | PLAN
415731 | PLAN
415738 | PLAN
415745 | PLAN
415752 | PLAN
415759 | PLAN
415766 | PLAN
415773 | PLAN
415780 | PLAN
415787 | PLAN
415794 | PLAN
415801 | PLAN
415808 | PLAN
415815 | PLAN
415822 | PLAN
415829 | PLAN
415836 | PLAN
415843 | PLAN
415850 | PLAN
415857 | PLAN
415864 | PLAN
415871 | PLAN
415878 | PLAN
415885 | PLAN
415892 | PLAN
415899 | PLAN
415906 | PLAN
415913 | PLAN
415920 | PLAN
415927 | PLAN
415934 | PLAN
415941 | PLAN
415948 | PLAN
415955 | PLAN
415962 | PLAN
415969 | PLAN
415976 | PLAN
415983 | PLAN
415990 | PLAN
415997 | PLAN
416004 | PLAN
416011 | PLAN
416018 | PLAN
416025 | PLAN
416032 | PLAN
416039 | PLAN
416046 | PLAN
416053 | PLAN
416060 | PLAN
416067 | PLAN
416074 | PLAN
416081 | PLAN
416088 | PLAN
416095 | PLAN
416102 | PLAN
416109 | PLAN
416116 | PLAN
416123 | PLAN
416130 | PLAN
416137 | PLAN
416144 | PLAN
416151 | PLAN
416158 | PLAN
416165 | PLAN
416172 | PLAN
416179 | PLAN
416186 | PLAN
416193 | PLAN
416200 | PLAN
416207 | PLAN
416214 | PLAN
416221 | PLAN
416228 | PLAN
416235 | PLAN
416242 | PLAN
416249 | PLAN
416256 | PLAN
416263 | PLAN
416270 | PLAN
416277 | PLAN
416284 | PLAN
416291 | PLAN
416298 | PLAN
416305 | PLAN
416312 | PLAN
416319 | PLAN
416326 | PLAN
416333 | PLAN
416340 | PLAN
416347 | PLAN
416354 | PLAN
416361 | PLAN
416368 | PLAN
416375 | PLAN
416382 | PLAN
416389 | PLAN
416396 | PLAN
416403 | PLAN
416410 | PLAN
416417 | PLAN
416424 | PLAN
416431 | PLAN
416438 | PLAN
416445 | PLAN
416452 | PLAN
416459 | PLAN
416466 | PLAN
416473 | PLAN
416480 | PLAN
416487 | PLAN
416494 | PLAN
416501 | PLAN
416508 | PLAN
416515 | PLAN
416522 | PLAN
416529 | PLAN
416536 | PLAN
416543 | PLAN
416550 | PLAN
416557 | PLAN
416564 | PLAN
416571 | PLAN
416578 | PLAN
416585 | PLAN
416592 | PLAN
416599 | PLAN
416606 | PLAN
416613 | PLAN
416620 | PLAN
416627 | PLAN
416634 | PLAN
416641 | PLAN
416648 | PLAN
416655 | PLAN
416662 | PLAN
416669 | PLAN
416676 | PLAN
416683 | PLAN
416690 | PLAN
416697 | PLAN
416704 | PLAN
416711 | PLAN
416718 | PLAN
416725 | PLAN
416732 | PLAN
416739 | PLAN
416746 | PLAN
416753 | PLAN
416760 | PLAN
416767 | PLAN
416774 | PLAN
416781 | PLAN
416788 | PLAN
416795 | PLAN
416802 | PLAN
416809 | PLAN
416816 | PLAN
416823 | PLAN
416830 | PLAN
416837 | PLAN
416844 | PLAN
416851 | PLAN
416858 | PLAN
416865 | PLAN
416872 | PLAN
416879 | PLAN
416886 | PLAN
416893 | PLAN
416900 | PLAN
416907 | PLAN
416914 | PLAN
416921 | PLAN
416928 | PLAN
416935 | PLAN
416942 | PLAN
416949 | PLAN
416956 | PLAN
416963 | PLAN
416970 | PLAN
416977 | PLAN
416984 | PLAN
416991 | PLAN
416998 | PLAN
417005 | PLAN
417012 | PLAN
417019 | PLAN
417026 | PLAN
417033 | PLAN
417040 | PLAN
417047 | PLAN
417054 | PLAN
417061 | PLAN
417068 | PLAN
417075 | PLAN
417082 | PLAN
417089 | PLAN
417096 | PLAN
417103 | PLAN
417110 | PLAN
417117 | PLAN
417124 | PLAN
417131 | PLAN
417138 | PLAN
417145 | PLAN
417152 | PLAN
417159 | PLAN
417166 | PLAN
417173 | PLAN
417180 | PLAN
417187 | PLAN
417194 | PLAN
417201 | PLAN
417208 | PLAN
417215 | PLAN
417222 | PLAN
417229 | PLAN
417236 | PLAN
417243 | PLAN
417250 | PLAN
417257 | PLAN
417264 | PLAN
417271 | PLAN
417278 | PLAN
417285 | PLAN
417292 | PLAN
417299 | PLAN
417306 | PLAN
417313 | PLAN
417320 | PLAN
417327 | PLAN
417334 | PLAN
417341 | PLAN
417348 | PLAN
417355 | PLAN
417362 | PLAN
417369 | PLAN
417376 | PLAN
417383 | PLAN
417390 | PLAN
417397 | PLAN
417404 | PLAN
417411 | PLAN
417418 | PLAN
417425 | PLAN
417432 | PLAN
417439 | PLAN
417446 | PLAN
417453 | PLAN
417460 | PLAN
417467 | PLAN
417474 | PLAN
417481 | PLAN
417488 | PLAN
417495 | PLAN
417502 | PLAN
417509 | PLAN
417516 | PLAN
417523 | PLAN
417530 | PLAN
417537 | PLAN
417544 | PLAN
417551 | PLAN
417558 | PLAN
417565 | PLAN
417572 | PLAN
417579 | PLAN
417586 | PLAN
417593 | PLAN
417600 | PLAN
417607 | PLAN
417614 | PLAN
417621 | PLAN
417628 | PLAN
417635 | PLAN
417642 | PLAN
417649 | PLAN
417656 | PLAN
417663 | PLAN
417670 | PLAN
417677 | PLAN
417684 | PLAN
417691 | PLAN
417698 | PLAN
417705 | PLAN
417712 | PLAN
417719 | PLAN
417726 | PLAN
417733 | PLAN
417740 | PLAN
417747 | PLAN
417754 | PLAN
417761 | PLAN
417768 | PLAN
417775 | PLAN
417782 | PLAN
417789 | PLAN
417796 | PLAN
417803 | PLAN
417810 | PLAN
417817 | PLAN
417824 | PLAN
417831 | PLAN
417838 | PLAN
417845 | PLAN
417852 | PLAN
417859 | PLAN
417866 | PLAN
417873 | PLAN
417880 | PLAN
417887 | PLAN
417894 | PLAN
417901 | PLAN
417908 | PLAN
417915 | PLAN
417922 | PLAN
417929 | PLAN
417936 | PLAN
417943 | PLAN
417950 | PLAN
417957 | PLAN
417964 | PLAN
417971 | PLAN
417978 | PLAN
417985 | PLAN
417992 | PLAN
417999 | PLAN
418006 | PLAN
418013 | PLAN
418020 | PLAN
418027 | PLAN
418034 | PLAN
418041 | PLAN
418048 | PLAN
418055 | PLAN
418062 | PLAN
418069 | PLAN
418076 | PLAN
418083 | PLAN
418090 | PLAN
418097 | PLAN
418104 | PLAN
418111 | PLAN
418118 | PLAN
418125 | PLAN
418132 | PLAN
418139 | PLAN
418146 | PLAN
418153 | PLAN
418160 | PLAN
418167 | PLAN
418174 | PLAN
418181 | PLAN
418188 | PLAN
418195 | PLAN
418202 | PLAN
418209 | PLAN
418216 | PLAN
418223 | PLAN
418230 | PLAN
418237 | PLAN
418244 | PLAN
418251 | PLAN
418258 | PLAN
418265 | PLAN
418272 | PLAN
418279 | PLAN
418286 | PLAN
418293 | PLAN
418300 | PLAN
418307 | PLAN
418314 | PLAN
418321 | PLAN
418328 | PLAN
418335 | PLAN
418342 | PLAN
418349 | PLAN
418356 | PLAN
418363 | PLAN
418370 | PLAN
418377 | PLAN
418384 | PLAN
418391 | PLAN
418398 | PLAN
418405 | PLAN
418412 | PLAN
418419 | PLAN
418426 | PLAN
418433 | PLAN
418440 | PLAN
418447 | PLAN
418454 | PLAN
418461 | PLAN
418468 | PLAN
418475 | PLAN
418482 | PLAN
418489 | PLAN
418496 | PLAN
418503 | PLAN
418510 | PLAN
418517 | PLAN
418524 | PLAN
418531 | PLAN
418538 | PLAN
418545 | PLAN
418552 | PLAN
418559 | PLAN
418566 | PLAN
418573 | PLAN
418580 | PLAN
418587 | PLAN
418594 | PLAN
418601 | PLAN
418608 | PLAN
418615 | PLAN
418622 | PLAN
418629 | PLAN
418636 | PLAN
418643 | PLAN
418650 | PLAN
418657 | PLAN
418664 | PLAN
418671 | PLAN
418678 | PLAN
418685 | PLAN
418692 | PLAN
418699 | PLAN
418706 | PLAN
418713 | PLAN
418720 | PLAN
418727 | PLAN
418734 | PLAN
418741 | PLAN
418748 | PLAN
418755 | PLAN
418762 | PLAN
418769 | PLAN
418776 | PLAN
418783 | PLAN
418790 | PLAN
418797 | PLAN
418804 | PLAN
418811 | PLAN
418818 | PLAN
418825 | PLAN
418832 | PLAN
418839 | PLAN
418846 | PLAN
418853 | PLAN
418860 | PLAN
418867 | PLAN
418874 | PLAN
418881 | PLAN
418888 | PLAN
418895 | PLAN
418902 | PLAN
418909 | PLAN
418916 | PLAN
418923 | PLAN
418930 | PLAN
418937 | PLAN
418944 | PLAN
418951 | PLAN
418958 | PLAN
418965 | PLAN
418972 | PLAN
418979 | PLAN
418986 | PLAN
418993 | PLAN
419000 | PLAN
419007 | PLAN
419014 | PLAN
419021 | PLAN
419028 | PLAN
419035 | PLAN
419042 | PLAN
419049 | PLAN
419056 | PLAN
419063 | PLAN
419070 | PLAN
419077 | PLAN
419084 | PLAN
419091 | PLAN
419098 | PLAN
419105 | PLAN
419112 | PLAN
419119 | PLAN
419126 | PLAN
419133 | PLAN
419140 | PLAN
419147 | PLAN
419154 | PLAN
419161 | PLAN
419168 | PLAN
419175 | PLAN
419182 | PLAN
419189 | PLAN
419196 | PLAN
419203 | PLAN
419210 | PLAN
419217 | PLAN
419224 | PLAN
419231 | PLAN
419238 | PLAN
419245 | PLAN
419252 | PLAN
419259 | PLAN
419266 | PLAN
419273 | PLAN
419280 | PLAN
419287 | PLAN
419294 | PLAN
419301 | PLAN
419308 | PLAN
419315 | PLAN
419322 | PLAN
419329 | PLAN
419336 | PLAN
419343 | PLAN
419350 | PLAN
419357 | PLAN
419364 | PLAN
419371 | PLAN
419378 | PLAN
419385 | PLAN
419392 | PLAN
419399 | PLAN
419406 | PLAN
419413 | PLAN
419420 | PLAN
419427 | PLAN
419434 | PLAN
419441 | PLAN
419448 | PLAN
419455 | PLAN
419462 | PLAN
419469 | PLAN
419476 | PLAN
419483 | PLAN
419490 | PLAN
419497 | PLAN
419504 | PLAN
419511 | PLAN
419518 | PLAN
419525 | PLAN
419532 | PLAN
419539 | PLAN
419546 | PLAN
419553 | PLAN
419560 | PLAN
419567 | PLAN
419574 | PLAN
419581 | PLAN
419588 | PLAN
419595 | PLAN
419602 | PLAN
419609 | PLAN
419616 | PLAN
419623 | PLAN
419630 | PLAN
419637 | PLAN
419644 | PLAN
419651 | PLAN
419658 | PLAN
419665 | PLAN
419672 | PLAN
419679 | PLAN
419686 | PLAN
419693 | PLAN
419700 | PLAN
419707 | PLAN
419714 | PLAN
419721 | PLAN
419728 | PLAN
419735 | PLAN
419742 | PLAN
419749 | PLAN
419756 | PLAN
419763 | PLAN
419770 | PLAN
419777 | PLAN
419784 | PLAN
419791 | PLAN
419798 | PLAN
419805 | PLAN
419812 | PLAN
419819 | PLAN
419826 | PLAN
419833 | PLAN
419840 | PLAN
419847 | PLAN
419854 | PLAN
419861 | PLAN
419868 | PLAN
419875 | PLAN
419882 | PLAN
419889 | PLAN
419896 | PLAN
419903 | PLAN
419910 | PLAN
419917 | PLAN
419924 | PLAN
419931 | PLAN
419938 | PLAN
419945 | PLAN
419952 | PLAN
419959 | PLAN
419966 | PLAN
419973 | PLAN
419980 | PLAN
419987 | PLAN
419994 | PLAN
420001 | PLAN
420008 | PLAN
420015 | PLAN
420022 | PLAN
420029 | PLAN
420036 | PLAN
420043 | PLAN
420050 | PLAN
420057 | PLAN
420064 | PLAN
420071 | PLAN
420078 | PLAN
420085 | PLAN
420092 | PLAN
420099 | PLAN
420106 | PLAN
420113 | PLAN
420120 | PLAN
420127 | PLAN
420134 | PLAN
420141 | PLAN
420148 | PLAN
420155 | PLAN
420162 | PLAN
420169 | PLAN
420176 | PLAN
420183 | PLAN
420190 | PLAN
420197 | PLAN
420204 | PLAN
420211 | PLAN
420218 | PLAN
420225 | PLAN
420232 | PLAN
420239 | PLAN
420246 | PLAN
420253 | PLAN
420260 | PLAN
420267 | PLAN
420274 | PLAN
420281 | PLAN
420288 | PLAN
420295 | PLAN
420302 | PLAN
420309 | PLAN
420316 | PLAN
420323 | PLAN
420330 | PLAN
420337 | PLAN
420344 | PLAN
420351 | PLAN
420358 | PLAN
420365 | PLAN
420372 | PLAN
420379 | PLAN
420386 | PLAN
420393 | PLAN
420400 | PLAN
420407 | PLAN
420414 | PLAN
420421 | PLAN
420428 | PLAN
420435 | PLAN
420442 | PLAN
420449 | PLAN
420456 | PLAN
420463 | PLAN
420470 | PLAN
420477 | PLAN
420484 | PLAN
420491 | PLAN
420498 | PLAN
420505 | PLAN
420512 | PLAN
420519 | PLAN
420526 | PLAN
420533 | PLAN
420540 | PLAN
420547 | PLAN
420554 | PLAN
420561 | PLAN
420568 | PLAN
420575 | PLAN
420582 | PLAN
420589 | PLAN
420596 | PLAN
420603 | PLAN
420610 | PLAN
420617 | PLAN
420624 | PLAN
420631 | PLAN
420638 | PLAN
420645 | PLAN
420652 | PLAN
420659 | PLAN
420666 | PLAN
420673 | PLAN
420680 | PLAN
420687 | PLAN
420694 | PLAN
420701 | PLAN
420708 | PLAN
420715 | PLAN
420722 | PLAN
420729 | PLAN
420736 | PLAN
420743 | PLAN
420750 | PLAN
420757 | PLAN
420764 | PLAN
420771 | PLAN
420778 | PLAN
420785 | PLAN
420792 | PLAN
420799 | PLAN
420806 | PLAN
420813 | PLAN
420820 | PLAN
420827 | PLAN
420834 | PLAN
420841 | PLAN
420848 | PLAN
420855 | PLAN
420862 | PLAN
420869 | PLAN
420876 | PLAN
420883 | PLAN
420890 | PLAN
420897 | PLAN
420904 | PLAN
420911 | PLAN
420918 | PLAN
420925 | PLAN
420932 | PLAN
420939 | PLAN
420946 | PLAN
420953 | PLAN
420960 | PLAN
420967 | PLAN
420974 | PLAN
420981 | PLAN
420988 | PLAN
420995 | PLAN
421002 | PLAN
421009 | PLAN
421016 | PLAN
421023 | PLAN
421030 | PLAN
421037 | PLAN
421044 | PLAN
421051 | PLAN
421058 | PLAN
421065 | PLAN
421072 | PLAN
421079 | PLAN
421086 | PLAN
421093 | PLAN
421100 | PLAN
421107 | PLAN
421114 | PLAN
421121 | PLAN
421128 | PLAN
421135 | PLAN
421142 | PLAN
421149 | PLAN
421156 | PLAN
421163 | PLAN
421170 | PLAN
421177 | PLAN
421184 | PLAN
421191 | PLAN
421198 | PLAN
421205 | PLAN
421212 | PLAN
421219 | PLAN
421226 | PLAN
421233 | PLAN
421240 | PLAN
421247 | PLAN
421254 | PLAN
421261 | PLAN
421268 | PLAN
421275 | PLAN
421282 | PLAN
421289 | PLAN
421296 | PLAN
421303 | PLAN
421310 | PLAN
421317 | PLAN
421324 | PLAN
421331 | PLAN
421338 | PLAN
421345 | PLAN
421352 | PLAN
421359 | PLAN
421366 | PLAN
421373 | PLAN
421380 | PLAN
421387 | PLAN
421394 | PLAN
421401 | PLAN
421408 | PLAN
421415 | PLAN
421422 | PLAN
421429 | PLAN
421436 | PLAN
421443 | PLAN
421450 | PLAN
421457 | PLAN
421464 | PLAN
421471 | PLAN
421478 | PLAN
421485 | PLAN
421492 | PLAN
421499 | PLAN
421506 | PLAN
421513 | PLAN
421520 | PLAN
421527 | PLAN
421534 | PLAN
421541 | PLAN
421548 | PLAN
421555 | PLAN
421562 | PLAN
421569 | PLAN
421576 | PLAN
421583 | PLAN
421590 | PLAN
421597 | PLAN
421604 | PLAN
421611 | PLAN
421618 | PLAN
421625 | PLAN
421632 | PLAN
421639 | PLAN
421646 | PLAN
421653 | PLAN
421660 | PLAN
421667 | PLAN
421674 | PLAN
421681 | PLAN
421688 | PLAN
421695 | PLAN
421702 | PLAN
421709 | PLAN
421716 | PLAN
421723 | PLAN
421730 | PLAN
421737 | PLAN
421744 | PLAN
421751 | PLAN
421758 | PLAN
421765 | PLAN
421772 | PLAN
421779 | PLAN
421786 | PLAN
421793 | PLAN
421800 | PLAN
421807 | PLAN
421814 | PLAN
421821 | PLAN
421828 | PLAN
421835 | PLAN
421842 | PLAN
421849 | PLAN
421856 | PLAN
421863 | PLAN
421870 | PLAN
421877 | PLAN
421884 | PLAN
421891 | PLAN
421898 | PLAN
421905 | PLAN
421912 | PLAN
421919 | PLAN
421926 | PLAN
421933 | PLAN
421940 | PLAN
421947 | PLAN
421954 | PLAN
421961 | PLAN
421968 | PLAN
421975 | PLAN
421982 | PLAN
421989 | PLAN
421996 | PLAN
422003 | PLAN
422010 | PLAN
422017 | PLAN
422024 | PLAN
422031 | PLAN
422038 | PLAN
422045 | PLAN
422052 | PLAN
422059 | PLAN
422066 | PLAN
422073 | PLAN
422080 | PLAN
422087 | PLAN
422094 | PLAN
422101 | PLAN
422108 | PLAN
422115 | PLAN
422122 | PLAN
422129 | PLAN
422136 | PLAN
422143 | PLAN
422150 | PLAN
422157 | PLAN
422164 | PLAN
422171 | PLAN
422178 | PLAN
422185 | PLAN
422192 | PLAN
422199 | PLAN
422206 | PLAN
422213 | PLAN
422220 | PLAN
422227 | PLAN
422234 | PLAN
422241 | PLAN
422248 | PLAN
422255 | PLAN
422262 | PLAN
422269 | PLAN
422276 | PLAN
422283 | PLAN
422290 | PLAN
422297 | PLAN
422304 | PLAN
422311 | PLAN
422318 | PLAN
422325 | PLAN
422332 | PLAN
422339 | PLAN
422346 | PLAN
422353 | PLAN
422360 | PLAN
422367 | PLAN
422374 | PLAN
422381 | PLAN
422388 | PLAN
422395 | PLAN
422402 | PLAN
422409 | PLAN
422416 | PLAN
422423 | PLAN
422430 | PLAN
422437 | PLAN
422444 | PLAN
422451 | PLAN
422458 | PLAN
422465 | PLAN
422472 | PLAN
422479 | PLAN
422486 | PLAN
422493 | PLAN
422500 | PLAN
422507 | PLAN
422514 | PLAN
422521 | PLAN
422528 | PLAN
422535 | PLAN
422542 | PLAN
422549 | PLAN
422556 | PLAN
422563 | PLAN
422570 | PLAN
422577 | PLAN
422584 | PLAN
422591 | PLAN
422598 | PLAN
422605 | PLAN
422612 | PLAN
422619 | PLAN
422626 | PLAN
422633 | PLAN
422640 | PLAN
422647 | PLAN
422654 | PLAN
422661 | PLAN
422668 | PLAN
422675 | PLAN
422682 | PLAN
422689 | PLAN
422696 | PLAN
422703 | PLAN
422710 | PLAN
422717 | PLAN
422724 | PLAN
422731 | PLAN
422738 | PLAN
422745 | PLAN
422752 | PLAN
422759 | PLAN
422766 | PLAN
422773 | PLAN
422780 | PLAN
422787 | PLAN
422794 | PLAN
422801 | PLAN
422808 | PLAN
422815 | PLAN
422822 | PLAN
422829 | PLAN
422836 | PLAN
422843 | PLAN
422850 | PLAN
422857 | PLAN
422864 | PLAN
422871 | PLAN
422878 | PLAN
422885 | PLAN
422892 | PLAN
422899 | PLAN
422906 | PLAN
422913 | PLAN
422920 | PLAN
422927 | PLAN
422934 | PLAN
422941 | PLAN
422948 | PLAN
422955 | PLAN
422962 | PLAN
422969 | PLAN
422976 | PLAN
422983 | PLAN
422990 | PLAN
422997 | PLAN
423004 | PLAN
423011 | PLAN
423018 | PLAN
423025 | PLAN
423032 | PLAN
423039 | PLAN
423046 | PLAN
423053 | PLAN
423060 | PLAN
423067 | PLAN
423074 | PLAN
423081 | PLAN
423088 | PLAN
423095 | PLAN
423102 | PLAN
423109 | PLAN
423116 | PLAN
423123 | PLAN
423130 | PLAN
423137 | PLAN
423144 | PLAN
423151 | PLAN
423158 | PLAN
423165 | PLAN
423172 | PLAN
423179 | PLAN
423186 | PLAN
423193 | PLAN
423200 | PLAN
423207 | PLAN
423214 | PLAN
423221 | PLAN
423228 | PLAN
423235 | PLAN
423242 | PLAN
423249 | PLAN
423256 | PLAN
423263 | PLAN
423270 | PLAN
423277 | PLAN
423284 | PLAN
423291 | PLAN
423298 | PLAN
423305 | PLAN
423312 | PLAN
423319 | PLAN
423326 | PLAN
423333 | PLAN
423340 | PLAN
423347 | PLAN
423354 | PLAN
423361 | PLAN
423368 | PLAN
423375 | PLAN
423382 | PLAN
423389 | PLAN
423396 | PLAN
423403 | PLAN
423410 | PLAN
423417 | PLAN
423424 | PLAN
423431 | PLAN
423438 | PLAN
423445 | PLAN
423452 | PLAN
423459 | PLAN
423466 | PLAN
423473 | PLAN
423480 | PLAN
423487 | PLAN
423494 | PLAN
423501 | PLAN
423508 | PLAN
423515 | PLAN
423522 | PLAN
423529 | PLAN
423536 | PLAN
423543 | PLAN
423550 | PLAN
423557 | PLAN
423564 | PLAN
423571 | PLAN
423578 | PLAN
423585 | PLAN
423592 | PLAN
423599 | PLAN
423606 | PLAN
423613 | PLAN
423620 | PLAN
423627 | PLAN
423634 | PLAN
423641 | PLAN
423648 | PLAN
423655 | PLAN
423662 | PLAN
423669 | PLAN
423676 | PLAN
423683 | PLAN
423690 | PLAN
423697 | PLAN
423704 | PLAN
423711 | PLAN
423718 | PLAN
423725 | PLAN
423732 | PLAN
423739 | PLAN
423746 | PLAN
423753 | PLAN
423760 | PLAN
423767 | PLAN
423774 | PLAN
423781 | PLAN
423788 | PLAN
423795 | PLAN
423802 | PLAN
423809 | PLAN
423816 | PLAN
423823 | PLAN
423830 | PLAN
423837 | PLAN
423844 | PLAN
423851 | PLAN
423858 | PLAN
423865 | PLAN
423872 | PLAN
423879 | PLAN
423886 | PLAN
423893 | PLAN
423900 | PLAN
423907 | PLAN
423914 | PLAN
423921 | PLAN
423928 | PLAN
423935 | PLAN
423942 | PLAN
423949 | PLAN
423956 | PLAN
423963 | PLAN
423970 | PLAN
423977 | PLAN
423984 | PLAN
423991 | PLAN
423998 | PLAN
424005 | PLAN
424012 | PLAN
424019 | PLAN
424026 | PLAN
424033 | PLAN
424040 | PLAN
424047 | PLAN
424054 | PLAN
424061 | PLAN
424068 | PLAN
424075 | PLAN
424082 | PLAN
424089 | PLAN
424096 | PLAN
424103 | PLAN
424110 | PLAN
424117 | PLAN
424124 | PLAN
424131 | PLAN
424138 | PLAN
424145 | PLAN
424152 | PLAN
424159 | PLAN
424166 | PLAN
424173 | PLAN
424180 | PLAN
424187 | PLAN
424194 | PLAN
424201 | PLAN
424208 | PLAN
424215 | PLAN
424222 | PLAN
424229 | PLAN
424236 | PLAN
424243 | PLAN
424250 | PLAN
424257 | PLAN
424264 | PLAN
424271 | PLAN
424278 | PLAN
424285 | PLAN
424292 | PLAN
424299 | PLAN
424306 | PLAN
424313 | PLAN
424320 | PLAN
424327 | PLAN
424334 | PLAN
424341 | PLAN
424348 | PLAN
424355 | PLAN
424362 | PLAN
424369 | PLAN
424376 | PLAN
424383 | PLAN
424390 | PLAN
424397 | PLAN
424404 | PLAN
424411 | PLAN
424418 | PLAN
424425 | PLAN
424432 | PLAN
424439 | PLAN
424446 | PLAN
424453 | PLAN
424460 | PLAN
424467 | PLAN
424474 | PLAN
424481 | PLAN
424488 | PLAN
424495 | PLAN
424502 | PLAN
424509 | PLAN
424516 | PLAN
424523 | PLAN
424530 | PLAN
424537 | PLAN
424544 | PLAN
424551 | PLAN
424558 | PLAN
424565 | PLAN
424572 | PLAN
424579 | PLAN
424586 | PLAN
424593 | PLAN
424600 | PLAN
424607 | PLAN
424614 | PLAN
424621 | PLAN
424628 | PLAN
424635 | PLAN
424642 | PLAN
424649 | PLAN
424656 | PLAN
424663 | PLAN
424670 | PLAN
424677 | PLAN
424684 | PLAN
424691 | PLAN
424698 | PLAN
424705 | PLAN
424712 | PLAN
424719 | PLAN
424726 | PLAN
424733 | PLAN
424740 | PLAN
424747 | PLAN
424754 | PLAN
424761 | PLAN
424768 | PLAN
424775 | PLAN
424782 | PLAN
424789 | PLAN
424796 | PLAN
424803 | PLAN
424810 | PLAN
424819 | PLAN
424826 | PLAN
424833 | PLAN
424840 | PLAN
424847 | PLAN
424854 | PLAN
424861 | PLAN
424868 | PLAN
424875 | PLAN
424882 | PLAN
424889 | PLAN
424896 | PLAN
424903 | PLAN
424910 | PLAN
424917 | PLAN
424924 | PLAN
424931 | PLAN
424938 | PLAN
424945 | PLAN
424952 | PLAN
424959 | PLAN
424966 | PLAN
424973 | PLAN
424980 | PLAN
424987 | PLAN
424994 | PLAN
425001 | PLAN
425008 | PLAN
425015 | PLAN
425022 | PLAN
425029 | PLAN
425036 | PLAN
425043 | PLAN
425050 | PLAN
425057 | PLAN
425064 | PLAN
425071 | PLAN
425078 | PLAN
425085 | PLAN
425092 | PLAN
425099 | PLAN
425106 | PLAN
425113 | PLAN
425120 | PLAN
425127 | PLAN
425134 | PLAN
425141 | PLAN
425148 | PLAN
425155 | PLAN
425162 | PLAN
425169 | PLAN
425176 | PLAN
425183 | PLAN
425190 | PLAN
425197 | PLAN
425204 | PLAN
425211 | PLAN
425218 | PLAN
425225 | PLAN
425232 | PLAN
425239 | PLAN
425246 | PLAN
425253 | PLAN
425260 | PLAN
425267 | PLAN
425274 | PLAN
425281 | PLAN
425288 | PLAN
425295 | PLAN
425302 | PLAN
425309 | PLAN
425316 | PLAN
425323 | PLAN
425330 | PLAN
425337 | PLAN
425344 | PLAN
425351 | PLAN
425358 | PLAN
425365 | PLAN
425372 | PLAN
425379 | PLAN
425386 | PLAN
425393 | PLAN
425400 | PLAN
425407 | PLAN
425414 | PLAN
425421 | PLAN
425428 | PLAN
425435 | PLAN
425442 | PLAN
425449 | PLAN
425456 | PLAN
425463 | PLAN
425470 | PLAN
425477 | PLAN
425484 | PLAN
425491 | PLAN
425498 | PLAN
425505 | PLAN
425512 | PLAN
425519 | PLAN
425526 | PLAN
425533 | PLAN
425540 | PLAN
425547 | PLAN
425554 | PLAN
425561 | PLAN
425568 | PLAN
425575 | PLAN
425582 | PLAN
425589 | PLAN
425596 | PLAN
425603 | PLAN
425610 | PLAN
425617 | PLAN
425624 | PLAN
425631 | PLAN
425638 | PLAN
425645 | PLAN
425652 | PLAN
425659 | PLAN
425666 | PLAN
425673 | PLAN
425680 | PLAN
425687 | PLAN
425694 | PLAN
425701 | PLAN
425708 | PLAN
425715 | PLAN
425722 | PLAN
425731 | PLAN
425738 | PLAN
425745 | PLAN
425752 | PLAN
425759 | PLAN
425766 | PLAN
425773 | PLAN
425780 | PLAN
425787 | PLAN
425794 | PLAN
425801 | PLAN
425808 | PLAN
425815 | PLAN
425822 | PLAN
425829 | PLAN
425836 | PLAN
425843 | PLAN
425850 | PLAN
425857 | PLAN
425864 | PLAN
425871 | PLAN
425878 | PLAN
425885 | PLAN
425892 | PLAN
425899 | PLAN
425906 | PLAN
425913 | PLAN
425920 | PLAN
425927 | PLAN
425934 | PLAN
425941 | PLAN
425948 | PLAN
425955 | PLAN
425962 | PLAN
425969 | PLAN
425976 | PLAN
425983 | PLAN
425990 | PLAN
425997 | PLAN
426004 | PLAN
426011 | PLAN
426018 | PLAN
426025 | PLAN
426032 | PLAN
426039 | PLAN
426046 | PLAN
426053 | PLAN
426060 | PLAN
426067 | PLAN
426074 | PLAN
426081 | PLAN
426088 | PLAN
426095 | PLAN
426102 | PLAN
426109 | PLAN
426116 | PLAN
426123 | PLAN
426130 | PLAN
426137 | PLAN
426144 | PLAN
426151 | PLAN
426158 | PLAN
426165 | PLAN
426172 | PLAN
426179 | PLAN
426186 | PLAN
426193 | PLAN
426200 | PLAN
426207 | PLAN
426214 | PLAN
426221 | PLAN
426228 | PLAN
426235 | PLAN
426242 | PLAN
426249 | PLAN
426256 | PLAN
426263 | PLAN
426270 | PLAN
426277 | PLAN
426284 | PLAN
426291 | PLAN
426298 | PLAN
426305 | PLAN
426312 | PLAN
426319 | PLAN
426326 | PLAN
426333 | PLAN
426340 | PLAN
426347 | PLAN
426354 | PLAN
426361 | PLAN
426368 | PLAN
426375 | PLAN
426382 | PLAN
426389 | PLAN
426396 | PLAN
426403 | PLAN
426410 | PLAN
426417 | PLAN
426424 | PLAN
426431 | PLAN
426438 | PLAN
426445 | PLAN
426452 | PLAN
426459 | PLAN
426466 | PLAN
426473 | PLAN
426480 | PLAN
426487 | PLAN
426494 | PLAN
426501 | PLAN
426508 | PLAN
426515 | PLAN
426522 | PLAN
426529 | PLAN
426536 | PLAN
426543 | PLAN
426550 | PLAN
426557 | PLAN
426564 | PLAN
426571 | PLAN
426578 | PLAN
426585 | PLAN
426592 | PLAN
426599 | PLAN
426606 | PLAN
426613 | PLAN
426620 | PLAN
426627 | PLAN
426634 | PLAN
426641 | PLAN
426648 | PLAN
426655 | PLAN
426662 | PLAN
426669 | PLAN
426676 | PLAN
426683 | PLAN
426690 | PLAN
426697 | PLAN
426704 | PLAN
426711 | PLAN
426718 | PLAN
426725 | PLAN
426732 | PLAN
426739 | PLAN
426746 | PLAN
426753 | PLAN
426760 | PLAN
426767 | PLAN
426774 | PLAN
426781 | PLAN
426788 | PLAN
426795 | PLAN
426802 | PLAN
426809 | PLAN
426816 | PLAN
426823 | PLAN
426830 | PLAN
426837 | PLAN
426844 | PLAN
426851 | PLAN
426858 | PLAN
426865 | PLAN
426872 | PLAN
426879 | PLAN
426886 | PLAN
426893 | PLAN
426900 | PLAN
426907 | PLAN
426914 | PLAN
426921 | PLAN
426928 | PLAN
426935 | PLAN
426942 | PLAN
426949 | PLAN
426956 | PLAN
426963 | PLAN
426970 | PLAN
426977 | PLAN
426984 | PLAN
426991 | PLAN
426998 | PLAN
427005 | PLAN
427012 | PLAN
427019 | PLAN
427026 | PLAN
427033 | PLAN
427040 | PLAN
427047 | PLAN
427054 | PLAN
427061 | PLAN
427068 | PLAN
427075 | PLAN
427082 | PLAN
427089 | PLAN
427096 | PLAN
427103 | PLAN
427110 | PLAN
427117 | PLAN
427124 | PLAN
427131 | PLAN
427138 | PLAN
427145 | PLAN
427152 | PLAN
427159 | PLAN
427166 | PLAN
427173 | PLAN
427180 | PLAN
427187 | PLAN
427194 | PLAN
427201 | PLAN
427208 | PLAN
427215 | PLAN
427222 | PLAN
427229 | PLAN
427236 | PLAN
427243 | PLAN
427250 | PLAN
427257 | PLAN
427264 | PLAN
427271 | PLAN
427278 | PLAN
427285 | PLAN
427292 | PLAN
427299 | PLAN
427306 | PLAN
427313 | PLAN
427320 | PLAN
427327 | PLAN
427334 | PLAN
427341 | PLAN
427348 | PLAN
427355 | PLAN
427362 | PLAN
427369 | PLAN
427376 | PLAN
427383 | PLAN
427390 | PLAN
427397 | PLAN
427404 | PLAN
427411 | PLAN
427418 | PLAN
427425 | PLAN
427432 | PLAN
427439 | PLAN
427446 | PLAN
427453 | PLAN
427460 | PLAN
427467 | PLAN
427474 | PLAN
427481 | PLAN
427488 | PLAN
427495 | PLAN
427502 | PLAN
427509 | PLAN
427516 | PLAN
427523 | PLAN
427530 | PLAN
427537 | PLAN
427544 | PLAN
427551 | PLAN
427558 | PLAN
427565 | PLAN
427572 | PLAN
427579 | PLAN
427586 | PLAN
427593 | PLAN
427600 | PLAN
427607 | PLAN
427614 | PLAN
427621 | PLAN
427628 | PLAN
427635 | PLAN
427642 | PLAN
427649 | PLAN
427656 | PLAN
427663 | PLAN
427670 | PLAN
427677 | PLAN
427684 | PLAN
427691 | PLAN
427698 | PLAN
427705 | PLAN
427712 | PLAN
427719 | PLAN
427726 | PLAN
427733 | PLAN
427740 | PLAN
427747 | PLAN
427754 | PLAN
427761 | PLAN
427768 | PLAN
427775 | PLAN
427782 | PLAN
427789 | PLAN
427796 | PLAN
427803 | PLAN
427810 | PLAN
427817 | PLAN
427824 | PLAN
427831 | PLAN
427838 | PLAN
427845 | PLAN
427852 | PLAN
427859 | PLAN
427866 | PLAN
427873 | PLAN
427880 | PLAN
427887 | PLAN
427894 | PLAN
427901 | PLAN
427908 | PLAN
427915 | PLAN
427922 | PLAN
427929 | PLAN
427936 | PLAN
427943 | PLAN
427950 | PLAN
427957 | PLAN
427964 | PLAN
427971 | PLAN
427978 | PLAN
427985 | PLAN
427992 | PLAN
427999 | PLAN
428006 | PLAN
428013 | PLAN
428020 | PLAN
428027 | PLAN
428034 | PLAN
428041 | PLAN
428048 | PLAN
428055 | PLAN
428062 | PLAN
428069 | PLAN
428076 | PLAN
428083 | PLAN
428090 | PLAN
428097 | PLAN
428104 | PLAN
428111 | PLAN
428118 | PLAN
428125 | PLAN
428132 | PLAN
428139 | PLAN
428146 | PLAN
428153 | PLAN
428160 | PLAN
428167 | PLAN
428174 | PLAN
428181 | PLAN
428188 | PLAN
428195 | PLAN
428202 | PLAN
428209 | PLAN
428216 | PLAN
428223 | PLAN
428230 | PLAN
428237 | PLAN
428244 | PLAN
428251 | PLAN
428258 | PLAN
428265 | PLAN
428272 | PLAN
428279 | PLAN
428286 | PLAN
428293 | PLAN
428300 | PLAN
428307 | PLAN
428314 | PLAN
428321 | PLAN
428328 | PLAN
428335 | PLAN
428342 | PLAN
428349 | PLAN
428356 | PLAN
428363 | PLAN
428370 | PLAN
428377 | PLAN
428384 | PLAN
428391 | PLAN
428398 | PLAN
428405 | PLAN
428412 | PLAN
428419 | PLAN
428426 | PLAN
428433 | PLAN
428440 | PLAN
428447 | PLAN
428454 | PLAN
428461 | PLAN
428468 | PLAN
428475 | PLAN
428482 | PLAN
428489 | PLAN
428496 | PLAN
428503 | PLAN
428510 | PLAN
428517 | PLAN
428524 | PLAN
428531 | PLAN
428538 | PLAN
428545 | PLAN
428552 | PLAN
428559 | PLAN
428566 | PLAN
428573 | PLAN
428580 | PLAN
428587 | PLAN
428594 | PLAN
428601 | PLAN
428608 | PLAN
428615 | PLAN
428622 | PLAN
428629 | PLAN
428636 | PLAN
428643 | PLAN
428650 | PLAN
428657 | PLAN
428664 | PLAN
428671 | PLAN
428678 | PLAN
428685 | PLAN
428692 | PLAN
428699 | PLAN
428706 | PLAN
428713 | PLAN
428720 | PLAN
428727 | PLAN
428734 | PLAN
428741 | PLAN
428748 | PLAN
428755 | PLAN
428762 | PLAN
428769 | PLAN
428776 | PLAN
428783 | PLAN
428790 | PLAN
428797 | PLAN
428804 | PLAN
428811 | PLAN
428818 | PLAN
428825 | PLAN
428832 | PLAN
428839 | PLAN
428846 | PLAN
428853 | PLAN
428860 | PLAN
428867 | PLAN
428874 | PLAN
428881 | PLAN
428888 | PLAN
428895 | PLAN
428902 | PLAN
428909 | PLAN
428916 | PLAN
428923 | PLAN
428930 | PLAN
428937 | PLAN
428944 | PLAN
428951 | PLAN
428958 | PLAN
428965 | PLAN
428972 | PLAN
428979 | PLAN
428986 | PLAN
428993 | PLAN
429000 | PLAN
429007 | PLAN
429014 | PLAN
429021 | PLAN
429028 | PLAN
429035 | PLAN
429042 | PLAN
429049 | PLAN
429056 | PLAN
429063 | PLAN
429070 | PLAN
429077 | PLAN
429084 | PLAN
429091 | PLAN
429098 | PLAN
429105 | PLAN
429112 | PLAN
429119 | PLAN
429126 | PLAN
429133 | PLAN
429140 | PLAN
429147 | PLAN
429154 | PLAN
429161 | PLAN
429168 | PLAN
429175 | PLAN
429182 | PLAN
429189 | PLAN
429196 | PLAN
429203 | PLAN
429210 | PLAN
429217 | PLAN
429224 | PLAN
429231 | PLAN
429238 | PLAN
429245 | PLAN
429252 | PLAN
429259 | PLAN
429266 | PLAN
429273 | PLAN
429280 | PLAN
429287 | PLAN
429294 | PLAN
429301 | PLAN
429308 | PLAN
429315 | PLAN
429322 | PLAN
429329 | PLAN
429336 | PLAN
429343 | PLAN
429350 | PLAN
429357 | PLAN
429364 | PLAN
429371 | PLAN
429378 | PLAN
429385 | PLAN
429392 | PLAN
429399 | PLAN
429406 | PLAN
429413 | PLAN
429420 | PLAN
429427 | PLAN
429434 | PLAN
429441 | PLAN
429448 | PLAN
429455 | PLAN
429462 | PLAN
429469 | PLAN
429476 | PLAN
429483 | PLAN
429490 | PLAN
429497 | PLAN
429504 | PLAN
429511 | PLAN
429518 | PLAN
429525 | PLAN
429532 | PLAN
429539 | PLAN
429546 | PLAN
429553 | PLAN
429560 | PLAN
429567 | PLAN
429574 | PLAN
429581 | PLAN
429588 | PLAN
429595 | PLAN
429602 | PLAN
429609 | PLAN
429616 | PLAN
429623 | PLAN
429630 | PLAN
429637 | PLAN
429644 | PLAN
429651 | PLAN
429658 | PLAN
429665 | PLAN
429672 | PLAN
429679 | PLAN
429686 | PLAN
429693 | PLAN
429700 | PLAN
429707 | PLAN
429714 | PLAN
429721 | PLAN
429728 | PLAN
429735 | PLAN
429742 | PLAN
429749 | PLAN
429756 | PLAN
429763 | PLAN
429770 | PLAN
429777 | PLAN
429784 | PLAN
429791 | PLAN
429798 | PLAN
429805 | PLAN
429812 | PLAN
429819 | PLAN
429826 | PLAN
429833 | PLAN
429840 | PLAN
429847 | PLAN
429854 | PLAN
429861 | PLAN
429868 | PLAN
429875 | PLAN
429882 | PLAN
429889 | PLAN
429896 | PLAN
429903 | PLAN
429910 | PLAN
429917 | PLAN
429924 | PLAN
429931 | PLAN
429938 | PLAN
429945 | PLAN
429952 | PLAN
429959 | PLAN
429966 | PLAN
429973 | PLAN
429980 | PLAN
429987 | PLAN
429994 | PLAN
430001 | PLAN
430008 | PLAN
430015 | PLAN
430022 | PLAN
430029 | PLAN
430036 | PLAN
430043 | PLAN
430050 | PLAN
430057 | PLAN
430064 | PLAN
430071 | PLAN
430078 | PLAN
430085 | PLAN
430092 | PLAN
430099 | PLAN
430106 | PLAN
430113 | PLAN
430120 | PLAN
430127 | PLAN
430134 | PLAN
430141 | PLAN
430148 | PLAN
430155 | PLAN
430162 | PLAN
430169 | PLAN
430176 | PLAN
430183 | PLAN
430190 | PLAN
430197 | PLAN
430204 | PLAN
430211 | PLAN
430218 | PLAN
430225 | PLAN
430232 | PLAN
430239 | PLAN
430246 | PLAN
430253 | PLAN
430260 | PLAN
430267 | PLAN
430274 | PLAN
430281 | PLAN
430288 | PLAN
430295 | PLAN
430302 | PLAN
430309 | PLAN
430316 | PLAN
430323 | PLAN
430330 | PLAN
430337 | PLAN
430344 | PLAN
430351 | PLAN
430358 | PLAN
430365 | PLAN
430372 | PLAN
430379 | PLAN
430386 | PLAN
430393 | PLAN
430400 | PLAN
430407 | PLAN
430414 | PLAN
430421 | PLAN
430428 | PLAN
430435 | PLAN
430442 | PLAN
430449 | PLAN
430456 | PLAN
430463 | PLAN
430470 | PLAN
430477 | PLAN
430484 | PLAN
430491 | PLAN
430498 | PLAN
430505 | PLAN
430512 | PLAN
430519 | PLAN
430526 | PLAN
430533 | PLAN
430540 | PLAN
430547 | PLAN
430554 | PLAN
430561 | PLAN
430568 | PLAN
430575 | PLAN
430582 | PLAN
430589 | PLAN
430596 | PLAN
430603 | PLAN
430610 | PLAN
430617 | PLAN
430624 | PLAN
430631 | PLAN
430638 | PLAN
430645 | PLAN
430652 | PLAN
430659 | PLAN
430666 | PLAN
430673 | PLAN
430680 | PLAN
430687 | PLAN
430694 | PLAN
430701 | PLAN
430708 | PLAN
430715 | PLAN
430722 | PLAN
430729 | PLAN
430736 | PLAN
430743 | PLAN
430750 | PLAN
430757 | PLAN
430764 | PLAN
430771 | PLAN
430778 | PLAN
430785 | PLAN
430792 | PLAN
430799 | PLAN
430806 | PLAN
430813 | PLAN
430820 | PLAN
430827 | PLAN
430834 | PLAN
430841 | PLAN
430848 | PLAN
430855 | PLAN
430862 | PLAN
430869 | PLAN
430876 | PLAN
430883 | PLAN
430890 | PLAN
430897 | PLAN
430904 | PLAN
430911 | PLAN
430918 | PLAN
430925 | PLAN
430932 | PLAN
430939 | PLAN
430946 | PLAN
430953 | PLAN
430960 | PLAN
430967 | PLAN
430974 | PLAN
430981 | PLAN
430988 | PLAN
430995 | PLAN
431002 | PLAN
431009 | PLAN
431016 | PLAN
431023 | PLAN
431030 | PLAN
431037 | PLAN
431044 | PLAN
431051 | PLAN
431058 | PLAN
431065 | PLAN
431072 | PLAN
431079 | PLAN
431086 | PLAN
431093 | PLAN
431100 | PLAN
431107 | PLAN
431114 | PLAN
431121 | PLAN
431128 | PLAN
431135 | PLAN
431142 | PLAN
431149 | PLAN
431156 | PLAN
431163 | PLAN
431170 | PLAN
431177 | PLAN
431184 | PLAN
431191 | PLAN
431198 | PLAN
431205 | PLAN
431212 | PLAN
431219 | PLAN
431226 | PLAN
431233 | PLAN
431240 | PLAN
431247 | PLAN
431254 | PLAN
431261 | PLAN
431268 | PLAN
431275 | PLAN
431282 | PLAN
431289 | PLAN
431296 | PLAN
431303 | PLAN
431310 | PLAN
431317 | PLAN
431324 | PLAN
431331 | PLAN
431338 | PLAN
431345 | PLAN
431352 | PLAN
431359 | PLAN
431366 | PLAN
431373 | PLAN
431380 | PLAN
431387 | PLAN
431394 | PLAN
431401 | PLAN
431408 | PLAN
431415 | PLAN
431422 | PLAN
431429 | PLAN
431436 | PLAN
431443 | PLAN
431450 | PLAN
431457 | PLAN
431464 | PLAN
431471 | PLAN
431478 | PLAN
431485 | PLAN
431492 | PLAN
431499 | PLAN
431506 | PLAN
431513 | PLAN
431520 | PLAN
431527 | PLAN
431534 | PLAN
431541 | PLAN
431548 | PLAN
431555 | PLAN
431562 | PLAN
431569 | PLAN
431576 | PLAN
431583 | PLAN
431590 | PLAN
431597 | PLAN
431604 | PLAN
431611 | PLAN
431618 | PLAN
431625 | PLAN
431632 | PLAN
431639 | PLAN
431646 | PLAN
431653 | PLAN
431660 | PLAN
431667 | PLAN
431674 | PLAN
431681 | PLAN
431688 | PLAN
431695 | PLAN
431702 | PLAN
431709 | PLAN
431716 | PLAN
431723 | PLAN
431730 | PLAN
431737 | PLAN
431744 | PLAN
431751 | PLAN
431758 | PLAN
431765 | PLAN
431772 | PLAN
431779 | PLAN
431786 | PLAN
431793 | PLAN
431800 | PLAN
431807 | PLAN
431814 | PLAN
431821 | PLAN
431828 | PLAN
431835 | PLAN
431842 | PLAN
431849 | PLAN
431856 | PLAN
431863 | PLAN
431870 | PLAN
431877 | PLAN
431884 | PLAN
431891 | PLAN
431898 | PLAN
431905 | PLAN
431912 | PLAN
431919 | PLAN
431926 | PLAN
431933 | PLAN
431940 | PLAN
431947 | PLAN
431954 | PLAN
431961 | PLAN
431968 | PLAN
431975 | PLAN
431982 | PLAN
431989 | PLAN
431996 | PLAN
432003 | PLAN
432010 | PLAN
432017 | PLAN
432024 | PLAN
432031 | PLAN
432038 | PLAN
432045 | PLAN
432052 | PLAN
432059 | PLAN
432066 | PLAN
432073 | PLAN
432080 | PLAN
432087 | PLAN
432094 | PLAN
432101 | PLAN
432108 | PLAN
432115 | PLAN
432122 | PLAN
432129 | PLAN
432136 | PLAN
432143 | PLAN
432150 | PLAN
432157 | PLAN
432164 | PLAN
432171 | PLAN
432178 | PLAN
432185 | PLAN
432192 | PLAN
432199 | PLAN
432206 | PLAN
432213 | PLAN
432220 | PLAN
432227 | PLAN
432234 | PLAN
432241 | PLAN
432248 | PLAN
432255 | PLAN
432262 | PLAN
432269 | PLAN
432276 | PLAN
432283 | PLAN
432290 | PLAN
432297 | PLAN
432304 | PLAN
432311 | PLAN
432318 | PLAN
432325 | PLAN
432332 | PLAN
432339 | PLAN
432346 | PLAN
432353 | PLAN
432360 | PLAN
432367 | PLAN
432374 | PLAN
432381 | PLAN
432388 | PLAN
432395 | PLAN
432402 | PLAN
432409 | PLAN
432416 | PLAN
432423 | PLAN
432430 | PLAN
432437 | PLAN
432444 | PLAN
432451 | PLAN
432458 | PLAN
432465 | PLAN
432472 | PLAN
432479 | PLAN
432486 | PLAN
432493 | PLAN
432500 | PLAN
432507 | PLAN
432514 | PLAN
432521 | PLAN
432528 | PLAN
432535 | PLAN
432542 | PLAN
432549 | PLAN
432556 | PLAN
432563 | PLAN
432570 | PLAN
432577 | PLAN
432584 | PLAN
432591 | PLAN
432598 | PLAN
432605 | PLAN
432612 | PLAN
432619 | PLAN
432626 | PLAN
432633 | PLAN
432640 | PLAN
432647 | PLAN
432654 | PLAN
432661 | PLAN
432668 | PLAN
432675 | PLAN
432682 | PLAN
432689 | PLAN
432696 | PLAN
432703 | PLAN
432710 | PLAN
432717 | PLAN
432724 | PLAN
432731 | PLAN
432738 | PLAN
432745 | PLAN
432752 | PLAN
432759 | PLAN
432766 | PLAN
432773 | PLAN
432780 | PLAN
432787 | PLAN
432794 | PLAN
432801 | PLAN
432808 | PLAN
432815 | PLAN
432822 | PLAN
432829 | PLAN
432836 | PLAN
432843 | PLAN
432850 | PLAN
432857 | PLAN
432864 | PLAN
432871 | PLAN
432878 | PLAN
432885 | PLAN
432892 | PLAN
432899 | PLAN
432906 | PLAN
432913 | PLAN
432920 | PLAN
432927 | PLAN
432934 | PLAN
432941 | PLAN
432948 | PLAN
432955 | PLAN
432962 | PLAN
432969 | PLAN
432976 | PLAN
432983 | PLAN
432990 | PLAN
432997 | PLAN
433004 | PLAN
433011 | PLAN
433018 | PLAN
433025 | PLAN
433032 | PLAN
433039 | PLAN
433046 | PLAN
433053 | PLAN
433060 | PLAN
433067 | PLAN
433074 | PLAN
433081 | PLAN
433088 | PLAN
433095 | PLAN
433102 | PLAN
433109 | PLAN
433116 | PLAN
433123 | PLAN
433130 | PLAN
433137 | PLAN
433144 | PLAN
433151 | PLAN
433158 | PLAN
433165 | PLAN
433172 | PLAN
433179 | PLAN
433186 | PLAN
433193 | PLAN
433200 | PLAN
433207 | PLAN
433214 | PLAN
433221 | PLAN
433228 | PLAN
433235 | PLAN
433242 | PLAN
433249 | PLAN
433256 | PLAN
433263 | PLAN
433270 | PLAN
433277 | PLAN
433284 | PLAN
433291 | PLAN
433298 | PLAN
433305 | PLAN
433312 | PLAN
433319 | PLAN
433326 | PLAN
433333 | PLAN
433340 | PLAN
433347 | PLAN
433354 | PLAN
433361 | PLAN
433368 | PLAN
433375 | PLAN
433382 | PLAN
433389 | PLAN
433396 | PLAN
433403 | PLAN
433410 | PLAN
433417 | PLAN
433424 | PLAN
433431 | PLAN
433438 | PLAN
433445 | PLAN
433452 | PLAN
433459 | PLAN
433466 | PLAN
433473 | PLAN
433480 | PLAN
433487 | PLAN
433494 | PLAN
433501 | PLAN
433508 | PLAN
433515 | PLAN
433522 | PLAN
433529 | PLAN
433536 | PLAN
433543 | PLAN
433550 | PLAN
433557 | PLAN
433564 | PLAN
433571 | PLAN
433578 | PLAN
433585 | PLAN
433592 | PLAN
433599 | PLAN
433606 | PLAN
433613 | PLAN
433620 | PLAN
433627 | PLAN
433634 | PLAN
433641 | PLAN
433648 | PLAN
433655 | PLAN
433662 | PLAN
433669 | PLAN
433676 | PLAN
433683 | PLAN
433690 | PLAN
433697 | PLAN
433704 | PLAN
433711 | PLAN
433718 | PLAN
433725 | PLAN
433732 | PLAN
433739 | PLAN
433746 | PLAN
433753 | PLAN
433760 | PLAN
433767 | PLAN
433774 | PLAN
433781 | PLAN
433788 | PLAN
433795 | PLAN
433802 | PLAN
433809 | PLAN
433816 | PLAN
433823 | PLAN
433830 | PLAN
433837 | PLAN
433844 | PLAN
433851 | PLAN
433858 | PLAN
433865 | PLAN
433872 | PLAN
433879 | PLAN
433886 | PLAN
433893 | PLAN
433900 | PLAN
433907 | PLAN
433914 | PLAN
433921 | PLAN
433928 | PLAN
433935 | PLAN
433942 | PLAN
433949 | PLAN
433956 | PLAN
433963 | PLAN
433970 | PLAN
433977 | PLAN
433984 | PLAN
433991 | PLAN
433998 | PLAN
434005 | PLAN
434012 | PLAN
434019 | PLAN
434026 | PLAN
434033 | PLAN
434040 | PLAN
434047 | PLAN
434054 | PLAN
434061 | PLAN
434068 | PLAN
434075 | PLAN
434082 | PLAN
434089 | PLAN
434096 | PLAN
434103 | PLAN
434110 | PLAN
434117 | PLAN
434124 | PLAN
434131 | PLAN
434138 | PLAN
434145 | PLAN
434152 | PLAN
434159 | PLAN
434166 | PLAN
434173 | PLAN
434180 | PLAN
434187 | PLAN
434194 | PLAN
434201 | PLAN
434208 | PLAN
434215 | PLAN
434222 | PLAN
434229 | PLAN
434236 | PLAN
434243 | PLAN
434250 | PLAN
434257 | PLAN
434264 | PLAN
434271 | PLAN
434278 | PLAN
434285 | PLAN
434292 | PLAN
434299 | PLAN
434306 | PLAN
434313 | PLAN
434320 | PLAN
434327 | PLAN
434334 | PLAN
434341 | PLAN
434348 | PLAN
434355 | PLAN
434362 | PLAN
434369 | PLAN
434376 | PLAN
434383 | PLAN
434390 | PLAN
434397 | PLAN
434404 | PLAN
434411 | PLAN
434418 | PLAN
434425 | PLAN
434432 | PLAN
434439 | PLAN
434446 | PLAN
434453 | PLAN
434460 | PLAN
434467 | PLAN
434474 | PLAN
434481 | PLAN
434488 | PLAN
434495 | PLAN
434502 | PLAN
434509 | PLAN
434516 | PLAN
434523 | PLAN
434530 | PLAN
434537 | PLAN
434544 | PLAN
434551 | PLAN
434558 | PLAN
434565 | PLAN
434572 | PLAN
434579 | PLAN
434586 | PLAN
434593 | PLAN
434600 | PLAN
434607 | PLAN
434614 | PLAN
434621 | PLAN
434628 | PLAN
434635 | PLAN
434642 | PLAN
434649 | PLAN
434656 | PLAN
434663 | PLAN
434670 | PLAN
434677 | PLAN
434684 | PLAN
434691 | PLAN
434698 | PLAN
434705 | PLAN
434712 | PLAN
434719 | PLAN
434726 | PLAN
434733 | PLAN
434740 | PLAN
434747 | PLAN
434754 | PLAN
434761 | PLAN
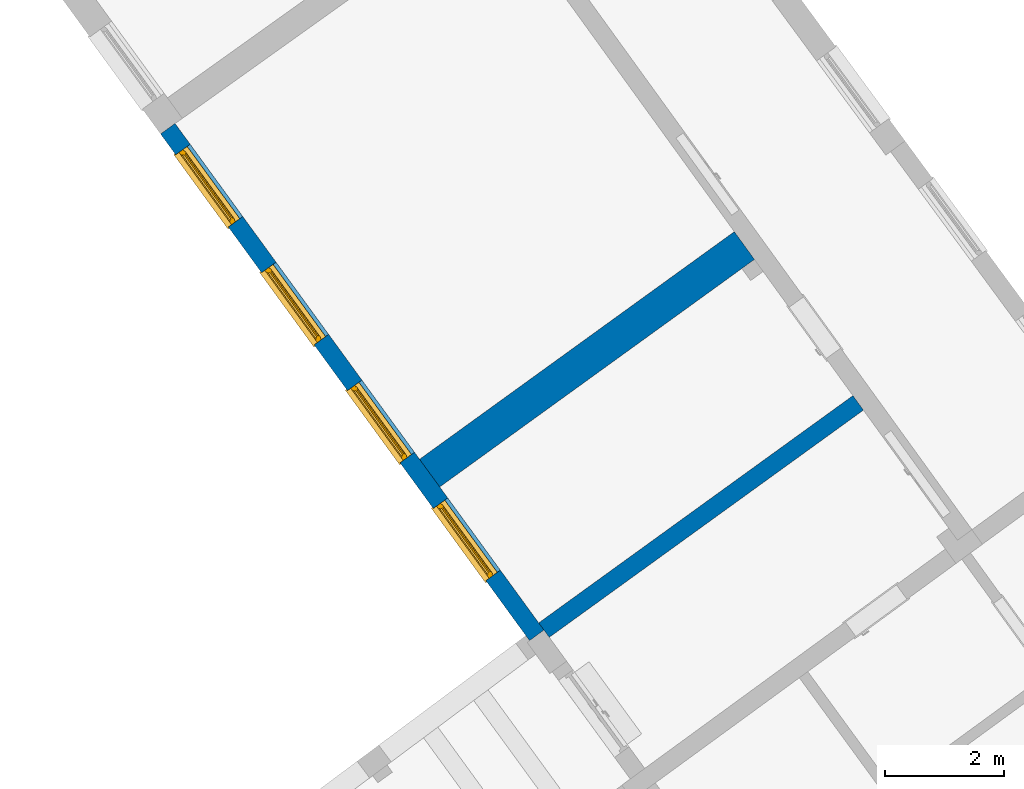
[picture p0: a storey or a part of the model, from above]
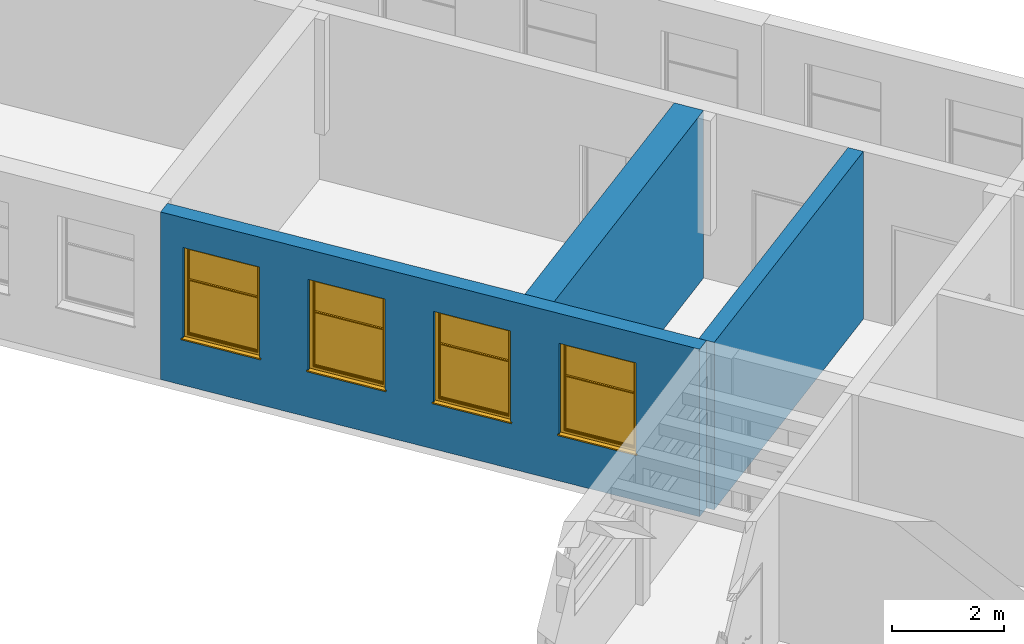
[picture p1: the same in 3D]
Properties of the parts of a building model (IFC2X3), part 10 of 13

# IfcSlab: Floor:Slab-179:1000 (17048)
Name (Floor:Slab-179:1000:...) | In
434768 | PLAN
434775 | PLAN
434782 | PLAN
434789 | PLAN
434796 | PLAN
434803 | PLAN
434810 | PLAN
434817 | PLAN
434824 | PLAN
434831 | PLAN
434838 | PLAN
434845 | PLAN
434852 | PLAN
434859 | PLAN
434866 | PLAN
434873 | PLAN
434880 | PLAN
434887 | PLAN
434894 | PLAN
434901 | PLAN
434908 | PLAN
434915 | PLAN
434922 | PLAN
434929 | PLAN
434936 | PLAN
434943 | PLAN
434950 | PLAN
434957 | PLAN
434964 | PLAN
434971 | PLAN
434978 | PLAN
434985 | PLAN
434992 | PLAN
434999 | PLAN
435006 | PLAN
435013 | PLAN
435020 | PLAN
435027 | PLAN
435034 | PLAN
435041 | PLAN
435048 | PLAN
435055 | PLAN
435062 | PLAN
435069 | PLAN
435076 | PLAN
435083 | PLAN
435090 | PLAN
435097 | PLAN
435104 | PLAN
435111 | PLAN
435118 | PLAN
435125 | PLAN
435132 | PLAN
435139 | PLAN
435146 | PLAN
435153 | PLAN
435160 | PLAN
435167 | PLAN
435174 | PLAN
435181 | PLAN
435188 | PLAN
435195 | PLAN
435202 | PLAN
435209 | PLAN
435216 | PLAN
435223 | PLAN
435230 | PLAN
435237 | PLAN
435244 | PLAN
435251 | PLAN
435258 | PLAN
435265 | PLAN
435272 | PLAN
435279 | PLAN
435286 | PLAN
435293 | PLAN
435300 | PLAN
435307 | PLAN
435314 | PLAN
435321 | PLAN
435328 | PLAN
435335 | PLAN
435342 | PLAN
435349 | PLAN
435356 | PLAN
435363 | PLAN
435370 | PLAN
435377 | PLAN
435384 | PLAN
435391 | PLAN
435398 | PLAN
435405 | PLAN
435412 | PLAN
435419 | PLAN
435426 | PLAN
435433 | PLAN
435440 | PLAN
435447 | PLAN
435454 | PLAN
435461 | PLAN
435468 | PLAN
435475 | PLAN
435482 | PLAN
435489 | PLAN
435496 | PLAN
435503 | PLAN
435510 | PLAN
435517 | PLAN
435524 | PLAN
435531 | PLAN
435538 | PLAN
435545 | PLAN
435552 | PLAN
435559 | PLAN
435566 | PLAN
435573 | PLAN
435580 | PLAN
435587 | PLAN
435594 | PLAN
435601 | PLAN
435608 | PLAN
435615 | PLAN
435622 | PLAN
435629 | PLAN
435636 | PLAN
435643 | PLAN
435650 | PLAN
435657 | PLAN
435664 | PLAN
435671 | PLAN
435678 | PLAN
435685 | PLAN
435692 | PLAN
435699 | PLAN
435706 | PLAN
435713 | PLAN
435720 | PLAN
435727 | PLAN
435734 | PLAN
435741 | PLAN
435748 | PLAN
435755 | PLAN
435762 | PLAN
435769 | PLAN
435776 | PLAN
435783 | PLAN
435790 | PLAN
435797 | PLAN
435804 | PLAN
435811 | PLAN
435818 | PLAN
435825 | PLAN
435832 | PLAN
435839 | PLAN
435846 | PLAN
435853 | PLAN
435860 | PLAN
435867 | PLAN
435874 | PLAN
435881 | PLAN
435888 | PLAN
435895 | PLAN
435902 | PLAN
435909 | PLAN
435916 | PLAN
435923 | PLAN
435930 | PLAN
435937 | PLAN
435944 | PLAN
435951 | PLAN
435958 | PLAN
435965 | PLAN
435972 | PLAN
435979 | PLAN
435986 | PLAN
435993 | PLAN
436000 | PLAN
436007 | PLAN
436014 | PLAN
436021 | PLAN
436028 | PLAN
436035 | PLAN
436042 | PLAN
436049 | PLAN
436056 | PLAN
436063 | PLAN
436070 | PLAN
436077 | PLAN
436084 | PLAN
436091 | PLAN
436098 | PLAN
436105 | PLAN
436112 | PLAN
436119 | PLAN
436126 | PLAN
436133 | PLAN
436140 | PLAN
436147 | PLAN
436154 | PLAN
436161 | PLAN
436168 | PLAN
436175 | PLAN
436182 | PLAN
436189 | PLAN
436196 | PLAN
436203 | PLAN
436210 | PLAN
436217 | PLAN
436224 | PLAN
436231 | PLAN
436238 | PLAN
436245 | PLAN
436252 | PLAN
436259 | PLAN
436266 | PLAN
436273 | PLAN
436280 | PLAN
436287 | PLAN
436294 | PLAN
436301 | PLAN
436308 | PLAN
436315 | PLAN
436322 | PLAN
436329 | PLAN
436336 | PLAN
436343 | PLAN
436350 | PLAN
436357 | PLAN
436364 | PLAN
436371 | PLAN
436378 | PLAN
436385 | PLAN
436392 | PLAN
436399 | PLAN
436406 | PLAN
436413 | PLAN
436420 | PLAN
436427 | PLAN
436434 | PLAN
436441 | PLAN
436448 | PLAN
436455 | PLAN
436462 | PLAN
436469 | PLAN
436476 | PLAN
436483 | PLAN
436490 | PLAN
436497 | PLAN
436504 | PLAN
436511 | PLAN
436518 | PLAN
436525 | PLAN
436532 | PLAN
436539 | PLAN
436546 | PLAN
436553 | PLAN
436560 | PLAN
436567 | PLAN
436574 | PLAN
436581 | PLAN
436588 | PLAN
436595 | PLAN
436602 | PLAN
436609 | PLAN
436616 | PLAN
436623 | PLAN
436630 | PLAN
436637 | PLAN
436644 | PLAN
436651 | PLAN
436658 | PLAN
436665 | PLAN
436672 | PLAN
436679 | PLAN
436686 | PLAN
436693 | PLAN
436700 | PLAN
436707 | PLAN
436714 | PLAN
436721 | PLAN
436728 | PLAN
436735 | PLAN
436742 | PLAN
436749 | PLAN
436756 | PLAN
436763 | PLAN
436770 | PLAN
436777 | PLAN
436784 | PLAN
436791 | PLAN
436798 | PLAN
436805 | PLAN
436812 | PLAN
436819 | PLAN
436826 | PLAN
436833 | PLAN
436840 | PLAN
436847 | PLAN
436854 | PLAN
436861 | PLAN
436868 | PLAN
436875 | PLAN
436882 | PLAN
436889 | PLAN
436896 | PLAN
436903 | PLAN
436910 | PLAN
436917 | PLAN
436924 | PLAN
436931 | PLAN
436938 | PLAN
436945 | PLAN
436952 | PLAN
436959 | PLAN
436966 | PLAN
436973 | PLAN
436980 | PLAN
436987 | PLAN
436994 | PLAN
437001 | PLAN
437008 | PLAN
437015 | PLAN
437022 | PLAN
437029 | PLAN
437036 | PLAN
437043 | PLAN
437050 | PLAN
437057 | PLAN
437064 | PLAN
437071 | PLAN
437078 | PLAN
437085 | PLAN
437092 | PLAN
437099 | PLAN
437106 | PLAN
437113 | PLAN
437120 | PLAN
437127 | PLAN
437134 | PLAN
437141 | PLAN
437148 | PLAN
437155 | PLAN
437162 | PLAN
437169 | PLAN
437176 | PLAN
437183 | PLAN
437190 | PLAN
437197 | PLAN
437204 | PLAN
437211 | PLAN
437218 | PLAN
437225 | PLAN
437232 | PLAN
437239 | PLAN
437246 | PLAN
437253 | PLAN
437260 | PLAN
437267 | PLAN
437274 | PLAN
437281 | PLAN
437288 | PLAN
437295 | PLAN
437302 | PLAN
437309 | PLAN
437316 | PLAN
437323 | PLAN
437330 | PLAN
437337 | PLAN
437344 | PLAN
437351 | PLAN
437358 | PLAN
437365 | PLAN
437372 | PLAN
437379 | PLAN
437386 | PLAN
437393 | PLAN
437400 | PLAN
437407 | PLAN
437414 | PLAN
437421 | PLAN
437428 | PLAN
437435 | PLAN
437442 | PLAN
437449 | PLAN
437456 | PLAN
437463 | PLAN
437470 | PLAN
437477 | PLAN
437484 | PLAN
437491 | PLAN
437498 | PLAN
437505 | PLAN
437512 | PLAN
437519 | PLAN
437526 | PLAN
437533 | PLAN
437540 | PLAN
437547 | PLAN
437554 | PLAN
437561 | PLAN
437568 | PLAN
437575 | PLAN
437582 | PLAN
437589 | PLAN
437596 | PLAN
437603 | PLAN
437610 | PLAN
437617 | PLAN
437624 | PLAN
437631 | PLAN
437638 | PLAN
437645 | PLAN
437652 | PLAN
437659 | PLAN
437666 | PLAN
437673 | PLAN
437680 | PLAN
437687 | PLAN
437694 | PLAN
437701 | PLAN
437708 | PLAN
437715 | PLAN
437722 | PLAN
437729 | PLAN
437736 | PLAN
437743 | PLAN
437750 | PLAN
437757 | PLAN
437764 | PLAN
437771 | PLAN
437778 | PLAN
437785 | PLAN
437792 | PLAN
437799 | PLAN
437806 | PLAN
437813 | PLAN
437820 | PLAN
437827 | PLAN
437834 | PLAN
437841 | PLAN
437848 | PLAN
437855 | PLAN
437862 | PLAN
437869 | PLAN
437876 | PLAN
437883 | PLAN
437890 | PLAN
437897 | PLAN
437904 | PLAN
437911 | PLAN
437918 | PLAN
437925 | PLAN
437932 | PLAN
437939 | PLAN
437946 | PLAN
437953 | PLAN
437960 | PLAN
437967 | PLAN
437974 | PLAN
437981 | PLAN
437988 | PLAN
437995 | PLAN
438002 | PLAN
438009 | PLAN
438016 | PLAN
438023 | PLAN
438030 | PLAN
438037 | PLAN
438044 | PLAN
438051 | PLAN
438058 | PLAN
438065 | PLAN
438072 | PLAN
438079 | PLAN
438086 | PLAN
438093 | PLAN
438100 | PLAN
438107 | PLAN
438114 | PLAN
438121 | PLAN
438128 | PLAN
438135 | PLAN
438142 | PLAN
438149 | PLAN
438156 | PLAN
438163 | PLAN
438170 | PLAN
438177 | PLAN
438184 | PLAN
438191 | PLAN
438198 | PLAN
438205 | PLAN
438212 | PLAN
438219 | PLAN
438226 | PLAN
438233 | PLAN
438240 | PLAN
438247 | PLAN
438254 | PLAN
438261 | PLAN
438268 | PLAN
438275 | PLAN
438282 | PLAN
438289 | PLAN
438296 | PLAN
438303 | PLAN
438310 | PLAN
438317 | PLAN
438324 | PLAN
438331 | PLAN
438338 | PLAN
438345 | PLAN
438352 | PLAN
438359 | PLAN
438366 | PLAN
438373 | PLAN
438380 | PLAN
438387 | PLAN
438394 | PLAN
438401 | PLAN
438408 | PLAN
438415 | PLAN
438422 | PLAN
438429 | PLAN
438436 | PLAN
438443 | PLAN
438450 | PLAN
438457 | PLAN
438464 | PLAN
438471 | PLAN
438478 | PLAN
438485 | PLAN
438492 | PLAN
438499 | PLAN
438506 | PLAN
438513 | PLAN
438520 | PLAN
438527 | PLAN
438534 | PLAN
438541 | PLAN
438548 | PLAN
438555 | PLAN
438562 | PLAN
438569 | PLAN
438576 | PLAN
438583 | PLAN
438590 | PLAN
438597 | PLAN
438604 | PLAN
438611 | PLAN
438618 | PLAN
438625 | PLAN
438632 | PLAN
438639 | PLAN
438646 | PLAN
438653 | PLAN
438660 | PLAN
438667 | PLAN
438674 | PLAN
438681 | PLAN
438688 | PLAN
438695 | PLAN
438702 | PLAN
438709 | PLAN
438716 | PLAN
438723 | PLAN
438730 | PLAN
438737 | PLAN
438744 | PLAN
438751 | PLAN
438758 | PLAN
438765 | PLAN
438772 | PLAN
438779 | PLAN
438786 | PLAN
438793 | PLAN
438800 | PLAN
438807 | PLAN
438814 | PLAN
438821 | PLAN
438828 | PLAN
438835 | PLAN
438842 | PLAN
438849 | PLAN
438856 | PLAN
438863 | PLAN
438870 | PLAN
438877 | PLAN
438884 | PLAN
438891 | PLAN
438898 | PLAN
438905 | PLAN
438912 | PLAN
438919 | PLAN
438926 | PLAN
438933 | PLAN
438940 | PLAN
438947 | PLAN
438954 | PLAN
438961 | PLAN
438968 | PLAN
438975 | PLAN
438982 | PLAN
438989 | PLAN
438996 | PLAN
439003 | PLAN
439010 | PLAN
439017 | PLAN
439024 | PLAN
439031 | PLAN
439038 | PLAN
439045 | PLAN
439052 | PLAN
439059 | PLAN
439066 | PLAN
439073 | PLAN
439080 | PLAN
439087 | PLAN
439094 | PLAN
439101 | PLAN
439108 | PLAN
439115 | PLAN
439122 | PLAN
439129 | PLAN
439136 | PLAN
439143 | PLAN
439150 | PLAN
439157 | PLAN
439164 | PLAN
439171 | PLAN
439178 | PLAN
439185 | PLAN
439192 | PLAN
439199 | PLAN
439206 | PLAN
439213 | PLAN
439220 | PLAN
439227 | PLAN
439234 | PLAN
439241 | PLAN
439248 | PLAN
439255 | PLAN
439262 | PLAN
439269 | PLAN
439276 | PLAN
439283 | PLAN
439290 | PLAN
439297 | PLAN
439304 | PLAN
439311 | PLAN
439318 | PLAN
439325 | PLAN
439332 | PLAN
439339 | PLAN
439346 | PLAN
439353 | PLAN
439360 | PLAN
439367 | PLAN
439374 | PLAN
439381 | PLAN
439388 | PLAN
439395 | PLAN
439402 | PLAN
439409 | PLAN
439416 | PLAN
439423 | PLAN
439430 | PLAN
439437 | PLAN
439444 | PLAN
439451 | PLAN
439458 | PLAN
439465 | PLAN
439472 | PLAN
439479 | PLAN
439486 | PLAN
439493 | PLAN
439500 | PLAN
439507 | PLAN
439514 | PLAN
439521 | PLAN
439528 | PLAN
439535 | PLAN
439542 | PLAN
439549 | PLAN
439556 | PLAN
439563 | PLAN
439570 | PLAN
439577 | PLAN
439584 | PLAN
439591 | PLAN
439598 | PLAN
439605 | PLAN
439612 | PLAN
439619 | PLAN
439626 | PLAN
439633 | PLAN
439640 | PLAN
439647 | PLAN
439654 | PLAN
439661 | PLAN
439668 | PLAN
439675 | PLAN
439682 | PLAN
439689 | PLAN
439696 | PLAN
439703 | PLAN
439710 | PLAN
439717 | PLAN
439724 | PLAN
439731 | PLAN
439738 | PLAN
439745 | PLAN
439752 | PLAN
439759 | PLAN
439766 | PLAN
439773 | PLAN
439780 | PLAN
439787 | PLAN
439794 | PLAN
439801 | PLAN
439808 | PLAN
439815 | PLAN
439822 | PLAN
439829 | PLAN
439836 | PLAN
439843 | PLAN
439850 | PLAN
439857 | PLAN
439864 | PLAN
439871 | PLAN
439878 | PLAN
439885 | PLAN
439892 | PLAN
439899 | PLAN
439906 | PLAN
439913 | PLAN
439920 | PLAN
439927 | PLAN
439934 | PLAN
439941 | PLAN
439948 | PLAN
439955 | PLAN
439962 | PLAN
439969 | PLAN
439976 | PLAN
439983 | PLAN
439990 | PLAN
439997 | PLAN
440004 | PLAN
440011 | PLAN
440018 | PLAN
440025 | PLAN
440032 | PLAN
440039 | PLAN
440046 | PLAN
440053 | PLAN
440060 | PLAN
440067 | PLAN
440074 | PLAN
440081 | PLAN
440088 | PLAN
440095 | PLAN
440102 | PLAN
440109 | PLAN
440118 | PLAN
440125 | PLAN
440132 | PLAN
440139 | PLAN
440146 | PLAN
440153 | PLAN
440160 | PLAN
440167 | PLAN
440174 | PLAN
440181 | PLAN
440188 | PLAN
440195 | PLAN
440202 | PLAN
440209 | PLAN
440216 | PLAN
440223 | PLAN
440230 | PLAN
440237 | PLAN
440244 | PLAN
440251 | PLAN
440258 | PLAN
440265 | PLAN
440272 | PLAN
440279 | PLAN
440286 | PLAN
440293 | PLAN
440300 | PLAN
440307 | PLAN
440314 | PLAN
440321 | PLAN
440328 | PLAN
440335 | PLAN
440342 | PLAN
440349 | PLAN
440356 | PLAN
440363 | PLAN
440370 | PLAN
440377 | PLAN
440384 | PLAN
440391 | PLAN
440398 | PLAN
440405 | PLAN
440412 | PLAN
440419 | PLAN
440426 | PLAN
440433 | PLAN
440440 | PLAN
440447 | PLAN
440454 | PLAN
440461 | PLAN
440468 | PLAN
440475 | PLAN
440482 | PLAN
440489 | PLAN
440496 | PLAN
440503 | PLAN
440510 | PLAN
440517 | PLAN
440524 | PLAN
440531 | PLAN
440538 | PLAN
440545 | PLAN
440552 | PLAN
440559 | PLAN
440566 | PLAN
440573 | PLAN
440580 | PLAN
440587 | PLAN
440594 | PLAN
440601 | PLAN
440608 | PLAN
440615 | PLAN
440622 | PLAN
440629 | PLAN
440636 | PLAN
440643 | PLAN
440650 | PLAN
440657 | PLAN
440664 | PLAN
440671 | PLAN
440678 | PLAN
440685 | PLAN
440692 | PLAN
440699 | PLAN
440706 | PLAN
440713 | PLAN
440720 | PLAN
440727 | PLAN
440734 | PLAN
440741 | PLAN
440748 | PLAN
440755 | PLAN
440762 | PLAN
440769 | PLAN
440776 | PLAN
440783 | PLAN
440790 | PLAN
440797 | PLAN
440804 | PLAN
440811 | PLAN
440818 | PLAN
440825 | PLAN
440832 | PLAN
440839 | PLAN
440846 | PLAN
440853 | PLAN
440860 | PLAN
440867 | PLAN
440874 | PLAN
440881 | PLAN
440888 | PLAN
440895 | PLAN
440902 | PLAN
440909 | PLAN
440916 | PLAN
440923 | PLAN
440930 | PLAN
440937 | PLAN
440944 | PLAN
440951 | PLAN
440958 | PLAN
440965 | PLAN
440972 | PLAN
440979 | PLAN
440986 | PLAN
440993 | PLAN
441000 | PLAN
441007 | PLAN
441014 | PLAN
441021 | PLAN
441028 | PLAN
441035 | PLAN
441042 | PLAN
441049 | PLAN
441056 | PLAN
441063 | PLAN
441070 | PLAN
441077 | PLAN
441084 | PLAN
441091 | PLAN
441098 | PLAN
441105 | PLAN
441112 | PLAN
441119 | PLAN
441126 | PLAN
441133 | PLAN
441140 | PLAN
441147 | PLAN
441154 | PLAN
441161 | PLAN
441168 | PLAN
441175 | PLAN
441182 | PLAN
441189 | PLAN
441196 | PLAN
441203 | PLAN
441210 | PLAN
441217 | PLAN
441224 | PLAN
441231 | PLAN
441238 | PLAN
441245 | PLAN
441252 | PLAN
441259 | PLAN
441266 | PLAN
441273 | PLAN
441280 | PLAN
441287 | PLAN
441294 | PLAN
441301 | PLAN
441308 | PLAN
441315 | PLAN
441322 | PLAN
441329 | PLAN
441336 | PLAN
441343 | PLAN
441350 | PLAN
441357 | PLAN
441364 | PLAN
441371 | PLAN
441378 | PLAN
441385 | PLAN
441392 | PLAN
441399 | PLAN
441406 | PLAN
441413 | PLAN
441420 | PLAN
441427 | PLAN
441434 | PLAN
441441 | PLAN
441448 | PLAN
441455 | PLAN
441462 | PLAN
441469 | PLAN
441476 | PLAN
441483 | PLAN
441490 | PLAN
441497 | PLAN
441504 | PLAN
441511 | PLAN
441518 | PLAN
441525 | PLAN
441532 | PLAN
441539 | PLAN
441546 | PLAN
441553 | PLAN
441560 | PLAN
441567 | PLAN
441574 | PLAN
441581 | PLAN
441588 | PLAN
441595 | PLAN
441602 | PLAN
441609 | PLAN
441616 | PLAN
441623 | PLAN
441630 | PLAN
441637 | PLAN
441644 | PLAN
441651 | PLAN
441658 | PLAN
441665 | PLAN
441672 | PLAN
441679 | PLAN
441686 | PLAN
441693 | PLAN
441700 | PLAN
441707 | PLAN
441714 | PLAN
441721 | PLAN
441728 | PLAN
441735 | PLAN
441742 | PLAN
441749 | PLAN
441756 | PLAN
441763 | PLAN
441770 | PLAN
441777 | PLAN
441784 | PLAN
441791 | PLAN
441798 | PLAN
441805 | PLAN
441812 | PLAN
441819 | PLAN
441826 | PLAN
441833 | PLAN
441840 | PLAN
441847 | PLAN
441854 | PLAN
441861 | PLAN
441868 | PLAN
441875 | PLAN
441882 | PLAN
441889 | PLAN
441896 | PLAN
441903 | PLAN
441910 | PLAN
441917 | PLAN
441924 | PLAN
441931 | PLAN
441938 | PLAN
441945 | PLAN
441952 | PLAN
441959 | PLAN
441966 | PLAN
441973 | PLAN
441980 | PLAN
441987 | PLAN
441994 | PLAN
442001 | PLAN
442008 | PLAN
442015 | PLAN
442022 | PLAN
442029 | PLAN
442036 | PLAN
442043 | PLAN
442050 | PLAN
442057 | PLAN
442064 | PLAN
442071 | PLAN
442078 | PLAN
442085 | PLAN
442092 | PLAN
442099 | PLAN
442106 | PLAN
442113 | PLAN
442120 | PLAN
442127 | PLAN
442134 | PLAN
442141 | PLAN
442148 | PLAN
442155 | PLAN
442162 | PLAN
442169 | PLAN
442176 | PLAN
442183 | PLAN
442190 | PLAN
442197 | PLAN
442204 | PLAN
442211 | PLAN
442218 | PLAN
442225 | PLAN
442232 | PLAN
442239 | PLAN
442246 | PLAN
442253 | PLAN
442260 | PLAN
442267 | PLAN
442274 | PLAN
442281 | PLAN
442288 | PLAN
442295 | PLAN
442302 | PLAN
442309 | PLAN
442316 | PLAN
442323 | PLAN
442330 | PLAN
442337 | PLAN
442344 | PLAN
442351 | PLAN
442358 | PLAN
442365 | PLAN
442372 | PLAN
442379 | PLAN
442386 | PLAN
442393 | PLAN
442400 | PLAN
442407 | PLAN
442414 | PLAN
442421 | PLAN
442428 | PLAN
442435 | PLAN
442442 | PLAN
442449 | PLAN
442456 | PLAN
442463 | PLAN
442470 | PLAN
442477 | PLAN
442484 | PLAN
442491 | PLAN
442498 | PLAN
442505 | PLAN
442512 | PLAN
442519 | PLAN
442526 | PLAN
442533 | PLAN
442540 | PLAN
442547 | PLAN
442554 | PLAN
442561 | PLAN
442568 | PLAN
442575 | PLAN
442582 | PLAN
442589 | PLAN
442596 | PLAN
442603 | PLAN
442610 | PLAN
442617 | PLAN
442624 | PLAN
442631 | PLAN
442638 | PLAN
442645 | PLAN
442652 | PLAN
442659 | PLAN
442666 | PLAN
442673 | PLAN
442680 | PLAN
442687 | PLAN
442694 | PLAN
442701 | PLAN
442708 | PLAN
442715 | PLAN
442722 | PLAN
442729 | PLAN
442736 | PLAN
442743 | PLAN
442750 | PLAN
442757 | PLAN
442764 | PLAN
442771 | PLAN
442778 | PLAN
442785 | PLAN
442792 | PLAN
442800 | PLAN
442807 | PLAN
442814 | PLAN
442821 | PLAN
442828 | PLAN
442835 | PLAN
442842 | PLAN
442849 | PLAN
442856 | PLAN
442863 | PLAN
442870 | PLAN
442877 | PLAN
442884 | PLAN
442891 | PLAN
442898 | PLAN
442905 | PLAN
442912 | PLAN
442919 | PLAN
442926 | PLAN
442933 | PLAN
442940 | PLAN
442947 | PLAN
442954 | PLAN
442961 | PLAN
442968 | PLAN
442975 | PLAN
442982 | PLAN
442989 | PLAN
442996 | PLAN
443003 | PLAN
443010 | PLAN
443017 | PLAN
443024 | PLAN
443032 | PLAN
443039 | PLAN
443046 | PLAN
443053 | PLAN
443060 | PLAN
443067 | PLAN
443074 | PLAN
443081 | PLAN
443088 | PLAN
443095 | PLAN
443102 | PLAN
443109 | PLAN
443116 | PLAN
443123 | PLAN
443130 | PLAN
443137 | PLAN
443144 | PLAN
443151 | PLAN
443158 | PLAN
443165 | PLAN
443172 | PLAN
443179 | PLAN
443186 | PLAN
443193 | PLAN
443200 | PLAN
443207 | PLAN
443214 | PLAN
443221 | PLAN
443228 | PLAN
443235 | PLAN
443242 | PLAN
443249 | PLAN
443256 | PLAN
443263 | PLAN
443270 | PLAN
443277 | PLAN
443284 | PLAN
443291 | PLAN
443298 | PLAN
443305 | PLAN
443312 | PLAN
443319 | PLAN
443326 | PLAN
443333 | PLAN
443340 | PLAN
443347 | PLAN
443354 | PLAN
443361 | PLAN
443368 | PLAN
443375 | PLAN
443382 | PLAN
443389 | PLAN
443396 | PLAN
443403 | PLAN
443410 | PLAN
443417 | PLAN
443424 | PLAN
443431 | PLAN
443438 | PLAN
443445 | PLAN
443452 | PLAN
443459 | PLAN
443466 | PLAN
443473 | PLAN
443480 | PLAN
443487 | PLAN
443494 | PLAN
443501 | PLAN
443508 | PLAN
443515 | PLAN
443522 | PLAN
443529 | PLAN
443536 | PLAN
443543 | PLAN
443550 | PLAN
443557 | PLAN
443564 | PLAN
443571 | PLAN
443578 | PLAN
443585 | PLAN
443592 | PLAN
443599 | PLAN
443606 | PLAN
443613 | PLAN
443620 | PLAN
443627 | PLAN
443634 | PLAN
443641 | PLAN
443648 | PLAN
443655 | PLAN
443662 | PLAN
443669 | PLAN
443676 | PLAN
443683 | PLAN
443690 | PLAN
443697 | PLAN
443704 | PLAN
443711 | PLAN
443718 | PLAN
443725 | PLAN
443732 | PLAN
443739 | PLAN
443746 | PLAN
443753 | PLAN
443760 | PLAN
443767 | PLAN
443774 | PLAN
443781 | PLAN
443788 | PLAN
443795 | PLAN
443802 | PLAN
443809 | PLAN
443816 | PLAN
443823 | PLAN
443830 | PLAN
443837 | PLAN
443844 | PLAN
443851 | PLAN
443858 | PLAN
443865 | PLAN
443872 | PLAN
443879 | PLAN
443886 | PLAN
443893 | PLAN
443900 | PLAN
443907 | PLAN
443914 | PLAN
443921 | PLAN
443928 | PLAN
443935 | PLAN
443942 | PLAN
443949 | PLAN
443956 | PLAN
443963 | PLAN
443970 | PLAN
443977 | PLAN
443984 | PLAN
443991 | PLAN
443998 | PLAN
444005 | PLAN
444012 | PLAN
444019 | PLAN
444026 | PLAN
444033 | PLAN
444040 | PLAN
444047 | PLAN
444054 | PLAN
444061 | PLAN
444068 | PLAN
444075 | PLAN
444082 | PLAN
444089 | PLAN
444096 | PLAN
444103 | PLAN
444110 | PLAN
444117 | PLAN
444124 | PLAN
444131 | PLAN
444138 | PLAN
444145 | PLAN
444152 | PLAN
444159 | PLAN
444166 | PLAN
444173 | PLAN
444180 | PLAN
444187 | PLAN
444194 | PLAN
444201 | PLAN
444208 | PLAN
444215 | PLAN
444222 | PLAN
444229 | PLAN
444236 | PLAN
444243 | PLAN
444250 | PLAN
444257 | PLAN
444264 | PLAN
444271 | PLAN
444278 | PLAN
444285 | PLAN
444292 | PLAN
444299 | PLAN
444306 | PLAN
444313 | PLAN
444320 | PLAN
444327 | PLAN
444334 | PLAN
444341 | PLAN
444348 | PLAN
444355 | PLAN
444362 | PLAN
444369 | PLAN
444376 | PLAN
444383 | PLAN
444390 | PLAN
444397 | PLAN
444404 | PLAN
444411 | PLAN
444418 | PLAN
444425 | PLAN
444432 | PLAN
444439 | PLAN
444446 | PLAN
444453 | PLAN
444460 | PLAN
444467 | PLAN
444474 | PLAN
444481 | PLAN
444488 | PLAN
444495 | PLAN
444502 | PLAN
444509 | PLAN
444516 | PLAN
444523 | PLAN
444530 | PLAN
444537 | PLAN
444544 | PLAN
444551 | PLAN
444558 | PLAN
444565 | PLAN
444572 | PLAN
444579 | PLAN
444586 | PLAN
444593 | PLAN
444600 | PLAN
444607 | PLAN
444614 | PLAN
444621 | PLAN
444628 | PLAN
444635 | PLAN
444642 | PLAN
444649 | PLAN
444656 | PLAN
444663 | PLAN
444670 | PLAN
444677 | PLAN
444684 | PLAN
444691 | PLAN
444698 | PLAN
444705 | PLAN
444712 | PLAN
444719 | PLAN
444726 | PLAN
444733 | PLAN
444740 | PLAN
444747 | PLAN
444754 | PLAN
444761 | PLAN
444768 | PLAN
444775 | PLAN
444782 | PLAN
444789 | PLAN
444796 | PLAN
444803 | PLAN
444810 | PLAN
444817 | PLAN
444824 | PLAN
444831 | PLAN
444838 | PLAN
444845 | PLAN
444852 | PLAN
444859 | PLAN
444866 | PLAN
444873 | PLAN
444880 | PLAN
444887 | PLAN
444894 | PLAN
444901 | PLAN
444908 | PLAN
444915 | PLAN
444922 | PLAN
444929 | PLAN
444936 | PLAN
444943 | PLAN
444950 | PLAN
444957 | PLAN
444964 | PLAN
444971 | PLAN
444978 | PLAN
444985 | PLAN
444992 | PLAN
444999 | PLAN
445006 | PLAN
445013 | PLAN
445020 | PLAN
445027 | PLAN
445034 | PLAN
445041 | PLAN
445048 | PLAN
445055 | PLAN
445062 | PLAN
445069 | PLAN
445076 | PLAN
445083 | PLAN
445090 | PLAN
445097 | PLAN
445104 | PLAN
445111 | PLAN
445118 | PLAN
445125 | PLAN
445132 | PLAN
445139 | PLAN
445146 | PLAN
445153 | PLAN
445160 | PLAN
445167 | PLAN
445174 | PLAN
445181 | PLAN
445188 | PLAN
445195 | PLAN
445202 | PLAN
445209 | PLAN
445216 | PLAN
445223 | PLAN
445230 | PLAN
445237 | PLAN
445244 | PLAN
445251 | PLAN
445258 | PLAN
445265 | PLAN
445272 | PLAN
445279 | PLAN
445286 | PLAN
445293 | PLAN
445300 | PLAN
445307 | PLAN
445314 | PLAN
445321 | PLAN
445328 | PLAN
445335 | PLAN
445342 | PLAN
445349 | PLAN
445356 | PLAN
445363 | PLAN
445370 | PLAN
445377 | PLAN
445384 | PLAN
445391 | PLAN
445398 | PLAN
445405 | PLAN
445412 | PLAN
445419 | PLAN
445426 | PLAN
445433 | PLAN
445440 | PLAN
445447 | PLAN
445454 | PLAN
445461 | PLAN
445468 | PLAN
445475 | PLAN
445482 | PLAN
445489 | PLAN
445496 | PLAN
445503 | PLAN
445510 | PLAN
445517 | PLAN
445524 | PLAN
445531 | PLAN
445538 | PLAN
445545 | PLAN
445552 | PLAN
445559 | PLAN
445566 | PLAN
445573 | PLAN
445580 | PLAN
445587 | PLAN
445594 | PLAN
445601 | PLAN
445608 | PLAN
445615 | PLAN
445622 | PLAN
445629 | PLAN
445636 | PLAN
445643 | PLAN
445650 | PLAN
445657 | PLAN
445663 | PLAN
445670 | PLAN
445678 | PLAN
445684 | PLAN
445691 | PLAN
445698 | PLAN
445705 | PLAN
445712 | PLAN
445719 | PLAN
445726 | PLAN
445733 | PLAN
445740 | PLAN
445747 | PLAN
445754 | PLAN
445761 | PLAN
445768 | PLAN
445775 | PLAN
445782 | PLAN
445789 | PLAN
445796 | PLAN
445803 | PLAN
445810 | PLAN
445817 | PLAN
445824 | PLAN
445831 | PLAN
445838 | PLAN
445845 | PLAN
445852 | PLAN
445859 | PLAN
445866 | PLAN
445873 | PLAN
445880 | PLAN
445887 | PLAN
445894 | PLAN
445901 | PLAN
445908 | PLAN
445915 | PLAN
445922 | PLAN
445929 | PLAN
445936 | PLAN
445943 | PLAN
445950 | PLAN
445957 | PLAN
445964 | PLAN
445971 | PLAN
445978 | PLAN
445985 | PLAN
445992 | PLAN
445999 | PLAN
446006 | PLAN
446013 | PLAN
446020 | PLAN
446027 | PLAN
446034 | PLAN
446041 | PLAN
446048 | PLAN
446055 | PLAN
446062 | PLAN
446069 | PLAN
446076 | PLAN
446083 | PLAN
446090 | PLAN
446097 | PLAN
446104 | PLAN
446111 | PLAN
446118 | PLAN
446125 | PLAN
446132 | PLAN
446139 | PLAN
446146 | PLAN
446153 | PLAN
446160 | PLAN
446167 | PLAN
446174 | PLAN
446181 | PLAN
446188 | PLAN
446195 | PLAN
446202 | PLAN
446209 | PLAN
446216 | PLAN
446223 | PLAN
446230 | PLAN
446237 | PLAN
446244 | PLAN
446251 | PLAN
446258 | PLAN
446265 | PLAN
446272 | PLAN
446279 | PLAN
446286 | PLAN
446293 | PLAN
446300 | PLAN
446307 | PLAN
446314 | PLAN
446321 | PLAN
446328 | PLAN
446335 | PLAN
446342 | PLAN
446349 | PLAN
446356 | PLAN
446363 | PLAN
446370 | PLAN
446377 | PLAN
446384 | PLAN
446391 | PLAN
446398 | PLAN
446405 | PLAN
446412 | PLAN
446419 | PLAN
446426 | PLAN
446433 | PLAN
446440 | PLAN
446447 | PLAN
446454 | PLAN
446461 | PLAN
446468 | PLAN
446475 | PLAN
446482 | PLAN
446489 | PLAN
446496 | PLAN
446503 | PLAN
446510 | PLAN
446517 | PLAN
446524 | PLAN
446531 | PLAN
446538 | PLAN
446545 | PLAN
446552 | PLAN
446559 | PLAN
446566 | PLAN
446573 | PLAN
446580 | PLAN
446587 | PLAN
446594 | PLAN
446601 | PLAN
446608 | PLAN
446615 | PLAN
446622 | PLAN
446629 | PLAN
446636 | PLAN
446643 | PLAN
446650 | PLAN
446657 | PLAN
446664 | PLAN
446671 | PLAN
446678 | PLAN
446685 | PLAN
446692 | PLAN
446699 | PLAN
446706 | PLAN
446713 | PLAN
446720 | PLAN
446727 | PLAN
446734 | PLAN
446741 | PLAN
446748 | PLAN
446755 | PLAN
446762 | PLAN
446769 | PLAN
446776 | PLAN
446783 | PLAN
446790 | PLAN
446797 | PLAN
446804 | PLAN
446811 | PLAN
446818 | PLAN
446825 | PLAN
446832 | PLAN
446839 | PLAN
446846 | PLAN
446853 | PLAN
446860 | PLAN
446867 | PLAN
446874 | PLAN
446881 | PLAN
446888 | PLAN
446895 | PLAN
446902 | PLAN
446909 | PLAN
446916 | PLAN
446923 | PLAN
446930 | PLAN
446937 | PLAN
446944 | PLAN
446951 | PLAN
446958 | PLAN
446965 | PLAN
446972 | PLAN
446979 | PLAN
446986 | PLAN
446993 | PLAN
447000 | PLAN
447007 | PLAN
447014 | PLAN
447021 | PLAN
447028 | PLAN
447035 | PLAN
447042 | PLAN
447049 | PLAN
447056 | PLAN
447063 | PLAN
447070 | PLAN
447077 | PLAN
447084 | PLAN
447091 | PLAN
447098 | PLAN
447105 | PLAN
447112 | PLAN
447119 | PLAN
447126 | PLAN
447133 | PLAN
447140 | PLAN
447147 | PLAN
447154 | PLAN
447161 | PLAN
447168 | PLAN
447175 | PLAN
447182 | PLAN
447189 | PLAN
447196 | PLAN
447203 | PLAN
447210 | PLAN
447217 | PLAN
447224 | PLAN
447231 | PLAN
447238 | PLAN
447245 | PLAN
447252 | PLAN
447259 | PLAN
447266 | PLAN
447273 | PLAN
447280 | PLAN
447287 | PLAN
447294 | PLAN
447301 | PLAN
447308 | PLAN
447315 | PLAN
447322 | PLAN
447329 | PLAN
447336 | PLAN
447343 | PLAN
447350 | PLAN
447357 | PLAN
447364 | PLAN
447371 | PLAN
447378 | PLAN
447385 | PLAN
447392 | PLAN
447399 | PLAN
447406 | PLAN
447413 | PLAN
447420 | PLAN
447427 | PLAN
447434 | PLAN
447441 | PLAN
447448 | PLAN
447455 | PLAN
447462 | PLAN
447469 | PLAN
447476 | PLAN
447483 | PLAN
447490 | PLAN
447497 | PLAN
447504 | PLAN
447511 | PLAN
447518 | PLAN
447525 | PLAN
447532 | PLAN
447539 | PLAN
447546 | PLAN
447553 | PLAN
447560 | PLAN
447567 | PLAN
447574 | PLAN
447581 | PLAN
447588 | PLAN
447595 | PLAN
447602 | PLAN
447609 | PLAN
447616 | PLAN
447623 | PLAN
447630 | PLAN
447637 | PLAN
447644 | PLAN
447651 | PLAN
447658 | PLAN
447665 | PLAN
447672 | PLAN
447679 | PLAN
447686 | PLAN
447693 | PLAN
447700 | PLAN
447707 | PLAN
447714 | PLAN
447721 | PLAN
447728 | PLAN
447735 | PLAN
447742 | PLAN
447749 | PLAN
447756 | PLAN
447763 | PLAN
447770 | PLAN
447777 | PLAN
447784 | PLAN
447791 | PLAN
447798 | PLAN
447805 | PLAN
447812 | PLAN
447819 | PLAN
447826 | PLAN
447833 | PLAN
447840 | PLAN
447847 | PLAN
447854 | PLAN
447861 | PLAN
447868 | PLAN
447875 | PLAN
447882 | PLAN
447889 | PLAN
447896 | PLAN
447903 | PLAN
447910 | PLAN
447917 | PLAN
447924 | PLAN
447931 | PLAN
447938 | PLAN
447945 | PLAN
447952 | PLAN
447959 | PLAN
447966 | PLAN
447973 | PLAN
447980 | PLAN
447987 | PLAN
447994 | PLAN
448001 | PLAN
448008 | PLAN
448015 | PLAN
448022 | PLAN
448029 | PLAN
448036 | PLAN
448043 | PLAN
448050 | PLAN
448057 | PLAN
448064 | PLAN
448071 | PLAN
448078 | PLAN
448085 | PLAN
448092 | PLAN
448099 | PLAN
448106 | PLAN
448113 | PLAN
448120 | PLAN
448127 | PLAN
448134 | PLAN
448141 | PLAN
448148 | PLAN
448155 | PLAN
448162 | PLAN
448169 | PLAN
448176 | PLAN
448183 | PLAN
448190 | PLAN
448197 | PLAN
448204 | PLAN
448211 | PLAN
448218 | PLAN
448225 | PLAN
448232 | PLAN
448239 | PLAN
448246 | PLAN
448253 | PLAN
448260 | PLAN
448267 | PLAN
448274 | PLAN
448281 | PLAN
448288 | PLAN
448295 | PLAN
448302 | PLAN
448309 | PLAN
448316 | PLAN
448323 | PLAN
448330 | PLAN
448337 | PLAN
448344 | PLAN
448351 | PLAN
448358 | PLAN
448365 | PLAN
448372 | PLAN
448379 | PLAN
448386 | PLAN
448393 | PLAN
448400 | PLAN
448407 | PLAN
448414 | PLAN
448421 | PLAN
448428 | PLAN
448435 | PLAN
448442 | PLAN
448449 | PLAN
448456 | PLAN
448463 | PLAN
448470 | PLAN
448477 | PLAN
448484 | PLAN
448491 | PLAN
448498 | PLAN
448505 | PLAN
448512 | PLAN
448519 | PLAN
448526 | PLAN
448533 | PLAN
448540 | PLAN
448547 | PLAN
448554 | PLAN
448561 | PLAN
448568 | PLAN
448575 | PLAN
448582 | PLAN
448589 | PLAN
448596 | PLAN
448603 | PLAN
448610 | PLAN
448617 | PLAN
448624 | PLAN
448631 | PLAN
448638 | PLAN
448645 | PLAN
448652 | PLAN
448659 | PLAN
448666 | PLAN
448673 | PLAN
448680 | PLAN
448687 | PLAN
448694 | PLAN
448701 | PLAN
448708 | PLAN
448715 | PLAN
448722 | PLAN
448729 | PLAN
448736 | PLAN
448743 | PLAN
448750 | PLAN
448757 | PLAN
448764 | PLAN
448771 | PLAN
448778 | PLAN
448785 | PLAN
448792 | PLAN
448799 | PLAN
448806 | PLAN
448813 | PLAN
448820 | PLAN
448827 | PLAN
448834 | PLAN
448841 | PLAN
448848 | PLAN
448855 | PLAN
448862 | PLAN
448869 | PLAN
448876 | PLAN
448883 | PLAN
448890 | PLAN
448897 | PLAN
448904 | PLAN
448911 | PLAN
448918 | PLAN
448925 | PLAN
448932 | PLAN
448939 | PLAN
448946 | PLAN
448953 | PLAN
448960 | PLAN
448967 | PLAN
448974 | PLAN
448981 | PLAN
448988 | PLAN
448995 | PLAN
449002 | PLAN
449009 | PLAN
449016 | PLAN
449023 | PLAN
449030 | PLAN
449037 | PLAN
449044 | PLAN
449051 | PLAN
449058 | PLAN
449065 | PLAN
449072 | PLAN
449079 | PLAN
449086 | PLAN
449093 | PLAN
449100 | PLAN
449107 | PLAN
449114 | PLAN
449121 | PLAN
449128 | PLAN
449135 | PLAN
449142 | PLAN
449149 | PLAN
449156 | PLAN
449163 | PLAN
449170 | PLAN
449177 | PLAN
449184 | PLAN
449191 | PLAN
449198 | PLAN
449205 | PLAN
449212 | PLAN
449219 | PLAN
449226 | PLAN
449233 | PLAN
449240 | PLAN
449247 | PLAN
449254 | PLAN
449261 | PLAN
449268 | PLAN
449275 | PLAN
449282 | PLAN
449289 | PLAN
449296 | PLAN
449303 | PLAN
449310 | PLAN
449317 | PLAN
449324 | PLAN
449331 | PLAN
449338 | PLAN
449345 | PLAN
449352 | PLAN
449359 | PLAN
449366 | PLAN
449373 | PLAN
449380 | PLAN
449387 | PLAN
449394 | PLAN
449401 | PLAN
449408 | PLAN
449415 | PLAN
449422 | PLAN
449429 | PLAN
449436 | PLAN
449443 | PLAN
449450 | PLAN
449457 | PLAN
449464 | PLAN
449471 | PLAN
449478 | PLAN
449485 | PLAN
449492 | PLAN
449499 | PLAN
449506 | PLAN
449513 | PLAN
449520 | PLAN
449527 | PLAN
449534 | PLAN
449541 | PLAN
449548 | PLAN
449555 | PLAN
449562 | PLAN
449569 | PLAN
449576 | PLAN
449583 | PLAN
449590 | PLAN
449597 | PLAN
449604 | PLAN
449611 | PLAN
449618 | PLAN
449625 | PLAN
449632 | PLAN
449639 | PLAN
449646 | PLAN
449653 | PLAN
449660 | PLAN
449667 | PLAN
449674 | PLAN
449681 | PLAN
449688 | PLAN
449695 | PLAN
449702 | PLAN
449709 | PLAN
449716 | PLAN
449723 | PLAN
449730 | PLAN
449737 | PLAN
449744 | PLAN
449751 | PLAN
449758 | PLAN
449765 | PLAN
449772 | PLAN
449779 | PLAN
449786 | PLAN
449793 | PLAN
449800 | PLAN
449807 | PLAN
449814 | PLAN
449821 | PLAN
449828 | PLAN
449835 | PLAN
449842 | PLAN
449849 | PLAN
449856 | PLAN
449863 | PLAN
449870 | PLAN
449877 | PLAN
449884 | PLAN
449891 | PLAN
449898 | PLAN
449905 | PLAN
449912 | PLAN
449919 | PLAN
449926 | PLAN
449933 | PLAN
449940 | PLAN
449947 | PLAN
449954 | PLAN
449961 | PLAN
449968 | PLAN
449975 | PLAN
449982 | PLAN
449989 | PLAN
449996 | PLAN
450003 | PLAN
450010 | PLAN
450017 | PLAN
450024 | PLAN
450031 | PLAN
450038 | PLAN
450045 | PLAN
450052 | PLAN
450059 | PLAN
450066 | PLAN
450073 | PLAN
450080 | PLAN
450087 | PLAN
450094 | PLAN
450101 | PLAN
450108 | PLAN
450115 | PLAN
450122 | PLAN
450129 | PLAN
450136 | PLAN
450143 | PLAN
450150 | PLAN
450157 | PLAN
450164 | PLAN
450171 | PLAN
450178 | PLAN
450185 | PLAN
450192 | PLAN
450199 | PLAN
450206 | PLAN
450213 | PLAN
450220 | PLAN
450227 | PLAN
450234 | PLAN
450241 | PLAN
450248 | PLAN
450255 | PLAN
450262 | PLAN
450269 | PLAN
450276 | PLAN
450283 | PLAN
450290 | PLAN
450297 | PLAN
450304 | PLAN
450311 | PLAN
450318 | PLAN
450325 | PLAN
450332 | PLAN
450339 | PLAN
450346 | PLAN
450353 | PLAN
450360 | PLAN
450367 | PLAN
450374 | PLAN
450381 | PLAN
450388 | PLAN
450395 | PLAN
450402 | PLAN
450409 | PLAN
450416 | PLAN
450423 | PLAN
450430 | PLAN
450437 | PLAN
450444 | PLAN
450451 | PLAN
450458 | PLAN
450465 | PLAN
450472 | PLAN
450479 | PLAN
450486 | PLAN
450493 | PLAN
450500 | PLAN
450507 | PLAN
450514 | PLAN
450521 | PLAN
450528 | PLAN
450535 | PLAN
450542 | PLAN
450549 | PLAN
450556 | PLAN
450563 | PLAN
450570 | PLAN
450577 | PLAN
450584 | PLAN
450591 | PLAN
450598 | PLAN
450605 | PLAN
450612 | PLAN
450619 | PLAN
450626 | PLAN
450633 | PLAN
450640 | PLAN
450647 | PLAN
450654 | PLAN
450661 | PLAN
450668 | PLAN
450675 | PLAN
450682 | PLAN
450689 | PLAN
450696 | PLAN
450703 | PLAN
450710 | PLAN
450717 | PLAN
450724 | PLAN
450731 | PLAN
450738 | PLAN
450745 | PLAN
450752 | PLAN
450759 | PLAN
450766 | PLAN
450773 | PLAN
450780 | PLAN
450787 | PLAN
450794 | PLAN
450801 | PLAN
450808 | PLAN
450815 | PLAN
450822 | PLAN
450829 | PLAN
450836 | PLAN
450843 | PLAN
450850 | PLAN
450857 | PLAN
450864 | PLAN
450871 | PLAN
450878 | PLAN
450885 | PLAN
450892 | PLAN
450899 | PLAN
450906 | PLAN
450913 | PLAN
450920 | PLAN
450927 | PLAN
450934 | PLAN
450941 | PLAN
450948 | PLAN
450955 | PLAN
450962 | PLAN
450969 | PLAN
450976 | PLAN
450983 | PLAN
450990 | PLAN
450997 | PLAN
451004 | PLAN
451011 | PLAN
451018 | PLAN
451025 | PLAN
451032 | PLAN
451039 | PLAN
451046 | PLAN
451053 | PLAN
451060 | PLAN
451067 | PLAN
451074 | PLAN
451081 | PLAN
451088 | PLAN
451095 | PLAN
451102 | PLAN
451109 | PLAN
451116 | PLAN
451123 | PLAN
451130 | PLAN
451137 | PLAN
451144 | PLAN
451151 | PLAN
451158 | PLAN
451165 | PLAN
451172 | PLAN
451179 | PLAN
451186 | PLAN
451193 | PLAN
451200 | PLAN
451207 | PLAN
451214 | PLAN
451221 | PLAN
451228 | PLAN
451235 | PLAN
451242 | PLAN
451249 | PLAN
451256 | PLAN
451263 | PLAN
451270 | PLAN
451277 | PLAN
451284 | PLAN
451291 | PLAN
451298 | PLAN
451305 | PLAN
451312 | PLAN
451319 | PLAN
451326 | PLAN
451333 | PLAN
451340 | PLAN
451347 | PLAN
451354 | PLAN
451361 | PLAN
451368 | PLAN
451375 | PLAN
451382 | PLAN
451389 | PLAN
451396 | PLAN
451403 | PLAN
451410 | PLAN
451417 | PLAN
451424 | PLAN
451431 | PLAN
451438 | PLAN
451445 | PLAN
451452 | PLAN
451459 | PLAN
451466 | PLAN
451473 | PLAN
451480 | PLAN
451487 | PLAN
451494 | PLAN
451501 | PLAN
451508 | PLAN
451515 | PLAN
451522 | PLAN
451529 | PLAN
451536 | PLAN
451543 | PLAN
451550 | PLAN
451557 | PLAN
451564 | PLAN
451571 | PLAN
451578 | PLAN
451585 | PLAN
451592 | PLAN
451599 | PLAN
451606 | PLAN
451613 | PLAN
451620 | PLAN
451627 | PLAN
451634 | PLAN
451641 | PLAN
451648 | PLAN
451655 | PLAN
451662 | PLAN
451669 | PLAN
451676 | PLAN
451683 | PLAN
451690 | PLAN
451697 | PLAN
451704 | PLAN
451711 | PLAN
451718 | PLAN
451725 | PLAN
451732 | PLAN
451739 | PLAN
451746 | PLAN
451753 | PLAN
451760 | PLAN
451767 | PLAN
451774 | PLAN
451781 | PLAN
451788 | PLAN
451795 | PLAN
451802 | PLAN
451809 | PLAN
451816 | PLAN
451823 | PLAN
451830 | PLAN
451837 | PLAN
451844 | PLAN
451851 | PLAN
451858 | PLAN
451865 | PLAN
451872 | PLAN
451879 | PLAN
451886 | PLAN
451893 | PLAN
451900 | PLAN
451907 | PLAN
451914 | PLAN
451921 | PLAN
451928 | PLAN
451935 | PLAN
451942 | PLAN
451949 | PLAN
451956 | PLAN
451963 | PLAN
451970 | PLAN
451977 | PLAN
451984 | PLAN
451991 | PLAN
451998 | PLAN
452005 | PLAN
452012 | PLAN
452019 | PLAN
452026 | PLAN
452033 | PLAN
452040 | PLAN
452047 | PLAN
452054 | PLAN
452061 | PLAN
452068 | PLAN
452075 | PLAN
452082 | PLAN
452089 | PLAN
452096 | PLAN
452103 | PLAN
452110 | PLAN
452117 | PLAN
452124 | PLAN
452131 | PLAN
452138 | PLAN
452145 | PLAN
452152 | PLAN
452159 | PLAN
452166 | PLAN
452173 | PLAN
452180 | PLAN
452187 | PLAN
452194 | PLAN
452201 | PLAN
452208 | PLAN
452215 | PLAN
452222 | PLAN
452229 | PLAN
452236 | PLAN
452243 | PLAN
452250 | PLAN
452257 | PLAN
452264 | PLAN
452271 | PLAN
452278 | PLAN
452285 | PLAN
452292 | PLAN
452299 | PLAN
452306 | PLAN
452313 | PLAN
452320 | PLAN
452327 | PLAN
452334 | PLAN
452341 | PLAN
452348 | PLAN
452355 | PLAN
452362 | PLAN
452369 | PLAN
452376 | PLAN
452383 | PLAN
452390 | PLAN
452397 | PLAN
452404 | PLAN
452411 | PLAN
452418 | PLAN
452425 | PLAN
452432 | PLAN
452439 | PLAN
452446 | PLAN
452453 | PLAN
452460 | PLAN
452467 | PLAN
452474 | PLAN
452481 | PLAN
452488 | PLAN
452495 | PLAN
452502 | PLAN
452509 | PLAN
452516 | PLAN
452523 | PLAN
452530 | PLAN
452537 | PLAN
452544 | PLAN
452551 | PLAN
452558 | PLAN
452565 | PLAN
452572 | PLAN
452579 | PLAN
452586 | PLAN
452593 | PLAN
452600 | PLAN
452607 | PLAN
452614 | PLAN
452621 | PLAN
452628 | PLAN
452635 | PLAN
452642 | PLAN
452649 | PLAN
452656 | PLAN
452663 | PLAN
452670 | PLAN
452677 | PLAN
452684 | PLAN
452691 | PLAN
452698 | PLAN
452705 | PLAN
452712 | PLAN
452719 | PLAN
452726 | PLAN
452733 | PLAN
452740 | PLAN
452747 | PLAN
452754 | PLAN
452761 | PLAN
452768 | PLAN
452775 | PLAN
452782 | PLAN
452789 | PLAN
452796 | PLAN
452803 | PLAN
452810 | PLAN
452817 | PLAN
452824 | PLAN
452831 | PLAN
452838 | PLAN
452845 | PLAN
452852 | PLAN
452859 | PLAN
452866 | PLAN
452873 | PLAN
452880 | PLAN
452887 | PLAN
452894 | PLAN
452901 | PLAN
452908 | PLAN
452915 | PLAN
452922 | PLAN
452929 | PLAN
452936 | PLAN
452943 | PLAN
452950 | PLAN
452957 | PLAN
452964 | PLAN
452971 | PLAN
452978 | PLAN
452985 | PLAN
452992 | PLAN
452999 | PLAN
453006 | PLAN
453013 | PLAN
453020 | PLAN
453027 | PLAN
453034 | PLAN
453041 | PLAN
453048 | PLAN
453055 | PLAN
453062 | PLAN
453069 | PLAN
453076 | PLAN
453083 | PLAN
453090 | PLAN
453097 | PLAN
453104 | PLAN
453111 | PLAN
453118 | PLAN
453125 | PLAN
453132 | PLAN
453139 | PLAN
453146 | PLAN
453153 | PLAN
453160 | PLAN
453167 | PLAN
453174 | PLAN
453181 | PLAN
453188 | PLAN
453195 | PLAN
453202 | PLAN
453209 | PLAN
453216 | PLAN
453223 | PLAN
453230 | PLAN
453237 | PLAN
453244 | PLAN
453251 | PLAN
453258 | PLAN
453265 | PLAN
453272 | PLAN
453279 | PLAN
453286 | PLAN
453293 | PLAN
453300 | PLAN
453307 | PLAN
453314 | PLAN
453321 | PLAN
453328 | PLAN
453335 | PLAN
453342 | PLAN
453349 | PLAN
453356 | PLAN
453363 | PLAN
453370 | PLAN
453377 | PLAN
453384 | PLAN
453391 | PLAN
453398 | PLAN
453405 | PLAN
453412 | PLAN
453419 | PLAN
453426 | PLAN
453433 | PLAN
453440 | PLAN
453447 | PLAN
453454 | PLAN
453461 | PLAN
453468 | PLAN
453475 | PLAN
453482 | PLAN
453489 | PLAN
453496 | PLAN
453503 | PLAN
453510 | PLAN
453517 | PLAN
453524 | PLAN
453531 | PLAN
453538 | PLAN
453545 | PLAN
453552 | PLAN
453559 | PLAN
453566 | PLAN
453573 | PLAN
453580 | PLAN
453587 | PLAN
453594 | PLAN
453601 | PLAN
453608 | PLAN
453615 | PLAN
453622 | PLAN
453629 | PLAN
453636 | PLAN
453643 | PLAN
453650 | PLAN
453657 | PLAN
453664 | PLAN
453671 | PLAN
453678 | PLAN
453685 | PLAN
453692 | PLAN
453699 | PLAN
453706 | PLAN
453713 | PLAN
453720 | PLAN
453727 | PLAN
453734 | PLAN
453741 | PLAN
453748 | PLAN
453755 | PLAN
453762 | PLAN
453769 | PLAN
453776 | PLAN
453783 | PLAN
453790 | PLAN
453797 | PLAN
453804 | PLAN
453811 | PLAN
453818 | PLAN
453825 | PLAN
453832 | PLAN
453839 | PLAN
453846 | PLAN
453853 | PLAN
453860 | PLAN
453867 | PLAN
453874 | PLAN
453881 | PLAN
453888 | PLAN
453895 | PLAN
453902 | PLAN
453909 | PLAN
453916 | PLAN
453923 | PLAN
453930 | PLAN
453937 | PLAN
453944 | PLAN
453951 | PLAN
453958 | PLAN
453965 | PLAN
453972 | PLAN
453979 | PLAN
453986 | PLAN
453993 | PLAN
454000 | PLAN
454007 | PLAN
454014 | PLAN
454021 | PLAN
454028 | PLAN
454035 | PLAN
454042 | PLAN
454049 | PLAN
454056 | PLAN
454063 | PLAN
454070 | PLAN
454077 | PLAN
454084 | PLAN
454091 | PLAN
454098 | PLAN
454105 | PLAN
454112 | PLAN
454119 | PLAN
454126 | PLAN
454133 | PLAN
454140 | PLAN
454147 | PLAN
454154 | PLAN
454161 | PLAN
454168 | PLAN
454175 | PLAN
454182 | PLAN
454189 | PLAN
454196 | PLAN
454203 | PLAN
454210 | PLAN
454217 | PLAN
454224 | PLAN
454231 | PLAN
454238 | PLAN
454245 | PLAN
454252 | PLAN
454259 | PLAN
454266 | PLAN
454273 | PLAN
454280 | PLAN
454287 | PLAN
454294 | PLAN
454301 | PLAN
454308 | PLAN
454315 | PLAN
454322 | PLAN
454329 | PLAN
454336 | PLAN
454343 | PLAN
454350 | PLAN
454357 | PLAN
454364 | PLAN
454371 | PLAN
454378 | PLAN
454385 | PLAN
454392 | PLAN
454399 | PLAN
454406 | PLAN
454413 | PLAN
454420 | PLAN
454427 | PLAN
454434 | PLAN
454441 | PLAN
454448 | PLAN
454455 | PLAN
454462 | PLAN
454469 | PLAN
454476 | PLAN
454483 | PLAN
454490 | PLAN
454497 | PLAN
454504 | PLAN
454511 | PLAN
454518 | PLAN
454525 | PLAN
454532 | PLAN
454539 | PLAN
454546 | PLAN
454553 | PLAN
454560 | PLAN
454567 | PLAN
454574 | PLAN
454581 | PLAN
454588 | PLAN
454595 | PLAN
454602 | PLAN
454609 | PLAN
454616 | PLAN
454623 | PLAN
454630 | PLAN
454637 | PLAN
454644 | PLAN
454651 | PLAN
454658 | PLAN
454665 | PLAN
454672 | PLAN
454679 | PLAN
454686 | PLAN
454693 | PLAN
454700 | PLAN
454707 | PLAN
454714 | PLAN
454721 | PLAN
454728 | PLAN
454735 | PLAN
454742 | PLAN
454749 | PLAN
454756 | PLAN
454763 | PLAN
454770 | PLAN
454777 | PLAN
454784 | PLAN
454791 | PLAN
454798 | PLAN
454805 | PLAN
454812 | PLAN
454819 | PLAN
454826 | PLAN
454833 | PLAN
454840 | PLAN
454847 | PLAN
454854 | PLAN
454861 | PLAN
454868 | PLAN
454875 | PLAN
454882 | PLAN
454889 | PLAN
454896 | PLAN
454903 | PLAN
454910 | PLAN
454917 | PLAN
454924 | PLAN
454931 | PLAN
454938 | PLAN
454945 | PLAN
454952 | PLAN
454959 | PLAN
454966 | PLAN
454973 | PLAN
454980 | PLAN
454987 | PLAN
454994 | PLAN
455001 | PLAN
455008 | PLAN
455015 | PLAN
455022 | PLAN
455029 | PLAN
455036 | PLAN
455043 | PLAN
455050 | PLAN
455057 | PLAN
455064 | PLAN
455071 | PLAN
455078 | PLAN
455085 | PLAN
455092 | PLAN
455099 | PLAN
455106 | PLAN
455113 | PLAN
455120 | PLAN
455127 | PLAN
455134 | PLAN
455141 | PLAN
455148 | PLAN
455155 | PLAN
455162 | PLAN
455169 | PLAN
455176 | PLAN
455183 | PLAN
455190 | PLAN
455197 | PLAN
455204 | PLAN
455211 | PLAN
455218 | PLAN
455225 | PLAN
455232 | PLAN
455239 | PLAN
455246 | PLAN
455253 | PLAN
455260 | PLAN
455267 | PLAN
455274 | PLAN
455281 | PLAN
455288 | PLAN
455295 | PLAN
455302 | PLAN
455309 | PLAN
455316 | PLAN
455323 | PLAN
455330 | PLAN
455337 | PLAN
455344 | PLAN
455351 | PLAN
455358 | PLAN
455365 | PLAN
455372 | PLAN
455379 | PLAN
455386 | PLAN
455393 | PLAN
455400 | PLAN
455407 | PLAN
455414 | PLAN
455421 | PLAN
455428 | PLAN
455435 | PLAN
455442 | PLAN
455449 | PLAN
455456 | PLAN
455463 | PLAN
455470 | PLAN
455477 | PLAN
455484 | PLAN
455491 | PLAN
455498 | PLAN
455505 | PLAN
455512 | PLAN
455519 | PLAN
455526 | PLAN
455533 | PLAN
455540 | PLAN
455547 | PLAN
455554 | PLAN
455561 | PLAN
455568 | PLAN
455575 | PLAN
455582 | PLAN
455589 | PLAN
455596 | PLAN
455603 | PLAN
455610 | PLAN
455617 | PLAN
455624 | PLAN
455631 | PLAN
455638 | PLAN
455645 | PLAN
455652 | PLAN
455659 | PLAN
455666 | PLAN
455673 | PLAN
455680 | PLAN
455687 | PLAN
455694 | PLAN
455701 | PLAN
455708 | PLAN
455715 | PLAN
455722 | PLAN
455729 | PLAN
455736 | PLAN
455743 | PLAN
455750 | PLAN
455757 | PLAN
455764 | PLAN
455771 | PLAN
455778 | PLAN
455785 | PLAN
455792 | PLAN
455799 | PLAN
455806 | PLAN
455813 | PLAN
455820 | PLAN
455827 | PLAN
455834 | PLAN
455841 | PLAN
455848 | PLAN
455855 | PLAN
455862 | PLAN
455869 | PLAN
455876 | PLAN
455883 | PLAN
455890 | PLAN
455897 | PLAN
455904 | PLAN
455911 | PLAN
455918 | PLAN
455925 | PLAN
455932 | PLAN
455939 | PLAN
455946 | PLAN
455953 | PLAN
455960 | PLAN
455967 | PLAN
455974 | PLAN
455981 | PLAN
455988 | PLAN
455995 | PLAN
456002 | PLAN
456009 | PLAN
456016 | PLAN
456023 | PLAN
456030 | PLAN
456037 | PLAN
456044 | PLAN
456051 | PLAN
456058 | PLAN
456065 | PLAN
456072 | PLAN
456079 | PLAN
456086 | PLAN
456093 | PLAN
456100 | PLAN
456107 | PLAN
456114 | PLAN
456121 | PLAN
456128 | PLAN
456135 | PLAN
456142 | PLAN
456149 | PLAN
456156 | PLAN
456163 | PLAN
456170 | PLAN
456177 | PLAN
456184 | PLAN
456191 | PLAN
456198 | PLAN
456205 | PLAN
456212 | PLAN
456219 | PLAN
456226 | PLAN
456233 | PLAN
456240 | PLAN
456247 | PLAN
456254 | PLAN
456261 | PLAN
456268 | PLAN
456275 | PLAN
456282 | PLAN
456289 | PLAN
456296 | PLAN
456303 | PLAN
456310 | PLAN
456317 | PLAN
456324 | PLAN
456331 | PLAN
456338 | PLAN
456345 | PLAN
456352 | PLAN
456359 | PLAN
456366 | PLAN
456373 | PLAN
456380 | PLAN
456387 | PLAN
456394 | PLAN
456401 | PLAN
456408 | PLAN
456415 | PLAN
456422 | PLAN
456429 | PLAN
456436 | PLAN
456443 | PLAN
456450 | PLAN
456457 | PLAN
456464 | PLAN
456471 | PLAN
456478 | PLAN
456485 | PLAN
456492 | PLAN
456499 | PLAN
456506 | PLAN
456513 | PLAN
456520 | PLAN
456527 | PLAN
456534 | PLAN
456541 | PLAN
456548 | PLAN
456555 | PLAN
456562 | PLAN
456569 | PLAN
456576 | PLAN
456583 | PLAN
456590 | PLAN
456597 | PLAN
456604 | PLAN
456611 | PLAN
456618 | PLAN
456625 | PLAN
456632 | PLAN
456639 | PLAN
456646 | PLAN
456653 | PLAN
456660 | PLAN
456667 | PLAN
456674 | PLAN
456681 | PLAN
456688 | PLAN
456695 | PLAN
456702 | PLAN
456709 | PLAN
456716 | PLAN
456723 | PLAN
456730 | PLAN
456737 | PLAN
456744 | PLAN
456751 | PLAN
456758 | PLAN
456765 | PLAN
456772 | PLAN
456779 | PLAN
456786 | PLAN
456793 | PLAN
456800 | PLAN
456807 | PLAN
456814 | PLAN
456821 | PLAN
456828 | PLAN
456835 | PLAN
456842 | PLAN
456849 | PLAN
456856 | PLAN
456863 | PLAN
456870 | PLAN
456877 | PLAN
456884 | PLAN
456891 | PLAN
456898 | PLAN
456905 | PLAN
456912 | PLAN
456919 | PLAN
456926 | PLAN
456933 | PLAN
456940 | PLAN
456947 | PLAN
456954 | PLAN
456961 | PLAN
456968 | PLAN
456975 | PLAN
456982 | PLAN
456989 | PLAN
456996 | PLAN
457003 | PLAN
457010 | PLAN
457017 | PLAN
457024 | PLAN
457031 | PLAN
457038 | PLAN
457045 | PLAN
457052 | PLAN
457059 | PLAN
457066 | PLAN
457073 | PLAN
457080 | PLAN
457087 | PLAN
457094 | PLAN
457101 | PLAN
457108 | PLAN
457115 | PLAN
457122 | PLAN
457129 | PLAN
457136 | PLAN
457143 | PLAN
457150 | PLAN
457157 | PLAN
457164 | PLAN
457171 | PLAN
457178 | PLAN
457185 | PLAN
457192 | PLAN
457199 | PLAN
457206 | PLAN
457213 | PLAN
457220 | PLAN
457227 | PLAN
457234 | PLAN
457241 | PLAN
457248 | PLAN
457255 | PLAN
457262 | PLAN
457269 | PLAN
457276 | PLAN
457283 | PLAN
457290 | PLAN
457297 | PLAN
457304 | PLAN
457311 | PLAN
457318 | PLAN
457325 | PLAN
457332 | PLAN
457339 | PLAN
457346 | PLAN
457353 | PLAN
457360 | PLAN
457367 | PLAN
457374 | PLAN
457381 | PLAN
457388 | PLAN
457395 | PLAN
457402 | PLAN
457409 | PLAN
457416 | PLAN
457423 | PLAN
457430 | PLAN
457437 | PLAN
457444 | PLAN
457451 | PLAN
457458 | PLAN
457465 | PLAN
457472 | PLAN
457479 | PLAN
457486 | PLAN
457493 | PLAN
457500 | PLAN
457507 | PLAN
457514 | PLAN
457521 | PLAN
457528 | PLAN
457535 | PLAN
457542 | PLAN
457549 | PLAN
457556 | PLAN
457563 | PLAN
457570 | PLAN
457577 | PLAN
457584 | PLAN
457591 | PLAN
457598 | PLAN
457605 | PLAN
457612 | PLAN
457619 | PLAN
457626 | PLAN
457633 | PLAN
457640 | PLAN
457647 | PLAN
457654 | PLAN
457661 | PLAN
457668 | PLAN
457675 | PLAN
457682 | PLAN
457689 | PLAN
457696 | PLAN
457703 | PLAN
457710 | PLAN
457717 | PLAN
457724 | PLAN
457731 | PLAN
457738 | PLAN
457745 | PLAN
457752 | PLAN
457759 | PLAN
457766 | PLAN
457773 | PLAN
457780 | PLAN
457787 | PLAN
457794 | PLAN
457801 | PLAN
457808 | PLAN
457815 | PLAN
457822 | PLAN
457829 | PLAN
457836 | PLAN
457843 | PLAN
457850 | PLAN
457857 | PLAN
457864 | PLAN
457871 | PLAN
457878 | PLAN
457885 | PLAN
457892 | PLAN
457899 | PLAN
457906 | PLAN
457913 | PLAN
457920 | PLAN
457927 | PLAN
457934 | PLAN
457941 | PLAN
457948 | PLAN
457955 | PLAN
457962 | PLAN
457969 | PLAN
457976 | PLAN
457983 | PLAN
457990 | PLAN
457997 | PLAN
458004 | PLAN
458011 | PLAN
458018 | PLAN
458025 | PLAN
458032 | PLAN
458039 | PLAN
458046 | PLAN
458053 | PLAN
458060 | PLAN
458067 | PLAN
458074 | PLAN
458081 | PLAN
458088 | PLAN
458095 | PLAN
458102 | PLAN
458109 | PLAN
458116 | PLAN
458123 | PLAN
458130 | PLAN
458137 | PLAN
458144 | PLAN
458151 | PLAN
458158 | PLAN
458165 | PLAN
458172 | PLAN
458179 | PLAN
458186 | PLAN
458193 | PLAN
458200 | PLAN
458207 | PLAN
458214 | PLAN
458221 | PLAN
458228 | PLAN
458235 | PLAN
458242 | PLAN
458249 | PLAN
458256 | PLAN
458263 | PLAN
458270 | PLAN
458277 | PLAN
458284 | PLAN
458291 | PLAN
458298 | PLAN
458305 | PLAN
458312 | PLAN
458319 | PLAN
458326 | PLAN
458333 | PLAN
458340 | PLAN
458347 | PLAN
458354 | PLAN
458361 | PLAN
458368 | PLAN
458375 | PLAN
458382 | PLAN
458389 | PLAN
458396 | PLAN
458403 | PLAN
458410 | PLAN
458417 | PLAN
458424 | PLAN
458431 | PLAN
458438 | PLAN
458445 | PLAN
458452 | PLAN
458459 | PLAN
458466 | PLAN
458473 | PLAN
458480 | PLAN
458487 | PLAN
458494 | PLAN
458501 | PLAN
458508 | PLAN
458515 | PLAN
458522 | PLAN
458529 | PLAN
458536 | PLAN
458543 | PLAN
458550 | PLAN
458557 | PLAN
458564 | PLAN
458571 | PLAN
458578 | PLAN
458585 | PLAN
458592 | PLAN
458599 | PLAN
458606 | PLAN
458613 | PLAN
458620 | PLAN
458627 | PLAN
458634 | PLAN
458641 | PLAN
458648 | PLAN
458655 | PLAN
458662 | PLAN
458669 | PLAN
458676 | PLAN
458683 | PLAN
458690 | PLAN
458697 | PLAN
458704 | PLAN
458711 | PLAN
458718 | PLAN
458725 | PLAN
458732 | PLAN
458739 | PLAN
458746 | PLAN
458753 | PLAN
458760 | PLAN
458767 | PLAN
458774 | PLAN
458781 | PLAN
458788 | PLAN
458795 | PLAN
458802 | PLAN
458809 | PLAN
458816 | PLAN
458823 | PLAN
458830 | PLAN
458837 | PLAN
458844 | PLAN
458851 | PLAN
458858 | PLAN
458865 | PLAN
458872 | PLAN
458879 | PLAN
458886 | PLAN
458893 | PLAN
458900 | PLAN
458907 | PLAN
458914 | PLAN
458921 | PLAN
458928 | PLAN
458935 | PLAN
458942 | PLAN
458949 | PLAN
458956 | PLAN
458963 | PLAN
458970 | PLAN
458977 | PLAN
458984 | PLAN
458991 | PLAN
458998 | PLAN
459005 | PLAN
459012 | PLAN
459019 | PLAN
459026 | PLAN
459033 | PLAN
459040 | PLAN
459047 | PLAN
459054 | PLAN
459061 | PLAN
459068 | PLAN
459075 | PLAN
459082 | PLAN
459089 | PLAN
459096 | PLAN
459103 | PLAN
459110 | PLAN
459117 | PLAN
459124 | PLAN
459131 | PLAN
459138 | PLAN
459145 | PLAN
459152 | PLAN
459159 | PLAN
459166 | PLAN
459173 | PLAN
459180 | PLAN
459187 | PLAN
459194 | PLAN
459201 | PLAN
459208 | PLAN
459215 | PLAN
459222 | PLAN
459229 | PLAN
459236 | PLAN
459243 | PLAN
459250 | PLAN
459257 | PLAN
459264 | PLAN
459271 | PLAN
459278 | PLAN
459285 | PLAN
459292 | PLAN
459299 | PLAN
459306 | PLAN
459313 | PLAN
459320 | PLAN
459327 | PLAN
459334 | PLAN
459341 | PLAN
459348 | PLAN
459355 | PLAN
459362 | PLAN
459369 | PLAN
459376 | PLAN
459383 | PLAN
459390 | PLAN
459397 | PLAN
459404 | PLAN
459411 | PLAN
459418 | PLAN
459425 | PLAN
459432 | PLAN
459439 | PLAN
459446 | PLAN
459453 | PLAN
459460 | PLAN
459467 | PLAN
459474 | PLAN
459481 | PLAN
459488 | PLAN
459495 | PLAN
459502 | PLAN
459509 | PLAN
459516 | PLAN
459523 | PLAN
459530 | PLAN
459537 | PLAN
459544 | PLAN
459551 | PLAN
459558 | PLAN
459565 | PLAN
459572 | PLAN
459579 | PLAN
459586 | PLAN
459593 | PLAN
459600 | PLAN
459607 | PLAN
459614 | PLAN
459621 | PLAN
459628 | PLAN
459635 | PLAN
459642 | PLAN
459649 | PLAN
459656 | PLAN
459663 | PLAN
459670 | PLAN
459677 | PLAN
459684 | PLAN
459691 | PLAN
459698 | PLAN
459705 | PLAN
459712 | PLAN
459719 | PLAN
459726 | PLAN
459733 | PLAN
459740 | PLAN
459747 | PLAN
459754 | PLAN
459761 | PLAN
459768 | PLAN
459775 | PLAN
459782 | PLAN
459789 | PLAN
459796 | PLAN
459803 | PLAN
459810 | PLAN
459817 | PLAN
459824 | PLAN
459831 | PLAN
459838 | PLAN
459845 | PLAN
459852 | PLAN
459859 | PLAN
459866 | PLAN
459873 | PLAN
459880 | PLAN
459887 | PLAN
459894 | PLAN
459901 | PLAN
459908 | PLAN
459915 | PLAN
459922 | PLAN
459929 | PLAN
459936 | PLAN
459943 | PLAN
459950 | PLAN
459957 | PLAN
459964 | PLAN
459971 | PLAN
459978 | PLAN
459985 | PLAN
459992 | PLAN
459999 | PLAN
460006 | PLAN
460013 | PLAN
460020 | PLAN
460027 | PLAN
460034 | PLAN
460041 | PLAN
460048 | PLAN
460055 | PLAN
460062 | PLAN
460069 | PLAN
460076 | PLAN
460083 | PLAN
460090 | PLAN
460097 | PLAN
460104 | PLAN
460111 | PLAN
460118 | PLAN
460125 | PLAN
460132 | PLAN
460139 | PLAN
460146 | PLAN
460153 | PLAN
460160 | PLAN
460167 | PLAN
460174 | PLAN
460181 | PLAN
460188 | PLAN
460195 | PLAN
460202 | PLAN
460209 | PLAN
460216 | PLAN
460223 | PLAN
460230 | PLAN
460237 | PLAN
460244 | PLAN
460251 | PLAN
460258 | PLAN
460265 | PLAN
460272 | PLAN
460279 | PLAN
460286 | PLAN
460293 | PLAN
460300 | PLAN
460307 | PLAN
460314 | PLAN
460321 | PLAN
460328 | PLAN
460335 | PLAN
460342 | PLAN
460349 | PLAN
460356 | PLAN
460363 | PLAN
460370 | PLAN
460377 | PLAN
460384 | PLAN
460391 | PLAN
460398 | PLAN
460405 | PLAN
460412 | PLAN
460419 | PLAN
460426 | PLAN
460433 | PLAN
460440 | PLAN
460447 | PLAN
460454 | PLAN
460461 | PLAN
460468 | PLAN
460475 | PLAN
460482 | PLAN
460489 | PLAN
460496 | PLAN
460503 | PLAN
460510 | PLAN
460517 | PLAN
460524 | PLAN
460531 | PLAN
460538 | PLAN
460545 | PLAN
460552 | PLAN
460559 | PLAN
460566 | PLAN
460573 | PLAN
460580 | PLAN
460587 | PLAN
460594 | PLAN
460601 | PLAN
460608 | PLAN
460615 | PLAN
460622 | PLAN
460629 | PLAN
460636 | PLAN
460643 | PLAN
460650 | PLAN
460657 | PLAN
460664 | PLAN
460671 | PLAN
460678 | PLAN
460685 | PLAN
460692 | PLAN
460699 | PLAN
460706 | PLAN
460713 | PLAN
460720 | PLAN
460727 | PLAN
460734 | PLAN
460741 | PLAN
460748 | PLAN
460755 | PLAN
460762 | PLAN
460769 | PLAN
460776 | PLAN
460783 | PLAN
460790 | PLAN
460797 | PLAN
460804 | PLAN
460811 | PLAN
460818 | PLAN
460825 | PLAN
460832 | PLAN
460839 | PLAN
460846 | PLAN
460853 | PLAN
460860 | PLAN
460867 | PLAN
460874 | PLAN
460881 | PLAN
460888 | PLAN
460895 | PLAN
460902 | PLAN
460909 | PLAN
460916 | PLAN
460923 | PLAN
460930 | PLAN
460937 | PLAN
460944 | PLAN
460951 | PLAN
460958 | PLAN
460965 | PLAN
460972 | PLAN
460979 | PLAN
460986 | PLAN
460993 | PLAN
461000 | PLAN
461007 | PLAN
461014 | PLAN
461021 | PLAN
461028 | PLAN
461035 | PLAN
461042 | PLAN
461049 | PLAN
461056 | PLAN
461063 | PLAN
461070 | PLAN
461077 | PLAN
461084 | PLAN
461091 | PLAN
461098 | PLAN
461105 | PLAN
461112 | PLAN
461119 | PLAN
461126 | PLAN
461133 | PLAN
461140 | PLAN
461147 | PLAN
461154 | PLAN
461161 | PLAN
461168 | PLAN
461175 | PLAN
461182 | PLAN
461189 | PLAN
461196 | PLAN
461203 | PLAN
461210 | PLAN
461217 | PLAN
461224 | PLAN
461231 | PLAN
461238 | PLAN
461245 | PLAN
461252 | PLAN
461259 | PLAN
461266 | PLAN
461273 | PLAN
461280 | PLAN
461287 | PLAN
461294 | PLAN
461301 | PLAN
461308 | PLAN
461315 | PLAN
461322 | PLAN
461329 | PLAN
461336 | PLAN
461343 | PLAN
461350 | PLAN
461357 | PLAN
461364 | PLAN
461371 | PLAN
461378 | PLAN
461385 | PLAN
461392 | PLAN
461399 | PLAN
461406 | PLAN
461413 | PLAN
461420 | PLAN
461427 | PLAN
461434 | PLAN
461441 | PLAN
461448 | PLAN
461455 | PLAN
461462 | PLAN
461469 | PLAN
461476 | PLAN
461483 | PLAN
461490 | PLAN
461497 | PLAN
461504 | PLAN
461511 | PLAN
461518 | PLAN
461525 | PLAN
461532 | PLAN
461539 | PLAN
461546 | PLAN
461553 | PLAN
461560 | PLAN
461567 | PLAN
461574 | PLAN
461581 | PLAN
461588 | PLAN
461595 | PLAN
461602 | PLAN
461609 | PLAN
461616 | PLAN
461623 | PLAN
461630 | PLAN
461637 | PLAN
461644 | PLAN
461651 | PLAN
461658 | PLAN
461665 | PLAN
461672 | PLAN
461679 | PLAN
461686 | PLAN
461693 | PLAN
461700 | PLAN
461707 | PLAN
461714 | PLAN
461721 | PLAN
461728 | PLAN
461735 | PLAN
461742 | PLAN
461749 | PLAN
461756 | PLAN
461763 | PLAN
461770 | PLAN
461777 | PLAN
461784 | PLAN
461791 | PLAN
461798 | PLAN
461805 | PLAN
461812 | PLAN
461819 | PLAN
461826 | PLAN
461833 | PLAN
461840 | PLAN
461847 | PLAN
461854 | PLAN
461861 | PLAN
461868 | PLAN
461875 | PLAN
461882 | PLAN
461889 | PLAN
461896 | PLAN
461903 | PLAN
461910 | PLAN
461917 | PLAN
461924 | PLAN
461931 | PLAN
461938 | PLAN
461945 | PLAN
461952 | PLAN
461959 | PLAN
461966 | PLAN
461973 | PLAN
461980 | PLAN
461987 | PLAN
461994 | PLAN
462001 | PLAN
462008 | PLAN
462015 | PLAN
462022 | PLAN
462029 | PLAN
462036 | PLAN
462043 | PLAN
462050 | PLAN
462057 | PLAN
462064 | PLAN
462071 | PLAN
462078 | PLAN
462085 | PLAN
462092 | PLAN
462099 | PLAN
462106 | PLAN
462113 | PLAN
462120 | PLAN
462127 | PLAN
462134 | PLAN
462141 | PLAN
462148 | PLAN
462155 | PLAN
462162 | PLAN
462169 | PLAN
462176 | PLAN
462183 | PLAN
462190 | PLAN
462197 | PLAN
462204 | PLAN
462211 | PLAN
462218 | PLAN
462225 | PLAN
462232 | PLAN
462239 | PLAN
462246 | PLAN
462253 | PLAN
462260 | PLAN
462267 | PLAN
462274 | PLAN
462281 | PLAN
462288 | PLAN
462295 | PLAN
462302 | PLAN
462309 | PLAN
462316 | PLAN
462323 | PLAN
462330 | PLAN
462337 | PLAN
462344 | PLAN
462351 | PLAN
462358 | PLAN
462365 | PLAN
462372 | PLAN
462379 | PLAN
462386 | PLAN
462393 | PLAN
462400 | PLAN
462407 | PLAN
462414 | PLAN
462421 | PLAN
462428 | PLAN
462435 | PLAN
462442 | PLAN
462449 | PLAN
462456 | PLAN
462463 | PLAN
462470 | PLAN
462477 | PLAN
462484 | PLAN
462491 | PLAN
462498 | PLAN
462505 | PLAN
462512 | PLAN
462519 | PLAN
462526 | PLAN
462533 | PLAN
462540 | PLAN
462547 | PLAN
462554 | PLAN
462561 | PLAN
462568 | PLAN
462575 | PLAN
462582 | PLAN
462589 | PLAN
462596 | PLAN
462603 | PLAN
462610 | PLAN
462617 | PLAN
462624 | PLAN
462631 | PLAN
462638 | PLAN
462645 | PLAN
462652 | PLAN
462659 | PLAN
462666 | PLAN
462673 | PLAN
462680 | PLAN
462687 | PLAN
462694 | PLAN
462701 | PLAN
462708 | PLAN
462715 | PLAN
462722 | PLAN
462729 | PLAN
462736 | PLAN
462743 | PLAN
462750 | PLAN
462757 | PLAN
462764 | PLAN
462771 | PLAN
462778 | PLAN
462785 | PLAN
462792 | PLAN
462799 | PLAN
462806 | PLAN
462813 | PLAN
462820 | PLAN
462827 | PLAN
462834 | PLAN
462841 | PLAN
462848 | PLAN
462855 | PLAN
462862 | PLAN
462869 | PLAN
462876 | PLAN
462883 | PLAN
462890 | PLAN
462897 | PLAN
462904 | PLAN
462911 | PLAN
462918 | PLAN
462925 | PLAN
462932 | PLAN
462939 | PLAN
462946 | PLAN
462953 | PLAN
462960 | PLAN
462967 | PLAN
462974 | PLAN
462981 | PLAN
462988 | PLAN
462995 | PLAN
463002 | PLAN
463009 | PLAN
463016 | PLAN
463023 | PLAN
463030 | PLAN
463037 | PLAN
463044 | PLAN
463051 | PLAN
463058 | PLAN
463065 | PLAN
463072 | PLAN
463079 | PLAN
463086 | PLAN
463093 | PLAN
463100 | PLAN
463107 | PLAN
463114 | PLAN
463121 | PLAN
463128 | PLAN
463135 | PLAN
463142 | PLAN
463149 | PLAN
463156 | PLAN
463163 | PLAN
463170 | PLAN
463177 | PLAN
463184 | PLAN
463191 | PLAN
463198 | PLAN
463205 | PLAN
463212 | PLAN
463219 | PLAN
463226 | PLAN
463233 | PLAN
463240 | PLAN
463247 | PLAN
463254 | PLAN
463261 | PLAN
463268 | PLAN
463275 | PLAN
463282 | PLAN
463289 | PLAN
463296 | PLAN
463303 | PLAN
463310 | PLAN
463317 | PLAN
463324 | PLAN
463331 | PLAN
463338 | PLAN
463345 | PLAN
463352 | PLAN
463359 | PLAN
463366 | PLAN
463373 | PLAN
463380 | PLAN
463387 | PLAN
463394 | PLAN
463401 | PLAN
463408 | PLAN
463415 | PLAN
463422 | PLAN
463429 | PLAN
463436 | PLAN
463443 | PLAN
463450 | PLAN
463457 | PLAN
463464 | PLAN
463471 | PLAN
463478 | PLAN
463485 | PLAN
463492 | PLAN
463499 | PLAN
463506 | PLAN
463513 | PLAN
463520 | PLAN
463527 | PLAN
463534 | PLAN
463541 | PLAN
463548 | PLAN
463555 | PLAN
463562 | PLAN
463569 | PLAN
463576 | PLAN
463583 | PLAN
463590 | PLAN
463597 | PLAN
463604 | PLAN
463611 | PLAN
463618 | PLAN
463625 | PLAN
463632 | PLAN
463639 | PLAN
463646 | PLAN
463653 | PLAN
463660 | PLAN
463667 | PLAN
463674 | PLAN
463681 | PLAN
463688 | PLAN
463695 | PLAN
463702 | PLAN
463709 | PLAN
463716 | PLAN
463723 | PLAN
463730 | PLAN
463737 | PLAN
463744 | PLAN
463751 | PLAN
463758 | PLAN
463765 | PLAN
463772 | PLAN
463779 | PLAN
463786 | PLAN
463793 | PLAN
463800 | PLAN
463807 | PLAN
463814 | PLAN
463821 | PLAN
463828 | PLAN
463835 | PLAN
463842 | PLAN
463849 | PLAN
463856 | PLAN
463863 | PLAN
463870 | PLAN
463877 | PLAN
463884 | PLAN
463891 | PLAN
463898 | PLAN
463905 | PLAN
463912 | PLAN
463919 | PLAN
463926 | PLAN
463933 | PLAN
463940 | PLAN
463947 | PLAN
463954 | PLAN
463961 | PLAN
463968 | PLAN
463975 | PLAN
463982 | PLAN
463989 | PLAN
463996 | PLAN
464003 | PLAN
464010 | PLAN
464017 | PLAN
464024 | PLAN
464031 | PLAN
464038 | PLAN
464045 | PLAN
464052 | PLAN
464059 | PLAN
464066 | PLAN
464073 | PLAN
464080 | PLAN
464087 | PLAN
464094 | PLAN
464101 | PLAN
464108 | PLAN
464115 | PLAN
464122 | PLAN
464129 | PLAN
464136 | PLAN
464143 | PLAN
464150 | PLAN
464157 | PLAN
464164 | PLAN
464171 | PLAN
464178 | PLAN
464185 | PLAN
464192 | PLAN
464199 | PLAN
464206 | PLAN
464213 | PLAN
464220 | PLAN
464227 | PLAN
464234 | PLAN
464241 | PLAN
464248 | PLAN
464255 | PLAN
464262 | PLAN
464269 | PLAN
464276 | PLAN
464283 | PLAN
464290 | PLAN
464297 | PLAN
464304 | PLAN
464311 | PLAN
464318 | PLAN
464325 | PLAN
464332 | PLAN
464339 | PLAN
464346 | PLAN
464353 | PLAN
464360 | PLAN
464367 | PLAN
464374 | PLAN
464381 | PLAN
464388 | PLAN
464395 | PLAN
464402 | PLAN
464409 | PLAN
464416 | PLAN
464423 | PLAN
464430 | PLAN
464437 | PLAN
464444 | PLAN
464451 | PLAN
464458 | PLAN
464465 | PLAN
464472 | PLAN
464479 | PLAN
464486 | PLAN
464493 | PLAN
464500 | PLAN
464507 | PLAN
464514 | PLAN
464521 | PLAN
464528 | PLAN
464535 | PLAN
464542 | PLAN
464549 | PLAN
464556 | PLAN
464563 | PLAN
464570 | PLAN
464577 | PLAN
464584 | PLAN
464591 | PLAN
464598 | PLAN
464605 | PLAN
464612 | PLAN
464619 | PLAN
464626 | PLAN
464633 | PLAN
464640 | PLAN
464647 | PLAN
464654 | PLAN
464661 | PLAN
464668 | PLAN
464675 | PLAN
464682 | PLAN
464689 | PLAN
464696 | PLAN
464703 | PLAN
464710 | PLAN
464717 | PLAN
464724 | PLAN
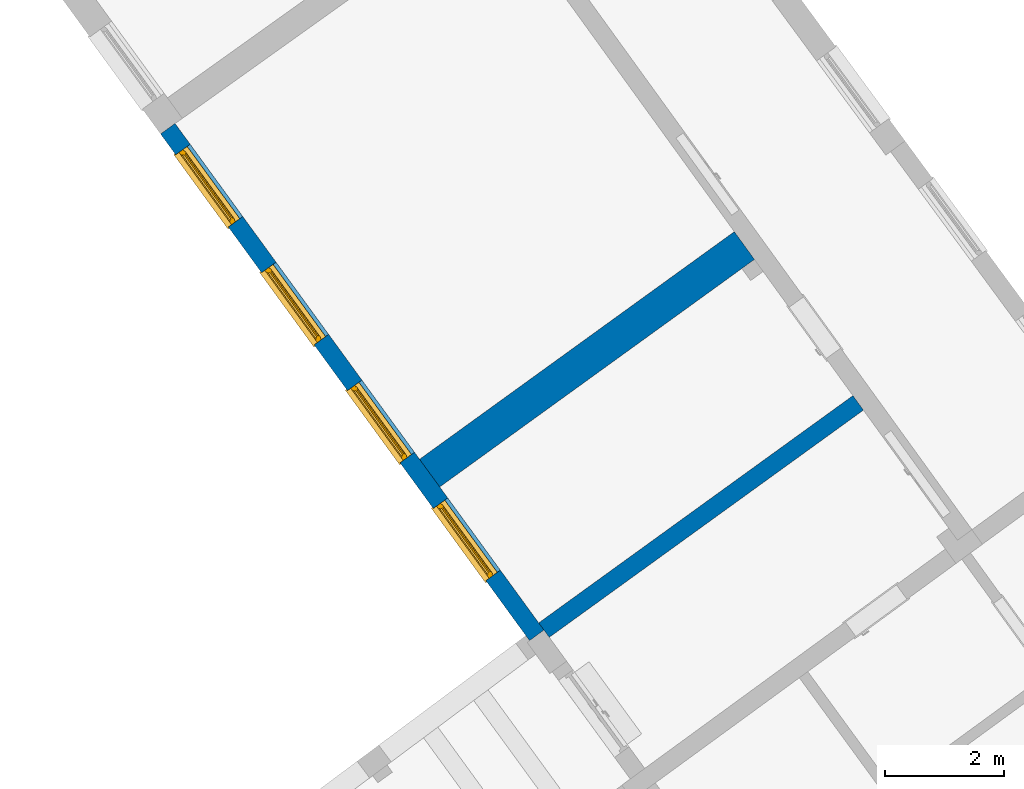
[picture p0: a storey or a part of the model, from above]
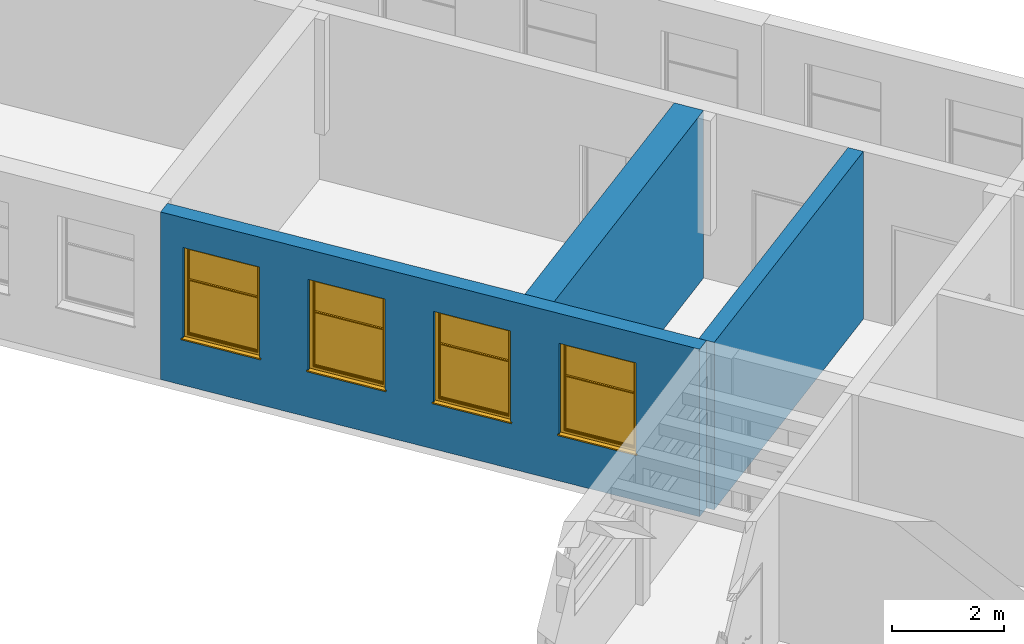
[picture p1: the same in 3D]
Properties of the parts of a building model (IFC2X3), part 11 of 13

# IfcSlab: Floor:Slab-179:1000 (17048)
Name (Floor:Slab-179:1000:...) | In
464731 | PLAN
464738 | PLAN
464745 | PLAN
464752 | PLAN
464759 | PLAN
464766 | PLAN
464773 | PLAN
464780 | PLAN
464787 | PLAN
464794 | PLAN
464801 | PLAN
464808 | PLAN
464815 | PLAN
464822 | PLAN
464829 | PLAN
464836 | PLAN
464843 | PLAN
464850 | PLAN
464857 | PLAN
464864 | PLAN
464871 | PLAN
464878 | PLAN
464885 | PLAN
464892 | PLAN
464899 | PLAN
464906 | PLAN
464913 | PLAN
464920 | PLAN
464927 | PLAN
464934 | PLAN
464941 | PLAN
464948 | PLAN
464955 | PLAN
464962 | PLAN
464969 | PLAN
464976 | PLAN
464983 | PLAN
464990 | PLAN
464997 | PLAN
465004 | PLAN
465011 | PLAN
465018 | PLAN
465025 | PLAN
465032 | PLAN
465039 | PLAN
465046 | PLAN
465053 | PLAN
465060 | PLAN
465067 | PLAN
465074 | PLAN
465081 | PLAN
465088 | PLAN
465095 | PLAN
465102 | PLAN
465109 | PLAN
465116 | PLAN
465123 | PLAN
465130 | PLAN
465137 | PLAN
465144 | PLAN
465151 | PLAN
465158 | PLAN
465165 | PLAN
465172 | PLAN
465179 | PLAN
465186 | PLAN
465193 | PLAN
465200 | PLAN
465207 | PLAN
465214 | PLAN
465221 | PLAN
465228 | PLAN
465235 | PLAN
465242 | PLAN
465249 | PLAN
465256 | PLAN
465263 | PLAN
465270 | PLAN
465277 | PLAN
465284 | PLAN
465291 | PLAN
465298 | PLAN
465305 | PLAN
465312 | PLAN
465319 | PLAN
465326 | PLAN
465333 | PLAN
465340 | PLAN
465347 | PLAN
465354 | PLAN
465361 | PLAN
465368 | PLAN
465375 | PLAN
465382 | PLAN
465389 | PLAN
465396 | PLAN
465403 | PLAN
465410 | PLAN
465417 | PLAN
465424 | PLAN
465431 | PLAN
465438 | PLAN
465445 | PLAN
465452 | PLAN
465459 | PLAN
465466 | PLAN
465473 | PLAN
465480 | PLAN
465487 | PLAN
465494 | PLAN
465501 | PLAN
465508 | PLAN
465515 | PLAN
465522 | PLAN
465529 | PLAN
465536 | PLAN
465543 | PLAN
465550 | PLAN
465557 | PLAN
465564 | PLAN
465571 | PLAN
465578 | PLAN
465585 | PLAN
465592 | PLAN
465599 | PLAN
465606 | PLAN
465613 | PLAN
465620 | PLAN
465627 | PLAN
465634 | PLAN
465641 | PLAN
465648 | PLAN
465655 | PLAN
465662 | PLAN
465669 | PLAN
465676 | PLAN
465683 | PLAN
465690 | PLAN
465697 | PLAN
465704 | PLAN
465711 | PLAN
465718 | PLAN
465725 | PLAN
465732 | PLAN
465739 | PLAN
465746 | PLAN
465753 | PLAN
465760 | PLAN
465767 | PLAN
465774 | PLAN
465781 | PLAN
465788 | PLAN
465795 | PLAN
465802 | PLAN
465809 | PLAN
465816 | PLAN
465823 | PLAN
465830 | PLAN
465837 | PLAN
465844 | PLAN
465851 | PLAN
465858 | PLAN
465865 | PLAN
465872 | PLAN
465879 | PLAN
465886 | PLAN
465893 | PLAN
465900 | PLAN
465907 | PLAN
465914 | PLAN
465921 | PLAN
465928 | PLAN
465935 | PLAN
465942 | PLAN
465949 | PLAN
465956 | PLAN
465963 | PLAN
465970 | PLAN
465977 | PLAN
465984 | PLAN
465991 | PLAN
465998 | PLAN
466005 | PLAN
466012 | PLAN
466019 | PLAN
466026 | PLAN
466033 | PLAN
466040 | PLAN
466047 | PLAN
466054 | PLAN
466061 | PLAN
466068 | PLAN
466075 | PLAN
466082 | PLAN
466089 | PLAN
466096 | PLAN
466103 | PLAN
466110 | PLAN
466117 | PLAN
466124 | PLAN
466131 | PLAN
466138 | PLAN
466145 | PLAN
466152 | PLAN
466159 | PLAN
466166 | PLAN
466173 | PLAN
466180 | PLAN
466187 | PLAN
466194 | PLAN
466201 | PLAN
466208 | PLAN
466215 | PLAN
466222 | PLAN
466229 | PLAN
466236 | PLAN
466243 | PLAN
466250 | PLAN
466257 | PLAN
466264 | PLAN
466271 | PLAN
466278 | PLAN
466285 | PLAN
466292 | PLAN
466299 | PLAN
466306 | PLAN
466313 | PLAN
466320 | PLAN
466327 | PLAN
466334 | PLAN
466341 | PLAN
466348 | PLAN
466355 | PLAN
466362 | PLAN
466369 | PLAN
466376 | PLAN
466383 | PLAN
466390 | PLAN
466397 | PLAN
466404 | PLAN
466411 | PLAN
466418 | PLAN
466425 | PLAN
466432 | PLAN
466439 | PLAN
466446 | PLAN
466453 | PLAN
466460 | PLAN
466467 | PLAN
466474 | PLAN
466481 | PLAN
466488 | PLAN
466495 | PLAN
466502 | PLAN
466509 | PLAN
466516 | PLAN
466523 | PLAN
466530 | PLAN
466537 | PLAN
466544 | PLAN
466551 | PLAN
466558 | PLAN
466565 | PLAN
466572 | PLAN
466579 | PLAN
466586 | PLAN
466593 | PLAN
466600 | PLAN
466607 | PLAN
466614 | PLAN
466621 | PLAN
466628 | PLAN
466635 | PLAN
466642 | PLAN
466649 | PLAN
466656 | PLAN
466663 | PLAN
466670 | PLAN
466677 | PLAN
466684 | PLAN
466691 | PLAN
466698 | PLAN
466705 | PLAN
466712 | PLAN
466719 | PLAN
466726 | PLAN
466733 | PLAN
466740 | PLAN
466747 | PLAN
466754 | PLAN
466761 | PLAN
466768 | PLAN
466775 | PLAN
466782 | PLAN
466789 | PLAN
466796 | PLAN
466803 | PLAN
466810 | PLAN
466817 | PLAN
466824 | PLAN
466831 | PLAN
466838 | PLAN
466845 | PLAN
466852 | PLAN
466859 | PLAN
466866 | PLAN
466873 | PLAN
466880 | PLAN
466887 | PLAN
466894 | PLAN
466901 | PLAN
466908 | PLAN
466915 | PLAN
466922 | PLAN
466929 | PLAN
466936 | PLAN
466943 | PLAN
466950 | PLAN
466957 | PLAN
466964 | PLAN
466971 | PLAN
466978 | PLAN
466985 | PLAN
466992 | PLAN
466999 | PLAN
467006 | PLAN
467013 | PLAN
467020 | PLAN
467027 | PLAN
467034 | PLAN
467041 | PLAN
467048 | PLAN
467055 | PLAN
467062 | PLAN
467069 | PLAN
467076 | PLAN
467083 | PLAN
467090 | PLAN
467097 | PLAN
467104 | PLAN
467111 | PLAN
467118 | PLAN
467125 | PLAN
467132 | PLAN
467139 | PLAN
467146 | PLAN
467153 | PLAN
467160 | PLAN
467167 | PLAN
467174 | PLAN
467181 | PLAN
467188 | PLAN
467195 | PLAN
467202 | PLAN
467209 | PLAN
467216 | PLAN
467223 | PLAN
467230 | PLAN
467237 | PLAN
467244 | PLAN
467251 | PLAN
467258 | PLAN
467265 | PLAN
467272 | PLAN
467279 | PLAN
467286 | PLAN
467293 | PLAN
467300 | PLAN
467307 | PLAN
467314 | PLAN
467321 | PLAN
467328 | PLAN
467335 | PLAN
467342 | PLAN
467349 | PLAN
467356 | PLAN
467363 | PLAN
467370 | PLAN
467377 | PLAN
467384 | PLAN
467391 | PLAN
467398 | PLAN
467405 | PLAN
467412 | PLAN
467419 | PLAN
467426 | PLAN
467433 | PLAN
467440 | PLAN
467447 | PLAN
467454 | PLAN
467461 | PLAN
467468 | PLAN
467475 | PLAN
467482 | PLAN
467489 | PLAN
467496 | PLAN
467503 | PLAN
467510 | PLAN
467517 | PLAN
467524 | PLAN
467531 | PLAN
467538 | PLAN
467545 | PLAN
467552 | PLAN
467559 | PLAN
467566 | PLAN
467573 | PLAN
467580 | PLAN
467587 | PLAN
467594 | PLAN
467601 | PLAN
467608 | PLAN
467615 | PLAN
467622 | PLAN
467629 | PLAN
467636 | PLAN
467643 | PLAN
467650 | PLAN
467657 | PLAN
467664 | PLAN
467671 | PLAN
467678 | PLAN
467685 | PLAN
467692 | PLAN
467699 | PLAN
467706 | PLAN
467713 | PLAN
467720 | PLAN
467727 | PLAN
467734 | PLAN
467741 | PLAN
467748 | PLAN
467755 | PLAN
467762 | PLAN
467769 | PLAN
467776 | PLAN
467783 | PLAN
467790 | PLAN
467797 | PLAN
467804 | PLAN
467811 | PLAN
467818 | PLAN
467825 | PLAN
467832 | PLAN
467839 | PLAN
467846 | PLAN
467853 | PLAN
467860 | PLAN
467867 | PLAN
467874 | PLAN
467881 | PLAN
467888 | PLAN
467895 | PLAN
467902 | PLAN
467909 | PLAN
467916 | PLAN
467923 | PLAN
467930 | PLAN
467937 | PLAN
467944 | PLAN
467951 | PLAN
467958 | PLAN
467965 | PLAN
467972 | PLAN
467979 | PLAN
467986 | PLAN
467993 | PLAN
468000 | PLAN
468007 | PLAN
468014 | PLAN
468021 | PLAN
468028 | PLAN
468035 | PLAN
468042 | PLAN
468049 | PLAN
468056 | PLAN
468063 | PLAN
468070 | PLAN
468077 | PLAN
468084 | PLAN
468091 | PLAN
468098 | PLAN
468105 | PLAN
468112 | PLAN
468119 | PLAN
468126 | PLAN
468133 | PLAN
468140 | PLAN
468147 | PLAN
468154 | PLAN
468161 | PLAN
468168 | PLAN
468175 | PLAN
468182 | PLAN
468189 | PLAN
468196 | PLAN
468203 | PLAN
468210 | PLAN
468217 | PLAN
468224 | PLAN
468231 | PLAN
468238 | PLAN
468245 | PLAN
468252 | PLAN
468259 | PLAN
468266 | PLAN
468273 | PLAN
468280 | PLAN
468287 | PLAN
468294 | PLAN
468301 | PLAN
468308 | PLAN
468315 | PLAN
468322 | PLAN
468329 | PLAN
468336 | PLAN
468343 | PLAN
468350 | PLAN
468357 | PLAN
468364 | PLAN
468371 | PLAN
468378 | PLAN
468385 | PLAN
468392 | PLAN
468399 | PLAN
468406 | PLAN
468413 | PLAN
468420 | PLAN
468427 | PLAN
468434 | PLAN
468441 | PLAN
468448 | PLAN
468455 | PLAN
468462 | PLAN
468469 | PLAN
468476 | PLAN
468483 | PLAN
468490 | PLAN
468497 | PLAN
468504 | PLAN
468511 | PLAN
468518 | PLAN
468525 | PLAN
468532 | PLAN
468539 | PLAN
468546 | PLAN
468553 | PLAN
468560 | PLAN
468567 | PLAN
468574 | PLAN
468581 | PLAN
468588 | PLAN
468595 | PLAN
468602 | PLAN
468609 | PLAN
468616 | PLAN
468623 | PLAN
468630 | PLAN
468637 | PLAN
468644 | PLAN
468651 | PLAN
468658 | PLAN
468665 | PLAN
468672 | PLAN
468679 | PLAN
468686 | PLAN
468693 | PLAN
468700 | PLAN
468707 | PLAN
468714 | PLAN
468721 | PLAN
468728 | PLAN
468735 | PLAN
468742 | PLAN
468749 | PLAN
468756 | PLAN
468763 | PLAN
468770 | PLAN
468777 | PLAN
468784 | PLAN
468791 | PLAN
468798 | PLAN
468805 | PLAN
468812 | PLAN
468819 | PLAN
468826 | PLAN
468833 | PLAN
468840 | PLAN
468847 | PLAN
468854 | PLAN
468861 | PLAN
468868 | PLAN
468875 | PLAN
468882 | PLAN
468889 | PLAN
468896 | PLAN
468903 | PLAN
468910 | PLAN
468917 | PLAN
468924 | PLAN
468931 | PLAN
468938 | PLAN
468945 | PLAN
468952 | PLAN
468959 | PLAN
468966 | PLAN
468973 | PLAN
468980 | PLAN
468987 | PLAN
468994 | PLAN
469001 | PLAN
469008 | PLAN
469015 | PLAN
469022 | PLAN
469029 | PLAN
469036 | PLAN
469043 | PLAN
469050 | PLAN
469057 | PLAN
469064 | PLAN
469071 | PLAN
469078 | PLAN
469085 | PLAN
469092 | PLAN
469099 | PLAN
469106 | PLAN
469113 | PLAN
469120 | PLAN
469127 | PLAN
469134 | PLAN
469141 | PLAN
469148 | PLAN
469155 | PLAN
469162 | PLAN
469169 | PLAN
469176 | PLAN
469183 | PLAN
469190 | PLAN
469197 | PLAN
469204 | PLAN
469211 | PLAN
469218 | PLAN
469225 | PLAN
469232 | PLAN
469239 | PLAN
469246 | PLAN
469253 | PLAN
469260 | PLAN
469267 | PLAN
469274 | PLAN
469281 | PLAN
469288 | PLAN
469295 | PLAN
469302 | PLAN
469309 | PLAN
469316 | PLAN
469323 | PLAN
469330 | PLAN
469337 | PLAN
469344 | PLAN
469351 | PLAN
469358 | PLAN
469365 | PLAN
469372 | PLAN
469379 | PLAN
469386 | PLAN
469393 | PLAN
469400 | PLAN
469407 | PLAN
469414 | PLAN
469421 | PLAN
469428 | PLAN
469435 | PLAN
469442 | PLAN
469449 | PLAN
469456 | PLAN
469463 | PLAN
469470 | PLAN
469477 | PLAN
469484 | PLAN
469491 | PLAN
469498 | PLAN
469505 | PLAN
469512 | PLAN
469519 | PLAN
469526 | PLAN
469533 | PLAN
469540 | PLAN
469547 | PLAN
469554 | PLAN
469561 | PLAN
469568 | PLAN
469575 | PLAN
469582 | PLAN
469589 | PLAN
469596 | PLAN
469603 | PLAN
469610 | PLAN
469617 | PLAN
469624 | PLAN
469631 | PLAN
469638 | PLAN
469645 | PLAN
469652 | PLAN
469659 | PLAN
469666 | PLAN
469673 | PLAN
469680 | PLAN
469687 | PLAN
469694 | PLAN
469701 | PLAN
469708 | PLAN
469715 | PLAN
469722 | PLAN
469729 | PLAN
469736 | PLAN
469743 | PLAN
469750 | PLAN
469757 | PLAN
469764 | PLAN
469771 | PLAN
469778 | PLAN
469785 | PLAN
469792 | PLAN
469799 | PLAN
469806 | PLAN
469813 | PLAN
469820 | PLAN
469827 | PLAN
469834 | PLAN
469841 | PLAN
469848 | PLAN
469855 | PLAN
469862 | PLAN
469869 | PLAN
469876 | PLAN
469883 | PLAN
469890 | PLAN
469897 | PLAN
469904 | PLAN
469911 | PLAN
469918 | PLAN
469925 | PLAN
469932 | PLAN
469939 | PLAN
469946 | PLAN
469953 | PLAN
469960 | PLAN
469967 | PLAN
469974 | PLAN
469981 | PLAN
469988 | PLAN
469995 | PLAN
470002 | PLAN
470009 | PLAN
470016 | PLAN
470023 | PLAN
470030 | PLAN
470037 | PLAN
470044 | PLAN
470051 | PLAN
470058 | PLAN
470065 | PLAN
470072 | PLAN
470079 | PLAN
470086 | PLAN
470093 | PLAN
470100 | PLAN
470107 | PLAN
470114 | PLAN
470121 | PLAN
470128 | PLAN
470135 | PLAN
470142 | PLAN
470149 | PLAN
470156 | PLAN
470163 | PLAN
470170 | PLAN
470177 | PLAN
470184 | PLAN
470191 | PLAN
470198 | PLAN
470205 | PLAN
470212 | PLAN
470219 | PLAN
470226 | PLAN
470233 | PLAN
470240 | PLAN
470247 | PLAN
470254 | PLAN
470261 | PLAN
470268 | PLAN
470275 | PLAN
470282 | PLAN
470289 | PLAN
470296 | PLAN
470303 | PLAN
470310 | PLAN
470317 | PLAN
470324 | PLAN
470331 | PLAN
470338 | PLAN
470345 | PLAN
470352 | PLAN
470359 | PLAN
470366 | PLAN
470373 | PLAN
470380 | PLAN
470387 | PLAN
470394 | PLAN
470401 | PLAN
470408 | PLAN
470415 | PLAN
470422 | PLAN
470429 | PLAN
470436 | PLAN
470443 | PLAN
470450 | PLAN
470457 | PLAN
470464 | PLAN
470471 | PLAN
470478 | PLAN
470485 | PLAN
470492 | PLAN
470499 | PLAN
470506 | PLAN
470513 | PLAN
470520 | PLAN
470527 | PLAN
470534 | PLAN
470541 | PLAN
470548 | PLAN
470555 | PLAN
470562 | PLAN
470569 | PLAN
470576 | PLAN
470583 | PLAN
470590 | PLAN
470597 | PLAN
470604 | PLAN
470611 | PLAN
470618 | PLAN
470625 | PLAN
470632 | PLAN
470639 | PLAN
470646 | PLAN
470653 | PLAN
470660 | PLAN
470667 | PLAN
470674 | PLAN
470681 | PLAN
470688 | PLAN
470695 | PLAN
470702 | PLAN
470709 | PLAN
470716 | PLAN
470723 | PLAN
470730 | PLAN
470737 | PLAN
470744 | PLAN
470751 | PLAN
470758 | PLAN
470765 | PLAN
470772 | PLAN
470779 | PLAN
470786 | PLAN
470793 | PLAN
470800 | PLAN
470807 | PLAN
470814 | PLAN
470821 | PLAN
470828 | PLAN
470835 | PLAN
470842 | PLAN
470849 | PLAN
470856 | PLAN
470863 | PLAN
470870 | PLAN
470877 | PLAN
470884 | PLAN
470891 | PLAN
470898 | PLAN
470905 | PLAN
470912 | PLAN
470919 | PLAN
470926 | PLAN
470933 | PLAN
470940 | PLAN
470947 | PLAN
470954 | PLAN
470961 | PLAN
470968 | PLAN
470975 | PLAN
470982 | PLAN
470989 | PLAN
470996 | PLAN
471003 | PLAN
471010 | PLAN
471017 | PLAN
471024 | PLAN
471031 | PLAN
471038 | PLAN
471045 | PLAN
471052 | PLAN
471059 | PLAN
471066 | PLAN
471073 | PLAN
471080 | PLAN
471087 | PLAN
471094 | PLAN
471101 | PLAN
471108 | PLAN
471115 | PLAN
471122 | PLAN
471129 | PLAN
471136 | PLAN
471143 | PLAN
471150 | PLAN
471157 | PLAN
471164 | PLAN
471171 | PLAN
471178 | PLAN
471185 | PLAN
471192 | PLAN
471199 | PLAN
471206 | PLAN
471213 | PLAN
471220 | PLAN
471227 | PLAN
471234 | PLAN
471241 | PLAN
471248 | PLAN
471255 | PLAN
471262 | PLAN
471269 | PLAN
471276 | PLAN
471283 | PLAN
471290 | PLAN
471297 | PLAN
471304 | PLAN
471311 | PLAN
471318 | PLAN
471325 | PLAN
471332 | PLAN
471339 | PLAN
471346 | PLAN
471353 | PLAN
471360 | PLAN
471367 | PLAN
471374 | PLAN
471381 | PLAN
471388 | PLAN
471395 | PLAN
471402 | PLAN
471409 | PLAN
471416 | PLAN
471423 | PLAN
471430 | PLAN
471437 | PLAN
471444 | PLAN
471451 | PLAN
471458 | PLAN
471465 | PLAN
471472 | PLAN
471479 | PLAN
471486 | PLAN
471493 | PLAN
471500 | PLAN
471507 | PLAN
471514 | PLAN
471521 | PLAN
471528 | PLAN
471535 | PLAN
471542 | PLAN
471549 | PLAN
471556 | PLAN
471563 | PLAN
471570 | PLAN
471577 | PLAN
471584 | PLAN
471591 | PLAN
471598 | PLAN
471605 | PLAN
471612 | PLAN
471619 | PLAN
471626 | PLAN
471633 | PLAN
471640 | PLAN
471647 | PLAN
471654 | PLAN
471661 | PLAN
471668 | PLAN
471675 | PLAN
471682 | PLAN
471689 | PLAN
471696 | PLAN
471703 | PLAN
471710 | PLAN
471717 | PLAN
471724 | PLAN
471731 | PLAN
471738 | PLAN
471745 | PLAN
471752 | PLAN
471759 | PLAN
471766 | PLAN
471773 | PLAN
471780 | PLAN
471787 | PLAN
471794 | PLAN
471801 | PLAN
471808 | PLAN
471815 | PLAN
471822 | PLAN
471829 | PLAN
471836 | PLAN
471843 | PLAN
471850 | PLAN
471857 | PLAN
471864 | PLAN
471871 | PLAN
471878 | PLAN
471885 | PLAN
471892 | PLAN
471899 | PLAN
471906 | PLAN
471913 | PLAN
471920 | PLAN
471927 | PLAN
471934 | PLAN
471941 | PLAN
471948 | PLAN
471955 | PLAN
471962 | PLAN
471969 | PLAN
471976 | PLAN
471983 | PLAN
471990 | PLAN
471997 | PLAN
472004 | PLAN
472011 | PLAN
472018 | PLAN
472025 | PLAN
472032 | PLAN
472039 | PLAN
472046 | PLAN
472053 | PLAN
472060 | PLAN
472067 | PLAN
472074 | PLAN
472081 | PLAN
472088 | PLAN
472095 | PLAN
472102 | PLAN
472109 | PLAN
472116 | PLAN
472123 | PLAN
472130 | PLAN
472137 | PLAN
472144 | PLAN
472151 | PLAN
472158 | PLAN
472165 | PLAN
472172 | PLAN
472179 | PLAN
472186 | PLAN
472193 | PLAN
472200 | PLAN
472207 | PLAN
472214 | PLAN
472221 | PLAN
472228 | PLAN
472235 | PLAN
472242 | PLAN
472249 | PLAN
472256 | PLAN
472263 | PLAN
472270 | PLAN
472277 | PLAN
472284 | PLAN
472291 | PLAN
472298 | PLAN
472305 | PLAN
472312 | PLAN
472319 | PLAN
472326 | PLAN
472333 | PLAN
472340 | PLAN
472347 | PLAN
472354 | PLAN
472361 | PLAN
472368 | PLAN
472375 | PLAN
472382 | PLAN
472389 | PLAN
472396 | PLAN
472403 | PLAN
472410 | PLAN
472417 | PLAN
472424 | PLAN
472431 | PLAN
472438 | PLAN
472445 | PLAN
472452 | PLAN
472459 | PLAN
472466 | PLAN
472473 | PLAN
472480 | PLAN
472487 | PLAN
472494 | PLAN
472501 | PLAN
472508 | PLAN
472515 | PLAN
472522 | PLAN
472529 | PLAN
472536 | PLAN
472543 | PLAN
472550 | PLAN
472557 | PLAN
472564 | PLAN
472571 | PLAN
472578 | PLAN
472585 | PLAN
472592 | PLAN
472599 | PLAN
472606 | PLAN
472613 | PLAN
472620 | PLAN
472627 | PLAN
472634 | PLAN
472641 | PLAN
472648 | PLAN
472655 | PLAN
472662 | PLAN
472669 | PLAN
472676 | PLAN
472683 | PLAN
472690 | PLAN
472697 | PLAN
472704 | PLAN
472711 | PLAN
472718 | PLAN
472725 | PLAN
472732 | PLAN
472739 | PLAN

# IfcSlab: Floor:Slab-179:1003 (39)
In: 3D
Type - PredefinedType: FLOOR; Material: Paint-01 5000 mm
Type - Pset_ElementShading - Roughness: 304.8 mm
Type - Pset_ProductRequirements - Category: Floors
Type - Pset_SlabCommon - IsExternal: no
Pset_QuantityTakeOff - Reference: Slab-179:1003; sets with these values: 2
Pset_SlabCommon - LoadBearing: no; PitchAngle: 0 deg; Reference: Slab-179:1003
Group: Model Group:River:478153
Name (Floor:Slab-179:1003:...)
347286
347385
347406
347424
347877
348280
348301
348312
348343
348409
348549
348653
348675
348692
348756
348894
349108
349332
349516
349823
349873
349883
349929
349939
349952
349962
350046
350195
350214
350251
350409
350509
350575
350767
350775
350810
350825
350840
352611

# IfcSlab: Floor:Slab-179:1080, Floor:Slab-179:1080:349367
In: 3D
Type - PredefinedType: FLOOR; Material: Paint-01 4450 mm
Type - Pset_ElementShading - Roughness: 304.8 mm
Type - Pset_ProductRequirements - Category: Floors
Type - Pset_SlabCommon - IsExternal: no
Pset_QuantityTakeOff - Reference: Slab-179:1080; sets with these values: 2
Pset_SlabCommon - LoadBearing: no; PitchAngle: 0 deg; Reference: Slab-179:1080
Group: Model Group:River:478153

# IfcSlab: Floor:Slab-179:1081, Floor:Slab-179:1081:349391
In: 3D
Type - PredefinedType: FLOOR; Material: Paint-01 7499.98 mm
Type - Pset_ElementShading - Roughness: 304.8 mm
Type - Pset_ProductRequirements - Category: Floors
Type - Pset_SlabCommon - IsExternal: no
Pset_QuantityTakeOff - Reference: Slab-179:1081; sets with these values: 2
Pset_SlabCommon - LoadBearing: no; PitchAngle: 0 deg; Reference: Slab-179:1081
Group: Model Group:River:478153

# IfcSlab: Floor:Slab-179:1086 (7)
In: 3D
Type - PredefinedType: FLOOR; Material: Paint-01 2450 mm
Type - Pset_ElementShading - Roughness: 304.8 mm
Type - Pset_ProductRequirements - Category: Floors
Type - Pset_SlabCommon - IsExternal: no
Pset_QuantityTakeOff - Reference: Slab-179:1086; sets with these values: 2
Pset_SlabCommon - LoadBearing: no; PitchAngle: 0 deg; Reference: Slab-179:1086
Group: Model Group:River:478153
Name (Floor:Slab-179:1086:...)
349562
349686
349841
349855
349863
349899
352628

# IfcSlab: Floor:Slab-180, Floor:Slab-180:351468
In: 3D
Type - PredefinedType: FLOOR; Material: Paint-01 1750 mm
Type - Pset_ElementShading - Roughness: 304.8 mm
Type - Pset_ProductRequirements - Category: Floors
Type - Pset_SlabCommon - IsExternal: no
Pset_QuantityTakeOff - Reference: Slab-180; sets with these values: 2
Pset_SlabCommon - Reference: Slab-180; LoadBearing: no; PitchAngle: 0 deg
Group: Model Group:River:478153

# IfcSlab: Floor:Slab-180:1008 (24)
In: 3D
Type - PredefinedType: FLOOR; Material: Paint-01 4950 mm
Type - Pset_ElementShading - Roughness: 304.8 mm
Type - Pset_ProductRequirements - Category: Floors
Type - Pset_SlabCommon - IsExternal: no
Pset_QuantityTakeOff - Reference: Slab-180:1008; sets with these values: 2
Pset_SlabCommon - LoadBearing: no; PitchAngle: 0 deg; Reference: Slab-180:1008
Group: Model Group:River:478153
Name (Floor:Slab-180:1008:...)
347349
347821
348565
348600
349126
349226
349256
349264
349282
349289
349296
349323
349458
349465
349544
349551
349570
349610
349660
350207
350527
350536
353087
353096

# IfcSlab: Floor:Slab-180:1079, Floor:Slab-180:1079:349340
In: 3D
Type - PredefinedType: FLOOR; Material: Paint-01 9950 mm
Type - Pset_ElementShading - Roughness: 304.8 mm
Type - Pset_ProductRequirements - Category: Floors
Type - Pset_SlabCommon - IsExternal: no
Pset_QuantityTakeOff - Reference: Slab-180:1079; sets with these values: 2
Pset_SlabCommon - LoadBearing: no; PitchAngle: 0 deg; Reference: Slab-180:1079
Group: Model Group:River:478153

# IfcSlab: Floor:Slab-180:1102 (5)
In: 3D
Type - PredefinedType: FLOOR; Material: Paint-01 1450 mm
Type - Pset_ElementShading - Roughness: 304.8 mm
Type - Pset_ProductRequirements - Category: Floors
Type - Pset_SlabCommon - IsExternal: no
Pset_QuantityTakeOff - Reference: Slab-180:1102; sets with these values: 2
Pset_SlabCommon - LoadBearing: no; PitchAngle: 0 deg; Reference: Slab-180:1102
Group: Model Group:River:478153
Name (Floor:Slab-180:1102:...)
351161
353241
353248
353255
353262

# IfcSlab: Floor:Slab-181 (3)
In: 3D
Type - PredefinedType: FLOOR; Material: Paint-01 3500 mm
Type - Pset_ElementShading - Roughness: 304.8 mm
Type - Pset_ProductRequirements - Category: Floors
Type - Pset_SlabCommon - IsExternal: no
Pset_QuantityTakeOff - Reference: Slab-181; sets with these values: 2
Pset_SlabCommon - LoadBearing: no; PitchAngle: 0 deg; Reference: Slab-181
Group: Model Group:River:478153
Name (Floor:Slab-181:...)
349449
349536
349679

# IfcSlab: Floor:Slab-181:1020 (20)
In: 3D
Type - PredefinedType: FLOOR; Material: Paint-01 10000 mm
Type - Pset_ElementShading - Roughness: 304.8 mm
Type - Pset_ProductRequirements - Category: Floors
Type - Pset_SlabCommon - IsExternal: no
Pset_QuantityTakeOff - Reference: Slab-181:1020; sets with these values: 2
Pset_SlabCommon - LoadBearing: no; PitchAngle: 0 deg; Reference: Slab-181:1020
Group: Model Group:River:478153
Name (Floor:Slab-181:1020:...)
347521
347799
348101
348273
349922
350752
350910
350943
350951
351028
351036
351196
351206
351226
352039
352113
352148
352344
352372
352381

# IfcSlab: Floor:Slab-183 (24)
In: 3D
Type - PredefinedType: FLOOR; Material: Paint-01 4000 mm
Type - Pset_ElementShading - Roughness: 304.8 mm
Type - Pset_ProductRequirements - Category: Floors
Type - Pset_SlabCommon - IsExternal: no
Pset_QuantityTakeOff - Reference: Slab-183; sets with these values: 2
Pset_SlabCommon - LoadBearing: no; PitchAngle: 0 deg; Reference: Slab-183
Group: Model Group:River:478153
Name (Floor:Slab-183:...)
347807
347830
347928
348030
348931
349271
350184
350719
351184
351342
351594
351651
351993
352005
352032
352046
352053
352061
352070
352077
352084
352091
352106
352124

# IfcSlab: Monolithic Landing:200mm_Thickness (16)
Type - PredefinedType: LANDING
Type - Pset_ProductRequirements - Category: Stairs: Landings
Type - Pset_SlabCommon - IsExternal: no
Material: Concrete, Cast-in-Place gray; Group: Model Group:Building:629362
Pset_QuantityTakeOff - Reference: 200mm_Thickness; sets with these values: 2
Pset_SlabCommon - PitchAngle: 0 deg; Reference: 200mm_Thickness
Name (Precast Stair:Stair:...) | In
619337 Landing 1 | 2.1OG +5.30
619337 Landing 2 | 2.1OG +5.30
619710 Landing 1 | 1.EG +0.00
619710 Landing 2 | 1.EG +0.00
620033 Landing 1 | 3.2OG +10.60
620033 Landing 2 | 3.2OG +10.60
620946 Landing 1 | 4.3OG +15.90
620946 Landing 2 | 4.3OG +15.90
623208 Landing 1 | 0.UG -3.60
623208 Landing 2 | 0.UG -3.60
623219 Landing 1 | 0.UG -3.60
623226 Landing 1 | 0.UG -3.60
623352 Landing 1 | 6.EG KH -1.15
623399 Landing 1 | 7.1OG KH +2.65
623442 Landing 1 | 8.2OG KH +6.45
623964 Landing 1 | 0.UG -3.60

# IfcSlab: RT - 020 (7)
In: 3D
Type - PredefinedType: ROOF
Type - Pset_ElementShading - Roughness: 304.8 mm
Type - Pset_ProductRequirements - Category: Roofs
Type - Pset_SlabCommon - IsExternal: yes
Material: Paint-01 97.0143 mm; Group: Model Group:River:478153
Pset_QuantityTakeOff - Reference: RT - 020; sets with these values: 2
Pset_SlabCommon - Reference: RT - 020; PitchAngle: 14.0362 deg
Name (Basic Roof:RT - 020:...)
351243
351251
351259
351266
351290
351298
351338

# IfcSlab: Slab-162, Slab-162 236610:Slab-162 236610:298321
In: 1.EG +0.00
Type - PredefinedType: FLOOR; Material: buildings
Type - Pset_ProductRequirements - Category: Floors
Type - Pset_SlabCommon - IsExternal: no
Pset_QuantityTakeOff - Reference: Slab-162 236610; sets with these values: 2
Pset_SlabCommon - Reference: Slab-162 236610
Group: Model Group:River:478153

# IfcSlab: Slab-169, Slab-169 211319:Slab-169 211319:297657
In: 0.UG -3.60
Type - PredefinedType: FLOOR; Material: Paveta
Type - Pset_ProductRequirements - Category: Floors
Type - Pset_SlabCommon - IsExternal: no
Pset_QuantityTakeOff - Reference: Slab-169 211319; sets with these values: 2
Pset_SlabCommon - Reference: Slab-169 211319
Group: Model Group:River:478153

# IfcSlab: Slab-169, Slab-169 211361:Slab-169 211361:297765
In: 0.UG -3.60
Type - PredefinedType: FLOOR; Material: _granite_01 nastilka svetla
Type - Pset_ProductRequirements - Category: Floors
Type - Pset_SlabCommon - IsExternal: no
Pset_QuantityTakeOff - Reference: Slab-169 211361; sets with these values: 2
Pset_SlabCommon - Reference: Slab-169 211361
Group: Model Group:River:478153

# IfcSlab: Slab-169 (2)
In: 0.UG -3.60
Type - PredefinedType: FLOOR; Material: road_asfalt
Type - Pset_ProductRequirements - Category: Floors
Type - Pset_SlabCommon - IsExternal: no
Pset_QuantityTakeOff - sets with these values: 2
Group: Model Group:River:478153
Name | Pset_QuantityTakeOff, Reference = Pset_SlabCommon, Reference
Slab-169:Slab-169:297548 | Slab-169
Slab-169 260969:Slab-169 260969:298848 | Slab-169 260969

# IfcSlab: Slab-172, Slab-172:Slab-172:297577
In: 0.UG -3.60
Type - PredefinedType: FLOOR; Material: Paveta
Type - Pset_ProductRequirements - Category: Floors
Type - Pset_SlabCommon - IsExternal: no
Pset_QuantityTakeOff - Reference: Slab-172; sets with these values: 2
Pset_SlabCommon - Reference: Slab-172
Group: Model Group:River:478153

# IfcSlab: Slab-176, Slab-176 219040:Slab-176 219040:297904
In: 0.UG -3.60
Type - PredefinedType: FLOOR; Material: Paveta
Type - Pset_ProductRequirements - Category: Floors
Type - Pset_SlabCommon - IsExternal: no
Pset_QuantityTakeOff - Reference: Slab-176 219040; sets with these values: 2
Pset_SlabCommon - Reference: Slab-176 219040
Group: Model Group:River:478153

# IfcSlab: Slab-180 (3)
In: 0.UG -3.60
Type - PredefinedType: FLOOR; Material: _granite_06 elementi novi
Type - Pset_ProductRequirements - Category: Floors
Type - Pset_SlabCommon - IsExternal: no
Pset_QuantityTakeOff - sets with these values: 2
Group: Model Group:River:478153
Name | Pset_QuantityTakeOff, Reference = Pset_SlabCommon, Reference
Slab-180:Slab-180:297954 | Slab-180
Slab-180 237997:Slab-180 237997:298594 | Slab-180 237997
Slab-180 256650:Slab-180 256650:298819 | Slab-180 256650

# IfcStair: Assembled Stair:Commercial-Ext_Steel_Fire_Escape (2)
In: 1.EG +0.00
ShapeType: STRAIGHT_RUN_STAIR; Group: Model Group:Building:629362
Pset_ProductRequirements - Category: Stairs
Pset_QuantityTakeOff - Reference: Commercial-Ext_Steel_Fire_Escape
Pset_StairCommon - IsExternal: no; Reference: Commercial-Ext_Steel_Fire_Escape; NumberOfRiser: 3; NumberOfTreads: 3; RiserHeight: 283.333 mm; TreadLength: 320 mm
Name (Assembled Stair:Stair:...)
629207
629355

# IfcStair: Precast Stair:Stair_CJC (13)
Pset_ProductRequirements - Category: Stairs
Pset_QuantityTakeOff - Reference: Stair_CJC
Pset_StairCommon - IsExternal: no; Reference: Stair_CJC; TreadLength: 320 mm
Group: Model Group:Building:629362
Name (Precast Stair:Stair:...) | In | ShapeType | NumberOfRiser | NumberOfTreads | RiserHeight (mm)
618218 | 1.EG +0.00 | STRAIGHT_RUN_STAIR | 9 | 8 | 155.556
618221 | 1.EG +0.00 | STRAIGHT_RUN_STAIR | 9 | 8 | 155.556
619156 | 2.1OG +5.30 | STRAIGHT_RUN_STAIR | 9 | 8 | 155.556
619159 | 2.1OG +5.30 | STRAIGHT_RUN_STAIR | 9 | 8 | 155.556
619337 | 2.1OG +5.30 |  | 33 | 33 | 160.606
619710 | 1.EG +0.00 |  | 33 | 33 | 160.606
619853 | 3.2OG +10.60 | STRAIGHT_RUN_STAIR | 9 | 8 | 155.556
619856 | 3.2OG +10.60 | STRAIGHT_RUN_STAIR | 9 | 8 | 155.556
620033 | 3.2OG +10.60 |  | 33 | 33 | 160.606
620777 | 4.3OG +15.90 | STRAIGHT_RUN_STAIR | 9 | 8 | 155.556
620780 | 4.3OG +15.90 | STRAIGHT_RUN_STAIR | 9 | 8 | 155.556
620946 | 4.3OG +15.90 |  | 21 | 20 | 167.273
624066 | 1.EG +0.00 | STRAIGHT_RUN_STAIR | 6 | 5 | 141.667

# IfcStair: Precast Stair:Stair_CJC_KH (9)
Pset_ProductRequirements - Category: Stairs
Pset_QuantityTakeOff - Reference: Stair_CJC_KH
Pset_StairCommon - IsExternal: no; Reference: Stair_CJC_KH
Group: Model Group:Building:629362
Name (Precast Stair:Stair:...) | In | ShapeType | NumberOfRiser | NumberOfTreads | RiserHeight (mm) | TreadLength (mm)
621927 | 1.EG +0.00 | STRAIGHT_RUN_STAIR | 6 | 5 | 125 | 320
621974 | 1.EG +0.00 | STRAIGHT_RUN_STAIR | 3 | 2 | 133.333 | 320
623208 | 0.UG -3.60 |  | 23 | 20 | 156.522 | 320
623219 | 0.UG -3.60 |  | 24 | 22 | 150 | 320
623226 | 0.UG -3.60 |  | 21 | 20 | 157.143 | 320
623352 | 6.EG KH -1.15 | HALF_TURN_STAIR | 24 | 22 | 158.333 | 320
623399 | 7.1OG KH +2.65 | HALF_TURN_STAIR | 24 | 22 | 158.333 | 320
623442 | 8.2OG KH +6.45 | HALF_TURN_STAIR | 24 | 22 | 158.333 | 320
623964 | 0.UG -3.60 |  | 16 | 16 | 153.125 | 300

# IfcStairFlight: Monolithic Run:1mm_Tread-175mm_Depth (34)
Type - PredefinedType: STRAIGHT
Type - Pset_ProductRequirements - Category: Stairs: Runs
Type - Pset_StairFlightCommon - NosingLength: 0 mm
Material: Concrete, Cast-in-Place gray, Analytical Wall Surface_CJC; Group: Model Group:Building:629362
Pset_QuantityTakeOff - Reference: 1mm_Tread-175mm_Depth
Pset_StairFlightCommon - Reference: 1mm_Tread-175mm_Depth
Name (Precast Stair:Stair:...) | In | NumberOfRiser = Pset_StairFlightCommon, NumberOfRiser | NumberOfTreads = Pset_StairFlightCommon, NumberOfTreads | RiserHeight (mm) | TreadLength (mm) | Pset_StairFlightCommon, RiserHeight (mm) | Pset_StairFlightCommon, TreadLength (mm) = TreadLengthAtOffset (mm) = TreadLengthAtInnerSide (mm) | WalkingLineOffset (mm)
618218 Run 1 | 1.EG +0.00 | 9 | 8 | 0.510353 | 1.04987 | 155.556 | 320 | 2.46063
618221 Run 1 | 1.EG +0.00 | 9 | 8 | 0.510353 | 1.04987 | 155.556 | 320 | 2.46063
619156 Run 1 | 2.1OG +5.30 | 9 | 8 | 0.510353 | 1.04987 | 155.556 | 320 | 2.46063
619159 Run 1 | 2.1OG +5.30 | 9 | 8 | 0.510353 | 1.04987 | 155.556 | 320 | 2.46063
619337 Run 1 | 2.1OG +5.30 | 13 | 13 | 0.526923 | 1.04987 | 160.606 | 320 | 2.62467
619337 Run 2 | 2.1OG +5.30 | 7 | 7 | 0.526923 | 1.04987 | 160.606 | 320 | 2.62467
619337 Run 3 | 2.1OG +5.30 | 13 | 13 | 0.526923 | 1.04987 | 160.606 | 320 | 2.62467
619710 Run 1 | 1.EG +0.00 | 13 | 13 | 0.526923 | 1.04987 | 160.606 | 320 | 2.62467
619710 Run 2 | 1.EG +0.00 | 7 | 7 | 0.526923 | 1.04987 | 160.606 | 320 | 2.62467
619710 Run 3 | 1.EG +0.00 | 13 | 13 | 0.526923 | 1.04987 | 160.606 | 320 | 2.62467
619853 Run 1 | 3.2OG +10.60 | 9 | 8 | 0.510353 | 1.04987 | 155.556 | 320 | 2.46063
619856 Run 1 | 3.2OG +10.60 | 9 | 8 | 0.510353 | 1.04987 | 155.556 | 320 | 2.46063
620033 Run 1 | 3.2OG +10.60 | 13 | 13 | 0.526923 | 1.04987 | 160.606 | 320 | 2.62467
620033 Run 2 | 3.2OG +10.60 | 7 | 7 | 0.526923 | 1.04987 | 160.606 | 320 | 2.62467
620033 Run 3 | 3.2OG +10.60 | 13 | 13 | 0.526923 | 1.04987 | 160.606 | 320 | 2.62467
620777 Run 1 | 4.3OG +15.90 | 9 | 8 | 0.510353 | 1.04987 | 155.556 | 320 | 2.46063
620780 Run 1 | 4.3OG +15.90 | 9 | 8 | 0.510353 | 1.04987 | 155.556 | 320 | 2.46063
620946 Run 1 | 4.3OG +15.90 | 13 | 13 | 0.548795 | 1.04987 | 167.273 | 320 | 2.62467
620946 Run 2 | 4.3OG +15.90 | 7 | 7 | 0.548795 | 1.04987 | 167.273 | 320 | 2.62467
623208 Run 1 | 0.UG -3.60 | 7 | 6 | 0.513523 | 1.04987 | 156.522 | 320 | 2.29659
623208 Run 2 | 0.UG -3.60 | 8 | 7 | 0.513523 | 1.04987 | 156.522 | 320 | 2.29659
623208 Run 3 | 0.UG -3.60 | 8 | 7 | 0.513523 | 1.04987 | 156.522 | 320 | 2.21457
623219 Run 1 | 0.UG -3.60 | 15 | 14 | 0.492126 | 1.04987 | 150 | 320 | 2.59186
623219 Run 2 | 0.UG -3.60 | 9 | 8 | 0.492126 | 1.04987 | 150 | 320 | 2.59186
623226 Run 1 | 0.UG -3.60 | 7 | 6 | 0.515561 | 1.04987 | 157.143 | 320 | 1.80446
623226 Run 2 | 0.UG -3.60 | 15 | 14 | 0.515561 | 1.04987 | 157.143 | 320 | 1.80446
623352 Run 1 | 6.EG KH -1.15 | 12 | 11 | 0.519466 | 1.04987 | 158.333 | 320 | 2.78871
623352 Run 2 | 6.EG KH -1.15 | 12 | 11 | 0.519466 | 1.04987 | 158.333 | 320 | 2.78871
623399 Run 1 | 7.1OG KH +2.65 | 12 | 11 | 0.519466 | 1.04987 | 158.333 | 320 | 2.78871
623399 Run 2 | 7.1OG KH +2.65 | 12 | 11 | 0.519466 | 1.04987 | 158.333 | 320 | 2.78871
623442 Run 1 | 8.2OG KH +6.45 | 12 | 11 | 0.519466 | 1.04987 | 158.333 | 320 | 2.78871
623442 Run 2 | 8.2OG KH +6.45 | 12 | 11 | 0.519466 | 1.04987 | 158.333 | 320 | 2.78871
623964 Run 1 | 0.UG -3.60 | 12 | 12 | 0.502379 | 0.984252 | 153.125 | 300 | 2.46063
623964 Run 2 | 0.UG -3.60 | 4 | 4 | 0.502379 | 0.984252 | 153.125 | 300 | 3.28084

# IfcStairFlight: Monolithic Run:1mm_Tread-175mm_Depth (3)
In: 1.EG +0.00
Type - Pset_ProductRequirements - Category: Stairs: Runs
Type - Pset_StairFlightCommon - NosingLength: 0 mm
TreadLength: 1.04987 mm; Material: Concrete, Cast-in-Place gray, Analytical Wall Surface_CJC; Group: Model Group:Building:629362
Pset_QuantityTakeOff - Reference: 1mm_Tread-175mm_Depth
Pset_StairFlightCommon - Reference: 1mm_Tread-175mm_Depth; TreadLength: 320 mm; TreadLengthAtOffset: 320 mm; TreadLengthAtInnerSide: 320 mm
Name (Precast Stair:Stair:...) | NumberOfRiser = Pset_StairFlightCommon, NumberOfRiser | NumberOfTreads = Pset_StairFlightCommon, NumberOfTreads | RiserHeight (mm) | Pset_StairFlightCommon, RiserHeight (mm)
621927 Run 1 | 6 | 5 | 0.410105 | 125
621974 Run 1 | 3 | 2 | 0.437445 | 133.333
624066 Run 1 | 6 | 5 | 0.464786 | 141.667

# IfcStairFlight: Non-Monolithic Run:Concrete_Steps_w-38mm_Tread-38mm_Nosing (2)
In: 1.EG +0.00
Type - PredefinedType: STRAIGHT
Type - Pset_ProductRequirements - Category: Stairs: Runs
Type - Pset_StairFlightCommon - NosingLength: 38 mm
NumberOfRiser: 3; NumberOfTreads: 3; RiserHeight: 0.929571 mm; TreadLength: 1.04987 mm; Material: Concrete, Cast-in-Place gray; Group: Model Group:Building:629362
Pset_QuantityTakeOff - Reference: Concrete_Steps_w-38mm_Tread-38mm_Nosing
Pset_StairFlightCommon - Reference: Concrete_Steps_w-38mm_Tread-38mm_Nosing; NumberOfRiser: 3; NumberOfTreads: 3; RiserHeight: 283.333 mm; TreadLength: 320 mm; WalkingLineOffset: 1.64042 mm; TreadLengthAtOffset: 320 mm; TreadLengthAtInnerSide: 320 mm
Name (Assembled Stair:Stair:...)
629207 Run 1
629355 Run 1

# IfcWall: 00 (3)
In: 1.EG +0.00
Type - Material: road_markirovka
Type - Pset_ProductRequirements - Category: Walls
Type - Pset_WallCommon - IsExternal: no
Pset_QuantityTakeOff - sets with these values: 2
Group: Model Group:River:478153
Name | Pset_QuantityTakeOff, Reference = Pset_WallCommon, Reference
00:00:295591 | 00
00 206555:00 206555:296071 | 00 206555
00 206648:00 206648:296231 | 00 206648

# IfcWall: 01 (2)
In: 1.EG +0.00
Type - Material: road_markirovka
Type - Pset_ProductRequirements - Category: Walls
Type - Pset_WallCommon - IsExternal: no
Pset_QuantityTakeOff - sets with these values: 2
Group: Model Group:River:478153
Name | Pset_QuantityTakeOff, Reference = Pset_WallCommon, Reference
01:01:296023 | 01
01 206822:01 206822:296679 | 01 206822

# IfcWall: 02 (2)
In: 1.EG +0.00
Type - Material: road_markirovka
Type - Pset_ProductRequirements - Category: Walls
Type - Pset_WallCommon - IsExternal: no
Pset_QuantityTakeOff - sets with these values: 2
Group: Model Group:River:478153
Name | Pset_QuantityTakeOff, Reference = Pset_WallCommon, Reference
02:02:296183 | 02
02 206647:02 206647:296215 | 02 206647

# IfcWall: 03, 03:03:296359
In: 1.EG +0.00
Type - Material: road_markirovka
Type - Pset_ProductRequirements - Category: Walls
Type - Pset_WallCommon - IsExternal: no
Pset_QuantityTakeOff - Reference: 03; sets with these values: 2
Pset_WallCommon - Reference: 03
Group: Model Group:River:478153

# IfcWall: 04 (201)
Type - Material: road_markirovka
Type - Pset_ProductRequirements - Category: Walls
Type - Pset_WallCommon - IsExternal: no
Pset_QuantityTakeOff - sets with these values: 2
Group: Model Group:River:478153
Name | In | Pset_QuantityTakeOff, Reference = Pset_WallCommon, Reference
04:04:288950 | 1.EG +0.00 | 04
04 203373:04 203373:289526 | 0.UG -3.60 | 04 203373
04 203686:04 203686:291047 | 6.EG KH -1.15 | 04 203686
04 203688:04 203688:291063 | 6.EG KH -1.15 | 04 203688
04 203690:04 203690:291079 | 6.EG KH -1.15 | 04 203690
04 203693:04 203693:291095 | 6.EG KH -1.15 | 04 203693
04 203695:04 203695:291111 | 6.EG KH -1.15 | 04 203695
04 203696:04 203696:291127 | 6.EG KH -1.15 | 04 203696
04 203697:04 203697:291143 | 6.EG KH -1.15 | 04 203697
04 203701:04 203701:291159 | 6.EG KH -1.15 | 04 203701
04 203703:04 203703:291175 | 6.EG KH -1.15 | 04 203703
04 203705:04 203705:291191 | 6.EG KH -1.15 | 04 203705
04 203707:04 203707:291207 | 6.EG KH -1.15 | 04 203707
04 203709:04 203709:291223 | 6.EG KH -1.15 | 04 203709
04 203710:04 203710:291239 | 6.EG KH -1.15 | 04 203710
04 203713:04 203713:291255 | 6.EG KH -1.15 | 04 203713
04 203714:04 203714:291271 | 6.EG KH -1.15 | 04 203714
04 203716:04 203716:291287 | 6.EG KH -1.15 | 04 203716
04 203719:04 203719:291303 | 6.EG KH -1.15 | 04 203719
04 203735:04 203735:291431 | 6.EG KH -1.15 | 04 203735
04 203756:04 203756:291591 | 6.EG KH -1.15 | 04 203756
04 203757:04 203757:291607 | 6.EG KH -1.15 | 04 203757
04 203762:04 203762:291639 | 6.EG KH -1.15 | 04 203762
04 203764:04 203764:291655 | 6.EG KH -1.15 | 04 203764
04 203765:04 203765:291671 | 6.EG KH -1.15 | 04 203765
04 203766:04 203766:291687 | 6.EG KH -1.15 | 04 203766
04 203768:04 203768:291703 | 6.EG KH -1.15 | 04 203768
04 203769:04 203769:291719 | 6.EG KH -1.15 | 04 203769
04 203770:04 203770:291735 | 6.EG KH -1.15 | 04 203770
04 203774:04 203774:291751 | 6.EG KH -1.15 | 04 203774
04 203776:04 203776:291767 | 6.EG KH -1.15 | 04 203776
04 203779:04 203779:291783 | 6.EG KH -1.15 | 04 203779
04 203781:04 203781:291799 | 6.EG KH -1.15 | 04 203781
04 203784:04 203784:291815 | 6.EG KH -1.15 | 04 203784
04 203785:04 203785:291831 | 6.EG KH -1.15 | 04 203785
04 203787:04 203787:291847 | 6.EG KH -1.15 | 04 203787
04 203788:04 203788:291863 | 6.EG KH -1.15 | 04 203788
04 203790:04 203790:291879 | 6.EG KH -1.15 | 04 203790
04 203791:04 203791:291895 | 1.EG +0.00 | 04 203791
04 203795:04 203795:291911 | 1.EG +0.00 | 04 203795
04 203798:04 203798:291927 | 1.EG +0.00 | 04 203798
04 203799:04 203799:291943 | 1.EG +0.00 | 04 203799
04 203802:04 203802:291959 | 1.EG +0.00 | 04 203802
04 203804:04 203804:291975 | 1.EG +0.00 | 04 203804
04 203806:04 203806:291991 | 1.EG +0.00 | 04 203806
04 203808:04 203808:292007 | 1.EG +0.00 | 04 203808
04 203810:04 203810:292023 | 1.EG +0.00 | 04 203810
04 203811:04 203811:292039 | 1.EG +0.00 | 04 203811
04 203813:04 203813:292055 | 1.EG +0.00 | 04 203813
04 203815:04 203815:292071 | 1.EG +0.00 | 04 203815
04 203816:04 203816:292087 | 1.EG +0.00 | 04 203816
04 203819:04 203819:292103 | 1.EG +0.00 | 04 203819
04 203822:04 203822:292119 | 1.EG +0.00 | 04 203822
04 203824:04 203824:292135 | 1.EG +0.00 | 04 203824
04 203825:04 203825:292151 | 1.EG +0.00 | 04 203825
04 203826:04 203826:292167 | 1.EG +0.00 | 04 203826
04 203828:04 203828:292183 | 1.EG +0.00 | 04 203828
04 203830:04 203830:292199 | 1.EG +0.00 | 04 203830
04 203831:04 203831:292215 | 1.EG +0.00 | 04 203831
04 203837:04 203837:292231 | 1.EG +0.00 | 04 203837
04 203838:04 203838:292247 | 1.EG +0.00 | 04 203838
04 203839:04 203839:292263 | 1.EG +0.00 | 04 203839
04 203841:04 203841:292279 | 1.EG +0.00 | 04 203841
04 203843:04 203843:292295 | 1.EG +0.00 | 04 203843
04 203845:04 203845:292311 | 1.EG +0.00 | 04 203845
04 203848:04 203848:292327 | 1.EG +0.00 | 04 203848
04 203850:04 203850:292343 | 1.EG +0.00 | 04 203850
04 203851:04 203851:292359 | 1.EG +0.00 | 04 203851
04 203853:04 203853:292375 | 1.EG +0.00 | 04 203853
04 203856:04 203856:292391 | 1.EG +0.00 | 04 203856
04 203857:04 203857:292407 | 1.EG +0.00 | 04 203857
04 203859:04 203859:292423 | 1.EG +0.00 | 04 203859
04 203861:04 203861:292439 | 1.EG +0.00 | 04 203861
04 203863:04 203863:292455 | 1.EG +0.00 | 04 203863
04 203864:04 203864:292471 | 1.EG +0.00 | 04 203864
04 203866:04 203866:292487 | 1.EG +0.00 | 04 203866
04 203872:04 203872:292535 | 1.EG +0.00 | 04 203872
04 204142:04 204142:292686 | 1.EG +0.00 | 04 204142
04 204245:04 204245:292718 | 1.EG +0.00 | 04 204245
04 204451:04 204451:292750 | 1.EG +0.00 | 04 204451
04 204487:04 204487:292782 | 1.EG +0.00 | 04 204487
04 204542:04 204542:292798 | 1.EG +0.00 | 04 204542
04 204776:04 204776:292814 | 1.EG +0.00 | 04 204776
04 204786:04 204786:292830 | 1.EG +0.00 | 04 204786
04 204813:04 204813:292846 | 1.EG +0.00 | 04 204813
04 204871:04 204871:292862 | 1.EG +0.00 | 04 204871
04 204886:04 204886:292897 | 1.EG +0.00 | 04 204886
04 204887:04 204887:292913 | 1.EG +0.00 | 04 204887
04 204889:04 204889:292929 | 1.EG +0.00 | 04 204889
04 204892:04 204892:292945 | 1.EG +0.00 | 04 204892
04 204893:04 204893:292961 | 1.EG +0.00 | 04 204893
04 204896:04 204896:292977 | 1.EG +0.00 | 04 204896
04 204897:04 204897:292993 | 1.EG +0.00 | 04 204897
04 204900:04 204900:293009 | 1.EG +0.00 | 04 204900
04 204901:04 204901:293025 | 1.EG +0.00 | 04 204901
04 204904:04 204904:293041 | 1.EG +0.00 | 04 204904
04 204905:04 204905:293057 | 1.EG +0.00 | 04 204905
04 204909:04 204909:293073 | 1.EG +0.00 | 04 204909
04 204910:04 204910:293089 | 1.EG +0.00 | 04 204910
04 204911:04 204911:293105 | 1.EG +0.00 | 04 204911
04 204913:04 204913:293121 | 1.EG +0.00 | 04 204913
04 204915:04 204915:293137 | 1.EG +0.00 | 04 204915
04 204917:04 204917:293153 | 1.EG +0.00 | 04 204917
04 204919:04 204919:293169 | 1.EG +0.00 | 04 204919
04 204922:04 204922:293185 | 1.EG +0.00 | 04 204922
04 204925:04 204925:293201 | 1.EG +0.00 | 04 204925
04 204926:04 204926:293217 | 1.EG +0.00 | 04 204926
04 204929:04 204929:293233 | 1.EG +0.00 | 04 204929
04 204930:04 204930:293249 | 1.EG +0.00 | 04 204930
04 204933:04 204933:293265 | 1.EG +0.00 | 04 204933
04 204949:04 204949:293393 | 1.EG +0.00 | 04 204949
04 205009:04 205009:293873 | 0.UG -3.60 | 04 205009
04 205010:04 205010:293889 | 0.UG -3.60 | 04 205010
04 205012:04 205012:293905 | 0.UG -3.60 | 04 205012
04 205013:04 205013:293921 | 0.UG -3.60 | 04 205013
04 205016:04 205016:293937 | 0.UG -3.60 | 04 205016
04 205018:04 205018:293953 | 0.UG -3.60 | 04 205018
04 205019:04 205019:293969 | 0.UG -3.60 | 04 205019
04 205022:04 205022:293985 | 0.UG -3.60 | 04 205022
04 205024:04 205024:294001 | 0.UG -3.60 | 04 205024
04 205025:04 205025:294017 | 0.UG -3.60 | 04 205025
04 205028:04 205028:294033 | 0.UG -3.60 | 04 205028
04 205029:04 205029:294049 | 0.UG -3.60 | 04 205029
04 205032:04 205032:294065 | 0.UG -3.60 | 04 205032
04 205034:04 205034:294081 | 0.UG -3.60 | 04 205034
04 205035:04 205035:294097 | 0.UG -3.60 | 04 205035
04 205037:04 205037:294113 | 0.UG -3.60 | 04 205037
04 205039:04 205039:294129 | 0.UG -3.60 | 04 205039
04 205042:04 205042:294145 | 0.UG -3.60 | 04 205042
04 205043:04 205043:294161 | 0.UG -3.60 | 04 205043
04 205045:04 205045:294177 | 0.UG -3.60 | 04 205045
04 205048:04 205048:294193 | 0.UG -3.60 | 04 205048
04 205049:04 205049:294209 | 0.UG -3.60 | 04 205049
04 205050:04 205050:294225 | 0.UG -3.60 | 04 205050
04 205053:04 205053:294241 | 0.UG -3.60 | 04 205053
04 205055:04 205055:294257 | 0.UG -3.60 | 04 205055
04 205058:04 205058:294273 | 0.UG -3.60 | 04 205058
04 205061:04 205061:294289 | 0.UG -3.60 | 04 205061
04 205062:04 205062:294305 | 0.UG -3.60 | 04 205062
04 205064:04 205064:294321 | 0.UG -3.60 | 04 205064
04 205072:04 205072:294358 | 0.UG -3.60 | 04 205072
04 205074:04 205074:294374 | 0.UG -3.60 | 04 205074
04 205076:04 205076:294390 | 0.UG -3.60 | 04 205076
04 205078:04 205078:294406 | 0.UG -3.60 | 04 205078
04 205084:04 205084:294436 | 0.UG -3.60 | 04 205084
04 205086:04 205086:294452 | 0.UG -3.60 | 04 205086
04 205090:04 205090:294475 | 0.UG -3.60 | 04 205090
04 205091:04 205091:294491 | 0.UG -3.60 | 04 205091
04 205097:04 205097:294514 | 0.UG -3.60 | 04 205097
04 205098:04 205098:294530 | 0.UG -3.60 | 04 205098
04 205101:04 205101:294553 | 0.UG -3.60 | 04 205101
04 205106:04 205106:294576 | 0.UG -3.60 | 04 205106
04 205108:04 205108:294592 | 0.UG -3.60 | 04 205108
04 205109:04 205109:294608 | 0.UG -3.60 | 04 205109
04 205112:04 205112:294624 | 0.UG -3.60 | 04 205112
04 205113:04 205113:294640 | 0.UG -3.60 | 04 205113
04 206140:04 206140:294727 | 0.UG -3.60 | 04 206140
04 206142:04 206142:294743 | 0.UG -3.60 | 04 206142
04 206143:04 206143:294759 | 0.UG -3.60 | 04 206143
04 206147:04 206147:294775 | 0.UG -3.60 | 04 206147
04 206148:04 206148:294791 | 0.UG -3.60 | 04 206148
04 206150:04 206150:294807 | 0.UG -3.60 | 04 206150
04 206153:04 206153:294823 | 0.UG -3.60 | 04 206153
04 206155:04 206155:294839 | 0.UG -3.60 | 04 206155
04 206157:04 206157:294855 | 0.UG -3.60 | 04 206157
04 206158:04 206158:294871 | 0.UG -3.60 | 04 206158
04 206162:04 206162:294887 | 0.UG -3.60 | 04 206162
04 206163:04 206163:294903 | 0.UG -3.60 | 04 206163
04 206165:04 206165:294919 | 0.UG -3.60 | 04 206165
04 206166:04 206166:294935 | 0.UG -3.60 | 04 206166
04 206169:04 206169:294951 | 0.UG -3.60 | 04 206169
04 206171:04 206171:294967 | 0.UG -3.60 | 04 206171
04 206172:04 206172:294983 | 0.UG -3.60 | 04 206172
04 206175:04 206175:294999 | 0.UG -3.60 | 04 206175
04 206177:04 206177:295015 | 0.UG -3.60 | 04 206177
04 206180:04 206180:295031 | 0.UG -3.60 | 04 206180
04 206181:04 206181:295047 | 0.UG -3.60 | 04 206181
04 206182:04 206182:295063 | 0.UG -3.60 | 04 206182
04 206185:04 206185:295079 | 0.UG -3.60 | 04 206185
04 206188:04 206188:295095 | 0.UG -3.60 | 04 206188
04 206190:04 206190:295111 | 0.UG -3.60 | 04 206190
04 206214:04 206214:295127 | 0.UG -3.60 | 04 206214
04 206348:04 206348:295143 | 0.UG -3.60 | 04 206348
04 206350:04 206350:295159 | 0.UG -3.60 | 04 206350
04 206351:04 206351:295175 | 0.UG -3.60 | 04 206351
04 206356:04 206356:295191 | 0.UG -3.60 | 04 206356
04 206357:04 206357:295207 | 0.UG -3.60 | 04 206357
04 206360:04 206360:295223 | 0.UG -3.60 | 04 206360
04 206362:04 206362:295239 | 0.UG -3.60 | 04 206362
04 206363:04 206363:295255 | 0.UG -3.60 | 04 206363
04 206364:04 206364:295271 | 0.UG -3.60 | 04 206364
04 206368:04 206368:295287 | 0.UG -3.60 | 04 206368
04 206369:04 206369:295303 | 0.UG -3.60 | 04 206369
04 206371:04 206371:295319 | 0.UG -3.60 | 04 206371
04 206374:04 206374:295335 | 0.UG -3.60 | 04 206374
04 206375:04 206375:295351 | 0.UG -3.60 | 04 206375
04 206377:04 206377:295367 | 0.UG -3.60 | 04 206377
04 206380:04 206380:295383 | 0.UG -3.60 | 04 206380
04 206399:04 206399:295479 | 0.UG -3.60 | 04 206399
04 206405:04 206405:295495 | 0.UG -3.60 | 04 206405
04 206644:04 206644:296199 | 1.EG +0.00 | 04 206644

# IfcWall: 05 (70)
Type - Material: road_markirovka
Type - Pset_ProductRequirements - Category: Walls
Type - Pset_WallCommon - IsExternal: no
Pset_QuantityTakeOff - sets with these values: 2
Group: Model Group:River:478153
Name | In | Pset_QuantityTakeOff, Reference = Pset_WallCommon, Reference
05:05:288982 | 6.EG KH -1.15 | 05
05 203250:05 203250:288998 | 6.EG KH -1.15 | 05 203250
05 203252:05 203252:289014 | 6.EG KH -1.15 | 05 203252
05 203253:05 203253:289030 | 6.EG KH -1.15 | 05 203253
05 203255:05 203255:289046 | 6.EG KH -1.15 | 05 203255
05 203257:05 203257:289062 | 6.EG KH -1.15 | 05 203257
05 203261:05 203261:289078 | 6.EG KH -1.15 | 05 203261
05 203726:05 203726:291367 | 6.EG KH -1.15 | 05 203726
05 203758:05 203758:291623 | 6.EG KH -1.15 | 05 203758
05 203867:05 203867:292503 | 1.EG +0.00 | 05 203867
05 203871:05 203871:292519 | 1.EG +0.00 | 05 203871
05 203888:05 203888:292551 | 1.EG +0.00 | 05 203888
05 203891:05 203891:292567 | 1.EG +0.00 | 05 203891
05 203892:05 203892:292583 | 1.EG +0.00 | 05 203892
05 203894:05 203894:292599 | 1.EG +0.00 | 05 203894
05 203897:05 203897:292615 | 1.EG +0.00 | 05 203897
05 203899:05 203899:292631 | 1.EG +0.00 | 05 203899
05 203901:05 203901:292647 | 1.EG +0.00 | 05 203901
05 203902:05 203902:292663 | 1.EG +0.00 | 05 203902
05 204169:05 204169:292702 | 1.EG +0.00 | 05 204169
05 204282:05 204282:292734 | 1.EG +0.00 | 05 204282
05 204477:05 204477:292766 | 1.EG +0.00 | 05 204477
05 205004:05 205004:293857 | 0.UG -3.60 | 05 205004
05 206852:05 206852:296711 | 6.EG KH -1.15 | 05 206852
05 206854:05 206854:296727 | 6.EG KH -1.15 | 05 206854
05 206866:05 206866:296743 | 6.EG KH -1.15 | 05 206866
05 206871:05 206871:296759 | 6.EG KH -1.15 | 05 206871
05 206873:05 206873:296775 | 6.EG KH -1.15 | 05 206873
05 206875:05 206875:296791 | 6.EG KH -1.15 | 05 206875
05 206877:05 206877:296807 | 6.EG KH -1.15 | 05 206877
05 206878:05 206878:296823 | 0.UG -3.60 | 05 206878
05 206880:05 206880:296839 | 0.UG -3.60 | 05 206880
05 206881:05 206881:296855 | 0.UG -3.60 | 05 206881
05 206884:05 206884:296871 | 0.UG -3.60 | 05 206884
05 206887:05 206887:296887 | 0.UG -3.60 | 05 206887
05 206889:05 206889:296903 | 0.UG -3.60 | 05 206889
05 206890:05 206890:296919 | 0.UG -3.60 | 05 206890
05 206891:05 206891:296935 | 0.UG -3.60 | 05 206891
05 206893:05 206893:296951 | 0.UG -3.60 | 05 206893
05 206896:05 206896:296967 | 0.UG -3.60 | 05 206896
05 206897:05 206897:296983 | 0.UG -3.60 | 05 206897
05 206899:05 206899:296999 | 0.UG -3.60 | 05 206899
05 206901:05 206901:297015 | 0.UG -3.60 | 05 206901
05 206903:05 206903:297031 | 0.UG -3.60 | 05 206903
05 206905:05 206905:297047 | 0.UG -3.60 | 05 206905
05 206907:05 206907:297063 | 0.UG -3.60 | 05 206907
05 206911:05 206911:297079 | 0.UG -3.60 | 05 206911
05 206912:05 206912:297095 | 0.UG -3.60 | 05 206912
05 206914:05 206914:297111 | 0.UG -3.60 | 05 206914
05 206916:05 206916:297127 | 0.UG -3.60 | 05 206916
05 206917:05 206917:297143 | 0.UG -3.60 | 05 206917
05 206918:05 206918:297159 | 0.UG -3.60 | 05 206918
05 206921:05 206921:297175 | 0.UG -3.60 | 05 206921
05 206922:05 206922:297191 | 0.UG -3.60 | 05 206922
05 206925:05 206925:297207 | 0.UG -3.60 | 05 206925
05 206927:05 206927:297223 | 0.UG -3.60 | 05 206927
05 206929:05 206929:297239 | 0.UG -3.60 | 05 206929
05 206932:05 206932:297255 | 0.UG -3.60 | 05 206932
05 206934:05 206934:297271 | 0.UG -3.60 | 05 206934
05 206935:05 206935:297287 | 0.UG -3.60 | 05 206935
05 206939:05 206939:297303 | 0.UG -3.60 | 05 206939
05 206941:05 206941:297319 | 0.UG -3.60 | 05 206941
05 206942:05 206942:297335 | 0.UG -3.60 | 05 206942
05 206944:05 206944:297351 | 0.UG -3.60 | 05 206944
05 206947:05 206947:297367 | 0.UG -3.60 | 05 206947
05 206948:05 206948:297383 | 0.UG -3.60 | 05 206948
05 206949:05 206949:297399 | 0.UG -3.60 | 05 206949
05 206951:05 206951:297415 | 0.UG -3.60 | 05 206951
05 206954:05 206954:297431 | 0.UG -3.60 | 05 206954
05 206957:05 206957:297447 | 0.UG -3.60 | 05 206957

# IfcWall: 06 (13)
Type - Material: road_markirovka
Type - Pset_ProductRequirements - Category: Walls
Type - Pset_WallCommon - IsExternal: no
Pset_QuantityTakeOff - sets with these values: 2
Group: Model Group:River:478153
Name | In | Pset_QuantityTakeOff, Reference = Pset_WallCommon, Reference
06:06:291351 | 6.EG KH -1.15 | 06
06 203730:06 203730:291399 | 6.EG KH -1.15 | 06 203730
06 203731:06 203731:291415 | 6.EG KH -1.15 | 06 203731
06 203736:06 203736:291447 | 6.EG KH -1.15 | 06 203736
06 203738:06 203738:291463 | 6.EG KH -1.15 | 06 203738
06 203739:06 203739:291479 | 6.EG KH -1.15 | 06 203739
06 203742:06 203742:291495 | 6.EG KH -1.15 | 06 203742
06 203743:06 203743:291511 | 6.EG KH -1.15 | 06 203743
06 203748:06 203748:291527 | 6.EG KH -1.15 | 06 203748
06 203749:06 203749:291543 | 6.EG KH -1.15 | 06 203749
06 203750:06 203750:291559 | 6.EG KH -1.15 | 06 203750
06 203753:06 203753:291575 | 6.EG KH -1.15 | 06 203753
06 205003:06 205003:293841 | 0.UG -3.60 | 06 205003

# IfcWall: 07 (2)
Type - Material: road_markirovka
Type - Pset_ProductRequirements - Category: Walls
Type - Pset_WallCommon - IsExternal: no
Pset_QuantityTakeOff - sets with these values: 2
Group: Model Group:River:478153
Name | In | Pset_QuantityTakeOff, Reference = Pset_WallCommon, Reference
07:07:291319 | 6.EG KH -1.15 | 07
07 205001:07 205001:293825 | 0.UG -3.60 | 07 205001

# IfcWall: 08 (5)
Type - Material: road_markirovka
Type - Pset_ProductRequirements - Category: Walls
Type - Pset_WallCommon - IsExternal: no
Pset_QuantityTakeOff - sets with these values: 2
Group: Model Group:River:478153
Name | In | Pset_QuantityTakeOff, Reference = Pset_WallCommon, Reference
08:08:288886 | 0.UG -3.60 | 08
08 203722:08 203722:291335 | 6.EG KH -1.15 | 08 203722
08 204960:08 204960:293489 | 0.UG -3.60 | 08 204960
08 204980:08 204980:293649 | 0.UG -3.60 | 08 204980
08 204998:08 204998:293809 | 0.UG -3.60 | 08 204998

# IfcWall: 09 (4)
Type - Material: road_markirovka
Type - Pset_ProductRequirements - Category: Walls
Type - Pset_WallCommon - IsExternal: no
Pset_QuantityTakeOff - sets with these values: 2
Group: Model Group:River:478153
Name | In | Pset_QuantityTakeOff, Reference = Pset_WallCommon, Reference
09:09:291383 | 6.EG KH -1.15 | 09
09 204961:09 204961:293505 | 0.UG -3.60 | 09 204961
09 204981:09 204981:293665 | 0.UG -3.60 | 09 204981
09 204997:09 204997:293793 | 0.UG -3.60 | 09 204997

# IfcWall: 10 (3)
In: 0.UG -3.60
Type - Material: road_markirovka
Type - Pset_ProductRequirements - Category: Walls
Type - Pset_WallCommon - IsExternal: no
Pset_QuantityTakeOff - sets with these values: 2
Group: Model Group:River:478153
Name | Pset_QuantityTakeOff, Reference = Pset_WallCommon, Reference
10:10:293473 | 10
10 204976:10 204976:293617 | 10 204976
10 204996:10 204996:293777 | 10 204996

# IfcWall: 11 (3)
In: 0.UG -3.60
Type - Material: road_markirovka
Type - Pset_ProductRequirements - Category: Walls
Type - Pset_WallCommon - IsExternal: no
Pset_QuantityTakeOff - sets with these values: 2
Group: Model Group:River:478153
Name | Pset_QuantityTakeOff, Reference = Pset_WallCommon, Reference
11:11:293457 | 11
11 204975:11 204975:293601 | 11 204975
11 204993:11 204993:293761 | 11 204993

# IfcWall: 12 (3)
In: 0.UG -3.60
Type - Material: road_markirovka
Type - Pset_ProductRequirements - Category: Walls
Type - Pset_WallCommon - IsExternal: no
Pset_QuantityTakeOff - sets with these values: 2
Group: Model Group:River:478153
Name | Pset_QuantityTakeOff, Reference = Pset_WallCommon, Reference
12:12:293441 | 12
12 204972:12 204972:293585 | 12 204972
12 204991:12 204991:293745 | 12 204991

# IfcWall: 13 (3)
In: 0.UG -3.60
Type - Material: road_markirovka
Type - Pset_ProductRequirements - Category: Walls
Type - Pset_WallCommon - IsExternal: no
Pset_QuantityTakeOff - sets with these values: 2
Group: Model Group:River:478153
Name | Pset_QuantityTakeOff, Reference = Pset_WallCommon, Reference
13:13:293425 | 13
13 204979:13 204979:293633 | 13 204979
13 204987:13 204987:293713 | 13 204987

# IfcWall: 14 (3)
In: 0.UG -3.60
Type - Material: road_markirovka
Type - Pset_ProductRequirements - Category: Walls
Type - Pset_WallCommon - IsExternal: no
Pset_QuantityTakeOff - sets with these values: 2
Group: Model Group:River:478153
Name | Pset_QuantityTakeOff, Reference = Pset_WallCommon, Reference
14:14:293409 | 14
14 204968:14 204968:293553 | 14 204968
14 204985:14 204985:293697 | 14 204985

# IfcWall: 15 (3)
In: 0.UG -3.60
Type - Material: road_markirovka
Type - Pset_ProductRequirements - Category: Walls
Type - Pset_WallCommon - IsExternal: no
Pset_QuantityTakeOff - sets with these values: 2
Group: Model Group:River:478153
Name | Pset_QuantityTakeOff, Reference = Pset_WallCommon, Reference
15:15:293377 | 15
15 204970:15 204970:293569 | 15 204970
15 204989:15 204989:293729 | 15 204989

# IfcWall: 16 (13)
In: 0.UG -3.60
Type - Material: road_markirovka
Type - Pset_ProductRequirements - Category: Walls
Type - Pset_WallCommon - IsExternal: no
Pset_QuantityTakeOff - sets with these values: 2
Group: Model Group:River:478153
Name | Pset_QuantityTakeOff, Reference = Pset_WallCommon, Reference
16:16:288720 | 16
16 203180:16 203180:288758 | 16 203180
16 203186:16 203186:288774 | 16 203186
16 203189:16 203189:288806 | 16 203189
16 203214:16 203214:288870 | 16 203214
16 204934:16 204934:293281 | 16 204934
16 204936:16 204936:293297 | 16 204936
16 204938:16 204938:293313 | 16 204938
16 204940:16 204940:293329 | 16 204940
16 204943:16 204943:293345 | 16 204943
16 204944:16 204944:293361 | 16 204944
16 204967:16 204967:293537 | 16 204967
16 204984:16 204984:293681 | 16 204984

# IfcWall: 81 (219)
Type - Material: road_markirovka
Type - Pset_ProductRequirements - Category: Walls
Type - Pset_WallCommon - IsExternal: no
Pset_QuantityTakeOff - sets with these values: 2
Group: Model Group:River:478153
Name | In | Pset_QuantityTakeOff, Reference = Pset_WallCommon, Reference
81:81:288822 | 0.UG -3.60 | 81
81 203199:81 203199:288838 | 0.UG -3.60 | 81 203199
81 203208:81 203208:288854 | 0.UG -3.60 | 81 203208
81 203229:81 203229:288966 | 0.UG -3.60 | 81 203229
81 203270:81 203270:289094 | 0.UG -3.60 | 81 203270
81 203274:81 203274:289110 | 0.UG -3.60 | 81 203274
81 203276:81 203276:289126 | 0.UG -3.60 | 81 203276
81 203282:81 203282:289142 | 0.UG -3.60 | 81 203282
81 203300:81 203300:289158 | 0.UG -3.60 | 81 203300
81 203321:81 203321:289174 | 0.UG -3.60 | 81 203321
81 203322:81 203322:289190 | 0.UG -3.60 | 81 203322
81 203329:81 203329:289206 | 0.UG -3.60 | 81 203329
81 203334:81 203334:289222 | 0.UG -3.60 | 81 203334
81 203335:81 203335:289238 | 0.UG -3.60 | 81 203335
81 203340:81 203340:289254 | 0.UG -3.60 | 81 203340
81 203342:81 203342:289270 | 0.UG -3.60 | 81 203342
81 203344:81 203344:289286 | 0.UG -3.60 | 81 203344
81 203346:81 203346:289302 | 0.UG -3.60 | 81 203346
81 203348:81 203348:289318 | 0.UG -3.60 | 81 203348
81 203350:81 203350:289334 | 0.UG -3.60 | 81 203350
81 203352:81 203352:289350 | 0.UG -3.60 | 81 203352
81 203353:81 203353:289366 | 0.UG -3.60 | 81 203353
81 203355:81 203355:289382 | 0.UG -3.60 | 81 203355
81 203356:81 203356:289398 | 0.UG -3.60 | 81 203356
81 203358:81 203358:289414 | 0.UG -3.60 | 81 203358
81 203360:81 203360:289430 | 0.UG -3.60 | 81 203360
81 203362:81 203362:289446 | 0.UG -3.60 | 81 203362
81 203364:81 203364:289462 | 0.UG -3.60 | 81 203364
81 203366:81 203366:289478 | 0.UG -3.60 | 81 203366
81 203367:81 203367:289494 | 0.UG -3.60 | 81 203367
81 203372:81 203372:289510 | 0.UG -3.60 | 81 203372
81 203375:81 203375:289542 | 0.UG -3.60 | 81 203375
81 203376:81 203376:289558 | 0.UG -3.60 | 81 203376
81 203377:81 203377:289574 | 0.UG -3.60 | 81 203377
81 203379:81 203379:289590 | 0.UG -3.60 | 81 203379
81 203382:81 203382:289606 | 0.UG -3.60 | 81 203382
81 203385:81 203385:289622 | 0.UG -3.60 | 81 203385
81 203387:81 203387:289638 | 0.UG -3.60 | 81 203387
81 203389:81 203389:289654 | 0.UG -3.60 | 81 203389
81 203390:81 203390:289670 | 0.UG -3.60 | 81 203390
81 203391:81 203391:289686 | 0.UG -3.60 | 81 203391
81 203396:81 203396:289702 | 0.UG -3.60 | 81 203396
81 203397:81 203397:289718 | 0.UG -3.60 | 81 203397
81 203398:81 203398:289734 | 0.UG -3.60 | 81 203398
81 203401:81 203401:289750 | 6.EG KH -1.15 | 81 203401
81 203403:81 203403:289766 | 1.EG +0.00 | 81 203403
81 203404:81 203404:289782 | 1.EG +0.00 | 81 203404
81 203406:81 203406:289798 | 6.EG KH -1.15 | 81 203406
81 203409:81 203409:289814 | 1.EG +0.00 | 81 203409
81 203410:81 203410:289830 | 1.EG +0.00 | 81 203410
81 203413:81 203413:289846 | 1.EG +0.00 | 81 203413
81 203415:81 203415:289862 | 1.EG +0.00 | 81 203415
81 203417:81 203417:289878 | 1.EG +0.00 | 81 203417
81 203419:81 203419:289894 | 1.EG +0.00 | 81 203419
81 203422:81 203422:289910 | 1.EG +0.00 | 81 203422
81 203423:81 203423:289926 | 1.EG +0.00 | 81 203423
81 203426:81 203426:289942 | 1.EG +0.00 | 81 203426
81 203436:81 203436:289958 | 1.EG +0.00 | 81 203436
81 203447:81 203447:289974 | 1.EG +0.00 | 81 203447
81 203449:81 203449:289990 | 1.EG +0.00 | 81 203449
81 203454:81 203454:290006 | 1.EG +0.00 | 81 203454
81 203463:81 203463:290022 | 1.EG +0.00 | 81 203463
81 203467:81 203467:290038 | 1.EG +0.00 | 81 203467
81 203468:81 203468:290054 | 1.EG +0.00 | 81 203468
81 203471:81 203471:290070 | 1.EG +0.00 | 81 203471
81 203475:81 203475:290086 | 1.EG +0.00 | 81 203475
81 203477:81 203477:290102 | 1.EG +0.00 | 81 203477
81 203478:81 203478:290118 | 1.EG +0.00 | 81 203478
81 203482:81 203482:290134 | 1.EG +0.00 | 81 203482
81 203483:81 203483:290150 | 1.EG +0.00 | 81 203483
81 203485:81 203485:290166 | 1.EG +0.00 | 81 203485
81 203486:81 203486:290182 | 1.EG +0.00 | 81 203486
81 203491:81 203491:290198 | 1.EG +0.00 | 81 203491
81 203492:81 203492:290214 | 1.EG +0.00 | 81 203492
81 203493:81 203493:290230 | 1.EG +0.00 | 81 203493
81 203495:81 203495:290246 | 1.EG +0.00 | 81 203495
81 203505:81 203505:290262 | 1.EG +0.00 | 81 203505
81 203507:81 203507:290278 | 1.EG +0.00 | 81 203507
81 203523:81 203523:290294 | 1.EG +0.00 | 81 203523
81 203526:81 203526:290310 | 1.EG +0.00 | 81 203526
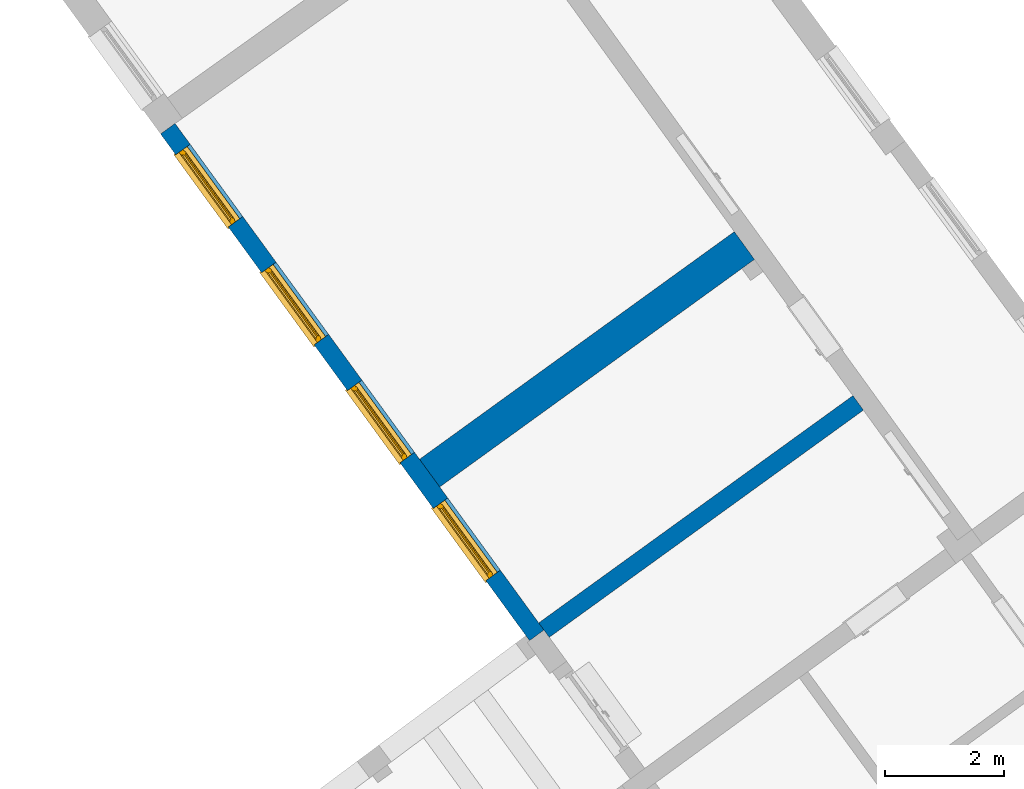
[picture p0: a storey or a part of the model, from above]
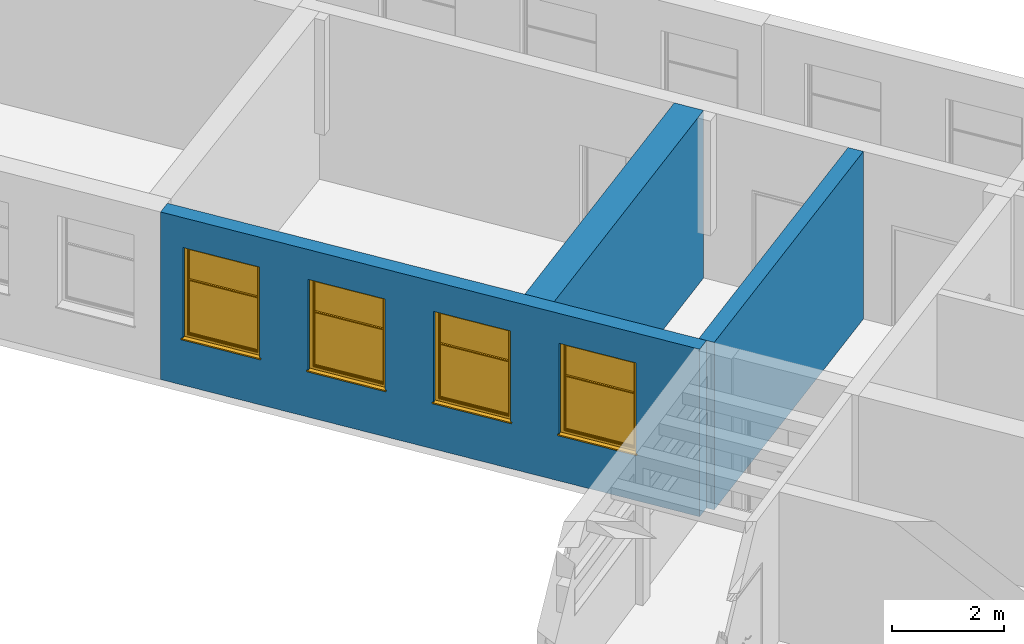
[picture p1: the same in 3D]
Properties of the parts of a building model (IFC2X3), part 12 of 13

# IfcWall: 81 (219)
Name | In | Pset_QuantityTakeOff, Reference = Pset_WallCommon, Reference
81 203530:81 203530:290326 | 1.EG +0.00 | 81 203530
81 203533:81 203533:290342 | 1.EG +0.00 | 81 203533
81 203534:81 203534:290358 | 1.EG +0.00 | 81 203534
81 203536:81 203536:290374 | 1.EG +0.00 | 81 203536
81 203539:81 203539:290390 | 1.EG +0.00 | 81 203539
81 203541:81 203541:290406 | 1.EG +0.00 | 81 203541
81 203543:81 203543:290422 | 1.EG +0.00 | 81 203543
81 203544:81 203544:290438 | 1.EG +0.00 | 81 203544
81 203546:81 203546:290454 | 1.EG +0.00 | 81 203546
81 203548:81 203548:290470 | 1.EG +0.00 | 81 203548
81 203551:81 203551:290486 | 1.EG +0.00 | 81 203551
81 203552:81 203552:290502 | 1.EG +0.00 | 81 203552
81 203555:81 203555:290518 | 1.EG +0.00 | 81 203555
81 203556:81 203556:290534 | 1.EG +0.00 | 81 203556
81 203565:81 203565:290550 | 1.EG +0.00 | 81 203565
81 203566:81 203566:290566 | 1.EG +0.00 | 81 203566
81 203596:81 203596:290582 | 1.EG +0.00 | 81 203596
81 203597:81 203597:290598 | 1.EG +0.00 | 81 203597
81 203598:81 203598:290614 | 1.EG +0.00 | 81 203598
81 203601:81 203601:290630 | 1.EG +0.00 | 81 203601
81 203604:81 203604:290646 | 1.EG +0.00 | 81 203604
81 203605:81 203605:290662 | 1.EG +0.00 | 81 203605
81 203612:81 203612:290678 | 1.EG +0.00 | 81 203612
81 203614:81 203614:290694 | 1.EG +0.00 | 81 203614
81 203616:81 203616:290710 | 1.EG +0.00 | 81 203616
81 203617:81 203617:290726 | 1.EG +0.00 | 81 203617
81 203620:81 203620:290742 | 1.EG +0.00 | 81 203620
81 203621:81 203621:290758 | 1.EG +0.00 | 81 203621
81 203622:81 203622:290774 | 1.EG +0.00 | 81 203622
81 203625:81 203625:290790 | 1.EG +0.00 | 81 203625
81 203626:81 203626:290806 | 1.EG +0.00 | 81 203626
81 203628:81 203628:290822 | 1.EG +0.00 | 81 203628
81 203629:81 203629:290838 | 1.EG +0.00 | 81 203629
81 203631:81 203631:290854 | 1.EG +0.00 | 81 203631
81 203636:81 203636:290870 | 1.EG +0.00 | 81 203636
81 203637:81 203637:290886 | 1.EG +0.00 | 81 203637
81 203640:81 203640:290902 | 1.EG +0.00 | 81 203640
81 203641:81 203641:290918 | 1.EG +0.00 | 81 203641
81 203643:81 203643:290934 | 1.EG +0.00 | 81 203643
81 203653:81 203653:290950 | 1.EG +0.00 | 81 203653
81 203659:81 203659:290966 | 1.EG +0.00 | 81 203659
81 203663:81 203663:290982 | 1.EG +0.00 | 81 203663
81 203664:81 203664:290998 | 1.EG +0.00 | 81 203664
81 203675:81 203675:291014 | 1.EG +0.00 | 81 203675
81 203676:81 203676:291030 | 1.EG +0.00 | 81 203676
81 204962:81 204962:293521 | 1.EG +0.00 | 81 204962
81 206538:81 206538:295927 | 1.EG +0.00 | 81 206538
81 206540:81 206540:295943 | 1.EG +0.00 | 81 206540
81 206542:81 206542:295959 | 1.EG +0.00 | 81 206542
81 206543:81 206543:295975 | 1.EG +0.00 | 81 206543
81 206547:81 206547:296007 | 1.EG +0.00 | 81 206547
81 206551:81 206551:296039 | 6.EG KH -1.15 | 81 206551
81 206580:81 206580:296135 | 1.EG +0.00 | 81 206580
81 206808:81 206808:296583 | 1.EG +0.00 | 81 206808
81 206968:81 206968:323827 | 0.UG -3.60 | 81 206968
81 206999:81 206999:323843 | 0.UG -3.60 | 81 206999
81 207014:81 207014:323859 | 0.UG -3.60 | 81 207014
81 207025:81 207025:323875 | 0.UG -3.60 | 81 207025
81 207027:81 207027:323891 | 0.UG -3.60 | 81 207027
81 207029:81 207029:323907 | 0.UG -3.60 | 81 207029
81 207030:81 207030:323923 | 0.UG -3.60 | 81 207030
81 207034:81 207034:323939 | 0.UG -3.60 | 81 207034
81 207036:81 207036:323955 | 0.UG -3.60 | 81 207036
81 207038:81 207038:323971 | 0.UG -3.60 | 81 207038
81 207039:81 207039:323987 | 0.UG -3.60 | 81 207039
81 207042:81 207042:324003 | 0.UG -3.60 | 81 207042
81 207044:81 207044:324019 | 0.UG -3.60 | 81 207044
81 207046:81 207046:324035 | 0.UG -3.60 | 81 207046
81 207047:81 207047:324051 | 0.UG -3.60 | 81 207047
81 207049:81 207049:324067 | 0.UG -3.60 | 81 207049
81 207050:81 207050:324083 | 0.UG -3.60 | 81 207050
81 207211:81 207211:324099 | 0.UG -3.60 | 81 207211
81 207214:81 207214:324115 | 0.UG -3.60 | 81 207214
81 207216:81 207216:324131 | 0.UG -3.60 | 81 207216
81 207218:81 207218:324147 | 0.UG -3.60 | 81 207218
81 207221:81 207221:324163 | 0.UG -3.60 | 81 207221
81 207222:81 207222:324179 | 0.UG -3.60 | 81 207222
81 207225:81 207225:324195 | 0.UG -3.60 | 81 207225
81 207226:81 207226:324211 | 0.UG -3.60 | 81 207226
81 207281:81 207281:324227 | 0.UG -3.60 | 81 207281
81 207283:81 207283:324243 | 0.UG -3.60 | 81 207283
81 207284:81 207284:324259 | 0.UG -3.60 | 81 207284
81 207292:81 207292:324275 | 0.UG -3.60 | 81 207292
81 207294:81 207294:324291 | 0.UG -3.60 | 81 207294
81 207295:81 207295:324307 | 0.UG -3.60 | 81 207295
81 207297:81 207297:324323 | 0.UG -3.60 | 81 207297
81 207298:81 207298:324339 | 0.UG -3.60 | 81 207298
81 207302:81 207302:324355 | 0.UG -3.60 | 81 207302
81 207304:81 207304:324371 | 0.UG -3.60 | 81 207304
81 207306:81 207306:324387 | 0.UG -3.60 | 81 207306
81 207307:81 207307:324403 | 0.UG -3.60 | 81 207307
81 207310:81 207310:324419 | 0.UG -3.60 | 81 207310
81 207311:81 207311:324435 | 0.UG -3.60 | 81 207311
81 207315:81 207315:324451 | 0.UG -3.60 | 81 207315
81 207316:81 207316:324467 | 0.UG -3.60 | 81 207316
81 207317:81 207317:324483 | 0.UG -3.60 | 81 207317
81 207319:81 207319:324499 | 0.UG -3.60 | 81 207319
81 207322:81 207322:324515 | 0.UG -3.60 | 81 207322
81 207325:81 207325:324531 | 1.EG +0.00 | 81 207325
81 207327:81 207327:324547 | 0.UG -3.60 | 81 207327
81 207328:81 207328:324563 | 0.UG -3.60 | 81 207328
81 207329:81 207329:324579 | 1.EG +0.00 | 81 207329
81 207331:81 207331:324595 | 6.EG KH -1.15 | 81 207331
81 207334:81 207334:324611 | 6.EG KH -1.15 | 81 207334
81 207336:81 207336:324627 | 6.EG KH -1.15 | 81 207336
81 207338:81 207338:324643 | 6.EG KH -1.15 | 81 207338
81 207340:81 207340:324659 | 6.EG KH -1.15 | 81 207340
81 207342:81 207342:324675 | 6.EG KH -1.15 | 81 207342
81 207345:81 207345:324691 | 6.EG KH -1.15 | 81 207345
81 207346:81 207346:324707 | 6.EG KH -1.15 | 81 207346
81 207347:81 207347:324723 | 6.EG KH -1.15 | 81 207347
81 207350:81 207350:324739 | 6.EG KH -1.15 | 81 207350
81 207351:81 207351:324755 | 6.EG KH -1.15 | 81 207351
81 207352:81 207352:324771 | 6.EG KH -1.15 | 81 207352
81 207356:81 207356:324787 | 6.EG KH -1.15 | 81 207356
81 207357:81 207357:324803 | 6.EG KH -1.15 | 81 207357
81 207359:81 207359:324819 | 6.EG KH -1.15 | 81 207359
81 207362:81 207362:324835 | 6.EG KH -1.15 | 81 207362
81 207363:81 207363:324851 | 1.EG +0.00 | 81 207363
81 207366:81 207366:324867 | 1.EG +0.00 | 81 207366
81 207369:81 207369:324883 | 1.EG +0.00 | 81 207369
81 207370:81 207370:324899 | 1.EG +0.00 | 81 207370
81 207372:81 207372:324915 | 1.EG +0.00 | 81 207372
81 207374:81 207374:324931 | 1.EG +0.00 | 81 207374
81 207376:81 207376:324947 | 1.EG +0.00 | 81 207376
81 207377:81 207377:324963 | 1.EG +0.00 | 81 207377
81 207378:81 207378:324979 | 1.EG +0.00 | 81 207378
81 207381:81 207381:324995 | 1.EG +0.00 | 81 207381
81 207384:81 207384:325011 | 1.EG +0.00 | 81 207384
81 207385:81 207385:325027 | 1.EG +0.00 | 81 207385
81 207389:81 207389:325043 | 1.EG +0.00 | 81 207389
81 207390:81 207390:325059 | 1.EG +0.00 | 81 207390
81 207394:81 207394:325075 | 1.EG +0.00 | 81 207394
81 207400:81 207400:325091 | 1.EG +0.00 | 81 207400
81 207401:81 207401:325107 | 1.EG +0.00 | 81 207401
81 207416:81 207416:325123 | 1.EG +0.00 | 81 207416
81 207425:81 207425:325139 | 1.EG +0.00 | 81 207425
81 207429:81 207429:325155 | 1.EG +0.00 | 81 207429
81 207513:81 207513:325171 | 1.EG +0.00 | 81 207513

# IfcWall: 82 (4)
In: 1.EG +0.00
Type - Material: road_markirovka
Type - Pset_ProductRequirements - Category: Walls
Type - Pset_WallCommon - IsExternal: no
Pset_QuantityTakeOff - sets with these values: 2
Group: Model Group:River:478153
Name | Pset_QuantityTakeOff, Reference = Pset_WallCommon, Reference
82:82:295911 | 82
82 206546:82 206546:295991 | 82 206546
82 206818:82 206818:296647 | 82 206818
82 206820:82 206820:296663 | 82 206820

# IfcWall: 83 (5)
In: 1.EG +0.00
Type - Material: road_markirovka
Type - Pset_ProductRequirements - Category: Walls
Type - Pset_WallCommon - IsExternal: no
Pset_QuantityTakeOff - sets with these values: 2
Group: Model Group:River:478153
Name | Pset_QuantityTakeOff, Reference = Pset_WallCommon, Reference
83:83:288594 | 83
83 203187:83 203187:288790 | 83 203187
83 206532:83 206532:295879 | 83 206532
83 206577:83 206577:296119 | 83 206577
83 206807:83 206807:296567 | 83 206807

# IfcWall: 84 (6)
In: 1.EG +0.00
Type - Material: road_markirovka
Type - Pset_ProductRequirements - Category: Walls
Type - Pset_WallCommon - IsExternal: no
Pset_QuantityTakeOff - sets with these values: 2
Group: Model Group:River:478153
Name | Pset_QuantityTakeOff, Reference = Pset_WallCommon, Reference
84:84:288902 | 84
84 206525:84 206525:295831 | 84 206525
84 206530:84 206530:295863 | 84 206530
84 206562:84 206562:296087 | 84 206562
84 206727:84 206727:296551 | 84 206727
84 206824:84 206824:296695 | 84 206824

# IfcWall: 85 (5)
In: 1.EG +0.00
Type - Material: road_markirovka
Type - Pset_ProductRequirements - Category: Walls
Type - Pset_WallCommon - IsExternal: no
Pset_QuantityTakeOff - sets with these values: 2
Group: Model Group:River:478153
Name | Pset_QuantityTakeOff, Reference = Pset_WallCommon, Reference
85:85:295895 | 85
85 206566:85 206566:296103 | 85 206566
85 206599:85 206599:296151 | 85 206599
85 206701:85 206701:296487 | 85 206701
85 206813:85 206813:296599 | 85 206813

# IfcWall: 86 (6)
In: 1.EG +0.00
Type - Material: road_markirovka
Type - Pset_ProductRequirements - Category: Walls
Type - Pset_WallCommon - IsExternal: no
Pset_QuantityTakeOff - sets with these values: 2
Group: Model Group:River:478153
Name | Pset_QuantityTakeOff, Reference = Pset_WallCommon, Reference
86:86:288918 | 86
86 203221:86 203221:288934 | 86 203221
86 206523:86 206523:295815 | 86 206523
86 206553:86 206553:296055 | 86 206553
86 206606:86 206606:296167 | 86 206606
86 206708:86 206708:296535 | 86 206708

# IfcWall: 87 (5)
In: 1.EG +0.00
Type - Material: road_markirovka
Type - Pset_ProductRequirements - Category: Walls
Type - Pset_WallCommon - IsExternal: no
Pset_QuantityTakeOff - sets with these values: 2
Group: Model Group:River:478153
Name | Pset_QuantityTakeOff, Reference = Pset_WallCommon, Reference
87:87:288682 | 87
87 206443:87 206443:295607 | 87 206443
87 206522:87 206522:295799 | 87 206522
87 206704:87 206704:296519 | 87 206704
87 206816:87 206816:296631 | 87 206816

# IfcWall: 88 (3)
In: 1.EG +0.00
Type - Material: road_markirovka
Type - Pset_ProductRequirements - Category: Walls
Type - Pset_WallCommon - IsExternal: no
Pset_QuantityTakeOff - sets with these values: 2
Group: Model Group:River:478153
Name | Pset_QuantityTakeOff, Reference = Pset_WallCommon, Reference
88:88:295783 | 88
88 206699:88 206699:296471 | 88 206699
88 206703:88 206703:296503 | 88 206703

# IfcWall: 89 (2)
In: 1.EG +0.00
Type - Material: road_markirovka
Type - Pset_ProductRequirements - Category: Walls
Type - Pset_WallCommon - IsExternal: no
Pset_QuantityTakeOff - sets with these values: 2
Group: Model Group:River:478153
Name | Pset_QuantityTakeOff, Reference = Pset_WallCommon, Reference
89:89:295847 | 89
89 206692:89 206692:296407 | 89 206692

# IfcWall: 90 (3)
In: 1.EG +0.00
Type - Material: road_markirovka
Type - Pset_ProductRequirements - Category: Walls
Type - Pset_WallCommon - IsExternal: no
Pset_QuantityTakeOff - sets with these values: 2
Group: Model Group:River:478153
Name | Pset_QuantityTakeOff, Reference = Pset_WallCommon, Reference
90:90:295575 | 90
90 206516:90 206516:295751 | 90 206516
90 206693:90 206693:296423 | 90 206693

# IfcWall: 91 (3)
In: 1.EG +0.00
Type - Material: road_markirovka
Type - Pset_ProductRequirements - Category: Walls
Type - Pset_WallCommon - IsExternal: no
Pset_QuantityTakeOff - sets with these values: 2
Group: Model Group:River:478153
Name | Pset_QuantityTakeOff, Reference = Pset_WallCommon, Reference
91:91:295559 | 91
91 206513:91 206513:295735 | 91 206513
91 206697:91 206697:296455 | 91 206697

# IfcWall: 92 (3)
In: 1.EG +0.00
Type - Material: road_markirovka
Type - Pset_ProductRequirements - Category: Walls
Type - Pset_WallCommon - IsExternal: no
Pset_QuantityTakeOff - sets with these values: 2
Group: Model Group:River:478153
Name | Pset_QuantityTakeOff, Reference = Pset_WallCommon, Reference
92:92:295543 | 92
92 206510:92 206510:295719 | 92 206510
92 206694:92 206694:296439 | 92 206694

# IfcWall: 93 (3)
In: 1.EG +0.00
Type - Material: road_markirovka
Type - Pset_ProductRequirements - Category: Walls
Type - Pset_WallCommon - IsExternal: no
Pset_QuantityTakeOff - sets with these values: 2
Group: Model Group:River:478153
Name | Pset_QuantityTakeOff, Reference = Pset_WallCommon, Reference
93:93:295527 | 93
93 206517:93 206517:295767 | 93 206517
93 206689:93 206689:296391 | 93 206689

# IfcWall: 94 (4)
In: 1.EG +0.00
Type - Material: road_markirovka
Type - Pset_ProductRequirements - Category: Walls
Type - Pset_WallCommon - IsExternal: no
Pset_QuantityTakeOff - sets with these values: 2
Group: Model Group:River:478153
Name | Pset_QuantityTakeOff, Reference = Pset_WallCommon, Reference
94:94:295511 | 94
94 206508:94 206508:295687 | 94 206508
94 206662:94 206662:296343 | 94 206662
94 206686:94 206686:296375 | 94 206686

# IfcWall: 95 (3)
In: 1.EG +0.00
Type - Material: road_markirovka
Type - Pset_ProductRequirements - Category: Walls
Type - Pset_WallCommon - IsExternal: no
Pset_QuantityTakeOff - sets with these values: 2
Group: Model Group:River:478153
Name | Pset_QuantityTakeOff, Reference = Pset_WallCommon, Reference
95:95:295447 | 95
95 206509:95 206509:295703 | 95 206509
95 206659:95 206659:296311 | 95 206659

# IfcWall: 96 (5)
In: 1.EG +0.00
Type - Material: road_markirovka
Type - Pset_ProductRequirements - Category: Walls
Type - Pset_WallCommon - IsExternal: no
Pset_QuantityTakeOff - sets with these values: 2
Group: Model Group:River:478153
Name | Pset_QuantityTakeOff, Reference = Pset_WallCommon, Reference
96:96:295463 | 96
96 206502:96 206502:295655 | 96 206502
96 206655:96 206655:296279 | 96 206655
96 206656:96 206656:296295 | 96 206656
96 206660:96 206660:296327 | 96 206660

# IfcWall: 97 (3)
In: 1.EG +0.00
Type - Material: road_markirovka
Type - Pset_ProductRequirements - Category: Walls
Type - Pset_WallCommon - IsExternal: no
Pset_QuantityTakeOff - sets with these values: 2
Group: Model Group:River:478153
Name | Pset_QuantityTakeOff, Reference = Pset_WallCommon, Reference
97:97:295431 | 97
97 206506:97 206506:295671 | 97 206506
97 206814:97 206814:296615 | 97 206814

# IfcWall: 98 (3)
In: 1.EG +0.00
Type - Material: road_markirovka
Type - Pset_ProductRequirements - Category: Walls
Type - Pset_WallCommon - IsExternal: no
Pset_QuantityTakeOff - sets with these values: 2
Group: Model Group:River:478153
Name | Pset_QuantityTakeOff, Reference = Pset_WallCommon, Reference
98:98:295415 | 98
98 206450:98 206450:295639 | 98 206450
98 206652:98 206652:296263 | 98 206652

# IfcWall: 99 (3)
In: 1.EG +0.00
Type - Material: road_markirovka
Type - Pset_ProductRequirements - Category: Walls
Type - Pset_WallCommon - IsExternal: no
Pset_QuantityTakeOff - sets with these values: 2
Group: Model Group:River:478153
Name | Pset_QuantityTakeOff, Reference = Pset_WallCommon, Reference
99:99:295399 | 99
99 206446:99 206446:295623 | 99 206446
99 206651:99 206651:296247 | 99 206651

# IfcWall: Basic Wall:Wand_Aussen_30 (3)
Type - PredefinedType: STANDARD; Material: Analytical Wall Surface_CJC 300 mm
Type - Pset_ElementShading - Roughness: 914.4 mm
Type - Pset_ProductRequirements - Category: Walls
Type - Pset_WallCommon - IsExternal: yes
Pset_QuantityTakeOff - Reference: Wand_Aussen_30; sets with these values: 2
Pset_WallCommon - LoadBearing: no; ExtendToStructure: no; Reference: Wand_Aussen_30
Group: Model Group:Building:629362
Name (Basic Wall:Wand_Aussen_30:...) | In
621664 | 1.EG +0.00
621858 | 7.1OG KH +2.65
623070 | 0.UG -3.60

# IfcWall: Basic Wall:Wand_Aussen_35 (11)
Type - PredefinedType: STANDARD; Material: Analytical Wall Surface_CJC 350 mm
Type - Pset_ElementShading - Roughness: 914.4 mm
Type - Pset_ProductRequirements - Category: Walls
Type - Pset_WallCommon - IsExternal: yes
Pset_QuantityTakeOff - Reference: Wand_Aussen_35; sets with these values: 2
Pset_WallCommon - LoadBearing: no; ExtendToStructure: no; Reference: Wand_Aussen_35
Group: Model Group:Building:629362
Name (Basic Wall:Wand_Aussen_35:...) | In
617734 | 1.EG +0.00
617737 | 1.EG +0.00
618241 | 1.EG +0.00
618248 | 1.EG +0.00
619174 | 2.1OG +5.30
619871 | 3.2OG +10.60
620673 | 4.3OG +15.90
621665 | 1.EG +0.00
621860 | 7.1OG KH +2.65
622479 | 0.UG -3.60
623128 | 0.UG -3.60

# IfcWall: Basic Wall:Wand_Aussen_45 (4)
Type - PredefinedType: STANDARD; Material: Analytical Wall Surface_CJC 450 mm
Type - Pset_ElementShading - Roughness: 914.4 mm
Type - Pset_ProductRequirements - Category: Walls
Type - Pset_WallCommon - IsExternal: yes
Pset_QuantityTakeOff - Reference: Wand_Aussen_45; sets with these values: 2
Pset_WallCommon - LoadBearing: no; ExtendToStructure: no; Reference: Wand_Aussen_45
Group: Model Group:Building:629362
Name (Basic Wall:Wand_Aussen_45:...) | In
618249 | 1.EG +0.00
621863 | 7.1OG KH +2.65
622211 | 8.2OG KH +6.45
622306 | 9.3OG KH +10.25

# IfcWall: Basic Wall:Wand_Innen_12.5 (2)
In: 0.UG -3.60
Type - PredefinedType: STANDARD; Material: Analytical Wall Surface_CJC 125 mm
Type - Pset_ElementShading - Roughness: 914.4 mm
Type - Pset_ProductRequirements - Category: Walls
Type - Pset_WallCommon - IsExternal: no
Pset_QuantityTakeOff - Reference: Wand_Innen_12.5; sets with these values: 2
Pset_WallCommon - LoadBearing: no; ExtendToStructure: no; Reference: Wand_Innen_12.5
Group: Model Group:Building:629362
Name (Basic Wall:Wand_Innen_12.5:...)
623055
623056

# IfcWall: Basic Wall:Wand_Innen_15 (10)
Type - PredefinedType: STANDARD; Material: Analytical Wall Surface_CJC 150 mm
Type - Pset_ElementShading - Roughness: 914.4 mm
Type - Pset_ProductRequirements - Category: Walls
Type - Pset_WallCommon - IsExternal: no
Pset_QuantityTakeOff - Reference: Wand_Innen_15; sets with these values: 2
Pset_WallCommon - LoadBearing: no; ExtendToStructure: no; Reference: Wand_Innen_15
Group: Model Group:Building:629362
Name (Basic Wall:Wand_Innen_15:...) | In
618196 | 1.EG +0.00
619154 | 2.1OG +5.30
619155 | 2.1OG +5.30
619625 | 2.1OG +5.30
619851 | 3.2OG +10.60
619852 | 3.2OG +10.60
620775 | 4.3OG +15.90
620776 | 4.3OG +15.90
621554 | 4.3OG +15.90
627525 | 2.1OG +5.30

# IfcWall: Basic Wall:Wand_Innen_17.5, Basic Wall:Wand_Innen_17.5:621887
In: 7.1OG KH +2.65
Type - PredefinedType: STANDARD; Material: Analytical Wall Surface_CJC 175 mm
Type - Pset_ElementShading - Roughness: 914.4 mm
Type - Pset_ProductRequirements - Category: Walls
Type - Pset_WallCommon - IsExternal: no
Pset_QuantityTakeOff - Reference: Wand_Innen_17.5; sets with these values: 2
Pset_WallCommon - LoadBearing: no; ExtendToStructure: no; Reference: Wand_Innen_17.5
Group: Model Group:Building:629362

# IfcWall: Basic Wall:Wand_Innen_20 (2)
In: 1.EG +0.00
Type - PredefinedType: STANDARD; Material: Analytical Wall Surface_CJC 200 mm
Type - Pset_ElementShading - Roughness: 914.4 mm
Type - Pset_ProductRequirements - Category: Walls
Type - Pset_WallCommon - IsExternal: no
Pset_QuantityTakeOff - Reference: Wand_Innen_20; sets with these values: 2
Pset_WallCommon - LoadBearing: no; ExtendToStructure: no; Reference: Wand_Innen_20
Group: Model Group:Building:629362
Name (Basic Wall:Wand_Innen_20:...)
621691
621692

# IfcWall: Basic Wall:Wand_Innen_30 (50)
Type - PredefinedType: STANDARD; Material: Analytical Wall Surface_CJC 300 mm
Type - Pset_ElementShading - Roughness: 914.4 mm
Type - Pset_ProductRequirements - Category: Walls
Type - Pset_WallCommon - IsExternal: no
Pset_QuantityTakeOff - Reference: Wand_Innen_30; sets with these values: 2
Pset_WallCommon - LoadBearing: no; ExtendToStructure: no; Reference: Wand_Innen_30
Group: Model Group:Building:629362
Name (Basic Wall:Wand_Innen_30:...) | In
617738 | 1.EG +0.00
617832 | 1.EG +0.00
617946 | 1.EG +0.00
618126 | 1.EG +0.00
618133 | 1.EG +0.00
618142 | 1.EG +0.00
618143 | 1.EG +0.00
618172 | 1.EG +0.00
618193 | 1.EG +0.00
618251 | 1.EG +0.00
618261 | 1.EG +0.00
618262 | 1.EG +0.00
618623 | 1.EG +0.00
619152 | 2.1OG +5.30
619512 | 2.1OG +5.30
619523 | 2.1OG +5.30
619597 | 2.1OG +5.30
619849 | 3.2OG +10.60
620039 | 3.2OG +10.60
620171 | 3.2OG +10.60
620226 | 3.2OG +10.60
620253 | 3.2OG +10.60
620717 | 4.3OG +15.90
620746 | 4.3OG +15.90
620773 | 4.3OG +15.90
620951 | 4.3OG +15.90
621081 | 4.3OG +15.90
621134 | 4.3OG +15.90
621679 | 1.EG +0.00
621682 | 1.EG +0.00
621696 | 1.EG +0.00
621700 | 1.EG +0.00
621893 | 7.1OG KH +2.65
622225 | 8.2OG KH +6.45
622237 | 8.2OG KH +6.45
622330 | 9.3OG KH +10.25
622502 | 0.UG -3.60
622517 | 0.UG -3.60
622573 | 0.UG -3.60
622580 | 0.UG -3.60
622838 | 0.UG -3.60
622909 | 0.UG -3.60
622927 | 0.UG -3.60
622928 | 0.UG -3.60
622929 | 0.UG -3.60
623037 | 0.UG -3.60
623038 | 0.UG -3.60
623040 | 0.UG -3.60
623127 | 0.UG -3.60
627523 | 2.1OG +5.30

# IfcWall: Basic Wall:Wand_Innen_35 (93)
Type - PredefinedType: STANDARD; Material: Analytical Wall Surface_CJC 350 mm
Type - Pset_ElementShading - Roughness: 914.4 mm
Type - Pset_ProductRequirements - Category: Walls
Type - Pset_WallCommon - IsExternal: no
Pset_QuantityTakeOff - Reference: Wand_Innen_35; sets with these values: 2
Pset_WallCommon - LoadBearing: no; ExtendToStructure: no; Reference: Wand_Innen_35
Group: Model Group:Building:629362
Name (Basic Wall:Wand_Innen_35:...) | In
617842 | 1.EG +0.00
617857 | 1.EG +0.00
617872 | 1.EG +0.00
617887 | 1.EG +0.00
617905 | 1.EG +0.00
617923 | 1.EG +0.00
617958 | 1.EG +0.00
617971 | 1.EG +0.00
618028 | 1.EG +0.00
618044 | 1.EG +0.00
618060 | 1.EG +0.00
618075 | 1.EG +0.00
618091 | 1.EG +0.00
618144 | 1.EG +0.00
618178 | 1.EG +0.00
618200 | 1.EG +0.00
618626 | 1.EG +0.00
618865 | 2.1OG +5.30
618879 | 2.1OG +5.30
618893 | 2.1OG +5.30
618907 | 2.1OG +5.30
618922 | 2.1OG +5.30
618936 | 2.1OG +5.30
618962 | 2.1OG +5.30
618975 | 2.1OG +5.30
619015 | 2.1OG +5.30
619029 | 2.1OG +5.30
619041 | 2.1OG +5.30
619057 | 2.1OG +5.30
619072 | 2.1OG +5.30
619088 | 2.1OG +5.30
619126 | 2.1OG +5.30
619137 | 2.1OG +5.30
619345 | 2.1OG +5.30
619433 | 2.1OG +5.30
619447 | 2.1OG +5.30
619461 | 2.1OG +5.30
619766 | 3.2OG +10.60
619823 | 3.2OG +10.60
619834 | 3.2OG +10.60
620041 | 3.2OG +10.60
620101 | 3.2OG +10.60
620115 | 3.2OG +10.60
620129 | 3.2OG +10.60
620425 | 3.2OG +10.60
620439 | 3.2OG +10.60
620453 | 3.2OG +10.60
620482 | 3.2OG +10.60
620496 | 3.2OG +10.60
620510 | 3.2OG +10.60
620524 | 3.2OG +10.60
620538 | 3.2OG +10.60
620552 | 3.2OG +10.60
620566 | 3.2OG +10.60
620580 | 3.2OG +10.60
620632 | 3.2OG +10.60
620646 | 3.2OG +10.60
620704 | 4.3OG +15.90
620758 | 4.3OG +15.90
620953 | 4.3OG +15.90
621011 | 4.3OG +15.90
621025 | 4.3OG +15.90
621039 | 4.3OG +15.90
621198 | 4.3OG +15.90
621326 | 4.3OG +15.90
621354 | 4.3OG +15.90
621368 | 4.3OG +15.90
621382 | 4.3OG +15.90
621396 | 4.3OG +15.90
621410 | 4.3OG +15.90
621424 | 4.3OG +15.90
621438 | 4.3OG +15.90
621452 | 4.3OG +15.90
621468 | 4.3OG +15.90
621482 | 4.3OG +15.90
621690 | 1.EG +0.00
622583 | 0.UG -3.60
622604 | 0.UG -3.60
622625 | 0.UG -3.60
622643 | 0.UG -3.60
622664 | 0.UG -3.60
622685 | 0.UG -3.60
622700 | 0.UG -3.60
622718 | 0.UG -3.60
622754 | 0.UG -3.60
622772 | 0.UG -3.60
622790 | 0.UG -3.60
622808 | 0.UG -3.60
622931 | 0.UG -3.60
622932 | 0.UG -3.60
622970 | 0.UG -3.60
622992 | 0.UG -3.60
627792 | 2.1OG +5.30

# IfcWall: Basic Wall:Wand_Innen_42.5 (3)
Type - PredefinedType: STANDARD; Material: Analytical Wall Surface_CJC 425 mm
Type - Pset_ElementShading - Roughness: 914.4 mm
Type - Pset_ProductRequirements - Category: Walls
Type - Pset_WallCommon - IsExternal: no
Pset_QuantityTakeOff - Reference: Wand_Innen_42.5; sets with these values: 2
Pset_WallCommon - LoadBearing: no; ExtendToStructure: no; Reference: Wand_Innen_42.5
Group: Model Group:Building:629362
Name (Basic Wall:Wand_Innen_42.5:...) | In
621678 | 1.EG +0.00
622492 | 0.UG -3.60
622501 | 0.UG -3.60

# IfcWall: Basic Wall:Wand_Innen_47.5, Basic Wall:Wand_Innen_47.5:620252
In: 3.2OG +10.60
Type - PredefinedType: STANDARD; Material: Analytical Wall Surface_CJC 475 mm
Type - Pset_ElementShading - Roughness: 914.4 mm
Type - Pset_ProductRequirements - Category: Walls
Type - Pset_WallCommon - IsExternal: no
Pset_QuantityTakeOff - Reference: Wand_Innen_47.5; sets with these values: 2
Pset_WallCommon - LoadBearing: no; ExtendToStructure: no; Reference: Wand_Innen_47.5
Group: Model Group:Building:629362

# IfcWall: Basic Wall:Wand_Innen_5 (4)
Type - PredefinedType: STANDARD; Material: Analytical Wall Surface_CJC 50 mm
Type - Pset_ElementShading - Roughness: 914.4 mm
Type - Pset_ProductRequirements - Category: Walls
Type - Pset_WallCommon - IsExternal: no
Pset_QuantityTakeOff - Reference: Wand_Innen_5; sets with these values: 2
Pset_WallCommon - LoadBearing: no; ExtendToStructure: no; Reference: Wand_Innen_5
Group: Model Group:Building:629362
Name (Basic Wall:Wand_Innen_5:...) | In
621566 | 4.3OG +15.90
626031 | 4.3OG +15.90
627469 | 2.1OG +5.30
627470 | 2.1OG +5.30

# IfcWall: Basic Wall:Wand_Innen_50 (2)
Type - PredefinedType: STANDARD; Material: Analytical Wall Surface_CJC 500 mm
Type - Pset_ElementShading - Roughness: 914.4 mm
Type - Pset_ProductRequirements - Category: Walls
Type - Pset_WallCommon - IsExternal: no
Pset_QuantityTakeOff - Reference: Wand_Innen_50; sets with these values: 2
Pset_WallCommon - LoadBearing: no; ExtendToStructure: no; Reference: Wand_Innen_50
Group: Model Group:Building:629362
Name (Basic Wall:Wand_Innen_50:...) | In
619185 | 2.1OG +5.30
619882 | 3.2OG +10.60

# IfcWall: Basic Wall:Wand_Innen_55 (4)
In: 0.UG -3.60
Type - PredefinedType: STANDARD; Material: Analytical Wall Surface_CJC 550 mm
Type - Pset_ElementShading - Roughness: 914.4 mm
Type - Pset_ProductRequirements - Category: Walls
Type - Pset_WallCommon - IsExternal: no
Pset_QuantityTakeOff - Reference: Wand_Innen_55; sets with these values: 2
Pset_WallCommon - LoadBearing: no; ExtendToStructure: no; Reference: Wand_Innen_55
Group: Model Group:Building:629362
Name (Basic Wall:Wand_Innen_55:...)
622736
623881
623883
623884

# IfcWall: Basic Wall:Wand_Innen_63, Basic Wall:Wand_Innen_63:620804
In: 4.3OG +15.90
Type - PredefinedType: STANDARD; Material: Analytical Wall Surface_CJC 630 mm
Type - Pset_ElementShading - Roughness: 914.4 mm
Type - Pset_ProductRequirements - Category: Walls
Type - Pset_WallCommon - IsExternal: no
Pset_QuantityTakeOff - Reference: Wand_Innen_63; sets with these values: 2
Pset_WallCommon - LoadBearing: no; ExtendToStructure: no; Reference: Wand_Innen_63
Group: Model Group:Building:629362

# IfcWall: Basic Wall:Wand_Innen_65 (8)
Type - PredefinedType: STANDARD; Material: Analytical Wall Surface_CJC 650 mm
Type - Pset_ElementShading - Roughness: 914.4 mm
Type - Pset_ProductRequirements - Category: Walls
Type - Pset_WallCommon - IsExternal: no
Pset_QuantityTakeOff - Reference: Wand_Innen_65; sets with these values: 2
Pset_WallCommon - LoadBearing: no; ExtendToStructure: no; Reference: Wand_Innen_65
Group: Model Group:Building:629362
Name (Basic Wall:Wand_Innen_65:...) | In
618107 | 1.EG +0.00
618260 | 1.EG +0.00
619103 | 2.1OG +5.30
619805 | 3.2OG +10.60
620730 | 4.3OG +15.90
622830 | 0.UG -3.60
622852 | 0.UG -3.60
622873 | 0.UG -3.60

# IfcWallStandardCase: Basic Wall:05 (22)
In: PLAN
Type - PredefinedType: STANDARD; Material: LS-Leaves Shrub 500 mm
Type - Pset_ElementShading - Roughness: 304.8 mm
Type - Pset_ProductRequirements - Category: Walls
Type - Pset_WallCommon - IsExternal: yes
Pset_QuantityTakeOff - Reference: 05; sets with these values: 2
Pset_WallCommon - Reference: 05; LoadBearing: no; ExtendToStructure: no
Group: Model Group:River:478153
Name
8 x 05
2 x 08
10 x 07
2 x 06

# IfcWallStandardCase: Basic Wall:06 (32)
In: PLAN
Type - PredefinedType: STANDARD; Material: LS-Leaves Shrub 1000 mm
Type - Pset_ElementShading - Roughness: 304.8 mm
Type - Pset_ProductRequirements - Category: Walls
Type - Pset_WallCommon - IsExternal: yes
Pset_QuantityTakeOff - Reference: 06; sets with these values: 2
Pset_WallCommon - Reference: 06; LoadBearing: no; ExtendToStructure: no
Group: Model Group:River:478153
Name
4 x 06
6 x 08
19 x 07
11
12
13

# IfcWallStandardCase: Basic Wall:07 (3)
In: PLAN
Type - PredefinedType: STANDARD; Material: LS-Leaves Shrub 2000 mm
Type - Pset_ElementShading - Roughness: 304.8 mm
Type - Pset_ProductRequirements - Category: Walls
Type - Pset_WallCommon - IsExternal: yes
Pset_QuantityTakeOff - Reference: 07; sets with these values: 2
Pset_WallCommon - Reference: 07; LoadBearing: no; ExtendToStructure: no
Group: Model Group:River:478153

# IfcWallStandardCase: Basic Wall:07:1028, 07
In: 3D
Type - PredefinedType: STANDARD; Material: Surf-Poured Concrete 250 mm
Type - Pset_ElementShading - Roughness: 304.8 mm
Type - Pset_ProductRequirements - Category: Walls
Type - Pset_WallCommon - IsExternal: yes
Pset_QuantityTakeOff - Reference: 07:1028; sets with these values: 2
Pset_WallCommon - LoadBearing: no; ExtendToStructure: no; Reference: 07:1028
Group: Model Group:River:478153

# IfcWallStandardCase: Basic Wall:07:1034 (3)
In: 3D
Type - PredefinedType: STANDARD; Material: Paint-01 800 mm
Type - Pset_ElementShading - Roughness: 304.8 mm
Type - Pset_ProductRequirements - Category: Walls
Type - Pset_WallCommon - IsExternal: yes
Pset_QuantityTakeOff - Reference: 07:1034; sets with these values: 2
Pset_WallCommon - LoadBearing: no; ExtendToStructure: no; Reference: 07:1034
Group: Model Group:River:478153

# IfcWallStandardCase: Basic Wall:07:1375 (2)
In: PLAN
Type - PredefinedType: STANDARD; Material: LS-Leaves Shrub 1000.01 mm
Type - Pset_ElementShading - Roughness: 304.8 mm
Type - Pset_ProductRequirements - Category: Walls
Type - Pset_WallCommon - IsExternal: yes
Pset_QuantityTakeOff - Reference: 07:1375; sets with these values: 2
Pset_WallCommon - LoadBearing: no; ExtendToStructure: no; Reference: 07:1375
Group: Model Group:River:478153

# IfcWallStandardCase: Basic Wall:83 (4)
In: 3D
Type - PredefinedType: STANDARD; Material: Paint-01 200 mm
Type - Pset_ElementShading - Roughness: 304.8 mm
Type - Pset_ProductRequirements - Category: Walls
Type - Pset_WallCommon - IsExternal: yes
Pset_QuantityTakeOff - Reference: 83; sets with these values: 2
Pset_WallCommon - Reference: 83; LoadBearing: no; ExtendToStructure: no
Group: Model Group:River:478153
Name
80
79
77
78

# IfcWallStandardCase: Basic Wall:Wand_Aussen_15 (3)
Type - PredefinedType: STANDARD; Material: Analytical Wall Surface_CJC 150 mm
Type - Pset_ElementShading - Roughness: 914.4 mm
Type - Pset_ProductRequirements - Category: Walls
Type - Pset_WallCommon - IsExternal: yes
Pset_QuantityTakeOff - Reference: Wand_Aussen_15; sets with these values: 2
Pset_WallCommon - LoadBearing: no; ExtendToStructure: no; Reference: Wand_Aussen_15
Group: Model Group:Building:629362
Name (Basic Wall:Wand_Aussen_15:...) | In
621835 | 6.EG KH -1.15
621836 | 6.EG KH -1.15
624167 | 4.3OG +15.90

# IfcWallStandardCase: Basic Wall:Wand_Aussen_20 (12)
Type - PredefinedType: STANDARD; Material: Analytical Wall Surface_CJC 200 mm
Type - Pset_ElementShading - Roughness: 914.4 mm
Type - Pset_ProductRequirements - Category: Walls
Type - Pset_WallCommon - IsExternal: yes
Pset_QuantityTakeOff - Reference: Wand_Aussen_20; sets with these values: 2
Pset_WallCommon - LoadBearing: no; ExtendToStructure: no; Reference: Wand_Aussen_20
Group: Model Group:Building:629362
Name (Basic Wall:Wand_Aussen_20:...) | In
618351 | 1.EG +0.00
619250 | 2.1OG +5.30
619521 | 2.1OG +5.30
619947 | 3.2OG +10.60
620169 | 3.2OG +10.60
620870 | 4.3OG +15.90
621079 | 4.3OG +15.90
624107 | 5.DG +21.50
624108 | 5.DG +21.50
624109 | 5.DG +21.50
624110 | 5.DG +21.50
624111 | 5.DG +21.50

# IfcWallStandardCase: Basic Wall:Wand_Aussen_30 (46)
Type - PredefinedType: STANDARD; Material: Analytical Wall Surface_CJC 300 mm
Type - Pset_ElementShading - Roughness: 914.4 mm
Type - Pset_ProductRequirements - Category: Walls
Type - Pset_WallCommon - IsExternal: yes
Pset_QuantityTakeOff - Reference: Wand_Aussen_30; sets with these values: 2
Pset_WallCommon - LoadBearing: no; ExtendToStructure: no; Reference: Wand_Aussen_30
Group: Model Group:Building:629362
Name (Basic Wall:Wand_Aussen_30:...) | In
621587 | 5.DG +21.50
621588 | 5.DG +21.50
621589 | 5.DG +21.50
621666 | 1.EG +0.00
621670 | 1.EG +0.00
621676 | 1.EG +0.00
621861 | 7.1OG KH +2.65
621865 | 7.1OG KH +2.65
622209 | 8.2OG KH +6.45
622213 | 8.2OG KH +6.45
622304 | 9.3OG KH +10.25
622308 | 9.3OG KH +10.25
622482 | 0.UG -3.60
622483 | 0.UG -3.60
622484 | 0.UG -3.60
622485 | 0.UG -3.60
622486 | 0.UG -3.60
622487 | 0.UG -3.60
622488 | 0.UG -3.60
622489 | 0.UG -3.60
622490 | 0.UG -3.60
623068 | 0.UG -3.60
623069 | 0.UG -3.60
623071 | 0.UG -3.60
623072 | 0.UG -3.60
623073 | 0.UG -3.60
623078 | 0.UG -3.60
623079 | 0.UG -3.60
623080 | 0.UG -3.60
623081 | 0.UG -3.60
623082 | 0.UG -3.60
623083 | 0.UG -3.60
623084 | 0.UG -3.60
623085 | 0.UG -3.60
623086 | 0.UG -3.60
623087 | 0.UG -3.60
623088 | 0.UG -3.60
624013 | 0.UG -3.60
624014 | 0.UG -3.60
624015 | 0.UG -3.60
624016 | 0.UG -3.60
624017 | 0.UG -3.60
624018 | 0.UG -3.60
624019 | 0.UG -3.60
624020 | 0.UG -3.60
624021 | 0.UG -3.60

# IfcWallStandardCase: Basic Wall:Wand_Aussen_35 (50)
Type - PredefinedType: STANDARD; Material: Analytical Wall Surface_CJC 350 mm
Type - Pset_ElementShading - Roughness: 914.4 mm
Type - Pset_ProductRequirements - Category: Walls
Type - Pset_WallCommon - IsExternal: yes
Pset_QuantityTakeOff - Reference: Wand_Aussen_35; sets with these values: 2
Pset_WallCommon - LoadBearing: no; ExtendToStructure: no; Reference: Wand_Aussen_35
Group: Model Group:Building:629362
Name (Basic Wall:Wand_Aussen_35:...) | In
617731 | 1.EG +0.00
617732 | 1.EG +0.00
617735 | 1.EG +0.00
617736 | 1.EG +0.00
618240 | 1.EG +0.00
618352 | 1.EG +0.00
618354 | 1.EG +0.00
618651 | 1.EG +0.00
618791 | 2.1OG +5.30
618792 | 2.1OG +5.30
618794 | 2.1OG +5.30
618795 | 2.1OG +5.30
618796 | 2.1OG +5.30
618797 | 2.1OG +5.30
619177 | 2.1OG +5.30
619251 | 2.1OG +5.30
619252 | 2.1OG +5.30
619520 | 2.1OG +5.30
619732 | 3.2OG +10.60
619733 | 3.2OG +10.60
619735 | 3.2OG +10.60
619736 | 3.2OG +10.60
619737 | 3.2OG +10.60
619738 | 3.2OG +10.60
619874 | 3.2OG +10.60
619948 | 3.2OG +10.60
619949 | 3.2OG +10.60
620168 | 3.2OG +10.60
620670 | 4.3OG +15.90
620671 | 4.3OG +15.90
620674 | 4.3OG +15.90
620675 | 4.3OG +15.90
620676 | 4.3OG +15.90
620795 | 4.3OG +15.90
620798 | 4.3OG +15.90
620871 | 4.3OG +15.90
620872 | 4.3OG +15.90
621078 | 4.3OG +15.90
621631 | 5.DG +21.50
621632 | 5.DG +21.50
621633 | 5.DG +21.50
621634 | 5.DG +21.50
621635 | 5.DG +21.50
621866 | 7.1OG KH +2.65
622208 | 8.2OG KH +6.45
622303 | 9.3OG KH +10.25
622473 | 0.UG -3.60
622475 | 0.UG -3.60
622907 | 0.UG -3.60
623129 | 0.UG -3.60

# IfcWallStandardCase: Basic Wall:Wand_Aussen_40 (7)
Type - PredefinedType: STANDARD; Material: Analytical Wall Surface_CJC 400 mm
Type - Pset_ElementShading - Roughness: 914.4 mm
Type - Pset_ProductRequirements - Category: Walls
Type - Pset_WallCommon - IsExternal: yes
Pset_QuantityTakeOff - Reference: Wand_Aussen_40; sets with these values: 2
Pset_WallCommon - LoadBearing: no; ExtendToStructure: no; Reference: Wand_Aussen_40
Group: Model Group:Building:629362
Name (Basic Wall:Wand_Aussen_40:...) | In
621667 | 1.EG +0.00
622210 | 8.2OG KH +6.45
622305 | 9.3OG KH +10.25
624103 | 5.DG +21.50
624104 | 5.DG +21.50
624105 | 5.DG +21.50
624106 | 5.DG +21.50

# IfcWallStandardCase: Basic Wall:Wand_Aussen_43.75, Basic Wall:Wand_Aussen_43.75:621862
In: 7.1OG KH +2.65
Type - PredefinedType: STANDARD; Material: Analytical Wall Surface_CJC 437.5 mm
Type - Pset_ElementShading - Roughness: 914.4 mm
Type - Pset_ProductRequirements - Category: Walls
Type - Pset_WallCommon - IsExternal: yes
Pset_QuantityTakeOff - Reference: Wand_Aussen_43.75; sets with these values: 2
Pset_WallCommon - LoadBearing: no; ExtendToStructure: no; Reference: Wand_Aussen_43.75
Group: Model Group:Building:629362

# IfcWallStandardCase: Basic Wall:Wand_Aussen_45 (20)
Type - PredefinedType: STANDARD; Material: Analytical Wall Surface_CJC 450 mm
Type - Pset_ElementShading - Roughness: 914.4 mm
Type - Pset_ProductRequirements - Category: Walls
Type - Pset_WallCommon - IsExternal: yes
Pset_QuantityTakeOff - Reference: Wand_Aussen_45; sets with these values: 2
Pset_WallCommon - LoadBearing: no; ExtendToStructure: no; Reference: Wand_Aussen_45
Group: Model Group:Building:629362
Name (Basic Wall:Wand_Aussen_45:...) | In
617733 | 1.EG +0.00
618242 | 1.EG +0.00
618243 | 1.EG +0.00
618793 | 2.1OG +5.30
619175 | 2.1OG +5.30
619178 | 2.1OG +5.30
619734 | 3.2OG +10.60
619872 | 3.2OG +10.60
619875 | 3.2OG +10.60
620672 | 4.3OG +15.90
620796 | 4.3OG +15.90
620799 | 4.3OG +15.90
621668 | 1.EG +0.00
621669 | 1.EG +0.00
621671 | 1.EG +0.00
621675 | 1.EG +0.00
621864 | 7.1OG KH +2.65
622120 | 6.EG KH -1.15
622212 | 8.2OG KH +6.45
622307 | 9.3OG KH +10.25

# IfcWallStandardCase: Basic Wall:Wand_Aussen_50 (13)
Type - PredefinedType: STANDARD; Material: Analytical Wall Surface_CJC 500 mm
Type - Pset_ElementShading - Roughness: 914.4 mm
Type - Pset_ProductRequirements - Category: Walls
Type - Pset_WallCommon - IsExternal: yes
Pset_QuantityTakeOff - Reference: Wand_Aussen_50; sets with these values: 2
Pset_WallCommon - LoadBearing: no; ExtendToStructure: no; Reference: Wand_Aussen_50
Group: Model Group:Building:629362
Name (Basic Wall:Wand_Aussen_50:...) | In
618353 | 1.EG +0.00
622471 | 0.UG -3.60
622474 | 0.UG -3.60
622476 | 0.UG -3.60
622477 | 0.UG -3.60
622478 | 0.UG -3.60
622480 | 0.UG -3.60
622481 | 0.UG -3.60
622906 | 0.UG -3.60
623045 | 0.UG -3.60
623048 | 0.UG -3.60
624064 | 1.EG +0.00
624065 | 1.EG +0.00

# IfcWallStandardCase: Basic Wall:Wand_Aussen_52.5, Basic Wall:Wand_Aussen_52.5:621672
In: 1.EG +0.00
Type - PredefinedType: STANDARD; Material: Analytical Wall Surface_CJC 525 mm
Type - Pset_ElementShading - Roughness: 914.4 mm
Type - Pset_ProductRequirements - Category: Walls
Type - Pset_WallCommon - IsExternal: yes
Pset_QuantityTakeOff - Reference: Wand_Aussen_52.5; sets with these values: 2
Pset_WallCommon - LoadBearing: no; ExtendToStructure: no; Reference: Wand_Aussen_52.5
Group: Model Group:Building:629362

# IfcWallStandardCase: Basic Wall:Wand_Aussen_55 (4)
In: 0.UG -3.60
Type - PredefinedType: STANDARD; Material: Analytical Wall Surface_CJC 550 mm
Type - Pset_ElementShading - Roughness: 914.4 mm
Type - Pset_ProductRequirements - Category: Walls
Type - Pset_WallCommon - IsExternal: yes
Pset_QuantityTakeOff - Reference: Wand_Aussen_55; sets with these values: 2
Pset_WallCommon - LoadBearing: no; ExtendToStructure: no; Reference: Wand_Aussen_55
Group: Model Group:Building:629362
Name (Basic Wall:Wand_Aussen_55:...)
623877
623878
623879
623880

# IfcWallStandardCase: Basic Wall:Wand_Aussen_75, Basic Wall:Wand_Aussen_75:621674
In: 1.EG +0.00
Type - PredefinedType: STANDARD; Material: Analytical Wall Surface_CJC 750 mm
Type - Pset_ElementShading - Roughness: 914.4 mm
Type - Pset_ProductRequirements - Category: Walls
Type - Pset_WallCommon - IsExternal: yes
Pset_QuantityTakeOff - Reference: Wand_Aussen_75; sets with these values: 2
Pset_WallCommon - LoadBearing: no; ExtendToStructure: no; Reference: Wand_Aussen_75
Group: Model Group:Building:629362

# IfcWallStandardCase: Basic Wall:Wand_Aussen_82.5, Basic Wall:Wand_Aussen_82.5:621673
In: 1.EG +0.00
Type - PredefinedType: STANDARD; Material: Analytical Wall Surface_CJC 825 mm
Type - Pset_ElementShading - Roughness: 914.4 mm
Type - Pset_ProductRequirements - Category: Walls
Type - Pset_WallCommon - IsExternal: yes
Pset_QuantityTakeOff - Reference: Wand_Aussen_82.5; sets with these values: 2
Pset_WallCommon - LoadBearing: no; ExtendToStructure: no; Reference: Wand_Aussen_82.5
Group: Model Group:Building:629362

# IfcWallStandardCase: Basic Wall:Wand_Innen_12.5 (5)
In: 0.UG -3.60
Type - PredefinedType: STANDARD; Material: Analytical Wall Surface_CJC 125 mm
Type - Pset_ElementShading - Roughness: 914.4 mm
Type - Pset_ProductRequirements - Category: Walls
Type - Pset_WallCommon - IsExternal: no
Pset_QuantityTakeOff - Reference: Wand_Innen_12.5; sets with these values: 2
Pset_WallCommon - LoadBearing: no; ExtendToStructure: no; Reference: Wand_Innen_12.5
Group: Model Group:Building:629362
Name (Basic Wall:Wand_Innen_12.5:...)
622511
622513
622837
623057
623058

# IfcWallStandardCase: Basic Wall:Wand_Innen_13 (3)
In: 0.UG -3.60
Type - PredefinedType: STANDARD; Material: Analytical Wall Surface_CJC 130 mm
Type - Pset_ElementShading - Roughness: 914.4 mm
Type - Pset_ProductRequirements - Category: Walls
Type - Pset_WallCommon - IsExternal: no
Pset_QuantityTakeOff - Reference: Wand_Innen_13; sets with these values: 2
Pset_WallCommon - LoadBearing: no; ExtendToStructure: no; Reference: Wand_Innen_13
Group: Model Group:Building:629362
Name (Basic Wall:Wand_Innen_13:...)
622509
622510
622512

# IfcWallStandardCase: Basic Wall:Wand_Innen_15 (20)
Type - PredefinedType: STANDARD; Material: Analytical Wall Surface_CJC 150 mm
Type - Pset_ElementShading - Roughness: 914.4 mm
Type - Pset_ProductRequirements - Category: Walls
Type - Pset_WallCommon - IsExternal: no
Pset_QuantityTakeOff - Reference: Wand_Innen_15; sets with these values: 2
Pset_WallCommon - LoadBearing: no; ExtendToStructure: no; Reference: Wand_Innen_15
Group: Model Group:Building:629362
Name (Basic Wall:Wand_Innen_15:...) | In
618194 | 1.EG +0.00
618195 | 1.EG +0.00
619153 | 2.1OG +5.30
619513 | 2.1OG +5.30
619515 | 2.1OG +5.30
619850 | 3.2OG +10.60
620774 | 4.3OG +15.90
621536 | 4.3OG +15.90
621558 | 4.3OG +15.90
621559 | 4.3OG +15.90
621560 | 4.3OG +15.90
621561 | 4.3OG +15.90
621564 | 4.3OG +15.90
621565 | 4.3OG +15.90
625639 | 4.3OG +15.90
625640 | 4.3OG +15.90
627819 | 3.2OG +10.60
627820 | 3.2OG +10.60
627840 | 2.1OG +5.30
627841 | 2.1OG +5.30

# IfcWallStandardCase: Basic Wall:Wand_Innen_17.5 (6)
Type - PredefinedType: STANDARD; Material: Analytical Wall Surface_CJC 175 mm
Type - Pset_ElementShading - Roughness: 914.4 mm
Type - Pset_ProductRequirements - Category: Walls
Type - Pset_WallCommon - IsExternal: no
Pset_QuantityTakeOff - Reference: Wand_Innen_17.5; sets with these values: 2
Pset_WallCommon - LoadBearing: no; ExtendToStructure: no; Reference: Wand_Innen_17.5
Group: Model Group:Building:629362
Name (Basic Wall:Wand_Innen_17.5:...) | In
621684 | 1.EG +0.00
621685 | 1.EG +0.00
621694 | 1.EG +0.00
621884 | 7.1OG KH +2.65
622229 | 8.2OG KH +6.45
622230 | 8.2OG KH +6.45

# IfcWallStandardCase: Basic Wall:Wand_Innen_18, Basic Wall:Wand_Innen_18:621683
In: 1.EG +0.00
Type - PredefinedType: STANDARD; Material: Analytical Wall Surface_CJC 180 mm
Type - Pset_ElementShading - Roughness: 914.4 mm
Type - Pset_ProductRequirements - Category: Walls
Type - Pset_WallCommon - IsExternal: no
Pset_QuantityTakeOff - Reference: Wand_Innen_18; sets with these values: 2
Pset_WallCommon - LoadBearing: no; ExtendToStructure: no; Reference: Wand_Innen_18
Group: Model Group:Building:629362

# IfcWallStandardCase: Basic Wall:Wand_Innen_20 (14)
Type - PredefinedType: STANDARD; Material: Analytical Wall Surface_CJC 200 mm
Type - Pset_ElementShading - Roughness: 914.4 mm
Type - Pset_ProductRequirements - Category: Walls
Type - Pset_WallCommon - IsExternal: no
Pset_QuantityTakeOff - Reference: Wand_Innen_20; sets with these values: 2
Pset_WallCommon - LoadBearing: no; ExtendToStructure: no; Reference: Wand_Innen_20
Group: Model Group:Building:629362
Name (Basic Wall:Wand_Innen_20:...) | In
618244 | 1.EG +0.00
618246 | 1.EG +0.00
618253 | 1.EG +0.00
618286 | 1.EG +0.00
619181 | 2.1OG +5.30
619187 | 2.1OG +5.30
619878 | 3.2OG +10.60
619884 | 3.2OG +10.60
620802 | 4.3OG +15.90
620807 | 4.3OG +15.90
621693 | 1.EG +0.00
621701 | 1.EG +0.00
623590 | 1.EG +0.00
625601 | 4.3OG +15.90

# IfcWallStandardCase: Basic Wall:Wand_Innen_22, Basic Wall:Wand_Innen_22:622061
In: 6.EG KH -1.15
Type - PredefinedType: STANDARD; Material: Analytical Wall Surface_CJC 220 mm
Type - Pset_ElementShading - Roughness: 914.4 mm
Type - Pset_ProductRequirements - Category: Walls
Type - Pset_WallCommon - IsExternal: no
Pset_QuantityTakeOff - Reference: Wand_Innen_22; sets with these values: 2
Pset_WallCommon - LoadBearing: no; ExtendToStructure: no; Reference: Wand_Innen_22
Group: Model Group:Building:629362

# IfcWallStandardCase: Basic Wall:Wand_Innen_25 (44)
Type - PredefinedType: STANDARD; Material: Analytical Wall Surface_CJC 250 mm
Type - Pset_ElementShading - Roughness: 914.4 mm
Type - Pset_ProductRequirements - Category: Walls
Type - Pset_WallCommon - IsExternal: no
Pset_QuantityTakeOff - Reference: Wand_Innen_25; sets with these values: 2
Pset_WallCommon - LoadBearing: no; ExtendToStructure: no; Reference: Wand_Innen_25
Group: Model Group:Building:629362
Name (Basic Wall:Wand_Innen_25:...) | In
618507 | 1.EG +0.00
618508 | 1.EG +0.00
618509 | 1.EG +0.00
618510 | 1.EG +0.00
618511 | 1.EG +0.00
618512 | 1.EG +0.00
618513 | 1.EG +0.00
618514 | 1.EG +0.00
618515 | 1.EG +0.00
618516 | 1.EG +0.00
618517 | 1.EG +0.00
619492 | 2.1OG +5.30
619493 | 2.1OG +5.30
619494 | 2.1OG +5.30
619495 | 2.1OG +5.30
619496 | 2.1OG +5.30
619497 | 2.1OG +5.30
619498 | 2.1OG +5.30
619499 | 2.1OG +5.30
619500 | 2.1OG +5.30
619501 | 2.1OG +5.30
619502 | 2.1OG +5.30
620149 | 3.2OG +10.60
620150 | 3.2OG +10.60
620151 | 3.2OG +10.60
620152 | 3.2OG +10.60
620153 | 3.2OG +10.60
620154 | 3.2OG +10.60
620155 | 3.2OG +10.60
620156 | 3.2OG +10.60
620157 | 3.2OG +10.60
620158 | 3.2OG +10.60
620159 | 3.2OG +10.60
621059 | 4.3OG +15.90
621060 | 4.3OG +15.90
621061 | 4.3OG +15.90
621062 | 4.3OG +15.90
621063 | 4.3OG +15.90
621064 | 4.3OG +15.90
621065 | 4.3OG +15.90
621066 | 4.3OG +15.90
621067 | 4.3OG +15.90
621068 | 4.3OG +15.90
621069 | 4.3OG +15.90

# IfcWallStandardCase: Basic Wall:Wand_Innen_27.5 (2)
Type - PredefinedType: STANDARD; Material: Analytical Wall Surface_CJC 275 mm
Type - Pset_ElementShading - Roughness: 914.4 mm
Type - Pset_ProductRequirements - Category: Walls
Type - Pset_WallCommon - IsExternal: no
Pset_QuantityTakeOff - Reference: Wand_Innen_27.5; sets with these values: 2
Pset_WallCommon - LoadBearing: no; ExtendToStructure: no; Reference: Wand_Innen_27.5
Group: Model Group:Building:629362
Name (Basic Wall:Wand_Innen_27.5:...) | In
622222 | 8.2OG KH +6.45
622317 | 9.3OG KH +10.25

# IfcWallStandardCase: Basic Wall:Wand_Innen_30 (351)
Type - PredefinedType: STANDARD; Material: Analytical Wall Surface_CJC 300 mm
Type - Pset_ElementShading - Roughness: 914.4 mm
Type - Pset_ProductRequirements - Category: Walls
Type - Pset_WallCommon - IsExternal: no
Pset_QuantityTakeOff - Reference: Wand_Innen_30; sets with these values: 2
Pset_WallCommon - LoadBearing: no; ExtendToStructure: no; Reference: Wand_Innen_30
Group: Model Group:Building:629362
Name (Basic Wall:Wand_Innen_30:...) | In
617739 | 1.EG +0.00
617815 | 1.EG +0.00
617833 | 1.EG +0.00
617834 | 1.EG +0.00
617835 | 1.EG +0.00
617920 | 1.EG +0.00
617921 | 1.EG +0.00
617938 | 1.EG +0.00
617939 | 1.EG +0.00
617940 | 1.EG +0.00
617941 | 1.EG +0.00
617942 | 1.EG +0.00
617943 | 1.EG +0.00
617944 | 1.EG +0.00
617945 | 1.EG +0.00
617984 | 1.EG +0.00
617998 | 1.EG +0.00
618012 | 1.EG +0.00
618026 | 1.EG +0.00
618043 | 1.EG +0.00
618059 | 1.EG +0.00
618106 | 1.EG +0.00
618125 | 1.EG +0.00
618127 | 1.EG +0.00
618128 | 1.EG +0.00
618129 | 1.EG +0.00
618131 | 1.EG +0.00
618132 | 1.EG +0.00
618134 | 1.EG +0.00
618135 | 1.EG +0.00
618136 | 1.EG +0.00
618137 | 1.EG +0.00
618139 | 1.EG +0.00
618141 | 1.EG +0.00
618166 | 1.EG +0.00
618171 | 1.EG +0.00
618173 | 1.EG +0.00
618174 | 1.EG +0.00
618175 | 1.EG +0.00
618227 | 1.EG +0.00
618228 | 1.EG +0.00
618254 | 1.EG +0.00
618255 | 1.EG +0.00
618256 | 1.EG +0.00
618259 | 1.EG +0.00
618279 | 1.EG +0.00
618284 | 1.EG +0.00
618287 | 1.EG +0.00
618288 | 1.EG +0.00
618559 | 1.EG +0.00
618641 | 1.EG +0.00
618725 | 1.EG +0.00
618726 | 1.EG +0.00
618750 | 1.EG +0.00
618751 | 1.EG +0.00
618752 | 1.EG +0.00
618753 | 1.EG +0.00
618858 | 2.1OG +5.30
618950 | 2.1OG +5.30
618988 | 2.1OG +5.30
619001 | 2.1OG +5.30
619056 | 2.1OG +5.30
619116 | 2.1OG +5.30
619118 | 2.1OG +5.30
619120 | 2.1OG +5.30
619127 | 2.1OG +5.30
619132 | 2.1OG +5.30
619133 | 2.1OG +5.30
619134 | 2.1OG +5.30
619135 | 2.1OG +5.30
619136 | 2.1OG +5.30
619165 | 2.1OG +5.30
619166 | 2.1OG +5.30
619182 | 2.1OG +5.30
619188 | 2.1OG +5.30
619343 | 2.1OG +5.30
619359 | 2.1OG +5.30
619511 | 2.1OG +5.30
619518 | 2.1OG +5.30
619522 | 2.1OG +5.30
619524 | 2.1OG +5.30
619525 | 2.1OG +5.30
619527 | 2.1OG +5.30
619528 | 2.1OG +5.30
619533 | 2.1OG +5.30
619534 | 2.1OG +5.30
619535 | 2.1OG +5.30
619536 | 2.1OG +5.30
619537 | 2.1OG +5.30
619538 | 2.1OG +5.30
619539 | 2.1OG +5.30
619540 | 2.1OG +5.30
619580 | 1.EG +0.00
619581 | 1.EG +0.00
619582 | 2.1OG +5.30
619583 | 2.1OG +5.30
619585 | 2.1OG +5.30
619593 | 2.1OG +5.30
619594 | 2.1OG +5.30
619596 | 2.1OG +5.30
619598 | 2.1OG +5.30
619599 | 2.1OG +5.30
619600 | 2.1OG +5.30
619601 | 2.1OG +5.30
619602 | 2.1OG +5.30
619603 | 2.1OG +5.30
619612 | 2.1OG +5.30
619623 | 2.1OG +5.30
619628 | 2.1OG +5.30
619635 | 2.1OG +5.30
619759 | 3.2OG +10.60
619779 | 3.2OG +10.60
619818 | 3.2OG +10.60
619820 | 3.2OG +10.60
619822 | 3.2OG +10.60
619824 | 3.2OG +10.60
619829 | 3.2OG +10.60
619830 | 3.2OG +10.60
619831 | 3.2OG +10.60
619832 | 3.2OG +10.60
619833 | 3.2OG +10.60
619862 | 3.2OG +10.60
619863 | 3.2OG +10.60
619879 | 3.2OG +10.60
619885 | 3.2OG +10.60
620055 | 3.2OG +10.60
620170 | 3.2OG +10.60
620172 | 3.2OG +10.60
620173 | 3.2OG +10.60
620175 | 3.2OG +10.60
620176 | 3.2OG +10.60
620181 | 3.2OG +10.60
620182 | 3.2OG +10.60
620183 | 3.2OG +10.60
620184 | 3.2OG +10.60
620185 | 3.2OG +10.60
620215 | 3.2OG +10.60
620216 | 3.2OG +10.60
620218 | 3.2OG +10.60
620224 | 3.2OG +10.60
620225 | 3.2OG +10.60
620227 | 3.2OG +10.60
620228 | 3.2OG +10.60
620229 | 3.2OG +10.60
620230 | 3.2OG +10.60
620231 | 3.2OG +10.60
620240 | 3.2OG +10.60
620250 | 3.2OG +10.60
620256 | 3.2OG +10.60
620631 | 3.2OG +10.60
620663 | 3.2OG +10.60
620664 | 3.2OG +10.60
620667 | 3.2OG +10.60
620697 | 4.3OG +15.90
620744 | 4.3OG +15.90
620748 | 4.3OG +15.90
620753 | 4.3OG +15.90
620754 | 4.3OG +15.90
620755 | 4.3OG +15.90
620756 | 4.3OG +15.90
620757 | 4.3OG +15.90
620786 | 4.3OG +15.90
620787 | 4.3OG +15.90
620803 | 4.3OG +15.90
620808 | 4.3OG +15.90
620967 | 4.3OG +15.90
621080 | 4.3OG +15.90
621082 | 4.3OG +15.90
621083 | 4.3OG +15.90
621085 | 4.3OG +15.90
621086 | 4.3OG +15.90
621090 | 4.3OG +15.90
621091 | 4.3OG +15.90
621092 | 4.3OG +15.90
621093 | 4.3OG +15.90
621094 | 4.3OG +15.90
621123 | 4.3OG +15.90
621124 | 4.3OG +15.90
621126 | 4.3OG +15.90
621132 | 4.3OG +15.90
621133 | 4.3OG +15.90
621135 | 4.3OG +15.90
621136 | 4.3OG +15.90
621137 | 4.3OG +15.90
621138 | 4.3OG +15.90
621139 | 4.3OG +15.90
621148 | 4.3OG +15.90
621162 | 4.3OG +15.90
621498 | 4.3OG +15.90
621499 | 4.3OG +15.90
621590 | 4.3OG +15.90
621591 | 4.3OG +15.90
621592 | 4.3OG +15.90
621680 | 1.EG +0.00
621686 | 1.EG +0.00
621688 | 1.EG +0.00
621867 | 7.1OG KH +2.65
621874 | 7.1OG KH +2.65
621876 | 7.1OG KH +2.65
621877 | 7.1OG KH +2.65
621879 | 7.1OG KH +2.65
621883 | 7.1OG KH +2.65
621886 | 7.1OG KH +2.65
621888 | 7.1OG KH +2.65
621890 | 7.1OG KH +2.65
621891 | 7.1OG KH +2.65
621894 | 7.1OG KH +2.65
621895 | 7.1OG KH +2.65
621897 | 7.1OG KH +2.65
621900 | 7.1OG KH +2.65
621901 | 7.1OG KH +2.65
621902 | 7.1OG KH +2.65
622046 | 1.EG +0.00
622047 | 1.EG +0.00
622048 | 1.EG +0.00
622049 | 1.EG +0.00
622050 | 1.EG +0.00
622051 | 1.EG +0.00
622052 | 1.EG +0.00
622053 | 1.EG +0.00
622054 | 1.EG +0.00
622055 | 1.EG +0.00
622058 | 6.EG KH -1.15
622059 | 6.EG KH -1.15
622060 | 6.EG KH -1.15
622221 | 8.2OG KH +6.45
622223 | 8.2OG KH +6.45
622228 | 8.2OG KH +6.45
622232 | 8.2OG KH +6.45
622233 | 8.2OG KH +6.45
622234 | 8.2OG KH +6.45
622238 | 8.2OG KH +6.45
622266 | 8.2OG KH +6.45
622267 | 8.2OG KH +6.45
622268 | 8.2OG KH +6.45
622269 | 8.2OG KH +6.45
622270 | 8.2OG KH +6.45
622271 | 8.2OG KH +6.45
622272 | 8.2OG KH +6.45
622316 | 9.3OG KH +10.25
622318 | 9.3OG KH +10.25
622320 | 9.3OG KH +10.25
622323 | 9.3OG KH +10.25
622325 | 9.3OG KH +10.25
622326 | 9.3OG KH +10.25
622327 | 9.3OG KH +10.25
622331 | 9.3OG KH +10.25
622332 | 9.3OG KH +10.25
622333 | 9.3OG KH +10.25
622334 | 9.3OG KH +10.25
622335 | 9.3OG KH +10.25
622336 | 9.3OG KH +10.25
622337 | 9.3OG KH +10.25
622338 | 9.3OG KH +10.25
622472 | 0.UG -3.60
622491 | 0.UG -3.60
622493 | 0.UG -3.60
622494 | 0.UG -3.60
622495 | 0.UG -3.60
622496 | 0.UG -3.60
622497 | 0.UG -3.60
622498 | 0.UG -3.60
622499 | 0.UG -3.60
622500 | 0.UG -3.60
622503 | 0.UG -3.60
622504 | 0.UG -3.60
622505 | 0.UG -3.60
622506 | 0.UG -3.60
622507 | 0.UG -3.60
622508 | 0.UG -3.60
622514 | 0.UG -3.60
622515 | 0.UG -3.60
622516 | 0.UG -3.60
622518 | 0.UG -3.60
622520 | 0.UG -3.60
622521 | 0.UG -3.60
622544 | 0.UG -3.60
622545 | 0.UG -3.60
622546 | 0.UG -3.60
622547 | 0.UG -3.60
622548 | 0.UG -3.60
622549 | 0.UG -3.60
622550 | 0.UG -3.60
622551 | 0.UG -3.60
622552 | 0.UG -3.60
622554 | 0.UG -3.60
622556 | 0.UG -3.60
622557 | 0.UG -3.60
622558 | 0.UG -3.60
622562 | 0.UG -3.60
622564 | 0.UG -3.60
622566 | 0.UG -3.60
622568 | 0.UG -3.60
622569 | 0.UG -3.60
622570 | 0.UG -3.60
622571 | 0.UG -3.60
622572 | 0.UG -3.60
622574 | 0.UG -3.60
622575 | 0.UG -3.60
622576 | 0.UG -3.60
622577 | 0.UG -3.60
622578 | 0.UG -3.60
622581 | 0.UG -3.60
622831 | 0.UG -3.60
622832 | 0.UG -3.60
622833 | 0.UG -3.60
622834 | 0.UG -3.60
622835 | 0.UG -3.60
622836 | 0.UG -3.60
622839 | 0.UG -3.60
622841 | 0.UG -3.60
622842 | 0.UG -3.60
622844 | 0.UG -3.60
622846 | 0.UG -3.60
622848 | 0.UG -3.60
622849 | 0.UG -3.60
622851 | 0.UG -3.60
622892 | 0.UG -3.60
622897 | 0.UG -3.60
622898 | 0.UG -3.60
622900 | 0.UG -3.60
622901 | 0.UG -3.60
622902 | 0.UG -3.60
622903 | 0.UG -3.60
622904 | 0.UG -3.60
622905 | 0.UG -3.60
622930 | 0.UG -3.60
622934 | 0.UG -3.60
622935 | 0.UG -3.60
622988 | 0.UG -3.60
622990 | 0.UG -3.60
623039 | 0.UG -3.60
623041 | 0.UG -3.60
623043 | 0.UG -3.60
623044 | 0.UG -3.60
623051 | 0.UG -3.60
623053 | 0.UG -3.60
623121 | 0.UG -3.60
623244 | 0.UG -3.60
623887 | 0.UG -3.60
623888 | 0.UG -3.60
623889 | 0.UG -3.60
623890 | 0.UG -3.60
623891 | 0.UG -3.60
623963 | 0.UG -3.60
626059 | 3.2OG +10.60
626060 | 3.2OG +10.60
626061 | 3.2OG +10.60
626062 | 3.2OG +10.60
628111 | 1.EG +0.00
628112 | 1.EG +0.00

# IfcWallStandardCase: Basic Wall:Wand_Innen_32.5 (3)
Type - PredefinedType: STANDARD; Material: Analytical Wall Surface_CJC 325 mm
Type - Pset_ElementShading - Roughness: 914.4 mm
Type - Pset_ProductRequirements - Category: Walls
Type - Pset_WallCommon - IsExternal: no
Pset_QuantityTakeOff - Reference: Wand_Innen_32.5; sets with these values: 2
Pset_WallCommon - LoadBearing: no; ExtendToStructure: no; Reference: Wand_Innen_32.5
Group: Model Group:Building:629362
Name (Basic Wall:Wand_Innen_32.5:...) | In
619530 | 2.1OG +5.30
620178 | 3.2OG +10.60
622519 | 0.UG -3.60

# IfcWallStandardCase: Basic Wall:Wand_Innen_33 (3)
Type - PredefinedType: STANDARD; Material: Analytical Wall Surface_CJC 330 mm
Type - Pset_ElementShading - Roughness: 914.4 mm
Type - Pset_ProductRequirements - Category: Walls
Type - Pset_WallCommon - IsExternal: no
Pset_QuantityTakeOff - Reference: Wand_Innen_33; sets with these values: 2
Pset_WallCommon - LoadBearing: no; ExtendToStructure: no; Reference: Wand_Innen_33
Group: Model Group:Building:629362
Name (Basic Wall:Wand_Innen_33:...) | In
619634 | 2.1OG +5.30
620255 | 3.2OG +10.60
621161 | 4.3OG +15.90

# IfcWallStandardCase: Basic Wall:Wand_Innen_35 (122)
Type - PredefinedType: STANDARD; Material: Analytical Wall Surface_CJC 350 mm
Type - Pset_ElementShading - Roughness: 914.4 mm
Type - Pset_ProductRequirements - Category: Walls
Type - Pset_WallCommon - IsExternal: no
Pset_QuantityTakeOff - Reference: Wand_Innen_35; sets with these values: 2
Pset_WallCommon - LoadBearing: no; ExtendToStructure: no; Reference: Wand_Innen_35
Group: Model Group:Building:629362
Name (Basic Wall:Wand_Innen_35:...) | In
617740 | 1.EG +0.00
617741 | 1.EG +0.00
617760 | 1.EG +0.00
617774 | 1.EG +0.00
617788 | 1.EG +0.00
617801 | 1.EG +0.00
617818 | 1.EG +0.00
617904 | 1.EG +0.00
617985 | 1.EG +0.00
617999 | 1.EG +0.00
618013 | 1.EG +0.00
618027 | 1.EG +0.00
618130 | 1.EG +0.00
618165 | 1.EG +0.00
618176 | 1.EG +0.00
618177 | 1.EG +0.00
618237 | 1.EG +0.00
618239 | 1.EG +0.00
618250 | 1.EG +0.00
618257 | 1.EG +0.00
618280 | 1.EG +0.00
618798 | 2.1OG +5.30
618816 | 2.1OG +5.30
618829 | 2.1OG +5.30
618845 | 2.1OG +5.30
618989 | 2.1OG +5.30
619002 | 2.1OG +5.30
619028 | 2.1OG +5.30
619179 | 2.1OG +5.30
619419 | 2.1OG +5.30
619514 | 2.1OG +5.30
619516 | 2.1OG +5.30
619517 | 2.1OG +5.30
619529 | 2.1OG +5.30
619531 | 2.1OG +5.30
619541 | 2.1OG +5.30
619542 | 2.1OG +5.30
619543 | 2.1OG +5.30
619544 | 2.1OG +5.30
619592 | 2.1OG +5.30
619614 | 2.1OG +5.30
619661 | 2.1OG +5.30
619673 | 2.1OG +5.30
619674 | 2.1OG +5.30
619747 | 3.2OG +10.60
619791 | 3.2OG +10.60
619792 | 3.2OG +10.60
619876 | 3.2OG +10.60
620087 | 3.2OG +10.60
620164 | 3.2OG +10.60
620165 | 3.2OG +10.60
620166 | 3.2OG +10.60
620177 | 3.2OG +10.60
620179 | 3.2OG +10.60
620186 | 3.2OG +10.60
620187 | 3.2OG +10.60
620188 | 3.2OG +10.60
620189 | 3.2OG +10.60
620223 | 3.2OG +10.60
620242 | 3.2OG +10.60
620280 | 3.2OG +10.60
620292 | 3.2OG +10.60
620293 | 3.2OG +10.60
620341 | 3.2OG +10.60
620355 | 3.2OG +10.60
620369 | 3.2OG +10.60
620383 | 3.2OG +10.60
620397 | 3.2OG +10.60
620411 | 3.2OG +10.60
620467 | 3.2OG +10.60
620594 | 3.2OG +10.60
620602 | 2.1OG +5.30
620615 | 2.1OG +5.30
620662 | 3.2OG +10.60
620685 | 4.3OG +15.90
620747 | 4.3OG +15.90
620800 | 4.3OG +15.90
620997 | 4.3OG +15.90
621074 | 4.3OG +15.90
621075 | 4.3OG +15.90
621076 | 4.3OG +15.90
621087 | 4.3OG +15.90
621088 | 4.3OG +15.90
621095 | 4.3OG +15.90
621096 | 4.3OG +15.90
621097 | 4.3OG +15.90
621098 | 4.3OG +15.90
621131 | 4.3OG +15.90
621150 | 4.3OG +15.90
621158 | 4.3OG +15.90
621159 | 4.3OG +15.90
621186 | 4.3OG +15.90
621199 | 4.3OG +15.90
621217 | 4.3OG +15.90
621231 | 4.3OG +15.90
621245 | 4.3OG +15.90
621259 | 4.3OG +15.90
621273 | 4.3OG +15.90
621287 | 4.3OG +15.90
621300 | 4.3OG +15.90
621313 | 4.3OG +15.90
621340 | 4.3OG +15.90
621466 | 4.3OG +15.90
621497 | 4.3OG +15.90
621515 | 4.3OG +15.90
621689 | 1.EG +0.00
621697 | 1.EG +0.00
621898 | 7.1OG KH +2.65
621899 | 7.1OG KH +2.65
622056 | 6.EG KH -1.15
622057 | 6.EG KH -1.15
622559 | 0.UG -3.60
622896 | 0.UG -3.60
622908 | 0.UG -3.60
622989 | 0.UG -3.60
622991 | 0.UG -3.60
623013 | 0.UG -3.60
623028 | 0.UG -3.60
623042 | 0.UG -3.60
623049 | 0.UG -3.60
623050 | 0.UG -3.60
623628 | 5.DG +21.50

# IfcWallStandardCase: Basic Wall:Wand_Innen_40 (11)
Type - PredefinedType: STANDARD; Material: Analytical Wall Surface_CJC 400 mm
Type - Pset_ElementShading - Roughness: 914.4 mm
Type - Pset_ProductRequirements - Category: Walls
Type - Pset_WallCommon - IsExternal: no
Pset_QuantityTakeOff - Reference: Wand_Innen_40; sets with these values: 2
Pset_WallCommon - LoadBearing: no; ExtendToStructure: no; Reference: Wand_Innen_40
Group: Model Group:Building:629362
Name (Basic Wall:Wand_Innen_40:...) | In
618138 | 1.EG +0.00
618289 | 1.EG +0.00
619117 | 2.1OG +5.30
619819 | 3.2OG +10.60
620743 | 4.3OG +15.90
621695 | 1.EG +0.00
622560 | 0.UG -3.60
622582 | 0.UG -3.60
622845 | 0.UG -3.60
623886 | 0.UG -3.60
623892 | 0.UG -3.60

# IfcWallStandardCase: Basic Wall:Wand_Innen_42.5 (9)
Type - PredefinedType: STANDARD; Material: Analytical Wall Surface_CJC 425 mm
Type - Pset_ElementShading - Roughness: 914.4 mm
Type - Pset_ProductRequirements - Category: Walls
Type - Pset_WallCommon - IsExternal: no
Pset_QuantityTakeOff - Reference: Wand_Innen_42.5; sets with these values: 2
Pset_WallCommon - LoadBearing: no; ExtendToStructure: no; Reference: Wand_Innen_42.5
Group: Model Group:Building:629362
Name (Basic Wall:Wand_Innen_42.5:...) | In
621681 | 1.EG +0.00
621875 | 7.1OG KH +2.65
621878 | 7.1OG KH +2.65
622214 | 8.2OG KH +6.45
622224 | 8.2OG KH +6.45
622226 | 8.2OG KH +6.45
622309 | 9.3OG KH +10.25
622319 | 9.3OG KH +10.25
622321 | 9.3OG KH +10.25

# IfcWallStandardCase: Basic Wall:Wand_Innen_43, Basic Wall:Wand_Innen_43:618643
In: 1.EG +0.00
Type - PredefinedType: STANDARD; Material: Analytical Wall Surface_CJC 430 mm
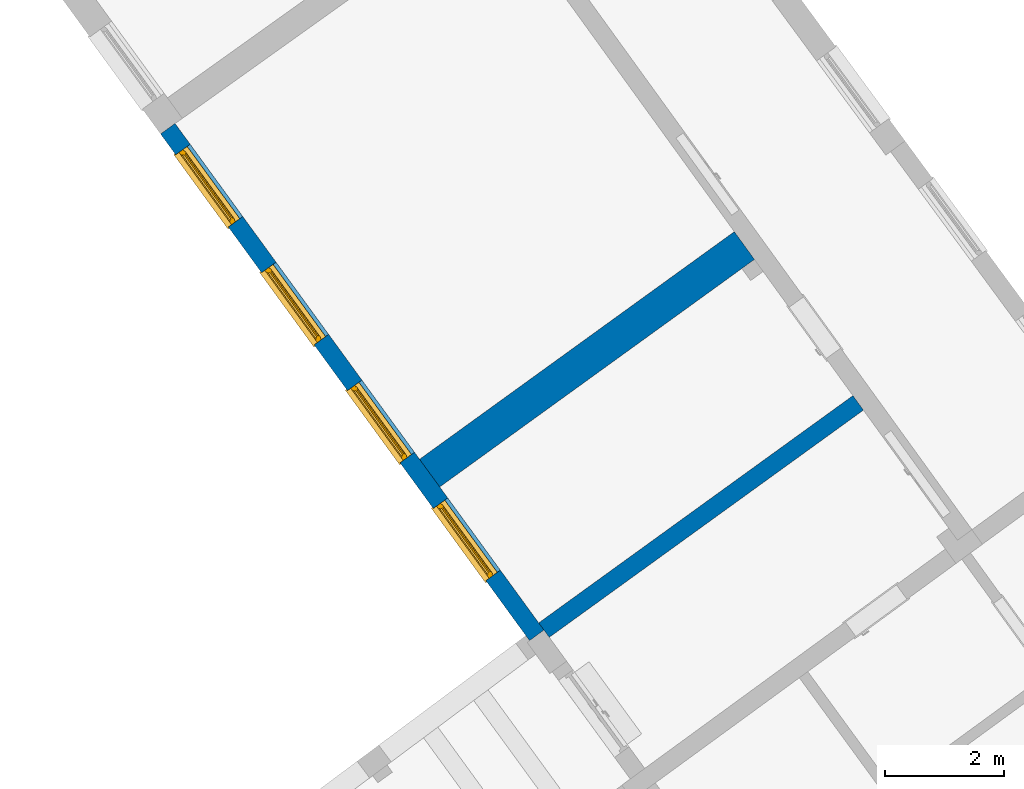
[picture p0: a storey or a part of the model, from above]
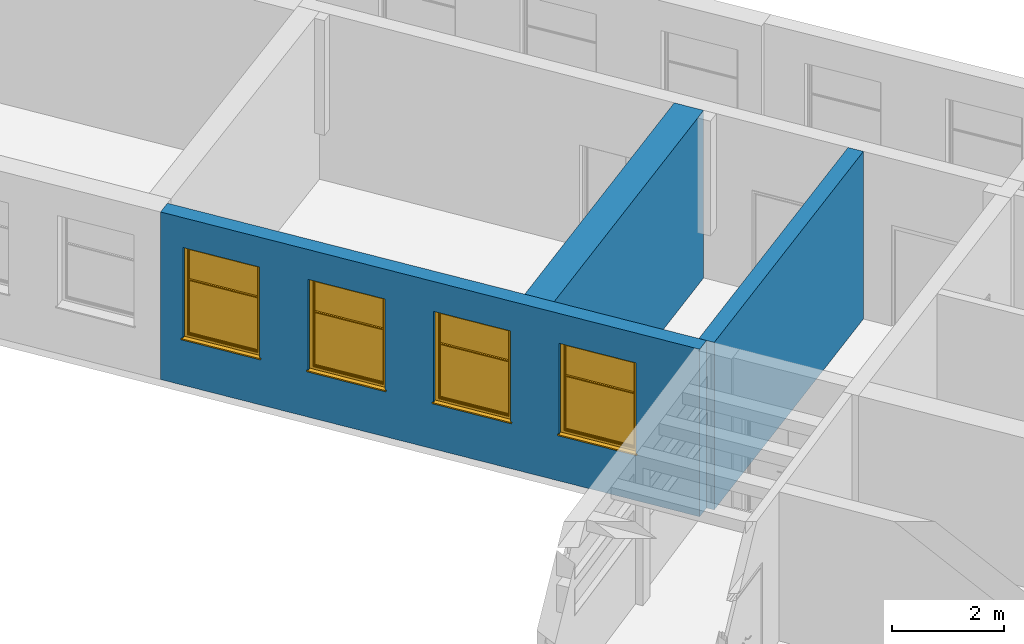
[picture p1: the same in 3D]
Properties of the parts of a building model (IFC2X3), part 13 of 13

# IfcWallStandardCase: Basic Wall:Wand_Innen_43, Basic Wall:Wand_Innen_43:618643
Type - Pset_ElementShading - Roughness: 914.4 mm
Type - Pset_ProductRequirements - Category: Walls
Type - Pset_WallCommon - IsExternal: no
Pset_QuantityTakeOff - Reference: Wand_Innen_43; sets with these values: 2
Pset_WallCommon - LoadBearing: no; ExtendToStructure: no; Reference: Wand_Innen_43
Group: Model Group:Building:629362

# IfcWallStandardCase: Basic Wall:Wand_Innen_45 (16)
Type - PredefinedType: STANDARD; Material: Analytical Wall Surface_CJC 450 mm
Type - Pset_ElementShading - Roughness: 914.4 mm
Type - Pset_ProductRequirements - Category: Walls
Type - Pset_WallCommon - IsExternal: no
Pset_QuantityTakeOff - Reference: Wand_Innen_45; sets with these values: 2
Pset_WallCommon - LoadBearing: no; ExtendToStructure: no; Reference: Wand_Innen_45
Group: Model Group:Building:629362
Name (Basic Wall:Wand_Innen_45:...) | In
618247 | 1.EG +0.00
619176 | 2.1OG +5.30
619526 | 2.1OG +5.30
619873 | 3.2OG +10.60
620174 | 3.2OG +10.60
620797 | 4.3OG +15.90
621084 | 4.3OG +15.90
621677 | 1.EG +0.00
621872 | 7.1OG KH +2.65
621882 | 7.1OG KH +2.65
621892 | 7.1OG KH +2.65
622216 | 8.2OG KH +6.45
622311 | 9.3OG KH +10.25
622324 | 9.3OG KH +10.25
622850 | 0.UG -3.60
623243 | 0.UG -3.60

# IfcWallStandardCase: Basic Wall:Wand_Innen_47.5 (2)
Type - PredefinedType: STANDARD; Material: Analytical Wall Surface_CJC 475 mm
Type - Pset_ElementShading - Roughness: 914.4 mm
Type - Pset_ProductRequirements - Category: Walls
Type - Pset_WallCommon - IsExternal: no
Pset_QuantityTakeOff - Reference: Wand_Innen_47.5; sets with these values: 2
Pset_WallCommon - LoadBearing: no; ExtendToStructure: no; Reference: Wand_Innen_47.5
Group: Model Group:Building:629362
Name (Basic Wall:Wand_Innen_47.5:...) | In
621687 | 1.EG +0.00
621859 | 7.1OG KH +2.65

# IfcWallStandardCase: Basic Wall:Wand_Innen_5 (13)
Type - PredefinedType: STANDARD; Material: Analytical Wall Surface_CJC 50 mm
Type - Pset_ElementShading - Roughness: 914.4 mm
Type - Pset_ProductRequirements - Category: Walls
Type - Pset_WallCommon - IsExternal: no
Pset_QuantityTakeOff - Reference: Wand_Innen_5; sets with these values: 2
Pset_WallCommon - LoadBearing: no; ExtendToStructure: no; Reference: Wand_Innen_5
Group: Model Group:Building:629362
Name (Basic Wall:Wand_Innen_5:...) | In
625609 | 4.3OG +15.90
625774 | 4.3OG +15.90
625875 | 4.3OG +15.90
625876 | 4.3OG +15.90
625877 | 4.3OG +15.90
625878 | 4.3OG +15.90
625879 | 4.3OG +15.90
625880 | 4.3OG +15.90
626030 | 4.3OG +15.90
626513 | 3.2OG +10.60
626514 | 3.2OG +10.60
626515 | 3.2OG +10.60
626516 | 3.2OG +10.60

# IfcWallStandardCase: Basic Wall:Wand_Innen_50 (16)
Type - PredefinedType: STANDARD; Material: Analytical Wall Surface_CJC 500 mm
Type - Pset_ElementShading - Roughness: 914.4 mm
Type - Pset_ProductRequirements - Category: Walls
Type - Pset_WallCommon - IsExternal: no
Pset_QuantityTakeOff - Reference: Wand_Innen_50; sets with these values: 2
Pset_WallCommon - LoadBearing: no; ExtendToStructure: no; Reference: Wand_Innen_50
Group: Model Group:Building:629362
Name (Basic Wall:Wand_Innen_50:...) | In
618282 | 1.EG +0.00
618283 | 1.EG +0.00
619119 | 2.1OG +5.30
619184 | 2.1OG +5.30
619821 | 3.2OG +10.60
619881 | 3.2OG +10.60
620745 | 4.3OG +15.90
620805 | 4.3OG +15.90
620806 | 4.3OG +15.90
621699 | 6.EG KH -1.15
622579 | 0.UG -3.60
622829 | 0.UG -3.60
622843 | 0.UG -3.60
622899 | 0.UG -3.60
623052 | 0.UG -3.60
623054 | 0.UG -3.60

# IfcWallStandardCase: Basic Wall:Wand_Innen_53 (3)
Type - PredefinedType: STANDARD; Material: Analytical Wall Surface_CJC 530 mm
Type - Pset_ElementShading - Roughness: 914.4 mm
Type - Pset_ProductRequirements - Category: Walls
Type - Pset_WallCommon - IsExternal: no
Pset_QuantityTakeOff - Reference: Wand_Innen_53; sets with these values: 2
Pset_WallCommon - LoadBearing: no; ExtendToStructure: no; Reference: Wand_Innen_53
Group: Model Group:Building:629362
Name (Basic Wall:Wand_Innen_53:...) | In
618285 | 1.EG +0.00
619186 | 2.1OG +5.30
619883 | 3.2OG +10.60

# IfcWallStandardCase: Basic Wall:Wand_Innen_55 (12)
Type - PredefinedType: STANDARD; Material: Analytical Wall Surface_CJC 550 mm
Type - Pset_ElementShading - Roughness: 914.4 mm
Type - Pset_ProductRequirements - Category: Walls
Type - Pset_WallCommon - IsExternal: no
Pset_QuantityTakeOff - Reference: Wand_Innen_55; sets with these values: 2
Pset_WallCommon - LoadBearing: no; ExtendToStructure: no; Reference: Wand_Innen_55
Group: Model Group:Building:629362
Name (Basic Wall:Wand_Innen_55:...) | In
619624 | 2.1OG +5.30
619627 | 2.1OG +5.30
620220 | 3.2OG +10.60
620251 | 3.2OG +10.60
621128 | 4.3OG +15.90
621881 | 7.1OG KH +2.65
622231 | 8.2OG KH +6.45
622540 | 0.UG -3.60
622553 | 0.UG -3.60
622847 | 0.UG -3.60
623885 | 0.UG -3.60
627524 | 2.1OG +5.30

# IfcWallStandardCase: Basic Wall:Wand_Innen_57.5 (4)
Type - PredefinedType: STANDARD; Material: Analytical Wall Surface_CJC 575 mm
Type - Pset_ElementShading - Roughness: 914.4 mm
Type - Pset_ProductRequirements - Category: Walls
Type - Pset_WallCommon - IsExternal: no
Pset_QuantityTakeOff - Reference: Wand_Innen_57.5; sets with these values: 2
Pset_WallCommon - LoadBearing: no; ExtendToStructure: no; Reference: Wand_Innen_57.5
Group: Model Group:Building:629362
Name (Basic Wall:Wand_Innen_57.5:...) | In
621698 | 1.EG +0.00
621885 | 7.1OG KH +2.65
622215 | 8.2OG KH +6.45
622310 | 9.3OG KH +10.25

# IfcWallStandardCase: Basic Wall:Wand_Innen_60 (14)
Type - PredefinedType: STANDARD; Material: Analytical Wall Surface_CJC 600 mm
Type - Pset_ElementShading - Roughness: 914.4 mm
Type - Pset_ProductRequirements - Category: Walls
Type - Pset_WallCommon - IsExternal: no
Pset_QuantityTakeOff - Reference: Wand_Innen_60; sets with these values: 2
Pset_WallCommon - LoadBearing: no; ExtendToStructure: no; Reference: Wand_Innen_60
Group: Model Group:Building:629362
Name (Basic Wall:Wand_Innen_60:...) | In
618560 | 1.EG +0.00
619587 | 2.1OG +5.30
621889 | 7.1OG KH +2.65
621896 | 7.1OG KH +2.65
622235 | 8.2OG KH +6.45
622236 | 8.2OG KH +6.45
622328 | 9.3OG KH +10.25
622329 | 9.3OG KH +10.25
622563 | 0.UG -3.60
622565 | 0.UG -3.60
622567 | 0.UG -3.60
622840 | 0.UG -3.60
623046 | 0.UG -3.60
623047 | 0.UG -3.60

# IfcWallStandardCase: Basic Wall:Wand_Innen_63 (5)
Type - PredefinedType: STANDARD; Material: Analytical Wall Surface_CJC 630 mm
Type - Pset_ElementShading - Roughness: 914.4 mm
Type - Pset_ProductRequirements - Category: Walls
Type - Pset_WallCommon - IsExternal: no
Pset_QuantityTakeOff - Reference: Wand_Innen_63; sets with these values: 2
Pset_WallCommon - LoadBearing: no; ExtendToStructure: no; Reference: Wand_Innen_63
Group: Model Group:Building:629362
Name (Basic Wall:Wand_Innen_63:...) | In
618281 | 1.EG +0.00
618642 | 1.EG +0.00
619183 | 2.1OG +5.30
619880 | 3.2OG +10.60
622891 | 0.UG -3.60

# IfcWallStandardCase: Basic Wall:Wand_Innen_65 (9)
Type - PredefinedType: STANDARD; Material: Analytical Wall Surface_CJC 650 mm
Type - Pset_ElementShading - Roughness: 914.4 mm
Type - Pset_ProductRequirements - Category: Walls
Type - Pset_WallCommon - IsExternal: no
Pset_QuantityTakeOff - Reference: Wand_Innen_65; sets with these values: 2
Pset_WallCommon - LoadBearing: no; ExtendToStructure: no; Reference: Wand_Innen_65
Group: Model Group:Building:629362
Name (Basic Wall:Wand_Innen_65:...) | In
617814 | 1.EG +0.00
618258 | 1.EG +0.00
618842 | 2.1OG +5.30
619744 | 3.2OG +10.60
620682 | 4.3OG +15.90
621873 | 7.1OG KH +2.65
622220 | 8.2OG KH +6.45
622315 | 9.3OG KH +10.25
622933 | 0.UG -3.60

# IfcWallStandardCase: Basic Wall:Wand_Innen_67.5 (4)
Type - PredefinedType: STANDARD; Material: Analytical Wall Surface_CJC 675 mm
Type - Pset_ElementShading - Roughness: 914.4 mm
Type - Pset_ProductRequirements - Category: Walls
Type - Pset_WallCommon - IsExternal: no
Pset_QuantityTakeOff - Reference: Wand_Innen_67.5; sets with these values: 2
Pset_WallCommon - LoadBearing: no; ExtendToStructure: no; Reference: Wand_Innen_67.5
Group: Model Group:Building:629362
Name (Basic Wall:Wand_Innen_67.5:...) | In
622227 | 8.2OG KH +6.45
622273 | 8.2OG KH +6.45
622322 | 9.3OG KH +10.25
622339 | 9.3OG KH +10.25

# IfcWallStandardCase: Basic Wall:Wand_Innen_70 (2)
Type - PredefinedType: STANDARD; Material: Analytical Wall Surface_CJC 700 mm
Type - Pset_ElementShading - Roughness: 914.4 mm
Type - Pset_ProductRequirements - Category: Walls
Type - Pset_WallCommon - IsExternal: no
Pset_QuantityTakeOff - Reference: Wand_Innen_70; sets with these values: 2
Pset_WallCommon - LoadBearing: no; ExtendToStructure: no; Reference: Wand_Innen_70
Group: Model Group:Building:629362
Name (Basic Wall:Wand_Innen_70:...) | In
621871 | 1.EG +0.00
622555 | 0.UG -3.60

# IfcWallStandardCase: Basic Wall:Wand_Innen_75, Basic Wall:Wand_Innen_75:623882
In: 0.UG -3.60
Type - PredefinedType: STANDARD; Material: Analytical Wall Surface_CJC 750 mm
Type - Pset_ElementShading - Roughness: 914.4 mm
Type - Pset_ProductRequirements - Category: Walls
Type - Pset_WallCommon - IsExternal: no
Pset_QuantityTakeOff - Reference: Wand_Innen_75; sets with these values: 2
Pset_WallCommon - LoadBearing: no; ExtendToStructure: no; Reference: Wand_Innen_75
Group: Model Group:Building:629362

# IfcWindow: Fenster_Aussen_CJC:Fenster_Aussen_CJC_265x350 (276)
Type - ParameterTakesPrecedence: no; Sizeable: no; Material: Glass, <Unnamed>
Type - Pset_ProductRequirements - Category: Windows
Type - Pset_WindowCommon - IsExternal: no
OverallHeight: 3500 mm; OverallWidth: 2650 mm; Group: Model Group:Building:629362
Pset_QuantityTakeOff - Reference: Fenster_Aussen_CJC_265x350
Pset_WindowCommon - Reference: Fenster_Aussen_CJC_265x350
Name (Fenster_Aussen_CJC:Fenster_Aussen_CJC_265x350:...) | In
618290 | 1.EG +0.00 | Pset_WindowCommon - IsExternal: yes
618291 | 1.EG +0.00
618292 | 1.EG +0.00
618293 | 1.EG +0.00
618294 | 1.EG +0.00
618295 | 1.EG +0.00
618296 | 1.EG +0.00
618297 | 1.EG +0.00
618298 | 1.EG +0.00
618299 | 1.EG +0.00
618300 | 1.EG +0.00
618301 | 1.EG +0.00
618302 | 1.EG +0.00
618303 | 1.EG +0.00
618304 | 1.EG +0.00
618305 | 1.EG +0.00
618306 | 1.EG +0.00
618307 | 1.EG +0.00
618308 | 1.EG +0.00
618309 | 1.EG +0.00
618310 | 1.EG +0.00
618311 | 1.EG +0.00
618312 | 1.EG +0.00
618313 | 1.EG +0.00
618314 | 1.EG +0.00
618315 | 1.EG +0.00
618316 | 1.EG +0.00
618317 | 1.EG +0.00
618318 | 1.EG +0.00
618319 | 1.EG +0.00
618320 | 1.EG +0.00
618321 | 1.EG +0.00
618322 | 1.EG +0.00
618323 | 1.EG +0.00
618324 | 1.EG +0.00
618325 | 1.EG +0.00
618326 | 1.EG +0.00
618327 | 1.EG +0.00
618328 | 1.EG +0.00
618329 | 1.EG +0.00
618330 | 1.EG +0.00
618331 | 1.EG +0.00
618332 | 1.EG +0.00
618333 | 1.EG +0.00
618334 | 1.EG +0.00
618335 | 1.EG +0.00
618336 | 1.EG +0.00
618337 | 1.EG +0.00
618338 | 1.EG +0.00
618339 | 1.EG +0.00
618340 | 1.EG +0.00
618341 | 1.EG +0.00
618342 | 1.EG +0.00
618343 | 1.EG +0.00
618344 | 1.EG +0.00
618345 | 1.EG +0.00
618346 | 1.EG +0.00
618347 | 1.EG +0.00
618348 | 1.EG +0.00
618349 | 1.EG +0.00
618350 | 1.EG +0.00
618463 | 1.EG +0.00
619189 | 2.1OG +5.30
619190 | 2.1OG +5.30
619191 | 2.1OG +5.30
619192 | 2.1OG +5.30
619193 | 2.1OG +5.30
619194 | 2.1OG +5.30
619195 | 2.1OG +5.30
619196 | 2.1OG +5.30
619197 | 2.1OG +5.30
619198 | 2.1OG +5.30
619199 | 2.1OG +5.30
619200 | 2.1OG +5.30
619201 | 2.1OG +5.30
619202 | 2.1OG +5.30
619203 | 2.1OG +5.30
619204 | 2.1OG +5.30
619205 | 2.1OG +5.30
619206 | 2.1OG +5.30
619207 | 2.1OG +5.30
619208 | 2.1OG +5.30
619209 | 2.1OG +5.30
619210 | 2.1OG +5.30
619211 | 2.1OG +5.30
619212 | 2.1OG +5.30
619213 | 2.1OG +5.30
619214 | 2.1OG +5.30
619215 | 2.1OG +5.30
619216 | 2.1OG +5.30
619217 | 2.1OG +5.30
619218 | 2.1OG +5.30
619219 | 2.1OG +5.30
619220 | 2.1OG +5.30
619221 | 2.1OG +5.30
619222 | 2.1OG +5.30
619223 | 2.1OG +5.30
619224 | 2.1OG +5.30
619225 | 2.1OG +5.30
619226 | 2.1OG +5.30
619227 | 2.1OG +5.30
619228 | 2.1OG +5.30
619229 | 2.1OG +5.30
619230 | 2.1OG +5.30
619231 | 2.1OG +5.30
619232 | 2.1OG +5.30
619233 | 2.1OG +5.30
619234 | 2.1OG +5.30
619235 | 2.1OG +5.30
619236 | 2.1OG +5.30
619237 | 2.1OG +5.30
619238 | 2.1OG +5.30
619239 | 2.1OG +5.30
619240 | 2.1OG +5.30
619241 | 2.1OG +5.30
619242 | 2.1OG +5.30
619243 | 2.1OG +5.30
619244 | 2.1OG +5.30
619245 | 2.1OG +5.30
619246 | 2.1OG +5.30
619247 | 2.1OG +5.30
619248 | 2.1OG +5.30
619249 | 2.1OG +5.30
619254 | 2.1OG +5.30
619519 | 2.1OG +5.30
619532 | 2.1OG +5.30
619613 | 2.1OG +5.30
619615 | 2.1OG +5.30
619699 | 2.1OG +5.30
619700 | 2.1OG +5.30
619701 | 2.1OG +5.30
619886 | 3.2OG +10.60
619887 | 3.2OG +10.60
619888 | 3.2OG +10.60
619889 | 3.2OG +10.60
619890 | 3.2OG +10.60
619891 | 3.2OG +10.60
619892 | 3.2OG +10.60
619893 | 3.2OG +10.60
619894 | 3.2OG +10.60
619895 | 3.2OG +10.60
619896 | 3.2OG +10.60
619897 | 3.2OG +10.60
619898 | 3.2OG +10.60
619899 | 3.2OG +10.60
619900 | 3.2OG +10.60
619901 | 3.2OG +10.60
619902 | 3.2OG +10.60
619903 | 3.2OG +10.60
619904 | 3.2OG +10.60
619905 | 3.2OG +10.60
619906 | 3.2OG +10.60
619907 | 3.2OG +10.60
619908 | 3.2OG +10.60
619909 | 3.2OG +10.60
619910 | 3.2OG +10.60
619911 | 3.2OG +10.60
619912 | 3.2OG +10.60
619913 | 3.2OG +10.60
619914 | 3.2OG +10.60
619915 | 3.2OG +10.60
619916 | 3.2OG +10.60
619917 | 3.2OG +10.60
619918 | 3.2OG +10.60
619919 | 3.2OG +10.60
619920 | 3.2OG +10.60
619921 | 3.2OG +10.60
619922 | 3.2OG +10.60
619923 | 3.2OG +10.60
619924 | 3.2OG +10.60
619925 | 3.2OG +10.60
619926 | 3.2OG +10.60
619927 | 3.2OG +10.60
619928 | 3.2OG +10.60
619929 | 3.2OG +10.60
619930 | 3.2OG +10.60
619931 | 3.2OG +10.60
619932 | 3.2OG +10.60
619933 | 3.2OG +10.60
619934 | 3.2OG +10.60
619935 | 3.2OG +10.60
619936 | 3.2OG +10.60
619937 | 3.2OG +10.60
619938 | 3.2OG +10.60
619939 | 3.2OG +10.60
619940 | 3.2OG +10.60
619941 | 3.2OG +10.60
619942 | 3.2OG +10.60
619943 | 3.2OG +10.60
619944 | 3.2OG +10.60
619945 | 3.2OG +10.60
619946 | 3.2OG +10.60
619951 | 3.2OG +10.60
620167 | 3.2OG +10.60
620180 | 3.2OG +10.60
620241 | 3.2OG +10.60
620243 | 3.2OG +10.60
620299 | 3.2OG +10.60
620300 | 3.2OG +10.60
620301 | 3.2OG +10.60
620809 | 4.3OG +15.90
620810 | 4.3OG +15.90
620811 | 4.3OG +15.90
620812 | 4.3OG +15.90
620813 | 4.3OG +15.90
620814 | 4.3OG +15.90
620815 | 4.3OG +15.90
620816 | 4.3OG +15.90
620817 | 4.3OG +15.90
620818 | 4.3OG +15.90
620819 | 4.3OG +15.90
620820 | 4.3OG +15.90
620821 | 4.3OG +15.90
620822 | 4.3OG +15.90
620823 | 4.3OG +15.90
620824 | 4.3OG +15.90
620825 | 4.3OG +15.90
620826 | 4.3OG +15.90
620827 | 4.3OG +15.90
620828 | 4.3OG +15.90
620829 | 4.3OG +15.90
620830 | 4.3OG +15.90
620831 | 4.3OG +15.90
620832 | 4.3OG +15.90
620833 | 4.3OG +15.90
620834 | 4.3OG +15.90
620835 | 4.3OG +15.90
620836 | 4.3OG +15.90
620837 | 4.3OG +15.90
620838 | 4.3OG +15.90
620839 | 4.3OG +15.90
620840 | 4.3OG +15.90
620841 | 4.3OG +15.90
620842 | 4.3OG +15.90
620843 | 4.3OG +15.90
620844 | 4.3OG +15.90
620845 | 4.3OG +15.90
620846 | 4.3OG +15.90
620847 | 4.3OG +15.90
620848 | 4.3OG +15.90
620849 | 4.3OG +15.90
620850 | 4.3OG +15.90
620851 | 4.3OG +15.90
620852 | 4.3OG +15.90
620853 | 4.3OG +15.90
620854 | 4.3OG +15.90
620855 | 4.3OG +15.90
620856 | 4.3OG +15.90
620857 | 4.3OG +15.90
620858 | 4.3OG +15.90
620859 | 4.3OG +15.90
620860 | 4.3OG +15.90
620861 | 4.3OG +15.90
620862 | 4.3OG +15.90
620863 | 4.3OG +15.90
620864 | 4.3OG +15.90
620865 | 4.3OG +15.90
620866 | 4.3OG +15.90
620867 | 4.3OG +15.90
620868 | 4.3OG +15.90
620869 | 4.3OG +15.90
620874 | 4.3OG +15.90
621077 | 4.3OG +15.90
621089 | 4.3OG +15.90
621149 | 4.3OG +15.90
621151 | 4.3OG +15.90
621205 | 4.3OG +15.90
621206 | 4.3OG +15.90
621207 | 4.3OG +15.90
622025 | 1.EG +0.00
623871 | 4.3OG +15.90
623872 | 4.3OG +15.90
623873 | 3.2OG +10.60
623874 | 3.2OG +10.60
623875 | 2.1OG +5.30
623876 | 2.1OG +5.30

# IfcWindow: Fenster_Aussen_CJC_TOPONLY:Fenster_Aussen_CJC_TOPONLY, Fenster_Aussen_CJC_TOPONLY:Fenster_Aussen_CJC_TOPONLY:618562
In: 1.EG +0.00
Type - ParameterTakesPrecedence: no; Sizeable: no; Material: Glass, <Unnamed>
Type - Pset_ProductRequirements - Category: Windows
Type - Pset_WindowCommon - IsExternal: no
OverallHeight: 800 mm; OverallWidth: 2650 mm; Group: Model Group:Building:629362
Pset_QuantityTakeOff - Reference: Fenster_Aussen_CJC_TOPONLY
Pset_WindowCommon - IsExternal: yes; Reference: Fenster_Aussen_CJC_TOPONLY

# IfcWindow: Fenster_Aussen_KH_CJC:Fenster_Aussen_KH_CJC (11)
Type - ParameterTakesPrecedence: no; Sizeable: no; Material: Glass, <Unnamed>
Type - Pset_ProductRequirements - Category: Windows
Type - Pset_WindowCommon - IsExternal: no
OverallHeight: 1000 mm; OverallWidth: 2200 mm; Group: Model Group:Building:629362
Pset_QuantityTakeOff - Reference: Fenster_Aussen_KH_CJC
Pset_WindowCommon - Reference: Fenster_Aussen_KH_CJC
Name (Fenster_Aussen_KH_CJC:Fenster_Aussen_KH_CJC:...) | In
623629 | 1.EG +0.00 | Pset_WindowCommon - IsExternal: yes
623630 | 6.EG KH -1.15
623631 | 1.EG +0.00
629210 | 7.1OG KH +2.65
629211 | 7.1OG KH +2.65
629212 | 2.1OG +5.30
629213 | 8.2OG KH +6.45
629214 | 8.2OG KH +6.45
629215 | 8.2OG KH +6.45
629216 | 3.2OG +10.60
629217 | 3.2OG +10.60

# IfcWindow: Fenster_Aussen_NORD1_CJC:Fenster_Aussen_NORD1_CJC (4)
Type - ParameterTakesPrecedence: no; Sizeable: no; Material: Glass, <Unnamed>
Type - Pset_ProductRequirements - Category: Windows
Type - Pset_WindowCommon - IsExternal: no
OverallHeight: 2650 mm; OverallWidth: 3200 mm; Group: Model Group:Building:629362
Pset_QuantityTakeOff - Reference: Fenster_Aussen_NORD1_CJC
Pset_WindowCommon - Reference: Fenster_Aussen_NORD1_CJC
Name (Fenster_Aussen_NORD1_CJC:Fenster_Aussen_NORD1_CJC:...) | In
618650 | 1.EG +0.00 | Pset_WindowCommon - IsExternal: yes
619360 | 2.1OG +5.30
620056 | 3.2OG +10.60
620968 | 4.3OG +15.90

# IfcWindow: Fenster_Aussen_NORD2_CJC:Fenster_Aussen_NORD2_CJC (3)
Type - ParameterTakesPrecedence: no; Sizeable: no; Material: Glass, <Unnamed>
Type - Pset_ProductRequirements - Category: Windows
Type - Pset_WindowCommon - IsExternal: no
OverallHeight: 2650 mm; OverallWidth: 3200 mm; Group: Model Group:Building:629362
Pset_QuantityTakeOff - Reference: Fenster_Aussen_NORD2_CJC
Pset_WindowCommon - Reference: Fenster_Aussen_NORD2_CJC
Name (Fenster_Aussen_NORD2_CJC:Fenster_Aussen_NORD2_CJC:...) | In
619368 | 1.EG +0.00 | Pset_WindowCommon - IsExternal: yes
620057 | 2.1OG +5.30
620969 | 3.2OG +10.60

# IfcWindow: Fenster_Corridor200x100x350_CJC:Fenster_Corridor200x100x350_CJC (12)
Type - ParameterTakesPrecedence: no; Sizeable: no; Material: Glass, <Unnamed>
Type - Pset_ProductRequirements - Category: Windows
Type - Pset_WindowCommon - IsExternal: no
OverallHeight: 1000 mm; OverallWidth: 2000 mm; Group: Model Group:Building:629362
Pset_QuantityTakeOff - Reference: Fenster_Corridor200x100x350_CJC
Pset_WindowCommon - Reference: Fenster_Corridor200x100x350_CJC
Name (Fenster_Corridor200x100x350_CJC:Fenster_Corridor200x100x350_CJC:...) | In
625610 | 4.3OG +15.90
625611 | 4.3OG +15.90
625612 | 4.3OG +15.90
625613 | 4.3OG +15.90
626055 | 3.2OG +10.60
626056 | 3.2OG +10.60
626057 | 3.2OG +10.60
626058 | 3.2OG +10.60
627815 | 2.1OG +5.30
627816 | 2.1OG +5.30
627817 | 2.1OG +5.30
627818 | 2.1OG +5.30

# IfcWindow: Fenster_Corridor265x80x260_CJC:Fenster_Corridor265x80x260_CJC (8)
In: 1.EG +0.00
Type - ParameterTakesPrecedence: no; Sizeable: no; Material: Glass, <Unnamed>
Type - Pset_ProductRequirements - Category: Windows
Type - Pset_WindowCommon - IsExternal: no
OverallHeight: 800 mm; OverallWidth: 2650 mm; Group: Model Group:Building:629362
Pset_QuantityTakeOff - Reference: Fenster_Corridor265x80x260_CJC
Pset_WindowCommon - Reference: Fenster_Corridor265x80x260_CJC
Name (Fenster_Corridor265x80x260_CJC:Fenster_Corridor265x80x260_CJC:...)
628140
628141
628142
628143
628144
628145
628146
628147

# IfcWindow: Fenster_Corridor450x80x335_CJC:Fenster_Corridor450x80x335_CJC (3)
In: 1.EG +0.00
Type - ParameterTakesPrecedence: no; Sizeable: no; Material: Glass, <Unnamed>
Type - Pset_ProductRequirements - Category: Windows
Type - Pset_WindowCommon - IsExternal: no
OverallHeight: 800 mm; OverallWidth: 4500 mm; Group: Model Group:Building:629362
Pset_QuantityTakeOff - Reference: Fenster_Corridor450x80x335_CJC
Pset_WindowCommon - Reference: Fenster_Corridor450x80x335_CJC
Name (Fenster_Corridor450x80x335_CJC:Fenster_Corridor450x80x335_CJC:...)
628137
628138
628139

# IfcWindow: Fenster_EingangWest_CJC:Fenster_EingangWest_CJC, Fenster_EingangWest_CJC:Fenster_EingangWest_CJC:624400
In: 1.EG +0.00
Type - ParameterTakesPrecedence: no; Sizeable: no; Material: Glass, <Unnamed>
Type - Pset_ProductRequirements - Category: Windows
Type - Pset_WindowCommon - IsExternal: no
OverallHeight: 4500 mm; OverallWidth: 2650 mm; Group: Model Group:Building:629362
Pset_QuantityTakeOff - Reference: Fenster_EingangWest_CJC
Pset_WindowCommon - IsExternal: yes; Reference: Fenster_EingangWest_CJC

# IfcWindow: Fenster_Tuer_Fass_CJC:Fenster_Tuer_Fass_CJC (3)
Type - ParameterTakesPrecedence: no; Sizeable: no; Material: <Unnamed>, Glass
Type - Pset_ProductRequirements - Category: Windows
Type - Pset_WindowCommon - IsExternal: no
OverallHeight: 4500 mm; OverallWidth: 2650 mm; Group: Model Group:Building:629362
Pset_QuantityTakeOff - Reference: Fenster_Tuer_Fass_CJC
Pset_WindowCommon - Reference: Fenster_Tuer_Fass_CJC
Name (Fenster_Tuer_Fass_CJC:Fenster_Tuer_Fass_CJC:...) | In
623733 | 2.1OG +5.30 | Pset_WindowCommon - IsExternal: yes
623734 | 3.2OG +10.60
623735 | 4.3OG +15.90

# IfcWindow: M_Instance-Window-Fixed:0610 x 1220mm (14)
Type - ParameterTakesPrecedence: no; Sizeable: no; Material: Sash, Glass, <Unnamed>
Type - Pset_ProductRequirements - Category: Windows
Type - Pset_WindowCommon - IsExternal: no; ThermalTransmittance: 6.7069 kg/K/s3
Pset_QuantityTakeOff - Reference: 0610 x 1220mm
Pset_WindowCommon - Reference: 0610 x 1220mm
Group: Model Group:Building:629362
Name (M_Instance-Window-Fixed:0610 x 1220mm:...) | In | OverallHeight (mm) | OverallWidth (mm)
619660 | 2.1OG +5.30 | 2500 | 1300
619670 | 2.1OG +5.30 | 2500 | 900
619671 | 2.1OG +5.30 | 2500 | 900
619672 | 2.1OG +5.30 | 1500 | 1500
620279 | 3.2OG +10.60 | 2500 | 1300
620289 | 3.2OG +10.60 | 2500 | 900
620290 | 3.2OG +10.60 | 2500 | 900
620291 | 3.2OG +10.60 | 1500 | 1500
620665 | 3.2OG +10.60 | 1500 | 1500
621185 | 4.3OG +15.90 | 2500 | 1300
621195 | 4.3OG +15.90 | 2500 | 900
621196 | 4.3OG +15.90 | 2500 | 900
621197 | 4.3OG +15.90 | 1500 | 1500
621500 | 4.3OG +15.90 | 1500 | 1500

# IfcWindow: M_Instance-Window-Fixed:508x270 (8)
In: 0.UG -3.60
Type - ParameterTakesPrecedence: no; Sizeable: no; Material: Sash, Glass, <Unnamed>
Type - Pset_ProductRequirements - Category: Windows
Type - Pset_WindowCommon - IsExternal: no; ThermalTransmittance: 6.7069 kg/K/s3
Pset_QuantityTakeOff - Reference: 508x270
Pset_WindowCommon - Reference: 508x270
Group: Model Group:Building:629362
Name (M_Instance-Window-Fixed:508x270:...) | OverallHeight (mm) | OverallWidth (mm)
623245 | 1200 | 2300
623246 | 1200 | 2300
623247 | 1200 | 2300
623248 | 1200 | 2300
623249 | 1200 | 2300
623250 | 1200 | 2300
623251 | 1800 | 4050
623252 | 1800 | 4500

# IfcWindow: M_Instance-Window-Fixed:508x270 2 (2)
Type - ParameterTakesPrecedence: no; Sizeable: no; Material: Sash, Glass, <Unnamed>
Type - Pset_ProductRequirements - Category: Windows
Type - Pset_WindowCommon - IsExternal: no; ThermalTransmittance: 6.7069 kg/K/s3
Pset_QuantityTakeOff - Reference: 508x270 2
Pset_WindowCommon - Reference: 508x270 2
Group: Model Group:Building:629362
Name (M_Instance-Window-Fixed:508x270 2:...) | In | OverallHeight (mm) | OverallWidth (mm)
622386 | 9.3OG KH +10.25 | 1100 | 3600
623893 | 0.UG -3.60 | 800 | 900

# IfcWindow: M_Window-Louvers:140x250 (3)
Type - ParameterTakesPrecedence: no; Sizeable: no; Material: Birch
Type - Pset_ProductRequirements - Category: Windows
Type - Pset_WindowCommon - IsExternal: no; ThermalTransmittance: 3.6886 kg/K/s3
OverallHeight: 2500 mm; OverallWidth: 1400 mm; Group: Model Group:Building:629362
Pset_QuantityTakeOff - Reference: 140x250
Pset_WindowCommon - Reference: 140x250
Name (M_Window-Louvers:140x250:...) | In
619621 | 2.1OG +5.30 | Pset_WindowCommon - IsExternal: yes
620249 | 3.2OG +10.60
621157 | 4.3OG +15.90

# IfcWindow: M_Window-Louvers:140x310 (3)
Type - ParameterTakesPrecedence: no; Sizeable: no; Material: Birch
Type - Pset_ProductRequirements - Category: Windows
Type - Pset_WindowCommon - IsExternal: no; ThermalTransmittance: 3.6886 kg/K/s3
OverallHeight: 3100 mm; OverallWidth: 1400 mm; Group: Model Group:Building:629362
Pset_QuantityTakeOff - Reference: 140x310
Pset_WindowCommon - Reference: 140x310
Name (M_Window-Louvers:140x310:...) | In
619616 | 2.1OG +5.30 | Pset_WindowCommon - IsExternal: yes
620244 | 3.2OG +10.60
621152 | 4.3OG +15.90

# IfcWindow: M_Window-Louvers:60x60, M_Window-Louvers:60x60:622296
In: 8.2OG KH +6.45
Type - ParameterTakesPrecedence: no; Sizeable: no; Material: Birch
Type - Pset_ProductRequirements - Category: Windows
Type - Pset_WindowCommon - IsExternal: no; ThermalTransmittance: 3.6886 kg/K/s3
OverallHeight: 600 mm; OverallWidth: 600 mm; Group: Model Group:Building:629362
Pset_QuantityTakeOff - Reference: 60x60
Pset_WindowCommon - IsExternal: yes; Reference: 60x60

# IfcWindow: M_Window-Louvers:90x250 (4)
Type - ParameterTakesPrecedence: no; Sizeable: no; Material: Birch
Type - Pset_ProductRequirements - Category: Windows
Type - Pset_WindowCommon - IsExternal: no; ThermalTransmittance: 3.6886 kg/K/s3
OverallHeight: 2500 mm; OverallWidth: 900 mm; Group: Model Group:Building:629362
Pset_QuantityTakeOff - Reference: 90x250
Pset_WindowCommon - Reference: 90x250
Name (M_Window-Louvers:90x250:...) | In
619675 | 2.1OG +5.30 | Pset_WindowCommon - IsExternal: yes
620294 | 3.2OG +10.60
621200 | 4.3OG +15.90
623591 | 1.EG +0.00

# IfcWindow: Tuer_Aussen_NORD_EG_CJC:Tuer_Aussen_NORD_EG_CJC, Tuer_Aussen_NORD_EG_CJC:Tuer_Aussen_NORD_EG_CJC:623742
In: 1.EG +0.00
Type - ParameterTakesPrecedence: no; Sizeable: no; Material: <Unnamed>, Glass
Type - Pset_ProductRequirements - Category: Windows
Type - Pset_WindowCommon - IsExternal: no
OverallHeight: 4500 mm; OverallWidth: 2600 mm; Group: Model Group:Building:629362
Pset_QuantityTakeOff - Reference: Tuer_Aussen_NORD_EG_CJC
Pset_WindowCommon - IsExternal: yes; Reference: Tuer_Aussen_NORD_EG_CJC

# IfcWindow: WINDOW_Glass_Block:WINDOW_Glass_Block_10x3 (2)
In: 1.EG +0.00
Type - ParameterTakesPrecedence: no; Sizeable: no; Material: Glass, Wood
Type - Pset_ProductRequirements - Category: Windows
Type - Pset_WindowCommon - IsExternal: no
OverallHeight: 590 mm; OverallWidth: 1920 mm; Group: Model Group:Building:629362
Pset_QuantityTakeOff - Reference: WINDOW_Glass_Block_10x3
Pset_WindowCommon - Reference: WINDOW_Glass_Block_10x3
Name (WINDOW_Glass_Block:WINDOW_Glass_Block_10x3:...)
623324 | Pset_WindowCommon - IsExternal: yes
623327

# IfcWindow: WINDOW_Glass_Block:WINDOW_Glass_Block_14x3 (8)
In: 1.EG +0.00
Type - ParameterTakesPrecedence: no; Sizeable: no; Material: Glass, Wood
Type - Pset_ProductRequirements - Category: Windows
Type - Pset_WindowCommon - IsExternal: no
OverallHeight: 590 mm; OverallWidth: 2680 mm; Group: Model Group:Building:629362
Pset_QuantityTakeOff - Reference: WINDOW_Glass_Block_14x3
Pset_WindowCommon - Reference: WINDOW_Glass_Block_14x3
Name (WINDOW_Glass_Block:WINDOW_Glass_Block_14x3:...)
623322 | Pset_WindowCommon - IsExternal: yes
623323
623325
623326
623328
623329
623331
623332

# IfcWindow: WINDOW_Glass_Block:WINDOW_Glass_Block_15x3 (2)
In: 1.EG +0.00
Type - ParameterTakesPrecedence: no; Sizeable: no; Material: Glass, Wood
Type - Pset_ProductRequirements - Category: Windows
Type - Pset_WindowCommon - IsExternal: no
OverallHeight: 590 mm; OverallWidth: 2870 mm; Group: Model Group:Building:629362
Pset_QuantityTakeOff - Reference: WINDOW_Glass_Block_15x3
Pset_WindowCommon - Reference: WINDOW_Glass_Block_15x3
Name (WINDOW_Glass_Block:WINDOW_Glass_Block_15x3:...)
623330
623333

# IfcWindow: Windows_Dbl_Plain:200x140 (61)
In: 0.UG -3.60
Type - OperationType: DOUBLE_PANEL_VERTICAL; ParameterTakesPrecedence: no; Sizeable: no; Material: Window Frame, Glass
Type - Pset_ManufacturerTypeInformation - Manufacturer: Revit
Type - Pset_ProductRequirements - Category: Windows
Type - Pset_WindowCommon - IsExternal: no; ThermalTransmittance: 3.6886 kg/K/s3
OverallHeight: 1400 mm; OverallWidth: 2000 mm; Group: Model Group:Building:629362
Pset_QuantityTakeOff - Reference: 200x140
Pset_WindowCommon - Reference: 200x140
Name (Windows_Dbl_Plain:200x140:...)
623253 | Pset_WindowCommon - IsExternal: yes
623254
623255
623256
623257
623258
623259
623260
623261
623262
623263
623264
623265
623266
623267
623268
623269
623270
623271
623272
623273
623274
623275
623276
623277
623278
623279
623280
623281
623282
623283
623286
623287
623288
623289
623290
623291
623292
623293
623294
623295
623296
623297
623298
623299
623300
623301
623302
623303
623304
623305
623306
623307
623308
623309
623310
623311
623312
623313
623314
623315

# IfcWindow: Windows_Sgl_Horz_Bars:200x150 (88)
Type - OperationType: SINGLE_PANEL; ParameterTakesPrecedence: no; Sizeable: no; Material: Window Frame, Glass
Type - Pset_ManufacturerTypeInformation - Manufacturer: Revit
Type - Pset_ProductRequirements - Category: Windows
Type - Pset_WindowCommon - IsExternal: no; ThermalTransmittance: 5.5617 kg/K/s3
OverallHeight: 2000 mm; OverallWidth: 1500 mm; Group: Model Group:Building:629362
Pset_QuantityTakeOff - Reference: 200x150
Pset_WindowCommon - Reference: 200x150
Name (Windows_Sgl_Horz_Bars:200x150:...) | In
621996 | 7.1OG KH +2.65 | Pset_WindowCommon - IsExternal: yes
621997 | 7.1OG KH +2.65
621998 | 7.1OG KH +2.65
621999 | 7.1OG KH +2.65
622000 | 7.1OG KH +2.65
622001 | 7.1OG KH +2.65
622002 | 7.1OG KH +2.65
622003 | 7.1OG KH +2.65
622004 | 7.1OG KH +2.65
622005 | 7.1OG KH +2.65
622006 | 7.1OG KH +2.65
622007 | 7.1OG KH +2.65
622008 | 7.1OG KH +2.65
622009 | 7.1OG KH +2.65
622010 | 7.1OG KH +2.65
622011 | 7.1OG KH +2.65
622012 | 7.1OG KH +2.65
622013 | 7.1OG KH +2.65
622014 | 7.1OG KH +2.65
622015 | 7.1OG KH +2.65
622016 | 7.1OG KH +2.65
622017 | 7.1OG KH +2.65
622018 | 7.1OG KH +2.65
622019 | 7.1OG KH +2.65
622020 | 7.1OG KH +2.65
622021 | 7.1OG KH +2.65
622022 | 7.1OG KH +2.65
622023 | 7.1OG KH +2.65
622024 | 7.1OG KH +2.65
622062 | 6.EG KH -1.15
622063 | 6.EG KH -1.15
622064 | 6.EG KH -1.15
622065 | 6.EG KH -1.15
622066 | 6.EG KH -1.15
622067 | 6.EG KH -1.15
622068 | 6.EG KH -1.15
622069 | 6.EG KH -1.15
622070 | 6.EG KH -1.15
622071 | 6.EG KH -1.15
622072 | 6.EG KH -1.15
622073 | 6.EG KH -1.15
622074 | 6.EG KH -1.15
622075 | 6.EG KH -1.15
622076 | 6.EG KH -1.15
622077 | 6.EG KH -1.15
622078 | 6.EG KH -1.15
622274 | 8.2OG KH +6.45
622275 | 8.2OG KH +6.45
622276 | 8.2OG KH +6.45
622277 | 8.2OG KH +6.45
622278 | 8.2OG KH +6.45
622279 | 8.2OG KH +6.45
622280 | 8.2OG KH +6.45
622281 | 8.2OG KH +6.45
622282 | 8.2OG KH +6.45
622283 | 8.2OG KH +6.45
622284 | 8.2OG KH +6.45
622285 | 8.2OG KH +6.45
622286 | 8.2OG KH +6.45
622287 | 8.2OG KH +6.45
622288 | 8.2OG KH +6.45
622289 | 8.2OG KH +6.45
622290 | 8.2OG KH +6.45
622291 | 8.2OG KH +6.45
622293 | 8.2OG KH +6.45
622294 | 8.2OG KH +6.45
622295 | 8.2OG KH +6.45
622341 | 9.3OG KH +10.25
622342 | 3.2OG +10.60
622343 | 3.2OG +10.60
622344 | 9.3OG KH +10.25
622345 | 9.3OG KH +10.25
622346 | 9.3OG KH +10.25
622347 | 9.3OG KH +10.25
622348 | 9.3OG KH +10.25
622349 | 9.3OG KH +10.25
622350 | 9.3OG KH +10.25
622351 | 9.3OG KH +10.25
622352 | 9.3OG KH +10.25
622353 | 9.3OG KH +10.25
622354 | 9.3OG KH +10.25
622355 | 9.3OG KH +10.25
622356 | 9.3OG KH +10.25
622357 | 9.3OG KH +10.25
622358 | 9.3OG KH +10.25
622359 | 9.3OG KH +10.25
622360 | 9.3OG KH +10.25
622361 | 9.3OG KH +10.25

# IfcWindow: Windows_Sgl_Plain:100x100, Windows_Sgl_Plain:100x100:622177
In: 6.EG KH -1.15
Type - OperationType: SINGLE_PANEL; ParameterTakesPrecedence: no; Sizeable: no; Material: Window Frame, Glass
Type - Pset_ManufacturerTypeInformation - Manufacturer: Revit
Type - Pset_ProductRequirements - Category: Windows
Type - Pset_WindowCommon - IsExternal: no; ThermalTransmittance: 5.5617 kg/K/s3
OverallHeight: 1000 mm; OverallWidth: 1000 mm; Group: Model Group:Building:629362
Pset_QuantityTakeOff - Reference: 100x100
Pset_WindowCommon - Reference: 100x100

# IfcWindow: Windows_Sgl_Plain:120x140, Windows_Sgl_Plain:120x140:622178
In: 6.EG KH -1.15
Type - OperationType: SINGLE_PANEL; ParameterTakesPrecedence: no; Sizeable: no; Material: Window Frame, Glass
Type - Pset_ManufacturerTypeInformation - Manufacturer: Revit
Type - Pset_ProductRequirements - Category: Windows
Type - Pset_WindowCommon - IsExternal: no; ThermalTransmittance: 5.5617 kg/K/s3
OverallHeight: 1400 mm; OverallWidth: 1200 mm; Group: Model Group:Building:629362
Pset_QuantityTakeOff - Reference: 120x140
Pset_WindowCommon - Reference: 120x140

# IfcWindow: Windows_Sgl_Plain:150x80 (3)
In: 0.UG -3.60
Type - OperationType: SINGLE_PANEL; ParameterTakesPrecedence: no; Sizeable: no; Material: Window Frame, Glass
Type - Pset_ManufacturerTypeInformation - Manufacturer: Revit
Type - Pset_ProductRequirements - Category: Windows
Type - Pset_WindowCommon - IsExternal: no; ThermalTransmittance: 5.5617 kg/K/s3
OverallHeight: 800 mm; OverallWidth: 1500 mm; Group: Model Group:Building:629362
Pset_QuantityTakeOff - Reference: 150x80
Pset_WindowCommon - Reference: 150x80
Name (Windows_Sgl_Plain:150x80:...)
623894 | Pset_WindowCommon - IsExternal: yes
623895
623896

# IfcWindow: Windows_Sgl_Plain:90x140 (6)
In: 0.UG -3.60
Type - OperationType: SINGLE_PANEL; ParameterTakesPrecedence: no; Sizeable: no; Material: Window Frame, Glass
Type - Pset_ManufacturerTypeInformation - Manufacturer: Revit
Type - Pset_ProductRequirements - Category: Windows
Type - Pset_WindowCommon - IsExternal: no; ThermalTransmittance: 5.5617 kg/K/s3
OverallHeight: 1400 mm; OverallWidth: 900 mm; Group: Model Group:Building:629362
Pset_QuantityTakeOff - Reference: 90x140
Pset_WindowCommon - Reference: 90x140
Name (Windows_Sgl_Plain:90x140:...)
623284 | Pset_WindowCommon - IsExternal: yes
623285
623316
623317
623318
623319

# IfcWindow: Windows_Sgl_Plain:90x45 (6)
In: 0.UG -3.60
Type - OperationType: SINGLE_PANEL; ParameterTakesPrecedence: no; Sizeable: no; Material: Window Frame, Glass
Type - Pset_ManufacturerTypeInformation - Manufacturer: Revit
Type - Pset_ProductRequirements - Category: Windows
Type - Pset_WindowCommon - IsExternal: no; ThermalTransmittance: 5.5617 kg/K/s3
OverallHeight: 450 mm; OverallWidth: 900 mm; Group: Model Group:Building:629362
Pset_QuantityTakeOff - Reference: 90x45
Pset_WindowCommon - Reference: 90x45
Name (Windows_Sgl_Plain:90x45:...)
623736 | Pset_WindowCommon - IsExternal: yes
623737
623738
623739
623740
623741
